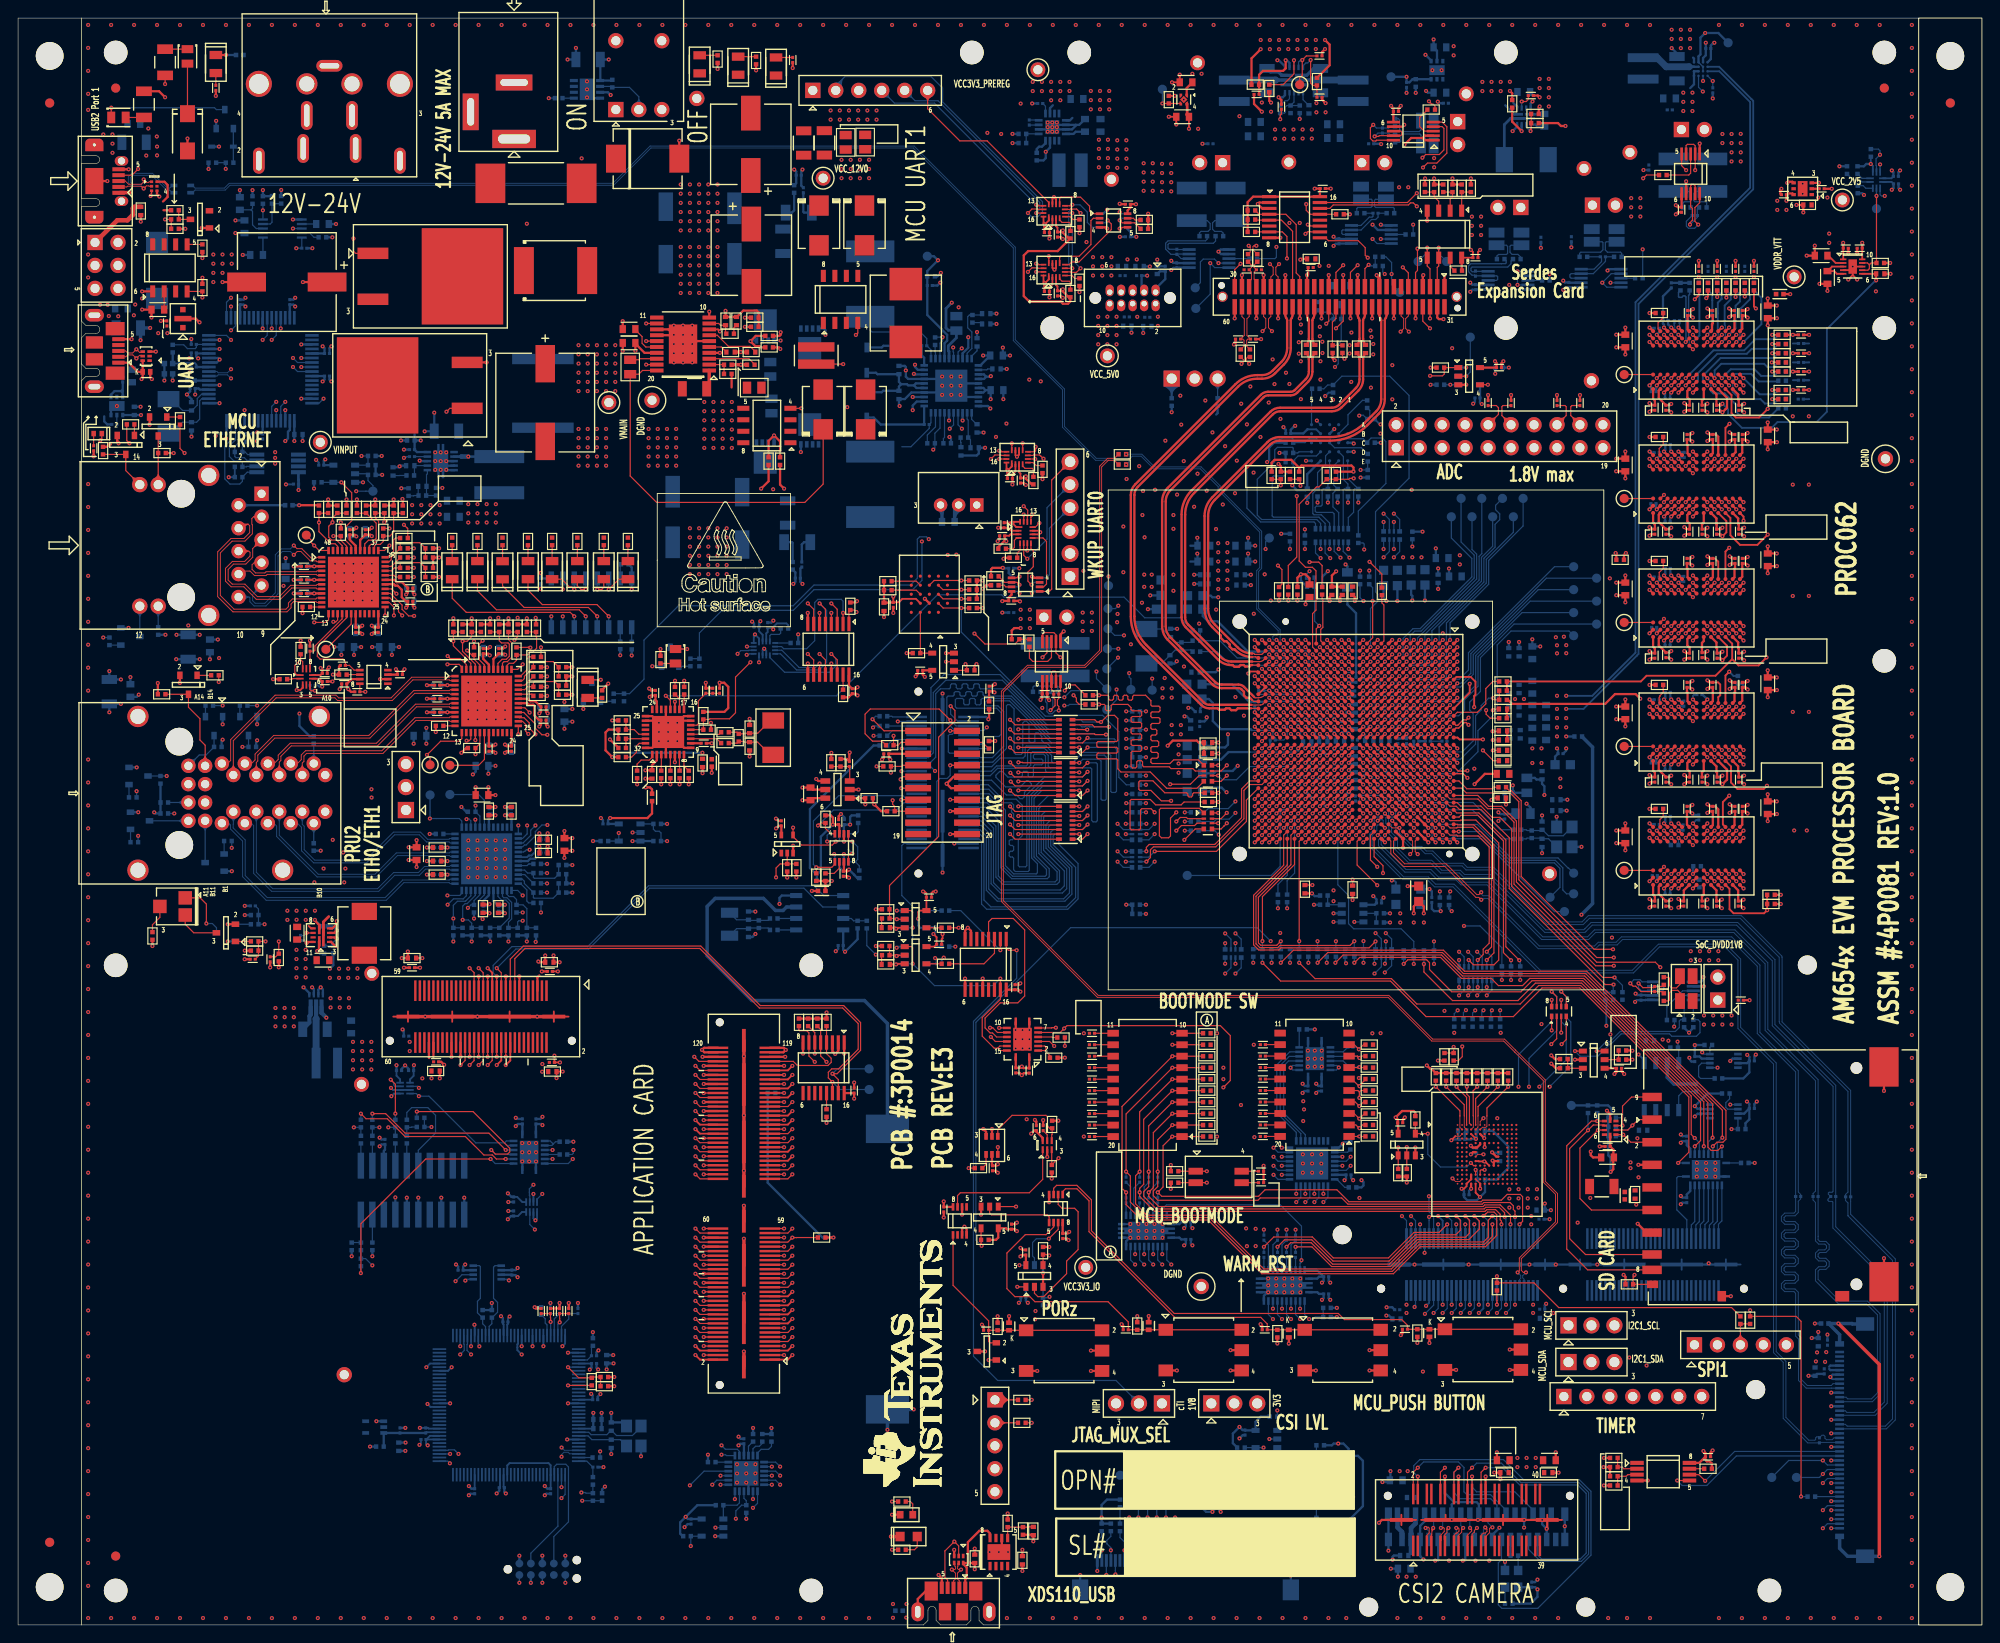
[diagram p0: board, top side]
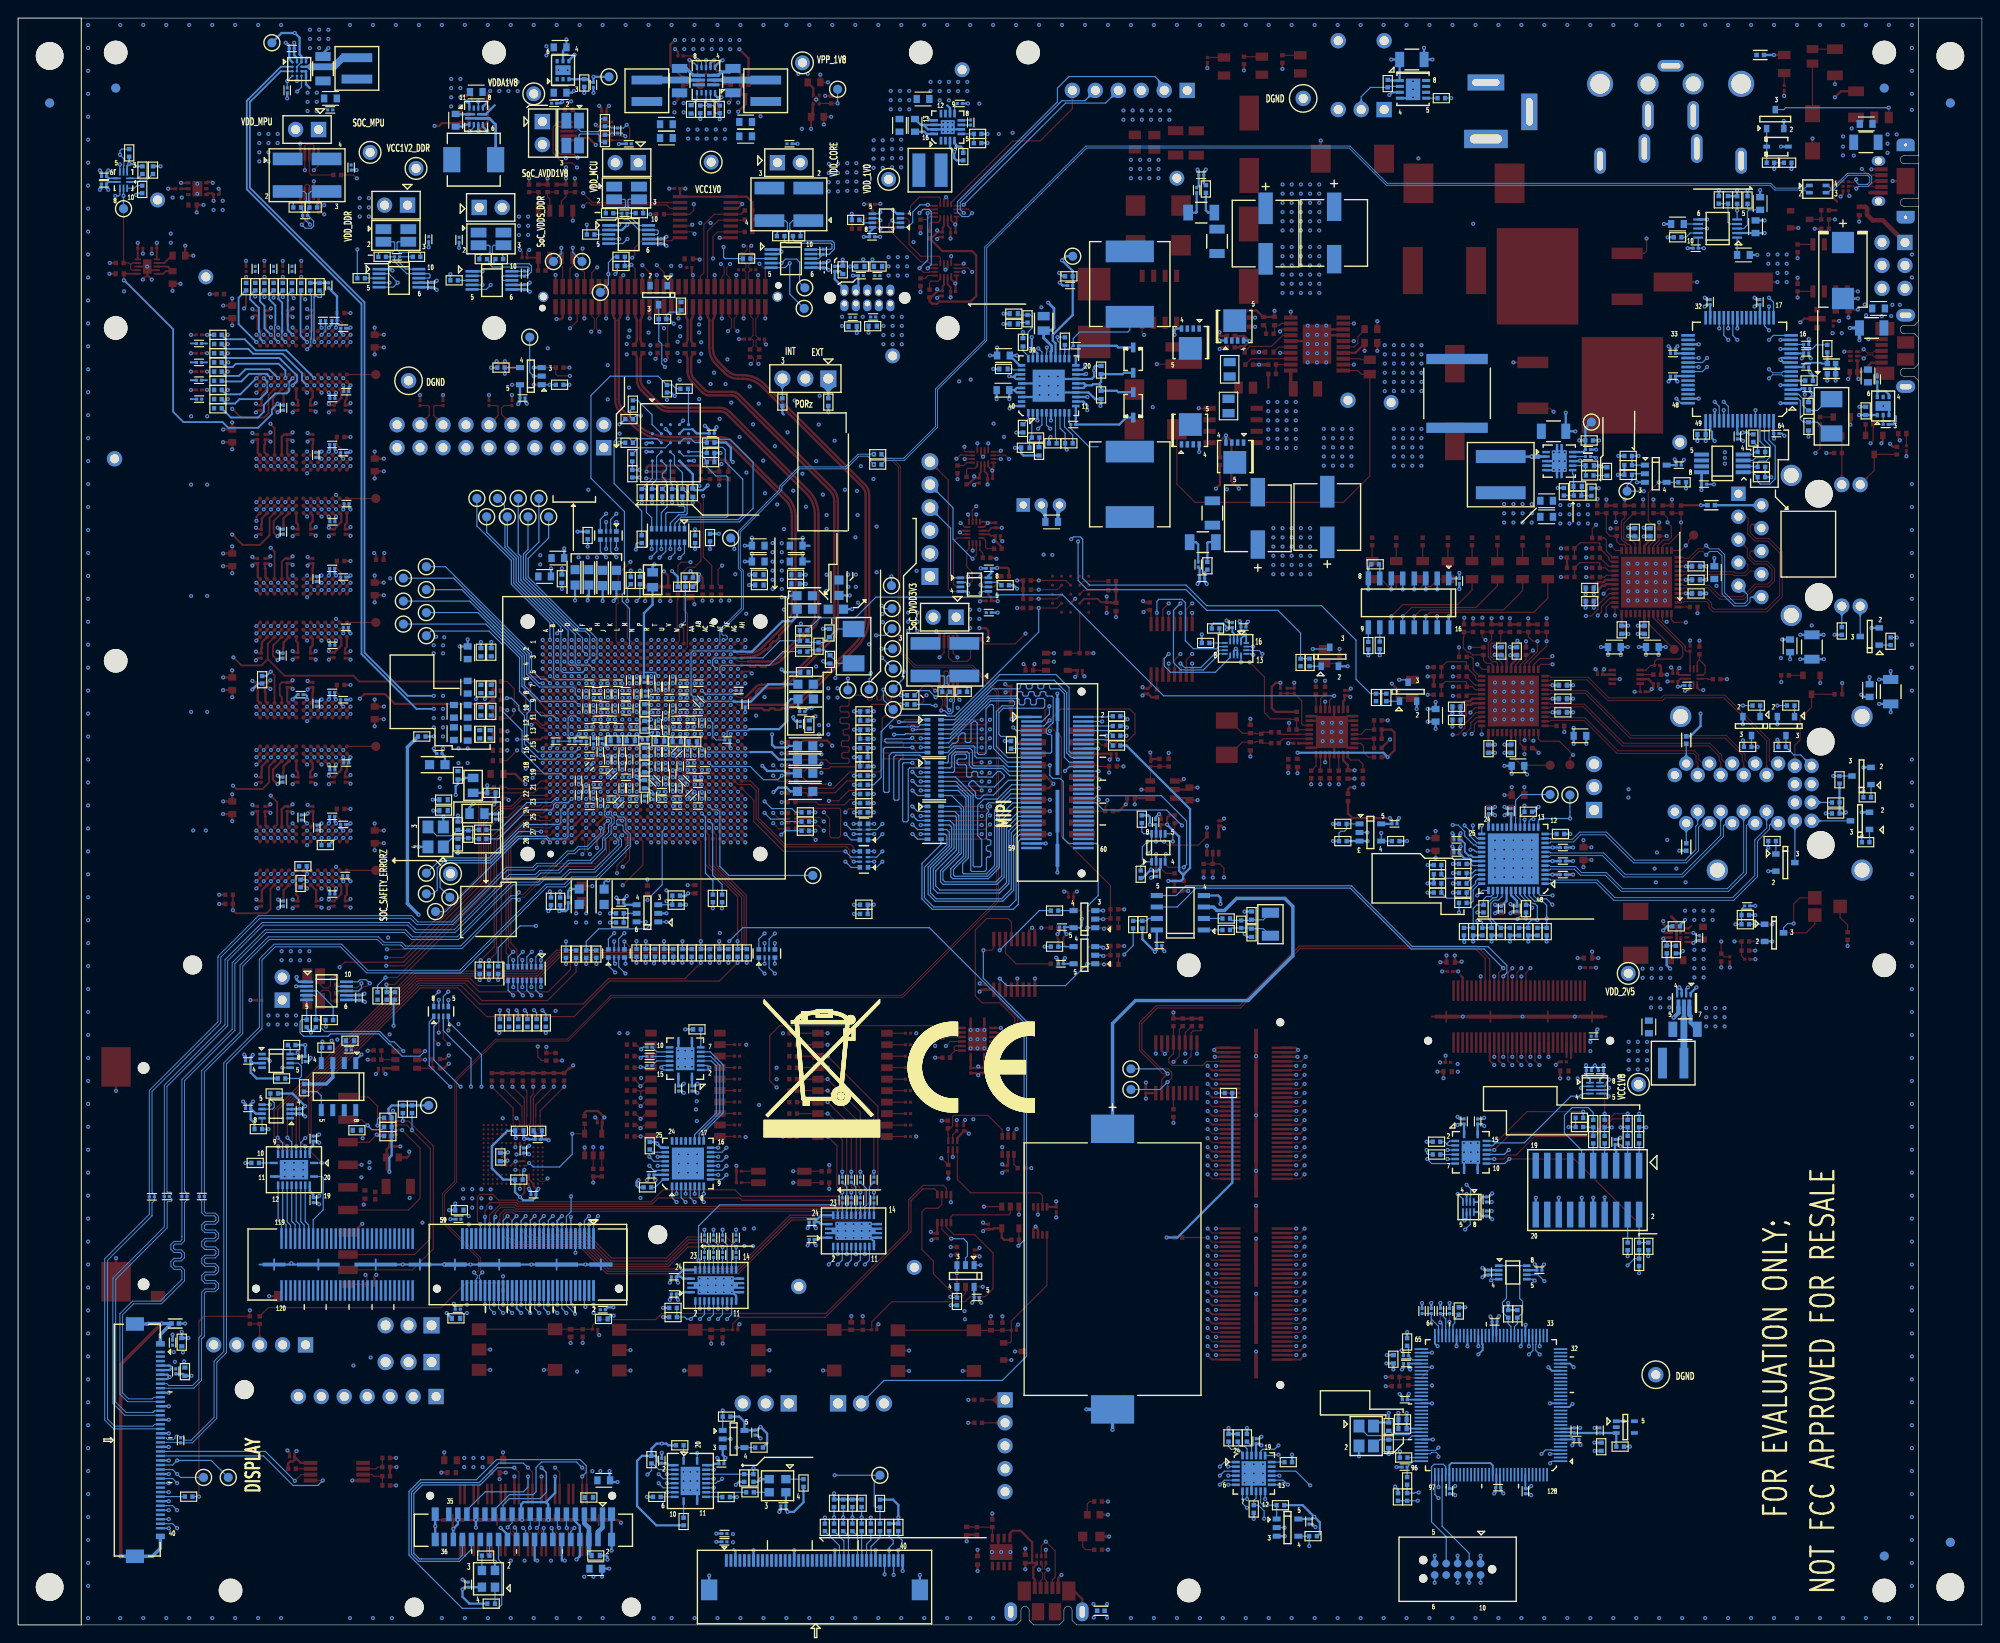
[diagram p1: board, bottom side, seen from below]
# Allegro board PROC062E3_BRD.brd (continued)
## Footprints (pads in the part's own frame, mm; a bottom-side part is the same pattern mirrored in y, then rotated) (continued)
XTAL4_NX3225GA_130X100_SMD_0-9
  rect 1.422x1.219 smd: 1(-1.1,-0.8) 2(1.1,-0.8) 3(1.1,0.8) 4(-1.1,0.8)
XTAL4_TXC_130X100_SMD_0-8
  rect 1.422x1.219 smd: 1(-1.1,-0.85) 2(1.1,-0.85) 3(1.1,0.85) 4(-1.1,0.85)
XTAL_ABM3_205X130_SMD
  rect 1.803x2.413 smd: 1(-1.9,0) 2(1.9,0)
XTAL_ABM3_210X130_SMD
  rect 1.803x2.413 smd: 1(-1.9,0) 2(1.9,0)
XTAL_ABS07_130X60_SMD_0-9
  rect 1.118x1.905 smd: 1(-1.27,0) 2(1.27,0)

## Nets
DGND: B1.2(-) C1.2 C2.2 C3.2 C5.2 C6.2 C7.2 C8.2 C9.2 C10.2 C11.1 C12.2 C13.2 C14.2 C15.2 C16.2 C17.2 C18.2 C19.2 C20.2 C21.2 C22.2 C23.2 C24.2 C25.2 C26.2 C29.2 C30.2 C31.2 C32.2 C33.2 C34.2 C35.2 C36.2 C37.2 C38.1 C39.2 C40.2 C41.2 C42.2 C43.2 C44.2 C45.2 C46.2 C47.2 C50.2 C51.2 C52.2 C53.2 C56.2 C57.2 C62.2 C63.2 C64.2 C65.2 C67.2 C68.2 C69.2 C70.2 C71.2 C72.2 C73.2 C74.2 C75.2 C76.2 C77.1 C78.2 C79.2 C80.2 C81.2 C82.2 C83.2 C85.2 C86.2 C87.2 C88.2 C89.2 C90.2 C91.2 C92.2 C94.2 C95.2 C96.2 C97.2 C98.2 C99.2 C100.2 C101.2 C102.2 C103.2 C104.2 C105.2 C106.2 C107.2 C108.2 C109.2 C110.2 C111.2 C112.2 C113.1 C114.2 C115.2 C116.2 C117.2 C119.2 C120.2 C121.2 C122.2 C123.2 C124.2 C125.2 C126.2 C127.2 C128.2 C129.2 C130.2 C131.2 C132.2 C133.2 C134.2 C135.2 C136.2 C137.2 C138.2 C139.2 C140.2 C141.2 C142.2 C143.2 C144.2 C145.2 C146.2 C147.2 C148.2 C149.2 C150.2 C151.2 C153.2 C154.2 C155.2 C156.1 C157.2 C158.2 C159.2 C160.2 C161.1 C162.2 C163.2 C164.2 C165.2 C166.2 C167.2 C168.2 C169.1 C170.1 C171.1 C172.2 C173.2 C174.2 C175.2 C176.2 C177.2 C178.2 C179.2 C180.2 C181.2 C182.2 C183.2 C184.2 C185.2 C186.2 C187.2 C188.2 C189.2 C190.2 C192.2 C193.2 C194.2 C195.2 C196.2 C197.2 C198.2 C199.2 C200.2 C201.2 C202.2 C203.2 C204.2 C205.2 C206.2 C207.2 C208.2 C209.2 C210.2 C211.2 C212.2 C213.2 C214.2 C215.2 C216.2 C217.2 C219.2 C220.2 C221.2 C222.2 C223.2 C224.1 C225.2 C226.2 C227.2 C228.2 C229.2 C230.2 C231.2 C232.2 C233.2 C234.2 C235.2 C236.2 C237.2 C238.2 C239.2 C240.2 C241.2 C242.2 C243.2 C244.2 C245.1 C246.1 C247.1 C248.1 C250.2 C251.2 C252.2 C253.2 C254.2 C255.2 C256.2 C257.2 C258.2 C259.2 C260.2 C261.2 C262.2 C263.2 C264.2 C265.2 C266.2 C267.2 C268.2 C270.2 C271.2 C272.2 C274.2 C275.2 C276.2 C277.2 C278.2 C281.2 C282.2 C283.2 C284.2 C285.2 C287.2 C288.2 C289.2 C290.2 C291.2 C294.2 C295.2 C296.2 C297.2 C298.2 C299.2 C300.2 C301.2 C302.2 C304.2 C305.1 C306.1 C307.2 C308.2 C309.2 C310.2 C311.2 C312.2 C313.2 C314.2 C315.2 C316.2 C317.2 C318.2 C319.1 C321.1 C322.1 C323.2 C324.1 C325.1 C326.1 C327.1 C328.2 C329.1 C330.2 C331.1 C332.2 C333.2 C334.2 C335.2 C336.2 C337.2 C338.2 C339.2 C340.2 C341.2 C342.2 C344.2 C345.2 C346.2 C347.1 C348.1 C349.1 C350.2 C351.2 C352.2 C353.2 C354.2 C355.2 C357.2 C358.2 C359.1 C360.1 C362.2 C363.2 C364.2 C365.2 C366.2 C367.2 C368.2 C369.2 C370.2 C371.2 C372.2 C373.2 C374.2 C375.2 C376.2 C377.2 C378.2 C379.2 C380.2 C381.2 C382.2 C383.2 C384.2 C385.2 C386.2 C387.2 C388.2 C389.2 C390.2 C391.2 C392.2 C393.2 C394.2 C395.2 C396.2 C397.2 C398.2 C399.2 C400.2 C401.2 C402.2 C403.2 C404.2 C405.2 C406.2 C407.2 C408.2 C409.2 C410.2 C411.2 C412.2 C413.1 C414.2 C415.2 C416.2 C417.2 C418.2 C419.2 C420.2 C421.2 C422.2 C423.2 C424.2 C425.2 C426.2 C427.2 C428.2 C429.2 C430.2 C431.2 C432.2 C433.2 C434.2 C435.2 C436.2 C437.2 C438.2 C439.2 C441.2 C442.2 C443.2 C444.2 C445.2 C446.2 C447.2 C448.2 C449.2 C450.2 C451.2 C452.2 C453.2 C454.2 C455.2 C456.2 C457.2 C458.2 C459.2 C460.2 C461.2 C462.2 C463.2 C464.2 C465.2 C466.2 C467.2 C468.2 C469.2 C470.2 C471.2 C472.2 C473.2 C474.2 C475.2 C476.2 C477.2 C478.2 C479.2 C480.2 C481.1 C482.2 C483.2 C484.2 C485.2 C486.2 C487.2 C488.2 C489.2 C490.2 C491.2 C492.2 C493.2 C494.2 C495.2 C496.2 C497.2 C498.2 C499.2 C500.2 C501.2 C502.2 C503.2 C504.2 C505.2 C506.2 C507.2 C508.2 C509.2 C510.2 C511.2 C512.2 C513.2 C514.2 C515.2 C516.2 C517.2 C518.2 C519.2 C520.2 C521.2 C522.2 C523.2 C524.2 C525.2 C526.2 C527.2 C528.2 C529.2 C530.2 C531.2 C532.2 C533.2 C534.2 C535.2 C536.2 C537.2 C538.2 C539.2 C540.2 C541.2 C542.2 C543.2 C544.2 C545.2 C546.2 C547.2 C548.2 C549.2 C550.2 C551.2 C552.2 C553.2 C554.2 C555.2 C556.2 C557.2 C558.2 C559.2 C560.2 C561.2 C562.2 C563.2 C564.1 C565.2 C566.2 C567.2 C568.2 C569.2 C570.1 C571.2 C572.2 C573.2 C574.2 C575.2 C576.1 C577.2 C578.2 C579.2 C580.2 C581.2 C582.2 C583.2 C584.2 C585.2 C586.2 C587.2 C588.2 C589.2 C590.2 C591.2 C592.2 C593.2 C594.2 C595.2 C596.1 C597.2 C598.2 C599.2 C600.2 C601.2 C602.2 C603.2 C604.2 C605.2 C606.2 C607.2 C608.2 C609.2 C610.2 C611.2 C612.2 C613.2 C614.2 C615.2 C616.2 C617.2 C618.2 C619.2 C620.2 C621.2 C622.2 C623.2 C624.1 C625.2 C626.2 C627.2 C628.2 C629.2 C630.2 C631.2 C632.2 C633.2 C634.2 C635.2 C636.2 C637.1 C638.2 C639.2 C640.2 C641.2 C642.2 C643.2 C644.2 C645.2 C646.2 C647.2 C648.2 C649.2 C650.2 C651.2 C652.1 C653.2 C654.2 C655.2 C656.2 C657.2 C658.2 C659.1 C660.2 C661.2 C662.2 C663.2 C664.2 C665.2 C666.1 C667.2 C668.2 C669.2 C670.1 C671.2 C672.2 C673.2 C674.2 C675.1 C676.1 C677.2 C679.2 C680.2 C681.2 C682.2 C685.2 C686.2 C687.1 C688.1 C689.1 C690.1 C691.2 C692.2 C693.2 C695.2 C696.2 D1.2(A) D2.2(ANODE) D4.1(A) D7.2(A) D10.2(A) D11.2(A) D12.2(A) D13.2(A) D14.2(ANODE) D16.1(A) FL2.2(GND) FL6.2 FL7.2 FL15.1 J1.2 J1.3 J2.3 J2.4 J2.5 J2.6 J2.7 J3.5(GND) J4.6 J5.1 J5.4 J5.7 J5.8 J5.9 J5.10 J5.13 J5.17 J5.20 J5.23 J5.26 J5.29 J5.32 J5.35 J5.38 J5.41 J5.44 J5.48 J5.51 J5.54 J5.57 J5.60 J5.SH1 J5.SH2 J6.4 J6.5 J6.6 J9.3 J10.1 J10.7 J10.8 J10.13 J10.14 J10.19 J10.20 J11.1 J12.1(CH-GND) J13.10 J13.12 J13.16 J13.20 J14.A10(GND) J14.B10(GND) J16.13 J16.18 J16.19 J16.22 J16.25 J16.40 J16.44 J16.61 J16.62 J16.63 J16.64 J17.3(VSS1) J17.6(VSS2) J17.G2 J17.G4 J17.G5 J18.1 J18.2 J18.5 J18.6 J18.17 J18.21 J18.25 J18.29 J18.36 J18.40 J18.52 J18.56 J18.69 J18.73 J18.82 J18.85 J18.86 J18.89 J18.92 J18.96 J18.97 J18.101 J18.104 J18.105 J18.107 J18.108 J18.109 J18.111 J18.112 J18.115 J18.116 J18.117 J18.118 J18.119 J18.120 J18.121 J18.122 J18.123 J18.124 J18.125 J18.126 J18.127 J18.128 J19.7 J20.5 J21.3 J22.12 J22.16 J22.24 J22.41(GND1) J22.42(GND2) J22.43(GND3) J22.44(GND4) J23.5(GND) J30.1 J32.16 J32.57 J32.61 J32.62 J32.63 J32.64 J33.1 J34.8 J34.10 J34.12 J34.16 J34.20 J35.12 J35.17 J35.22 J35.30 J35.35 J35.36 J35.121 J35.122 J35.123 J35.124 J35.125 J35.126 J35.127 J35.128 J36.12 J36.17 J36.22 J36.30 J36.35 J36.36 J36.61 J36.62 J36.63 J36.64 J38.6 J38.7 J38.10 J38.13 J38.16 J38.19 J38.22 J38.25 J38.28 J38.34 J39.6 J39.7 J39.10 J39.13 J39.16 J39.19 J39.22 J39.29 J39.33 J39.34 J39.SH1 J39.SH2 J39.SH3 J39.SH4 J40.3 J40.5 J40.9 J41.7 J41.16 J41.25 J41.34 J41.40 J41.41 J41.42 J42.5(GND) J43.3 LD2.1 LD3.1 LD4.1 LD5.1 LD19.1(CATHODE) LD20.1(CATHODE) Q3.2(S) Q4.2(S) Q5.2(S) Q6.2(S) Q7.3(D) Q8.2(S) Q9.2(S) Q10.2(S) Q11.2(S) Q12.2(S) Q13.2(S) Q14.2(S) Q15.2(S) Q16.2(S) Q17.2(S) R6.1 R10.2 R11.2 R15.2 R17.1 R19.2 R22.1 R23.1 R30.2 R31.1 R32.2 R34.2 R39.2 R40.2 R41.2 R42.1 R50.2 R52.2 R53.2 R59.2 R60.2 R62.2 R64.2 R65.2 R71.1 R75.2 R80.1 R82.1 R83.2 R87.1 R91.2 R92.2 R95.2 R96.2 R99.2 R112.2 R116.1 R117.2 R122.2 R125.2 R130.2 R135.2 R136.2 R138.2 R139.2 R142.2 R143.2 R146.2 R150.1 R158.2 R164.1 R166.2 R172.2 R176.2 R179.2 R186.2 R187.1 R188.2 R190.2 R195.1 R197.1 R201.2 R212.2 R216.2 R219.1 R228.2 R230.2 R240.2 R243.2 R245.2 R247.2 R249.2 R251.2 R252.1 R254.1 R255.1 R258.2 R260.2 R272.2 R274.2 R276.2 R278.2 R280.2 R282.2 R285.2 R287.2 R291.2 R293.2 R295.2 R297.2 R300.2 R301.2 R305.2 R312.1 R315.1 R324.2 R327.1 R331.1 R333.2 R340.2 R343.2 R350.2 R353.2 R356.2 R388.1 R394.1 R398.2 R409.1 R417.2 R418.2 R428.2 R431.1 R440.2 R442.1 R452.1 R453.1 R454.1 R456.2 R462.1 R471.2 R473.2 R478.1 R483.2 R484.2 R497.2 R509.2 R513.1 R514.2 R518.2 R524.2 R526.1 R535.2 R536.2 R544.1 R546.2 R553.2 R556.2 R557.2 R560.2 R561.2 R567.2 R596.1 R621.1 R622.1 R639.1 R641.2 R648.1 R650.1 R652.1 R653.2 R659.1 R660.1 R669.1 R673.2 R676.1 R677.2 R679.1 R680.2 R707.2 R730.2 R731.2 R737.1 R738.1 R739.2 R740.2 SW1.1 SW1.SH1 SW1.SH2 SW5.3 SW5.4 SW5.5(GND) SW6.3 SW6.4 SW6.5(GND) SW7.3 SW7.4 SW7.5(GND) SW8.3 SW8.4 SW8.5(GND) TP2.1(TP) TP4.1(TP) TP6.1(TP) TP21.1(TP) TP87.1(TP) TP88.1(TP) U1.2(GND) U1.5(EP) U2.7(GND) U3.1(A1) U3.7(GND) U4.4(GND) U5.3(GND) U5.7(EP) U6.1(1\O\E\) U6.10(GND1) U6.11(GND2) U6.16(2\O\E\) U7.2(A1) U7.3(A2) U7.8(GND) U8.4(GND) U9.4(VSS) U10.4(PGND) U10.8(GND) U10.11(EP) U11.1(GND) U12.1(1\O\E\) U12.10(GND1) U12.11(GND2) U12.16(2\O\E\) U13.1(S1) U13.2(S2) U13.3(S3) U14.6(AGND) U14.13(CSG) U14.14(PGND) U14.21(EP) U15.3(GND) U16.A2(VSSQ#A2) U16.A8(VSSQ#A8) U16.A9(VSS#A9) U16.C8(VSS#C8) U16.D1(VSSQ#D1) U16.D9(VSSQ#D9) U16.E1(VSS#E1) U16.E9(VSS#E9) U16.G1(VSS#G1) U16.H9(VSS#H9) U16.K1(VSS#K1) U16.K9(VSS#K9) U16.N1(VSS#N1) U17.3(GND) U19.1(1\O\E\) U19.10(GND1) U19.11(GND2) U19.16(2\O\E\) U20.A2(VSSQ#A2) U20.A8(VSSQ#A8) U20.A9(VSS#A9) U20.C8(VSS#C8) U20.D1(VSSQ#D1) U20.D9(VSSQ#D9) U20.E1(VSS#E1) U20.E9(VSS#E9) U20.G1(VSS#G1) U20.H9(VSS#H9) U20.K1(VSS#K1) U20.K9(VSS#K9) U20.N1(VSS#N1) U21.1(1\O\E\) U21.10(GND1) U21.11(GND2) U21.16(2\O\E\) U22.49(GND) U23.4(GND) U24.B3(VSS) U25.A2(VSSQ#A2) U25.A8(VSSQ#A8) U25.A9(VSS#A9) U25.C8(VSS#C8) U25.D1(VSSQ#D1) U25.D9(VSSQ#D9) U25.E1(VSS#E1) U25.E9(VSS#E9) U25.G1(VSS#G1) U25.H9(VSS#H9) U25.K1(VSS#K1) U25.K9(VSS#K9) U25.N1(VSS#N1) U26.8(GND) U27.1(A1) U27.7(GND) U28.3(GND) U29.3(GND) U30.2(GND) U31.49(GND) U32.4(GND#4) U32.9(GND#9) U32.15(GND#15) U32.16(GND#16) U32.21(GND#21) U32.25(GND#25) U32.26(GND#26) U32.32(GND#32) U32.33(EP) U33.A2(VSSQ#A2) U33.A8(VSSQ#A8) U33.A9(VSS#A9) U33.C8(VSS#C8) U33.D1(VSSQ#D1) U33.D9(VSSQ#D9) U33.E1(VSS#E1) U33.E9(VSS#E9) U33.G1(VSS#G1) U33.H9(VSS#H9) U33.K1(VSS#K1) U33.K9(VSS#K9) U33.N1(VSS#N1) U34.A1(VSS#A1) U34.A2(VSS#A2) U34.A28(VSS#A28) U34.AA7(VSS#AA7) U34.AA11(VSS#AA11) U34.AA13(VSS#AA13) U34.AA15(VSS#AA15) U34.AA17(VSS#AA17) U34.AA19(VSS#AA19) U34.AA23(VSS#AA23) U34.AA26(VSS#AA26) U34.AB10(VSS#AB10) U34.AB12(VSS#AB12) U34.AB14(VSS#AB14) U34.AB16(VSS#AB16) U34.AB18(VSS#AB18) U34.AB20(VSS#AB20) U34.AB22(VSS#AB22) U34.AD4(VSS#AD4) U34.AE5(VSS#AE5) U34.AE10(VSS#AE10) U34.AE25(VSS#AE25) U34.AF2(VSS#AF2) U34.AF8(VSS#AF8) U34.AF15(VSS#AF15) U34.AF20(VSS#AF20) U34.AG1(VSS#AG1) U34.AG4(VSS#AG4) U34.AG7(VSS#AG7) U34.AG10(VSS#AG10) U34.AG28(VSS#AG28) U34.AH1(VSS#AH1) U34.AH2(VSS#AH2) U34.AH5(VSS#AH5) U34.AH8(VSS#AH8) U34.AH11(VSS#AH11) U34.AH27(VSS#AH27) U34.AH28(VSS#AH28) U34.B6(VSS#B6) U34.B9(VSS#B9) U34.B12(VSS#B12) U34.B15(VSS#B15) U34.B20(VSS#B20) U34.D22(VSS#D22) U34.E4(VSS#E4) U34.E26(VSS#E26) U34.E28(VSS#E28) U34.F3(VSS#F3) U34.F14(VSS#F14) U34.F19(VSS#F19) U34.F22(VSS#F22) U34.F25(VSS#F25) U34.F27(VSS#F27) U34.G2(VSS#G2) U34.G7(VSS#G7) U34.G9(VSS#G9) U34.G11(VSS#G11) U34.G13(VSS#G13) U34.G16(VSS#G16) U34.G21(VSS#G21) U34.G23(VSS#G23) U34.H1(VSS#H1) U34.H6(VSS#H6) U34.H8(VSS#H8) U34.H10(VSS#H10) U34.H12(VSS#H12) U34.H14(VSS#H14) U34.H20(VSS#H20) U34.H22(VSS#H22) U34.H24(VSS#H24) U34.H26(VSS#H26) U34.H28(VSS#H28) U34.J7(VSS#J7) U34.J9(VSS#J9) U34.J11(VSS#J11) U34.J13(VSS#J13) U34.J15(VSS#J15) U34.J18(VSS#J18) U34.J21(VSS#J21) U34.J23(VSS#J23) U34.J25(VSS#J25) U34.J27(VSS#J27) U34.K1(VSS#K1) U34.K6(VSS#K6) U34.K8(VSS#K8) U34.K10(VSS#K10) U34.K12(VSS#K12) U34.K14(VSS#K14) U34.K17(VSS#K17) U34.K19(VSS#K19) U34.K22(VSS#K22) U34.K23(VSS#K23) U34.L3(VSS#L3) U34.L7(VSS#L7) U34.L9(VSS#L9) U34.L11(VSS#L11) U34.L13(VSS#L13) U34.L16(VSS#L16) U34.L23(VSS#L23) U34.L24(VSS#L24) U34.L26(VSS#L26) U34.L28(VSS#L28) U34.M8(VSS#M8) U34.M10(VSS#M10) U34.M15(VSS#M15) U34.M17(VSS#M17) U34.M20(VSS#M20) U34.N7(VSS#N7) U34.N9(VSS#N9) U34.N11(VSS#N11) U34.N13(VSS#N13) U34.N16(VSS#N16) U34.N19(VSS#N19) U34.N21(VSS#N21) U34.P6(VSS#P6) U34.P8(VSS#P8) U34.P10(VSS#P10) U34.P12(VSS#P12) U34.P14(VSS#P14) U34.P16(VSS#P16) U34.P18(VSS#P18) U34.P22(VSS#P22) U34.R7(VSS#R7) U34.R9(VSS#R9) U34.R11(VSS#R11) U34.R13(VSS#R13) U34.R15(VSS#R15) U34.R17(VSS#R17) U34.R19(VSS#R19) U34.R21(VSS#R21) U34.T8(VSS#T8) U34.T10(VSS#T10) U34.T12(VSS#T12) U34.T14(VSS#T14) U34.T16(VSS#T16) U34.T18(VSS#T18) U34.T22(VSS#T22) U34.T26(VSS#T26) U34.U3(VSS#U3) U34.U7(VSS#U7) U34.U9(VSS#U9) U34.U11(VSS#U11) U34.U13(VSS#U13) U34.U15(VSS#U15) U34.U17(VSS#U17) U34.U19(VSS#U19) U34.U21(VSS#U21) U34.V6(VSS#V6) U34.V10(VSS#V10) U34.V12(VSS#V12) U34.V14(VSS#V14) U34.V18(VSS#V18) U34.V20(VSS#V20) U34.V22(VSS#V22) U34.W7(VSS#W7) U34.W9(VSS#W9) U34.W11(VSS#W11) U34.W13(VSS#W13) U34.W15(VSS#W15) U34.W17(VSS#W17) U34.W19(VSS#W19) U34.W21(VSS#W21) U34.W23(VSS#W23) U34.Y6(VSS#Y6) U34.Y8(VSS#Y8) U34.Y12(VSS#Y12) U34.Y14(VSS#Y14) U34.Y16(VSS#Y16) U34.Y18(VSS#Y18) U34.Y22(VSS#Y22) U35.2(GND#2) U35.4(GND#4) U35.6(GND#6) U36.3(GND) U37.2(GND) U38.A2(VSSQ#A2) U38.A8(VSSQ#A8) U38.A9(VSS#A9) U38.C8(VSS#C8) U38.D1(VSSQ#D1) U38.D9(VSSQ#D9) U38.E1(VSS#E1) U38.E9(VSS#E9) U38.G1(VSS#G1) U38.H9(VSS#H9) U38.K1(VSS#K1) U38.K9(VSS#K9) U38.N1(VSS#N1) U39.3(GND) U40.1(PGND) U40.11(AGND) U41.3(GND) U42.7(2A) U42.8(GND) U42.9(3A) U42.12(4A) U43.8(GND1) U43.9(GND2) U43.17(PAD) U44.2(GND) U45.2(GND) U46.1(A0) U46.2(A1) U46.3(A2) U46.8(GND) U47.5(GND) U48.3(GND) U49.2(GND) U50.2(GND) U51.A6(VSS#A6) U51.C4(VSSQ#C4) U51.E7(VSS#E7) U51.G5(VSS#G5) U51.H10(VSS#H10) U51.J5(VSS#J5) U51.K8(VSS#K8) U51.N2(VSSQ#N2) U51.N5(VSSQ#N5) U51.P4(VSSQ#P4) U51.P6(VSSQ#P6) U52.4(GND) U53.3(GND) U54.3(2A) U54.4(GND) U54.6(3A) U55.3(GND) U56.4(GND) U57.6(GND) U57.9(PAD) U58.3(GND) U59.A2(AGND) U59.C1(SENSE-) U59.C3(PGND1) U59.C4(PGND2) U59.D4(PGND3) U60.5(GND) U60.7(EP) U61.1(PGND1) U61.11(PGND2) U61.13(AGND) U62.4(GND) U62.9(EP) U63.1(PGND) U63.11(AGND) U64.6(AGND) U64.14(PGND#14) U64.15(PGND#15) U64.17(EP) U65.4(GND) U66.6(GND) U67.1(A1) U67.7(GND) U68.1(A1) U68.2(A0) U68.7(GND) U69.7(GND) U70.7(GND) U71.1(S1) U71.2(S2) U71.3(S3) U73.1(GND1) U73.5(GND2) U73.10(AGND) U73.11(GND3) U73.13(TEST) U73.15(GND4) U73.25(GND5) U73.35(GND6) U73.47(GND7) U73.51(GND8) U74.3(GND) U75.14(PGND2) U75.17(PGND1) U75.35(AGND) U75.38(SYNIN) U75.41(EP) U76.3(GND) U76.7(EP) U77.B3(VSS#B3) U77.C1(VSS#C1) U77.E5(VSS#E5) U79.5(VSS) U80.3(GND#3) U80.4(GND#4) U80.5(GND#5) U80.11(EP) U81.1(S1) U81.2(S2) U81.3(S3) U82.3(GND) U83.4(GND) U84.8(G\) U84.16(GND) U85.1(1\O\E\) U85.10(GND1) U85.11(GND2) U85.16(2\O\E\) U86.3(GND) U87.2(GND) U88.49(GND) U89.2(GND) U90.3(GND) U91.4(VSS) U92.3(GND) U93.2(A0) U93.7(GND) U94.5(GND) U95.8(GND1) U95.9(GND2) U95.17(PAD) U96.2(GND) U97.3(A2) U97.5(GND) U97.6(B2) U98.8(GND1) U98.9(GND2) U98.17(PAD) U99.25(GND) U99.33(EP) U100.11(GND) U100.21(PAD) U101.3(A2) U101.5(GND) U101.6(B2) U102.11(GND1) U102.12(GND2) U102.13(GND3) U102.25(EP) U103.2(GND) U104.3(GND) U105.11(GND1) U105.12(GND2) U105.13(GND3) U105.25(EP) U106.10(GNDA) U106.17(GND#17) U106.48(GND#48) U106.55(GND#55) U106.58(GND#58) U106.64(W\A\K\E\) U106.66(XOSC0) U106.80(GND#80) U106.114(GND#114) U107.1(ANODE) U108.3(GND) U109.3(GND) U110.9(GND) U110.25(PAD) U111.11(GND) U111.21(PAD) U112.2(GND) U113.3(GND) U114.2(GND) U115.1(GND) Y4.2 Y4.4 Y6.2 Y6.4
GNDUSB: C77.2 J42.SH1 J42.SH2 J42.SH3 J42.SH4 J42.SH5 J42.SH6 R71.2
VCC1V0: C4.1 C268.1 C270.1 C274.1 C275.1 C276.1 C277.1 J26.1 J27.1 L4.2 L5.2 R349.4 R355.3 TP25.1(TP) U61.16(VO)
VCC1V2_DDR: C267.1 C287.1 C288.1 J28.1 J29.1 L6.2 R16.1 R360.4 R361.1 TP26.1(TP) U63.3(VOS)
VCC1V2_PG: R12.1 U63.5(PG)
VCC1V8: C16.1 C21.1 C41.1 C102.1 C120.1 C123.1 C126.1 C134.1 C135.1 C155.1 C162.1 C178.1 C186.1 C192.1 C209.1 C213.1 C216.1 C219.1 C220.1 C230.1 C237.1 C246.2 C248.2 C285.1 C295.1 C300.1 C334.1 C346.1 C358.1 C362.1 C371.1 C394.1 C396.1 C400.1 C404.1 C406.1 C477.1 C513.1 C529.1 C578.1 C582.1 C586.1 C598.1 C605.1 C608.1 C617.1 C619.1 C625.1 C637.2 C639.1 C641.1 C662.1 C675.2 C676.2 C677.1 FL4.1 FL5.1 FL11.1 FL12.1 FL14.1 J6.3 J15.1 J16.55 J16.57 J16.59 J22.38 J22.40 J35.2 J35.4 J36.2 J36.4 J37.1 J39.4 J39.5 L11.2 R27.2 R33.2 R35.2 R51.2 R90.1 R93.1 R94.1 R97.1 R98.2 R100.2 R115.1 R119.1 R137.1 R140.1 R141.1 R144.1 R145.2 R149.1 R151.2 R156.1 R160.1 R163.1 R167.1 R198.2 R234.2 R246.2 R262.1 R263.1 R264.1 R265.1 R266.1 R267.1 R268.1 R269.1 R288.2 R307.2 R308.2 R385.2 R402.2 R403.2 R406.2 R411.2 R420.2 R421.2 R422.2 R423.2 R424.2 R447.2 R498.2 R520.1 R522.1 R542.2 R554.2 R555.1 R558.1 R559.1 R562.1 R604.2 R605.2 R624.2 R625.1 R647.2 R700.1 R732.2 R741.1 TP19.1(TP) U6.3(VCCA) U8.8(VCC) U12.3(VCCA) U22.19(VDDIO#19) U22.30(VDDIO#30) U22.41(VDDIO#41) U29.7(VCCA) U30.3(VCCA) U31.19(VDDIO#19) U31.30(VDDIO#30) U31.41(VDDIO#41) U45.3(VCCA) U48.5(VCC) U51.C6(VCCQ#C6) U51.M4(VCCQ#M4) U51.N4(VCCQ#N4) U51.P3(VCCQ#P3) U51.P5(VCCQ#P5) U53.5(VCC) U65.8(VCC) U74.5(VCC) U77.B4(VCC#B4) U77.D1(VCC#D1) U77.E4(VCC#E4) U82.5(VCC) U85.3(VCCA) U86.5(VCC) U88.19(VDDIO#19) U88.30(VDDIO#30) U88.41(VDDIO#41) U94.3(FB) U94.4(VOS) U96.3(VCCA) U100.2(VCCA) U104.5(VCC) U109.6(VCCB) U114.4(VCC)
VCC1V8_CLKBUFF: C147.1 C171.2 FL4.2 U32.2(VDDO#2) U32.6(VDDO#6) U32.19(VDDO#19) U32.23(VDDO#23)
VCC1V8_MIPI: C188.1 FL5.2 R214.1 R217.1 R218.2 R479.1 U37.3(VCCA)
VCC2V5_PG: R549.1 U40.5(PG)
VCC3V3_IO: C6.1 C13.1 C18.1 C20.1 C26.1 C29.1 C92.1 C103.1 C119.1 C121.1 C122.1 C133.1 C136.1 C138.1 C144.1 C146.1 C148.1 C166.1 C189.1 C198.1 C217.1 C221.1 C222.1 C224.2 C225.1 C226.1 C227.1 C229.1 C234.1 C236.1 C238.1 C239.1 C244.1 C245.2 C247.2 C289.1 C294.1 C302.1 C304.1 C363.1 C366.1 C379.1 C389.1 C395.1 C581.1 C591.1 C596.2 C603.1 C604.1 C610.1 C613.1 C614.1 C615.1 C622.1 C623.1 C624.2 C626.1 C627.1 C629.1 C631.1 C632.1 C634.1 C635.1 C636.1 C638.1 C640.1 C648.1 C649.1 C656.1 C658.1 C661.1 C664.1 C666.2 C670.2 C671.1 C672.1 C673.1 C674.1 C685.1 C686.1 C687.2 C688.2 C689.2 C690.2 C693.1 C696.1 FL3.1 J5.18 J5.19 J13.5 J16.1 J16.3 J16.5 J22.30 J22.32 J22.34 J22.36 J31.1 J35.56 J35.58 J35.60 J36.56 J36.58 J36.60 J37.3 J38.4 J38.5 J39.1 J39.2 J39.3 J41.1 J41.2 J41.3 J43.1 L9.2 R20.2 R21.1 R24.1 R26.2 R29.2 R36.2 R37.1 R38.1 R58.2 R66.2 R78.2 R79.2 R81.2 R84.1 R88.2 R89.2 R103.1 R104.1 R105.1 R106.1 R107.1 R108.1 R109.1 R110.1 R113.2 R120.1 R123.2 R124.2 R126.2 R127.2 R133.2 R134.1 R147.2 R153.2 R155.2 R159.2 R174.1 R175.1 R177.2 R178.2 R184.2 R210.1 R213.1 R215.2 R221.2 R224.2 R227.2 R231.1 R232.1 R235.2 R236.2 R237.2 R238.2 R239.1 R242.1 R244.1 R248.1 R250.1 R256.1 R257.1 R259.1 R261.1 R270.2 R271.1 R273.1 R275.1 R277.1 R279.1 R281.1 R283.2 R284.1 R286.1 R289.1 R290.1 R292.1 R294.1 R296.1 R302.1 R303.2 R304.2 R306.1 R309.2 R318.2 R319.2 R320.2 R321.2 R328.1 R329.1 R330.1 R336.2 R390.2 R401.1 R412.2 R415.2 R419.1 R427.2 R441.2 R449.1 R459.2 R481.2 R482.2 R490.2 R496.1 R501.1 R504.1 R506.2 R521.1 R538.1 R539.1 R540.1 R545.1 R547.1 R552.2 R581.1 R582.1 R583.1 R584.1 R585.1 R586.1 R592.1 R593.1 R630.2 R656.2 R658.2 R661.2 R664.2 R667.2 R668.2 R671.1 R672.2 R681.2 R682.2 R683.2 R684.2 R685.2 R686.2 R687.1 R696.1 R697.1 R698.2 R735.1 R736.1 TP20.1(TP) U2.1(A1) U2.2(A0) U2.6(VS+) U3.6(VS+) U6.2(VCCB) U7.1(A0) U7.16(VCC) U9.8(VCC) U17.5(VCC) U19.3(VCCA) U21.3(VCCA) U23.8(VCC) U24.B4(VCC) U26.16(VCC) U27.6(VS+) U28.5(VCC) U29.6(VCCB) U30.7(VCCB) U36.5(VCC) U37.7(VCCB) U39.5(VCC) U41.5(VCC) U42.16(VCC) U43.1(VCCA) U43.16(VCCB) U44.4(V+) U45.7(VCCB) U46.16(VCC) U50.5(VCC) U51.E6(VCC#E6) U51.F5(VCC#F5) U51.J10(VCC#J10) U51.K9(VCC#K9) U52.8(VCC) U54.8(VCC) U55.5(VCC) U56.8(VCC) U67.2(A0) U67.6(VS+) U68.6(VS+) U69.1(A1) U69.6(VS+) U70.1(A1) U70.6(VS+) U83.8(VCC) U84.1(VCC) U87.3(VCCA) U87.7(VCCB) U89.4(V+) U90.5(VCC) U91.8(VCC) U92.5(VCC) U93.1(A1) U93.6(VS+) U95.1(VCCA) U95.16(VCCB) U97.1(VCCA) U98.1(VCCA) U99.27(VCCP) U99.31(VCC) U100.19(VCCB) U101.1(VCCA) U101.8(VCCB) U102.1(VCCA) U102.23(VCCB1) U102.24(VCCB2) U103.3(VCCA) U105.1(VCCA) U105.23(VCCB1) U105.24(VCCB2) U108.5(VCC) U109.7(VCCA) U110.21(VCC) U111.19(VCCB) U112.4(VCC) U113.5(VCC) U115.2(IN1) U115.3(IN2)
VCC3V3_PREREG: C1.1 C15.1 C23.1 C25.1 C211.1 C231.1 C252.1 C253.1 C255.1 C256.1 C257.1 C260.1 C262.1 C283.1 C284.1 C290.1 C606.1 R3.1 R4.2 R7.1 R8.1 R12.2 R345.1 R357.1 R376.2 R486.1 R549.2 R702.1 TP1.1(TP) U1.4(IN) U5.6(IN) U10.2(VLDOIN) U10.10(VDD) U40.7(PVIN) U40.8(AVIN) U49.6(VCC) U59.A1(AVIN) U59.A4(VIN) U60.6(IN) U61.3(VIN1) U61.9(VIN2) U63.7(PVIN) U63.8(AVIN) U64.3(DEF) U64.10(AVIN) U64.11(PVIN#11) U64.12(PVIN#12) U64.13(EN) U94.7(VIN)
VCC3V3_PREREG_PG: C316.1 R376.1 TP83.1(TP) U5.4(EN) U40.6(EN) U75.24(PG1) U80.8(EN)
VCC3V3_R: J32.1 R184.1
VCC3V3_XDS: C249.1 C251.1 C611.1 C616.1 C621.1 C633.1 C642.1 C646.1 C647.1 C650.1 C657.1 C660.1 C668.1 C669.1 J34.5 J40.1 R313.2 R314.2 R322.2 R334.1 R649.2 R651.2 R654.1 R655.1 R657.2 R663.1 U57.3(OUT1) U57.4(OUT2) U97.8(VCCB) U98.16(VCCB) U103.7(VCCB) U106.7(VDD#7) U106.8(VDDA) U106.16(VDD#16) U106.26(VDD#26) U106.28(VDD#28) U106.39(VDD#39) U106.47(VDD#47) U106.51(VDD#51) U106.52(VDD#52) U106.69(VDD#69) U106.79(VDD#79) U106.90(VDD#90) U106.101(VDD#101) U106.113(VDD#113) U106.122(VDD#122)
VCC5V0_PG: R404.1 U75.7(PG2)
VCC_1V8_FT4232: C321.2 C322.2 C347.2 C349.2 U73.12(VCORE#12) U73.37(VCORE#37) U73.49(VREGOUT) U73.64(VCORE#64)
VCC_2V5: C17.1 C297.1 C298.1 FL1.1 J6.1 TP82.1(TP) U5.1(OUT)
VCC_3V3_FT4232: C40.1 C91.1 C94.1 C305.2 C306.2 C326.2 C339.1 C348.2 C360.2 C397.1 FL9.2 FL10.2 R77.1 R408.2 R413.2 R416.2 U12.2(VCCB) U19.2(VCCB) U21.2(VCCB) U73.20(VCCIO#20) U73.31(VCCIO#31) U73.42(VCCIO#42) U73.50(VREGIN) U73.56(VCCIO#56) U76.1(OUT) U79.8(VCC) U85.2(VCCB)
VCC_5V0: C50.1 C223.1 C228.1 C309.1 C313.1 C365.1 C367.1 C368.1 C628.1 C630.1 C643.1 C644.1 FL2.1(I) J6.8 J6.10 J16.2 J16.4 J16.6 J35.55 J35.57 J35.59 J36.55 J36.57 J36.59 J38.1 J38.2 J38.3 R1.1 R426.2 R704.1 TP7.1(TP) U75.6(VCCX)
VCC_12V0: C7.1 C8.1 C9.1 C10.1 C12.1 C24.1 C56.1 C296.1 C301.1 C336.1 D3.1(CATHODE) D5.1(CATHODE) J6.7 J6.9 J9.2 R2.1 R54.1 TP66.1(TP) U14.10(VOUT) U14.17(VCCX)
VCC_HDR: C663.1 J37.2 R662.1 R666.1 R688.2 U111.2(VCCA)
VCC_LM5140: C330.1 C679.1 D15.2(ANODE) D17.2(ANODE) U75.15(VCC#15) U75.16(VCC#16)
VDD1V8_PG: C258.1 R336.1 TP81.1(TP) U60.3(PG) U61.4(EN) U94.2(PG)
VDD3V3_CLKBUF: C160.1 C169.2 FL3.2 R173.1 R185.1 R189.2 R193.2 R199.2 U32.10(VDD)
VDD_1V0: C101.1 C110.1 C111.1 C124.1 C125.1 C149.1 C150.1 C163.1 C187.1 C193.1 C195.1 C197.1 C208.1 C215.1 C271.1 C272.1 C310.1 C314.1 C372.1 C388.1 C392.1 C399.1 C403.1 C407.1 C446.1 C453.1 C471.1 C512.1 C577.1 C589.1 C590.1 C599.1 J6.2 J16.56 J16.58 J16.60 L7.2 R344.1 TP27.1(TP) U22.6(VDD1P0#6) U22.24(VDD1P0#24) U22.31(VDD1P0#31) U22.42(VDD1P0#42) U31.6(VDD1P0#6) U31.24(VDD1P0#24) U31.31(VDD1P0#31) U31.42(VDD1P0#42) U64.16(VOS) U88.6(VDD1P0#6) U88.24(VDD1P0#24) U88.31(VDD1P0#31) U88.42(VDD1P0#42)
VDD_1V0_PG: R345.2 U64.4(PG)
VDD_2V5: C109.1 C117.1 C143.1 C153.1 C194.1 C196.1 C199.1 C212.1 C378.1 C381.1 C393.1 C424.1 C466.1 C499.1 C588.1 C592.1 C609.1 C612.1 J16.52 J16.54 L2.2 R566.1 TP64.1(TP) U22.3(VDDA2P5#3) U22.9(VDDA2P5#9) U31.3(VDDA2P5#3) U31.9(VDDA2P5#9) U40.3(VOS) U88.3(VDDA2P5#3) U88.9(VDDA2P5#9)
VDD_CORE: C373.1 C374.1 C376.1 C377.1 C382.1 C383.1 C390.1 C391.1 C431.1 C451.1 C469.1 C473.1 C476.1 C479.1 C484.1 C485.1 C486.1 C487.1 C488.1 C490.1 C491.1 C494.1 C500.1 C502.1 C503.1 C509.1 C510.1 C511.1 C516.1 C517.1 C518.1 C520.1 C531.1 C532.1 C533.1 C534.1 C539.1 C543.1 C550.1 FL19.1 J27.2 R339.1 R355.2 U34.AA12(VDD#AA12) U34.J8(VDD#J8) U34.J10(VDD#J10) U34.J12(VDD#J12) U34.J14(VDD#J14) U34.J19(VDD#J19) U34.K13(VDD#K13) U34.L14(VDD#L14) U34.L19(VDD#L19) U34.M13(VDD#M13) U34.N14(VDD#N14) U34.P13(VDD#P13) U34.P15(VDD#P15) U34.P19(VDD#P19) U34.R14(VDD#R14) U34.R16(VDD#R16) U34.R18(VDD#R18) U34.T13(VDD#T13) U34.T15(VDD#T15) U34.T17(VDD#T17) U34.T19(VDD#T19) U34.U14(VDD#U14) U34.U16(VDD#U16) U34.U18(VDD#U18) U34.V13(VDD#V13) U34.V15(VDD#V15) U34.V19(VDD#V19) U34.W14(VDD#W14) U34.W18(VDD#W18) U34.Y11(VDD#Y11) U34.Y13(VDD#Y13) U34.Y15(VDD#Y15)
VDD_CORE_PG: C2.1 R8.2 TP79.1(TP) U59.A3(VSEL1) U59.B2(EN) U59.C2(VSEL0) U61.5(PG)
VDD_DDR4: C22.1 C44.1 C45.1 C47.1 C53.1 C78.1 C80.1 C81.1 C83.1 C86.1 C87.1 C89.1 C90.1 C95.1 C97.1 C98.1 C100.1 C105.1 C106.1 C108.1 C112.1 C128.1 C129.1 C130.1 C132.1 C139.1 C140.1 C142.1 C154.1 C172.1 C174.1 C175.1 C177.1 C182.1 C183.1 C185.1 C190.1 C202.1 C204.1 C205.1 C207.1 C303.1 C311.1 C312.1 C315.1 C332.1 C335.1 C351.1 C354.1 C355.1 C364.1 C369.1 C380.1 C385.1 C387.1 C398.1 C402.1 C434.1 C447.1 C449.1 C528.1 C538.1 C579.1 C583.1 C585.1 C593.1 C594.1 J28.2 R182.2 R220.2 R360.1 R460.2 R503.2 R516.1 U10.1(VDDQSNS) U16.A1(VDD#A1) U16.B2(VDDQ#B2) U16.B8(VDDQ#B8) U16.C1(VDDQ#C1) U16.C7(VDD#C7) U16.C9(VDDQ#C9) U16.E2(VDDQ#E2) U16.E8(VDDQ#E8) U16.F1(VDD#F1) U16.F9(VDD#F9) U16.H1(VDD#H1) U16.J9(VDD#J9) U16.M1(VDD#M1) U16.N9(VDD#N9) U20.A1(VDD#A1) U20.B2(VDDQ#B2) U20.B8(VDDQ#B8) U20.C1(VDDQ#C1) U20.C7(VDD#C7) U20.C9(VDDQ#C9) U20.E2(VDDQ#E2) U20.E8(VDDQ#E8) U20.F1(VDD#F1) U20.F9(VDD#F9) U20.H1(VDD#H1) U20.J9(VDD#J9) U20.M1(VDD#M1) U20.N9(VDD#N9) U25.A1(VDD#A1) U25.B2(VDDQ#B2) U25.B8(VDDQ#B8) U25.C1(VDDQ#C1) U25.C7(VDD#C7) U25.C9(VDDQ#C9) U25.E2(VDDQ#E2) U25.E8(VDDQ#E8) U25.F1(VDD#F1) U25.F9(VDD#F9) U25.H1(VDD#H1) U25.J9(VDD#J9) U25.M1(VDD#M1) U25.N9(VDD#N9) U33.A1(VDD#A1) U33.B2(VDDQ#B2) U33.B8(VDDQ#B8) U33.C1(VDDQ#C1) U33.C7(VDD#C7) U33.C9(VDDQ#C9) U33.E2(VDDQ#E2) U33.E8(VDDQ#E8) U33.F1(VDD#F1) U33.F9(VDD#F9) U33.H1(VDD#H1) U33.J9(VDD#J9) U33.M1(VDD#M1) U33.N9(VDD#N9) U38.A1(VDD#A1) U38.B2(VDDQ#B2) U38.B8(VDDQ#B8) U38.C1(VDDQ#C1) U38.C7(VDD#C7) U38.C9(VDDQ#C9) U38.E2(VDDQ#E2) U38.E8(VDDQ#E8) U38.F1(VDD#F1) U38.F9(VDD#F9) U38.H1(VDD#H1) U38.J9(VDD#J9) U38.M1(VDD#M1) U38.N9(VDD#N9)
VDD_DLL_CORE: C575.1 C580.1 FL19.2 U34.G22(VDD_DLL0) U34.H23(VDD_DLL1)
VDD_MCU: C375.1 C384.1 C452.1 C457.1 C458.1 C468.1 C482.1 J26.2 R349.1 U34.N10(VDD_MCU#N10) U34.P11(VDD_MCU#P11) U34.R10(VDD_MCU#R10) U34.R12(VDD_MCU#R12) U34.T11(VDD_MCU#T11)
VDD_MMC1: C692.1 C695.1 FL38.1 U115.6(OUT1) U115.7(OUT2) U115.8(OUT3)
VDD_MMC1_SD: C235.1 FL38.2 J17.4(VDD)
VDD_MPU: C437.1 C438.1 C456.1 C460.1 C461.1 C462.1 C463.1 C465.1 C467.1 C492.1 C496.1 C497.1 C498.1 C515.1 C524.1 C525.1 C526.1 C530.1 C535.1 J24.2 R348.1 R476.1 U34.K9(VDD_MPU0#K9) U34.K11(VDD_MPU0#K11) U34.K16(VDD_MPU1#K16) U34.K18(VDD_MPU1#K18) U34.L8(VDD_MPU0#L8) U34.L10(VDD_MPU0#L10) U34.L17(VDD_MPU1#L17) U34.M11(VDD_MPU0#M11) U34.M16(VDD_MPU1#M16) U34.M18(VDD_MPU1#M18) U34.N17(VDD_MPU1#N17) U59.B1(SENSE+)
VDDA1V8: C259.1 C263.1 J25.1 R342.2 TP22.1(TP) U60.1(OUT)
VDDA_1P8_OLDI: C566.1 FL21.2 U34.L22(VDDS_OLDI)
VDDA_1V8: FL21.1 FL22.1 FL23.1 FL24.1 FL25.1 FL26.1 FL27.1 FL28.1 FL29.1 FL30.1 FL31.1 FL32.1 FL33.1 FL34.1 FL35.1 J25.2 R342.3 U34.AB6(VDDA_1P8_WKUP_MON) U34.AC6(VDDA_1P8_SOC_MON)
VDDA_3P3_IOLDO_WKUP: C450.1 FL16.2 U34.AB9(VDDA_3P3_IOLDO_WKUP)
VDDA_3P3_USB: C464.1 C501.1 FL18.2 U34.AC12(VDDA_3P3_USB)
VDDA_3V3_SDIO: FL13.2 U34.H17(VDDA_3P3_SDIO)
VDDA_GP1: C478.1 C495.1 C521.1 FL27.2 U34.AA14(VDDA_GP1#AA14) U34.AB13(VDDA_GP1#AB13) U34.AB15(VDDA_GP1#AB15)
VDDA_GP3: C472.1 FL30.2 U34.U12(VDDA_GP3)
VDDA_GP4: C556.1 C595.1 FL28.2 U34.L20(VDDS_GP4#L20) U34.M21(VDDS_GP4#M21)
VDDA_GP9: C448.1 FL29.2 U34.AA9(VDDA_GP9)
VDDA_LM5140: C318.1 R404.2 U75.3(FB2) U75.28(FB1) U75.33(DEMB) U75.34(ILSET) U75.36(VDDA) U75.37(OSC)
VDDA_MCU_ADC: C423.1 C444.1 FL26.2 U34.M7(VDDA_MCU_ADC#M7) U34.M9(VDDA_MCU_ADC#M9)
VDDA_PLL_DDR: C455.1 C507.1 FL32.2 U34.H11(VDDA_PLL1_DDR) U34.H15(VDDA_PLL0_DDR)
VDDA_PLL_DSS: C565.1 FL33.2 U34.L21(VDDA_PLL_DSS)
VDDA_PLL_MAIN: C527.1 FL34.2 U34.Y17(VDDA_PLL_MAIN)
VDDA_PLL_MPU: C474.1 C508.1 FL31.2 U34.K15(VDDA_PLL_ARM1) U34.L12(VDDA_PLL_ARM0)
VDDA_PLL_PER0: C422.1 FL35.2 U34.AB7(VDDA_PLL_PER0)
VDDA_POR: C445.1 FL24.2 U34.Y9(VDDA_WKUP_POR)
VDDA_SRAM_CORE: C519.1 C546.1 FL22.2 U34.M19(VDDA_CORE0_SRAM) U34.V16(VDDA_CORE2_SRAM)
VDDA_SRAM_MPU: C419.1 C540.1 FL23.2 U34.K7(VDDA_MPU0_SRAM) U34.L18(VDDA_MPU1_SRAM)
VDDA_SYS_MON: R484.1 R486.2 U34.AC11(VDDA_PMIC_INPUT_MON)
VDDA_WKUP_LDO: C430.1 FL25.2 U34.AB8(VDDA_WKUP_LDO)
VDDC_1V2: C651.1 C653.1 C667.1 U106.87(VDDC#87) U106.115(VDDC#115)
VDDIM: C618.1 C620.1 U51.C2(VDDIM)
VDDR_VTT: C30.1 C31.1 C32.1 C33.1 C34.1 C35.1 C36.1 C38.2 C52.1 C57.1 C64.1 C65.1 C67.1 C70.1 C71.1 C328.1 R43.2 R44.2 R45.2 R46.2 R47.2 R48.2 R49.2 R56.2 R57.2 R61.2 R63.2 R67.2 R69.2 R70.2 R366.2 R367.2 R368.2 R369.2 R370.2 R371.2 R372.2 R377.2 R379.2 R382.2 R383.2 R386.2 R389.2 R391.2 R393.2 R742.2 TP5.1(TP) U10.3(VTT) U10.5(VTTSNS)
VDDS_OSC1: C514.1 C522.1 FL36.2 U34.J16(VDDS_SOC_OSC1)
VDDSHV_MMC1: C552.1 C564.2 C572.1 FL20.2 FL37.1 U34.J20(VDDSHV_MMC1#J20) U34.J22(VDDSHV_MMC1#J22) U34.K21(VDDSHV_MMC1#K21)
VDDSHV_SD_IO: C233.1 C607.1 FL37.2 R310.1 R600.2 R606.1 R607.1 R608.1 R614.1 R616.1 TP75.1(TP) U47.10(VCC) U96.7(VCCB)
VIN: C254.1 D6.1(CATHODE) Q1.4(D) R337.1 U62.1(V+)
VIN_MON_PORZ_3V3_PG: C353.1 R210.2 R401.2 TP76.1(TP) U35.1(OUT) U50.3(B) U60.4(EN) U63.6(EN) U80.10(PGOOD) U94.1(EN)
VINPUT: C39.1 C282.1 Q1.3(S) Q2.4(D) R13.1 R347.2 R351.1 R352.1 R354.1 R362.1 TP10.1(TP) U62.3(SOURCE) U66.2(VIN)
ADDR: R622.2 U99.26(ADDR)
APP_CARD_PSTN: J18.113 R238.1 U46.4(P0)
APP_PRG0_PRU0GPO16: J18.19 R570.2
APP_PRG0_PRU0GPO17: J18.10 R589.2
APP_PRG0_PRU1GPO0: J18.30 R576.2
APP_PRG0_PRU1GPO1: J18.34 R580.2
APP_PRG0_PRU1GPO2: J18.32 R578.2
APP_PRG0_PRU1GPO3: J18.28 R574.2
APP_PRG0_PRU1GPO4: J18.26 R572.2
APP_PRG0_PRU1GPO5: J18.8 R587.2
APP_UART1_CTS: J16.27 U26.13(ID1)
APP_UART1_RTS: J16.29 U26.10(IC1)
APP_UART1_RX: J16.31 U26.6(IB1)
APP_UART1_TX: J16.33 U26.3(IA1)
ATEST0_POK: TP29.1(TP) U34.B1(ATEST0_POK)
ATEST0_POR: TP50.1(TP) U34.AA6(ATEST0_POR)
ATEST-MAIN: TP58.1(TP) U34.AC23(ATEST_MAIN)
BOARD ID_APP_A1: J16.42
BOARD ID_LCD_A0: J38.31
BOARD ID_LCD_A2: J38.37
BOARDID_HDMI_A0: J35.8 J36.8
BOARDID_HDMI_A1: J35.10 J36.10
BOARDID_SERDES_A2: J5.11
BOOST_DRIVE: U13.4(G) U14.15(LO)
BOOT_EEPROM_A0: R23.2 R24.2 U9.1(A0)
BOOT_EEPROM_A1: R21.2 R22.2 U9.2(A1)
BOOT_EEPROM_A2: R19.1 R20.1 U9.3(A2)
BOOT_EEPROM_WP: R38.2 U9.7(WP)
BOOTMODE_I2C_SCL: J41.37 R696.2 U99.29(SCL)
BOOTMODE_I2C_SDA: J41.39 R697.2 U99.30(SDA)
BOOTMODEON: U17.4(Y) U95.14(2\O\E\) U95.15(1\O\E\) U102.22(O\E\) U105.22(O\E\)
BUCK_DRIVE: U14.19(HO) U18.4(G)
CAP_VDD_WKUP: C115.1 C443.1 C459.1 C475.1 C571.1 U34.M22(VDD_WKUP1) U34.V9(CAP_VDD_WKUP) U34.V11(VDD_WKUP#V11) U34.W10(VDD_WKUP#W10) U34.W12(VDD_WKUP#W12)
CAP_VDDA_1P8_IOLDO0: C170.2 U34.AA10(VDDS18V6) U34.AA16(VDDS_GENERAL_BIAS1) U34.G12(VDDS_GENERAL_BIAS0) U34.G19(CAP_VDDA_1P8_IOLDO0) U34.P20(VDDS_GPMC_BIAS)
CAP_VDDA_1P8_IOLDO1: C200.1 U34.Y19(CAP_VDDA_1P8_IOLDO1)
CAP_VDDA_1P8_IOLDO_WKUP: C113.2 U34.AA8(CAP_VDDA_1P8_IOLDO_WKUP) U34.V8(VDDS_WKUP_GENERAL_BIAS0)
CAP_VDDA_1P8_SDIO: C180.1 U34.G17(VDDQIN_SDIO) U34.J17(CAP_VDDA_1P8_SDIO) U34.K20(VDDS_MMC_BIAS1)
CAP_VDDAR_CORE0: C167.1 U34.P17(CAP_VDDAR_CORE0)
CAP_VDDAR_CORE1: C165.1 U34.V17(CAP_VDDAR_CORE1)
CAP_VDDAR_CORE2: C159.1 U34.W16(CAP_VDDAR_CORE2)
CAP_VDDAR_CORE3: C157.1 U34.M14(CAP_VDDAR_CORE3)
CAP_VDDAR_CORE4: C158.1 U34.L15(CAP_VDDAR_CORE4)
CAP_VDDAR_MCU: C116.1 U34.U10(CAP_VDDAR_MCU)
CAP_VDDAR_MPU0_0: C151.1 U34.M12(CAP_VDDAR_MPU0_0)
CAP_VDDAR_MPU0_1: C386.1 U34.N12(CAP_VDDAR_MPU0_1)
CAP_VDDAR_MPU2: C201.1 U34.N18(CAP_VDDAR_MPU2)
CAP_VDDAR_MPU3: C164.1 U34.N15(CAP_VDDAR_MPU3)
CAP_VDDAR_WKUP: C114.1 U34.Y10(CAP_VDDAR_WKUP)
CAP_VDDSHV_SDLDO: C541.1 FL20.1 U34.H18(CAP_VDDSHV_SDLDO)
CDCEL_XIN: R194.2 U32.11(XIN)
CDCEL_XOUT: R191.2 U32.12(XOUT)
COMP: C48.1 R55.1 U14.9(COMP)
CON_LCD_PWR_DN: J35.40 J36.40 U110.7(P06)
CS: D8.2(ANODE) D9.2(ANODE) R62.1 U14.12(CS)
CSI0_RXN0: J22.7 J39.9 U34.G28(CSI0_RXN0)
CSI0_RXN1: J22.11 J39.12 U34.H27(CSI0_RXN1)
CSI0_RXN2: J22.15 J39.15 U34.F26(CSI0_RXN2)
CSI0_RXN3: J22.19 J39.18 U34.H25(CSI0_RXN3)
CSI0_RXN4: J22.23 J39.21 U34.G24(CSI0_RXN4)
CSI0_RXP0: J22.5 J39.8 U34.F28(CSI0_RXP0)
CSI0_RXP1: J22.9 J39.11 U34.G27(CSI0_RXP1)
CSI0_RXP2: J22.13 J39.14 U34.G26(CSI0_RXP2)
CSI0_RXP3: J22.17 J39.17 U34.G25(CSI0_RXP3)
CSI0_RXP4: J22.21 J39.20 U34.F24(CSI0_RXP4)
CSI_`MCU_SPI0_D0: J22.18 J39.30 U111.4(A3)
CSI_MCU_SCL: J22.2 J39.25 R662.2 U111.1(A1)
CSI_MCU_SDA: J22.4 J39.24 R666.2 U111.3(A2)
CSI_MCU_SPI0_CLK: J22.20 J39.31 U111.5(A4)
CSI_MCU_SPI0_CS0: J22.22 J39.32 U111.6(A5)
CSI_REF_CLK: J22.10 U111.8(A7)
CSI_REF_CLK_1V8: J39.26 R699.2
CSI_REF_CLK_3V3: R674.2 U111.13(B7)
CSI_RESETN: J22.14 J39.23 U111.7(A6)
CSI_RSTN: R664.1 U108.4(Y) U111.14(B6)
CTI_TCK: R233.1 U42.3(1B2)
DDR_A0: R389.1 U16.L3(A0) U20.L3(A0) U25.L3(A0) U33.L3(A0) U34.A10(DDR_AC0) U38.L3(A0)
DDR_A1: R43.1 U16.L7(A1) U20.L7(A1) U25.L7(A1) U33.L7(A1) U34.D9(DDR_AC1) U38.L7(A1)
DDR_A2: R393.1 U16.M3(A2) U20.M3(A2) U25.M3(A2) U33.M3(A2) U34.C9(DDR_AC2) U38.M3(A2)
DDR_A3: R369.1 U16.K7(A3) U20.K7(A3) U25.K7(A3) U33.K7(A3) U34.E9(DDR_AC3) U38.K7(A3)
DDR_A4: R386.1 U16.K3(A4) U20.K3(A4) U25.K3(A4) U33.K3(A4) U34.A9(DDR_AC4) U38.K3(A4)
DDR_A5: R368.1 U16.L8(A5) U20.L8(A5) U25.L8(A5) U33.L8(A5) U34.E8(DDR_AC5) U38.L8(A5)
DDR_A6: R67.1 U16.L2(A6) U20.L2(A6) U25.L2(A6) U33.L2(A6) U34.F8(DDR_AC6) U38.L2(A6)
DDR_A7: R49.1 U16.M8(A7) U20.M8(A7) U25.M8(A7) U33.M8(A7) U34.C7(DDR_AC7) U38.M8(A7)
DDR_A8: R69.1 U16.M2(A8) U20.M2(A8) U25.M2(A8) U33.M2(A8) U34.C8(DDR_AC8) U38.M2(A8)
DDR_A9: R367.1 U16.M7(A9) U20.M7(A9) U25.M7(A9) U33.M7(A9) U34.D7(DDR_AC9) U38.M7(A9)
DDR_A10: R383.1 U16.J3(A10/AP) U20.J3(A10/AP) U25.J3(A10/AP) U33.J3(A10/AP) U34.E7(DDR_AC10) U38.J3(A10/AP)
DDR_A11: R70.1 U16.N2(A11) U20.N2(A11) U25.N2(A11) U33.N2(A11) U34.A6(DDR_AC11) U38.N2(A11)
DDR_A12: R370.1 U16.J7(A12/BC_N) U20.J7(A12/BC_N) U25.J7(A12/BC_N) U33.J7(A12/BC_N) U34.F7(DDR_AC12) U38.J7(A12/BC_N)
DDR_A13: R44.1 U16.N8(A13) U20.N8(A13) U25.N8(A13) U33.N8(A13) U34.D6(DDR_AC13) U38.N8(A13)
DDR_A14_WEN: R382.1 U16.H2(WE_N/A14) U20.H2(WE_N/A14) U25.H2(WE_N/A14) U33.H2(WE_N/A14) U34.C6(DDR_AC14) U38.H2(WE_N/A14)
DDR_A15_CAS: R46.1 U16.H7(CAS_N/A15) U20.H7(CAS_N/A15) U25.H7(CAS_N/A15) U33.H7(CAS_N/A15) U34.F6(DDR_AC15) U38.H7(CAS_N/A15)
DDR_A16_RAS: R371.1 U16.H8(RAS_N/A16) U20.H8(RAS_N/A16) U25.H8(RAS_N/A16) U33.H8(RAS_N/A16) U34.E6(DDR_AC16) U38.H8(RAS_N/A16)
DDR_A17: R366.1 U16.N7(A17/NF) U20.N7(A17/NF) U25.N7(A17/NF) U33.N7(A17/NF) U34.E5(DDR_AC17) U38.N7(A17/NF)
DDR_ACTN: R742.1 U16.H3(ACT_N) U20.H3(ACT_N) U25.H3(ACT_N) U33.H3(ACT_N) U34.D8(DDR_AC18) U38.H3(ACT_N)
DDR_ALERTN: R460.1 U16.L9(ALERT_N) U20.L9(ALERT_N) U25.L9(ALERT_N) U33.L9(ALERT_N) U34.D5(DDR_ALERT_N) U38.L9(ALERT_N)
DDR_BA0: R63.1 U16.K2(BA0) U20.K2(BA0) U25.K2(BA0) U33.K2(BA0) U34.D10(DDR_AC19) U38.K2(BA0)
DDR_BA1: R48.1 U16.K8(BA1) U20.K8(BA1) U25.K8(BA1) U33.K8(BA1) U34.E10(DDR_AC20) U38.K8(BA1)
DDR_BG0: R61.1 U16.J2(BG0) U20.J2(BG0) U25.J2(BG0) U33.J2(BG0) U34.C10(DDR_AC21) U38.J2(BG0)
DDR_BG1: R47.1 U16.J8(BG1) U20.J8(BG1) U25.J8(BG1) U33.J8(BG1) U34.F11(DDR_AC22) U38.J8(BG1)
DDR_CKE: R57.1 R731.1 U16.G3(CKE) U20.G3(CKE) U25.G3(CKE) U33.G3(CKE) U34.C11(DDR_AC26) U38.G3(CKE)
DDR_CKE1: R379.1 R730.1 U16.G2(C0/CKE1) U20.G2(C0/CKE1) U25.G2(C0/CKE1) U33.G2(C0/CKE1) U34.D12(DDR_AC29) U38.G2(C0/CKE1)
DDR_CLKN: R374.1 U16.F8(CK_C) U20.F8(CK_C) U25.F8(CK_C) U33.F8(CK_C) U34.B8(DDR_CK0_N) U38.F8(CK_C)
DDR_CLKP: R373.1 U16.F7(CK_T) U20.F7(CK_T) U25.F7(CK_T) U33.F7(CK_T) U34.A8(DDR_CK0) U38.F7(CK_T)
DDR_CS1N: R45.1 U16.G8(C1/CS1_N) U20.G8(C1/CS1_N) U25.G8(C1/CS1_N) U33.G8(C1/CS1_N) U34.E11(DDR_AC27) U38.G8(C1/CS1_N)
DDR_CSN: R372.1 U16.G7(CS_N) U20.G7(CS_N) U25.G7(CS_N) U33.G7(CS_N) U34.D11(DDR_AC24) U38.G7(CS_N)
DDR_DM0: U16.A7(NF/NF/DM_N/DBI_N/TDQS_T) U34.E1(DDR_DQDM8)
DDR_DM1: U20.A7(NF/NF/DM_N/DBI_N/TDQS_T) U34.C5(DDR_DQDM17)
DDR_DM2: U25.A7(NF/NF/DM_N/DBI_N/TDQS_T) U34.D14(DDR_DQDM26)
DDR_DM3: U33.A7(NF/NF/DM_N/DBI_N/TDQS_T) U34.B17(DDR_DQDM35)
DDR_DM4: U34.C17(DDR_DQDM43) U38.A7(NF/NF/DM_N/DBI_N/TDQS_T)
DDR_DQ0: U16.C2(DQ0) U34.A3(DDR_DQDM0)
DDR_DQ1: U16.B7(DQ1) U34.B2(DDR_DQDM1)
DDR_DQ2: U16.D3(DQ2) U34.C2(DDR_DQDM2)
DDR_DQ3: U16.D7(DQ3) U34.D2(DDR_DQDM3)
DDR_DQ4: U16.D2(DQ4/NC) U34.E2(DDR_DQDM4)
DDR_DQ5: U16.D8(DQ5/NC) U34.G1(DDR_DQDM5)
DDR_DQ6: U16.E3(DQ6/NC) U34.F2(DDR_DQDM6)
DDR_DQ7: U16.E7(DQ7/NC) U34.F1(DDR_DQDM7)
DDR_DQ8: U20.C2(DQ0) U34.E3(DDR_DQDM9)
DDR_DQ9: U20.B7(DQ1) U34.C3(DDR_DQDM10)
DDR_DQ10: U20.D3(DQ2) U34.D3(DDR_DQDM11)
DDR_DQ11: U20.D7(DQ3) U34.B3(DDR_DQDM12)
DDR_DQ12: U20.D2(DQ4/NC) U34.D4(DDR_DQDM13)
DDR_DQ13: U20.D8(DQ5/NC) U34.C4(DDR_DQDM14)
DDR_DQ14: U20.E3(DQ6/NC) U34.B4(DDR_DQDM15)
DDR_DQ15: U20.E7(DQ7/NC) U34.B5(DDR_DQDM16)
DDR_DQ16: U25.C2(DQ0) U34.E13(DDR_DQDM18)
DDR_DQ17: U25.B7(DQ1) U34.C14(DDR_DQDM19)
DDR_DQ18: U25.D3(DQ2) U34.B14(DDR_DQDM20)
DDR_DQ19: U25.D7(DQ3) U34.A14(DDR_DQDM21)
DDR_DQ20: U25.D2(DQ4/NC) U34.E14(DDR_DQDM22)
DDR_DQ21: U25.D8(DQ5/NC) U34.B13(DDR_DQDM23)
DDR_DQ22: U25.E3(DQ6/NC) U34.C13(DDR_DQDM24)
DDR_DQ23: U25.E7(DQ7/NC) U34.D13(DDR_DQDM25)
DDR_DQ24: U33.C2(DQ0) U34.D15(DDR_DQDM27)
DDR_DQ25: U33.B7(DQ1) U34.C15(DDR_DQDM28)
DDR_DQ26: U33.D3(DQ2) U34.E16(DDR_DQDM29)
DDR_DQ27: U33.D7(DQ3) U34.E15(DDR_DQDM30)
DDR_DQ28: U33.D2(DQ4/NC) U34.D16(DDR_DQDM31)
DDR_DQ29: U33.D8(DQ5/NC) U34.B16(DDR_DQDM32)
DDR_DQ30: U33.E3(DQ6/NC) U34.C16(DDR_DQDM33)
DDR_DQ31: U33.E7(DQ7/NC) U34.A17(DDR_DQDM34)
DDR_DQ36: U34.B19(DDR_DQDM36) U38.C2(DQ0)
DDR_DQ37: U34.B18(DDR_DQDM37) U38.B7(DQ1)
DDR_DQ38: U34.C18(DDR_DQDM38) U38.D3(DQ2)
DDR_DQ39: U34.D18(DDR_DQDM39) U38.D7(DQ3)
DDR_DQ40: U34.E18(DDR_DQDM40) U38.D2(DQ4/NC)
DDR_DQ41: U34.E17(DDR_DQDM41) U38.D8(DQ5/NC)
DDR_DQ42: U34.D17(DDR_DQDM42) U38.E3(DQ6/NC)
DDR_DQS0_N: U16.B3(DQS_C) U34.C1(DDR_DQS0_N)
DDR_DQS0_P: U16.C3(DQS_T) U34.D1(DDR_DQS0)
DDR_DQS1_N: U20.B3(DQS_C) U34.A4(DDR_DQS1_N)
DDR_DQS1_P: U20.C3(DQS_T) U34.A5(DDR_DQS1)
DDR_DQS2_N: U25.B3(DQS_C) U34.A12(DDR_DQS2_N)
DDR_DQS2_P: U25.C3(DQS_T) U34.A13(DDR_DQS2)
DDR_DQS3_N: U33.B3(DQS_C) U34.A16(DDR_DQS3_N)
DDR_DQS3_P: U33.C3(DQS_T) U34.A15(DDR_DQS3)
DDR_DQS_N: U34.A18(DDR_DQS4_N) U38.B3(DQS_C)
DDR_DQS_P: U34.A19(DDR_DQS4) U38.C3(DQS_T)
DDR_ODT: R377.1 U16.F3(ODT) U20.F3(ODT) U25.F3(ODT) U33.F3(ODT) U34.B11(DDR_AC25) U38.F3(ODT)
DDR_ODT1: R56.1 U16.F2(C2/ODT1) U20.F2(C2/ODT1) U25.F2(C2/ODT1) U33.F2(C2/ODT1) U34.E12(DDR_AC28) U38.F2(C2/ODT1)
DDR_PARITY: R391.1 U16.N3(PAR) U20.N3(PAR) U25.N3(PAR) U33.N3(PAR) U34.B10(DDR_AC23) U38.N3(PAR)
DDR_RESET#: R165.1 R171.1 R219.2 R220.1 U16.L1(RESET_N) U20.L1(RESET_N) U25.L1(RESET_N) U33.L1(RESET_N) U38.L1(RESET_N)
DDR_RESET_FS: R171.2 R182.1 U34.F16(DDR_FS_RESET_N)
DDR_TEN: R462.2 R503.1 U16.G9(TEN) U20.G9(TEN) U25.G9(TEN) U33.G9(TEN) U38.G9(TEN)
DDR_VPP: C43.1 C46.1 C79.1 C85.1 C88.1 C96.1 C104.1 C107.1 C127.1 C137.1 C141.1 C173.1 C181.1 C184.1 C203.1 FL1.2 U16.B1(VPP#B1) U16.M9(VPP#M9) U20.B1(VPP#B1) U20.M9(VPP#M9) U25.B1(VPP#B1) U25.M9(VPP#M9) U33.B1(VPP#B1) U33.M9(VPP#M9) U38.B1(VPP#B1) U38.M9(VPP#M9)
DDR_VREFCA: C37.1 C82.1 C99.1 C131.1 C176.1 C206.1 C338.1 C370.1 C411.1 C544.1 C597.1 R728.1 U10.6(VTTREF) U16.J1(VREFCA) U20.J1(VREFCA) U25.J1(VREFCA) U33.J1(VREFCA) U38.J1(VREFCA)
DDR_VTT_EN: R707.1 U34.P3(MCU_OSPI1_D0) U109.4(B2)
DDR_VTT_EN_3V3: R41.1 TP84.1(TP) U10.7(S3) U10.9(S5) U109.9(A2)
DEBOUNCE_WARM_RST: C242.1 D13.1(K) R321.1 SW7.1 SW7.2 U52.6(3A)
DEBOUNCE_WKUP_GPIO0_13: C240.1 D12.1(K) R320.1 SW5.1 SW5.2 U52.3(2A)
DEBOUNCE_WKUP_GPIO0_27: C241.1 D10.1(K) R318.1 SW6.1 SW6.2 U52.1(1A)
DIR: R648.2 R656.1 U95.2(1DIR) U95.3(2DIR) U102.2(DIR) U105.2(DIR)
ECAP0_IN_APWM0_OUT: J38.38 U34.D21(ECAP0_IN_APWM0_OUT)
EEPROM_A1: R327.2 R328.2 U56.2(A1)
EEPROM_A2: R330.2 R331.2 U56.3(A2)
EEPROM_WP: R329.2 U56.7(WP)
EMMC_RSTN: R288.1 U48.4(Y) U51.K5(RST_N)
EXP_BRD_DET_INTN: R283.1 U46.13(I\N\T\)
EXP_PCIE_DET_INTN: R27.1 U7.13(I\N\T\) U34.T1(MCU_OSPI1_CLK)
FB: C48.2 C49.2 R53.1 R54.2 U14.8(FB)
FT4232_DO: R407.2 R408.1 U79.4(DO)
FT4232_EECLK: R413.1 U73.62(EECLK) U79.2(CLK)
FT4232_EECS: R416.1 U73.63(EECS) U79.1(CS)
FT4232_EEDATA: R407.1 U73.61(EEDATA) U79.3(DI)
FT4232_MCU_UART1_CTS_3V3: U12.12(2B2) U73.28(BDBUS2)
FT4232_MCU_UART1_RTS_3V3: U12.14(1B2) U73.29(BDBUS3)
FT4232_MCU_UART1_RX_3V3: U12.13(2B1) U73.26(BDBUS0)
FT4232_MCU_UART1_TX_3V3: U12.15(1B1) U73.27(BDBUS1)
FT4232_REF: R388.2 U73.6(REF)
FT4232_RESET: C319.2 R381.1 U73.14(R\E\S\E\T\)
FT4232_UART0_CTS_3V3: U19.12(2B2) U73.18(ADBUS2)
FT4232_UART0_RTS_3V3: U19.14(1B2) U73.19(ADBUS3)
FT4232_UART0_RX_3V3: U19.13(2B1) U73.16(ADBUS0)
FT4232_UART0_TX_3V3: U19.15(1B1) U73.17(ADBUS1)
FT4232_UART1_CTS_1V8: U26.14(ID0) U85.9(2A2)
FT4232_UART1_CTS_3V3: U73.53(DDBUS2) U85.12(2B2)
FT4232_UART1_RTS_1V8: U26.11(IC0) U85.7(1A2)
FT4232_UART1_RTS_3V3: U73.54(DDBUS3) U85.14(1B2)
FT4232_UART1_RX_1V8: U26.5(IB0) U85.8(2A1)
FT4232_UART1_RX_3V3: U73.48(DDBUS0) U85.13(2B1)
FT4232_UART1_TX_1V8: U26.2(IA0) U85.6(1A1)
FT4232_UART1_TX_3V3: U73.52(DDBUS1) U85.15(1B1)
FT4232_USB_DM: J42.2(D-) U15.5(IO4) U73.7(DM)
FT4232_USB_DP: J42.3(D+) U15.4(IO3) U73.8(DP)
FT4232_USB_VBUS: C327.2 C329.2 D7.1(K) J42.1(VBUS) U15.6(VCC) U76.4(EN) U76.6(IN)
FT4232_WKUP_UART0_CTS_3V3: U21.12(2B2) U73.40(CDBUS2)
FT4232_WKUP_UART0_RTS_3V3: U21.14(1B2) U73.41(CDBUS3)
FT4232_WKUP_UART0_RX_3V3: U21.13(2B1) U73.38(CDBUS0)
FT4232_WKUP_UART0_TX_3V3: U21.15(1B1) U73.39(CDBUS1)
GATE: C291.1 Q2.1(G) U66.10(GATE)
GP1_TOUCH_EVT: J35.38 J36.38 U110.13(P13)
GPIO_CSI_RESETN: R658.1 U108.1(A) U110.8(P07)
GPIO_EMMC_RSTN: R303.1 U48.1(A) U110.1(P00)
GPIO_MCU_RGMII_RSTN: R409.2 R412.1 U82.1(A) U110.5(P04)
GPIO_OSPI_RSTN: R390.1 U74.1(A) U110.2(P01)
GPIO_PRG2_RGMII_RESETN: R506.1 R513.2 U86.1(A) U110.4(P03)
GPIO_SGMII_PHY_INT: J5.46 R58.1 R729.2
GPIO_SGMII_PHY_RST: J5.6 U110.6(P05)
GPIO_SPI0_RSTN: R159.1 U28.1(A) U110.3(P02)
HB: C66.1 U14.18(HB)
HDMI_GPMC_BRD_DET: J35.18 J36.18 R235.1 U46.7(P3)
HDR_MCU_UART1_CTS_1V8: U6.9(2A2) U8.1(A)
HDR_MCU_UART1_CTS_3V3: J30.6 U6.12(2B2)
HDR_MCU_UART1_RTS_3V3: J30.2 U6.14(1B2)
HDR_MCU_UART1_RX_1V8: U6.8(2A1) U65.1(A)
HDR_MCU_UART1_RX_3V3: J30.4 U6.13(2B1)
HDR_MCU_UART1_TX_3V3: J30.5 U6.15(1B1)
HDR_WKUP_UART0_CTS_3V3: J11.6 U23.1(A)
HDR_WKUP_UART0_RX_3V3: J11.4 U83.1(A)
HS: C66.2 D8.1(CATHODE) D9.1(CATHODE) L1.1 U14.20(HS) U18.1(S1) U18.2(S2) U18.3(S3)
HS_L: D3.2(ANODE) D5.2(ANODE) L1.2 U13.5(D1) U13.6(D2) U13.7(D3) U13.8(D4)
IFORCE: TP62.1(TP) U34.B28(IFORCE)
IN_SEL0: R193.1 R197.2 U32.30(IN_SEL0)
IN_SEL1: R187.2 R189.1 U32.29(IN_SEL1)
INA_ALERT: J21.4 R14.2 R18.2 R147.1 R148.2 R358.2 R363.2 R364.2 R365.2 R591.2
JTAG_CTI_RTCK: J13.9 R565.1
JTAG_CTI_TCK: J13.11 R227.1 R229.1 U41.2(B) U92.2(B)
JTAG_DIR: R254.2 U43.2(1DIR) U43.3(2DIR)
JTAG_EMU0: J13.13 R504.2 U37.8(B1) U87.8(B1)
JTAG_EMU1: J13.14 R521.2 U37.1(B2) U87.1(B2)
JTAG_EMU_RSTN: J13.15 R213.2 R472.1 U50.6(C)
JTAG_MIPI_EMU0_1V8: J32.38 R217.2 U37.5(A1)
JTAG_MIPI_EMU1_1V8: J32.40 R214.2 U37.4(A2)
JTAG_MIPI_RTCK: J32.7 R223.1
JTAG_MIPI_TCK: J32.3 R221.1 R222.1 U39.2(B) U90.2(B)
JTAG_MUX_SEL: J43.2 U42.1(S)
JTAG_TCK: U42.4(1A) U43.12(1B2)
JTAG_TDI: J13.3 R196.2 U43.13(1B1)
JTAG_TDIS: J13.4 R195.2
JTAG_TDO: J13.7 R202.1 U101.7(B1)
JTAG_TMS: J13.1 R470.1 U43.11(2B1)
JTAG_TRST#: J13.2 R475.1 U43.10(2B2)
LCD_BRD_DET: J38.40 R237.1 U46.5(P1)
LCD_BRD_TOUCH_INT: J38.29 R36.1 U7.7(P3)
LCD_BRD_TOUCH_RESETN: R686.1 U110.11(P11) U113.1(A)
LCD_DISPLAY_EN: J38.30 R687.2 U110.10(P10)
LCD_SHIELD: FL15.2 J38.SH1 J38.SH2 J38.SH3 J38.SH4
LCD_TOUCH_RESETN: J38.39 R698.1 U113.4(Y)
LED1: LD11.1 U84.3(DRAIN0)
LED2: LD12.1 U84.4(DRAIN1)
LED3: LD13.1 U84.5(DRAIN2)
LED4: LD14.1 U84.6(DRAIN3)
LED5: LD10.1 U84.11(DRAIN4)
LED6: LD15.1 U84.12(DRAIN5)
LED7: LD9.1 U84.13(DRAIN6)
LED8: LD8.1 U84.14(DRAIN7)
LM5140_COMP1: C308.1 R375.2 U75.29(COMP1)
LM5140_COMP2: C350.1 R399.2 U75.2(COMP2)
MAIN: F1.1 J1.1 J2.1 J2.2
MAIN_UART1_SEL: R134.2 U26.1(S) U110.15(P15)
MCASP1_ACLKR: R577.2 U100.7(A6)
MCASP1_ACLKR_3V3: J35.115 U100.14(B6)
MCASP1_ACLKX: R575.2 U100.4(A3)
MCASP1_ACLKX_3V3: J35.109 U100.17(B3)
MCASP1_AFSR: R573.2 U100.8(A7)
MCASP1_AFSR_3V3: J35.117 U100.13(B7)
MCASP1_AFSX: R579.2 U100.1(A1)
MCASP1_AFSX_3V3: J35.105 U100.20(B1)
MCASP1_AHCLKR: R569.2 U100.9(A8)
MCASP1_AHCLKR_3V3: J35.119 U100.12(B8)
MCASP1_AHCLKX: R590.2 U100.5(A4)
MCASP1_AHCLKX_3V3: J35.111 U100.16(B4)
MCASP1_AXR0: R571.2 U100.6(A5)
MCASP1_AXR0_3V3: J35.113 U100.15(B5)
MCASP1_AXR1: R588.2 U100.3(A2)
MCASP1_AXR1_3V3: J35.107 U100.18(B2)
MCU_ADC0_CH0: J10.4 U34.K5(MCU_ADC0_CH0)
MCU_ADC0_CH1: J10.5 U34.J3(MCU_ADC0_CH1)
MCU_ADC0_CH2: J10.11 U34.J1(MCU_ADC0_CH2)
MCU_ADC0_CH3: J10.2 U34.J5(MCU_ADC0_CH3)
MCU_ADC0_CH4: J10.9 U34.K4(MCU_ADC0_CH4)
MCU_ADC0_CH5: J10.15 U34.J4(MCU_ADC0_CH5)
MCU_ADC0_CH6: J10.6 U34.J2(MCU_ADC0_CH6)
MCU_ADC0_CH7: J10.3 U34.J6(MCU_ADC0_CH7)
MCU_ADC0_REFN: C74.1 J10.12 U34.K2(MCU_ADC0_REFN)
MCU_ADC0_REFP: C73.1 J10.10 U34.K3(MCU_ADC0_REFP)
MCU_ADC1_AIN1: TP34.1(TP) U34.G6(MCU_ADC1_CH1)
MCU_ADC1_AIN2: TP32.1(TP) U34.G4(MCU_ADC1_CH2)
MCU_ADC1_AIN3: TP31.1(TP) U34.H5(MCU_ADC1_CH3)
MCU_ADC1_AIN4: TP35.1(TP) U34.F5(MCU_ADC1_CH4)
MCU_ADC1_AIN5: TP30.1(TP) U34.G5(MCU_ADC1_CH5)
MCU_ADC1_AIN6: TP36.1(TP) U34.G3(MCU_ADC1_CH6)
MCU_ADC1_AIN7: TP37.1(TP) U34.H4(MCU_ADC1_CH7)
MCU_ADC1_CH8: J10.17 U34.F4(MCU_ADC1_CH0)
MCU_ADC1_REFN: C76.1 J10.18 U34.H3(MCU_ADC1_REFN)
MCU_ADC1_REFP: C75.1 J10.16 U34.H2(MCU_ADC1_REFP)
MCU_BOOTMODE0: R225.2 R228.1 R231.2 U34.AF4(WKUP_GPIO0_0)
MCU_BOOTMODE1: R540.2 R546.1 R548.2 U34.AF3(WKUP_GPIO0_1)
MCU_BOOTMODE2: R230.1 R232.2 U34.AE3(WKUP_GPIO0_2)
MCU_BOOTMODE3: R301.1 SW4.1(A1) U34.AD1(WKUP_GPIO0_3)
MCU_BOOTMODE9: R83.1 R84.2 U34.AB4(WKUP_GPIO0_9)
MCU_BYP_POR: J8.2 U34.V5(MCU_BYP_POR)
MCU_CLKOUT: R129.2 R185.2 R190.1 U32.13(PRI_INP)
MCU_EARTH: C405.1 J12.15(SH1) J12.16(SH2) R456.1
MCU_ETH1_CLK_OUT: TP14.1(TP) U22.18(CLK_OUT)
MCU_ETH1_INTN: R100.1 U22.44(INT/PWDN) U96.5(A1)
MCU_ETH1_INTN_SDIO: R600.1 U34.C24(MMC1_SDWP) U96.8(B1)
MCU_ETH1_RBIAS: R135.1 U22.12(RBIAS)
MCU_ETH1_RESETN: R417.1 U22.43(RESET_N) U82.4(Y)
MCU_ETH_D0M: J12.10(MX0-) U22.2(TD_M_A)
MCU_ETH_D0P: J12.9(MX0+) U22.1(TD_P_A)
MCU_ETH_D1M: J12.8(MX1-) U22.5(TD_M_B)
MCU_ETH_D1P: J12.7(MX1+) U22.4(TD_P_B)
MCU_ETH_D2M: J12.6(MX2-) U22.8(TD_M_C)
MCU_ETH_D2P: J12.5(MX2+) U22.7(TD_P_C)
MCU_ETH_D3M: J12.4(MX3-) U22.11(TD_M_D)
MCU_ETH_D3P: J12.3(MX3+) U22.10(TD_P_D)
MCU_ETH_GPIO_0: R72.2 R96.1 R97.2 U22.39(GPIO_0)
MCU_ETH_GPIO_1: R94.2 R95.1 U22.40(GPIO_1)
MCU_ETH_LED1: J12.12 Q9.3(D)
MCU_ETH_LED2: J12.13 Q3.3(D) R79.1
MCU_ETH_LED3: J12.14 Q4.3(D) R78.1
MCU_ETH_LED_1000: R73.2 R90.2 R91.1 U22.46(LED_1)
MCU_ETH_LED_ACTN: R92.1 R93.2 R451.2 U22.45(LED_2)
MCU_MCAN0_RX: J16.32 U34.W2(MCU_MCAN0_RX)
MCU_MCAN0_TX: J16.30 R131.1
MCU_MCAN0_TX_R: R131.2 U34.W1(MCU_MCAN0_TX)
MCU_MCAN1_RX: J16.36 U34.AD3(WKUP_GPIO0_5)
MCU_MCAN1_TX: J16.34 R128.2
MCU_MCAN1_TX/BOOTMODE4: R128.1 R305.1 SW4.2(A2) U34.AC3(WKUP_GPIO0_4)
MCU_MDC_RGMII: R132.2 U34.L1(MCU_MDIO_CLK)
MCU_MDC_RGMII_1V8: R149.2 U22.16(MDC) U29.8(A1)
MCU_MDC_RGMII_3V3: R132.1 R175.2 U29.5(B1)
MCU_MDIO_1V8: R156.2 U22.17(MDIO) U30.5(A1)
MCU_MDIO_3V3: R174.2 U30.8(B1) U34.L4(MCU_MDIO_DATA)
MCU_PORZ_OUT: R415.1 TP85.1(TP) U34.V2(MCU_PORZ_OUT) U82.2(B)
MCU_RESETSTATZ: TP38.1(TP) U34.V3(MCU_RESETSTATZ)
MCU_RESETZ: TP47.1(TP) U34.W4(MCU_RESETZ)
MCU_RGMII1_CLKIN: R203.2 U22.15(XI)
MCU_RGMII1_RD0: R118.1 U34.L6(MCU_RGMII1_RD0)
MCU_RGMII1_RD0_R: R118.2 R119.2 R122.1 U22.33(RX_D0)
MCU_RGMII1_RD1: R114.1 U34.M6(MCU_RGMII1_RD1)
MCU_RGMII1_RD1_R: R114.2 U22.34(RX_D1)
MCU_RGMII1_RD2: R111.1 U34.L5(MCU_RGMII1_RD2)
MCU_RGMII1_RD2_R: R111.2 R112.1 R115.2 U22.35(RX_D2)
MCU_RGMII1_RD3: R102.1 U34.L2(MCU_RGMII1_RD3)
MCU_RGMII1_RD3_R: R102.2 U22.36(RX_D3)
MCU_RGMII1_RX_CTL: R101.1 U34.N5(MCU_RGMII1_RX_CTL)
MCU_RGMII1_RX_CTL_R: R98.1 R99.1 R101.2 U22.38(RX_DV/RX_CTRL)
MCU_RGMII1_RXC: R121.1 U34.M1(MCU_RGMII1_RXC)
MCU_RGMII1_RXC_R: R121.2 U22.32(RX_CLK)
MCU_RGMII1_TD0: RA7.4 U22.28(TX_D0)
MCU_RGMII1_TD0_R: RA7.5 U34.M5(MCU_RGMII1_TD0)
MCU_RGMII1_TD1: RA7.3 U22.27(TX_D1)
MCU_RGMII1_TD1_R: RA7.6 U34.M4(MCU_RGMII1_TD1)
MCU_RGMII1_TD2: RA7.2 U22.26(TX_D2)
MCU_RGMII1_TD2_R: RA7.7 U34.M3(MCU_RGMII1_TD2)
MCU_RGMII1_TD3: RA7.1 U22.25(TX_D3)
MCU_RGMII1_TD3_R: RA7.8 U34.M2(MCU_RGMII1_TD3)
MCU_RGMII1_TX_CTL: R439.2 U22.37(TX_EN/TX_CTRL)
MCU_RGMII1_TX_CTL_R: R439.1 U34.N4(MCU_RGMII1_TX_CTL)
MCU_RGMII1_TXC: R438.2 U22.29(GTX_CLK)
MCU_RGMII1_TXC_R: R438.1 U34.N1(MCU_RGMII1_TXC)
MCU_RTCK: J34.9 R617.2
MCU_SAFETY_ERRORZ: TP40.1(TP) U34.W3(MCU_SAFETY_ERRORN)
MCU_SPI0_CLK: R432.1 U111.16(B4)
MCU_SPI0_CLK/BOOTMODE6: R432.2 R441.1 R442.2 U34.Y1(MCU_SPI0_CLK)
MCU_SPI0_CS0: U34.Y4(MCU_SPI0_CS0) U111.15(B5)
MCU_SPI0_D0/BOOTMODE7: R668.1 R669.2 U34.Y3(MCU_SPI0_D0) U111.17(B3)
MCU_SYSCLKOUT: TP43.1(TP) U34.AB3(WKUP_GPIO0_10)
MCU_TCK: J34.11 R610.2
MCU_TCLK: R610.1 R615.2 R617.1
MCU_TDI: J34.3 R619.2
MCU_TDIS: J34.4 R639.2
MCU_TDO: J34.7 R618.2
MCU_TEST_POR: R428.1 U34.V4(MCU_TEST_POR)
MCU_TMS: J34.1 R620.2
MCU_TRST#: J34.2 R640.2 R641.1
MCU_UART_SEL: R32.1 U8.6(A\/B) U65.6(A\/B) U109.5(B1)
MCU_UART_SEL_IO_EXP: U109.8(A1) U110.16(P16)
MCU_XDS110_TCK: R609.1 R615.1 U106.35(PA2/SSI0CLK)
MCU_XDS110_TDI: R612.1 R619.1 U106.38(PA5/SSI0XDAT1)
MCU_XDS110_TDO: R611.1 R618.1 U106.37(PA4/SSI0XDAT0)
MCU_XDS110_TMS: R613.1 R620.1 U106.36(PA3/SSI0FSS)
MCU_XDS110_TRST#: R640.1 R646.1 U106.40(PA6)
MIC-GATE: Q1.1(G) R338.1
MIPI_TCK: R543.1 U42.2(1B1)
MIPI_TDI_R: J32.5 R196.1
MIPI_TDO_R: J32.4 R202.2
MIPI_TMS_R: J32.2 R470.2
MIPI_TRC_CLK: J32.13 RA9.12
MIPI_TRC_CTL: J32.17 RA9.13
MIPI_TRC_DAT00: J32.19 RA9.11
MIPI_TRC_DAT01: J32.21 RA9.10
MIPI_TRC_DAT02: J32.23 RA9.9
MIPI_TRC_DAT03: J32.25 RA10.16
MIPI_TRC_DAT04: J32.27 RA10.15
MIPI_TRC_DAT05: J32.29 RA10.14
MIPI_TRC_DAT06: J32.31 RA10.13
MIPI_TRC_DAT07: J32.33 RA10.12
MIPI_TRC_DAT08: J32.35 RA10.11
MIPI_TRC_DAT09: J32.37 RA10.10
MIPI_TRC_DAT10: J32.39 RA10.9
MIPI_TRC_DAT11: J32.41 RA11.16
MIPI_TRC_DAT12: J32.43 RA11.15
MIPI_TRC_DAT13: J32.45 RA11.14
MIPI_TRC_DAT14: J32.47 RA11.13
MIPI_TRC_DAT15: J32.49 RA11.12
MIPI_TRC_DAT16: J32.51 RA11.11
MIPI_TRC_DAT17: J32.53 RA11.10
MIPI_TRC_DAT18: J32.55 RA11.9
MIPI_TRC_DAT19: J32.18 RA9.16
MIPI_TRC_DAT20: J32.20 RA9.15
MIPI_TRC_DAT21: J32.22 RA9.14
MIPI_TRC_DAT22: J32.24 R463.2
MIPI_TRC_DAT23: J32.26 R466.2
MIPI_TRST#_R: J32.8 R475.2
MMC0_CALPAD: R535.1 U34.D24(MMC0_CALPAD)
MMC0_CLK: RA14.14 U51.M6(CLK)
MMC0_CMD: R625.2 RA14.12 U51.M5(CMD)
MMC0_DAT0: R264.2 RA14.10 U51.A3(DAT0)
MMC0_DAT1: R265.2 RA14.16 U51.A4(DAT1)
MMC0_DAT2: R267.2 RA14.15 U51.A5(DAT2)
MMC0_DAT3: R262.2 R533.2 U51.B2(DAT3)
MMC0_DAT4: R263.2 RA14.11 U51.B3(DAT4)
MMC0_DAT5: R266.2 R532.2 U51.B4(DAT5)
MMC0_DAT6: R268.2 RA14.9 U51.B5(DAT6)
MMC0_DAT7: R269.2 RA14.13 U51.B6(DAT7)
MMC0_DS: R253.2 U51.H5(DS)
MMC0_VCTRL_TP: TP59.1(TP) U34.D23(MMC0_VCTRL_TP)
MMC1_CALPAD: R536.1 U34.F23(MMC1_CALPAD)
MMC1_CLK: J17.5(CLK) R534.1 U47.8(IO6)
MMC1_CLK_R: R534.2 U34.C27(MMC1_CLK)
MMC1_CMD: J17.2(CMD) R616.2 U34.C28(MMC1_CMD) U47.1(IO1)
MMC1_D0: J17.7(DAT0) R607.2 U34.D28(MMC1_DAT0) U47.7(IO5)
MMC1_D1: J17.8(DAT1) R606.2 U34.E27(MMC1_DAT1) U47.6(IO4)
MMC1_D2: J17.9(DAT2) R608.2 U34.D26(MMC1_DAT2) U47.3(IO3)
MMC1_D3: J17.1(CD/DAT3) R614.2 U34.D27(MMC1_DAT3) U47.2(IO2)
MMC1_SD_EN: R735.2 U7.9(P4) U115.4(EN)
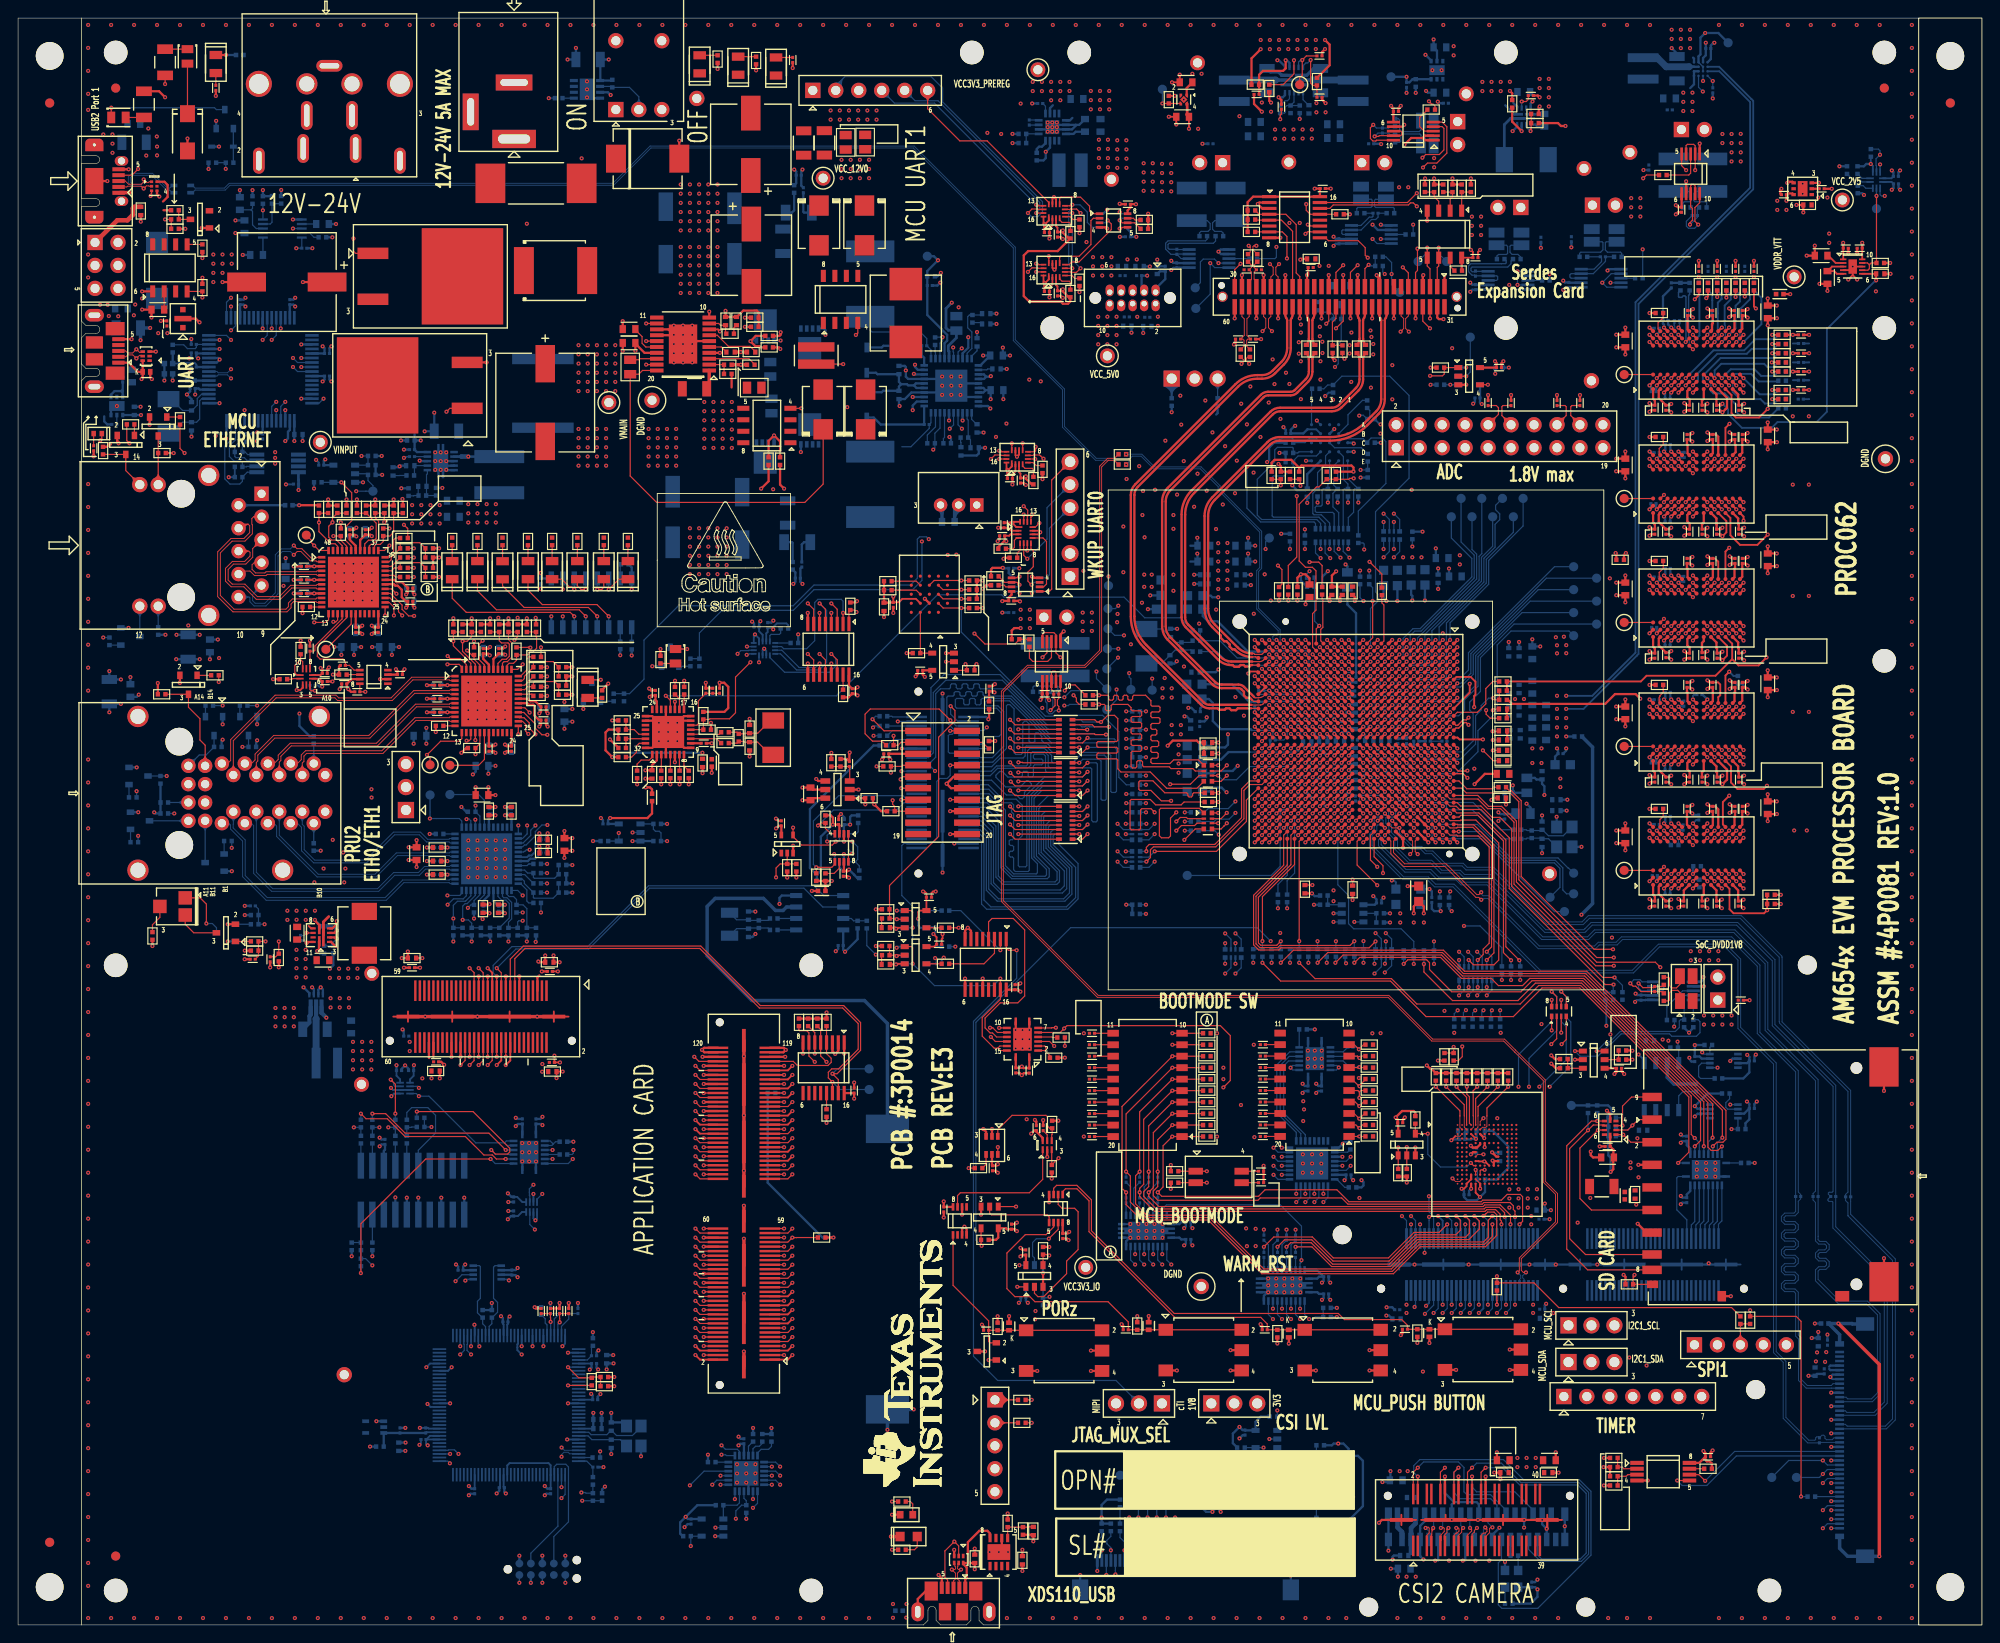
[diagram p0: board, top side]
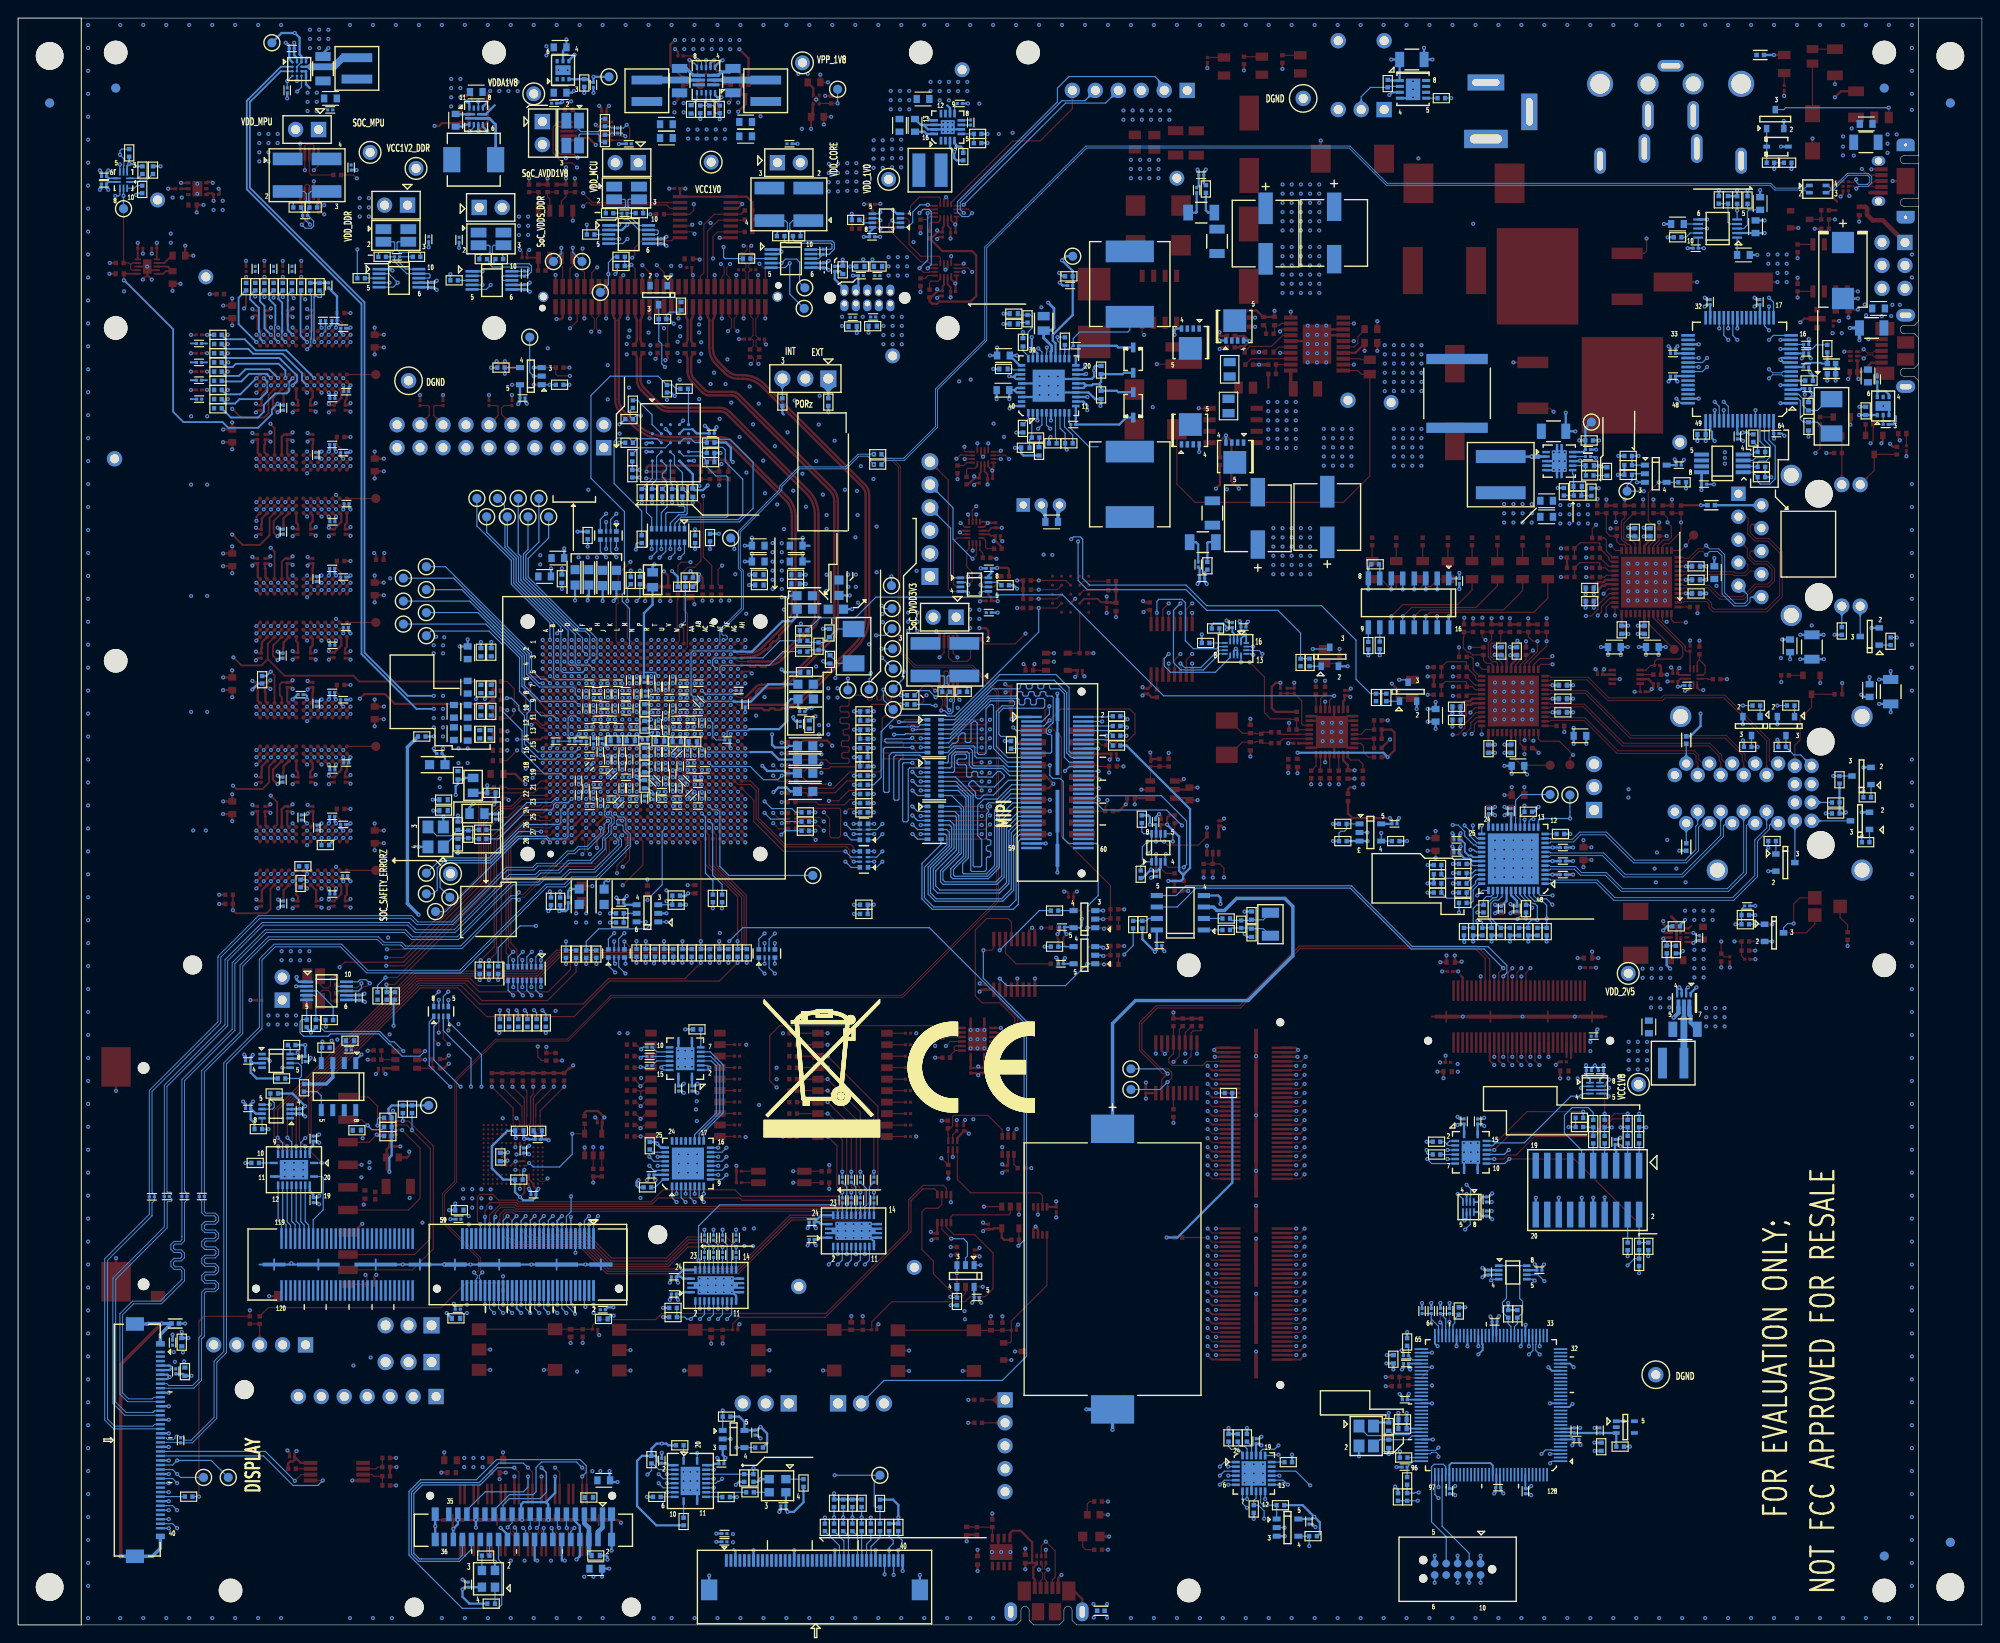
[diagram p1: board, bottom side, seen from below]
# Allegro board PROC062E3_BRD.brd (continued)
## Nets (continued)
MMC1_SDCD: J17.G1 R310.2 U34.B24(MMC1_SDCD)
MMC1_VCTRL_TP: TP61.1(TP) U34.E23(MMC1_VCTRL_TP)
OLDI0_A0N: J38.8 R599.2 U34.J28(OLDI0_A0N)
OLDI0_A0P: J38.9 R599.1 U34.K28(OLDI0_A0P)
OLDI0_A1N: J38.11 R597.2 U34.L27(OLDI0_A1N)
OLDI0_A1P: J38.12 R597.1 U34.K27(OLDI0_A1P)
OLDI0_A2N: J38.14 R595.2 U34.K24(OLDI0_A2N)
OLDI0_A2P: J38.15 R595.1 U34.J24(OLDI0_A2P)
OLDI0_A3N: J38.17 R594.2 U34.J26(OLDI0_A3N)
OLDI0_A3P: J38.18 R594.1 U34.K26(OLDI0_A3P)
OLDI0_CLKN: J38.20 R598.2 U34.L25(OLDI0_CLKN)
OLDI0_CLKP: J38.21 R598.1 U34.K25(OLDI0_CLKP)
OSC0: C652.2 U106.88(OSC0) Y6.1
OSC1: C659.2 U106.89(OSC1) Y6.3
OSC1_XI: R507.1 U34.C22(OSC1_XI)
OSC1_XOUT: R511.1 U34.E22(OSC1_XO)
OSPI_CLK: R398.1 R430.2 R706.1
OSPI_CS: R403.1 R429.2 U77.C2(S#)
OSPI_DQ0: R424.1 RA8.4 U77.D3(DQ0)
OSPI_DQ1: R421.1 RA8.7 U77.D2(DQ1)
OSPI_DQ2: R402.1 RA8.1 U77.C4(DQ2/W#)
OSPI_DQ3: R411.1 RA8.3 U77.D4(DQ3)
OSPI_DQ4: R406.1 RA8.2 U77.D5(DQ4)
OSPI_DQ5: R423.1 RA8.5 U77.E3(DQ5)
OSPI_DQ6: R422.1 RA8.6 U77.E2(DQ6)
OSPI_DQ7: R420.1 RA8.8 U77.E1(DQ7)
OSPI_DQS: R410.2 R732.1 U34.U2(MCU_OSPI0_DQS)
OSPI_INT: R33.1 R745.1 U34.N2(MCU_OSPI1_CSN0)
OSPI_LBCLKO_GPIO: R705.2 U34.U1(MCU_OSPI0_LBCLKO)
OSPI_RSTN: R385.1 U74.4(Y) U77.A4(RESET#)
PCIE0_PRSNTN: J5.21 R26.1 U7.4(P0)
PCIE1_ATEST: TP51.1(TP) U34.AC13(PCIE1ATEST)
PCIE1_PRSNTN: J5.22 R29.1 U7.5(P1)
PCIE1_RESREF: R497.1 U34.AC14(PCIE1REFRES)
PCIE1_SGMII1_RXN1: J5.52 U34.AG9(PCIE1_RXN0)
PCIE1_SGMII1_RXP1: J5.53 U34.AH10(PCIE1_RXP0)
PCIE1_SGMII1_TXN1: C58.2 J5.50
PCIE1_SGMII1_TXN1_C: C58.1 U34.AH9(PCIE1_TXN0)
PCIE1_SGMII1_TXP1: C59.2 J5.49
PCIE1_SGMII1_TXP1_C: C59.1 U34.AG8(PCIE1_TXP0)
PCIE_GPIO_RESET_IN: J5.12 R705.1 R743.1
PGD: R346.1 R347.1 U66.8(NPGD)
PMIC_POWER-EN0: TP52.1(TP) U34.Y5(PMIC_POWER_EN0)
PMIC_POWER-EN1: TP49.1(TP) U34.AA5(PMIC_POWER_EN1)
PORZ_OUT: J5.30 J16.38 J35.16 J36.16 R304.1 TP86.1(TP) U17.2(B) U28.2(B) U34.C19(PORZ_OUT) U48.2(B) U74.2(B) U86.2(B) U108.2(B) U113.2(B)
PRG0_MDIODATA: J18.53 R307.1 U34.AE26(PRG0_MDIO0_MDIO)
PRG0_MDIOMDCLK: J18.59 U34.AE28(PRG0_MDIO0_MDC)
PRG0_PRU0_GPO11_R: R568.1 U34.AB25(PRG0_PRU0GPO11)
PRG0_PRU0_GPO12_R: RA15.5 U34.AD27(PRG0_PRU0GPO12)
PRG0_PRU0_GPO13_R: RA15.6 U34.AC26(PRG0_PRU0GPO13)
PRG0_PRU0_GPO14_R: RA15.7 U34.AD26(PRG0_PRU0GPO14)
PRG0_PRU0_GPO15_R: RA15.8 U34.AA24(PRG0_PRU0GPO15)
PRG0_PRU0GPO0: J18.35 U34.V24(PRG0_PRU0GPO0)
PRG0_PRU0GPO1: J18.39 U34.W25(PRG0_PRU0GPO1)
PRG0_PRU0GPO2: J18.33 U34.W24(PRG0_PRU0GPO2)
PRG0_PRU0GPO3: J18.23 U34.AA27(PRG0_PRU0GPO3)
PRG0_PRU0GPO4: J18.31 U34.Y24(PRG0_PRU0GPO4)
PRG0_PRU0GPO5: J18.37 U34.V28(PRG0_PRU0GPO5)
PRG0_PRU0GPO6: J18.27 U34.Y25(PRG0_PRU0GPO6)
PRG0_PRU0GPO7: J18.16 U34.U27(PRG0_PRU0GPO7)
PRG0_PRU0GPO8: J18.20 U34.V27(PRG0_PRU0GPO8)
PRG0_PRU0GPO9: J18.43 U34.V26(PRG0_PRU0GPO9)
PRG0_PRU0GPO10: J18.18 U34.U25(PRG0_PRU0GPO10)
PRG0_PRU0GPO11: J18.13 R568.2
PRG0_PRU0GPO12: J18.15 RA15.4
PRG0_PRU0GPO13: J18.9 RA15.3
PRG0_PRU0GPO14: J18.11 RA15.2
PRG0_PRU0GPO15: J18.7 RA15.1
PRG0_PRU0GPO16: R569.1 R570.1 U34.AD28(PRG0_PRU0GPO16)
PRG0_PRU0GPO17: R589.1 R590.1 U34.U26(PRG0_PRU0GPO17)
PRG0_PRU0GPO18: J18.14 U34.V25(PRG0_PRU0GPO18)
PRG0_PRU0GPO19: J18.12 U34.U24(PRG0_PRU0GPO19)
PRG0_PRU1GPO0: R575.1 R576.1 U34.AB28(PRG0_PRU1GPO0)
PRG0_PRU1GPO1: R579.1 R580.1 U34.AC28(PRG0_PRU1GPO1)
PRG0_PRU1GPO2: R577.1 R578.1 U34.AC27(PRG0_PRU1GPO2)
PRG0_PRU1GPO3: R573.1 R574.1 U34.AB26(PRG0_PRU1GPO3)
PRG0_PRU1GPO4: R571.1 R572.1 U34.AA25(PRG0_PRU1GPO4)
PRG0_PRU1GPO5: R587.1 R588.1 U34.U23(PRG0_PRU1GPO5)
PRG0_PRU1GPO6: J18.54 U34.AB27(PRG0_PRU1GPO6)
PRG0_PRU1GPO7: J18.41 U34.W28(PRG0_PRU1GPO7)
PRG0_PRU1GPO8: J18.22 U34.W27(PRG0_PRU1GPO8)
PRG0_PRU1GPO9: J18.45 U34.Y28(PRG0_PRU1GPO9)
PRG0_PRU1GPO10: J18.49 U34.AA28(PRG0_PRU1GPO10)
PRG0_PRU1GPO11: J18.48 R527.2
PRG0_PRU1GPO11_R: R527.1 U34.AB24(PRG0_PRU1GPO11)
PRG0_PRU1GPO12: J18.50 R528.2
PRG0_PRU1GPO12_R: R528.1 U34.AC25(PRG0_PRU1_GPO12)
PRG0_PRU1GPO13: J18.46 RA16.4
PRG0_PRU1GPO13_R: RA16.5 U34.AD25(PRG0_PRU1GPO13)
PRG0_PRU1GPO14: J18.44 RA16.3
PRG0_PRU1GPO14_R: RA16.6 U34.AD24(PRG0_PRU1GPO14)
PRG0_PRU1GPO15: J18.42 RA16.2
PRG0_PRU1GPO15_R: RA16.7 U34.AE27(PRG0_PRU1GPO15)
PRG0_PRU1GPO16: J18.38 RA16.1
PRG0_PRU1GPO16_R: RA16.8 U34.AC24(PRG0_PRU1GPO16)
PRG0_PRU1GPO17: J18.24 U34.Y27(PRG0_PRU1GPO17)
PRG0_PRU1GPO18: J18.51 U34.Y26(PRG0_PRU1GPO18)
PRG0_PRU1GPO19: J18.47 U34.W26(PRG0_PRU1GPO19)
PRG0_RGMII1_ETH1_CLK: J18.4 R204.2
PRG0_RGMII2_ETH2_CLK: J18.106 R205.2
PRG1_MDIODATA: J18.99 R605.1 U34.AD18(PRG1_MDIO0_MDIO)
PRG1_MDIOMDCLK: J18.95 U34.AH18(PRG1_MDIO0_MDC)
PRG1_PRU0_GPO11_R: R508.1 U34.AF21(PRG1_PRU0GPO11)
PRG1_PRU0_GPO12_R: RA13.5 U34.AH20(PRG1_PRU0GPO12)
PRG1_PRU0_GPO13_R: RA13.6 U34.AH21(PRG1_PRU0GPO13)
PRG1_PRU0_GPO14_R: RA13.7 U34.AG20(PRG1_PRU0GPO14)
PRG1_PRU0_GPO15_R: RA13.8 U34.AD19(PRG1_PRU0GPO15)
PRG1_PRU0GPO0: J18.88 U34.AE22(PRG1_PRU0GPO0)
PRG1_PRU0GPO1: J18.76 U34.AG24(PRG1_PRU0GPO1)
PRG1_PRU0GPO2: J18.80 U34.AF23(PRG1_PRU0GPO2)
PRG1_PRU0GPO3: J18.90 U34.AD21(PRG1_PRU0GPO3)
PRG1_PRU0GPO4: J18.78 U34.AG23(PRG1_PRU0GPO4)
PRG1_PRU0GPO5: J18.60 U34.AF27(PRG1_PRU0GPO5)
PRG1_PRU0GPO6: J18.84 U34.AF22(PRG1_PRU0GPO6)
PRG1_PRU0GPO7: J18.66 U34.AG27(PRG1_PRU0GPO7)
PRG1_PRU0GPO8: J18.58 U34.AF28(PRG1_PRU0GPO8)
PRG1_PRU0GPO9: J18.62 U34.AF26(PRG1_PRU0GPO9)
PRG1_PRU0GPO10: J18.74 U34.AH25(PRG1_PRU0GPO10)
PRG1_PRU0GPO11: J18.98 R508.2
PRG1_PRU0GPO12: J18.110 RA13.4
PRG1_PRU0GPO13: J18.114 RA13.3
PRG1_PRU0GPO14: J18.100 RA13.2
PRG1_PRU0GPO15: J18.102 RA13.1
PRG1_PRU0GPO16: J18.94 U34.AD20(PRG1_PRU0GPO16)
PRG1_PRU0GPO17: J18.70 U34.AH26(PRG1_PRU0GPO17)
PRG1_PRU0GPO18: J18.72 U34.AG25(PRG1_PRU0GPO18)
PRG1_PRU0GPO19: J18.68 U34.AG26(PRG1_PRU0GPO19)
PRG1_PRU1GPO0: J18.63 U34.AH24(PRG1_PRU1GPO0)
PRG1_PRU1GPO1: J18.67 U34.AH23(PRG1_PRU1GPO1)
PRG1_PRU1GPO2: J18.77 U34.AG21(PRG1_PRU1GPO2)
PRG1_PRU1GPO3: J18.75 U34.AH22(PRG1_PRU1GPO3)
PRG1_PRU1GPO4: J18.65 U34.AE21(PRG1_PRU1GPO4)
PRG1_PRU1GPO5: J18.55 U34.AC22(PRG1_PRU1GPO5)
PRG1_PRU1GPO6: J18.71 U34.AG22(PRG1_PRU1GPO6)
PRG1_PRU1GPO8: J18.57 U34.AE24(PRG1_PRU1GPO8)
PRG1_PRU1GPO9: J18.64 U34.AF25(PRG1_PRU1GPO9)
PRG1_PRU1GPO10: J18.61 U34.AF24(PRG1_PRU1GPO10)
PRG1_PRU1GPO11: J18.81 R499.2
PRG1_PRU1GPO11_R: R499.1 U34.AC20(PRG1_PRU1GPO11)
PRG1_PRU1GPO12: J18.79 R505.2
PRG1_PRU1GPO12_R: R505.1 U34.AE20(PRG1_PRU1GPO12)
PRG1_PRU1GPO13: J18.91 RA12.4
PRG1_PRU1GPO13_R: RA12.5 U34.AF19(PRG1_PRU1GPO13)
PRG1_PRU1GPO14: J18.93 RA12.3
PRG1_PRU1GPO14_R: RA12.6 U34.AH19(PRG1_PRU1GPO14)
PRG1_PRU1GPO15: J18.83 RA12.2
PRG1_PRU1GPO15_R: RA12.7 U34.AG19(PRG1_PRU1GPO15)
PRG1_PRU1GPO16: J18.87 RA12.1
PRG1_PRU1GPO16_R: RA12.8 U34.AE19(PRG1_PRU1GPO16)
PRG1_RGMII1_ETH1_CLK: J18.3 R206.2
PRG1_RGMII2_ETH2_CLK: J18.103 R207.2
PRG2_ETH1_D0M: J14.A2(TD1-_1) U31.2(TD_M_A)
PRG2_ETH1_D0P: J14.A1(TD1+_1) U31.1(TD_P_A)
PRG2_ETH1_D1M: J14.A4(TD2-_1) U31.5(TD_M_B)
PRG2_ETH1_D1P: J14.A3(TD2+_1) U31.4(TD_P_B)
PRG2_ETH1_D2M: J14.A6(TD3-_1) U31.8(TD_M_C)
PRG2_ETH1_D2P: J14.A5(TD3+_1) U31.7(TD_P_C)
PRG2_ETH1_D3M: J14.A8(TD4-_1) U31.11(TD_M_D)
PRG2_ETH1_D3P: J14.A7(TD4+_1) U31.10(TD_P_D)
PRG2_ETH1_GPIO_0: R143.1 R144.2 R467.2 U31.39(GPIO_0)
PRG2_ETH1_GPIO_1: R141.2 R142.1 U31.40(GPIO_1)
PRG2_ETH1_LED1: J14.A11 Q16.3(D)
PRG2_ETH1_LED2: J14.A13 Q12.3(D) R481.1
PRG2_ETH1_LED3: J14.A14 Q13.3(D) R482.1
PRG2_ETH1_LED_1000: R137.2 R138.1 R468.2 U31.46(LED_1)
PRG2_ETH1_LED_ACT: R139.1 R140.2 R512.1 U31.45(LED_2)
PRG2_ETH1_LED_LINK/MCUBOOTMODE5: R87.2 R88.1 U31.47(LED_0) U34.Y2(MCU_SPI0_D1)
PRG2_ETH2_D0M: J14.B2(TD1-_2) U88.2(TD_M_A)
PRG2_ETH2_D0P: J14.B1(TD1+_2) U88.1(TD_P_A)
PRG2_ETH2_D1M: J14.B4(TD2-_2) U88.5(TD_M_B)
PRG2_ETH2_D1P: J14.B3(TD2+_2) U88.4(TD_P_B)
PRG2_ETH2_D2M: J14.B6(TD3-_2) U88.8(TD_M_C)
PRG2_ETH2_D2P: J14.B5(TD3+_2) U88.7(TD_P_C)
PRG2_ETH2_D3M: J14.B8(TD4-_2) U88.11(TD_M_D)
PRG2_ETH2_D3P: J14.B7(TD4+_2) U88.10(TD_P_D)
PRG2_ETH2_GPIO_0: R495.2 R555.2 R556.1 U88.39(GPIO_0)
PRG2_ETH2_GPIO_1: R557.1 R558.2 U88.40(GPIO_1)
PRG2_ETH2_LED1: J14.B11 Q15.3(D)
PRG2_ETH2_LED2: J14.B13 Q14.3(D) R490.1
PRG2_ETH2_LED3: J14.B14 Q5.3(D) R178.1
PRG2_ETH2_LED_1000: R161.2 R561.1 R562.2 U88.46(LED_1)
PRG2_ETH2_LED_ACT: R515.1 R559.2 R560.1 U88.45(LED_2)
PRG2_ETH2_LED_LINK/MCUBOOTMODE8: R81.1 R82.2 U34.AC5(WKUP_GPIO0_8) U88.47(LED_0)
PRG2_ETH_LED0: R464.2 R737.2 U7.10(P5)
PRG2_ETH_LED1: R458.2 R738.2 U7.11(P6)
PRG2_MDC: J5.16 RA5.16 U31.16(MDC) U88.16(MDC)
PRG2_MDIO: J5.15 R198.1 R498.1 RA3.11 U31.17(MDIO) U88.17(MDIO)
PRG2_PRU0_GP0: RA1.4 RA9.5 U34.AF18(PRG2_PRU0_GPO0)
PRG2_PRU0_GP1: RA1.5 RA9.4 U34.AE18(PRG2_PRU0_GPO1)
PRG2_PRU0_GP2: RA1.3 RA9.6 U34.AH17(PRG2_PRU0_GPO2)
PRG2_PRU0_GP3: RA1.2 RA9.7 U34.AG18(PRG2_PRU0_GPO3)
PRG2_PRU0_GP4: RA1.1 RA9.8 U34.AG17(PRG2_PRU0_GPO4)
PRG2_PRU0_GP5: RA3.8 RA10.1 U34.AF17(PRG2_PRU0_GPO5)
PRG2_PRU0_GP6: R209.2 RA3.7 RA10.2
PRG2_PRU0_GP7: RA3.6 RA10.3 U34.AC19(PRG2_PRU0_GPO7)
PRG2_PRU0_GP8: R211.2 RA3.5 RA10.4
PRG2_PRU0_GP9: RA3.4 RA4.4 RA10.5
PRG2_PRU0_GP10: RA3.3 RA4.3 RA10.6
PRG2_PRU0_GP11: RA3.2 RA4.2 RA10.7
PRG2_PRU0_GP16: RA3.1 RA4.1 RA10.8
PRG2_PRU1_GP0: RA5.8 RA11.1 U34.AH15(PRG2_PRU1_GPO0)
PRG2_PRU1_GP1: RA5.7 RA11.2 U34.AC16(PRG2_PRU1_GPO1)
PRG2_PRU1_GP2: RA5.6 RA11.3 U34.AD17(PRG2_PRU1_GPO2)
PRG2_PRU1_GP3: RA5.5 RA11.4 U34.AH14(PRG2_PRU1_GPO3)
PRG2_PRU1_GP4: RA5.4 RA11.5 U34.AG14(PRG2_PRU1_GPO4)
PRG2_PRU1_GP5: RA5.3 RA11.6 U34.AG15(PRG2_PRU1_GPO5)
PRG2_PRU1_GP6: RA2.3 RA5.2 RA11.7
PRG2_PRU1_GP7: RA5.1 RA11.8 U34.AE15(PRG2_PRU1_GPO7)
PRG2_PRU1_GP8: RA1.8 RA2.4 RA9.1
PRG2_PRU1_GP9: R494.2 RA1.7 RA9.2
PRG2_PRU1_GP10: R500.2 RA1.6 RA9.3
PRG2_PRU1_GP11: R180.1 R463.1 RA2.1
PRG2_PRU1_GP16: R183.1 R466.1 RA2.2
PRG2_RGMII1_ETH1_CLK: R170.2 U31.15(XI)
PRG2_RGMII1_ETH1_CLK_OUT: TP17.1(TP) U31.18(CLK_OUT)
PRG2_RGMII1_ETH1_RBIAS: R188.1 U31.12(RBIAS)
PRG2_RGMII1_RD0: R168.1 RA1.13
PRG2_RGMII1_RD0_R: R167.2 R168.2 R179.1 U31.33(RX_D0)
PRG2_RGMII1_RD1: R162.1 RA1.12
PRG2_RGMII1_RD1_R: R162.2 U31.34(RX_D1)
PRG2_RGMII1_RD2: R157.1 RA1.14
PRG2_RGMII1_RD2_R: R157.2 R158.1 R163.2 U31.35(RX_D2)
PRG2_RGMII1_RD3: R154.1 RA1.15
PRG2_RGMII1_RD3_R: R154.2 U31.36(RX_D3)
PRG2_RGMII1_RX_CTL: R152.1 RA1.16
PRG2_RGMII1_RX_CTL_R: R145.1 R146.1 R152.2 U31.38(RX_DV/RX_CTRL)
PRG2_RGMII1_RXC: R181.1 RA3.9
PRG2_RGMII1_RXC_R: R181.2 U31.32(RX_CLK)
PRG2_RGMII1_TD0: RA3.12 U31.28(TX_D0)
PRG2_RGMII1_TD1: RA3.13 U31.27(TX_D1)
PRG2_RGMII1_TD2: RA3.14 U31.26(TX_D2)
PRG2_RGMII1_TD3: RA3.15 U31.25(TX_D3)
PRG2_RGMII1_TX_CTL: RA3.10 U31.37(TX_EN/TX_CTRL)
PRG2_RGMII1_TXC: RA3.16 U31.29(GTX_CLK)
PRG2_RGMII2_ETH2_CLK: R169.2 U88.15(XI)
PRG2_RGMII2_ETH2_CLK_OUT: TP55.1(TP) U88.18(CLK_OUT)
PRG2_RGMII2_ETH2_RBIAS: R509.1 U88.12(RBIAS)
PRG2_RGMII2_RD0: R519.1 RA5.9
PRG2_RGMII2_RD0_R: R518.1 R519.2 R520.2 U88.33(RX_D0)
PRG2_RGMII2_RD1: R523.1 RA5.10
PRG2_RGMII2_RD1_R: R523.2 U88.34(RX_D1)
PRG2_RGMII2_RD2: R525.1 RA5.11
PRG2_RGMII2_RD2_R: R522.2 R524.1 R525.2 U88.35(RX_D2)
PRG2_RGMII2_RD3: R537.1 RA5.12
PRG2_RGMII2_RD3_R: R537.2 U88.36(RX_D3)
PRG2_RGMII2_RX_CTL: R541.1 RA5.13
PRG2_RGMII2_RX_CTL_R: R541.2 R553.1 R554.1 U88.38(RX_DV/RX_CTRL)
PRG2_RGMII2_RXC: R517.1 RA5.14
PRG2_RGMII2_RXC_R: R517.2 U88.32(RX_CLK)
PRG2_RGMII2_TD0: RA1.9 U88.28(TX_D0)
PRG2_RGMII2_TD1: RA1.10 U88.27(TX_D1)
PRG2_RGMII2_TD2: RA1.11 U88.26(TX_D2)
PRG2_RGMII2_TD3: R180.2 U88.25(TX_D3)
PRG2_RGMII2_TX_CTL: RA5.15 U88.37(TX_EN/TX_CTRL)
PRG2_RGMII2_TXC: R183.2 U88.29(GTX_CLK)
PRG2_RGMII_INTN: R151.1 R542.1 U31.44(INT/PWDN) U45.5(A1) U88.44(INT/PWDN)
PRG2_RGMII_INTN_3V3: R270.1 U34.A22(EXT_REFCLK1) U45.8(B1)
PRG2_RGMII_RESETN: R514.1 U31.43(RESET_N) U86.4(Y) U88.43(RESET_N)
PRG_EARTH: C489.1 J14.SH1 J14.SH2 J14.SH3 J14.SH4 R473.1
PRI_INN: C145.1 R172.1 R173.2 U32.14(PRI_INN)
R_PRG2_PRU1_GP6: RA2.6 U34.AC17(PRG2_PRU1_GPO6)
R_PRG2_PRU1_GP8: RA2.5 U34.AD15(PRG2_PRU1_GPO8)
R_PRG2_PRU1_GP11: RA2.8 U34.AD14(PRG2_PRU1_GPO11)
R_PRG2_PRU1_GP16: RA2.7 U34.AE14(PRG2_PRU1_GPO16)
R_SOC_SPI1_CS1: J35.42 J36.42 R311.2
RAMP: C62.1 U14.5(RAMP)
REFCLK0N: J5.58 R60.1 R725.1
REFCLK0N_R: R725.2 U34.AF9(REFCLK0N)
REFCLK0P: J5.59 R59.1 R724.1
REFCLK0P_R: R724.2 U34.AF10(REFCLK0P)
REFCLK1N: J5.27 R40.1 R727.1
REFCLK1N_R: R727.2 U34.AE8(REFCLK1N)
REFCLK1P: J5.28 R39.1 R726.1
REFCLK1P_R: R726.2 U34.AE9(REFCLK1P)
RESET_SOC_MPU: C682.1 U59.D1(VDD) U110.12(P12)
RESETSTATZ: TP48.1(TP) U34.D19(RESETSTATZ)
RT: R65.1 U14.3(RT)
SEL_XDS: U36.4(Y) U87.6(OE) U97.4(O\E\) U98.14(2\O\E\) U98.15(1\O\E\)
SEL_XDS110_INV: J13.8 J32.58 R215.1 R216.1 U36.2(A) U39.1(A) U41.1(A) U42.15(O\E\) U43.14(2\O\E\) U43.15(1\O\E\) U90.1(A) U92.1(A) U101.4(O\E\) U103.6(OE)
SERDES_BRD_DET: J5.45 R236.1 U46.6(P2)
SHIELD: FL7.1 J2.SH1 J2.SH2 J2.SH3 J2.SH4
SOC_DDR_VREFCA: C504.1 C505.1 R728.2 U34.F12(DDR_VREF0)
SOC_DVDD1V8: C415.1 C417.1 C418.1 C425.1 C432.1 C435.1 C439.1 C442.1 C537.1 C542.1 C545.1 C547.1 C548.1 C549.1 C551.1 C553.1 C555.1 C557.1 C558.1 C561.1 C562.1 C568.1 C569.1 C570.2 C573.1 C574.1 C576.2 FL36.1 J15.2 R234.3 U34.AA20(VDDSHV_PRG2#AA20) U34.AA22(VDDSHV_PRG1#AA22) U34.AB19(VDDSHV_PRG2#AB19) U34.AB21(VDDSHV_PRG2#AB21) U34.AB23(VDDSHV_PRG2#AB23) U34.AC18(VDDS_PRG_BIAS2) U34.F20(VDDS_MMC_BIAS0) U34.G20(VDDSHV_MMC0#G20) U34.H19(VDDSHV_MMC0#H19) U34.H21(VDDSHV_MMC0#H21) U34.N6(VDDSHV_WKUP_CPSW2G0#N6) U34.N8(VDDS_WKUP_CPSW2G_BIAS0) U34.P7(VDDSHV_WKUP_CPSW2G0#P7) U34.P9(VDDSHV_WKUP_CPSW2G0#P9) U34.R6(VDDSHV_WKUP_FLASH0#R6) U34.R8(VDDSHV_WKUP_FLASH0#R8) U34.T7(VDDSHV_WKUP_FLASH0#T7) U34.T9(VDDS_WKUP_FLASH_BIAS0) U34.T20(VDDS_PRG_BIAS0) U34.T21(VDDSHV_PRG0#T21) U34.U20(VDDSHV_PRG0#U20) U34.U22(VDDSHV_PRG0#U22) U34.V21(VDDSHV_PRG0#V21) U34.V23(VDDSHV_PRG0#V23) U34.W20(VDDSHV_PRG1#W20) U34.W22(VDDSHV_PRG1#W22) U34.Y20(VDDS_PRG_BIAS1) U34.Y21(VDDSHV_PRG1#Y21) U34.Y23(VDDSHV_PRG1#Y23)
SOC_DVDD3V3: C413.2 C416.1 C421.1 C426.1 C433.1 C470.1 C480.1 C481.2 C506.1 C523.1 C536.1 C554.1 C560.1 C563.1 C567.1 FL13.1 FL16.1 FL18.1 J31.2 R395.2 R459.3 U34.AA18(VDDSHV_GENERAL1#AA18) U34.AA21(VDDA_3P3_IOLDO1) U34.AB11(VDDSHV6) U34.AB17(VDDSHV_GENERAL1#AB17) U34.AC10(VDDA_3P3_SOC_MON) U34.G15(VDDSHV_GENERAL0#G15) U34.G18(VDDA_3P3_IOLDO0) U34.H16(VDDSHV_GENERAL0#H16) U34.N20(VDDSHV_GPMC#N20) U34.N22(VDDSHV_GPMC#N22) U34.P21(VDDSHV_GPMC#P21) U34.R20(VDDSHV_GPMC#R20) U34.R22(VDDSHV_GPMC#R22) U34.U6(VDDA_3P3_WKUP_IO_MON) U34.U8(VDDSHV_WKUP_GENERAL0#U8) U34.V7(VDDSHV_WKUP_GENERAL0#V7) U34.W8(VDDSHV_WKUP_GENERAL0#W8) U34.Y7(VDDSHV_WKUP_GENERAL0#Y7)
SOC_EMU0: U34.AA2(EMU0) U87.5(A1) U103.5(A1)
SOC_EMU1: U34.AA1(EMU1) U87.4(A2) U103.4(A2)
SOC_FT4232_MCU_UART1_CTS_1V8: U8.2(B) U12.9(2A2)
SOC_FT4232_MCU_UART1_RX_1V8: U12.8(2A1) U65.2(B)
SOC_FT4232_WKUP_UART0_CTS_3V3: U21.9(2A2) U23.2(B)
SOC_FT4232_WKUP_UART0_RX_3V3: U21.8(2A1) U83.2(B)
SOC_I2C0_SCL: J16.21 J33.3 R586.2 U34.D20(I2C0_SCL) U84.15(SCL) U91.6(SCL) U110.19(SCL)
SOC_I2C0_SDA: J16.23 J33.2 R585.2 U34.C21(I2C0_SDA) U84.2(SDA) U91.5(SDA) U110.20(SDA)
SOC_I2C1_SCL: J38.26 J44.3 R581.2 TP67.1(TP) U34.B21(I2C1_SCL)
SOC_I2C1_SDA: J38.27 J45.3 R582.2 TP68.1(TP) U34.E21(I2C1_SDA)
SOC_I2C2_SCL: J41.36 R325.1 R592.2 TP73.1(TP) U2.5(SCL) U3.5(SCL) U27.2(A0) U27.5(SCL) U34.T27(GPMC0_CSN3) U44.1(SCL) U67.5(SCL) U68.5(SCL) U69.2(A0) U69.5(SCL) U70.5(SCL) U89.1(SCL) U93.5(SCL)
SOC_I2C2_SDA: J41.38 R326.1 R593.2 TP74.1(TP) U2.4(SDA) U3.2(A0) U3.4(SDA) U27.4(SDA) U34.R25(GPMC0_CSN2) U44.6(SDA) U67.4(SDA) U68.4(SDA) U69.4(SDA) U70.2(A0) U70.4(SDA) U89.6(SDA) U93.4(SDA)
SOC_MAIN_UART0_CTS_3V3: U19.9(2A2) U34.AG11(UART0_CTSN)
SOC_MAIN_UART0_RTS_3V3: U19.7(1A2) U34.AD11(UART0_RTSN)
SOC_MAIN_UART0_RX_3V3: U19.8(2A1) U34.AF11(UART0_RXD)
SOC_MAIN_UART0_TX_3V3: U19.6(1A1) U34.AE11(UART0_TXD)
SOC_MAIN_UART1_RX_1V8: U26.7(YB) U34.AE23(PRG1_PRU1GPO17)
SOC_MAIN_UART1_TX_1V8: U26.4(YA) U34.AD23(PRG1_PRU1GPO7)
SOC_MCU_SCL: J5.2 J35.32 J36.32 J44.2 R545.2 TP69.1(TP) U9.6(SCL) U111.20(B1)
SOC_MCU_SCL_R: J44.1 U34.AD8(MCU_I2C0_SCL)
SOC_MCU_SDA: J5.3 J35.34 J36.34 J45.2 R538.2 TP70.1(TP) U9.5(SDA) U111.18(B2)
SOC_MCU_SDA_R: J45.1 U34.AD7(MCU_I2C0_SDA)
SOC_MCU_UART1_CTS_1V8: U8.5(Y) U34.P1(MCU_OSPI1_D3)
SOC_MCU_UART1_RTS_1V8: U6.7(1A2) U12.7(1A2) U34.N3(MCU_OSPI1_CSN1)
SOC_MCU_UART1_RX_1V8: U34.P4(MCU_OSPI1_D1) U65.5(Y)
SOC_MCU_UART1_TX_1V8: U6.6(1A1) U12.6(1A1) U34.P5(MCU_OSPI1_D2)
SOC_MMC0_CD: R739.1 U34.A23(MMC0_SDCD)
SOC_MMC0_CLK: RA14.3 U34.B25(MMC0_CLK)
SOC_MMC0_CMD: RA14.5 U34.B27(MMC0_CMD)
SOC_MMC0_DAT0: RA14.7 U34.A26(MMC0_DAT0)
SOC_MMC0_DAT1: RA14.1 U34.E25(MMC0_DAT1)
SOC_MMC0_DAT2: RA14.2 U34.C26(MMC0_DAT2)
SOC_MMC0_DAT3: R533.1 U34.A25(MMC0_DAT3)
SOC_MMC0_DAT4: RA14.6 U34.E24(MMC0_DAT4)
SOC_MMC0_DAT5: R532.1 U34.A24(MMC0_DAT5)
SOC_MMC0_DAT6: RA14.8 U34.B26(MMC0_DAT6)
SOC_MMC0_DAT7: RA14.4 U34.D25(MMC0_DAT7)
SOC_MMC0_DS: R252.2 R253.1 U34.C25(MMC0_DS)
SOC_MMC0_WP: R740.1 R741.2 U34.B23(MMC0_SDWP)
SOC_MPU: C261.1 C266.1 C278.1 J24.1 L3.2 R348.4 TP24.1(TP)
SOC_OSPI_CLK: R430.1 U34.V1(MCU_OSPI0_CLK)
SOC_OSPI_DQ0: RA8.13 U34.U4(MCU_OSPI0_D0)
SOC_OSPI_DQ1: RA8.10 U34.U5(MCU_OSPI0_D1)
SOC_OSPI_DQ2: RA8.16 U34.T2(MCU_OSPI0_D2)
SOC_OSPI_DQ3: RA8.14 U34.T3(MCU_OSPI0_D3)
SOC_OSPI_DQ4: RA8.15 U34.T4(MCU_OSPI0_D4)
SOC_OSPI_DQ5: RA8.12 U34.T5(MCU_OSPI0_D5)
SOC_OSPI_DQ6: RA8.11 U34.R2(MCU_OSPI0_D6)
SOC_OSPI_DQ7: RA8.9 U34.R3(MCU_OSPI0_D7)
SOC_PORZ: R299.2 R427.1 R743.2 TP28.1(TP) U34.E19(PORZ) U34.W5(MCU_PORZ)
SOC_POWER_MON_PORZ: R289.2 U49.4(SENSE_OUT) U50.1(A)
SOC_SAFETY_ERRORZ: TP57.1(TP) U34.E20(SOC_SAFETY_ERRORN)
SOC_SERDES_REFCLK0_N: J5.24 U34.AG5(USB0_REFCLKN)
SOC_SERDES_REFCLK0_P: J5.25 U34.AG6(USB0_REFCLKP)
SOC_SERDES_REFCLK1_N: J5.55 U34.AH6(PCIE1_REFCLKN)
SOC_SERDES_REFCLK1_P: J5.56 U34.AH7(PCIE1_REFCLKP)
SOC_SPI0_CLK: J16.20 R136.1 R491.1 U24.B2(C)
SOC_SPI0_CLK_R: R491.2 U34.AH13(SPI0_CLK)
SOC_SPI0_CS0: R133.1 U24.C2(S#) U34.AG13(SPI0SCS0)
SOC_SPI0_CS1: J16.24 U34.AF13(SPI0SCS1)
SOC_SPI0_D0: J16.26 R123.1 U24.D3(DQ0) U34.AE13(SPI0_D0)
SOC_SPI0_D1: J16.28 R126.1 U24.D2(DQ1) U34.AD13(SPI0_D1)
SOC_SPI1_CLK: J20.4 J35.48 J36.48 J38.32 R489.1
SOC_SPI1_CLK_R: R489.2 U34.AH12(SPI1_CLK)
SOC_SPI1_CS: J20.3 R316.1 R317.1
SOC_SPI1_CS0: R317.2 R675.1 U34.AD12(SPI1_CS0)
SOC_SPI1_CS1: R311.1 R316.2 U34.AG12(SPI1_CS1)
SOC_SPI1_MISO: J20.2 J35.46 J36.46 J38.36 U34.AF12(SPI1_D1)
SOC_SPI1_MOSI: J20.1 J35.44 J36.44 J38.35 U34.AE12(SPI1_D0)
SOC_TCK: R241.2 R623.2 U34.AA4(TCK)
SOC_TDI: U34.C20(TDI) U43.4(1A1) U98.4(1A1)
SOC_TDO: R208.2 U97.2(A1) U101.2(A1)
SOC_TMS: U34.A21(TMS) U43.6(2A1) U98.6(2A1)
SOC_TRST#: R130.1 U34.AA3(TRSTN) U43.7(2A2) U98.7(2A2)
SOC_UART1_CTS_1V8: U26.12(YD) U34.AD22(PRG1_PRU1GPO18)
SOC_UART1_RTS_1V8: U26.9(YC) U34.AC21(PRG1_PRU1GPO19)
SOC_USB1_VBUS: R28.2 R34.1 U34.AF6(USB1_VBUS)
SOC_VDDS_DDR: C408.1 C409.1 C410.1 C420.1 C427.1 C428.1 C429.1 C436.1 C441.1 C454.1 C483.1 C493.1 J29.2 R361.4 U34.G8(VDDS_DDR#G8) U34.G10(VDDS_DDR#G10) U34.G14(VDDS_DDR#G14) U34.H7(VDDS_DDR#H7) U34.H9(VDDS_DDR#H9) U34.H13(VDDS_DDR#H13)
SOC_WARM_RESETZ: R309.1 U34.F17(RESETZ) U55.4(Y)
SOC_WKUP_SCL: J5.33 J16.15 J35.6 J36.6 J38.23 R584.2 TP71.1(TP) U7.14(SCL) U34.AC7(WKUP_I2C0_SCL) U46.14(SCL) U56.6(SCL) U59.D3(SCL)
SOC_WKUP_SDA: J5.34 J16.17 J35.14 J36.14 J38.24 R583.2 TP72.1(TP) U7.15(SDA) U34.AD6(WKUP_I2C0_SDA) U46.15(SDA) U56.5(SDA) U59.D2(SDA)
SOC_WKUP_UART0_CTS_3V3: U23.5(Y) U34.AC2(WKUP_GPIO0_6)
SOC_WKUP_UART0_RTS_3V3: J11.2 U21.7(1A2) U34.AC1(WKUP_GPIO0_7)
SOC_WKUP_UART0_RX_3V3: U34.AB1(WKUP_UART0_RXD) U83.5(Y)
SOC_WKUP_UART0_TX_3V3: J11.5 U21.6(1A1) U34.AB5(WKUP_UART0_TXD)
SPI0_RSTN: R153.1 U24.A4(RESET#/DNU) U28.4(Y)
SPI0_WP: R127.1 U24.C4(W#/DQ2)
SS: C63.1 U14.7(SS)
SUPERVISOR_DEBOUNCE_RSTN: C243.1 D11.1(K) Q7.2(S) R319.1 SW8.1 SW8.2 U54.1(1A)
SUPERVISOR_MR_RSTN: U49.1(ENABLE) U54.7(1Y)
SYS_BOOTMODE0: U99.1(P00) U102.3(A1)
SYS_BOOTMODE1: U99.2(P01) U102.4(A2)
SYS_BOOTMODE2: U99.3(P02) U102.5(A3)
SYS_BOOTMODE3: U99.4(P03) U102.6(A4)
SYS_BOOTMODE4: U99.5(P04) U102.7(A5)
SYS_BOOTMODE5: U99.6(P05) U102.8(A6)
SYS_BOOTMODE6: U99.7(P06) U102.9(A7)
SYS_BOOTMODE7: U99.8(P07) U102.10(A8)
SYS_BOOTMODE8: U99.9(P10) U105.3(A1)
SYS_BOOTMODE9: U99.10(P11) U105.4(A2)
SYS_BOOTMODE10: U99.11(P12) U105.5(A3)
SYS_BOOTMODE11: U99.12(P13) U105.6(A4)
SYS_BOOTMODE12: U99.13(P14) U105.7(A5)
SYS_BOOTMODE13: U99.14(P15) U105.8(A6)
SYS_BOOTMODE14: U99.15(P16) U105.9(A7)
SYS_BOOTMODE15: U99.16(P17) U105.10(A8)
SYS_BOOTMODE16: U95.4(1A1) U99.19(P22)
SYS_BOOTMODE17: U95.5(1A2) U99.18(P21)
SYS_BOOTMODE18: U95.6(2A1) U99.17(P20)
TCA6424_EXP_INT: R630.1 U99.32(I\N\T\)
TCA9555_EXP_INT: R661.1 U110.22(I\N\T\)
TEMP_DIODE_P: TP53.1(TP) U34.W6(TEMP_DIODE_P)
TEST_GPIO1: R683.1 R692.1 U53.1(A)
TEST_GPIO2: R684.1 R693.1 U104.1(A)
TEST_GPIO3: R66.1 R694.1 U17.1(A)
TEST_GPIO4: R685.1 R695.1 TP65.1(TP) U99.28(R\E\S\E\T\)
TEST_PORZN: Q7.1(G) R681.1 R690.1
TEST_POWERDOWN: R352.2 R689.1 U66.5(EN)
TEST_WARMRESETN: R682.1 R691.1 U55.1(A)
TG: R4.1 TP3.1(TP) U61.7(TG)
TIMER_IO0: J19.1 U34.B22(TIMER_IO0)
TIMER_IO1: J19.2 U34.C23(TIMER_IO1)
TIMER_IO2: J19.3 RA6.1
TIMER_IO3: J19.4 RA6.2
TIMER_IO6: J19.5 RA6.3
TIMER_IO7: J19.6 RA6.4
TM4C129_RSTN: J40.10 R323.2
TM4C129_TCK: J40.4 U106.100(PC0/TCK/SWCLK)
TM4C129_TDI: J40.8 U106.98(PC2/TDI)
TM4C129_TDO: J40.6 U106.97(PC3/TDO/SWO)
TM4C129_TMS: J40.2 U106.99(PC1/TMS/SWDIO)
TMP1_ADD0: R544.2 R547.2 U89.5(ADD0)
TMP1_ADD1: R526.2 R539.2 U89.3(ADD1)
TMP2_ADD0: R247.1 R256.2 U44.5(ADD0)
TMP2_ADD1: R255.2 R261.2 U44.3(ADD1)
USB0_ATEST: TP54.1(TP) U34.AD10(USB0_ATEST)
USB0_DM: J5.36 U34.AE2(USB0_DM)
USB0_DP: J5.37 U34.AF1(USB0_DP)
USB0_DRV_VBUS: J5.5 U34.AD9(USB0_DRVVBUS)
USB0_ID_SOC: J5.14 U34.AF7(USB0_ID)
USB0_PCIE0_SGMII0_RXN0: J5.40 U34.AH3(USB0_SSRXN)
USB0_PCIE0_SGMII0_RXP0: J5.39 U34.AG2(USB0_SSRXP)
USB0_PCIE0_SGMII0_TXN0: C60.2 J5.43
USB0_PCIE0_SGMII0_TXN0_C: C60.1 U34.AH4(USB0_SSTXN)
USB0_PCIE0_SGMII0_TXP0: C61.2 J5.42
USB0_PCIE0_SGMII0_TXP0_C: C61.1 U34.AG3(USB0_SSTXP)
USB0_RESREF: R483.1 U34.AC9(USB0_RESREF)
USB0_VBUS: C691.1 J5.47 R380.1
USB0_VBUS_SOC: R469.2 R471.1 U34.AE7(USB0_VBUS)
USB1_AB_DM: FL8.4 J3.2(D-) U4.2(D-)
USB1_AB_DP: FL8.3 J3.3(D+) U4.1(D+)
USB1_AB_ID: J3.4(ID) J4.5 U4.3(ID) U34.AF5(USB1_ID)
USB1_CM_DM: FL8.1 R397.2
USB1_CM_DP: FL8.2 R400.2
USB1_DM: R74.2 R397.1 U34.AD2(USB1_DM)
USB1_DP: R76.2 R400.1 U34.AE1(USB1_DP)
USB1_DRV_VBUS: R474.2 R477.1 U34.AC8(USB1_DRVVBUS)
USB1_DRVBUS: R50.1 R477.2 U11.4(EN)
USB1_HDMI_GPMC_DM: J35.52 J36.52 R74.1
USB1_HDMI_GPMC_DP: J35.54 J36.54 R76.1
USB1_HDMI_GPMC_DRVBUS: J35.50 J36.50 R474.1
USB1_SHIELD: C11.2 J3.6(SH1) J3.7(SH2) J3.8(SH3) J3.9(SH4) J3.10(SH5) R17.2
USB1_VBUS: C19.1 J3.1(VCC) J4.1 R25.1 U4.6(VBUS) U11.6(OUT1) U11.7(OUT2) U11.8(OUT3)
UVLO_REF: R64.1 R68.2 U14.2(UVLO)
VMAIN: C68.1 C69.1 C72.1 C179.1 C323.1 C333.1 C340.1 C341.1 C680.1 C681.1 Q2.3(S) R9.1 R68.1 R200.1 R359.1 TP9.1(TP) U14.1(VIN) U14.4(EN) U18.5(D1) U18.6(D2) U18.7(D3) U18.8(D4) U35.5(VDD) U72.5(D) U75.25(VIN) U75.31(EN1) U75.40(EN2) U78.5(D) U80.1(VIN)
VOUT1_DATA20: J35.7 J36.7 U34.T28(GPMC0_BE0N_CLE)
VOUT1_DATA21: RA6.8 RA17.5 U34.P23(GPMC0_BE1N)
VOUT1_DATA21_TEST_HDR: J35.5 J36.5 RA17.4
VOUT1_DATA22: J35.3 J36.3 U34.R26(GPMC0_WAIT0)
VOUT1_DATA23: RA6.7 RA17.6 U34.R23(GPMC0_WAIT1)
VOUT1_DATA23_TEST_HDR: J35.1 J36.1 RA17.3
VOUT1_DE: RA6.5 RA17.8 U34.T23(GPMC0_CSN1)
VOUT1_DE_TEST_HDR: J35.28 J36.28 RA17.1
VOUT1_HSYNC: RA6.6 RA17.7 U34.T24(GPMC0_DIR)
VOUT1_HSYNC_TEST_HDR: J35.26 J36.26 RA17.2
VOUT1_PCLK: J35.20 J36.20 U34.R24(GPMC0_CSN0)
VOUT1_VSYNC: J35.24 J36.24 U34.T25(GPMC0_WPN)
VOUT_D0_BOOTMODE0: J35.51 J36.51 R297.1 R631.1 SW3.1 U34.M27(GPMC0_AD0)
VOUT_D1_BOOTMODE1: J35.49 J36.49 R293.1 R626.1 SW3.2 U34.M23(GPMC0_AD1)
VOUT_D2_BOOTMODE2: J35.47 J36.47 R287.1 R632.1 SW3.3 U34.M28(GPMC0_AD2)
VOUT_D3_BOOTMODE3: J35.45 J36.45 R282.1 R627.1 SW3.4 U34.M24(GPMC0_AD3)
VOUT_D4_BOOTMODE4: J35.43 J36.43 R278.1 R633.1 SW3.5 U34.N24(GPMC0_AD4)
VOUT_D5_BOOTMODE5: J35.41 J36.41 R274.1 R628.1 SW3.6 U34.N27(GPMC0_AD5)
VOUT_D6_BOOTMODE6: J35.39 J36.39 R260.1 R629.1 SW3.7 U34.N28(GPMC0_AD6)
VOUT_D7_BOOTMODE7: J35.37 J36.37 R251.1 R634.1 SW3.8 U34.M25(GPMC0_AD7)
VOUT_D8_BOOTMODE8: J35.33 J36.33 R245.1 R642.1 SW3.9 U34.N23(GPMC0_AD8)
VOUT_D9_BOOTMODE9: J35.31 J36.31 R240.1 R635.1 SW3.10 U34.M26(GPMC0_AD9)
VOUT_D10_BOOTMODE10: J35.29 J36.29 R295.1 R643.1 SW2.1 U34.P28(GPMC0_AD10)
VOUT_D11_BOOTMODE11: J35.27 J36.27 R291.1 R636.1 SW2.2 U34.P27(GPMC0_AD11)
VOUT_D12_BOOTMODE12: J35.25 J36.25 R285.1 R644.1 SW2.3 U34.N26(GPMC0_AD12)
VOUT_D13_BOOTMODE13: J35.23 J36.23 R280.1 R637.1 SW2.4 U34.N25(GPMC0_AD13)
VOUT_D14_BOOTMODE14: J35.21 J36.21 R276.1 R638.1 SW2.5 U34.P24(GPMC0_AD14)
VOUT_D15_BOOTMODE15: J35.19 J36.19 R272.1 R645.1 SW2.6 U34.R27(GPMC0_AD15)
VOUT_D16: J35.15 J36.15 U34.R28(GPMC0_CLK)
VOUT_D17_BOOTMODE16: J35.13 J36.13 R258.1 R603.1 SW2.7 U34.P25(GPMC0_ADVN_ALE)
VOUT_D18_BOOTMODE17: J35.11 J36.11 R249.1 R602.1 SW2.8 U34.P26(GPMC0_OEN_REN)
VOUT_D19_BOOTMODE18: J35.9 J36.9 R243.1 R601.1 SW2.9 U34.U28(GPMC0_WEN)
VPHY_3V3_FT4232: C331.2 FL10.1 U73.4(VPHY)
VPLL_3V3_FT4232: C324.2 FL9.1 R381.2 U73.9(VPLL)
VPP: U77.C5(VPP)
VPP_1V8: C5.1 FL17.1 TP23.1(TP) U1.1(OUT)
VPP_CORE_MCU: C414.1 C559.1 FL17.2 U34.F21(VPP_CORE) U34.T6(VPP_MCU)
VPP_LDO_EN: R6.2 TP80.1(TP) U1.3(EN) U34.R1(MCU_OSPI1_LBCLKO)
VREF: C654.1 C655.1 R663.2 U106.9(VREFA+) U107.3(CATHODE)
VSENSE: C361.2 R418.1 R425.2 U80.6(VSENSE)
WARM_RST: U52.2(3Y) U55.2(B)
WKUP_GPIO0_13: U52.5(2Y) U53.2(B)
WKUP_GPIO0_13_INTN: R308.1 U34.R5(MCU_OSPI0_CSN1) U53.4(Y)
WKUP_GPIO0_27: U52.7(1Y) U104.2(B)
WKUP_GPIO0_27_INTN: R647.1 U34.P2(MCU_OSPI1_DQS) U104.4(Y)
WKUP_LFOSC_RTC_XIN: R551.2 U34.AE4(WKUP_LFOSC_XI)
WKUP_LFOSC_XIN: R564.1 U91.1(X1)
WKUP_LFOSC_XOUT: R550.1 U91.2(X2)
WKUP_OSC0_XIN: R448.2 R450.1 U34.AD5(WKUP_OSC0_XI)
WKUP_OSC0_XOUT: R457.1 U34.AE6(WKUP_OSC0_XO)
WKUP_UART_SEL: R120.2 U23.6(A\/B) U83.6(A\/B) U110.14(P14)
XDS110_DIR: R621.2 U98.2(1DIR) U98.3(2DIR)
XDS110_EMU0: R655.2 U103.8(B1) U106.42(PF0)
XDS110_EMU1: R654.2 U103.1(B2) U106.43(PF1)
XDS110_TCK: R609.2 U98.12(1B2)
XDS110_TDI: R612.2 U98.13(1B1)
XDS110_TDO: R611.2 U97.7(B1)
XDS110_TMS: R613.2 U98.11(2B1)
XDS110_TRST#: R646.2 U98.10(2B2)
XDS_SHIELD: FL6.1 J23.SH1 J23.SH2 J23.SH3 J23.SH4 J23.SH5 J23.SH6
XDS_USB_DM: J23.2(D-) U58.5(IO4) U106.93(PL7/USB0DM)
XDS_USB_DP: J23.3(D+) U58.4(IO3) U106.94(PL6/USB0DP)
XDS_USB_ID: J23.4(ID) R665.2 U58.2(IO2)
XDS_USB_VBUS: C250.1 J23.1(VBUS) R670.1 R678.1 U57.1(IN1) U57.2(IN2) U57.8(EN) U58.6(VCC)
N5126218: J14.A12 R501.2
N5126260: TP16.1(TP) U31.13(VDDA1P8#13) U31.48(VDDA1P8#48)
N15202140: R665.1 U106.95(PB0/USB0ID)
N15204440: C249.2 R333.1 R334.2 U57.5(NR/FB)
N15205319: C645.1 R657.1 U106.68(VBAT)
N15205492: R322.1 R323.1 R324.1 U106.70(R\S\T\)
N15212041: R653.1 U106.59(RBAIS)
N15239696: C665.1 R670.2 U106.96(PB1/USB0VBUS)
N15241750: R677.1 R678.2 U106.1(PD0/AIN15)
N15242949: R335.1 U106.3(PD2/AIN13)
N15242980: LD20.2(ANODE) R335.2
N15243226: R332.1 U106.4(PD3/AIN12)
N15352717: R410.1 U77.C3(DQS)
N15365714: J41.27 R690.2
N15365947: J41.30 R692.2
N15366015: J41.31 R693.2
N15366091: J41.32 R694.2
N15507744: C342.1 U76.2(NR/FB)
N15584817: R281.2 SW3.17
N15584821: R286.2 SW3.18
N15584825: R292.2 SW3.19
N15584829: R296.2 SW3.20
N15591045: R250.2 SW3.13
N15591049: R259.2 SW3.14
N15591053: R273.2 SW3.15
N15591057: R277.2 SW3.16
N15697942: J12.11 R449.2
N15698204: TP12.1(TP) U22.13(VDDA1P8#13) U22.48(VDDA1P8#48)
N15808488: R75.1 U20.B9(ZQ)
N15808528: TP8.1(TP) U16.A3(NF/NF/TDQS_C/NF)
N15808578: TP11.1(TP) U20.A3(NF/NF/TDQS_C/NF)
N15808694: TP13.1(TP) U25.A3(NF/NF/TDQS_C/NF)
N15808746: R52.1 U16.B9(ZQ)
N15808770: TP15.1(TP) U33.A3(NF/NF/TDQS_C/NF)
N15812130: R166.1 U33.B9(ZQ)
N15812170: R117.1 U25.B9(ZQ)
N15820521: R516.2 U38.E7(DQ7/NC)
N15820751: TP18.1(TP) U38.A3(NF/NF/TDQS_C/NF)
N15820885: R212.1 U38.B9(ZQ)
N15854221: C440.2 R715.1 U27.8(VBUS) U27.9(VIN-)
N15854243: C440.1 R714.1 U27.10(VIN+)
N15854325: R148.1 U27.3(ALERT)
N15854335: R18.1 U3.3(ALERT)
N15854337: C279.2 R713.1 U3.8(VBUS) U3.9(VIN-)
N15854349: C279.1 R712.1 U3.10(VIN+)
N15854407: R363.1 U68.3(ALERT)
N15854417: C286.2 R709.1 U68.8(VBUS) U68.9(VIN-)
N15854427: C286.1 R708.1 U68.10(VIN+)
N15854463: R358.1 U67.3(ALERT)
N15854467: C280.2 R711.1 U67.8(VBUS) U67.9(VIN-)
N15854483: C280.1 R710.1 U67.10(VIN+)
N15854545: R591.1 U93.3(ALERT)
N15854547: R14.1 U2.3(ALERT)
N15854553: C218.2 R717.1 U93.8(VBUS) U93.9(VIN-)
N15854557: C273.2 R719.1 U2.8(VBUS) U2.9(VIN-)
N15854581: C273.1 R718.1 U2.10(VIN+)
N15854603: C218.1 R716.1 U93.10(VIN+)
N15854669: R364.1 U69.3(ALERT)
N15854673: C292.2 R723.1 U69.8(VBUS) U69.9(VIN-)
N15854685: C292.1 R722.1 U69.10(VIN+)
N15854737: R365.1 U70.3(ALERT)
N15854741: C293.2 R721.1 U70.8(VBUS) U70.9(VIN-)
N15854757: C293.1 R720.1 U70.10(VIN+)
N15854857: J21.2 R326.2
N15854859: J21.1 R325.2
N16248811: R448.1 U32.20(Y7)
N16248833: R169.1 U32.18(Y6)
N16248855: R170.1 U32.17(Y5)
N16248877: R207.1 U32.8(Y4)
N16248899: R206.1 U32.7(Y3)
N16248921: R205.1 U32.5(Y2)
N16248943: R204.1 U32.3(Y1)
N16248965: R203.1 U32.1(Y0)
N16295803: R244.2 SW3.12
N16300126: R239.2 SW3.11
N16303893: R279.2 SW2.17
N16303897: R284.2 SW2.18
N16303901: R290.2 SW2.19
N16303905: R294.2 SW2.20
N16303913: R248.2 SW2.13
N16303917: R257.2 SW2.14
N16303921: R271.2 SW2.15
N16303925: R275.2 SW2.16
N16303929: R242.2 SW2.12
N16457366: C401.1 R450.2 R455.1 Y3.2
N16457370: C412.1 R455.2 R457.2 Y3.1
N16458713: C584.1 R507.2 R510.1 Y4.3
N16458717: C587.1 R510.2 R511.2 Y4.1
N16460347: C602.1 R563.1 R564.2 Y5.2
N16460351: C600.1 R550.2 R563.2 Y5.1
N16489740: R551.1 R552.1 U91.7(MFP)
N16493735: B1.1(+) U91.3(VBAT)
N16679303: R312.2 R313.1 U106.60(PK7)
N16679944: R649.1 R650.2 U106.63(PK4)
N16679981: R651.1 R652.2 U106.61(PK6)
N16680014: R314.1 R315.2 U106.62(PK5)
N16753626: J32.6 R472.2
N16753680: J32.15 R478.2
N16753934: J32.12 R479.2
N16818481: LD6.1 Q8.3(D)
N16818579: D14.1(CATHODE) Q8.1(G) R346.2
N16818604: R362.2 U66.1(SENSE)
N16818646: LD6.2 R13.2
N16818667: R359.2 U66.9(OUT)
N16818684: C281.1 U66.7(TIMER)
N16818713: LD5.2 R9.2
N16818872: R350.1 R351.2 U66.4(UVLO)
N16818874: R353.1 R354.2 U66.3(OVP)
N16865556: FL12.2 J14.A9(VCC)
N16865678: FL11.2 J12.2(VCC)
N16937764: R241.1 U43.5(1A2)
N16938293: R623.1 U98.5(1A2)
N17211229: J41.33 R695.2
N17247526: LD11.2 R107.2
N17247539: LD12.2 R108.2
N17247599: LD13.2 R109.2
N17247637: LD14.2 R110.2
N17247662: LD10.2 R106.2
N17247701: LD15.2 R105.2
N17247743: LD9.2 R104.2
N17247786: LD8.2 R103.2
N17248427: R431.2 U84.7(A2)
N17248432: R453.2 U84.10(A1)
N17248439: R454.2 U84.9(A0)
N17307815: R688.1 U111.10(OE)
N17309165: R676.2 U111.9(A8)
N17314921: R679.2 U111.12(B8)
N17368941: R356.1 U65.7(G\)
N17368953: R440.1 U83.7(G\)
N17372472: R452.2 U85.5(2DIR)
N17372478: R447.1 U85.4(1DIR)
N17372544: R80.2 U19.5(2DIR)
N17372552: R89.1 U19.4(1DIR)
N17372616: R116.2 U21.5(2DIR)
N17372624: R113.1 U21.4(1DIR)
N17372676: R42.2 U12.5(2DIR)
N17372684: R51.1 U12.4(1DIR)
N17402100: R624.1 U100.10(OE)
N17546132: J41.26 R689.2
N17546158: J41.28 R691.2
N17682848: R355.4 R708.2
N17682861: R355.1 R709.2
N17683733: R349.3 R710.2
N17683748: R349.2 R711.2
N17685192: R348.3 R712.2
N17685207: R348.2 R713.2
N17685595: R459.1 R714.2
N17685608: R459.4 R715.2
N17685678: R234.1 R716.2
N17685693: R234.4 R717.2
N17685736: R342.1 R718.2
N17685749: R342.4 R719.2
N17686321: R361.2 R720.2
N17686333: R361.3 R721.2
N17686697: R360.3 R722.2
N17686710: R360.2 R723.2
N17781485: L11.1 U94.6(SW)
N17781689: L6.1 U63.2(SW)
N17781701: R15.1 R16.2 U63.4(FB)
N17781734: L3.1 U59.B3(SW1) U59.B4(SW2)
N17782106: R7.2 R11.1 U61.8(MODE)
N17782154: L5.1 U61.2(SW1)
N17782156: L4.1 U61.10(SW2)
N17782314: C4.2 R339.2 R340.1 R341.2 U61.14(FB)
N17782316: C265.1 U61.12(SS/TR)
N17782320: R10.1 U61.6(VSEL)
N17782393: R341.1 U61.15(RS)
N17785459: C357.1 R414.1 U80.7(COMP)
N17785463: C359.2 R414.2
N17785477: C356.2 L9.1 U80.2(SW)
N17785481: C356.1 U80.9(BOOT)
N17785497: C361.1 R419.2 R425.1
N17785579: L7.1 U64.1(SW1) U64.2(SW2)
N17785692: C269.2 U64.7(CP)
N17785694: C269.1 U64.8(CN)
N17785722: R343.1 R344.2 U64.5(FB)
N17786037: L2.1 U40.2(SW)
N17786049: R566.2 R567.1 U40.4(FB)
N17817176: TP41.1(TP) U34.A7(DDR_CK1)
N17817178: TP39.1(TP) U34.B7(DDR_CK1_N)
N17817198: TP45.1(TP) U34.C12(DDR_ATESTOUTO)
N17817246: TP42.1(TP) U34.F9(DDR_DTESTOUT0)
N17817413: R186.1 U34.F13(DDR_VTP)
N17817732: TP44.1(TP) U34.F10(DDR_DTESTOUT1)
N17818942: TP46.1(TP) U34.F15(DDR_VREF_ZQ)
N17839730: C299.1 J4.2
N17903256: R302.2 SW4.4(B1)
N17903258: R306.2 SW4.3(B2)
N17976903: R596.2 U95.7(2A2)
N18001847: R700.2 U114.1(ENABLE/DISABLE)
N18001866: R699.1 U114.3(OUTPUT)
N18022426: R31.2 U6.5(2DIR)
N18022434: R35.1 U6.4(1DIR)
N18024163: R30.1 U8.7(G\)
N18024634: R125.1 U23.7(G\)
N18046866: C51.1 U14.16(VCC)
N18046972: C49.1 R55.2
N18070254: R603.2 U95.13(1B1)
N18070257: R602.2 U95.12(1B2)
N18070260: R601.2 U95.11(2B1)
N18104656: J8.1 R395.1
N18104659: J8.3 R394.2
N18114187: FL14.2 J14.B9(VCC)
N18115017: J14.B12 R496.2
N18115328: TP56.1(TP) U88.13(VDDA1P8#13) U88.48(VDDA1P8#48)
N18116794: Q16.1(G) R512.2
N18116818: Q12.1(G) R467.1
N18116875: Q13.1(G) R468.1
N18117332: Q15.1(G) R515.2
N18117348: Q14.1(G) R495.1
N18117389: Q5.1(G) R161.1
N18118509: R494.1 U34.AF14(PRG2_PRU1_GPO9)
N18118513: R500.1 U34.AC15(PRG2_PRU1_GPO10)
N18118517: R211.1 U34.AH16(PRG2_PRU0_GPO8)
N18118519: RA4.6 U34.AF16(PRG2_PRU0_GPO10)
N18118521: RA4.5 U34.AG16(PRG2_PRU0_GPO9)
N18118523: RA4.7 U34.AE16(PRG2_PRU0_GPO11)
N18118537: RA4.8 U34.AD16(PRG2_PRU0_GPO16)
N18118541: R209.1 U34.AE17(PRG2_PRU0_GPO6)
N18120742: R150.2 U29.1(DIR2) U29.10(DIR1)
N18120819: R160.2 U30.6(OE)
N18120892: R164.2 U29.2(O\E\)
N18122515: Q3.1(G) R73.1
N18122533: Q4.1(G) R72.1
N18122581: Q9.1(G) R451.1
N18125073: TP60.1(TP) U34.A27(VSENSE)
N18125082: R208.1 U34.A20(TDO)
N18125186: R129.1 U34.AB2(WKUP_GPIO0_11)
N18184841: R667.1 U110.18(A0)
N18184861: R660.2 U110.23(A1)
N18184865: R659.2 U110.24(A2)
N18275385: R218.1 U37.6(OE)
N18276744: C214.1 R229.2
N18280417: R233.2 U41.4(Y)
N18280437: R565.2 U92.4(Y)
N18280477: R543.2 U90.4(Y)
N18280857: R223.2 U39.4(Y)
N18289329: R300.1 R476.2 U49.3(SENSE)
N18289350: C232.1 U49.5(CT)
N18289892: R674.1 U112.3(OUTPUT)
N18289915: R671.2 U112.1(ENABLE/DISABLE)
N18292398: C168.1 R200.2 R201.1 U35.3(SENSE)
N18320293: C161.2 R192.1 R194.1 Y1.2
N18320301: C156.2 R191.1 R192.2 Y1.1
N18321769: R199.1 U32.31(OE)
N18436285: LD18.1(CATHODE1) Q17.3(D)
N18436298: LD18.3(ANODE) R224.1
N18436321: Q6.1(G) R225.1
N18436342: LD18.2(CATHODE2) Q6.3(D)
N18436344: Q17.1(G) R548.1
N18436628: Q11.1(G) R464.1
N18436656: LD17.2 R177.1
N18436666: LD17.1 Q11.3(D)
N18436681: Q10.1(G) R458.1
N18436707: LD16.2 R155.1
N18546005: D2.1(CATHODE) D6.2(ANODE) F1.2 R5.1
N18546027: LD1.1 R5.2
N18546044: D1.1(K) LD1.2
N18547174: R338.2 U62.5(GATE)
N18547348: R337.2 SW1.2 U62.2(I/P)
N18550089: C3.1 U63.9(SS/TR)
N18860929: R672.1 U109.10(DIR1)
N18860951: R673.1 U109.2(O\E\)
N18867275: R642.2 U105.21(B1)
N18867277: R635.2 U105.20(B2)
N18867279: R643.2 U105.19(B3)
N18867281: R636.2 U105.18(B4)
N18867283: R644.2 U105.17(B5)
N18867285: R637.2 U105.16(B6)
N18867287: R638.2 U105.15(B7)
N18867289: R645.2 U105.14(B8)
N18867885: R631.2 U102.21(B1)
N18867903: R626.2 U102.20(B2)
N18867905: R632.2 U102.19(B3)
N18867915: R627.2 U102.18(B4)
N18867925: R633.2 U102.17(B5)
N18867943: R628.2 U102.16(B6)
N18867953: R629.2 U102.15(B7)
N18867955: R634.2 U102.14(B8)
N18948512: R124.1 U24.D4(DQ3)
N18950218: R429.1 U34.R4(MCU_OSPI0_CSN0)
N18968753: C42.1 FL2.3(O) U11.2(IN1) U11.3(IN2)
N18968782: R37.2 U11.5(O\C\)
N18972035: R176.1 U26.15(E\)
N18977103: LD7.2(ANODE) R77.2
N18977129: C337.1 U73.3(OSCO) Y2.2
N18977189: C344.1 U73.2(OSCI) Y2.1
N18977240: LD7.1(CATHODE) U73.60(P\W\R\E\N\)
N19031494: C601.1 U40.9(SS/TR)
N19031660: C264.1 U64.9(SS)
N19158110: R299.1 U50.4(Y)
N19311007: R165.2 U34.A11(DDR_RESET_N)
N19311901: D16.3(C) R380.2 R469.1
N19312123: D4.3(C) R25.2 R28.1
N19753713: C343.2 D17.1(CATHODE) U75.11(HB2)
N19753729: C343.1 L10.1 U75.10(SW2) U78.1(S1) U78.2(S2) U78.3(S3) U81.5(D)
N19753760: L10.2 R426.1 R703.1
N19753772: R405.2 U75.8(HOL2) U78.4(G)
N19753820: R392.1 U75.13(LO2)
N19753822: R392.2 R396.2 U81.4(G)
N19753872: C684.1 R703.2 U75.4(CS2)
N19753878: C684.2 R704.2 U75.5(VOUT2)
N19753964: C352.1 R399.1
N19754006: C317.1 U75.30(SS1)
N19754185: C345.1 U75.1(SS2)
N19754201: C320.2 L8.2 U71.5(D) U72.1(S1) U72.2(S2) U72.3(S3) U75.21(SW1)
N19754203: C320.1 D15.1(CATHODE) U75.20(HB1)
N19754223: R378.2 U75.22(HO1)
N19754237: R378.1 U72.4(G) U75.23(HOL1)
N19754314: R384.1 R387.1 U71.4(G)
N19754320: R384.2 U75.19(LOL1)
N19754322: R387.2 U75.18(LO1)
N19754431: R405.1 U75.9(HO2)
N19754435: R396.1 U75.12(LOL2)
N19754522: L8.1 R357.2 R701.1
N19754526: C683.1 R702.2 U75.26(VOUT1)
N19754534: C683.2 R701.2 U75.27(CS1)
N19754630: C325.2 U75.32(RES)
N19754677: C307.1 R375.1
N20141585: R680.1 U109.1(DIR2)
N20142928: C14.1 U5.2(NR/FB)
N20155231: R246.1 U45.6(OE)
N20155262: R604.1 U96.6(OE)
N20584902: R706.2 U77.B2(C)
N20753582: C303.2 R373.2 R374.2
N21124530: J38.33 R675.2
N21549383: R729.1 U34.F18(NMIN)
N22464359: R736.2 U115.5(O\C\)
N22573349: R745.2 U77.A5(DNU1)
N152432201: LD19.2(ANODE) R332.2
N182775171: C210.1 R222.2
N184366740: LD16.1 Q10.3(D)
N194468551: LD4.2 R2.2
N197540311: LD2.2 R1.2
N197540831: LD3.2 R3.2

Pads without a net: D4 2; D16 2; J4 3 4; J5 31; J9 1; J11 3; J13 6 17 18 19; J16 7 8 9 10 11 12 14 16 35 37 39 41 43 45 46 47 48 49 50 51 53; J17 G3; J21 5; J22 1 3 6 8 25 26 27 28 29 31 33 35 37 39; J30 3; J32 9 10 11 14 28 30 32 34 36 42 44 46 48 50 52 54 56 59 60; J34 6 13 14 15 17 18 19; J35 53 61 62 63 64 65 66 67 68 69 70 71 72 73 74 75 76 77 78 79 80 81 82 83 84 85 86 87 88 89 90 91 92 93 94 95 96 97 98 99 100 101 102 103 104 106 108 110 112 114 116 118 120; J36 53; J39 27 28 35 36; J40 7; J41 4 5 6 8 9 10 11 12 13 14 15 17 18 19 20 21 22 23 24 29 35; J42 4; SW1 3; SW2 10 11; U4 5; U5 5; U7 6 12; U8 3; U14 11; U15 1 2; U22 14 20 21 22 23 47; U23 3; U24 A2 A3 A5 B1 B5 C1 C3 C5 D1 D5 E1 E2 E3 E4 E5; U29 4 9; U30 1 4; U31 14 20 21 22 23; U32 22 24 27 28; U34 AC4; U36 1; U40 10; U42 5 6 10 11 13 14; U45 1 4; U46 9 10 11 12; U47 4 9; U51 A1 A2 A7 A8 A9 A10 A11 A12 A13 A14 B1 B7 B8 B9 B10 B11 B12 B13 B14 C1 C3 C5 C7 C8 C9 C10 C11 C12 C13 C14 D1 D2 D3 D4 D12 D13 D14 E1 E2 E3 E5 E8 E9 E10 E12 E13 E14 F1 F2 F3 F10 F12 F13 F14 G1 G2 G3 G10 G12 G13 G14 H1 H2 H3 H12 H13 H14 J1 J2 J3 J12 J13 J14 K1 K2 K3 K6 K7 K10 K12 K13 K14 L1 L2 L3 L12 L13 L14 M1 M2 M3 M7 M8 M9 M10 M11 M12 M13 M14 N1 N3 N6 N7 N8 N9 N10 N11 N12 N13 N14 P1 P2 P7 P8 P9 P10 P11 P12 P13 P14; U54 2 5; U56 1; U57 7; U58 1; U60 2; U62 6 7 8; U63 10; U65 3; U73 21 22 23 24 30 32 33 34 36 43 44 45 46 55 57 58 59; U75 39; U76 5; U77 A2 A3 B1 B5; U79 6 7; U83 3; U88 14 20 21 22 23; U95 10; U96 1 4; U99 20 21 22 23 24; U106 2 5 6 11 12 13 14 15 18 19 20 21 22 23 24 25 27 29 30 31 32 33 34 41 44 45 46 49 50 53 54 56 57 65 67 71 72 73 74 75 76 77 78 81 82 83 84 85 86 91 92 102 103 104 105 106 107 108 109 110 111 112 116 117 118 119 120 121 123 124 125 126 127 128; U107 2 4 5; U110 17

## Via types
v1: diameter 0.457, hole 0.203, TOP to BOTTOM, 4718 vias

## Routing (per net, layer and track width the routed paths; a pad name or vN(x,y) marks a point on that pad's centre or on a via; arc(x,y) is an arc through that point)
DGND: length 1459.3
  TOP w0.094: U51.A6 161.68,55.7 v1(162.05,56.07) ; v1(158.62,49.4) 158.95,49.08 159.44,49.08 U51.N2
  TOP w0.122: U51.P6 U51.N5
  TOP w0.203: 170.73,11.62 J22.44 169.1,12.19 ; J18.101 85.12,59.36 v1(85.62,59.86) ; U6.1 113.98,155.41 v1(113.53,154.95) 113.39,155.08 U6.16 ; J18.5 85.12,30.36 v1(85.62,30.86) ; J18.25 85.12,35.36 v1(85.62,35.86) ; v1(52.93,61.95) 53.43,62.45 J16.22 ; C688.1 102.13,75.87 102.23,75.97 v1(102.23,76.45) ; v1(59.55,60.5) C228.2 v1(60.22,61.23) ; v1(101.47,81.15) 101.18,81.15 101.01,80.99 C690.1 ; v1(128.46,171.54) C5.2 v1(127.61,170.69) ; J16.19 v1(53.93,71.75) ; v1(85.62,58.86) 85.12,58.36 J18.97 ; U12.16 113.39,148.57 v1(113.53,148.44) 113.98,148.89 U12.1 ; v1(128.08,166.03) C1.2 v1(127.25,166.88) ; U6.11 114.38,157.82 v1(114.55,157.99) 114.78,157.76 U6.10 ; v1(59.31,62.99) C223.2 v1(59.92,62.24) ; v1(203.37,148.87) 202.88,149.36 ; 202.88,149.36 v1(202.88,150.3) ; 202.88,149.36 v1(202.39,148.87) ; 152.97,11.05 J22.41 ; J22.41 154.6,11.62 ; J22.41 152.97,12.19 ; U51.K8 162.22,51.29 v1(162.15,51.29) 161.55,51.29 161.51,51.32 U51.J5 ; J16.13 v1(55.43,71.75) ; C106.2 187.66,118.01 188.01,117.66 U25.K9 ; U10.8 v1(202.88,150.3) ; v1(202.88,150.3) 202.48,149.9 U10.4 ; J18.2 75.4,29.36 v1(74.9,29.86) ; C685.2 161.44,151.92 v1(161.67,152.15) ; U21.11 112.86,121.08 v1(113.03,120.9) 112.8,120.68 U21.10 ; C222.2 v1(59.69,72.31) ; v1(85.62,61.86) 85.12,61.36 J18.109 ; v1(85.62,60.86) 85.12,60.36 J18.105 ; v1(161.22,53.78) U51.C4 ; v1(74.9,30.86) 75.4,30.36 J18.6 ; U21.1 110.38,121.48 v1(109.93,121.93) 110.06,122.06 U21.16 ; J18.85 85.12,55.36 v1(85.62,55.86) ; U34.AH8 U34.AG7 ; 43.12,66.74 J16.61 ; J16.61 41.49,67.31 ; J16.61 43.12,67.88 ; v1(74.9,55.86) 75.4,55.36 J18.86 ; J18.29 85.12,36.36 v1(85.62,36.86) ; v1(136.04,105.28) 136.26,105.5 137.05,105.5 U34.AH5 ; J18.111 v1(84.71,61.86) ; 155.16,11.62 J22.43 157.86,12.19 ; v1(59.88,73.33) C227.2 v1(59.21,74.08) ; J16.62 59.25,67.88 ; J16.62 60.87,67.31 ; J16.62 59.25,66.74 ; J18.1 85.12,29.36 v1(85.62,29.86) ; 48.01,67.88 J16.63 48.01,66.74 ; v1(85.62,51.86) 85.12,51.36 J18.69 ; 188.23,102.87 188.23,104.06 188,104.29 C140.2 ; J18.21 85.12,34.36 v1(85.62,34.86) ; 54.36,67.88 54.36,66.74 ; v1(85.62,52.86) 85.12,52.36 J18.73 ; v1(51.93,72.67) 52.43,72.17 J16.25 ; U39.3 97.21,77.14 v1(97.09,77.03) ; R6.1 v1(127.91,169.19) ; J18.107 v1(84.71,60.86) ; U12.11 114.38,150.16 114.58,149.96 v1(114.61,149.96) 114.78,150.13 U12.10 ; U19.11 110.29,129.43 v1(110.46,129.26) 110.69,129.49 U19.10 ; v1(74.9,54.86) 75.4,54.36 J18.82 ; J16.18 54.43,62.45 v1(53.93,61.95) ; v1(188.47,106.74) 188.98,107.25 188.98,108.35 ; 164.21,11.05 J22.42 164.21,12.19 ; U19.16 109.3,127.87 v1(109.43,127.73) 109.89,128.19 U19.1 ; J18.89 85.12,56.36 v1(85.62,56.86) ; v1(85.62,33.86) 85.12,33.36 J18.17 ; U41.3 97.15,73.15 v1(97.08,73.09) ; U29.3 31.48,103.71 31.2,103.44 v1(30.81,103.44) ; v1(188.47,120.46) 188.91,120.9
  TOP w0.208: U38.H9 v1(186.81,88.69) ; U33.N1 v1(190.81,95.21) ; U25.K1 188.98,108.35 ; U25.D9 v1(182.81,116.12) ; U20.A9 v1(180.41,129.84) ; U38.K1 v1(188.41,81.49) ; U25.H9 v1(186.81,116.12) ; U38.E1 v1(183.61,81.49) ; U20.C8 v1(182.01,129.04) ; U20.G1 v1(185.21,122.64) ; U25.E9 v1(183.61,116.12) ; U25.C8 v1(182.01,115.32) ; U33.A9 v1(180.41,102.41) ; U33.E9 v1(183.61,102.41) ; U25.A9 v1(180.41,116.12) ; U33.K9 188.01,102.65 188.23,102.87 ; U25.N1 v1(190.81,108.92) ; U25.G1 v1(185.21,108.92) ; U38.A9 v1(180.41,88.69) ; U20.K1 188.91,122.14 188.91,120.9 ; U38.G1 v1(185.21,81.49) ; U38.N1 v1(190.81,81.49) ; U33.C8 v1(182.01,101.61) ; U33.E1 v1(183.61,95.21) ; U20.H9 v1(186.81,129.84) ; U20.E1 v1(183.61,122.64) ; U20.N1 190.81,122.64 v1(190.81,122.17) ; U25.E1 v1(183.61,108.92) ; U20.E9 v1(183.61,129.84) ; U33.H9 v1(186.81,102.41) ; U33.G1 v1(185.21,95.21) ; U25.A8 v1(180.41,115.32)
  TOP w0.254: C198.2 91.72,82.84 v1(91.88,82.67) ; C109.2 v1(30.48,117.14) ; v1(113.53,154.95) 113.5,154.92 C20.2 ; U8.4 120.3,154.65 v1(120.44,154.51) ; v1(52.79,96.5) 52.61,96.68 C162.2 ; v1(177.74,126.86) C90.2 v1(176.72,127.65) ; C127.2 182.58,107.04 v1(182.81,106.81) ; U16.N1 v1(190.81,136.35) ; U34.R7 v1(147.16,104.19) ; C206.2 188.18,79.54 v1(188.41,79.31) ; C82.2 188.24,134.4 188.47,134.18 v1(188.47,134.18) 188.83,134.53 188.83,134.54 188.98,134.69 188.98,135.78 U16.K1 ; v1(33.08,74.57) 33.27,74.76 33.27,75.61 U40.1 ; R230.2 v1(28.83,72.76) ; U34.N11 v1(149.56,100.99) ; v1(184.25,134.24) 184.42,134.4 C80.2 ; U34.Y22 v1(143.16,91.39) ; C138.2 35.79,103.77 v1(35.56,103.55) ; U51.E7 v1(162.18,52.86) ; J22.43 v1(158.54,11.62) v1(161.44,11.62) J22.42 v1(166.54,11.62) v1(168.54,11.62) J22.44 169.1,10.7 v1(169.04,10.64) ; U7.8 v1(139.59,153.49) ; C171.1 v1(69.38,93.65) ; v1(114.01,102.33) 113.81,102.54 C148.2 113.78,103.06 U27.7 ; C176.2 188.24,93.26 v1(188.47,93.03) 188.98,93.54 188.98,94.63 U33.K1 ; J17.G5 v1(206.34,59.09) ; v1(52.2,108.21) 52,108.02 51.45,108.02 C125.2 ; U34.G21 v1(154.36,92.19) ; U7.3 137.57,156.74 137.1,157.21 v1(137.1,157.23) 137.26,157.39 U7.2 ; J18.104 v1(75.82,59.86) ; v1(141.8,151.07) 141.88,151.15 C26.2 ; v1(180.41,117.73) R117.2 ; U34.L3 v1(151.16,107.39) ; U32.15 73.13,100.06 ; 73.13,100.06 v1(72.9,99.82) v1(71.88,98.81) ; 73.13,100.06 73.63,100.56 U32.16 ; U28.3 v1(102.62,107.53) ; v1(177.74,140.58) C53.2 v1(176.74,141.37) ; J5.32 156.94,144.67 157.12,144.49 v1(157.63,144.49) ; v1(186.81,79.31) 186.58,79.54 C205.2 ; C126.2 53.64,108.03 v1(53.87,108.26) ; U35.2 v1(92.94,92.43) ; v1(180.41,93.09) 180.57,93.26 C172.2 ; U34.AE10 v1(139.16,101.79) ; v1(72.52,142.75) v1(73.53,141.73) 74.04,142.24 74.76,142.24 74.94,142.06 U14.6 ; v1(72.52,142.75) 71.91,143.36 U14.13 ; v1(72.52,142.75) 72.48,142.71 U14.14 ; R333.2 v1(109.43,12.33) ; C140.2 187.04,104.29 v1(186.81,104.52) ; v1(180.41,131.44) R75.2 ; C219.2 v1(191.48,69.13) ; LD19.1 v1(96.65,12.19) ; U34.AB14 v1(141.56,98.59) ; v1(47.12,61.98) 46.79,62.31 C609.2 ; U34.Y6 v1(143.16,104.99) ; v1(150.5,11.3) 150.81,11.62 J22.41 ; J5.51 v1(141.74,144.57) ; U34.AE5 v1(139.16,105.79) ; C50.2 v1(15.79,144.29) ; R130.2 141.48,115.87 v1(141.86,116.26) 142.37,116.26 142.81,115.81 C113.1 ; C40.2 113.5,148.41 v1(113.53,148.44) ; v1(186.81,145.67) 187.04,145.44 C45.2 ; v1(153.16,85.99) U34.H28 U34.J27 ; C102.2 38.89,121.18 v1(39.12,121.41) ; C75.2 v1(170.18,136.09) ; C214.2 v1(97.08,73.09) ; v1(61.29,87.06) C193.2 v1(60.41,87.85) ; v1(186.81,93.03) 186.58,93.26 C175.2 ; v1(110.85,41.72) 111.08,41.49 C239.2 ; C3.2 168.07,169.23 v1(168.26,169.04) ; v1(160.66,52.07) 160.91,52.32 U51.G5 ; C21.2 115.32,153.57 v1(115.54,153.35) ; v1(145.76,116.59) 145.29,116.11 C114.2 C115.2 ; C250.2 v1(105.79,8.45) ; U34.W19 v1(143.96,93.79) ; R92.2 R91.2 v1(34.29,124.54) ; U33.D1 v1(182.81,95.21) ; v1(153.35,56.16) 153.12,55.93 C230.2 ; U34.F27 U34.E28 v1(155.96,86.59) ; U34.V18 v1(144.76,94.59) ; C204.2 183.77,79.54 v1(183.61,79.38) ; U34.H22 v1(153.56,91.39) ; R99.2 42.55,124.59 v1(42.51,124.59) ; U34.N16 v1(149.56,96.19) ; v1(110.8,113.26) 110.74,113.26 110.7,113.31 C119.2 ; R150.1 v1(31.24,108.92) ; J5.48 v1(144.14,144.56) ; U34.H14 v1(153.56,98.59) ; U34.Y16 v1(143.16,96.19) ; U34.AB12 v1(141.56,100.19) ; C187.2 v1(53.84,90.51) ; C153.2 v1(45.21,100.99) ; v1(182.81,93.03) 182.58,93.26 C173.2 ; C166.2 95.73,95.95 v1(95.54,95.76) ; R31.1 v1(117.38,154) ; U34.AA17 v1(142.36,95.39) ; v1(189.27,90.81) 189.5,90.58 C184.2 ; U36.3 v1(85.7,86.22) ; C229.2 v1(92.46,60.02) ; C105.2 184.99,118.01 v1(185.15,118.17) ; J5.17 v1(144.94,149.36) ; U34.U9 v1(145.56,102.59) ; C237.2 110.29,44.35 v1(110.45,44.51) ; U34.F3 v1(155.16,107.39) ; v1(11.11,130.75) 10.96,130.9 Q4.2 ; U49.2 v1(113.81,51.77) ; Q5.2 v1(17.89,104.22) ; J13.16 v1(103.07,90.04) ; U34.AA23 v1(142.36,90.59) ; R80.1 v1(113.28,126.78) ; U34.F19 v1(155.16,93.79) ; J5.35 v1(154.54,144.57) ; U46.2 90.7,63.52 v1(90.36,63.18) 90.05,63.49 U46.3 ; D4.1 v1(20.31,154.58) ; R219.1 v1(194.93,80.79) ; R312.1 57.27,35.01 v1(57.13,35.15) ; v1(100.27,113.55) U24.B3 ; C110.2 v1(30.48,115.64) ; C95.2 180.57,120.69 v1(180.41,120.52) ; v1(109.43,127.73) 109.4,127.7 C91.2 ; U42.7 105.37,76.81 105.04,77.14 v1(105.03,77.14) 105.02,77.14 104.72,76.85 U42.8 ; C30.2 v1(185.86,150.94) ; U11.1 v1(13.72,147.55) ; J18.96 v1(75.82,57.86) ; v1(83.81,89.22) 84.05,88.98 C189.2 ; C195.2 v1(58.56,86.14) ; U34.M10 v1(150.36,101.79) ; U34.AA26 v1(142.36,88.19) ; U33.D9 v1(182.81,102.41) ; C216.2 v1(42.67,72.72) ; C15.2 194.88,158.37 194.88,158.8 v1(195,158.91) ; v1(189.28,118.24) 189.51,118.01 C107.2 ; U34.AA13 v1(142.36,99.39) ; U34.V6 v1(144.76,104.99) ; C86.2 184.99,131.72 v1(185.15,131.89) ; R135.2 v1(31.46,111.95) ; C78.2 180.57,134.4 v1(180.41,134.24) ; R142.2 R143.2 v1(54.23,111.39) ; v1(91,89.73) 90.74,89.47 C188.2 ; J13.12 103.17,92.58 v1(102.68,93.08) 103.45,93.85 104.94,93.85 ; U34.AH28 137.16,86.97 136.78,86.59 v1(136.76,86.59) ; J42.5 v1(12.55,142.27) ; C134.2 34.19,105.77 v1(34.37,105.95) ; U34.P12 v1(148.76,100.19) ; R247.2 178.51,63.56 v1(178.51,63.53) ; J5.38 v1(152.14,144.57) ; R11.2 144.2,168.78 v1(144.59,168.39) ; R19.2 155.58,160.06 v1(155.59,160.06) ; U38.E9 v1(183.61,88.69) ; v1(168.26,168.02) 168.16,167.92 R15.2 ; v1(185.15,90.74) 184.99,90.58 C182.2 ; D1.2 v1(18.73,164.48) ; v1(106.59,33.22) 106.77,33.04 C243.2 ; J5.1 v1(157.74,149.37) ; R228.2 v1(25.07,74.62) ; C83.2 190.64,134.4 v1(190.87,134.18) ; D12.2 v1(156.07,31.19) ; v1(84.83,62.86) J18.115 ; C111.2 43.65,114.2 v1(43.83,114.02) ; C18.2 183.56,156.31 v1(183.32,156.08) ; J17.6 180.08,43.41 v1(179.11,44.39) ; U34.N13 v1(149.56,99.39) ; U34.H26 U34.J25 v1(152.76,89.79) ; U16.D1 v1(182.81,136.35) ; U16.D9 v1(182.81,143.55) ; C612.2 v1(46.63,60.48) ; U34.P14 v1(148.76,98.59) ; v1(190.87,93.03) 190.87,93.03 190.64,93.26 C177.2 ; U38.A8 v1(180.41,87.89) ; v1(39.5,124.54) R96.2 R95.2 ; v1(137.54,167.44) 136.68,168.3 C2.2 ; v1(193.48,119.34) C104.2 v1(194.49,118.56) ; v1(194.49,104.84) C137.2 v1(193.48,105.63) ; U4.4 15.36,158.31 v1(15.62,158.05) ; v1(134.46,141.68) 134.63,141.85 R59.2 ; U34.B9 v1(158.36,102.59) ; v1(198.69,152.62) C25.2 v1(197.79,151.51) ; U48.3 v1(154.52,52.83) ; v1(71.88,99.82) 71.63,100.07 U32.21 ; v1(50.16,111.39) R139.2 R138.2 ; C155.2 58.38,99.59 v1(58.56,99.41) ; U34.AA19 v1(142.36,93.79) ; C161.1 v1(80.9,96.09) ; SW7.5 v1(134.08,30.4) ; C151.2 164.63,101.3 R186.2 ; C145.2 R172.2 v1(76.05,104.25) ; C142.2 191.1,104.29 v1(191.26,104.46) ; C141.2 189.51,104.29 v1(189.28,104.52) ; C139.2 184.99,104.29 v1(185.15,104.46) ; C156.1 v1(80.9,100.26) ; v1(109.93,121.93) 109.9,121.96 C94.2 ; v1(58.56,100.87) 58.38,101.05 C150.2 ; v1(86.74,91.26) C179.2 87.85,91.48 U35.6 ; C245.1 v1(163.54,19.1) ; v1(190.81,79.31) 190.58,79.54 C207.2 ; D2.2 v1(73.12,164.24) ; U44.2 v1(172.17,62.55) ; D7.2 14.62,138.04 v1(14.8,137.86) ; v1(194.49,91.12) C181.2 v1(193.48,91.91) ; U47.5 176.06,56.54 v1(175.7,56.9) ; R327.1 v1(175.37,18.48) ; v1(186.81,90.81) 187.04,90.58 C183.2 187.68,90.58 188.01,90.25 U38.K9 ; v1(200.09,147.61) C38.1 v1(199.21,148.4) ; v1(71.88,98.81) v1(70.87,99.82) 70.63,100.06 ; v1(71.88,98.81) v1(72.9,97.79) 73.63,97.06 U32.9 ; v1(71.88,98.81) v1(70.87,97.79) 70.13,97.06 U32.32 ; SW5.5 v1(164.96,30.47) ; C14.2 v1(200.57,158.91) ; v1(34.77,104.39) C136.2 ; U34.T18 v1(146.36,94.59) ; U34.Y14 v1(143.16,98.59) ; v1(108.97,117.96) 109.09,118.08 R116.1 ; v1(42.74,105.75) 42.51,105.52 C135.2 ; C180.2 v1(164.54,90.78) ; U34.U11 v1(145.56,100.99) ; U34.H8 v1(153.56,103.39) ; v1(193.48,143.8) C43.2 v1(194.5,144.59) ; U34.V22 v1(144.76,91.39) ; v1(188.47,106.74) 188.24,106.97 C131.2 ; C248.1 v1(170.36,16.85) ; v1(186.81,106.81) 186.58,107.04 C128.2 ; J16.40 v1(48.93,62.87) ; D11.2 v1(109.59,34.17) ; R190.2 v1(76.62,99.81) ; v1(176.74,86.5) C190.2 v1(177.74,85.72) ; v1(139.38,128.46) 139.64,128.21 R82.1 R83.2 ; v1(190.87,120.46) 190.87,120.46 190.64,120.69 C100.2 ; C117.2 v1(30.48,114.14) ; v1(108.33,119.92) 108.55,120.14 C103.2 ; C44.2 185.05,145.44 v1(185.21,145.61) ; R164.1 v1(28.19,104.65) ; C99.2 188.24,120.69 v1(188.47,120.46) ; v1(115.54,146.84) 115.32,147.06 C41.2 ; v1(88.27,93.6) 88.48,93.38 U35.4 ; v1(177.74,113.15) C112.2 v1(176.74,113.93) ; C217.2 110.69,70.85 v1(110.83,70.99) ; v1(176.74,100.22) C154.2 v1(177.74,99.43) ; C47.2 191.1,145.44 v1(191.26,145.61) ; U34.L9 v1(151.16,102.59) ; C208.2 52.09,78.8 v1(52.13,78.75) ; v1(92.83,102.85) 92.64,103.04 C146.2 91.84,102.64 R176.2 ; v1(71.88,97.79) 71.63,97.54 U32.4 ; SW8.5 v1(118.64,30.35) ; C130.2 184.42,106.97 v1(184.25,106.81) ; U34.T22 v1(146.36,91.39) ; v1(186.81,118.24) 187.04,118.01 C106.2 ; C144.2 107.79,103.87 v1(108.01,104.1) ; v1(111.44,126.14) 111.23,126.35 C92.2 ; J18.56 v1(75.82,42.86) ; U46.8 v1(86.8,63.21) ; U34.L24 v1(151.16,90.59) U34.L23 ; R34.2 v1(18.49,154.48) ; SW6.5 v1(149.45,30.4) ; U34.AF8 v1(138.36,103.39) ; U42.9 v1(104.72,71.52) ; v1(44.07,83.86) C196.2 v1(43.19,84.64) ; R42.1 v1(117.38,147.48) ; C251.2 v1(111.06,8.32) ; U34.AF2 v1(138.36,108.19) ; U38.A2 v1(180.41,82.29) ; R305.2 v1(127.47,48.25) ; U34.W21 v1(143.96,92.19) ; U34.B12 v1(158.36,100.19) ; U34.W11 v1(143.96,100.99) ; v1(42.43,73.79) C213.2 v1(43.1,74.51) ; J16.44 v1(47.93,62.87) ; U34.L11 v1(151.16,100.99) ; C98.2 186.58,120.69 v1(186.81,120.46) ; R41.2 v1(207.02,150.7) ; U34.K17 v1(151.96,95.39) ; C200.2 v1(143.08,80.95) ; v1(65.45,97.98) 66.38,97.05 R197.1 ; U34.P18 v1(148.76,94.59) ; U34.G2 v1(154.36,108.19) ; C169.1 v1(75.69,94.24) ; U34.V10 v1(144.76,101.79) ; R195.1 v1(108.05,97.81) ; R315.1 v1(60.9,35.62) ; U34.J23 v1(152.76,90.59) U34.H24 ; U34.P6 v1(148.76,104.99) ; U26.8 v1(87.33,111.99) ; J18.117 84.63,63.36 v1(84.9,63.63) 84.67,63.86 J18.119 ; U32.26 70.63,100.06 ; 70.63,100.06 70.13,100.56 U32.25 ; U34.H20 v1(153.56,92.99) ; C225.2 110.75,61.08 v1(111,60.83) 111.22,61.06 C226.2 ; U34.A2 v1(159.16,108.19) ; C246.1 v1(170.04,19.1) ; J22.16 v1(159.29,16.42) ; v1(127.13,97.28) 127.7,97.85 130.35,97.85 130.56,97.64 C159.2 C165.2 ; C19.2 v1(13.57,155.27) ; U34.W15 v1(143.96,96.99) ; U34.P8 v1(148.76,103.39) ; C122.2 v1(95.76,111.52) ; J18.116 v1(75.69,62.86) ; U34.AH1 v1(136.76,108.99) ; R216.2 v1(86.07,82.69) ; U53.3 v1(106.49,45.4) ; C210.2 96.96,77.15 v1(97.09,77.03) ; v1(159.16,108.99) 159.16,108.94 158.81,108.59 U34.A1 ; J13.20 v1(103.07,87.5) ; C234.2 108.11,50.26 v1(108.34,50.03) ; U34.F22 v1(155.16,91.39) ; C231.2 112.6,55.73 v1(112.45,55.88) ; U34.E4 v1(155.96,106.59) ; U34.R21 v1(147.16,92.19) ; U34.R13 v1(147.16,99.39) ; v1(153.29,165.99) 153.09,165.79 U2.7 ; C203.2 182.58,79.54 v1(182.81,79.31) ; J3.5 v1(12.23,161.07) ; U34.W13 v1(143.96,99.39) ; U34.K8 v1(151.96,103.39) ; U9.4 v1(155.83,155.38) ; U46.1 v1(91.35,63.21) ; SW6.3 v1(143.51,28.15) ; U34.H6 v1(153.56,104.99) ; C224.1 177.32,61.25 v1(177.61,60.96) ; R255.1 169.95,62.61 v1(169.55,63.02) ; C174.2 184.49,93.26 184.26,93.03 v1(184.25,93.03) ; U55.3 v1(113.34,38.93) ; R252.1 v1(157.01,62.45) ; C197.2 v1(45.21,84.52) ; U34.J15 v1(152.76,96.99) ; v1(180.41,79.38) 180.57,79.54 C202.2 ; C133.2 99.48,105.2 v1(99.25,104.97) ; U34.AG1 v1(137.56,108.99) ; R201.2 91.64,95.82 C168.2 91.92,96.49 v1(91.96,96.53) ; U34.G16 v1(154.36,96.19) ; C242.2 122.21,33.1 v1(122.03,33.27) ; R112.2 v1(46.56,119.13) ; U38.C8 v1(182.01,87.89) ; U34.T12 v1(146.36,100.19) ; SW7.4 v1(134.08,28.15) ; C46.2 189.44,145.44 v1(189.21,145.67) ; U25.D1 v1(182.81,108.92) ; U20.A8 v1(180.41,129.04) ; SW6.4 v1(149.45,28.15) ; U34.P10 v1(148.76,101.79) ; U34.L26 v1(151.16,88.19) ; v1(39.11,109.65) 39.29,109.83 C124.2 ; v1(43.83,112.56) 43.65,112.74 C120.2 ; U34.B20 v1(158.36,92.99) ; U37.2 91.32,86.69 v1(91.34,86.68) ; v1(152.91,168.08) 152.65,167.83 C6.2 ; J22.12 v1(157.79,16.42) ; LD5.1 v1(23,173.72) ; J22.24 v1(162.29,16.42) ; C101.2 37.17,121.18 v1(37.4,121.41) ; U34.Y8 v1(143.16,103.39) ; U43.8 111.82,65.56 v1(111.07,64.81) 110.32,65.56 U43.9 ; v1(163,52.29) 163.47,51.82 U51.H10 ; v1(14.75,144.67) C42.2 v1(13.72,145.54) ; U54.6 v1(104.39,45.4) ; R10.2 138.37,168.64 v1(138.56,168.45) ; U34.Y18 v1(143.16,94.59) ; R188.2 v1(46.19,98.8) ; U34.D22 v1(156.76,91.39) ; v1(161.68,48.26) U51.P6 ; SW5.4 v1(164.96,28.22) ; J17.G2 v1(189.41,36.37) ; U5.3 v1(199.15,159.56) ; U34.R15 v1(147.16,96.99) ; v1(53.84,96.5) 54.02,96.68 C163.2 ; U16.A9 v1(180.41,143.55) ; Q7.3 v1(106.93,30.26) ; J5.41 v1(149.74,144.57) ; U34.W17 v1(143.96,95.39) ; J18.108 v1(75.82,60.86) ; U34.T8 v1(146.36,103.39) ; U38.D1 v1(182.81,81.49) ; J5.23 v1(140.14,149.36) ; v1(112.12,116) 112.26,115.86 U23.4 ; v1(155.39,149.36) 155.34,149.31 J5.4 ; C199.2 v1(45.21,83.02) ; v1(115.63,109.94) 115.28,109.59 U27.1 ; FL2.2 19.66,144.54 v1(20.07,144.13) ; SW7.3 v1(128.15,28.15) ; R32.2 124.97,155.46 R30.2 v1(124.97,156.15) ; C37.2 v1(207.06,149.5) ; v1(158.62,160.06) R22.1 R23.1 ; U34.AE25 v1(139.16,88.99) ; U34.R17 v1(147.16,95.39) ; R300.2 v1(114.31,49.39) ; U51.P4 v1(160.68,48.26) ; U3.7 v1(184.46,159.74) ; C67.2 v1(198.06,138.68) ; U16.E1 v1(183.61,136.35) ; U16.E9 v1(183.61,143.55) ; J5.29 v1(135.34,149.36) ; v1(145.16,158.93) 145.1,158.93 145.1,158.94 C13.2 ; U16.H9 v1(186.81,143.55) ; U34.AD4 v1(140.76,106.59) ; v1(186.81,131.95) 187.04,131.72 C87.2 187.76,131.72 188.01,131.47 U20.K9 ; J18.36 v1(75.82,37.86) ; C240.2 153.09,32.25 v1(152.91,32.07) ; C39.2 v1(22.61,148.59) ; U34.N7 v1(149.56,104.19) ; U34.U13 v1(145.56,99.39) ; v1(182.81,120.46) 182.58,120.69 C96.2 ; U16.G1 v1(185.21,136.35) ; U34.K14 v1(151.96,98.59) ; J18.118 75.9,63.36 v1(75.63,63.63) 75.86,63.86 J18.120 ; v1(180.41,104.01) R166.2 ; J5.44 v1(147.34,144.57) ; v1(182.81,134.18) 182.58,134.4 C79.2 ; C186.2 v1(52.79,90.51) ; R179.2 v1(61.29,102.93) ; C51.2 v1(66.86,144.26) ; C108.2 191.1,118.01 v1(191.26,118.17) ; U34.AB20 v1(141.56,92.99) ; U34.M15 v1(150.36,96.99) ; v1(189.26,131.95) 189.49,131.72 C88.2 ; U34.P22 v1(148.76,91.39) ; C16.2 121.86,157.2 v1(121.82,157.25) ; U34.U7 v1(145.56,104.19) ; R136.2 v1(106.69,112.52) ; J18.52 v1(75.82,41.86) ; U34.T10 v1(146.36,101.79) ; U33.A2 v1(180.41,96.01) ; U34.K10 v1(151.96,101.79) ; C121.2 v1(96.79,111.98) ; C160.2 v1(76.71,97.56) ; v1(125.03,34.18) D13.2 ; v1(137.4,33.27) 137.58,33.1 C241.2 ; U54.4 104.89,43.83 v1(104.65,44.07) 104.39,43.81 U54.3 ; R146.2 57.28,111.44 v1(57.24,111.44) ; v1(163.92,16.13) C247.1 v1(163.25,16.85) ; U34.N19 v1(149.56,93.79) ; R50.2 v1(20.38,149.07) ; C52.2 v1(198.06,142.75) ; J23.5 102.14,5.17 v1(101.79,5.52) ; U34.AA7 v1(142.36,104.19) ; v1(186.81,134.18) 186.58,134.4 C81.2 ; U34.AG10 v1(137.56,100.99) ; v1(69.79,103.61) 69.99,103.4 C147.2 ; C64.2 v1(198.06,140.71) ; C73.2 v1(162.56,136.09) ; U34.J13 v1(152.76,99.39) ; Q6.2 v1(23.19,77.53) ; C236.2 v1(102.36,45.08) ; R331.1 v1(175.37,15.43) ; U34.H10 v1(153.56,101.79) ; U34.T26 v1(146.36,88.19) ; U34.L13 v1(151.16,99.39) ; v1(40.04,104.65) U30.2 ; U34.U21 v1(145.56,92.19) ; U34.A28 v1(159.16,86.59) ; U34.G7 v1(154.36,104.19) ; U34.U19 v1(145.56,93.79) ; U34.M17 v1(150.36,95.39) ; U34.H12 v1(153.56,100.19) ; C34.2 v1(189.93,150.94) ; J18.40 v1(75.82,38.86) ; J18.112 v1(75.82,61.86) ; U34.W9 v1(143.96,102.59) ; v1(108.46,8.06) 108.78,8.39 108.78,9.56 ; U34.V14 v1(144.76,98.59) ; U34.L7 v1(151.16,104.19) ; R212.2 v1(180.41,90.3) ; U34.AB10 v1(141.56,101.79) ; v1(53.84,78.75) 53.79,78.8 C209.2 ; U3.1 v1(185.96,163.92) ; R122.2 v1(46.56,115.95) ; SW8.3 v1(112.7,28.1) ; U38.D9 v1(182.81,88.69) ; U34.U3 v1(145.56,107.39) ; R60.2 v1(137.46,142.28) ; U34.P16 v1(148.76,96.19) ; U34.G23 v1(154.36,90.59) ; C178.2 v1(50.6,92.7) ; C233.2 v1(174.9,52.95) ; U34.AB22 v1(141.56,91.39) ; J5.60 v1(134.54,144.57) ; U16.K9 v1(188.41,143.55) ; U34.J9 v1(152.76,102.59) ; U34.R19 v1(147.16,93.79) ; U34.AF15 v1(138.36,96.99) ; U34.AG4 v1(138.36,106.59) ; C244.2 187.16,19.08 v1(187.39,19.3) ; U34.B15 v1(158.36,96.99) ; C123.2 37.88,109.83 v1(38.06,109.65) ; R324.2 v1(65.93,26.42) ; U34.V20 v1(144.76,92.99) ; J18.92 v1(75.82,56.86) ; U17.3 v1(160.14,137.23) ; U20.D9 v1(182.81,129.84) ; C22.2 v1(202.39,151.74) ; U34.V12 v1(144.76,100.19) ; J17.G4 v1(206.34,40.58) ; v1(197.42,156.3) C17.2 v1(196.66,157.12) ; v1(191.26,131.89) 191.1,131.72 C89.2 ; U16.A8 v1(180.41,142.75) ; U56.4 v1(180.21,15.98) ; Q3.2 v1(14.54,132.81) ; U34.W23 v1(143.96,90.59) ; SW5.3 v1(159.02,28.22) ; U34.J18 v1(152.76,94.59) ; R52.2 v1(180.41,145.16) ; v1(184.25,120.52) 184.42,120.69 C97.2 ; v1(164.25,139.83) 164.05,139.62 C686.2 ; C232.2 v1(113.36,55.87) ; v1(193.48,133.06) C85.2 v1(194.49,132.27) ; U34.AH11 v1(136.76,100.99) ; R158.2 v1(61.29,105.97) ; U34.M8 v1(150.36,103.39) ; U34.Y12 v1(143.16,100.19) ; U34.R9 v1(147.16,102.59) ; U34.G9 v1(154.36,102.59) ; C36.2 v1(191.96,150.94) ; C149.2 v1(45.21,102.48) ; U34.AA11 v1(142.36,100.99) ; J17.3 v1(179.18,50.91) ; U20.A2 v1(180.41,123.44) ; v1(116.17,42.58) 115.99,42.76 C238.2 ; D10.2 v1(140.53,31.13) ; U20.D1 v1(182.81,122.64) ; U34.K22 v1(151.96,91.39) U34.K23 ; U33.A8 v1(180.41,101.61) ; U34.AH27 v1(136.76,87.39) ; R187.1 v1(65.71,100.09) ; U34.F14 v1(155.16,98.59) ; U34.N9 v1(149.56,102.59) ; J5.20 v1(142.54,149.36) 142.66,149.48 C29.2 ; J5.26 v1(137.74,149.36) ; U34.F25 U34.E26 v1(155.96,88.19) ; U34.J21 v1(152.76,92.19) ; C132.2 190.64,106.97 190.87,106.74 v1(190.87,106.74) ; U34.G13 v1(154.36,99.39) ; U34.U17 v1(145.56,95.39) ; R254.1 v1(115.76,62.76) ; C56.2 v1(66.86,140.98) ; U58.3 v1(103.52,8.31) ; U34.J11 v1(152.76,100.99) ; U40.11 32.02,75.57 v1(31.9,75.46) ; C201.2 v1(147.57,80.21) ; U34.AG28 v1(137.56,86.59) ; R301.2 v1(127.47,50.89) ; U34.T14 v1(146.36,98.59) ; U34.AF20 v1(138.36,92.99) ; SW8.4 v1(118.64,28.1) ; U34.R11 v1(147.16,100.99) ; C157.2 C158.2 ; v1(114.02,46.77) U52.4 ; U34.N21 v1(149.56,92.19) ; R125.2 107.09,115.05 v1(106.69,114.66) ; U34.K6 v1(151.96,104.99) ; U34.G11 v1(154.36,100.99) ; U34.K19 v1(151.96,93.79) ; U34.AG7 v1(137.56,104.19) ; U16.C8 v1(182.01,142.75) ; C23.2 v1(203.37,151.74) ; C70.2 v1(198.06,136.65) ; U34.AH2 v1(136.76,108.19) ; J5.57 v1(136.94,144.57) ; U34.AB18 v1(141.56,94.59) ; C76.2 v1(172.72,136.09) ; U34.L16 v1(151.16,96.19) ; U34.B6 v1(158.36,104.99) ; U34.AB16 v1(141.56,96.19) ; U50.2 v1(107.69,54.87) ; v1(191.26,90.74) 191.1,90.58 C185.2 ; C194.2 v1(45.21,86.02) ; U34.M20 v1(150.36,92.99) ; U42.12 v1(106.67,71.52) ; R53.2 v1(80.38,144.65) ; C32.2 v1(187.9,150.94) ; v1(15.23,140.9) U15.3 ; U25.A2 v1(180.41,109.72) ; U34.T16 v1(146.36,96.19) ; U34.W7 v1(143.96,104.19) ; C192.2 v1(58.56,87.6) ; U34.AA15 v1(142.36,96.99) ; J5.13 v1(148.14,149.37) ; C74.2 v1(165.1,136.09) ; U34.K12 v1(151.96,100.19) ; J5.54 v1(139.34,144.57) ; C129.2 180.57,106.97 v1(180.41,106.81) ; U34.J7 v1(152.76,104.19) ; C143.2 v1(45.21,103.98) ; U16.A2 v1(180.41,137.15) ; U34.U15 v1(145.56,96.99)
  TOP w0.305: U34.K1 v1(151.96,108.99) ; v1(151.16,86.6) 150.77,86.99 U34.L28 ; U34.H1 v1(153.56,108.99)
  TOP w0.381: J18.123 v1(80.26,42.74) ; v1(150.24,149.35) 150.54,149.05 J5.10 ; J18.124 v1(80.26,46.38) ; J18.128 v1(80.26,62.93) J18.127 v1(80.26,56.39) J18.126 v1(80.26,50.25) J18.125 ; C63.2 v1(79.93,140.84) C62.2 ; J16.61 v1(45.02,67.31) J16.63 v1(50.8,67.31) v1(57.4,67.31) J16.62 ; J18.122 v1(80.26,36.64) ; J18.121 v1(80.26,30.25) ; R65.2 v1(79.93,139.45) R64.2 ; LD20.1 v1(96.52,9.78)
  L02_GND1 w0.127: 136.32,100.58 138,100.58
  L12_SIG4 w0.254: v1(98.17,138.81) 97.03,138.81 95.24,140.6 89.5,140.6 87.97,142.12 v1(84.32,142.12) ; v1(97.48,134.87) 90.65,128.04 84.21,128.04 83.5,127.33 v1(83.5,125.66)
  BOTTOM w0.122: v1(183.61,143.55) 183.73,143.67 183.73,144.02 ; C430.2 v1(138.36,103.39)
  BOTTOM w0.203: 172.73,40.45 J35.125 172.73,39.31 ; U97.3 U97.6 41.46,59.2 v1(41.24,59.42) ; C65.2 198.06,139.7 198.06,139.7 ; C689.1 102.13,73.61 v1(102.36,73.84) ; U92.3 97.28,75.05 v1(97.16,74.93) ; v1(171.2,102.81) 174.09,102.81 178.86,107.58 178.86,146.35 191.54,159.03 191.54,168.5 188.13,171.91 U59.C1 ; C358.2 33.25,128.62 v1(32.96,128.91) ; U106.58 v1(58.09,30.84) ; 188.86,39.31 J35.128 ; J35.128 188.86,40.45 ; J35.128 190.48,39.88 ; C667.2 53.69,15.27 U106.114 ; v1(54.36,34.12) 54.17,33.94 C642.2 54.17,33.31 54.09,33.23 U106.48 ; 152.73,40.45 J35.121 152.73,39.31 ; C571.2 150.96,90.78 v1(151.16,90.59) ; v1(200.41,27.43) 200.64,27.2 J38.7 ; 157.62,39.31 J35.122 157.62,40.45 ; v1(150.67,132.84) 150.6,132.84 150.03,133.41 R398.2 ; J35.17 157.54,44.74 v1(157.04,45.24) ; 163.97,40.45 J35.123 163.97,39.31 ; U101.3 v1(56.99,47.69) ; C687.1 102.01,76.68 102.23,76.45 v1(102.23,76.45) ; C657.2 44.55,20.09 v1(44.39,19.92) ; C349.1 22.1,131.83 v1(21.84,131.57) ; U102.13 124.03,44.35 v1(124.78,43.6) ; U85.1 81.93,109.16 v1(81.49,109.6) 81.36,109.47 81.36,108.67 U85.16 ; v1(29.62,126.2) 30.42,126.2 C360.1 ; 183.97,39.31 J35.127 183.97,40.45 ; 177.62,39.31 J35.126 177.62,40.45 ; U90.3 v1(97.17,79.04) ; U97.5 41.56,58.8 v1(41.28,58.51) ; v1(60.19,30.84) 60.49,31.14 U106.64 ; v1(60.81,24.52) U106.80 ; R707.2 v1(204.88,161.66) 205.11,161.43 U109.3 ; U101.5 57.39,44.94 v1(57.21,44.77) 56.99,44.99 U101.6 ; J35.12 156.04,35.64 v1(155.7,35.31) ; J35.36 162.04,35.02 v1(161.54,34.52) ; U106.10 45.41,21.72 45.33,21.8 C654.2 v1(44.43,21.8) ; U85.11 82.33,107.85 v1(82.51,108.02) 82.73,107.79 U85.10 ; v1(47.77,24.52) U106.17 ; 168.86,40.45 J35.124 168.86,39.31 ; v1(179.2,63.12) 179.83,62.48 U115.1 ; U106.66 v1(60.81,30.12) ; C57.2 198.06,141.8 ; 198.06,135.64 C71.2 ; U82.3 v1(38.14,126.43) ; U106.55 v1(56.89,30.84)
  BOTTOM w0.254: v1(52.2,108.21) C407.2 ; v1(91.88,82.67) 91.88,82.68 91.72,82.84 C198.2 ; C408.2 v1(165.99,108.77) ; v1(53.84,78.75) 53.61,78.98 C598.2 ; v1(182.81,136.35) 182.69,136.23 C335.2 ; v1(91,89.73) 91.38,89.34 C581.2 ; C664.2 139.11,18.32 v1(138.94,18.49) 139.25,18.8 U108.3 ; C607.2 185.06,62.34 184.91,62.48 ; C450.2 136.76,101.59 v1(136.76,100.99) ; v1(182.81,81.49) 182.69,81.37 C594.2 ; 122.92,42.85 124.03,42.85 v1(124.78,43.6) ; 122.92,42.85 U102.12 ; 122.92,42.85 122.53,42.45 U102.11 ; U68.1 132.98,152.19 v1(132.75,151.96) 133.02,151.69 U68.2 ; C398.2 180.65,109.96 v1(180.41,109.72) ; v1(139.93,132.54) 139.93,132.5 140.18,132.25 C346.2 ; R652.1 v1(58.86,35.62) ; v1(185.42,56.26) 185.72,56.56 C220.2 186.07,56.57 U45.2 ; v1(60.41,99.16) C471.2 v1(61.29,99.95) ; C635.2 144.93,38.04 v1(145.1,37.87) ; v1(50.16,75.62) R560.2 R561.2 ; v1(147.16,99.39) 147.31,99.24 147.76,99.24 C482.2 ; v1(79.67,20.83) 79.9,20.6 C658.2 ; C372.2 37.35,121.36 v1(37.4,121.41) ; 138.16,36.82 137.77,36.42 U105.11 ; 138.16,36.82 U105.12 ; 138.16,36.82 139.27,36.82 v1(140.02,37.57) 139.27,38.32 U105.13 ; C447.2 180.44,102.37 v1(180.41,102.41) ; v1(54.23,75.62) R556.2 R557.2 ; v1(102.23,103.06) J32.62 J32.64 ; v1(10.09,105.54) C489.2 v1(11.37,104.61) ; v1(208.12,158.8) 207.95,158.97 C661.2 ; C388.2 v1(30.48,115.64) ; v1(46.74,128.78) 47.24,128.27 48.2,128.27 U80.4 ; J34.12 v1(44.26,47.27) ; v1(200.51,18.2) J38.25 ; v1(147.16,93.79) 146.97,93.61 C547.2 ; U73.25 v1(27.05,143.46) ; v1(151.77,17.02) 151.77,16.19 151.83,16.13 C666.1 151.51,15.81 v1(150.88,15.81) ; J38.10 v1(200.51,25.7) ; v1(153.56,98.59) 153.54,98.58 C507.2 C508.2 ; v1(180.41,88.69) 180.52,88.58 C583.2 ; C600.2 81.52,78.95 v1(81.53,78.93) ; U64.6 114.11,165.48 v1(114.36,165.73) ; C277.2 v1(130.97,163.89) ; Q14.2 v1(13.12,94.88) ; J39.33 v1(168.54,11.62) 168.54,11.14 v1(169.04,10.64) J39.34 ; C663.2 v1(145.99,19.05) ; R518.2 v1(61.29,84.08) ; C516.2 147.21,97.04 v1(147.16,96.99) ; C311.2 183.73,144.02 ; C640.2 169.21,33.95 v1(169.77,34.51) ; v1(183.87,54.27) 184.06,54.08 C619.2 ; v1(112.12,114.18) 112.3,114.36 U83.4 ; U77.E5 v1(142.42,128.81) ; v1(163,52.29) 163.05,52.24 C623.2 ; v1(147.16,102.59) 147.35,102.78 C435.2 ; v1(182.81,129.84) 182.72,129.93 C351.2 ; v1(47.35,127.81) 47.38,127.78 U80.5 ; C276.2 150.7,163.89 v1(150.73,163.86) ; v1(141.86,116.26) 141.86,115.55 R442.1 ; C364.2 180.57,123.6 v1(180.41,123.44) ; C669.2 50.01,14.52 v1(49.85,14.35) ; C281.2 v1(35.16,155.01) ; U87.2 v1(91.32,85.29) ; U96.2 189.59,62.66 v1(189.34,62.41) ; v1(188.47,106.74) 188.24,106.97 C131.2 ; C613.2 143.76,59.08 v1(143.55,58.86) ; v1(67.95,86.73) U86.3 R513.1 ; v1(52.79,96.5) C513.2 ; C176.2 188.24,93.26 v1(188.47,93.03) ; C362.2 v1(142.56,124.15) ; v1(39.98,53.91) 40.17,53.72 C621.2 ; v1(22.28,135.19) U73.1 ; C348.1 26.64,131.23 v1(26.42,131) ; C593.2 180.72,82.6 v1(180.41,82.29) ; C399.2 v1(39.11,109.65) ; R553.2 57.28,75.57 v1(57.24,75.57) ; U59.C3 U59.C4 U59.D4 185.33,170.47 184.91,170.05 ; v1(97.73,96.97) 97.79,96.97 97.79,96.97 J32.16 ; C614.2 142.26,59.08 v1(142.05,58.86) ; C586.2 58.38,87.42 v1(58.56,87.6) ; v1(103.2,137.12) 102.45,136.37 U75.14 98.79,136.37 98.06,135.64 C679.2 97.41,134.95 v1(97.48,134.87) ; v1(103.2,137.12) v1(104.22,136.11) 104.45,135.87 U75.38 ; v1(103.2,137.12) 102.45,137.87 U75.17 98.43,137.87 98.17,138.13 v1(98.17,138.81) 98.17,139.19 98.05,139.31 C330.2 ; v1(103.2,137.12) 103.45,137.37 U75.35 ; v1(127.52,150.94) 127.74,150.72 C294.2 128.15,150.69 U68.7 ; U73.35 v1(31.32,141.69) ; C448.2 141.72,101.96 v1(141.56,101.79) ; C402.2 182.69,108.8 v1(182.81,108.92) ; v1(151.54,8.22) J39.SH2 J39.SH1 ; C401.2 v1(128.17,110.22) ; Q15.2 v1(23.64,83.4) ; R673.2 204.12,161.4 204.38,161.66 v1(204.88,161.66) ; C522.2 171.2,96.75 v1(171.2,96.99) ; U60.5 156.91,174.19 C253.2 v1(156.53,175.44) ; v1(132.74,105.73) 132.44,105.42 C413.1 ; R514.2 v1(63.58,86.73) ; v1(58.25,14.35) 58.41,14.52 C668.2 ; C622.2 160.79,52.21 v1(160.66,52.07) ; U89.2 v1(145.47,78.74) ; C329.1 11.57,138.44 ; v1(129.41,101.47) 129.75,101.47 C464.2 ; C285.2 v1(121.84,153.59) ; U59.A2 186.33,173.38 186.63,173.68 C252.2 v1(186.63,175.07) ; C665.2 v1(64.73,17.46) ; U103.2 54.59,39.25 C634.2 55.01,39.27 v1(55.24,39.5) ; v1(114.36,165.73) 114.61,165.48 U64.15 116.55,165.48 116.97,165.9 116.97,165.98 ; v1(114.36,165.73) 114.61,165.98 U64.14 116.97,165.98 ; Y6.2 v1(68.88,18.66) ; v1(200.41,27.43) 200.41,27.44 200.66,27.7 J38.6 ; R418.2 v1(46.91,125.81) ; C601.2 31.64,75.73 v1(31.9,75.46) ; J32.63 J32.61 v1(102.23,83.25) ; C682.2 v1(187.41,168.91) ; Q11.2 v1(62.51,101.35) ; v1(166.54,10.77) v1(166.54,11.62) J39.29 ; 130.43,118.54 C377.2 129.64,117.67 ; C585.2 183.8,88.51 v1(183.61,88.69) ; v1(122.54,97.03) R483.2 R484.2 ; C313.2 v1(123.13,142.99) ; C319.1 v1(19.15,142.28) ; U67.7 146.1,153.35 C289.2 145.7,153.38 v1(145.47,153.61) ; C453.2 v1(58.56,100.87) ; R526.1 143.92,80.64 143.38,80.64 v1(143.08,80.95) ; C322.1 34.44,141.27 v1(34.65,141.48) ; R676.1 v1(147.63,14.17) ; U93.7 180.01,69.66 179.98,69.69 C604.2 179.04,69.69 178.88,69.85 v1(178.87,69.85) ; J41.16 v1(131.35,8.26) ; v1(180.41,116.12) 180.58,115.95 C385.2 ; C82.2 188.18,134.4 188.41,134.18 v1(188.47,134.18) ; U80.3 v1(47.35,128.78) ; v1(144.16,63.55) 144.15,63.56 U95.9 ; v1(143.96,96.99) 144.14,96.81 C519.2 ; C389.2 v1(57.79,114.62) ; C534.2 147.28,95.27 v1(147.16,95.39) ; v1(132.99,12.51) 132.82,12.68 C671.2 ; v1(143.96,92.19) 143.97,92.19 C555.2 ; C332.2 180.6,136.97 v1(180.41,137.15) ; J39.16 160.04,7.13 ; C344.2 v1(19.18,131.49) ; C660.2 v1(42.82,19.26) ; R680.2 v1(201.41,161.4) ; J39.SH4 v1(171.04,10.92) J39.SH3 ; J41.40 v1(119.35,5.97) ; v1(22.28,141.19) U73.13 ; C272.2 117.34,165.98 116.97,165.98 ; J41.41 v1(140.75,5.47) ; 131.44,100.53 v1(131.44,100.43) 131.44,100.23 131.19,99.97 C480.2 ; v1(129.86,43.91) 129.69,44.08 C631.2 ; v1(156.78,119.13) 156.78,119.12 C375.2 ; v1(109.69,140.46) C323.2 v1(108.9,141.34) ; C615.2 57.76,55.99 v1(57.99,56.22) ; J40.3 v1(57.98,7.66) ; v1(208.12,160.94) 207.94,160.76 C662.2 ; v1(151.96,93.79) 151.78,93.96 C540.2 ; R417.2 v1(32.73,125.75) ; v1(168.83,46.62) C628.2 v1(169.5,45.9) ; 9.53,133.73 9.53,133.17 9.85,132.84 C342.2 ; R567.2 33.35,74.3 v1(33.08,74.57) ; Q13.2 v1(22.62,99.65) ; v1(158.36,96.99) 158.01,97.33 C504.2 ; v1(81.17,111.01) 81.38,110.8 C397.2 ; C626.2 v1(54.21,46.8) ; v1(182.81,88.69) 182.72,88.79 C579.2 ; C629.2 v1(54.21,45.8) ; C383.2 v1(130.06,116.2) ; v1(64.4,25.55) 64.1,25.25 C650.2 ; v1(147.16,92.19) 147.53,92.57 C550.2 ; v1(147.16,92.19) 146.94,91.97 C563.2 ; v1(147.16,92.19) 147.63,91.72 C565.2 ; R544.1 v1(151.72,78.74) ; v1(62.91,169.02) 63,168.94 U62.4 ; C502.2 151.65,98.29 v1(151.96,98.59) ; v1(34.96,108.2) C404.2 v1(35.75,107.33) ; C337.2 19.18,135.64 v1(18.67,136.14) 18.8,136.27 18.8,136.27 19.02,136.5 C331.1 ; C577.2 54.02,90.33 v1(53.84,90.51) ; v1(30.64,146.85) 30.64,146.85 30.44,146.65 C305.1 ; R536.2 157.23,79.08 v1(157.32,78.98) 156.59,78.98 156.34,79.23 C595.2 ; v1(125.98,151.07) C298.2 126.04,150.34 C297.2 ; v1(55.04,56.11) 55.16,55.99 C616.2 ; J39.13 158.54,13.34 158.79,13.59 ; C587.2 v1(168.53,85.4) ; C400.2 v1(38.06,109.65) ; C391.2 v1(130.06,115.19) ; v1(182.81,102.41) 182.72,102.5 C434.2 ; v1(172.88,86.1) Y4.4 ; C357.2 42.24,128.27 42.24,128.27 42.19,128.22 v1(42.19,128.2) 42.08,128.09 C359.1 ; R535.2 158.24,79.27 v1(158.53,78.98) ; C394.2 v1(43.83,112.56) ; U114.2 v1(164.43,6.98) ; v1(152.59,5.33) C676.1 v1(151.8,6.22) ; v1(142.36,96.99) 142.1,97.25 C511.2 ; C386.2 v1(157.04,116.9) ; v1(180.41,143.55) 180.48,143.49 C315.2 ; v1(39.12,121.41) 39.07,121.36 C371.2 ; C646.2 v1(65.81,29.86) ; v1(10.92,134.87) 10.53,134.87 10.27,134.62 U76.3 ; v1(199.07,32.42) C643.2 v1(198.35,31.75) ; R431.1 67.86,117.02 U84.8 v1(67.86,114.59) ; R639.1 v1(39.18,40.8) ; C647.2 63.97,28.44 v1(64.14,28.27) ; C672.2 74.04,11.16 v1(73.7,10.82) ; C267.2 168.74,167.15 U63.1 ; v1(120.44,156.6) 120.44,156.59 120,156.15 U65.4 ; C578.2 52.61,90.33 v1(52.79,90.51) ; J38.22 v1(200.51,19.7) ; C307.2 v1(108.19,143.95) ; v1(160.68,48.26) 160.46,48.03 C625.2 ; C653.2 C651.2 v1(64.53,23.46) ; C409.2 v1(164.85,108.77) ; C677.2 167.74,4.74 v1(168.02,5.02) ; J35.126 v1(174.63,39.88) J35.125 v1(170.05,39.88) J35.124 J36.61 v1(167.14,39.88) J35.123 J36.63 v1(160.41,39.88) J35.122 J36.64 v1(154.43,39.88) J35.121 J36.62 ; R509.2 v1(45.52,87.52) ; v1(170.87,148.74) 171.06,148.55 C302.2 171.53,148.52 U69.7 ; R641.2 v1(36.89,40.8) ; C395.2 v1(108.84,112.02) ; J39.22 163.04,9.98 v1(163.81,10.75) ; C221.2 192.01,57.65 v1(192.28,57.91) ; 129.64,119.42 C374.2 130.43,120.29 ; J39.19 161.54,13.34 161.29,13.59 158.79,13.59 ; C590.2 v1(45.21,84.52) ; v1(182.81,143.55) 182.46,143.9 C312.2 ; v1(182.81,95.21) 182.69,95.09 C538.2 ; v1(157,168.54) 157.17,168.38 C263.2 ; v1(168.33,108.27) C410.2 v1(167.45,109.06) ; C345.2 v1(106.77,131.94) ; C306.1 24.94,146.65 25.14,146.85 v1(25.14,146.85) ; C618.2 159.98,54.49 C620.2 160.66,53.72 160.71,53.78 v1(161.22,53.78) 161.27,53.83 C617.2 ; C378.2 v1(30.48,117.14) ; U77.C1 147.57,130.81 147.66,130.72 v1(147.7,130.72) ; v1(198,27.57) C649.2 198.93,27.77 C648.2 ; v1(147.64,49.21) 147.64,49.21 147.41,49.44 C624.1 ; v1(157.79,16.42) 157.79,14.6 158.79,13.59 ; C352.2 106.01,129.4 106.24,129.63 C350.2 v1(106.93,130.25) ; v1(136.81,119.42) C373.2 v1(136.02,120.29) ; C512.2 v1(53.84,96.5) ; C308.2 v1(108.19,145.1) ; v1(183.61,116.12) 183.72,116.01 C387.2 ; J39.10 157.04,7.12 ; R343.2 v1(109.97,164.98) ; R653.2 v1(57.13,35.15) ; U73.10 21.97,139.69 22.29,140.01 v1(22.29,140.02) 22.12,140.19 U73.11 ; v1(108.95,135.64) C318.2 ; C588.2 v1(45.21,86.02) ; C466.2 v1(45.21,100.99) ; C392.2 v1(43.83,114.02) ; U112.2 v1(135.06,16.13) 135.35,15.84 R669.1 ; C424.2 v1(45.21,103.98) ; U63.11 167.27,168.37 v1(167.48,168.57) ; FL7.2 v1(23,173.72) ; U111.11 142.07,14.9 v1(142.06,14.91) ; C675.1 152.14,7.68 152,7.54 v1(152,7.22) ; v1(31.32,135.69) U73.47 ; J41.34 v1(122.35,8.26) ; R454.1 v1(67.86,107.27) ; R471.2 v1(122.54,100.08) ; C288.2 v1(168.4,152.37) ; v1(147.16,100.99) 147.2,100.95 C458.2 ; v1(186.81,102.41) 186.28,102.93 R462.1 ; v1(155.16,98.59) 155.61,98.13 C505.2 C506.2 ; v1(128.13,106.63) 128.13,106.63 127.88,106.38 C412.2 ; v1(57.28,51.29) 57.26,51.28 U98.8 ; C510.2 144.8,98.55 v1(144.76,98.59) ; R677.2 64.58,14.99 v1(64.9,15.3) ; C477.2 v1(58.56,99.41) ; v1(155.42,7.24) 155.06,7.6 155.06,7.6 155.04,7.62 J39.6 155.04,10.68 155.05,10.69 155.05,10.97 155.54,11.46 J39.7 ; R621.1 v1(61.4,53.47) ; FL15.1 v1(198.7,33.35) ; v1(135.06,20.64) 135.43,21.01 C656.2 ; R497.2 v1(122.54,90.93) ; v1(41.34,107.33) C403.2 v1(42.13,108.2) ; v1(151.16,96.19) 151.13,96.17 C525.2 ; J34.20 v1(49.34,47.27) ; v1(58.56,86.14) 58.38,85.96 C589.2 ; C328.2 198.06,137.73 ; R452.1 v1(86.27,109.6) ; R394.1 132.65,134.09 132.5,133.93 ; R473.2 v1(12.42,104.88) ; v1(145.55,132.33) U77.B3 ; C324.1 19.15,138.76 v1(18.99,138.59) 18.69,138.3 R388.1 ; v1(81.53,76.45) 81.2,76.12 C602.2 ; C637.1 110.89,35.86 v1(110.67,35.64) ; Q8.2 v1(21.91,166.42) ; v1(188.41,79.31) 188.18,79.54 C206.2 ; v1(151.33,35.14) 151.96,35.14 C639.2 ; v1(151.31,34.23) 151.6,34.23 C641.2 ; C636.2 144.93,36.14 v1(145.1,35.97) ; D14.2 v1(22.22,163.58) ; v1(136.81,117.67) C376.2 v1(136.02,118.54) ; C499.2 v1(43.75,97.51) ; C645.2 63.97,30.17 v1(64.18,30.38) ; C655.2 v1(42.82,21.8) ; R428.2 v1(139.68,120.74) ; v1(163.7,88.96) 163.91,89.17 C580.2 ; C291.2 v1(32.54,152.34) ; J35.22 v1(158.54,35.43) ; U84.16 v1(58.97,111.6) ; Y4.2 v1(170.14,89.43) ; C355.2 183.7,129.75 v1(183.61,129.84) ; v1(83.52,111.13) 83.31,110.91 C396.2 ; C599.2 51.91,78.98 v1(52.13,78.75) ; U110.9 80.77,16.51 v1(80.52,16.76) ; J34.8 v1(41.72,47.31) ; R622.1 146.69,53.44 v1(146.49,53.24) 146.06,52.8 U99.25 ; U98.9 55.76,51.28 v1(55.75,51.29) ; C414.2 147.27,104.3 v1(147.16,104.19) ; C382.2 v1(136.33,116.2) ; J35.127 186.81,39.88 v1(186.95,40.02) 187.09,39.88 J35.128 ; C611.2 42.41,61.52 v1(42.8,61.91) 43.18,61.53 C610.2 ; J40.9 v1(56.71,4.66) ; C406.2 53.8,108.21 53.85,108.26 v1(53.87,108.26) ; C608.2 192.01,62.95 v1(192.17,63.1) ; v1(22.28,142.19) U73.15 ; C633.2 48.66,39.66 v1(48.43,39.88) ; R546.2 v1(25.07,78.55) ; v1(168.98,35.54) 168.83,35.39 C638.2 ; R596.1 v1(143.4,65.9) ; U95.8 142.65,63.56 v1(142.64,63.55) ; R679.1 v1(137.68,14.15) ; U100.11 187.69,49.62 v1(187.68,49.61) ; C446.2 v1(45.21,102.48) ; Q10.2 v1(70.13,106.08) ; v1(183.87,46.55) 184.05,46.72 C627.2 ; C659.1 v1(65.6,18.91) ; C596.1 150.78,80.23 151,80.45 v1(151,80.48) ; C584.2 v1(168.53,89.57) ; R315.1 v1(60.9,35.62) ; U67.1 150.78,154.85 v1(150.7,154.94) ; v1(46.02,134.14) C341.2 44.97,132.08 v1(44.96,132.07) ; U107.1 v1(39.62,22.54) ; C564.1 164.37,90.95 v1(164.54,90.78) ; U71.1 v1(84.32,142.12) ; C259.2 155.89,169.55 v1(155.7,169.74) ; C339.2 v1(13.55,134.79) ; C380.2 182.72,116.22 v1(182.81,116.12) ; J34.10 v1(42.99,47.27) ; C393.2 v1(30.48,114.14) ; C582.2 64.68,89.05 v1(64.45,89.28) ; v1(18.92,140.15) 19.15,140.38 C321.1 ; v1(20.08,106.86) C405.2 v1(17.48,106.86) ; v1(129.86,42) 129.69,42.17 C632.2 ; Q12.2 v1(26.43,99.66) ; C299.2 v1(13.72,146.77) ; v1(61.69,174.5) C254.2 v1(60.76,173.22) ; C644.2 v1(200.09,32.12) ; C560.2 142.95,91.6 v1(143.16,91.39) ; J41.25 v1(126.85,8.26) ; J34.16 v1(46.8,47.27) ; v1(65.6,23.46) C652.1 66.88,22.41 Y6.4 ; C592.2 v1(45.21,83.02) ; J38.13 v1(200.51,24.2) ; C316.2 101.66,148.21 v1(101.98,148.53) ; C264.2 v1(112.14,168.35) ; C354.2 180.54,129.71 v1(180.41,129.84) ; C603.2 90.69,74.81 v1(90.42,74.55) ; C99.2 188.24,120.69 v1(188.47,120.46) ; C528.2 180.6,95.82 v1(180.41,96.01) ; R125.2 107.09,115.05 v1(106.69,114.66) ; v1(50.29,94.11) 50.6,94.42 C529.2 ; R456.2 v1(21.21,106.85) ; U74.3 v1(160.14,139.13) ; v1(22.28,137.19) U73.5 ; U66.6 v1(30.39,155.51) ; C317.2 v1(106.05,143.06) ; C384.2 v1(158.24,116.89) ; C509.2 146.64,98.31 v1(146.36,98.59) ; C287.2 v1(171.77,152.44) ; R409.1 v1(40.21,129.35) ; J41.42 v1(117.45,5.52) ; C325.1 v1(109.33,138.97) ; U73.51 v1(29.55,134.42) ; v1(34.65,137.59) 34.65,137.59 34.44,137.8 C326.1 ; C390.2 v1(136.33,115.06) ; C576.1 v1(171.25,90.11) ; C347.1 v1(31.47,131) ; J35.35 v1(162.04,44.32) ; U70.7 161.21,148.27 C304.2 160.81,148.3 v1(160.59,148.53) ; R648.1 v1(145.83,35.08) ; R453.1 v1(66.59,107.3) ; v1(53.94,14.55) 53.77,14.71 C667.2 ; v1(124.97,156.15) R30.2 ; Q17.2 v1(23.19,75.63) ; U104.3 v1(113.34,38.93) ; C501.2 138.47,97.1 v1(138.36,96.99) ; R353.2 v1(25.92,158.76) ; J35.30 v1(160.54,35.43) ; C282.2 v1(24.04,155.41) ; C379.2 v1(110.72,116.92) ; J41.7 v1(135.85,8.26) ; R350.2 v1(29.1,158.78) ; Q9.2 v1(12.21,110.32) ; v1(143.96,93.79) 143.77,93.61 C548.2 ; U91.4 84.45,80.71 84.2,80.45 v1(84.2,79.78) ; U93.2 v1(186.41,70.66) ; v1(83.31,21.79) R659.1 R660.1 ; v1(200.51,13.7) J38.34 ; C369.2 182.69,122.52 v1(182.81,122.64) ; C570.1 v1(171.32,91.31) ; C674.2 v1(139.95,9.2) ; v1(128.99,100.53) 129.23,100.53 C481.1 ; C449.2 183.8,102.22 v1(183.61,102.41) ; C630.2 v1(169.36,44.89) ; Q16.2 v1(13.29,89.92) ; C500.2 148.11,98.01 148.69,98.59 v1(148.76,98.59) 148.96,98.39 C503.2 ; v1(42.52,65.89) 42.65,65.76 C215.2 ; R195.1 v1(108.05,97.81) ; R524.2 v1(61.29,81.03) ; v1(200.51,16.7) J38.28 ; v1(160.91,135.13) 161.1,135.32 C334.2 ; J38.19 v1(200.51,21.2) ; U113.3 v1(77.09,9.82) ; C314.2 v1(124.42,142.95) ; C353.2 v1(42.67,130.05) ; v1(139.95,10.11) C673.2 ; J38.16 v1(200.51,22.7) ; C278.2 v1(179.74,160.98) ; J32.57 v1(103.53,86.47) ; C258.2 v1(153.54,169.52) ; J40.5 v1(60.52,7.66)
  BOTTOM w0.381: v1(96.14,21.59) B1.2 v1(99.03,23.85) ; J9.3 102.17,123.77 C336.2 ; v1(14.61,143.51) C77.1 v1(13.54,142.16)
  BOTTOM w0.457: U94.5 33.56,67.73 v1(34.09,67.2)
  vias: v1(7.75,177.04) v1(7.75,174.5) v1(7.75,171.96) v1(7.75,169.42) v1(7.75,167.64) v1(7.75,151.64) v1(7.75,149.1) v1(7.75,126.24) v1(7.75,123.7) v1(7.75,121.16) v1(7.75,118.62) v1(7.75,116.08) v1(7.75,113.54) v1(7.75,111) v1(7.75,108.46) v1(7.75,105.92) v1(7.75,103.38) v1(7.75,95.76) v1(7.75,93.22) v1(7.75,90.68) v1(7.75,88.14) v1(7.75,85.6) v1(7.75,83.06) v1(7.75,80.52) v1(7.75,77.98) v1(7.75,75.44) v1(7.75,72.9) v1(7.75,70.36) v1(7.75,67.82) v1(7.75,65.28) v1(7.75,62.74) v1(7.75,60.2) v1(7.75,57.66) v1(7.75,55.12) v1(7.75,52.58) v1(7.75,50.04) v1(7.75,47.5) v1(7.75,44.96) v1(7.75,42.42) v1(7.75,39.88) v1(7.75,37.34) v1(7.75,34.8) v1(7.75,32.26) v1(7.75,29.72) v1(7.75,27.18) v1(7.75,24.64) v1(7.75,22.1) v1(7.75,19.56) v1(7.75,17.02) v1(7.75,14.48) v1(7.75,11.94) v1(7.75,9.4) v1(7.75,6.86) v1(7.75,4.32) v1(7.75,0.76) v1(10.29,177.04) v1(10.29,0.76) v1(12.83,177.04) v1(12.81,144.92) v1(12.83,0.76) v1(12.96,146.11) v1(14.17,162.59) v1(14.4,165.58) v1(15.37,177.04) v1(15.34,164.69) v1(15.37,163.58) v1(15.37,162.61) v1(15.37,0.76) v1(17.91,177.04) v1(17.91,0.76) v1(20.45,177.04) v1(20.45,0.76) v1(21.59,151.64) v1(21.59,150.62) v1(21.59,149.61) v1(21.59,148.59) v1(22.23,106.98) v1(22.61,151.64) v1(22.61,150.62) v1(22.61,149.61) v1(22.99,177.04) v1(22.99,0.76) v1(23.62,151.64) v1(23.62,150.62) v1(25.53,177.04) v1(25.53,0.76) v1(28.07,177.04) v1(28.07,0.76) v1(28.43,129.77) v1(28.43,129.13) v1(28.43,128.5) v1(29.35,114.97) v1(30.61,177.04) v1(30.61,0.76) v1(30.78,74.7) v1(30.78,73.68) v1(30.78,72.67) v1(30.78,71.65) v1(31.8,74.7) v1(31.8,73.68) v1(31.8,72.67) v1(31.8,71.65) v1(32.77,82.17) v1(33.15,177.04) v1(33.15,0.76) v1(33.78,83.69) v1(34.56,69.34) v1(34.56,68.33) v1(34.8,86.87) v1(35.05,117.42) v1(35.05,116.4) v1(35.05,115.39) v1(35.05,114.37) v1(35.05,113.35) v1(35.57,69.34) v1(35.57,68.33) v1(35.69,177.04) v1(35.69,0.76) v1(35.94,85.47) v1(36.07,117.42) v1(36.07,116.4) v1(36.07,115.39) v1(36.07,114.37) v1(36.07,113.35) v1(36.07,82.17) v1(36.2,83.69) v1(36.59,69.34) v1(36.59,68.33) v1(37.08,117.42) v1(37.08,116.4) v1(37.08,115.39) v1(37.08,114.37) v1(37.08,113.35) v1(38.1,117.42) v1(38.1,116.4) v1(38.1,115.39) v1(38.1,114.37) v1(38.1,113.35) v1(38.23,177.04) v1(38.23,0.76) v1(39.12,117.42) v1(39.12,116.4) v1(39.12,115.39) v1(39.12,114.37) v1(39.12,113.35) v1(40.77,177.04) v1(40.77,0.76) v1(43.31,177.04) v1(43.31,0.76) v1(43.57,123.91) v1(43.57,122.89) v1(43.57,121.88) v1(44.59,123.91) v1(44.59,122.89) v1(44.59,121.88) v1(45.61,123.91) v1(45.61,122.89) v1(45.61,121.88) v1(45.85,177.04) v1(45.85,0.76) v1(46.13,129.74) v1(46.13,128.78) v1(46.13,127.81) v1(46.62,123.91) v1(46.62,122.89) v1(46.62,121.88) v1(46.74,129.74) v1(46.74,127.81) v1(47.35,129.74) v1(48.39,177.04) v1(48.39,0.76) v1(49.78,104.27) v1(49.78,103.25) v1(49.78,102.23) v1(49.78,101.22) v1(49.78,100.2) v1(49.78,86.8) v1(49.78,85.79) v1(49.78,84.77) v1(49.78,83.76) v1(49.78,82.74) v1(50.8,104.27) v1(50.8,103.25) v1(50.8,102.23) v1(50.8,101.22) v1(50.8,100.2) v1(50.8,86.8) v1(50.8,85.79) v1(50.8,84.77) v1(50.8,83.76) v1(50.8,82.74) v1(50.93,177.04) v1(50.93,0.76) v1(51.82,104.27) v1(51.82,103.25) v1(51.82,102.23) v1(51.82,101.22) v1(51.82,100.2) v1(51.82,86.8) v1(51.82,85.79) v1(51.82,84.77) v1(51.82,83.76) v1(51.82,82.74) v1(52.83,104.27) v1(52.83,103.25) v1(52.83,102.23) v1(52.83,101.22) v1(52.83,100.2) v1(52.83,86.8) v1(52.83,85.79) v1(52.83,84.77) v1(52.83,83.76) v1(52.83,82.74) v1(53.47,177.04) v1(53.47,0.76) v1(53.85,104.27) v1(53.85,103.25) v1(53.85,102.23) v1(53.85,101.22) v1(53.85,100.2) v1(53.85,86.8) v1(53.85,85.79) v1(53.85,84.77) v1(53.85,83.76) v1(53.85,82.74) v1(55.75,53.32) v1(55.75,52.3) v1(56.01,177.04) v1(56.01,0.76) v1(56.51,53.32) v1(56.51,52.3) v1(56.51,51.29) v1(57.28,53.32) v1(57.28,52.3) v1(58.55,177.04) v1(58.55,0.76) v1(61.09,177.04) v1(61.09,0.76) v1(61.98,132.33) v1(61.98,131.32) v1(61.98,130.3) v1(61.98,129.29) v1(61.98,128.27) v1(62.91,170.8) v1(62.91,169.91) v1(62.99,132.33) v1(62.99,131.32) v1(62.99,130.3) v1(62.99,129.29) v1(62.99,128.27) v1(63.63,177.04) v1(63.63,0.76) v1(64.01,132.33) v1(64.01,131.32) v1(64.01,130.3) v1(64.01,129.29) v1(64.01,128.27) v1(65.02,132.33) v1(65.02,131.32) v1(65.02,130.3) v1(65.02,129.29) v1(65.02,128.27) v1(66.17,177.04) v1(66.17,0.76) v1(68.71,177.04) v1(68.71,0.76) v1(69.72,132.33) v1(69.72,131.32) v1(69.72,130.3) v1(69.72,129.29) v1(69.72,128.27) v1(70.74,132.33) v1(70.74,131.32) v1(70.74,130.3) v1(70.74,129.29) v1(70.74,128.27) v1(70.87,98.81) v1(71.25,177.04) v1(71.25,0.76) v1(71.75,132.33) v1(71.75,131.32) v1(71.75,130.3) v1(71.75,129.29) v1(71.75,128.27) v1(72.52,143.76) v1(72.52,141.73) v1(72.52,140.72) v1(72.52,139.7) v1(72.77,132.33) v1(72.77,131.32) v1(72.77,130.3) v1(72.77,129.29) v1(72.77,128.27) v1(72.9,98.81) v1(73.28,152.46) v1(73.28,151.45) v1(73.28,150.43) v1(73.28,149.42) v1(73.28,148.4) v1(73.28,147.38) v1(73.53,143.76) v1(73.53,142.75) v1(73.53,140.72) v1(73.53,139.7) v1(73.79,177.04) v1(73.79,0.76) v1(74.3,152.46) v1(74.3,151.45) v1(74.3,150.43) v1(74.3,149.42) v1(74.3,148.4) v1(74.3,147.38) v1(74.55,143.76) v1(74.55,142.75) v1(74.55,141.73) v1(74.55,140.72) v1(74.55,139.7) v1(75.31,152.46) v1(75.31,151.45) v1(75.31,150.43) v1(75.31,149.42) v1(75.31,148.4) v1(75.31,147.38) v1(76.33,177.04) v1(76.33,152.46) v1(76.33,151.45) v1(76.33,150.43) v1(76.33,149.42) v1(76.33,148.4) v1(76.33,147.38) v1(76.33,0.76) v1(77.34,152.46) v1(77.34,151.45) v1(77.34,150.43) v1(77.34,149.42) v1(77.34,148.4) v1(77.34,147.38) v1(78.87,177.04) v1(78.87,0.76) v1(79.5,17.78) v1(79.5,16.76) v1(79.5,15.75) v1(80.52,17.78) v1(80.52,15.75) v1(81.41,177.04) v1(81.41,0.76) v1(81.53,17.78) v1(81.53,16.76) v1(81.53,15.75) v1(83.95,177.04) v1(83.95,0.76) v1(86.49,177.04) v1(86.49,0.76) v1(89.03,177.04) v1(89.03,0.76) v1(89.85,167.58) v1(89.85,166.56) v1(90.87,167.58) v1(90.87,166.56) v1(91.57,177.04) v1(91.57,0.76) v1(91.88,167.58) v1(91.88,166.56) v1(92.9,167.58) v1(92.9,166.56) v1(93.92,167.58) v1(93.92,166.56) v1(94.11,177.04) v1(94.11,0.76) v1(94.93,167.58) v1(94.93,166.56) v1(96.65,177.04) v1(96.75,2.31) v1(96.75,0.79) v1(99.19,177.04) v1(101.73,177.04) v1(102.18,138.14) v1(102.18,137.12) v1(102.18,136.11) v1(103.2,138.14) v1(103.2,136.11) v1(104.01,145.8) v1(104.22,138.14) v1(104.22,137.12) v1(104.27,177.04) v1(106.81,177.04) v1(107.44,8.06) v1(108.14,131.45) v1(109.3,132.93) v1(109.35,177.04) v1(109.35,0.76) v1(109.47,8.06) v1(110.31,65.82) v1(110.31,64.81) v1(110.31,63.79) v1(111.07,65.82) v1(111.07,63.79) v1(111.89,177.04) v1(111.84,65.82) v1(111.84,64.81) v1(111.84,63.79) v1(111.89,0.76) v1(113.86,166.24) v1(113.86,165.73) v1(113.86,165.23) v1(114.43,177.04) v1(114.36,166.24) v1(114.36,165.23) v1(114.43,0.76) v1(114.87,166.24) v1(114.87,165.73) v1(114.87,165.23) v1(116.97,177.04) v1(116.97,0.76) v1(118.63,169.74) v1(118.63,168.72) v1(118.63,167.7) v1(119.51,177.04) v1(119.51,0.76) v1(119.65,169.74) v1(119.65,168.72) v1(119.65,167.7) v1(120.66,169.74) v1(120.66,168.72) v1(120.66,167.7) v1(122.05,177.04) v1(122.05,0.76) v1(122.22,121.54) v1(122.22,116.48) v1(122.58,126.8) v1(122.68,151.09) v1(123,44.36) v1(123,43.6) v1(123,42.84) v1(123.06,108.51) v1(123.71,151.09) v1(123.76,144.74) v1(123.89,44.36) v1(123.89,43.6) v1(123.89,42.84) v1(123.98,128.22) v1(124.33,122.81) v1(124.28,113.11) v1(124.4,125.48) v1(124.59,177.04) v1(124.57,120.35) v1(124.59,0.76) v1(124.78,44.36) v1(124.78,42.84) v1(125.73,125.6) v1(125.67,44.36) v1(125.67,43.6) v1(125.67,42.84) v1(126.56,44.36) v1(126.56,43.6) v1(126.56,42.84) v1(126.8,104.78) v1(126.87,131.04) v1(127.13,177.04) v1(127.13,0.76) v1(127.76,122.81) v1(127.76,121.28) v1(127.76,116.2) v1(127.76,114.43) v1(128.17,125.07) v1(128.63,132.82) v1(128.91,168.78) v1(128.91,128.78) v1(128.93,106.05) v1(129.67,177.04) v1(129.67,0.76) v1(130.05,123.72) v1(130.43,127.38) v1(130.4,120.29) v1(130.4,118.54) v1(130.61,110.79) v1(131.29,135.48) v1(131.44,125.5) v1(132.08,131.95) v1(132.21,177.04) v1(132.21,0.76) v1(132.48,121.26) v1(132.49,112.34) v1(132.59,65.47) v1(132.59,54.04) v1(133.22,123.98) v1(133.29,61.66) v1(133.29,60.39) v1(133.48,130.43) v1(134.57,125.22) v1(134.62,102.67) v1(134.75,177.04) v1(134.77,128.83) v1(134.75,0.76) v1(135.26,135.13) v1(135.56,100.61) v1(135.89,132.84) v1(136.27,137.03) v1(136.63,127.51) v1(136.65,111.89) v1(137.29,177.04) v1(137.29,0.76) v1(137.39,131.44) v1(137.54,168.45) v1(137.86,116.26) v1(138.3,135.25) v1(138.24,38.33) v1(138.24,37.57) v1(138.24,36.8) v1(138.56,167.44) v1(138.73,140.03) v1(139,165.47) v1(139,164.45) v1(138.94,137.3) v1(139.13,38.33) v1(139.13,37.57) v1(139.13,36.8) v1(139.6,133.45) v1(139.83,177.04) v1(139.83,0.76) v1(140.02,165.47) v1(140.02,164.45) v1(140.02,38.33) v1(140.02,36.8) v1(140.21,138.56) v1(140.59,137.31) v1(140.91,38.33) v1(140.91,37.57) v1(140.91,36.8) v1(141.03,165.47) v1(141.03,164.45) v1(141.63,141.94) v1(141.63,140.67) v1(141.8,38.33) v1(141.8,37.57) v1(141.8,36.8) v1(141.86,143.89) v1(141.86,143) v1(141.86,139.83) v1(141.86,135.64) v1(142.05,165.47) v1(142.05,164.47) v1(142.08,52.07) v1(142.08,51.05) v1(142.08,50.04) v1(142.06,16.94) v1(142.06,15.93) v1(142.37,177.04) v1(142.37,0.76) v1(142.64,62.66) v1(142.64,61.77) v1(142.82,16.94) v1(142.82,15.93) v1(142.82,14.91) v1(143.07,165.47) v1(143.07,164.47) v1(143.1,52.07) v1(143.1,51.05) v1(143.1,50.04) v1(143.4,63.55) v1(143.4,62.66) v1(143.4,61.77) v1(143.57,168.39) v1(143.57,167.37) v1(143.59,16.94) v1(143.59,15.93) v1(143.59,14.91) v1(143.95,143.64) v1(143.95,142.6) v1(144.02,139.83) v1(144.02,137.79) v1(144.11,52.07) v1(144.11,51.05) v1(144.11,50.04) v1(144.23,141.99) v1(144.16,62.66) v1(144.16,61.77) v1(144.25,140.74) v1(144.59,167.37) v1(144.91,177.04) v1(144.91,0.76) v1(145.42,135.56) v1(146.88,0.76) v1(147.24,141.6) v1(147.24,140.69) v1(147.42,137.54) v1(147.45,177.04) v1(147.45,143) v1(149.56,143.23) v1(149.61,136.91) v1(149.66,142.52) v1(149.76,65.46) v1(149.86,141.73) v1(149.86,140.59) v1(149.99,177.04) v1(150.67,65.48) v1(151.97,139.4) v1(151.97,135.61) v1(152.53,177.04) v1(152.53,0.76) v1(155.07,177.04) v1(155.07,0.76) v1(156.4,172.03) v1(156.72,7.11) v1(157.42,172.03) v1(157.61,177.04) v1(157.56,109.73) v1(157.61,0.76) v1(158.24,7.11) v1(158.59,141.27) v1(159.77,7.11) v1(160.15,177.04) v1(160.15,0.76) v1(161.04,94.74) v1(161.16,7.11) v1(162.69,177.04) v1(162.69,7.11) v1(162.69,0.76) v1(165.23,177.04) v1(165.23,0.76) v1(165.54,102.45) v1(166.53,102.45) v1(167.45,96.99) v1(167.45,95.37) v1(167.77,177.04) v1(167.77,0.76) v1(168.26,171.07) v1(168.26,170.05) v1(168.47,96.99) v1(168.47,95.37) v1(169.28,171.07) v1(169.28,170.05) v1(169.28,169.04) v1(169.28,168.02) v1(170.18,102.81) v1(170.31,177.04) v1(170.31,0.76) v1(172.85,177.04) v1(173.86,47.24) v1(175.39,177.04) v1(175.84,0.76) v1(177.93,177.04) v1(177.93,0.76) v1(178.18,29.59) v1(178.94,46.51) v1(179.07,53.85) v1(179.2,49.53) v1(180.09,28.7) v1(180.47,177.04) v1(180.47,0.76) v1(184.14,169.54) v1(184.14,168.53) v1(184.14,167.51) v1(184.82,62.76) v1(185.16,169.54) v1(185.16,168.53) v1(185.16,167.51) v1(185.65,51.13) v1(185.65,50.37) v1(185.65,49.61) v1(186.66,51.13) v1(186.66,50.37) v1(186.66,49.61) v1(187.68,51.13) v1(187.68,50.37) v1(188.09,177.04) v1(188.09,0.76) v1(190.63,177.04) v1(190.63,0.76) v1(193.17,177.04) v1(193.17,0.76) v1(195.71,177.04) v1(195.71,0.76) v1(196.26,133.74) v1(196.26,126.17) v1(196.26,113.86) v1(196.26,101.03) v1(196.41,87.91) v1(197.35,159.47) v1(197.35,158.36) v1(197.81,87.91) v1(198.03,133.74) v1(198.03,126.17) v1(198.03,113.86) v1(198.03,101.03) v1(198.25,177.04) v1(198.25,0.76) v1(200.79,177.04) v1(200.79,0.76) v1(203.33,177.04) v1(203.33,0.76) v1(205.87,177.04) v1(205.87,0.76) v1(209.42,177.04) v1(209.42,174.5) v1(209.42,171.96) v1(209.42,169.42) v1(209.42,166.88) v1(209.42,164.34) v1(209.42,161.8) v1(209.42,159.26) v1(209.42,156.72) v1(209.42,154.18) v1(209.42,151.64) v1(209.42,149.1) v1(209.42,146.56) v1(209.42,144.02) v1(209.42,141.48) v1(209.42,138.94) v1(209.42,136.4) v1(209.42,133.86) v1(209.42,131.32) v1(209.42,128.78) v1(209.42,126.24) v1(209.42,123.7) v1(209.42,121.16) v1(209.42,118.62) v1(209.42,116.08) v1(209.42,113.54) v1(209.42,111) v1(209.42,108.46) v1(209.42,105.92) v1(209.42,103.38) v1(209.42,100.84) v1(209.42,98.3) v1(209.42,95.76) v1(209.42,93.22) v1(209.42,90.68) v1(209.42,88.14) v1(209.42,85.6) v1(209.42,83.06) v1(209.42,80.52) v1(209.42,77.98) v1(209.42,75.44) v1(209.42,72.9) v1(209.42,70.36) v1(209.42,67.82) v1(209.42,65.28) v1(209.42,62.74) v1(209.42,60.2) v1(209.42,57.66) v1(209.42,55.12) v1(209.42,52.58) v1(209.42,50.04) v1(209.42,47.5) v1(209.42,44.96) v1(209.42,42.42) v1(209.42,39.88) v1(209.42,37.34) v1(209.42,34.8) v1(209.42,32.26) v1(209.42,29.72) v1(209.42,27.18) v1(209.42,24.64) v1(209.42,22.1) v1(209.42,19.56) v1(209.42,17.02) v1(209.42,14.48) v1(209.42,11.94) v1(209.42,9.4) v1(209.42,6.86) v1(209.42,4.32) v1(209.42,0.76)
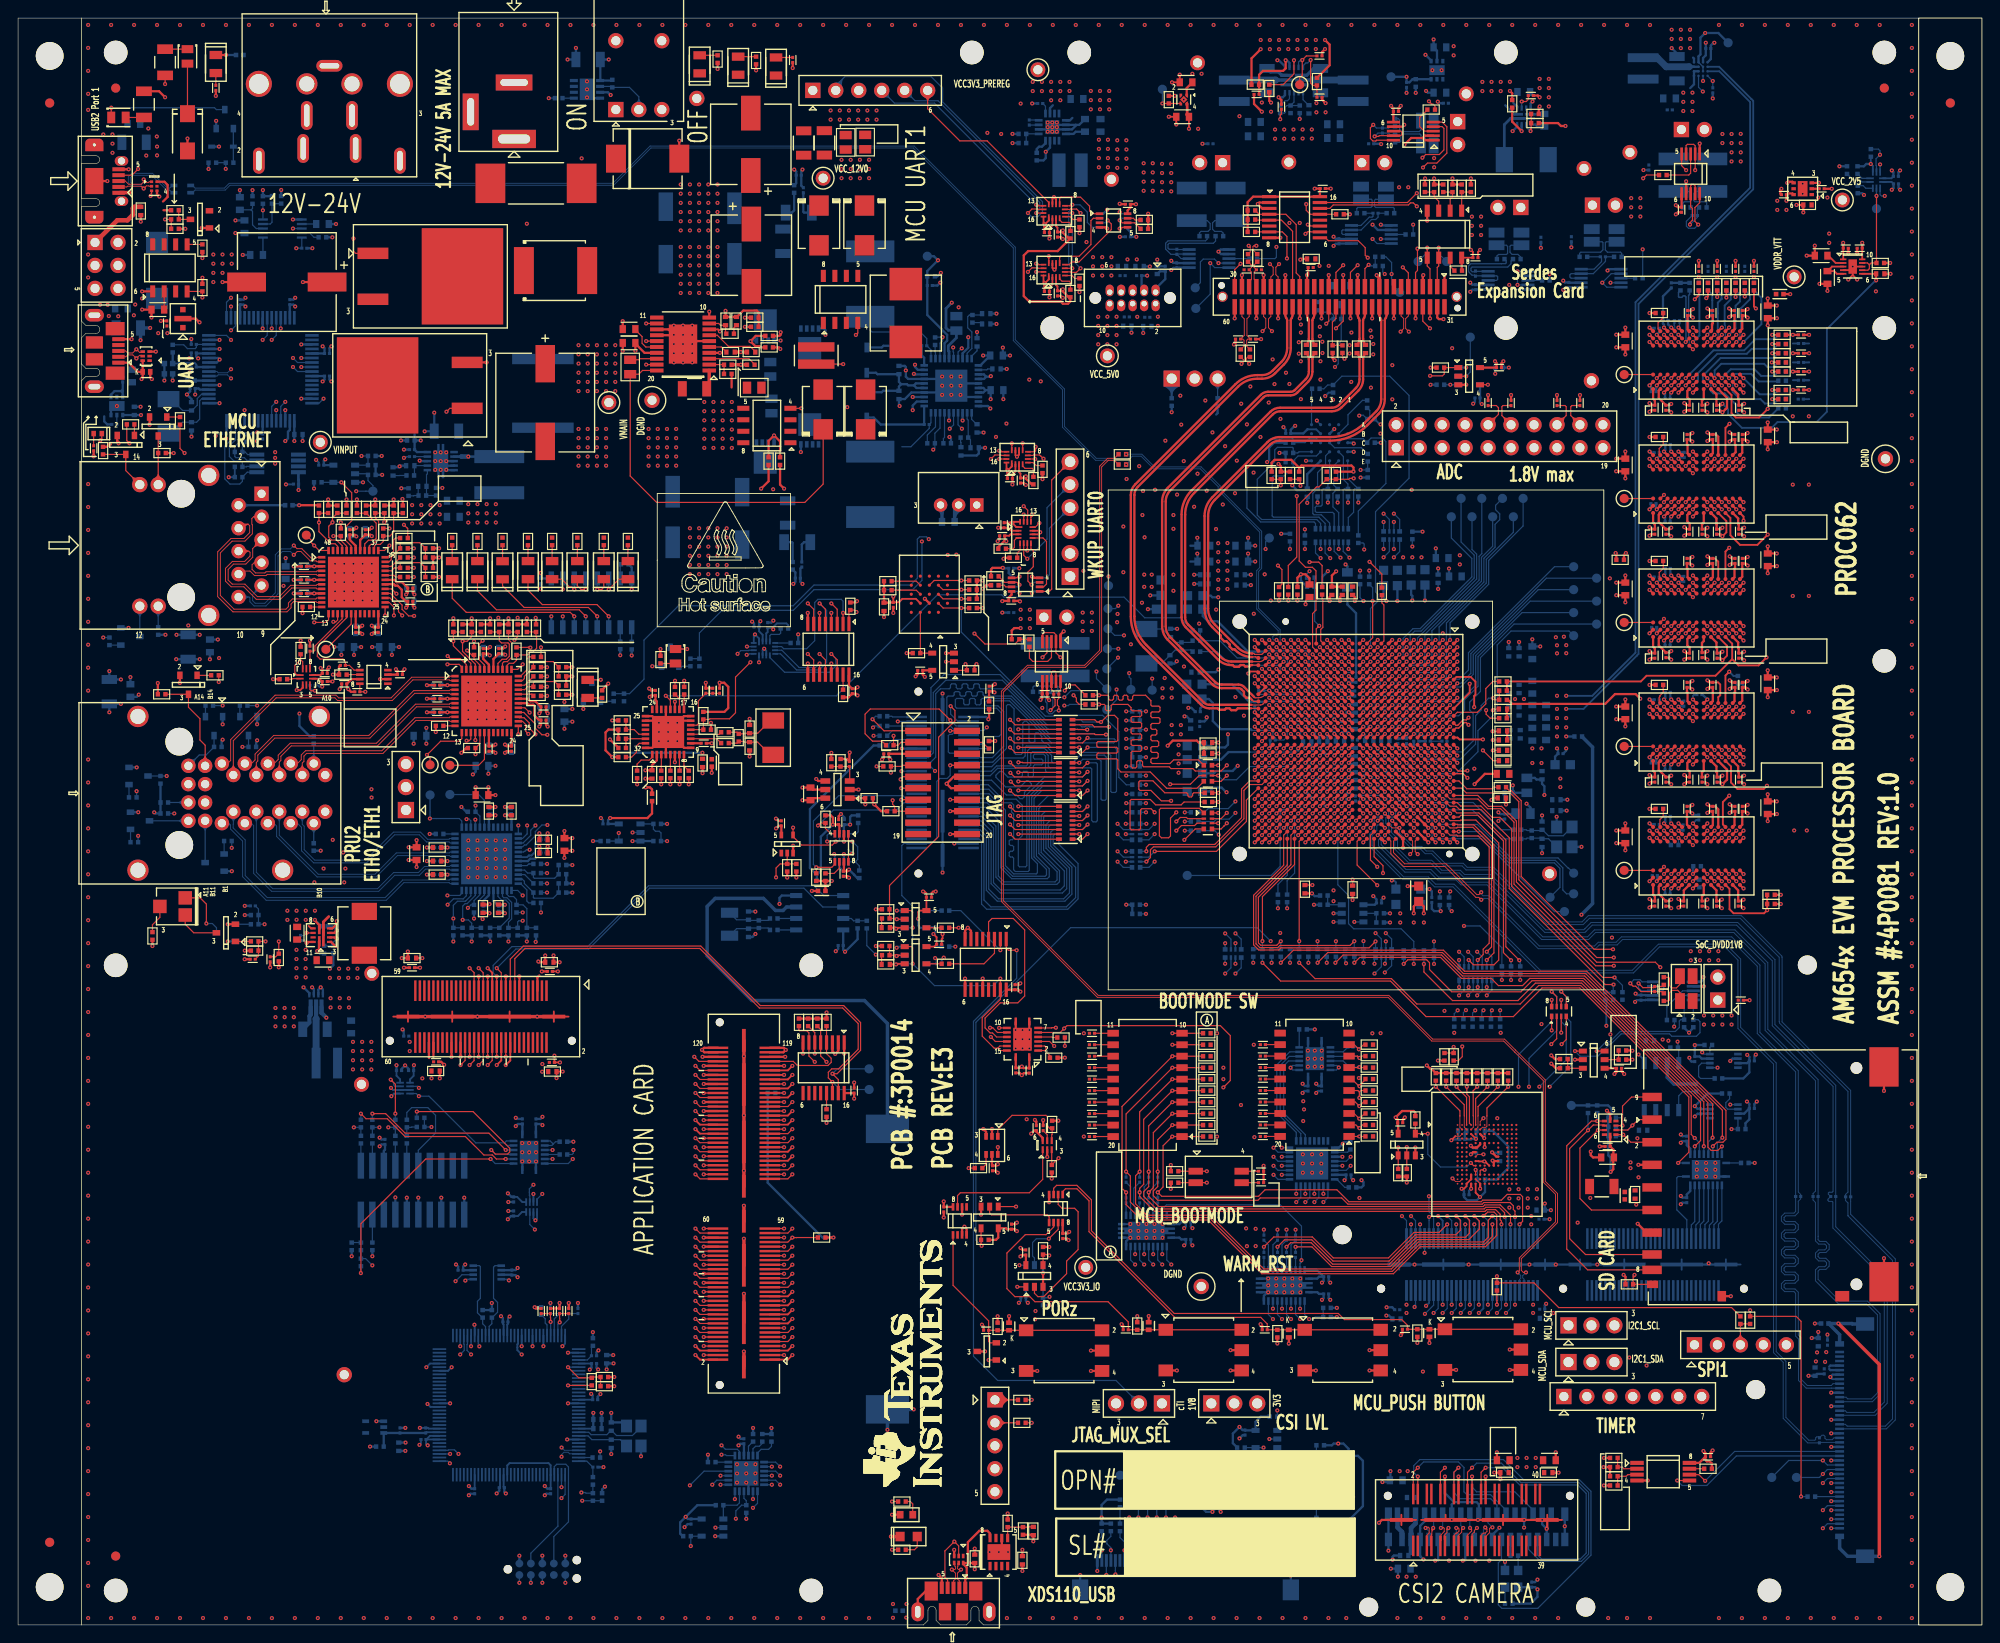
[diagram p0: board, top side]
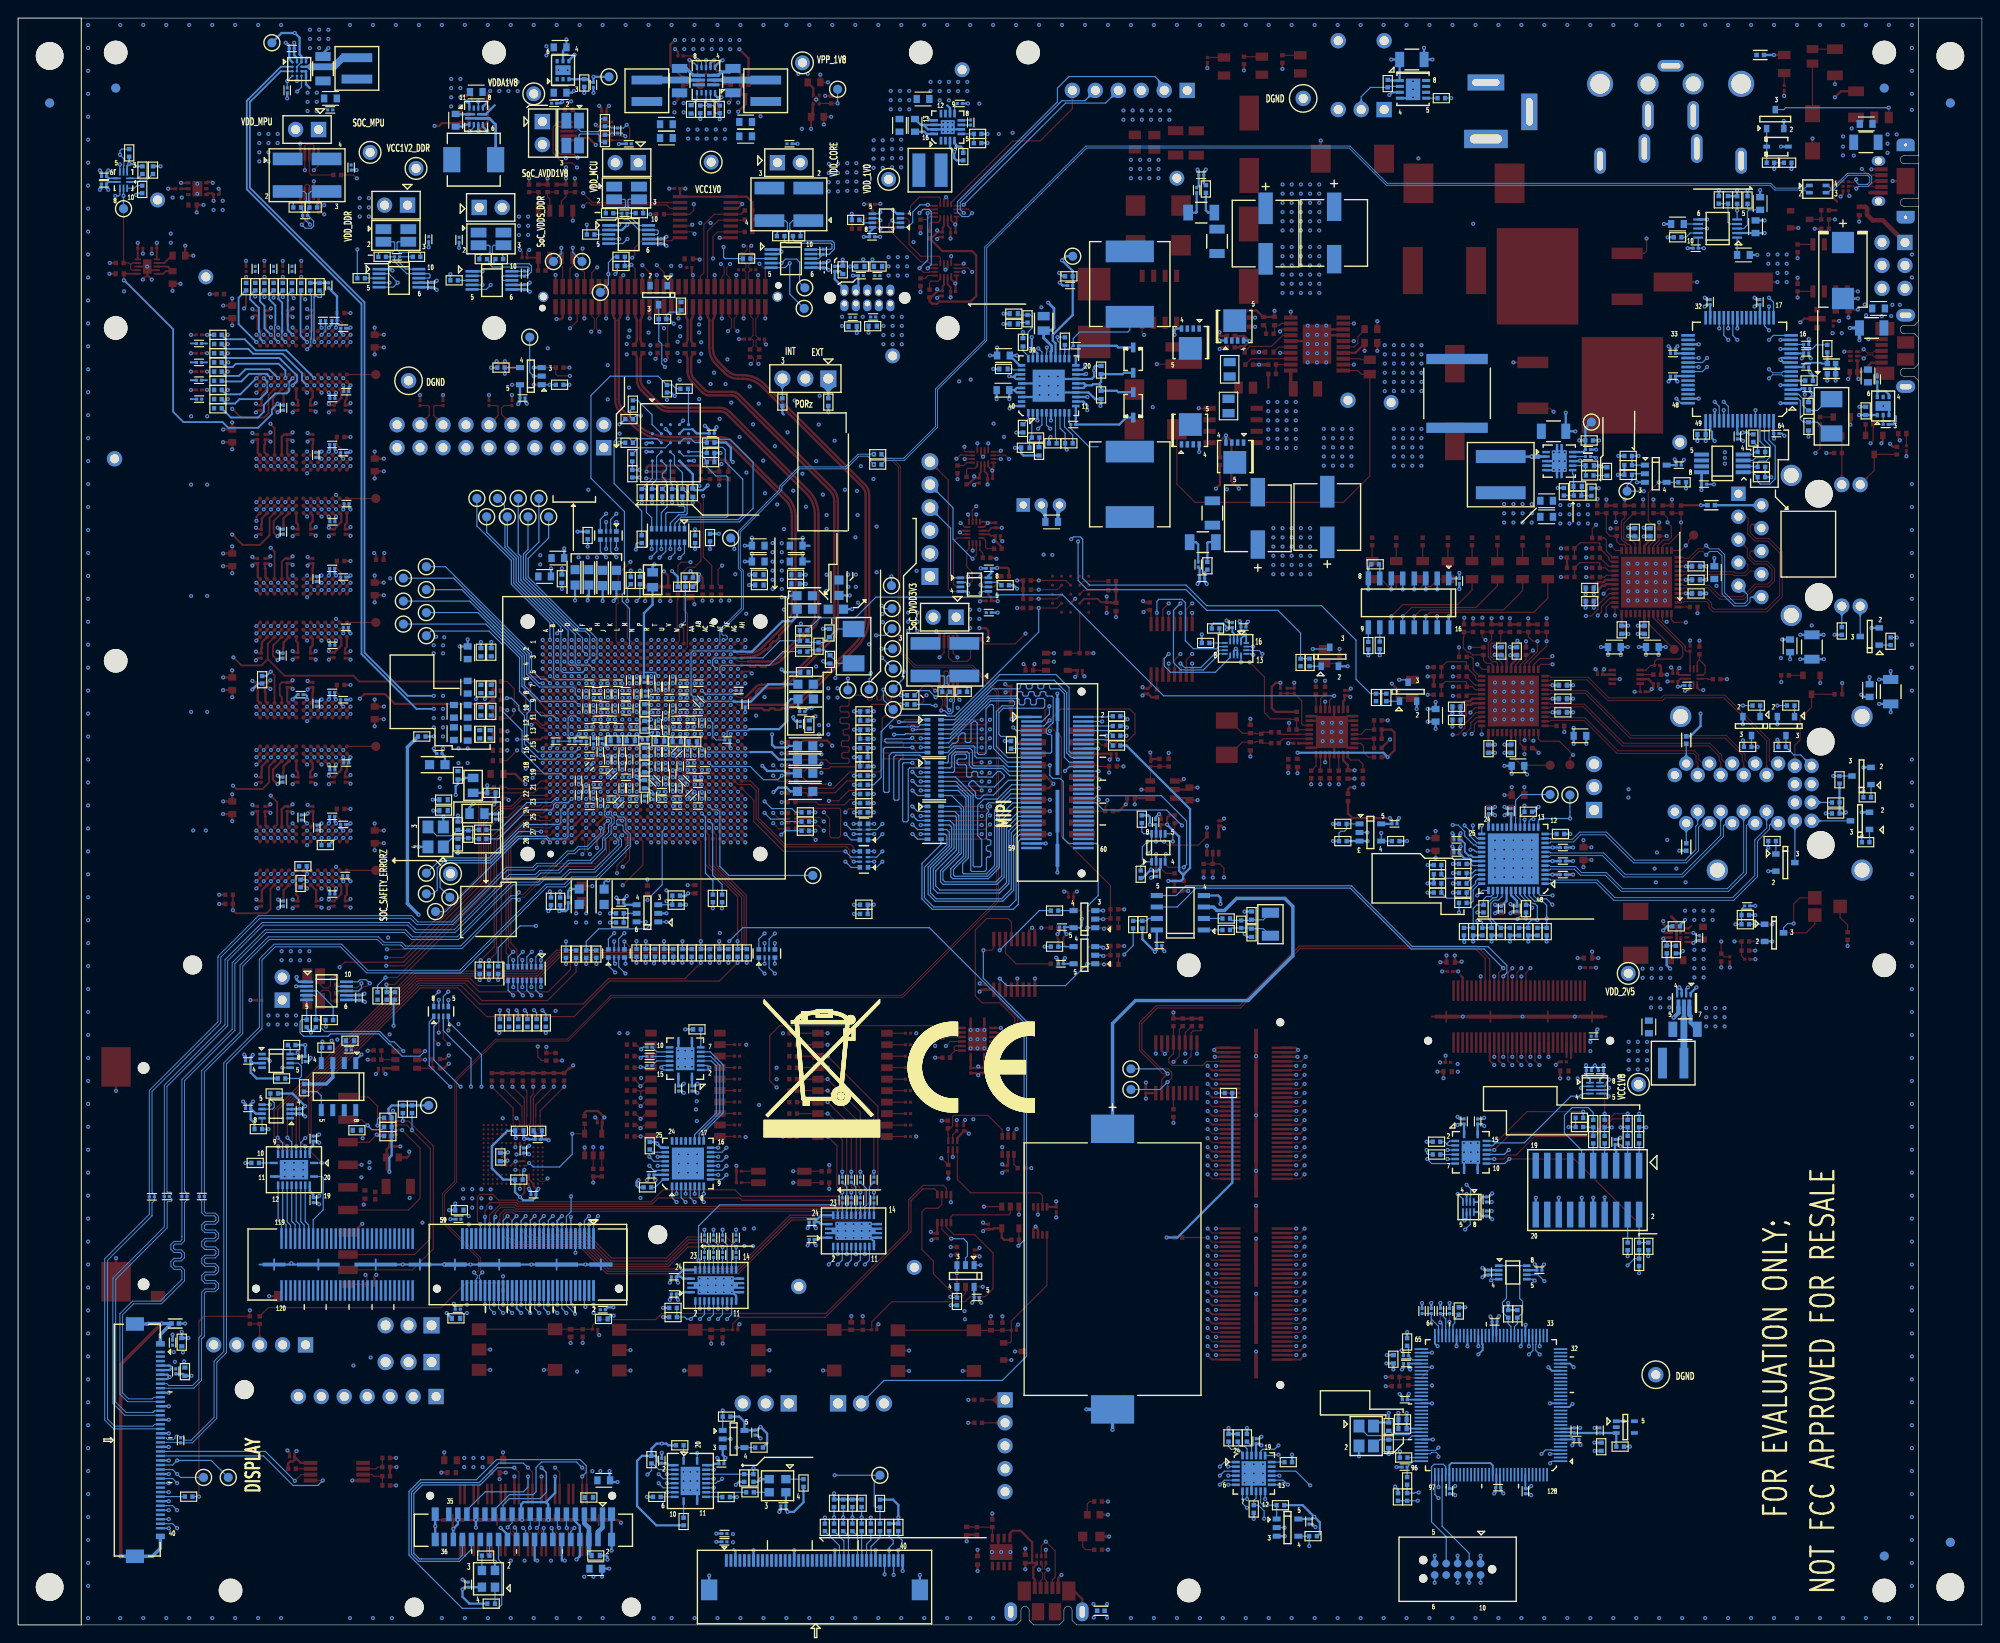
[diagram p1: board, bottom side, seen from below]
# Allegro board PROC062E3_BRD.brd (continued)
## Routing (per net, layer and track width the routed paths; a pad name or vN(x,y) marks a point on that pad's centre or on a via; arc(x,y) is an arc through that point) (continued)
GNDUSB:
  vias: v1(9.07,146.08) v1(9.91,146.08) v1(10.03,144.83) v1(11.07,144.81)
VCC1V0: length 7.2
  TOP w0.254: v1(139.4,169.04) 139.7,168.73 C4.1
  L08_PWR3 w0.254: v1(139.4,169.04) 137.16,169.04 v1(135.06,166.94)
  BOTTOM w0.254: v1(139.4,169.04) 139.87,169.04 140.1,169.27 U61.16
VCC1V2_DDR: length 4.7
  TOP w0.254: R16.1 170.29,166.18 170.61,165.86 v1(171.12,165.86)
  BOTTOM w0.254: U63.3 167.79,166.02 168.01,165.8 C267.1
VCC1V2_PG: length 3.8
  TOP w0.254: v1(166.27,165.29) 165.23,166.34 R12.1
  BOTTOM w0.254: U63.5 v1(166.27,165.29)
VCC1V8: length 255.8
  TOP w0.203: C41.1 114.94,148.11 114.78,148.26 U12.3 ; v1(159.63,48.26) 159.9,48.26 160.18,48.55 U51.P3 U51.N4 ; U29.7 33.45,105.1 C134.1 ; C21.1 114.94,154.62 114.78,154.78 U6.3 ; v1(161.67,47.35) 161.18,47.83 U51.P5
  TOP w0.254: R307.2 v1(90.17,42.87) ; v1(53.84,79.68) 53.8,79.72 C209.1 ; FL5.1 v1(87.78,81.22) ; R93.1 v1(36.32,124.54) ; R149.1 v1(32.28,108.92) ; C186.1 v1(52.79,89.59) ; R198.2 49.55,97.03 v1(49.02,96.5) ; U30.3 41.88,105.15 41.88,105.16 C135.1 41.95,105.59 v1(41.78,105.75) ; v1(52.79,97.42) 52.61,97.24 C162.1 U31.19 ; R167.1 R163.1 v1(61.29,104.96) ; v1(33.46,105.88) 33.46,105.88 33.66,105.69 33.66,105.31 C134.1 ; v1(52,92.7) C178.1 v1(52.79,91.82) ; 116.36,146.91 116.19,146.91 115.54,147.56 v1(115.54,147.79) 115.36,147.62 C41.1 ; 116.36,146.91 116.36,146.45 116.11,146.19 115.54,146.19 115.3,146.43 111.82,146.43 111.21,147.04 111.21,151.54 111.7,152.02 114.96,152.02 116.36,153.42 ; 116.36,146.91 R51.2 ; R156.1 35.49,106.03 R160.1 v1(34.82,105.15) ; U22.41 37.83,120.05 38.39,120.61 C102.1 38.39,120.63 38.97,120.63 v1(39.12,120.48) ; v1(65.47,89.28) 69.6,89.28 70.1,89.79 FL4.1 ; v1(56.26,111.39) R145.2 R144.1 ; U22.19 C123.1 37.88,110.39 v1(38.06,110.57) ; U51.C6 162.14,53.87 v1(162.14,53.87) ; v1(123.62,157.2) C16.1 123.01,156.84 122.69,156.52 U8.8 ; R94.1 v1(37.47,124.54) ; R288.2 154.52,56.68 154.34,56.86 153.04,56.86 v1(152.34,56.16) 152.56,55.93 C230.1 152.56,55.31 152.62,55.26 U48.5 ; R27.2 v1(147.27,156.09) ; R119.1 R115.1 v1(46.56,118.11) ; v1(155.79,61.91) 156.16,61.54 156.29,61.54 156.77,61.06 R262.1 R263.1 R264.1 R265.1 R266.1 R267.1 R268.1 R269.1 ; v1(53.87,107.35) 53.75,107.47 C126.1 53.15,107.46 52.57,106.88 U31.41 ; C216.1 v1(44.45,72.72) ; R140.1 R141.1 v1(52.2,111.39) ; 116.36,153.42 R35.2 ; 116.36,153.42 116.19,153.42 115.54,154.07 v1(115.54,154.31) 115.36,154.13 C21.1 ; C192.1 v1(57.64,87.6) ; R151.2 v1(50.42,108.85) ; v1(57.64,99.41) 57.82,99.59 C155.1 57.59,100.13 57.09,100.64 57.09,101.69 56.95,101.82 56.47,101.82 56.31,101.99 55.32,101.99 ; R100.2 v1(35.69,122) ; v1(110.45,43.57) 110.24,43.79 C237.1 109.36,43.79 109.26,43.89 U53.5 108.39,42.86 108.14,42.61 R308.2 ; C213.1 v1(44.7,73.79) ; v1(41.53,124.54) R98.2 R97.1 ; R137.1 v1(48.13,111.39) ; U22.30 40.61,115.16 41.55,115.16 41.72,114.99 41.98,114.99 42.43,114.54 42.43,113.72 42.86,113.28 C120.1 43.09,112.74 v1(42.91,112.56) ; U51.M4 U51.N4 ; v1(31.08,123.9) 33.24,123.9 R90.1
  L03_SIG1 w0.203: v1(207.21,160.94) 207.69,160.46 207.69,149.15 206.11,147.57 v1(205.45,147.57)
  BOTTOM w0.203: v1(175.64,66.29) 175.64,69.05 R741.1 ; 142.58,132.29 143.55,132.29 U77.B4 ; U85.3 82.73,109.71 82.89,109.87 C396.1 ; R447.2 85.17,110.62 84.96,110.82 83.91,110.82 83.51,110.42 v1(83.51,110.16) ; C662.1 207.16,160.07 U109.6 ; v1(144.55,135.97) 144.93,136.36 R33.2 ; C586.1 57.59,86.88 57.18,86.46 57.18,85.55 56.78,85.14 56.52,85.14 56.5,85.13 56.47,85.13 56.29,84.95 55.38,84.95 U88.30
  BOTTOM w0.254: R246.2 186.82,58.8 v1(185.42,57.4) 185.71,57.12 C220.1 186.1,57.07 U45.3 ; FL14.1 v1(33.46,85.67) ; v1(162.14,53.87) 162.19,53.92 C617.1 163.07,54.67 164.78,52.96 164.78,50.55 163.51,49.28 R625.1 162.22,47.9 v1(161.67,47.35) 161.31,46.99 160.26,46.99 159.9,47.35 C625.1 159.9,48 v1(159.63,48.26) ; U74.5 C334.1 161.66,135.29 v1(161.86,135.09) ; v1(83.51,110.16) 83.32,110.35 C396.1 ; U86.5 C582.1 65.24,89.05 v1(65.47,89.28) ; v1(33.97,128.97) 33.81,128.8 C358.1 U82.5 ; J6.3 124.25,147.75 C300.1 v1(124.86,149.3) ; U100.2 184.91,52.7 184.53,53.08 C619.1 184.05,53.52 v1(183.87,53.35) ; C400.1 v1(38.06,110.57) ; R562.1 v1(48.13,75.62) ; R403.2 v1(150.7,130.81) ; v1(39.12,120.48) 39.08,120.44 C371.1 ; v1(191.21,63.08) 191.45,62.84 C608.1 ; R423.2 v1(144.84,124.19) ; R624.2 v1(192.04,51.12) ; v1(52.2,75.62) R558.1 R559.1 ; v1(52.79,89.59) 52.61,89.77 C578.1 U88.19 ; v1(111.67,35.64) 111.45,35.87 C637.2 U104.5 ; U77.E4 142.56,127.33 C362.1 142.38,125.56 141.43,125.56 v1(140.9,126.1) ; U114.4 C677.1 167.78,4.18 v1(168.02,3.94) 168.02,3.11 167.27,2.36 R700.1 ; v1(207.21,160.94) 207.38,160.77 C662.1 ; U94.3 33.21,70.29 v1(33.46,70.55) 33.71,70.31 U94.4 ; R421.2 v1(147.07,124.19) ; v1(61.29,82.05) R522.1 R520.1 ; v1(90.17,42.87) 88.96,42.87 82.9,48.93 R605.2 ; FL11.1 v1(31.08,123.9) ; R411.2 R406.2 v1(139.5,129.68) ; v1(141.22,132.68) 141.13,132.59 141.08,132.59 140.74,132.25 C346.1 142.13,131.84 142.58,132.29 ; R647.2 v1(114.03,35.37) ; R422.2 v1(145.92,124.19) ; R555.1 R554.2 v1(56.26,75.62) ; R604.2 190.79,60.47 191.45,61.13 C608.1 ; C394.1 v1(42.91,112.56) ; v1(37.15,107.33) C404.1 v1(37.94,108.2) ; v1(52,94.18) C529.1 v1(52.79,95.06) ; FL12.1 32.25,98.33 31.11,99.47 v1(31.11,100.84) ; C295.1 v1(125.16,150.31) ; R498.2 49.55,89.98 v1(49.02,90.51) ; C586.1 57.82,87.42 v1(57.64,87.6) ; C608.1 191.2,62.16 U96.3 ; v1(53.87,107.35) 53.66,107.35 53.6,107.29 C406.1 ; R542.2 v1(50.42,78.16) ; U88.41 52.57,80.11 53.12,79.55 C598.1 53.69,79.54 v1(53.84,79.68) ; R420.2 v1(148.21,124.19) ; U65.8 122.69,154.45 123.01,154.13 C285.1 v1(123.66,153.59) ; v1(148.46,126.96) R732.2 ; R385.2 v1(164.86,139.13) ; R424.2 v1(143.7,124.19) ; 154.04,7.97 C675.2 ; v1(147.7,129.81) 147.7,129.81 U77.D1 ; v1(138.13,128.68) 138.35,128.9 138.35,130.27 138.9,130.83 R402.2 ; C513.1 v1(52.79,97.42) ; C477.1 v1(57.64,99.41)
  BOTTOM w0.508: 154.04,7.97 J39.4 154.04,10.73 154.54,11.23 J39.5
  vias: v1(37.03,64.52) v1(37.03,63.5) v1(37.03,62.48) v1(37.03,61.47) v1(38.05,64.52) v1(38.05,63.5) v1(38.05,62.48) v1(38.05,61.47) v1(39.07,64.52) v1(39.07,63.5) v1(39.07,62.48) v1(39.07,61.47) v1(153.54,35.43) v1(153.54,34.52) v1(153.54,5.33) v1(154.56,5.33) v1(167.83,18.48) v1(167.83,17.46) v1(186.44,67.44) v1(186.44,66.43) v1(187.45,67.44) v1(187.45,66.43) v1(188.47,67.44) v1(188.47,66.43) v1(189.48,67.44) v1(189.48,66.43)
VCC1V8_CLKBUFF: length 8
  TOP w0.203: U32.19 v1(72.63,102.16)
  TOP w0.254: v1(69.41,92.68) 69.88,92.68 70.1,92.46 FL4.2 ; v1(69.85,102.68) 70.01,102.84 C147.1 70.48,102.34 70.63,102.19 U32.23 ; U32.6 v1(72.63,95.46) ; U32.2 70.63,95.67 70.1,95.14 C171.2 v1(69.38,94.57)
VCC1V8_MIPI: length 32.9
  TOP w0.254: R218.2 FL5.2 ; R218.2 R217.1 ; R218.2 v1(89.98,82.32) ; R214.1 89.88,89.57 90.11,89.34 v1(90.11,88.56) C188.1 90.82,88.48 U37.3
  BOTTOM w0.254: 88.33,82.99 87.57,83.76 87.57,90.27 94.6,97.31 R479.1 ; 88.33,82.99 88.33,82.57 88.58,82.32 v1(89.98,82.32) ; 88.33,82.99 88.77,83.44 88.77,87.22 v1(90.11,88.56)
VCC2V5_PG: length 2.1
  TOP w0.254: U40.5 34.98,76.57 v1(35.25,76.85)
  BOTTOM w0.254: R549.1 34.8,77.3 v1(35.25,76.85)
VCC3V3_IO: length 346.3
  TOP w0.203: v1(100.08,81.15) 100.25,81.15 100.45,80.95 C690.2 U39.5 99.7,79.04 99.54,78.88 v1(99.54,78.13) ; U21.3 109.75,120.68 109.6,120.52 C103.1 ; U41.5 101.32,75.05 C688.2 101.57,76.09 v1(101.22,76.45) ; U9.8 C685.1 160.88,151.92 v1(160.66,152.15) ; U29.6 33.32,104.7 C136.1 ; U24.B4 99.28,113.54 97.79,113.54 97.41,113.16 96.79,113.16 ; U19.3 110.69,127.56 110.85,127.4 C92.1 ; U6.2 114.38,154.86 114.06,154.53 C20.1 ; 96.79,113.16 v1(96.79,113.79) ; 96.79,113.16 C121.1
  TOP w0.254: C103.1 109.11,120.1 v1(109.28,119.92) 109.05,119.92 108.4,119.27 R113.2 ; v1(143.38,158.93) 143.45,158.93 143.45,158.94 C13.1 143.96,158.91 U7.16 U7.1 136.58,158.04 135.97,157.43 R26.2 R29.2 R36.2 ; R89.2 112.09,126.2 111.44,126.85 v1(111.44,127.09) 111.27,126.91 C92.1 ; R147.2 109.88,110.02 110.16,110.3 v1(110.87,110.3) ; U43.16 C225.1 110.85,61.64 v1(111,61.79) 111.16,61.62 C226.1 U43.1 ; v1(83.82,88.14) 83.82,88.14 84.1,88.42 C189.1 U36.5 ; v1(186.37,19.24) 186.6,19.01 C244.1 ; 57.64,71.87 57.43,71.65 J16.5 ; R330.1 R328.1 v1(175.32,17.46) ; 155.32,164.53 155.56,164.29 U2.1 ; 155.32,164.53 154.05,164.53 v1(153.29,163.77) ; 155.32,164.53 155.58,164.79 U2.2 ; 163.12,51.32 163.18,51.25 U51.K9 ; 163.12,51.32 v1(163.06,51.38) ; 163.12,51.32 U51.J10 ; v1(102.36,46.86) C236.1 U54.8 ; 141.67,128.04 141.91,128.28 147.46,128.28 147.68,128.07 v1(147.68,127.61) R88.2 ; 141.67,128.04 R84.1 ; 141.67,128.04 140.79,128.92 138.95,128.92 138.62,128.59 R81.2 ; R289.1 v1(115.04,55.79) ; v1(58.29,74.08) C227.1 57.61,73.33 v1(57.53,73.41) ; R318.2 v1(139.26,31.14) ; R213.1 95.43,90.04 v1(94.68,90.8) 94.68,90.81 94.53,90.96 R210.1 ; R283.2 v1(89.4,55.55) ; R38.1 159.64,149.9 U9.8 ; R232.1 v1(27.88,72.76) ; U55.5 C239.1 111.01,40.93 v1(110.85,40.77) ; U56.8 185.91,17.93 186.59,18.61 C244.1 ; R37.1 v1(20.38,151.24) ; R159.2 105.76,106.09 v1(105.98,106.31) ; v1(108.9,116.97) 107.76,116.97 107.59,116.8 R120.1 ; v1(163.32,139.83) 163.49,139.66 C686.1 U17.5 ; R174.1 36.8,103.25 v1(36.51,103.54) 36.35,103.71 C138.1 36.36,104.14 36.87,104.65 U30.7 ; U3.6 C18.1 183.55,156.87 v1(183.32,157.1) ; C121.1 96.34,113.15 96.3,113.11 C122.1 R127.2 R124.2 ; U27.6 113.28,103.06 C148.1 113.25,102.54 v1(113.07,102.36) ; U44.4 C224.2 176.76,61.19 v1(176.53,60.96) ; v1(123.76,34.17) R321.2 ; v1(137.73,50.8) R302.1 R306.1 ; R329.1 187.3,17.86 187.07,18.1 186.75,18.1 186.6,18.25 C244.1 ; v1(160.66,53.02) 160.86,52.82 U51.F5 161.33,52.82 161.68,53.17 U51.E6 ; R235.2 R236.2 R237.2 R238.2 v1(89.4,67.77) ; C136.1 v1(33.63,103.82) ; v1(145.59,139.94) 145.37,140.17 R58.2 ; R184.2 C144.1 107.85,103.31 v1(107.98,103.19) ; v1(108.84,113.28) 108.86,113.31 C119.1 109.55,113.68 109.87,113.99 U23.8 ; R221.2 v1(94.86,79.18) ; v1(10.16,130.68) 9.84,130.36 R78.2 ; R224.2 v1(14.86,75.12) ; C222.1 v1(57.92,72.31) ; R177.2 64.58,103.48 v1(65.26,104.16) ; U37.7 91.32,83.47 C198.1 91.7,83.4 v1(91.88,83.59) ; U46.16 C229.1 v1(92.46,58.24) ; v1(96.46,95.76) 96.29,95.92 C166.1 J13.5 ; R303.2 R304.2 v1(153.57,48.94) ; R134.1 92.63,113.14 v1(92.77,113.28) ; v1(110.84,70.08) 110.84,70.08 110.83,70.08 110.63,70.29 C217.1 U42.16 ; v1(116.23,43.49) 116.06,43.32 C238.1 U52.8 ; v1(108.34,50.98) 108.18,50.82 C234.1 107.69,50.87 U50.5 ; v1(169.55,62.1) 170.05,61.6 R261.1 ; R309.2 v1(114.03,41.82) ; FL3.1 v1(76.71,94.28) ; R153.2 v1(98.26,107.53) ; R215.2 v1(85.05,82.69) ; R66.2 v1(156.2,139.13) ; R319.2 v1(108.32,34.16) ; v1(92.83,103.76) 92.67,103.6 C146.1 91.88,103.95 U26.16 ; v1(100.27,104.9) 100.04,105.13 C133.1 U28.5 ; v1(106.69,115.57) R123.2 R126.2 R133.2 ; R155.2 v1(71.04,107.99) ; v1(156.59,160.06) R20.2 R21.1 ; R24.1 v1(160.66,160.06) ; R256.1 v1(178.51,62.55) ; v1(114.06,153.41) C20.1 ; R79.2 v1(17.21,129.67) ; R178.2 v1(15.46,104.22) ; v1(151.83,168.08) 152.09,167.82 C6.1 U2.6 ; R227.2 v1(94.86,75.12) ; R231.1 v1(25.06,73.66) ; R320.2 v1(154.74,31.2)
  L10_SIG3 w0.254: v1(114.06,153.41) 115.17,152.29 125.84,152.29 126.95,151.18 126.95,150.49 v1(127.52,149.92)
  L12_SIG4 w0.254: v1(114.06,153.41) 114.06,159.38 110.87,162.56 v1(110.87,168.34)
  BOTTOM w0.203: C626.1 55.19,47.36 55.76,46.79 U101.1 ; U109.7 207.18,159.67 C661.1 ; v1(101.22,76.45) 101.45,76.68 C687.2 100.53,77.22 U90.5 99.77,77.14 99.54,77.37 v1(99.54,78.13) ; U97.1 43.34,60.36 43.74,60.76 C610.1 ; C629.1 55.28,45.24 55.73,45.69 U101.8 ; v1(101.41,73.79) 101.57,73.62 C689.2 U92.5 ; v1(33.63,103.82) 33.3,103.82 33.16,103.96 R175.1
  BOTTOM w0.254: R667.2 v1(76.29,18.83) ; R685.2 120.42,13.86 119.82,13.27 v1(119.82,11.89) R697.1 R696.1 ; v1(122.54,79.69) R538.1 R545.1 ; v1(146.69,49.21) 146.85,49.37 C624.2 U99.31 ; U87.7 91.32,88.5 C581.1 v1(92.01,88.56) 92.01,89.41 92.18,89.57 R504.1 ; R656.2 v1(145.83,34.06) ; U84.1 C389.1 v1(57.79,116.4) ; v1(15.05,89.92) 15.18,89.79 R496.1 R501.1 R490.2 ; R270.2 191.03,55.52 191.45,55.94 C221.1 ; v1(207.21,158.8) 207.39,158.98 C661.1 ; U95.16 C613.1 143.79,59.64 v1(143.55,59.88) ; U99.27 v1(146.45,51.8) ; R698.2 73.49,9.82 73.22,10.1 73.22,11.35 v1(73.83,11.96) ; v1(144.84,116.6) 144.22,115.97 R441.2 ; v1(55.24,38.48) 55.01,38.71 C634.1 54.56,38.75 U103.3 ; C610.1 43.74,61.9 v1(43.78,61.94) ; U102.1 128.44,42.85 128.63,42.66 C632.1 129.13,42.18 v1(128.95,42) ; R412.2 R415.2 v1(40.26,127.25) ; U83.8 109.87,116.07 109.55,116.39 C379.1 108.95,116.92 v1(108.9,116.97) ; J38.4 200.4,28.7 200.28,28.57 ; R552.2 92.84,75.87 v1(91.45,74.49) 91.25,74.69 C603.1 U91.8 ; v1(139.85,18.49) 139.67,18.3 C664.1 140.18,17.83 140.32,17.68 140.33,17.68 140.34,17.68 U111.19 ; R336.2 v1(154.56,169.52) ; v1(54.16,44.89) 54.17,44.89 54.52,45.24 C629.1 ; C221.1 190.87,56.57 U45.7 ; C221.1 191.45,57.65 v1(191.18,57.91) ; R672.2 203.94,158.42 v1(204.13,158.23) ; U67.2 150.37,154.35 v1(149.78,154.94) ; v1(165.81,149.77) U70.1 ; v1(160.66,53.02) 160.91,52.77 C622.1 ; R540.1 v1(25.07,79.56) ; R664.2 134.81,19.64 134.33,20.11 134.33,21.18 v1(135.06,21.91) 135.41,21.57 C656.1 135.72,21.52 U108.5 136.85,22.49 137.41,23.05 R658.2 ; v1(175.77,149.87) 175.77,149.87 175.93,150.02 U69.1 ; v1(144.19,35.97) 144.37,36.15 C636.1 143.87,36.63 143.68,36.82 U105.1 ; R661.2 v1(81.28,21.79) ; R482.2 22.51,97.84 v1(22.62,97.95) ; J41.3 137.85,8.18 138.05,8.38 ; v1(149.86,80.64) 150.22,80.29 C596.2 150.02,79.69 U89.4 ; v1(148.56,49.21) 148.78,48.99 148.78,48.63 148.56,48.41 R630.2 ; R521.1 92.81,82.64 92.46,82.99 92.46,83.02 v1(91.88,83.59) 91.7,83.4 C198.1 90.82,83.83 U87.3 ; R419.1 v1(42.38,125.77) ; 129.12,44.56 C631.1 129.13,44.09 v1(128.95,43.91) ; 129.12,44.56 128.63,44.56 128.41,44.35 U102.24 ; 129.12,44.56 128.36,45.32 U102.23 ; R686.2 75.12,13.25 v1(73.83,11.96) ; R427.2 v1(155.31,120.97) ; J38.5 200.4,28.2 200.28,28.32 ; R449.1 v1(16.29,109.56) ; v1(73.83,11.96) 74.07,11.72 C672.1 U113.5 ; R671.1 130.31,13.58 131.38,12.51 v1(132.08,12.51) 132.26,12.69 C671.1 U112.4 ; R401.1 v1(42.34,131.06) ; v1(54.17,47.75) 54.56,47.36 C626.1 ; v1(127.52,149.92) 127.76,150.16 C294.1 128.15,150.19 U68.6 ; v1(160.59,147.51) 160.82,147.74 C304.1 161.21,147.77 U70.6 ; v1(79.67,19.87) 79.84,20.04 C658.1 U110.21 ; v1(144.19,37.87) 144.37,38.06 C635.1 ; v1(126.94,14.56) R681.2 R682.2 R683.2 R684.2 ; v1(26.43,97.88) 26.32,97.77 R481.2 ; U93.1 186.12,71.16 186.37,71.42 v1(186.37,71.69) ; U67.6 146.1,152.85 C289.1 145.71,152.82 v1(145.47,152.59) ; R687.1 v1(80.53,11.73) ; U95.1 C614.1 142.29,59.64 v1(142.05,59.88) ; R547.1 v1(151.72,77.72) ; v1(163.06,51.38) 163.12,51.32 C623.1 ; R506.2 v1(71.77,88.63) ; v1(178.81,68.94) 179.01,69.13 C604.1 179.94,69.13 179.97,69.16 U93.6 ; v1(137.8,15.49) 137.45,15.84 R668.2 ; v1(170.87,147.72) 171.14,147.99 C302.1 171.53,148.02 U69.6 ; R539.1 v1(143.31,79.69) ; U105.23 143.61,39.29 C635.1 ; U105.24 143.65,38.32 143.87,38.53 C635.1 ; R592.1 v1(184.79,65.53) 184.24,66.08 R593.1 ; R390.2 v1(156.2,137.23) ; U100.19 184.91,48.01 184.53,47.63 C627.1 184.06,47.28 v1(183.87,47.47) ; U98.1 C615.1 57.87,55.43 v1(57.99,55.31)
  BOTTOM w0.381: U115.3 182.37,60.58 183.1,59.86 R736.1
  BOTTOM w0.508: J39.1 152.54,10.79 153.04,10.29 J39.2
  vias: v1(49.78,124.02) v1(49.78,123) v1(49.78,121.98) v1(50.8,124.02) v1(50.8,123) v1(50.8,121.98) v1(51.82,124.02) v1(51.82,123) v1(51.82,121.98) v1(52.83,124.02) v1(52.83,123) v1(52.83,121.98) v1(110.87,112.33) v1(110.87,111.32) v1(111.89,112.33) v1(111.89,111.32) v1(111.89,110.3) v1(117.86,65.47) v1(117.86,54.04) v1(136.65,64.2) v1(136.72,53.98) v1(138.11,10.06) v1(138.11,9.14) v1(143.92,150.38) v1(144.94,150.38) v1(152.78,17.02) v1(153.67,17.02) v1(158.81,65.52) v1(163.96,65.52) v1(165.8,18.48) v1(165.8,17.46) v1(166.81,18.48) v1(166.81,17.46) v1(167.54,35.43) v1(167.54,34.52) v1(181.86,64.77) v1(182.5,64.64) v1(198.81,29.16) v1(199.83,29.11)
VCC3V3_PREREG: length 210.4
  TOP w0.203: 32.13,77.34 32.4,77.07 U40.8 ; C1.1 v1(129.48,165.55) ; U10.10 C23.1 ; 200.19,151.51 201,150.7 U10.2
  TOP w0.254: R4.2 144.2,174.04 v1(144.53,174.37) ; v1(164.97,169.74) 165.23,169.48 R12.2 ; C23.1 v1(203.93,152.93) ; v1(144.53,175.37) 145.03,174.87 145.03,172.58 143.65,171.2 R7.1 ; U1.4 129.29,168.3 ; v1(32.83,78.01) 32.83,77.92 33.31,77.43 U40.7 ; v1(112.03,54.36) 112.37,54.7 C231.1 112.6,54.6 113.31,53.89 U49.6 ; v1(195.56,157.59) C15.1 195.69,158.39 196.22,158.39 U5.6 ; R8.1 136.4,173.34 v1(137.41,174.36) ; R3.1 v1(81.61,172.02)
  TOP w0.305: 129.29,168.3 129.29,167.18 129.23,167.13 C1.1
  L03_SIG1 w0.254: v1(112.03,54.36) 111.08,55.31 111.08,55.76 111.08,57.8 113.84,60.56 113.84,91.57 117.21,94.94 118.46,94.94 118.51,95 v1(122.54,95)
  L05_SIG2 w0.254: v1(28.46,66.23) 28.46,55.87 37.99,46.34 58.92,46.34 69.97,57.4 76.71,57.4 83.39,64.08 89.46,64.08 89.9,63.64 89.9,62.99 90.14,62.76 90.14,61.72 89.41,60.99 89.41,60.08 95.13,54.36 v1(112.03,54.36)
  BOTTOM w0.254: R345.1 113.39,162.05 113.65,162.31 v1(113.65,163) 114.11,163.47 U64.3 ; R549.2 33.38,77.46 v1(32.83,78.01) ; 116.59,166.75 116.32,166.48 U64.13 ; R376.2 101.66,149.22 v1(102.04,149.61) ; R357.1 85.57,156.27 85.82,156.53 R702.1 ; v1(182.86,174.48) 183.45,173.89 C255.1 ; 165.35,168.4 165.77,167.98 U63.8 ; U59.A4 185.33,173.32 185.23,173.42 ; U64.10 114.11,167.83 114.43,168.15 ; R486.1 v1(122.54,95) ; 164.47,168.15 165.46,167.15 U63.7 ; v1(187.58,175.07) 187.5,175.07 187.19,174.76 C252.1 187.19,173.27 U59.A1
  BOTTOM w0.356: C257.1 138.51,171.83 139.38,171.83 139.75,171.47 U61.3 ; C256.1 143.27,172.23 142.51,171.47 U61.9
  BOTTOM w0.457: C606.1 32.21,66.65 32.21,67.36 32.36,67.51 U94.7
  vias: v1(28.46,68.26) v1(28.46,67.25) v1(29.48,68.26) v1(29.48,67.25) v1(29.48,66.23) v1(29.78,79.03) v1(29.78,78.01) v1(30.49,68.26) v1(30.49,67.25) v1(30.49,66.23) v1(30.79,79.03) v1(30.79,78.03) v1(31.81,79.03) v1(31.81,78.01) v1(32.83,79.03) v1(73.28,159.38) v1(73.28,158.37) v1(73.28,157.35) v1(73.28,156.34) v1(73.28,155.32) v1(73.28,154.31) v1(74.3,159.38) v1(74.3,158.37) v1(74.3,157.35) v1(74.3,156.34) v1(74.3,155.32) v1(74.3,154.31) v1(75.31,159.38) v1(75.31,158.37) v1(75.31,157.35) v1(75.31,156.34) v1(75.31,155.32) v1(75.31,154.31) v1(76.33,159.38) v1(76.33,158.37) v1(76.33,157.35) v1(76.33,156.34) v1(76.33,155.32) v1(76.33,154.31) v1(77.34,159.38) v1(77.34,158.37) v1(77.34,157.35) v1(77.34,156.34) v1(77.34,155.32) v1(77.34,154.31) v1(112.2,170.74) v1(112.2,169.72) v1(113.22,170.74) v1(113.22,169.72) v1(114.24,170.74) v1(114.24,169.72) v1(114.24,168.71) v1(115.25,170.74) v1(115.25,169.72) v1(115.25,168.71) v1(116.27,170.74) v1(116.27,169.74) v1(130.49,165.55) v1(137.41,175.37) v1(138.43,175.37) v1(138.43,174.36) v1(139.45,175.37) v1(139.45,174.36) v1(140.46,175.37) v1(140.46,174.37) v1(141.48,175.37) v1(141.48,174.37) v1(142.49,175.37) v1(142.49,174.37) v1(143.51,175.37) v1(143.51,174.37) v1(158.75,174.69) v1(158.75,173.67) v1(161.93,170.74) v1(161.93,169.72) v1(162.94,170.74) v1(162.94,169.72) v1(163.96,170.74) v1(163.96,169.72) v1(164.97,170.75) v1(182.86,176.51) v1(182.86,175.49) v1(183.88,176.51) v1(183.88,175.49) v1(183.88,174.48) v1(184.89,176.51) v1(184.89,175.49) v1(184.89,174.48) v1(194.54,157.59) v1(194.54,156.57) v1(195.56,156.57) v1(200.28,153.95) v1(200.28,152.93)
VCC3V3_PREREG_PG: length 313.2
  TOP w0.254: v1(195.64,159.56) 195.77,159.69 196.22,159.69 U5.4 ; v1(35.24,77.87) 35.24,77.56 34.76,77.07 U40.6
  L05_SIG2 w0.254: v1(44.41,128.83) 44.41,130.09 41.38,133.12 27.98,133.12 26.92,134.18 26.92,136.4 22.59,140.73 22.09,140.73 21.82,141 21.82,147.3 22.36,147.84 98.56,147.84 v1(101.73,151)
  L10_SIG3 w0.254: v1(195.64,159.56) 195.64,161.35 190.02,166.98 160.16,166.98 159.66,167.48 158.73,167.48 158.23,166.98 155.16,166.98 152.59,169.54 134.68,169.54 133.29,168.15 127.51,168.15 126.37,167 104.58,167 100.55,162.97 100.55,152.18 v1(101.73,151)
  L12_SIG4 w0.254: v1(35.24,77.87) 37.38,80.01 37.38,106.45 33.81,110.02 33.81,120.06 32.64,121.22 32.64,124.71 35.65,127.73 43.31,127.73 v1(44.41,128.83)
  BOTTOM w0.254: v1(44.41,128.83) 44.46,128.83 44.51,128.78 U80.8 ; U75.24 102.45,141.82 102.74,142.11 102.74,142.75 100.55,144.95 C316.1 R376.1 100.55,149.82 v1(101.73,151) 101.28,151.45 TP83.1
VCC3V3_R: length 3.5
  TOP w0.254: v1(107.3,100.21) 107.38,100.29 R184.1
  BOTTOM w0.254: v1(107.3,100.21) 107.04,100.47 J32.1
VCC3V3_XDS: length 54.1
  TOP w0.254: v1(112.27,9.26) C249.1 112.22,9.98 R334.1 ; R322.2 v1(65.93,27.43) ; R313.2 R314.2 v1(59.88,35.62) ; C251.1 v1(111.06,5.97)
  BOTTOM w0.203: 45.14,20.52 U106.7 ; 45.14,20.52 C657.1 45.11,20.06 v1(45.3,19.87) ; 45.14,20.52 45.54,20.92 U106.8 ; v1(45.28,24.45) 45.6,24.12 U106.16 ; U106.69 C647.1 ; U106.52 v1(55.69,30.84) ; v1(50.47,33.22) 50.49,33.22 U106.39 ; U106.47 53.69,33.23 53.61,33.31 C642.1 ; U97.8 42.24,60.37 41.85,60.77 C611.1 ; U106.79 C650.1 ; C668.1 U106.101 58.89,17.67 58.66,17.91 54.36,17.91 54.09,17.64 U106.113 ; U106.28 45.56,28.92 v1(45.15,28.51) ; v1(55.69,29.92) 55.21,30.41 55.21,30.7 55.21,30.7 55.21,31.04 55.29,31.12 U106.51 ; U106.90 v1(60.72,20.52) ; v1(47.94,28.51) 47.55,28.12 U106.26 ; U106.122 C669.1
  BOTTOM w0.254: R314.2 v1(59.88,35.62) ; v1(63.37,25.57) 63.54,25.4 C650.1 ; C668.1 58.54,15.08 v1(58.25,15.37) ; C669.1 50.14,15.08 v1(49.85,15.37) ; v1(65.85,28.94) C646.1 v1(65.09,28.27) ; v1(63.22,28.26) 63.41,28.45 C647.1 ; v1(53.4,34.16) 53.61,33.95 C642.1 ; v1(39.98,52.96) 40.18,53.16 C621.1 40.58,52.58 40.45,52.45 J34.5 ; v1(49.44,39.88) 49.22,39.66 C633.1 U103.7 ; v1(55.04,55.2) 55.27,55.43 C616.1 U98.16 ; R663.1 v1(38.92,19.73) ; C660.1 v1(42.85,20.18) ; R657.2 v1(63.56,32.4) ; R655.1 R654.1 v1(52.39,35.62) ; R649.2 v1(61.91,35.62) ; J40.1 v1(55.44,7.66) ; C611.1 v1(41.85,61.94)
VCC5V0_PG: length 3.4
  BOTTOM w0.132: R404.1 102.32,131.27 102.45,131.4 U75.7
VCC_1V8_FT4232: length 38.7
  L03_SIG1 w0.381: v1(19.92,140.14) 19.92,138.33 20.83,137.41 20.83,133.41 v1(22.99,131.25) 23.81,130.43 29.98,130.43 v1(30.55,131) 30.55,132.78 32.51,134.75 32.51,140.31 v1(33.68,141.48)
  BOTTOM w0.203: C349.2 22.99,131.8 v1(22.99,131.25)
  BOTTOM w0.254: C349.2 23.05,131.86 U73.64 ; v1(33.68,141.48) 33.88,141.27 C322.2 U73.37 ; U73.49 C347.2 v1(30.55,131) ; U73.12 19.77,140.69 C321.2 19.71,140.35 v1(19.92,140.14)
VCC_2V5: length 99.7
  TOP w0.254: FL1.1 v1(195.97,147.26)
  L05_SIG2 w0.381: v1(199.07,157.94) 199.07,157.37 199.07,157.37 199.07,155.25 197.31,153.49 177.75,153.49 175.68,151.43 152.11,151.43 151.38,152.15 147.45,152.15 147.09,151.79 139.04,151.79 137.59,153.24 128.99,153.24 125.79,150.04 J6.1
  L08_PWR3 w0.254: v1(199.07,157.94) 198.56,157.43 198.56,155.25 195.07,151.76 195.07,148.16 v1(195.97,147.26)
  BOTTOM w0.254: C298.1 126.27,149.78 C297.1 126.86,148.92 125.79,147.85 J6.1
  vias: v1(200.08,157.94)
VCC_3V3_FT4232: length 173.6
  TOP w0.203: C94.1 109.51,121.4 109.84,121.08 U21.2 ; U19.2 110.29,127.64 109.96,127.31 C91.1 ; C40.1 114.06,148.02 114.38,148.35 U12.2
  TOP w0.254: C40.1 v1(114.06,146.89) ; C91.1 v1(109.96,126.19) ; C94.1 v1(108.39,121.4) ; R77.1 v1(8.36,129.31)
  L03_SIG1 w0.254: v1(114.06,146.89) 111.82,146.89 111.18,146.25 111.18,133.02 109.43,131.28 109.43,130.56 109.96,130.03 v1(109.96,126.19)
  L05_SIG2 w0.254: v1(108.39,121.4) 88.38,121.4 82.09,115.11 v1(82.09,111.07)
  L10_SIG3 w0.254: v1(82.09,111.07) 80.75,109.73 48.13,109.73 40.51,102.11 35.31,102.11 34.79,102.63 30.98,102.63 28.7,104.9 28.7,125.2 29.08,125.58 v1(31.01,125.58)
  L12_SIG4 w0.254: v1(108.39,121.4) 108.39,124.61 v1(109.96,126.19)
  BOTTOM w0.203: C397.1 81.94,109.95 82.33,109.56 U85.2 ; v1(23.29,127) 23.3,127 R416.2 R413.2 ; v1(26.45,131.95) 25.91,131.95 25.69,131.74 R408.2
  BOTTOM w0.254: v1(30.64,145.88) 30.64,145.88 30.44,146.09 C305.2 U73.31 ; v1(25.14,145.88) 25.14,145.88 24.94,146.09 C306.2 U73.20 ; v1(82.09,111.07) 81.94,110.92 C397.1 ; v1(16.18,137.69) FL10.2 FL9.2 ; v1(29.55,131) 29.84,131.3 29.84,132.02 30.05,132.22 U73.50 ; U73.56 C348.2 26.61,131.79 v1(26.45,131.95) ; U73.42 C326.2 33.88,137.8 33.68,137.59 v1(33.68,137.59) ; U76.1 C339.1 v1(13.59,133.87)
  BOTTOM w0.305: v1(31.01,125.58) C360.2 31.01,126.68 31,126.69 U79.8
VCC_5V0: length 201.8
  TOP w0.254: R1.1 v1(77.36,172.17)
  L06_PWR1 w0.508: v1(198.94,30.15) 195.94,33.15 178.51,33.15 v1(167.33,44.32)
  L08_PWR3 w0.254: v1(77.36,172.17) 80.66,168.87 80.66,152.64 82.42,150.88 82.42,146.3
  L08_PWR3 w0.508: v1(16.51,142.94) 18.29,144.72 60.77,144.72 62.36,146.3 82.42,146.3 96.14,132.59
  L08_PWR3 w0.762: 95.19,77.28 70.61,77.28 57.98,64.64 v1(57.98,62.06)
  BOTTOM w0.254: R704.1 85.65,119.73 85.57,119.81 R426.2 ; U75.6 v1(102.95,133.27)
  vias: v1(15.49,142.94) v1(57.95,61.21) v1(74.3,121.35) v1(74.3,120.33) v1(74.3,119.32) v1(74.3,118.3) v1(74.3,117.28) v1(74.3,116.27) v1(75.31,121.35) v1(75.31,120.33) v1(75.31,119.32) v1(75.31,118.3) v1(75.31,117.28) v1(75.31,116.27) v1(76.33,121.35) v1(76.33,120.33) v1(76.33,119.32) v1(76.33,118.3) v1(76.33,117.28) v1(76.33,116.27) v1(77.34,121.35) v1(77.34,120.33) v1(77.34,119.32) v1(77.34,118.3) v1(77.34,117.28) v1(77.34,116.27) v1(78.36,121.35) v1(78.36,120.33) v1(78.36,119.32) v1(78.36,118.3) v1(78.36,117.28) v1(78.36,116.27) v1(119.44,144.74) v1(119.44,143.74) v1(119.44,142.72) v1(119.44,141.71) v1(120.46,144.75) v1(120.46,143.74) v1(120.46,142.72) v1(120.46,141.71) v1(121.48,144.75) v1(121.48,143.74) v1(121.48,142.72) v1(121.48,141.71) v1(164.91,48.2) v1(164.91,47.19) v1(164.91,46.18) v1(165.93,48.21) v1(165.93,47.19) v1(165.93,46.18) v1(166.95,48.21) v1(166.95,47.19) v1(166.95,46.18) v1(167.33,45.24) v1(167.96,48.21) v1(167.94,47.2) v1(199.95,30.19)
VCC_12V0: length 96.5
  TOP w0.254: U14.10 v1(76.43,145.32) ; R2.1 v1(85.66,172.27) ; R54.1 v1(80.38,143.64) ; v1(68.27,140.98) 68.27,141.64 68.26,141.64 68.26,141.77 ; 68.26,141.77 69.28,140.76 U14.17 ; 68.26,141.77 C56.1
  L03_SIG1 w0.254: 80.52,146.37 80.96,146.81 80.96,157.42 83.63,160.08 TP66.1 v1(91.06,160.08) ; 80.52,146.37 80.84,146.05 80.84,144.1 v1(80.38,143.64) ; 80.52,146.37 77.48,146.37 v1(76.43,145.32) 69.43,145.32 68.27,144.15 v1(68.27,140.98)
  L05_SIG2 w0.254: v1(91.06,162.12) 85.66,167.51 v1(85.66,172.27)
  L12_SIG4 w0.381: J9.2 105.11,125.02 107.74,125.02 111.89,129.16 111.89,132.33 117.98,138.43 117.98,145.8 116.86,146.92 116.86,148.35 117.82,149.31 v1(118.87,149.31)
  BOTTOM w0.381: C336.1 103.57,123.48 J9.2
  vias: v1(91.06,161.1) v1(92.08,162.12) v1(92.08,161.1) v1(92.08,160.08) v1(93.09,162.12) v1(93.09,161.1) v1(93.09,160.08) v1(94.11,162.12) v1(94.11,161.1) v1(94.11,160.08) v1(118.87,151.34) v1(118.87,150.33) v1(119.89,151.34) v1(119.89,150.33) v1(119.89,149.31) v1(120.9,151.34) v1(120.9,150.33) v1(120.9,149.31)
VCC_HDR: length 34.3
  L05_SIG2 w0.254: J37.2 135.75,25.77 140.28,25.77 v1(145.99,20.07)
  BOTTOM w0.254: R666.1 147.13,19.49 146.56,20.07 v1(145.99,20.07) 145.48,20.07 145.29,19.88 R662.1 ; R666.1 148.17,18.71 148.72,18.16 148.72,13.14 146.59,11.02 R688.2 ; R666.1 146.67,18.71 146.48,18.52 146.48,18.13 146.24,17.88 C663.1 145.44,17.88 145.23,17.68 U111.2
VCC_LM5140: length 13.2
  BOTTOM w0.254: 99.06,137.16 99.27,137.37 U75.16 ; 99.06,137.16 99.35,136.87 U75.15 ; 99.06,137.16 98.42,137.16 98.3,137.29 97.66,137.29 ; 97.66,137.29 97.41,137.54 C330.1 95.03,138.39 94.87,138.55 D15.2 ; 97.66,137.29 97.41,137.03 C679.1 95.67,136.56 95.51,136.4 D17.2
VDD1V8_PG: length 216.3
  L05_SIG2 w0.254: v1(153.54,171.3) 141.1,171.3 v1(139.26,173.14) 137.32,173.14 132.33,168.15 127,168.15 126.05,167.2 109.28,167.2 v1(107.19,165.1)
  L12_SIG4 w0.254: v1(107.19,165.1) 67.06,165.1 65.15,163.19 65.15,149.1 50.29,134.24 50.29,128.78 48.13,126.62 39.37,126.62 38.99,127 37.85,127 34.21,123.37 34.21,111 37.78,107.43 37.78,77.53 33.54,73.29 33.54,71.57 v1(32.51,70.55)
  BOTTOM w0.254: U61.4 140.1,172.45 139.41,173.14 v1(139.26,173.14) ; U60.3 R336.1 154.21,171.03 153.86,170.69 C258.1 v1(153.54,171.3) TP81.1 ; v1(32.51,70.55) 32.71,70.35 U94.2
VDD3V3_CLKBUF: length 33.2
  TOP w0.254: U32.10 C160.1 ; R193.2 R189.2 65.28,99.07 64.96,98.75 64.96,96.77 v1(65.71,96.02) R199.2 ; R185.1 78.12,101.04 78.53,101.45 78.53,103.81 78.09,104.25 v1(77.58,104.25) R173.1
  L03_SIG1 w0.254: v1(77.58,104.25) 75.68,102.36 v1(75.68,96.51)
  BOTTOM w0.254: v1(65.71,96.02) 66.19,96.51 v1(75.68,96.51)
VDD_1V0: length 47.8
  TOP w0.254: C149.1 v1(47.48,102.48) U31.6 ; U22.42 37.33,119.41 36.7,120.04 36.7,120.09 36.68,120.12 C101.1 37.22,120.62 v1(37.4,120.44) ; C195.1 v1(57.64,86.14) ; C208.1 52.09,79.72 v1(52.13,79.76) ; U31.42 52.07,106.26 51.44,106.89 C125.1 51.98,107.47 v1(52.16,107.29) ; v1(39.11,110.57) 39.29,110.39 C124.1 U22.24 ; C187.1 v1(53.84,89.59) ; U31.24 C163.1 54.02,97.24 v1(53.84,97.42) ; v1(57.64,100.87) 57.82,101.05 C150.1 57.81,101.59 57.19,102.21 56.63,102.21 56.35,102.48 U31.31 ; U22.31 41.62,115.64 41.88,115.38 42.46,115.38 C111.1 43.09,114.2 v1(42.91,114.02) ; C197.1 v1(47.48,84.52) ; C110.1 v1(32.74,115.64) U22.6 ; v1(61.29,85.66) C193.1 v1(60.41,84.87)
  BOTTOM w0.254: U88.31 56.37,84.52 56.63,84.78 57.17,84.78 57.81,85.41 C589.1 57.82,85.96 v1(57.64,86.14) ; R344.1 v1(109.97,163.97) ; C392.1 v1(42.91,114.02) ; U88.6 v1(47.48,84.52) C590.1 ; C388.1 v1(32.74,115.64) ; v1(61.29,101.35) C471.1 v1(60.41,102.13) ; v1(53.84,89.59) 54.02,89.77 C577.1 U88.24 ; C407.1 v1(52.16,107.29) ; C453.1 v1(57.64,100.87) ; U64.16 116.71,164.98 116.95,165.23 C272.1 ; v1(39.94,107.31) C403.1 v1(39.15,108.2) ; C446.1 v1(47.48,102.48) ; U88.42 52.07,80.75 51.41,80.09 C599.1 51.91,79.54 v1(52.13,79.76) ; C512.1 v1(53.84,97.42) ; C399.1 v1(39.11,110.57) ; C372.1 v1(37.4,120.44)
  vias: v1(43.31,64.52) v1(43.31,63.5) v1(119.52,164.34) v1(119.52,163.32) v1(119.52,162.31) v1(119.52,161.29) v1(120.52,164.34) v1(120.52,163.32) v1(120.52,162.31) v1(120.52,161.29) v1(121.55,164.27) v1(121.55,163.26) v1(121.55,162.24) v1(121.55,161.23) v1(122.55,164.27) v1(122.57,163.26) v1(122.57,162.24) v1(122.57,161.23) v1(126.05,144.75) v1(126.05,143.74)
VDD_1V0_PG: length 1.9
  BOTTOM w0.254: U64.4 113.61,163.96 113.23,163.57 112.9,163.57 112.65,163.32 R345.2
VDD_2V5: length 24.6
  TOP w0.254: J16.54 45.43,62.77 45.47,62.74 ; U40.3 34.62,75.57 35.17,75.02 ; C117.1 v1(32.74,114.14) U22.9 ; C153.1 v1(47.48,100.99) U31.9 ; v1(44.07,86.83) C196.1 v1(43.19,86.04) ; U22.3 v1(32.74,117.14) C109.1 ; C199.1 v1(47.48,83.02) ; U31.3 v1(47.48,103.98) C143.1 ; C194.1 v1(47.48,86.02) ; J16.52 45.93,62.85
  BOTTOM w0.254: v1(45.15,97.51) C499.1 v1(45.15,99.26) ; U88.9 v1(47.48,86.02) C588.1 ; C393.1 v1(32.74,114.14) ; R566.1 34.86,73 v1(34.48,72.62) ; C424.1 v1(47.48,103.98) ; C381.1 v1(29.59,118.05) ; U88.3 v1(47.48,83.02) C592.1 ; C466.1 v1(47.48,100.99) ; C378.1 v1(32.74,117.14)
  vias: v1(34.48,71.6) v1(35.49,72.62) v1(35.49,71.6) v1(36.51,72.62) v1(36.51,71.6) v1(37.53,72.62) v1(37.53,71.6) v1(44.7,60.48) v1(45.72,60.48)
VDD_CORE: length 88.8
  TOP w0.254: U34.W14 v1(143.96,98.59) ; U34.T15 v1(146.36,96.99) ; U34.V13 v1(144.76,99.39) ; U34.N14 v1(149.56,98.59) ; U34.R18 v1(147.16,94.59) ; U34.J14 v1(152.76,98.59) ; U34.V19 v1(144.76,93.79) ; U34.Y15 v1(143.16,96.99) ; U34.P19 v1(148.76,93.79) ; U34.U18 v1(145.56,94.59) ; U34.R16 v1(147.16,96.19) ; U34.R14 v1(147.16,98.59) ; U34.T13 v1(146.36,99.39) ; U34.P15 v1(148.76,96.99) ; U34.W18 v1(143.96,94.59) ; U34.L19 v1(151.16,93.79) ; U34.T17 v1(146.36,95.39) ; U34.V15 v1(144.76,96.99) ; U34.Y13 v1(143.16,99.39) ; U34.Y11 v1(143.16,100.99) ; U34.U14 v1(145.56,98.59) ; U34.J12 v1(152.76,100.19) ; U34.K13 v1(151.96,99.39) ; U34.P13 v1(148.76,99.39) ; U34.T19 v1(146.36,93.79) ; U34.L14 v1(151.16,98.59) ; U34.J10 v1(152.76,101.79) ; U34.AA12 v1(142.36,100.19) ; U34.M13 v1(150.36,99.39) ; U34.J8 v1(152.76,103.39) ; U34.U16 v1(145.56,96.19) ; U34.J19 v1(152.76,93.79)
  L05_SIG2 w0.122: 159.77,93.25 158.83,94.18 153.15,94.18 v1(152.76,93.79)
  L05_SIG2 w0.254: v1(166.82,90.87) 166.82,92.77 165.93,93.66 160.93,93.66 160.48,93.22 159.79,93.22 159.77,93.25
  L07_PWR2 w0.254: v1(144.76,93.79) 144.37,94.17 ; v1(146.36,93.79) 145.97,94.17 ; v1(151.16,93.79) 151.54,94.17 ; v1(148.76,93.79) 148.25,94.3 ; v1(152.76,93.79) 152.34,94.21
  L12_SIG4 w0.203: v1(128.52,136.02) 127.25,136.02 125.22,138.05 125.22,141.48 129.67,145.92 129.67,152.91 138.05,161.29 138.05,165.48 138.68,166.12 141.21,166.12 v1(141.73,166.64)
  BOTTOM w0.203: R339.1 v1(141.73,166.64)
  BOTTOM w0.254: C500.1 147.55,98.2 v1(147.16,98.59) ; v1(151.16,98.59) 150.73,98.17 C502.1 ; v1(145.56,98.59) 145.72,98.43 C509.1 ; v1(147.16,96.19) 147.22,96.12 C516.1 ; C550.1 148.45,93.49 v1(148.76,93.79) ; v1(149.56,98.59) 149.88,98.27 C503.1 ; v1(166.82,90.87) 167.25,90.44 FL19.1 ; v1(143.16,96.99) 143.02,97.13 C511.1 ; v1(147.16,94.59) 147.4,94.35 C534.1 ; v1(143.96,98.59) 143.88,98.51 C510.1
  vias: v1(124.47,161.73) v1(124.47,160.72) v1(124.47,159.7) v1(124.47,158.69) v1(125.48,161.73) v1(125.48,160.72) v1(125.48,159.7) v1(125.48,158.69) v1(126.5,161.67) v1(126.5,160.66) v1(126.5,159.64) v1(126.5,158.62) v1(127.51,161.67) v1(127.52,160.66) v1(127.52,159.64) v1(127.52,158.62) v1(132.72,119.7) v1(132.72,118.69) v1(132.72,117.66) v1(132.72,116.66) v1(132.72,115.65) v1(132.72,114.63) v1(133.73,119.71) v1(133.73,118.69) v1(133.73,117.66) v1(133.73,116.66) v1(133.73,115.65) v1(133.73,114.63)
VDD_CORE_PG: length 68.9
  TOP w0.254: v1(140.18,173.14) 140.18,172.24 139.89,171.96 137.67,171.96 137.24,171.53 R8.2 C2.1
  L10_SIG3 w0.254: v1(186.56,176.15) 187.09,175.62 187.09,173.69 182.89,169.49 166.44,169.49 165.26,168.31 158.88,168.31 156.37,170.81 142.5,170.81 v1(140.18,173.14)
  BOTTOM w0.147: U59.A3 U59.B2
  BOTTOM w0.152: U59.C2 U59.B2
  BOTTOM w0.254: U61.5 140.6,172.84 140.3,173.14 v1(140.18,173.14) ; TP79.1 188.02,176.15 v1(186.56,176.15) 186.04,175.63 186.04,173.78 185.83,173.57 U59.A3
VDD_DDR4: length 163.3
  TOP w0.203: U10.1 C22.1
  TOP w0.208: U16.E2 v1(183.61,137.15) ; U25.C7 v1(182.01,114.52) ; U16.C7 v1(182.01,141.95) ; U25.E2 v1(183.61,109.72) ; U16.B2 v1(181.21,137.15) ; U25.B8 v1(181.21,115.32) ; U20.E8 v1(183.61,129.04) ; U33.E2 v1(183.61,96.01) ; U16.E8 v1(183.61,142.75) ; U33.C7 v1(182.01,100.81) ; U33.E8 v1(183.61,101.61) ; U25.E8 v1(183.61,115.32)
  TOP w0.254: U20.E2 v1(183.61,123.44) ; v1(191.26,89.79) 191.26,89.79 191.03,90.02 C185.1 190.66,88.54 U38.N9 ; v1(179.39,102.49) 178.88,103 176.59,103 175.51,101.92 165.21,101.92 164.76,102.36 R182.2 ; v1(176.74,142.77) C53.1 v1(177.74,143.55) ; v1(176.74,115.33) C112.1 v1(177.74,116.12) ; U16.J9 187.32,143.26 187.32,143.93 187.41,144.02 C45.1 186.98,144.88 v1(186.81,144.72) ; v1(185.15,89.79) 184.92,90.02 C182.1 184.55,88.55 U38.F9 ; U33.N9 190.66,102.26 C142.1 191.03,103.73 191.26,103.5 v1(191.26,103.5) ; U33.A1 180.81,94.52 181,94.32 C172.1 180.64,93.82 v1(180.41,94.04) ; U16.C1 v1(182.01,136.35) ; v1(190.81,80.26) 190.65,80.1 C207.1 190.21,81.29 U38.M1 ; U25.C9 v1(182.01,116.12) ; U25.F9 184.62,115.92 184.62,116.88 184.55,116.94 C105.1 184.92,117.45 v1(185.15,117.22) ; U33.M1 190.21,95 190.21,94.38 190.27,94.32 C177.1 190.71,93.82 v1(190.87,93.98) ; v1(186.81,131) 186.98,131.17 C87.1 187.41,129.63 U20.J9 ; U20.B8 v1(181.21,129.04) ; U20.C7 v1(182.01,128.24) ; U20.F9 184.62,129.63 184.62,130.59 184.55,130.66 C86.1 184.92,131.17 v1(185.15,130.94) ; U25.B2 v1(181.21,109.72) ; U25.N9 190.66,115.98 C108.1 191.03,117.45 191.26,117.22 v1(191.26,117.22) ; U33.B8 v1(181.21,101.61) ; U33.B2 v1(181.21,96.01) ; U33.H1 186.41,94.53 186.21,94.32 C175.1 186.64,93.82 v1(186.81,93.98) ; v1(177.74,88.69) C190.1 v1(176.74,87.9) ; U38.B2 v1(181.21,82.29) ; U25.H1 186.41,108.86 186.21,108.67 186.21,108.11 186.21,108.1 C128.1 186.64,107.59 v1(186.81,107.76) ; U16.F1 184.59,136.54 184.59,135.83 184.85,135.57 C80.1 184.48,134.96 v1(184.25,135.19) ; v1(186.81,117.28) 186.98,117.45 C106.1 187.41,115.92 U25.J9 ; U20.M1 190.21,122.43 190.21,121.82 190.27,121.76 C100.1 190.71,121.25 v1(190.87,121.41) ; U16.C9 v1(182.01,143.55) ; C22.1 201.83,152.93 v1(201.83,152.93) ; U20.C1 v1(182.01,122.64) ; v1(191.26,144.65) 191.03,144.88 C47.1 190.66,143.41 U16.N9 ; U33.C9 v1(182.01,102.41) ; U20.B2 v1(181.21,123.44) ; v1(183.61,80.33) 183.84,80.1 C204.1 184.2,81.28 U38.F1 ; U20.A1 180.81,121.95 181,121.76 C95.1 180.64,121.25 v1(180.41,121.48) ; U25.F1 184.59,109.11 184.59,108.39 184.85,108.14 C130.1 184.48,107.53 v1(184.25,107.76) ; U33.J9 187.41,102.2 C140.1 186.98,103.73 v1(186.81,103.57) ; v1(177.74,102.41) C154.1 176.72,101.62 v1(176.72,101.62) ; U38.E2 v1(183.61,82.29) ; U16.M1 190.21,136.15 190.21,135.6 190.28,135.53 C83.1 190.71,134.96 v1(190.87,135.13) ; U38.H1 186.41,80.81 186.21,80.61 C205.1 186.64,80.1 v1(186.81,80.26) ; U20.N9 190.66,129.69 C89.1 191.03,131.17 191.26,130.94 v1(191.26,130.94) ; U20.C9 v1(182.01,129.84) ; U33.C1 v1(182.01,95.21) ; U33.F1 184.59,95.39 184.59,94.68 184.85,94.42 C174.1 184.48,93.82 v1(184.25,94.04) ; U20.H1 186.41,121.95 186.21,121.76 C98.1 186.64,121.25 186.81,121.41 v1(186.81,121.41) ; U38.E8 v1(183.61,87.89) ; U38.B8 v1(181.21,87.89) ; U16.B8 v1(181.21,142.75) ; U16.A1 180.81,135.67 181,135.47 C78.1 180.64,134.96 v1(180.41,135.19) ; U25.C1 v1(182.01,108.92) ; U38.C7 v1(182.01,87.09) ; R220.2 v1(194.93,79.77) ; v1(180.41,107.76) 180.64,107.53 C129.1 181,108.04 180.81,108.23 U25.A1 ; U38.A1 180.81,80.8 181,80.61 C202.1 180.64,80.1 v1(180.41,80.33) ; U16.F9 184.62,143.35 C44.1 184.98,144.88 v1(185.21,144.65) ; U38.C1 v1(182.01,81.49) ; v1(186.81,89.85) 186.98,90.02 C183.1 187.41,88.49 U38.J9 ; v1(176.74,129.05) C90.1 v1(177.74,129.84) ; v1(184.25,121.48) 184.48,121.25 C97.1 184.85,121.86 184.59,122.11 184.59,122.82 U20.F1 ; v1(190.87,107.7) 190.71,107.53 C132.1 190.27,108.04 190.21,108.1 190.21,108.72 U25.M1 ; U33.F9 184.62,102.2 184.62,103.16 184.55,103.23 C139.1 184.92,103.73 v1(185.15,103.5) ; U38.C9 v1(182.01,88.69) ; v1(186.81,135.13) 186.64,134.96 C81.1 186.21,135.47 186.41,135.67 U16.H1
  BOTTOM w0.122: 183.17,144.02 183.13,143.98 183.13,143.78 183.2,143.72 183.2,143.16 v1(183.61,142.75)
  BOTTOM w0.254: C303.1 182.82,147.93 181.9,147.01 C312.1 181.9,143.98 182.01,143.87 v1(182.01,143.55) ; C447.1 181.5,101.89 v1(181.21,101.61) ; v1(181.21,123.44) 181.13,123.52 C364.1 ; v1(183.61,87.89) 183.67,87.95 C585.1 ; v1(182.01,129.84) 182.16,129.98 C351.1 ; v1(181.21,115.32) 181.49,115.6 C385.1 ; C594.1 182.13,81.37 v1(182.01,81.49) ; v1(181.21,109.72) 181.21,109.73 C398.1 ; v1(183.61,129.04) 183.76,129.19 C355.1 ; v1(185.15,89.79) 185.31,89.62 R503.2 ; C369.1 182.13,122.52 v1(182.01,122.64) ; C332.1 181.16,137.1 v1(181.21,137.15) ; v1(181.21,142.75) 181.5,143.04 C315.1 ; C335.1 182.13,136.23 v1(182.01,136.35) ; v1(182.01,87.09) 182.78,86.32 R516.1 ; C449.1 183.66,101.66 v1(183.61,101.61) ; C387.1 183.74,115.45 v1(183.61,115.32) ; v1(181.21,96.01) 181.16,95.96 C528.1 ; C579.1 182.16,88.83 v1(182.01,88.69) ; C593.1 181.28,82.36 v1(181.21,82.29) ; C380.1 182.16,116.27 v1(182.01,116.12) ; v1(181.21,129.04) 181.5,129.32 C354.1 ; v1(182.01,95.21) 182.13,95.09 C538.1 ; C402.1 182.13,108.8 v1(182.01,108.92) ; 183.17,144.02 C311.1 ; v1(181.21,87.89) 181.5,88.18 C583.1 ; C434.1 182.16,102.55 v1(182.01,102.41) ; v1(191.26,103.5) 190.6,104.16 R460.2
  vias: v1(178.38,157.87) v1(178.38,156.86) v1(178.38,155.84) v1(179.4,157.87) v1(179.4,156.86) v1(179.4,155.84)
VDD_DLL_CORE: length 25
  TOP w0.254: U34.G22 v1(154.36,91.39) ; U34.H23 v1(153.56,90.59)
  L03_SIG1 w0.254: v1(153.56,90.59) v1(154.36,91.39)
  L05_SIG2 w0.122: v1(153.56,90.59) 153.95,90.98 159.77,90.98 159.77,90.98
  L05_SIG2 w0.254: v1(163.7,89.92) 161.23,89.92 160.16,90.98 159.77,90.98
  L07_PWR2 w0.122: v1(154.36,91.39) 154.76,90.98 157.81,90.98 157.86,90.93
  L07_PWR2 w0.254: v1(163.7,89.92) 159.7,89.92 158.69,90.93 157.86,90.93
  BOTTOM w0.254: v1(163.7,89.92) 163.89,89.73 C580.1 165.55,89.73 FL19.2
VDD_MCU: length 6.7
  TOP w0.254: U34.T11 v1(146.36,100.99) ; U34.P11 v1(148.76,100.99) ; U34.N10 v1(149.56,101.79) ; U34.R10 v1(147.16,101.79) ; U34.R12 v1(147.16,100.19)
  L06_PWR1 w0.254: v1(147.16,100.19) v1(146.36,100.99) v1(147.16,101.79)
  BOTTOM w0.254: C482.1 147.32,100.03 v1(147.16,100.19) ; C458.1 147.23,101.87 v1(147.16,101.79)
  vias: v1(152.72,159.08) v1(153.73,159.08) v1(159.44,118.36) v1(159.44,117.35)
VDD_MMC1:
  vias: v1(178.31,51.18) v1(178.31,50.55)
VDD_MPU: length 90.9
  TOP w0.254: U34.K18 v1(151.96,94.59) ; U34.L10 v1(151.16,101.79) ; U34.K16 v1(151.96,96.19) ; U34.K11 v1(151.96,100.99) ; U34.M18 v1(150.36,94.59) ; U34.M11 v1(150.36,100.99) ; U34.N17 v1(149.56,95.39) ; U34.L17 v1(151.16,95.39) ; U34.K9 v1(151.96,102.59) ; U34.L8 v1(151.16,103.39) ; U34.M16 v1(150.36,96.19)
  BOTTOM w0.203: v1(171.2,101.36) 173.11,101.36 179,107.25 179.2,107.44 179.2,146.18 191.88,158.86 191.88,168.64 191.68,168.84 188.11,172.41 U59.B1
  BOTTOM w0.254: R476.1 171.2,98.3 v1(171.2,98.31) ; v1(150.36,100.99) 150.32,101.03 C465.1
  vias: v1(170.18,101.36) v1(170.18,100.34) v1(170.18,99.31) v1(170.18,98.31) v1(171.2,100.34) v1(171.2,99.31) v1(188.47,164.97) v1(188.47,163.97) v1(189.48,164.97) v1(189.48,163.97) v1(189.48,162.94) v1(189.48,161.94) v1(190.5,164.99) v1(190.5,163.97) v1(190.5,162.94) v1(190.5,161.94)
VDDA_1P8_OLDI: length 12.5
  TOP w0.254: FL21.2 v1(153.67,81.75) ; U34.L22 v1(151.16,91.39)
  L06_PWR1 w0.122: v1(151.16,91.39) 151.55,91 151.55,86.3
  L06_PWR1 w0.254: v1(153.67,81.75) 153.67,83.06 151.55,85.18 151.55,86.3
VDDA_1V8: length 4.2
  TOP w0.254: U34.AB6 v1(141.56,104.99) ; U34.AC6 v1(140.76,104.99) ; v1(154.34,78.74) 154.34,79.51 FL21.1 155.45,79.49 v1(155.45,78.74)
  vias: v1(124.53,116.22) v1(124.53,114.86) v1(125.36,116.22) v1(125.36,114.86) v1(128.33,97.35) v1(128.33,96.33) v1(128.33,95.31) v1(128.33,94.3) v1(152.84,78.74) v1(152.84,77.72) v1(153.16,118.13) v1(154.18,118.13) v1(154.34,77.72) v1(155.19,118.13) v1(155.46,77.72) v1(156.59,162.31) v1(156.59,161.29)
VDDA_3P3_IOLDO_WKUP: length 12.2
  TOP w0.254: U34.AB9 v1(141.56,102.59)
  BOTTOM w0.122: 138.07,102.2 141.16,102.2 v1(141.56,102.59)
  BOTTOM w0.254: FL16.2 134.22,104.09 136.15,102.15 C450.1 138.03,102.15 138.07,102.2
VDDA_3P3_USB: length 17.1
  TOP w0.254: U34.AC12 v1(140.76,100.19)
  BOTTOM w0.122: 136.41,99.01 136.44,98.98 138.6,98.98 138.76,98.82 138.76,98.43 139.03,98.16 C501.1 139.97,97.92 140.35,98.29 140.35,99.78 v1(140.76,100.19)
  BOTTOM w0.254: 136.41,99.01 136.3,99.12 133.02,99.12 132.12,100.01 132.12,102.02 131.69,102.45 FL18.2 130.92,101.61 130.74,101.42 C464.1
VDDA_3V3_SDIO: length 0.9
  TOP w0.254: U34.H17 v1(153.56,95.39)
  BOTTOM w0.254: v1(153.56,95.39) 153.76,95.19 FL13.2
VDDA_GP1: length 15.8
  TOP w0.254: U34.AA14 v1(142.36,98.59) ; U34.AB13 v1(141.56,99.39) ; U34.AB15 v1(141.56,96.99)
  L10_SIG3 w0.254: v1(141.56,96.99) 141.56,97.79 v1(142.36,98.59) v1(141.56,99.39)
  BOTTOM w0.122: 136.14,96.58 141.15,96.58 v1(141.56,96.99)
  BOTTOM w0.254: FL27.2 133.03,95.75 133.86,96.58 136.14,96.58
VDDA_GP3: length 17.2
  TOP w0.254: U34.U12 v1(145.56,100.19)
  L08_PWR3 w0.122: 136.14,99.5 136.42,99.78 145.15,99.78 v1(145.56,100.19)
  L08_PWR3 w0.152: v1(133.79,98.55) 135.19,98.55 136.14,99.5
  BOTTOM w0.254: FL30.2 131.93,97.27 132.11,97.09 133.48,97.09 133.79,97.41 v1(133.79,98.55)
VDDA_GP4: length 18.1
  TOP w0.203: U34.L20 v1(151.16,92.99)
  TOP w0.254: U34.M21 v1(150.36,92.19)
  L06_PWR1 w0.122: v1(150.36,92.19) v1(151.16,92.99) 151.55,92.6 151.55,92.05 151.79,91.8 152.12,91.8 152.36,91.55 152.36,87.93
  L06_PWR1 w0.254: 152.36,87.93 152.36,85.13 v1(156.08,81.42)
  BOTTOM w0.254: FL28.2 v1(156.08,81.42) 156.08,81.42 156.34,81.17 C595.1
VDDA_GP9: length 20.3
  TOP w0.254: U34.AA9 v1(142.36,102.59)
  BOTTOM w0.122: 138.02,107.7 138.1,107.78 142.52,107.78 142.75,107.55 142.75,102.98 v1(142.36,102.59)
  BOTTOM w0.254: 138.02,107.7 136,107.7 132.64,111.06 131.58,111.06 131.01,111.63 FL29.2 ; v1(142.36,102.59) 142.13,102.37 C448.1
VDDA_LM5140: length 28.6
  L12_SIG4 w0.254: v1(105.07,142.49) 105.07,139.02 105.92,138.18 v1(107.57,138.18) 107.57,137.92 107.55,137.91 v1(107.55,135.64) 105.19,133.27 v1(104.45,133.27) 104.45,133.29 103.63,134.11 102.36,134.11 102.11,133.86 102.11,132.33 v1(103,131.44)
  BOTTOM w0.254: v1(107.55,135.64) C318.1 106.98,136.63 ; v1(103,131.44) 103.16,131.28 R404.2 ; 106.98,136.63 106.98,136.61 106.74,136.37 U75.37 ; 106.98,136.63 106.74,136.87 U75.36 ; U75.3 v1(104.45,133.27) ; 107.06,138.11 107.51,138.11 v1(107.57,138.18) ; 107.06,138.11 106.82,137.87 U75.34 ; 107.06,138.11 106.8,138.37 U75.33 ; U75.28 104.45,140.7 105.07,141.32 v1(105.07,142.49)
VDDA_MCU_ADC: length 15.3
  TOP w0.254: U34.M9 v1(150.36,102.59) ; U34.M7 v1(150.36,104.19)
  L03_SIG1 w0.122: 150.75,109.6 150.75,107.23 150.52,107 150.2,107 149.97,106.76 149.96,106.75 149.96,104.83 149.97,104.83 149.97,104.58 v1(150.36,104.19) 149.96,103.8 149.96,102.98 v1(150.36,102.59)
  L03_SIG1 w0.254: 150.75,109.6 150.75,110.55 152.53,112.33 v1(152.53,113.29)
  BOTTOM w0.254: FL26.2 v1(152.53,113.29)
VDDA_PLL_DDR: length 21.4
  TOP w0.254: U34.H15 v1(153.56,96.99) ; U34.H11 v1(153.56,100.99)
  L05_SIG2 w0.122: v1(153.56,100.99) 153.16,101.38 153.16,107.55 153.17,107.55 153.17,107.57 153.39,107.8 153.72,107.8 153.95,108.03 153.95,109.58 153.97,109.6
  L05_SIG2 w0.254: v1(155.58,113.36) 155.58,112.71 153.97,111.1 153.97,109.6
  L12_SIG4 w0.122: v1(153.56,100.99) 153.16,100.6 153.16,97.38 v1(153.56,96.99)
  BOTTOM w0.122: v1(153.56,96.99) 153.54,97 C507.1
  BOTTOM w0.254: FL32.2 v1(155.58,113.36)
VDDA_PLL_DSS: length 16.4
  TOP w0.254: U34.L21 v1(151.16,92.19)
  L06_PWR1 w0.122: 150.76,86.34 150.76,91.79 v1(151.16,92.19)
  L06_PWR1 w0.254: 150.76,86.34 150.76,85.08 152.15,83.69 152.15,82.6 v1(151.92,82.37)
  BOTTOM w0.122: v1(151.16,92.19) 150.76,91.79 148.56,91.79 148.34,91.57 148.34,91.28 148.22,91.16 C565.1
  BOTTOM w0.203: v1(151.92,82.37) 152.16,82.37 152.36,82.17 FL33.2
VDDA_PLL_MAIN: length 15.1
  TOP w0.254: U34.Y17 v1(143.16,95.39)
  L06_PWR1 w0.122: v1(143.16,95.39) 143.55,95 143.55,94.43 143.3,94.18 136.14,94.18
  L06_PWR1 w0.152: v1(134.87,95.06) 135.75,94.18 136.14,94.18
  BOTTOM w0.254: FL34.2 132.24,94.23 132.5,94.49 134.31,94.49 v1(134.87,95.06)
VDDA_PLL_MPU: length 25.5
  TOP w0.254: U34.K15 v1(151.96,96.99) ; U34.L12 v1(151.16,100.19)
  L12_SIG4 w0.122: 148.11,109.6 148.11,109.57 148.11,109.57 148.11,104.01 148.35,103.78 151.32,103.78 151.54,103.55 151.54,100.58 v1(151.16,100.19) 151.56,99.78 151.56,97.38 v1(151.96,96.99)
  L12_SIG4 w0.254: 148.11,109.6 148.11,110.77 150.63,113.29 v1(151.32,113.29)
  BOTTOM w0.254: FL31.2 151,113.66 151.32,113.35 v1(151.32,113.29) ; v1(151.96,96.99) 152.48,97.51 C508.1
VDDA_PLL_PER0: length 23.4
  TOP w0.254: U34.AB7 v1(141.56,104.19)
  L08_PWR3 w0.122: v1(141.56,104.19) 141.16,104.59 136.51,104.59
  L08_PWR3 w0.254: 136.51,104.59 129.52,104.59 124.94,109.17 v1(124.94,112.39)
  BOTTOM w0.254: FL35.2 v1(124.94,112.39)
VDDA_POR: length 29
  TOP w0.254: U34.Y9 v1(143.16,102.59)
  L05_SIG2 w0.122: v1(143.16,102.59) 143.56,103 143.56,103.6 143.75,103.78 144.21,103.78 144.35,103.92 144.35,106.75 144.1,107 143.79,107 143.55,107.25 143.55,108.61 143.32,108.84 143.32,109.6
  L05_SIG2 w0.254: v1(132.72,113.71) 132.06,114.37 132.06,115.88 132.32,116.13 135.27,116.13 135.89,115.52 136.77,115.52 137.1,115.19 140.8,115.19 143.32,112.67 143.32,109.6
  BOTTOM w0.254: v1(132.72,113.71) 132.07,113.71 131.9,113.88 FL24.2
VDDA_SRAM_CORE: length 26
  TOP w0.254: U34.V16 v1(144.76,96.19) ; U34.M19 v1(150.36,93.79)
  L06_PWR1 w0.122: v1(144.76,96.19) 144.36,95.8 144.36,93.65 144.1,93.38 136.82,93.38 136.14,92.71
  L06_PWR1 w0.152: 136.14,92.71 135.58,92.14 v1(133.64,92.14)
  L12_SIG4 w0.122: v1(144.76,96.19) 145.16,95.78 145.16,94.36 145.34,94.18 149.96,94.18 150.12,94.02 150.12,94.02 v1(150.36,93.79)
  BOTTOM w0.254: C519.1 144.56,96.39 v1(144.76,96.19) ; FL22.2 131.75,92.23 132.17,92.65 133.1,92.65 133.6,92.14 133.6,92.14 v1(133.64,92.14)
VDDA_SRAM_MPU: length 24.1
  TOP w0.254: U34.K7 v1(151.96,104.19) ; U34.L18 v1(151.16,94.59)
  L03_SIG1 w0.122: 153.16,109.6 153.16,105.65 153.15,105.63 153.15,105.63 152.92,105.4 152.61,105.4 152.35,105.13 152.35,104.83 151.96,104.44 v1(151.96,104.19)
  L03_SIG1 w0.254: v1(154.18,113.36) 154.18,111.44 153.16,110.43 153.16,109.6
  L12_SIG4 w0.122: v1(151.96,104.19) 152.36,103.78 152.36,95.25 152.35,95.23 152.35,95.23 152.12,95 151.56,95 v1(151.16,94.59)
  BOTTOM w0.254: v1(154.18,113.36) 154.18,113.87 154.05,113.99 FL23.2 ; C540.1 151.34,94.4 v1(151.16,94.59)
VDDA_SYS_MON: length 20.3
  TOP w0.254: U34.AC11 v1(140.76,100.99)
  L08_PWR3 w0.122: 136.38,100.57 136.4,100.58 140.35,100.58 v1(140.76,100.99)
  L08_PWR3 w0.254: 136.38,100.57 135.62,99.81 134.1,99.81 132.16,97.87 126.59,97.87 v1(124.73,96.01)
  BOTTOM w0.254: R486.2 R484.1 v1(124.73,96.01)
VDDA_WKUP_LDO: length 31.6
  TOP w0.254: U34.AB8 v1(141.56,103.39)
  L08_PWR3 w0.122: v1(141.56,103.39) 141.16,103.78 138.07,103.78
  L08_PWR3 w0.254: 138.07,103.78 137.99,103.7 129.6,103.7 124.27,109.03 124.27,112.43 125.2,113.36 v1(125.2,113.92)
  BOTTOM w0.122: v1(141.56,103.39) 141.15,102.98 138.07,102.98 138.04,102.96 137.3,102.96 137.2,103.06 C430.1
  BOTTOM w0.254: FL25.2 v1(125.2,113.92)
VDDC_1V2: length 23.8
  L12_SIG4 w0.254: v1(63.61,23.46) 55.34,23.46 52.92,21.04 v1(52.92,14.55)
  BOTTOM w0.203: C667.1 53.29,15.27 U106.115 ; U106.87 C653.1
  BOTTOM w0.254: v1(63.61,23.46) C651.1 C653.1 ; v1(52.92,14.55) 53.21,14.84 C667.1
VDDIM: length 3.5
  TOP w0.094: 158.94,54.08 159.44,54.08 U51.C2
  TOP w0.203: 158.94,54.08 v1(158.5,53.63)
  BOTTOM w0.254: C618.1 159.24,53.9 C620.1 158.58,53.72 v1(158.5,53.63)
VDDR_VTT: length 9.7
  TOP w0.203: U10.3 200.59,150.3 C38.2 200.84,149.8 201.13,149.5 U10.5
  TOP w0.254: R56.2 v1(196.27,142.75) 196.27,142.75 C52.1 ; v1(196.27,140.72) 196.27,140.71 C64.1 ; v1(196.27,136.65) 196.27,136.65 C70.1 ; C67.1 196.27,138.68 v1(196.27,138.68)
  BOTTOM w0.203: C328.1 196.27,137.73 ; C65.1 196.27,139.7 ; C57.1 196.27,141.8
  BOTTOM w0.254: v1(196.27,142.75) R377.2
  vias: v1(185.86,149.16) v1(187.9,149.16) v1(189.93,149.16) v1(191.96,149.16)
VDDS_OSC1: length 20.6
  TOP w0.254: U34.J16 v1(152.76,96.19)
  L08_PWR3 w0.122: v1(152.76,96.19) 153.15,95.8 159.43,95.8 159.77,96.14 159.77,96.14
  L08_PWR3 w0.254: 159.77,96.14 169.33,96.14 v1(170.18,96.99)
  BOTTOM w0.254: v1(170.18,96.99) 170.29,96.88 C522.1 169.97,96.08 FL36.2
VDDSHV_MMC1: length 71.5
  TOP w0.254: U34.K21 v1(151.96,92.19) ; U34.J22 v1(152.76,91.39) ; U34.J20 v1(152.76,92.99) ; v1(173.91,52.37) 173.91,51.98 174.17,51.73 FL37.1
  L03_SIG1 w0.254: v1(152.76,92.99) v1(151.96,92.19) v1(152.76,91.39)
  L05_SIG2 w0.122: 159.77,91.8 153.16,91.8 v1(152.76,91.39)
  L05_SIG2 w0.254: v1(173.91,52.37) 174.39,51.9 175.9,51.9 179.26,55.26 179.26,57.34 175.02,61.58 175.02,74.08 165.29,83.81 v1(165.29,92.9) 164.19,91.8 159.77,91.8
  BOTTOM w0.254: FL20.2 C564.2 v1(165.29,92.9)
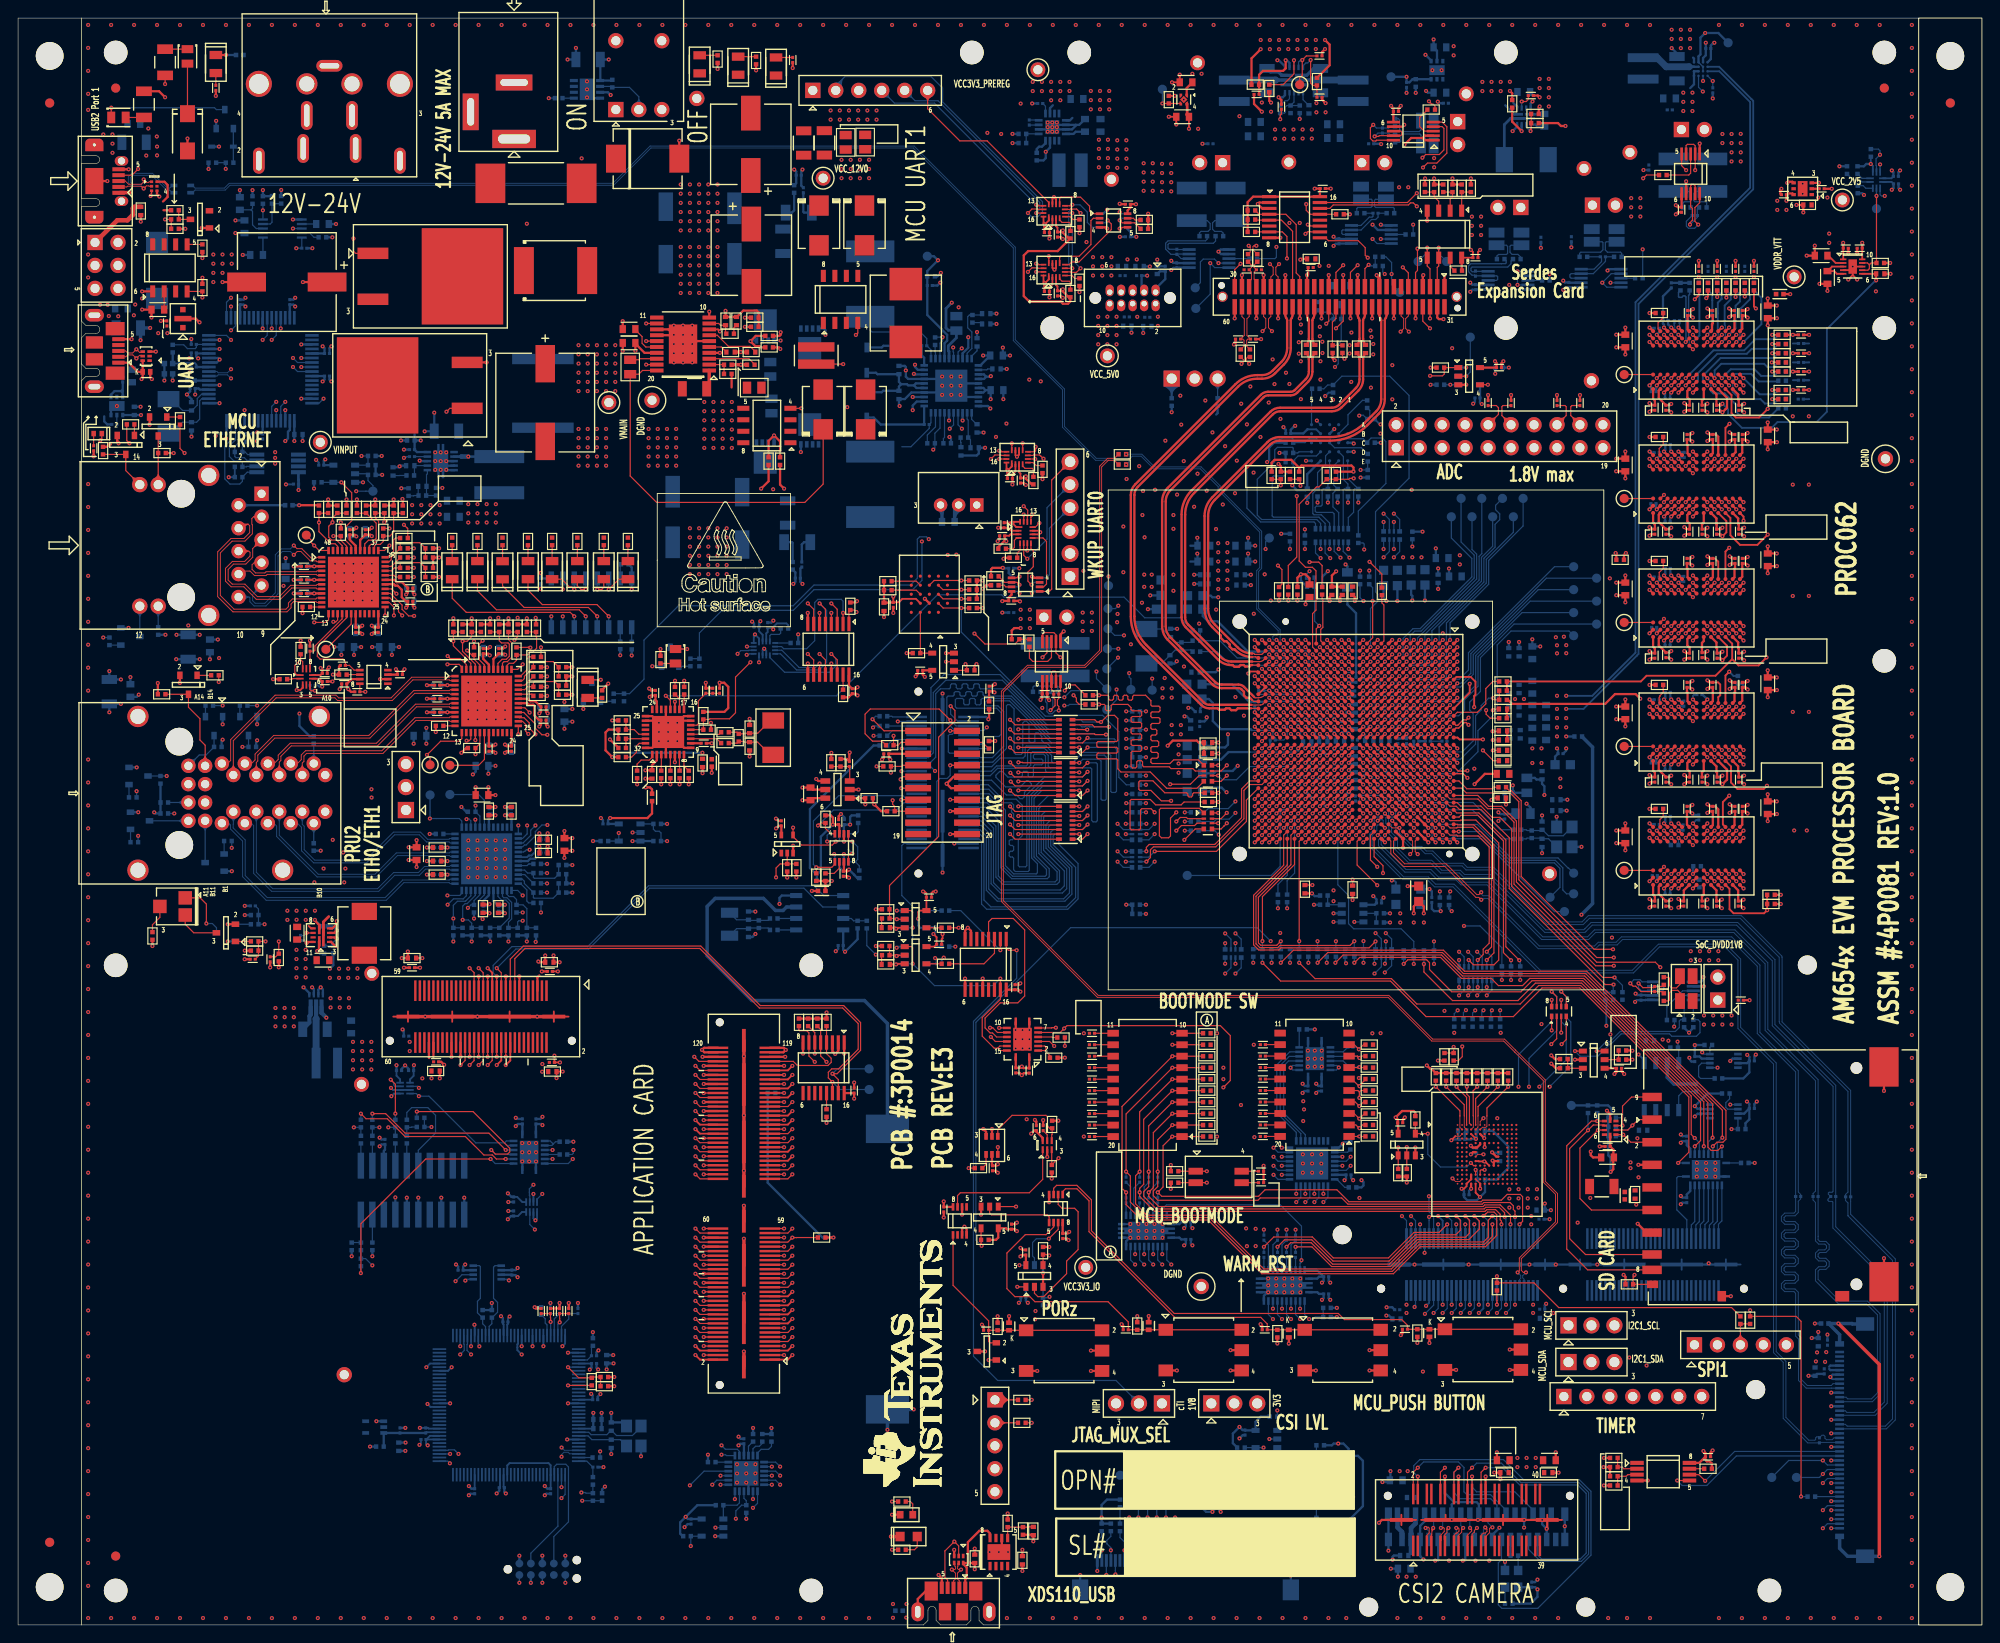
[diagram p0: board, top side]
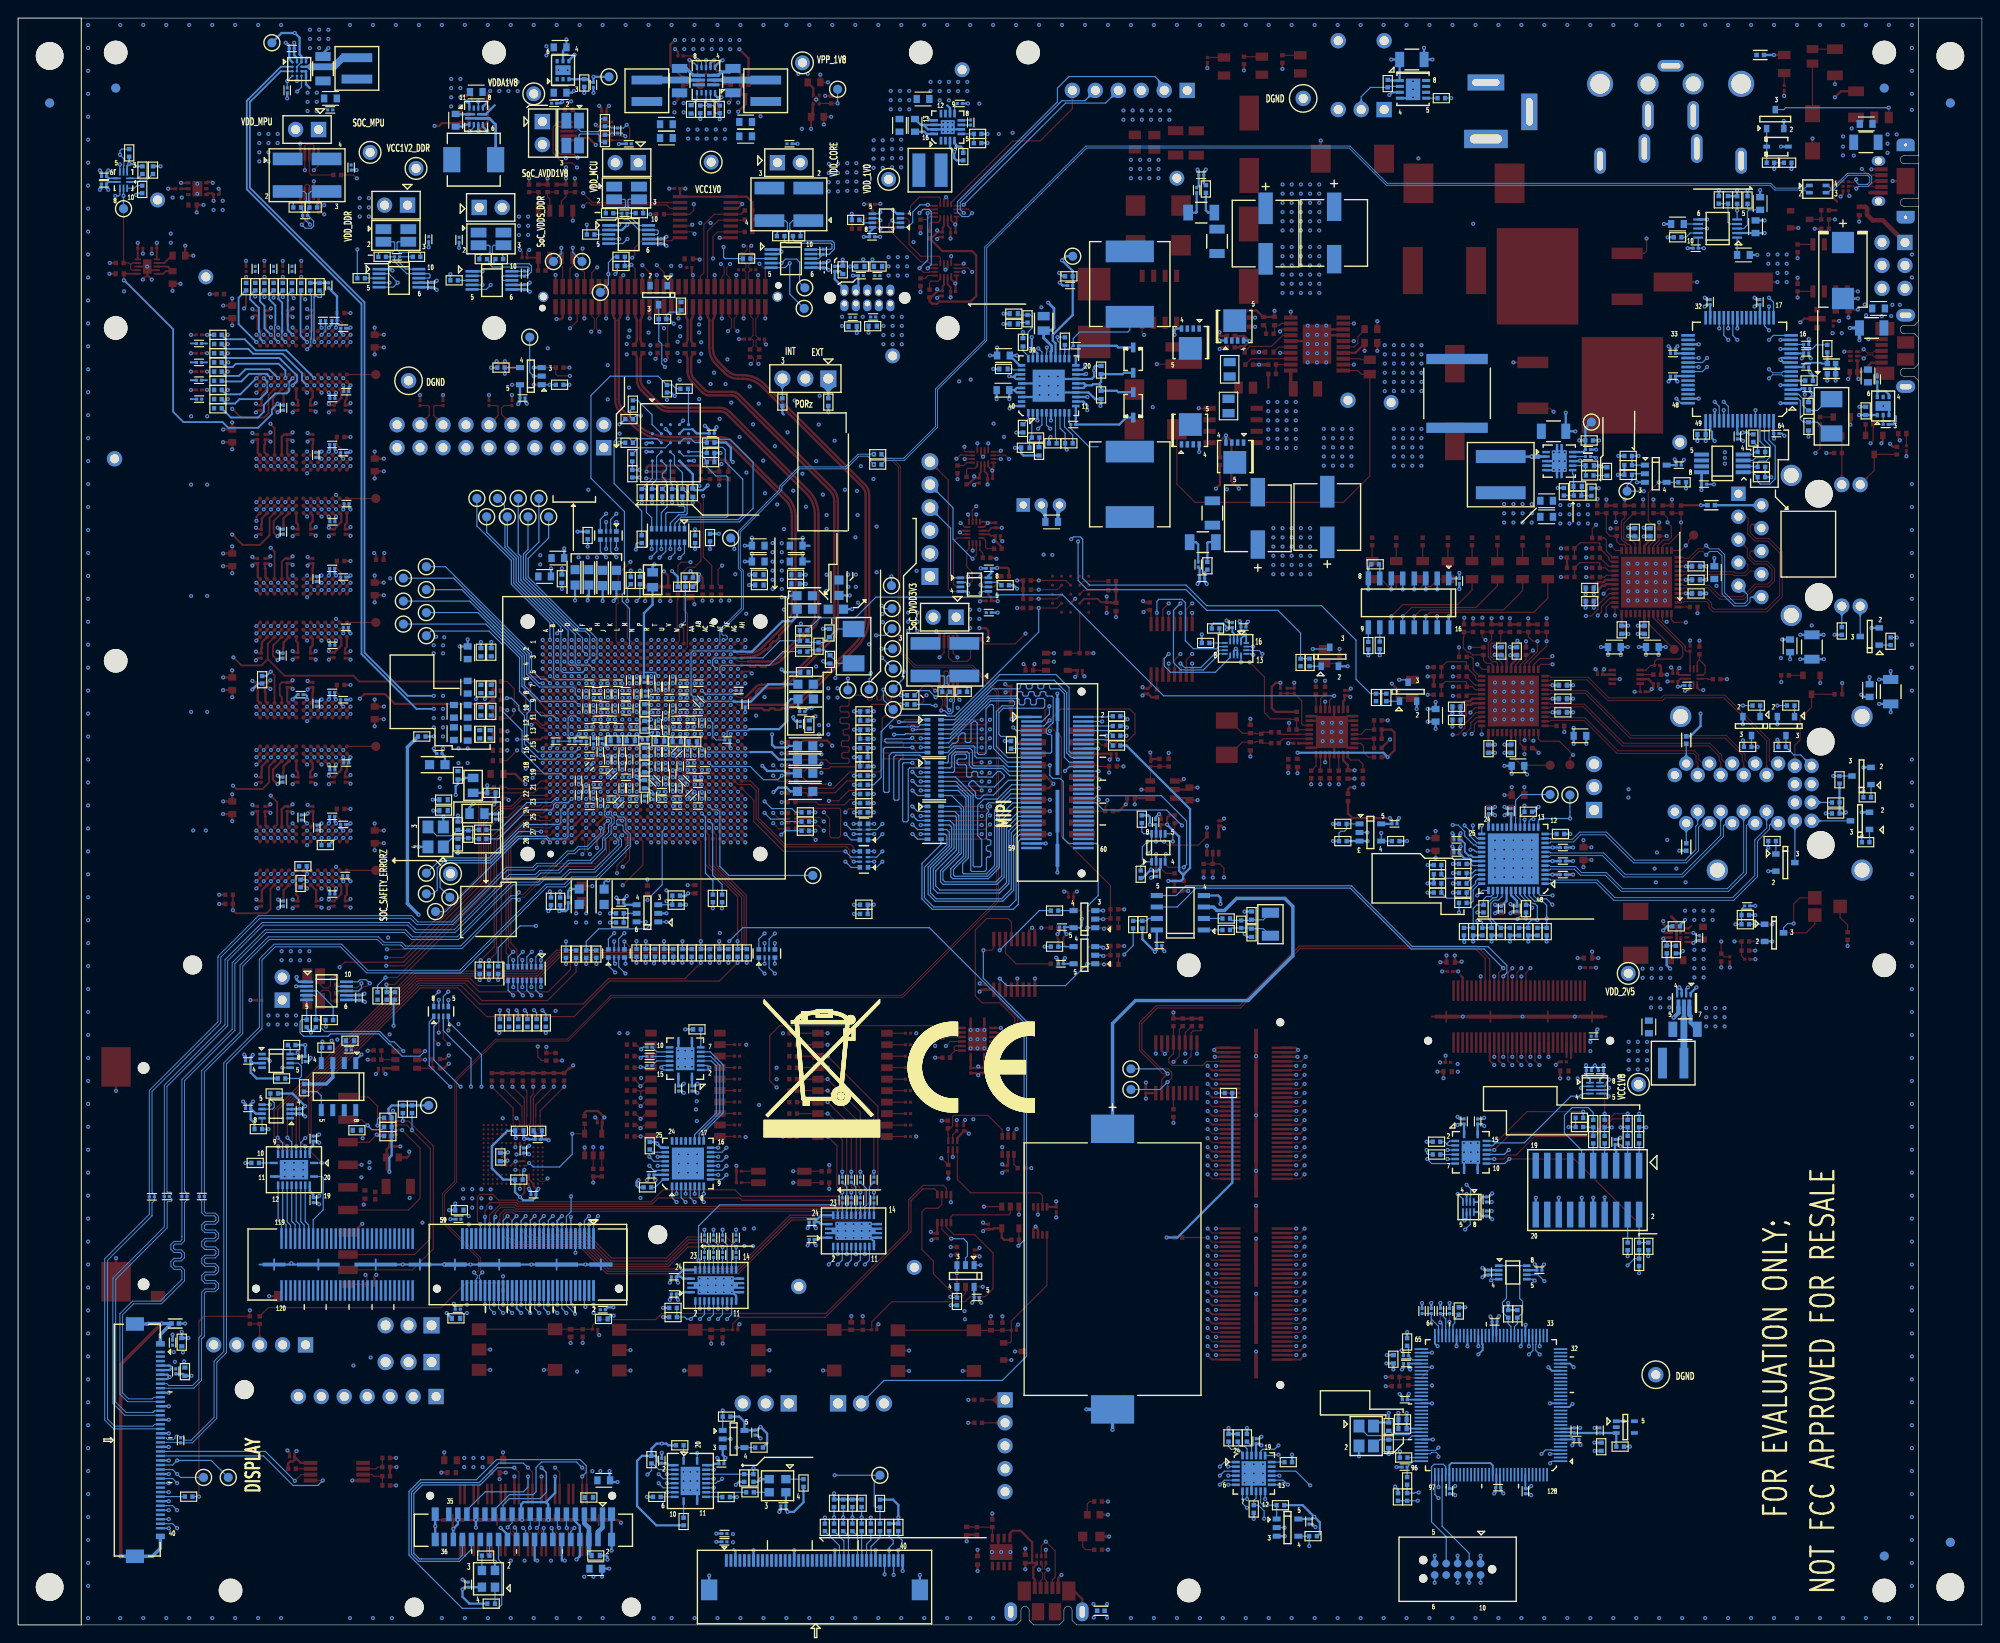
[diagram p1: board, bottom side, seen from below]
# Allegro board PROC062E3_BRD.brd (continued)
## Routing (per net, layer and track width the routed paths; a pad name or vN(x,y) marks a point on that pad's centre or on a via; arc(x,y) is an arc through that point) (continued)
VDDSHV_SD_IO: length 51.3
  TOP w0.254: v1(176.11,50.13) 176.4,50.42 176.4,51.66 FL37.2 176.42,51.78 176.42,52.59 C233.1 U47.10 ; R310.1 177.76,38.52 v1(177.55,38.73)
  L08_PWR3 w0.254: v1(176.11,50.13) 176.11,54.85 v1(185.42,64.16)
  L12_SIG4 w0.254: v1(177.55,38.73) 176.11,40.17 v1(176.11,50.13)
  BOTTOM w0.254: TP75.1 R607.1 R606.1 175.84,57.48 176.21,57.11 176.21,56.64 175.86,56.29 R608.1 R614.1 R616.1 175.86,51.95 176.11,51.7 v1(176.11,50.13) ; U96.7 186.18,62.66 185.95,62.9 C607.1 v1(185.42,64.16) 185.42,64.16 185.43,64.17 R600.2
VIN: length 30.6
  L12_SIG4 w0.254: v1(56.26,155.04) 56.26,155.07 56.71,155.51 63.56,155.51 64.07,156.02 64.07,171.97 v1(65.32,173.22)
  BOTTOM w0.254: v1(65.32,173.22) C254.1 64.39,170.92 U62.1 65.63,170.89 R337.1
VIN_MON_PORZ_3V3_PG: length 356
  TOP w0.254: U35.1 R210.2 v1(93.69,90.8) ; U50.3 107.04,54.56 v1(106.74,54.86)
  L03_SIG1 w0.254: v1(106.74,54.86) 93.69,67.92 v1(93.69,90.8)
  L05_SIG2 w0.254: v1(155.63,173.74) 155.19,173.3 155.19,171.58 153.81,170.19 135.32,170.19 132.87,167.74 127.17,167.74 126.13,166.7 110.44,166.7 v1(108.71,164.97)
  L10_SIG3 w0.254: v1(44.53,131.06) 58.48,131.06 60.21,132.79 89.74,132.79 v1(91.69,134.75)
  L12_SIG4 w0.254: 83.06,133.86 81.66,132.46 81.66,116.71 90.55,107.82 90.55,93.93 v1(93.69,90.8) ; 83.06,133.86 90.8,133.86 v1(91.69,134.75) ; 83.06,133.86 82.04,134.87 82.04,160.02 86.11,164.08 107.82,164.08 v1(108.71,164.97) ; v1(31.56,70.55) 32.51,71.5 32.51,76.83 36.97,81.29 36.97,105.39 33.4,108.96 33.4,119.89 32,121.28 32,125.86 34.82,128.68 43.21,128.68 44.53,130 v1(44.53,131.06) ; v1(165.28,165.29) 162.43,168.14 162.43,170.88 160.34,172.97 156.4,172.97 v1(155.63,173.74)
  BOTTOM w0.254: U60.4 156.26,173.11 v1(155.63,173.74) ; U63.6 165.77,165.79 v1(165.28,165.29) ; R401.2 v1(44.53,131.06) ; R401.2 43.85,132.42 TP76.1 ; R401.2 43.85,130.06 C353.1 44.11,129.78 U80.10 ; U94.1 32.21,69.91 31.57,70.55 v1(31.56,70.55)
VINPUT: length 98.3
  TOP w0.254: R13.1 15.59,169.7 v1(16.26,169.04) ; C39.1 v1(31.5,148.59)
  L03_SIG1 w0.254: v1(16.26,169.04) 21.06,164.23 v1(21.06,161.1) 23.4,158.76 v1(24.53,158.76) 25.28,159.51 26.33,159.51 v1(27.07,158.77) 24.77,156.46 24.77,154.75 v1(24.03,154.01) 24.85,153.19 v1(24.85,151.59) 28.49,151.59 v1(31.5,148.59) 31.88,148.97 31.88,155.19 34.54,157.86 59.95,157.86 63.12,161.03 63.12,168.21 64.2,169.29 v1(65.53,169.29)
  BOTTOM w0.254: U62.3 65.23,169.59 v1(65.53,169.29) ; U66.2 C282.1 v1(24.03,154.01) ; v1(27.07,158.77) R352.1 28.07,158.09 R351.1 ; R347.2 v1(21.06,161.1) ; R362.1 v1(24.85,151.59) ; R354.1 v1(24.53,158.76)
ADDR: length 1.8
  BOTTOM w0.132: R622.2 147.02,52.3 U99.26
APP_CARD_PSTN: length 11.3
  TOP w0.132: J18.113 85.72,62.36 86.18,61.9 89.57,61.9 89.92,62.25 89.92,62.7 89.4,63.21 U46.4 R238.1
APP_PRG0_PRU0GPO16: length 84.7
  TOP w0.132: J18.19 v1(84.71,33.86)
  L12_SIG4 w0.084: v1(84.71,33.86) 85.17,33.4 87.39,33.4 103.14,49.15 113.42,49.15 114.12,49.85 114.74,49.85 124.46,59.56 124.46,65.08 127.97,68.59 142.69,68.59 146.85,72.76 v1(146.85,73.21)
  BOTTOM w0.132: R570.2 146.75,73.34 146.85,73.24 v1(146.85,73.21)
APP_PRG0_PRU0GPO17: length 100.9
  TOP w0.132: J18.10 75.4,31.36 v1(74.9,31.86)
  L10_SIG3 w0.084: v1(74.9,31.86) 75.36,31.4 82.01,31.4 82.93,32.32 85.73,32.32 105.19,51.78 111.06,51.78 111.91,52.63 114.67,52.63 124.54,62.49 124.54,63.47 128.4,67.34 145.79,67.34 149.07,70.61 151.82,70.61 v1(154.34,73.14)
  BOTTOM w0.132: R589.2 v1(154.34,73.14)
APP_PRG0_PRU1GPO0: length 85.4
  TOP w0.132: v1(74.9,36.86) 75.4,36.36 J18.30
  L10_SIG3 w0.084: v1(140.65,73.27) 137.8,70.41 127.2,70.41 127.17,70.38 127.13,70.38 121.49,64.74 121.49,63.97 115.41,57.89 103.82,57.89 90.87,44.93 84.27,44.93 82.63,43.29 82.63,42.73 76.3,36.4 75.36,36.4 v1(74.9,36.86)
  BOTTOM w0.132: R576.2 v1(140.65,73.27)
APP_PRG0_PRU1GPO1: length 80.9
  TOP w0.132: v1(74.9,37.86) 75.4,37.36 J18.34
  L10_SIG3 w0.084: v1(74.9,37.86) 75.36,37.4 76.44,37.4 82.02,42.98 82.02,43.54 84.02,45.54 90.62,45.54 103.57,58.5 115.15,58.5 120.64,63.98 120.64,64.77 126.89,71.02 134.34,71.02 v1(136.59,73.27)
  BOTTOM w0.132: R580.2 v1(136.59,73.27)
APP_PRG0_PRU1GPO2: length 80.9
  TOP w0.132: J18.32 v1(75.82,36.86)
  L10_SIG3 w0.084: v1(75.82,36.86) 76.33,36.86 82.32,42.85 82.32,43.41 84.15,45.24 90.74,45.24 103.7,58.19 115.28,58.19 120.94,63.85 120.94,64.69 126.96,70.71 136.07,70.71 v1(138.62,73.27)
  BOTTOM w0.132: R578.2 v1(138.62,73.27)
APP_PRG0_PRU1GPO3: length 85.5
  TOP w0.132: J18.28 v1(75.82,35.86)
  L10_SIG3 w0.084: v1(75.82,35.86) 76.28,35.86 82.93,42.51 82.93,43.16 84.4,44.63 91,44.63 103.95,57.58 115.53,57.58 121.79,63.84 121.79,64.64 127.23,70.08 127.3,70.08 127.33,70.1 139.52,70.1 v1(142.68,73.27)
  BOTTOM w0.132: R574.2 v1(142.68,73.27)
APP_PRG0_PRU1GPO4: length 89.9
  TOP w0.132: v1(74.9,35.86) 75.4,35.36 J18.26
  L10_SIG3 w0.084: v1(144.72,73.27) 141.25,69.8 127.37,69.8 122.1,64.53 122.1,63.71 115.66,57.28 104.08,57.28 91.12,44.32 84.53,44.32 83.31,43.11 83.31,42.46 76.25,35.4 75.36,35.4 v1(74.9,35.86)
  BOTTOM w0.132: R572.2 v1(144.72,73.27)
APP_PRG0_PRU1GPO5: length 101.4
  TOP w0.132: J18.8 v1(75.82,30.86)
  L10_SIG3 w0.084: v1(75.82,30.86) 82.61,30.86 83.07,31.32 85.73,31.32 96.65,42.24 96.65,42.72 105.4,51.47 111.19,51.47 112.04,52.32 114.8,52.32 124.84,62.37 124.84,63.31 128.56,67.03 145.92,67.03 149.12,70.23 153.67,70.23 v1(156.58,73.14)
  BOTTOM w0.132: R587.2 v1(156.58,73.14)
APP_UART1_CTS: length 68
  TOP w0.132: U26.13 v1(89.93,106.39) ; J16.27 v1(51.93,71.75)
  L10_SIG3 w0.084: v1(89.93,106.39) 79.43,95.89 70.04,95.89 69.66,95.5 57.14,95.5 52.91,91.27 52.08,91.27 50.11,89.3 50.11,88.92 50.34,88.69 50.34,79.83 50.91,79.26 50.91,75.51 51.44,74.99 51.44,72.25 v1(51.93,71.75)
APP_UART1_RTS: length 68.6
  TOP w0.132: v1(87.33,107.43) 87.98,106.78 U26.10 ; J16.29 51.43,72.17 v1(50.93,72.67)
  L10_SIG3 w0.084: v1(87.33,107.43) 85.39,107.43 74.55,96.6 56.55,96.6 51.65,91.69 50.99,91.69 49.14,89.84 49.14,78.63 49.57,78.19 49.57,74.03 v1(50.93,72.67)
APP_UART1_RX: length 73.4
  TOP w0.132: J16.31 v1(50.93,71.75) ; U26.6 v1(88.63,111.99)
  L10_SIG3 w0.084: v1(50.93,71.75) 50.2,71.75 47.68,74.28 47.68,78.66 47.95,78.94 47.95,91.12 52.33,95.5 53.78,95.5 55.5,97.22 73.28,97.22 88.05,111.99 v1(88.63,111.99)
APP_UART1_TX: length 75.4
  TOP w0.132: U26.3 90.58,112.38 v1(89.93,113.03) ; J16.33 50.43,72.17 v1(49.93,72.67)
  L10_SIG3 w0.084: v1(89.93,113.03) 89.09,112.19 89.09,111.57 74.42,96.9 55.75,96.9 52.31,93.46 50.72,93.46 48.26,91 48.26,78.61 48.64,78.23 48.64,73.96 v1(49.93,72.67)
ATEST0_POK: length 19.6
  TOP w0.132: U34.B1 v1(158.36,108.99)
  BOTTOM w0.122: 158.36,109.6 v1(158.36,108.99)
  BOTTOM w0.132: 158.36,109.6 158.36,110.89 162.62,115.16 162.62,117.79 166.43,121.6 TP29.1
ATEST0_POR: length 24.2
  TOP w0.132: U34.AA6 v1(142.36,104.99)
  L05_SIG2 w0.084: v1(142.36,104.99) 142.12,104.99 141.72,104.58 136.14,104.58 133.69,107.04 122.1,107.04 122.09,107.03 v1(121.63,107.03)
  BOTTOM w0.132: TP50.1 v1(121.63,107.03)
ATEST-MAIN: length 18.7
  TOP w0.132: U34.AC23 v1(140.76,90.59)
  BOTTOM w0.122: 139.56,86.06 139.56,89.95 139.81,90.2 140.36,90.2 v1(140.76,90.59)
  BOTTOM w0.132: 139.56,86.06 139.56,83.94 138.56,82.93 TP58.1
BOOST_DRIVE: length 28.8
  TOP w0.132: U14.15 v1(69.45,142.06) ; v1(92.65,142.74) 92.86,142.95 U13.4
  L05_SIG2 w0.084: v1(92.65,142.74) 90.44,142.74 86.44,138.74 72.77,138.74 v1(69.45,142.06)
BOOT_EEPROM_A0: length 3.1
  TOP w0.132: U9.1 R23.2 R24.2
BOOT_EEPROM_A1: length 3.2
  TOP w0.132: U9.2 158.37,157.78 158.62,158.03 R22.2 R21.2
BOOT_EEPROM_A2: length 3.3
  TOP w0.132: U9.3 157.1,157.53 156.59,158.03 R20.1 R19.1
BOOT_EEPROM_WP: length 1.6
  TOP w0.132: R38.2 158.37,150.33 U9.7
BOOTMODE_I2C_SCL: length 77.7
  L12_SIG4 w0.084: v1(120.85,8.26) 119.94,7.35 119.94,5.2 120.36,4.78 137.59,4.78 141.34,8.52 141.34,28.74 146.48,33.88 146.48,38.01 143.7,40.78 143.7,44.53 145.42,46.24 145.42,49.77 v1(146.45,50.8)
  BOTTOM w0.132: R696.2 120.84,9.8 120.4,9.36 120.4,9 120.4,9 120.4,8.99 120.85,8.54 v1(120.85,8.26) J41.37 ; U99.29 v1(146.45,50.8)
BOOTMODE_I2C_SDA: length 80.4
  L12_SIG4 w0.084: v1(147.36,50.8) 145.72,49.16 145.72,46.12 144.03,44.43 144.03,40.92 146.81,38.14 146.81,33.74 141.64,28.58 141.64,8.4 137.72,4.47 120.23,4.47 118.94,5.77 118.94,7.35 v1(119.85,8.26)
  BOTTOM w0.132: U99.30 146.87,50.3 147.36,50.8 v1(147.36,50.8) ; J41.39 v1(119.85,8.26) 119.4,8.71 119.4,9.36 119.82,9.79 R697.2
BOOTMODEON: length 247.5
  TOP w0.132: U17.4 v1(162.54,137.23)
  L10_SIG3 w0.084: v1(146.05,61.68) 146.05,62.94 147.83,64.72 148.99,64.72 152.84,60.87 162.85,60.87 v1(168.47,66.48)
  L12_SIG4 w0.084: v1(168.47,66.48) 173.61,66.48 178.84,61.26 192.04,61.26 200.72,69.94 200.72,140.71 193.42,148.01 178.42,148.01 167.64,137.23 v1(162.54,137.23) ; v1(146.05,61.68) 145.33,60.96 142.87,60.96 141.72,62.11 140.31,62.11 140.15,61.96 140.15,49.64 139.73,49.21 135.38,49.21 134.72,48.55 134.72,41.52 135.88,40.36 v1(141.92,40.36)
  BOTTOM w0.132: U102.22 126.53,46.01 127,46.48 139.57,46.48 141.92,44.13 v1(141.92,40.36) 141.92,40.13 141.77,39.98 U105.22 ; U95.15 145.77,61.41 v1(146.05,61.68) 145.83,61.91 U95.14
BUCK_DRIVE: length 21.6
  TOP w0.132: U18.4 v1(86.61,134.62) ; U14.19 v1(69.45,139.46)
  L05_SIG2 w0.084: v1(69.45,139.46) 74.03,134.87 78.93,134.87 79.19,134.62 v1(86.61,134.62)
CAP_VDD_WKUP: length 36.3
  TOP w0.132: U34.V11 v1(144.76,100.99) ; U34.W10 v1(143.96,101.79) ; U34.V9 v1(144.76,102.59) ; U34.W12 v1(143.96,100.19) ; U34.M22 v1(150.36,91.39)
  TOP w0.254: v1(146.18,113.29) 146.18,113.71 C115.1
  L05_SIG2 w0.122: 147.57,109.22 147.57,102.46 147.3,102.18 145.16,102.18 v1(144.76,102.59) 144.76,102.52 144.02,101.79 v1(143.96,101.79) v1(144.76,100.99) v1(143.96,100.19)
  L05_SIG2 w0.203: v1(146.18,113.29) 147.41,112.06 147.41,109.39 147.57,109.22
  L12_SIG4 w0.122: v1(150.36,91.39) 149.97,91.78 149.97,93.13 149.71,93.38 144.61,93.38 144.36,93.63 144.36,99.78 v1(143.96,100.19)
  BOTTOM w0.203: v1(150.36,91.39) 150.38,91.39 C571.1
CAP_VDDA_1P8_IOLDO0: length 41.3
  TOP w0.132: U34.G12 v1(154.36,100.19)
  TOP w0.203: U34.AA16 v1(142.36,96.19) ; U34.AA10 v1(142.36,101.79) ; U34.G19 v1(154.36,93.79) ; U34.P20 v1(148.76,92.99)
  TOP w0.254: C170.2 162.2,94.17 v1(161.06,93.03)
  L05_SIG2 w0.122: v1(154.36,93.79) 154.76,93.39 158.84,93.39 159.41,92.81 159.77,92.81
  L05_SIG2 w0.254: v1(161.06,93.03) 160.84,92.81 159.77,92.81
  L07_PWR2 w0.122: v1(142.36,96.19) 141.96,95.8 141.96,93.63 142.19,93.4 148.35,93.4 v1(148.76,92.99) 149.15,93.38 153.95,93.38 v1(154.36,93.79)
  L10_SIG3 w0.122: v1(154.36,100.19) 153.96,99.8 153.96,94.19 154.36,93.8 v1(154.36,93.79)
  L12_SIG4 w0.122: v1(142.36,101.79) 141.96,101.4 141.96,96.58 v1(142.36,96.19)
CAP_VDDA_1P8_IOLDO1: length 13.6
  TOP w0.132: U34.Y19 v1(143.16,93.79) ; v1(143.13,81.87) C200.1
  L05_SIG2 w0.084: v1(143.13,81.87) 143.55,82.28 143.55,86.43 143.55,86.43 143.55,93.4 v1(143.16,93.79)
CAP_VDDA_1P8_IOLDO_WKUP: length 15.1
  TOP w0.132: U34.V8 v1(144.76,103.39) ; C113.2 142.75,113.73 142.38,113.36 v1(142.38,112.94) ; U34.AA8 v1(142.36,103.39)
  L03_SIG1 w0.084: v1(142.38,112.94) 143.15,112.17 143.15,107.94 142.76,107.55 142.76,103.8 v1(142.36,103.39) 142.75,103 144.36,103 v1(144.76,103.39)
CAP_VDDA_1P8_SDIO: length 21.5
  TOP w0.203: U34.K20 v1(151.96,92.99) ; U34.G17 v1(154.36,95.39) ; U34.J17 v1(152.76,95.39)
  TOP w0.254: C180.1 163.15,91.5 v1(162.93,91.29)
  L06_PWR1 w0.122: v1(151.96,92.99) 152.36,92.58 152.92,92.58 153.16,92.34 153.16,90.42 153.4,90.18 158.08,90.18
  L06_PWR1 w0.254: v1(162.93,91.29) 161.94,90.3 158.19,90.3 158.08,90.18
  L12_SIG4 w0.122: v1(154.36,95.39) 153.95,95.8 153.16,95.8 v1(152.76,95.39) 153.16,94.98 153.16,93.65 153.15,93.63 153.15,93.63 152.92,93.4 152.36,93.4 v1(151.96,92.99)
CAP_VDDAR_CORE0: length 16.6
  TOP w0.132: C167.1 163.13,95.63 v1(161.99,96.77) ; U34.P17 v1(148.76,95.39)
  L05_SIG2 w0.122: 159.54,95.78 149.15,95.78 v1(148.76,95.39)
  L05_SIG2 w0.203: 159.54,95.78 160.53,96.77 v1(161.99,96.77)
CAP_VDDAR_CORE1: length 15.1
  TOP w0.132: U34.V17 v1(144.76,95.39) ; C165.1 v1(132.73,96.43)
  L03_SIG1 w0.084: v1(132.73,96.43) 133.26,96.96 136.14,96.96 136.56,97.38 142.52,97.38 142.76,97.13 142.76,96.03 143.01,95.78 144.36,95.78 v1(144.76,95.39)
CAP_VDDAR_CORE2: length 14.1
  TOP w0.132: U34.W16 v1(143.96,96.19) ; C159.1 v1(132.73,97.64)
  L03_SIG1 w0.084: v1(132.73,97.64) 135.36,97.64 135.68,97.96 137.02,97.96 137.24,98.18 139.63,98.18 139.86,97.95 143.16,97.95 143.55,97.56 143.55,96.6 v1(143.96,96.19)
CAP_VDDAR_CORE3: length 14.9
  TOP w0.132: U34.M14 v1(150.36,98.59)
  TOP w0.203: C157.1 163.7,98.88 v1(163.06,98.88)
  L05_SIG2 w0.203: v1(163.06,98.88) 161.38,98.88 160.41,97.92 150.66,97.92 150.36,98.22 v1(150.36,98.59)
CAP_VDDAR_CORE4: length 14
  TOP w0.132: U34.L15 v1(151.16,96.99) ; C158.1 v1(163.08,97.92)
  L05_SIG2 w0.203: v1(151.16,96.99) 151.66,97.5 160.5,97.5 161.48,98.48 162.52,98.48 v1(163.08,97.92)
CAP_VDDAR_MCU: length 14.9
  TOP w0.132: U34.U10 v1(145.56,101.79)
  TOP w0.254: v1(147.83,113.29) 147.83,113.71 C116.1
  L12_SIG4 w0.122: 147.7,109.47 147.82,109.36 147.82,102.54 147.46,102.18 145.95,102.18 v1(145.56,101.79)
  L12_SIG4 w0.254: 147.7,109.47 147.54,109.64 147.54,112.56 147.83,112.85 v1(147.83,113.29)
CAP_VDDAR_MPU0_0: length 16.9
  TOP w0.132: v1(163.08,101.22) 163.21,101.35 C151.1 ; U34.M12 v1(150.36,100.19)
  L05_SIG2 w0.084: v1(163.08,101.22) 160.28,98.42 159.91,98.42 159.68,98.2 151,98.2 150.75,98.45 150.75,99.8 v1(150.36,100.19)
CAP_VDDAR_MPU0_1: length 21.6
  TOP w0.132: U34.N12 v1(149.56,100.19)
  L03_SIG1 w0.084: v1(149.56,100.19) 149.96,100.6 151.32,100.6 151.54,100.82 151.54,106.72 151.81,107 152.12,107 152.35,107.23 152.35,109.15 152.35,109.15 152.35,110.69 153.35,111.7 153.35,113.61 154.69,114.95 156.71,114.95 v1(157.04,114.63)
  BOTTOM w0.132: C386.1 v1(157.04,114.63)
CAP_VDDAR_MPU2: length 16.3
  TOP w0.132: C201.1 v1(147.57,82.48) ; U34.N18 v1(149.56,94.59)
  L10_SIG3 w0.084: v1(147.57,82.48) 150.75,85.65 150.75,94.75 150.52,94.98 149.95,94.98 v1(149.56,94.59)
CAP_VDDAR_MPU3: length 15.3
  TOP w0.132: U34.N15 v1(149.56,96.99) ; C164.1 v1(163.08,96.77)
  L05_SIG2 w0.084: v1(163.08,96.77) 162.67,97.18 160.27,97.18 159.7,96.61 149.94,96.61 v1(149.56,96.99)
CAP_VDDAR_WKUP: length 16.3
  TOP w0.132: U34.Y10 v1(143.16,101.79)
  TOP w0.254: C114.1 145.03,113.71 v1(145.03,113.29)
  L05_SIG2 w0.122: 146.76,109.31 146.76,105.65 146.5,105.38 145.39,105.38 145.15,105.13 145.15,103.23 144.9,102.98 144.47,102.98 144.35,102.86 144.35,102.43 144.12,102.2 144.11,102.2 144.1,102.18 143.55,102.18 v1(143.16,101.79)
  L05_SIG2 w0.203: v1(145.03,113.29) 145.07,113.29 146.76,111.6 146.76,109.31
CAP_VDDSHV_SDLDO: length 23.5
  TOP w0.203: U34.H18 v1(153.56,94.59)
  L06_PWR1 w0.122: 159.55,90.98 154.13,90.98 153.96,91.15 153.96,92.33 153.72,92.58 153.41,92.58 153.15,92.85 153.15,94.18 v1(153.56,94.59)
  L06_PWR1 w0.254: 159.55,90.98 161.98,90.98 162.83,91.83 v1(168.78,91.83)
  BOTTOM w0.254: v1(168.78,91.83) 168.78,92.81 168.53,93.06 C541.1 168.52,93.55 167.91,93.55 167.73,93.72 FL20.1
CDCEL_XIN: length 3.6
  TOP w0.132: R194.2 77.26,98.06 U32.11
CDCEL_XOUT: length 3.5
  TOP w0.132: U32.12 75.41,98.56 75.43,98.54 77.51,98.54 R191.2
COMP: length 2.9
  TOP w0.132: R55.1 78.23,142.96 C48.1 77.67,143.81 77.48,144.01 U14.9
CON_LCD_PWR_DN: length 102.6
  L05_SIG2 w0.084: v1(81.27,12.95) 82.73,11.49 118.17,11.49 124.71,18.03 137.6,18.03 139.08,19.51 158.55,19.51 162.54,23.5 v1(162.54,34.52)
  BOTTOM w0.132: J35.40 163.04,35.02 v1(162.54,34.52) ; U110.7 81.77,13.45 v1(81.27,12.95)
CS: length 30.8
  TOP w0.132: U14.12 v1(69.45,144.01) ; R62.1 v1(91.25,139.51) 91.25,139.51
  L05_SIG2 w0.084: v1(91.25,139.51) 90.17,138.44 72.26,138.44 68.9,141.8 68.9,143.45 v1(69.45,144.01)
CSI0_RXN0: length 100.3
  TOP w0.107: v1(156.49,10.73) 156.34,10.58 156.34,10.03 156.29,9.98 J22.7 ; v1(153.94,85.29) 154.21,85.56 154.21,86.74 U34.G28
  L12_SIG4 w0.076: v1(153.94,85.29) 154.22,85.01 154.22,80.93 155.9,79.24 155.9,71.14 153.09,68.33 153.09,64.2 150.46,61.57 150.46,40.75 149.33,39.62 149.33,32.29 152.92,28.69 152.92,28.42 152.27,27.78 152.27,27.32 152.62,26.97 153.08,26.97 153.77,27.65 153.96,27.65 155.37,26.24 155.82,26.24 156.72,27.14 156.95,27.14 157.14,26.95 157.14,26.72 156.25,25.84 156.25,25.36 156.6,25.01 157.04,25.01 157.94,25.92 158.17,25.92 158.36,25.73 158.36,25.5 157.47,24.61 157.47,24.14 158.39,23.22 158.39,14.88 154.74,11.23 154.74,11 154.74,10.06 155.04,9.75 155.96,9.75 156.32,10.12 156.32,10.56 v1(156.49,10.73)
  BOTTOM w0.107: J39.9 156.54,10.78 v1(156.49,10.73)
CSI0_RXN1: length 100.1
  TOP w0.107: v1(158.18,10.73) 158,10.55 158,10.21 157.71,9.92 157.71,9.49 157.79,9.41 J22.11 ; U34.H27 v1(153.56,87.39)
  L12_SIG4 w0.076: v1(153.56,87.39) 153.81,87.13 153.81,86.09 152.73,85.01 152.73,80.96 154.74,78.95 154.74,71.06 152,68.32 152,64.2 149.71,61.91 149.71,41.55 148.55,40.4 148.55,31.94 150.05,30.44 150.05,27.79 152.35,25.49 152.35,25.26 151.68,24.59 151.68,24.13 152.03,23.78 152.48,23.78 153.16,24.45 153.39,24.45 153.57,24.27 153.57,24.04 152.9,23.36 152.9,22.91 153.25,22.56 153.71,22.56 154.38,23.23 154.61,23.23 156.15,21.69 156.15,14.9 153.95,12.7 153.95,9.66 154.66,8.96 157.1,8.96 158.08,9.94 158.08,10.63 v1(158.18,10.73)
  BOTTOM w0.107: J39.12 158.04,10.59 v1(158.18,10.73)
CSI0_RXN2: length 100.1
  TOP w0.107: J22.15 159.29,9.91 159.64,10.26 159.64,10.57 v1(159.8,10.73) ; U34.F26 v1(154.36,88.99)
  L12_SIG4 w0.076: v1(154.36,88.99) 154.36,88.72 155,88.07 155,86.04 155.51,85.54 155.51,84.99 156.82,83.68 156.82,80.81 156.93,80.7 156.93,78.6 157.37,78.17 157.37,71.15 154.95,68.73 154.95,64.54 151.48,61.07 151.48,41.55 152.06,40.97 152.06,36.55 150.6,35.08 150.6,32.87 153.84,29.62 159.26,29.62 160.19,28.7 160.19,27.66 160.35,27.5 161.07,27.5 161.39,27.18 161.39,26.68 161.07,26.36 160.35,26.36 160.19,26.2 160.19,25.93 160.35,25.77 161.07,25.77 161.39,25.44 161.39,24.95 161.07,24.63 160.35,24.63 160.19,24.46 160.19,24.2 160.35,24.04 161.07,24.04 161.39,23.71 161.39,23.22 161.07,22.89 160.35,22.89 160.19,22.73 160.19,13.79 159.71,13.32 159.71,10.82 v1(159.8,10.73)
  BOTTOM w0.107: v1(159.8,10.73) 159.54,10.99 J39.15
CSI0_RXN3: length 100.4
  TOP w0.107: v1(161.33,10.73) 161.04,10.44 161.04,10.28 160.79,10.03 J22.19 ; U34.H25 v1(153.56,88.99)
  L12_SIG4 w0.076: v1(153.56,88.99) 153.56,88.35 152.82,87.61 152.82,86.62 151.56,85.36 151.56,83.12 151.23,82.79 151.23,80.96 153.66,78.54 153.66,71.11 151.17,68.62 151.17,64.52 148.95,62.3 148.95,42.17 147.8,41.02 147.8,26.82 149.24,25.39 149.24,13.28 154.32,8.21 159.21,8.21 161.05,10.04 161.05,10.61 161.16,10.73 v1(161.33,10.73)
  BOTTOM w0.107: J39.18 161.04,10.44 v1(161.33,10.73)
CSI0_RXN4: length 100.5
  TOP w0.107: U34.G24 v1(154.36,89.79) ; J22.23 162.29,9.77 162.73,10.21 162.73,10.67 162.84,10.79 v1(163.04,10.79)
  L12_SIG4 w0.076: v1(154.36,89.79) 154.57,89.57 154.75,89.57 154.88,89.44 154.88,89.09 155.3,88.67 155.3,86.3 157.66,83.93 157.66,80.58 157.87,80.37 157.87,70.85 155.84,68.81 155.84,64.45 153.76,62.37 153.76,55.78 151.96,53.98 151.96,41.87 152.55,41.28 152.55,34.2 153.85,32.91 158.41,32.91 164.57,26.75 164.57,9.84 164.21,9.48 162.93,9.48 162.65,9.76 162.65,10.94 162.73,11.02 162.9,11.02 163.04,10.88 v1(163.04,10.79)
  BOTTOM w0.107: v1(163.04,10.79) 162.54,11.29 J39.21
CSI0_RXP0: length 100.2
  TOP w0.107: v1(155.65,10.73) 155.74,10.82 155.94,10.82 156.04,10.71 156.04,10.17 155.79,9.91 J22.5 ; U34.F28 154.5,86.74 154.5,85.57 v1(154.78,85.29)
  L12_SIG4 w0.076: v1(154.78,85.29) 154.68,85.29 154.5,85.1 154.5,84.92 154.49,84.92 154.49,81.04 156.18,79.35 156.18,71.03 153.37,68.21 153.37,64.08 150.73,61.45 150.73,40.64 149.6,39.51 149.6,32.4 153.2,28.81 153.2,28.31 152.55,27.66 152.55,27.43 152.74,27.25 152.97,27.25 153.65,27.93 154.07,27.93 155.49,26.52 155.7,26.52 156.6,27.42 157.06,27.42 157.41,27.07 157.41,26.61 156.53,25.72 156.53,25.48 156.71,25.29 156.93,25.29 157.83,26.19 158.29,26.19 158.64,25.84 158.64,25.38 157.75,24.5 157.75,24.25 158.67,23.33 158.67,14.77 155.02,11.11 155.02,10.17 155.16,10.03 155.84,10.03 156.04,10.23 156.04,10.75 155.96,10.83 155.73,10.83 155.65,10.75 v1(155.65,10.73)
  BOTTOM w0.107: J39.8 156.04,10.34 v1(155.65,10.73)
CSI0_RXP1: length 100.4
  TOP w0.107: U34.G27 v1(154.36,87.39) ; v1(157.34,10.73) 157.4,10.79 157.61,10.79 157.71,10.69 157.71,10.33 157.37,9.99 157.37,9.38 157.29,9.3 J22.9
  L12_SIG4 w0.076: v1(157.34,10.73) 157.46,10.85 157.72,10.85 157.81,10.76 157.81,10.05 156.99,9.24 154.77,9.24 154.23,9.78 154.23,12.59 156.43,14.78 156.43,21.8 154.73,23.5 154.27,23.5 153.59,22.83 153.36,22.83 153.18,23.02 153.18,23.25 153.85,23.92 153.85,24.38 153.5,24.73 153.04,24.73 152.37,24.06 152.14,24.06 151.95,24.24 151.95,24.47 152.62,25.15 152.62,25.61 150.33,27.9 150.33,30.56 148.83,32.06 148.83,40.29 149.98,41.44 149.98,61.8 152.27,64.09 152.27,68.2 155.02,70.95 155.02,79.07 153.01,81.08 153.01,84.9 154.09,85.98 154.09,87.12 v1(154.36,87.39)
  BOTTOM w0.107: v1(157.34,10.73) 157.54,10.93 J39.11
CSI0_RXP2: length 99.7
  TOP w0.107: U34.G26 v1(154.36,88.19) ; J22.13 158.79,9.91 159.04,10.16 159.12,10.16 159.34,10.39 159.34,10.63 159.24,10.73 v1(159.04,10.73)
  L12_SIG4 w0.076: v1(159.04,10.73) 159.04,10.66 159.12,10.58 159.35,10.58 159.43,10.66 159.43,13.43 159.91,13.91 159.91,22.85 160.23,23.17 160.95,23.17 161.11,23.33 161.11,23.6 160.95,23.76 160.23,23.76 159.91,24.08 159.91,24.58 160.23,24.9 160.95,24.9 161.11,25.06 161.11,25.33 160.95,25.49 160.23,25.49 159.91,25.82 159.91,26.31 160.23,26.63 160.95,26.63 161.11,26.8 161.11,27.06 160.95,27.22 160.23,27.22 159.91,27.55 159.91,28.59 159.15,29.35 153.73,29.35 150.32,32.75 150.32,35.19 151.79,36.66 151.79,40.85 151.21,41.43 151.21,61.19 154.67,64.65 154.67,68.84 157.09,71.26 157.09,78.05 156.65,78.49 156.65,80.58 156.54,80.7 156.54,83.56 155.23,84.87 155.23,85.42 154.73,85.93 154.73,87.82 v1(154.36,88.19)
  BOTTOM w0.107: v1(159.04,10.73) J39.14
CSI0_RXP3: length 100.6
  TOP w0.107: U34.G25 v1(153.56,89.79) ; v1(160.57,10.73) 160.74,10.55 160.74,10.4 160.29,9.94 J22.17
  L12_SIG4 w0.076: v1(160.57,10.73) 160.77,10.53 160.77,10.16 159.1,8.48 154.43,8.48 149.52,13.4 149.52,25.5 148.08,26.94 148.08,40.91 149.23,42.05 149.23,62.18 151.45,64.4 151.45,68.51 153.93,70.99 153.93,78.66 151.51,81.08 151.51,82.68 151.84,83.01 151.84,85.24 153.1,86.51 153.1,87.5 153.93,88.33 153.93,89.15 153.56,89.52 v1(153.56,89.79)
  BOTTOM w0.107: J39.17 160.54,10.76 v1(160.57,10.73)
CSI0_RXP4: length 100.2
  TOP w0.107: v1(162.24,10.79) 162.43,10.6 162.43,10.34 162.26,10.16 162.04,10.16 161.79,9.91 J22.21 ; U34.F24 v1(155.16,89.79)
  L12_SIG4 w0.076: v1(162.24,10.79) 162.37,10.66 162.37,9.65 162.81,9.21 164.33,9.21 164.84,9.73 164.84,26.86 158.52,33.19 153.96,33.19 152.83,34.32 152.83,41.39 152.23,41.99 152.23,53.86 154.04,55.67 154.04,62.26 156.11,64.33 156.11,68.7 158.15,70.74 158.15,80.48 157.94,80.7 157.94,84.05 155.57,86.41 155.57,88.79 155.16,89.2 v1(155.16,89.79)
  BOTTOM w0.107: J39.20 162.04,10.59 v1(162.24,10.79)
CSI_`MCU_SPI0_D0: length 50.5
  TOP w0.132: J22.18 160.29,16.9 v1(160.79,17.4)
  L05_SIG2 w0.084: v1(160.79,17.4) 160.33,17.85 157.11,17.85 156.15,16.89 154.65,16.89 153.95,17.59 146.33,17.59 v1(145.41,16.68)
  BOTTOM w0.132: v1(145.41,16.68) U111.4 ; J39.30 167.04,8.36 167.78,7.62 167.78,7.62 168.36,7.04 172.67,7.04 172.88,7.04 173.67,7.83 173.67,14.67 172.58,15.76 166.17,15.76 164.03,17.9 161.29,17.9 v1(160.79,17.4)
CSI_MCU_SCL: length 31
  TOP w0.132: v1(154.79,17.4) 154.29,16.9 J22.2
  L05_SIG2 w0.084: v1(154.79,17.4) 153.71,18.48 144.11,18.48 v1(143.57,19.01)
  BOTTOM w0.132: v1(154.79,17.4) 155.42,18.03 159.28,18.03 159.89,17.42 159.89,14.73 160.21,14.41 162.83,14.41 164.54,12.7 J39.25 ; R662.2 v1(143.57,19.01) U111.1
CSI_MCU_SDA: length 63.8
  TOP w0.132: J22.4 v1(154.79,16.42)
  L05_SIG2 w0.084: v1(154.79,16.42) 154.46,16.1 151.77,16.1 151.23,16.64 v1(147.57,16.64)
  BOTTOM w0.132: v1(147.57,16.64) 147.13,17.08 R666.2 146.99,17.87 146.3,17.18 U111.3 ; J39.24 164.04,7.22 163.69,6.87 163.69,2.22 164.08,1.84 168.05,1.84 173.94,7.72 173.94,14.79 172.66,16.06 166.5,16.06 164.26,18.3 155.01,18.3 154.34,17.62 154.34,16.87 v1(154.79,16.42)
CSI_MCU_SPI0_CLK: length 36.5
  TOP w0.132: J22.20 v1(160.79,16.42)
  L05_SIG2 w0.084: v1(160.79,16.42) 156.68,12.32 145.51,12.32 144.24,13.58 144.24,15.34 145.12,16.22 145.87,16.22 v1(146.33,16.68)
  BOTTOM w0.132: J39.31 167.54,12.7 165.51,14.73 161.3,14.73 160.79,15.24 v1(160.79,16.42) ; U111.5 145.83,16.18 v1(146.33,16.68)
CSI_MCU_SPI0_CS0: length 52.9
  TOP w0.132: J22.22 161.79,16.9 v1(162.29,17.4)
  L05_SIG2 w0.084: v1(145.41,15.68) 145.34,15.68 144.58,14.92 144.58,13.68 145.63,12.62 156.34,12.62 160.6,16.88 161.77,16.88 v1(162.29,17.4)
  BOTTOM w0.132: J39.32 168.04,7.73 168.47,7.3 172.56,7.3 172.77,7.3 173.41,7.94 173.41,14.55 172.47,15.49 166.06,15.49 164.15,17.4 v1(162.29,17.4) ; v1(145.41,15.68) U111.6
CSI_REF_CLK: length 18
  TOP w0.132: J22.10 157.29,16.9 v1(157.79,17.4)
  L05_SIG2 w0.084: v1(157.79,17.4) 156.07,15.68 151.75,15.68 151.17,16.27 150.32,16.27 148.72,14.68 v1(145.41,14.68)
  BOTTOM w0.132: U111.8 v1(145.41,14.68)
CSI_REF_CLK_1V8: length 1.8
  BOTTOM w0.132: J39.26 R699.2
CSI_REF_CLK_3V3: length 4.4
  BOTTOM w0.132: R674.2 U111.13
CSI_RESETN: length 34.6
  TOP w0.132: J22.14 158.79,16.9 v1(159.29,17.4)
  L05_SIG2 w0.084: v1(159.29,17.4) 158.83,16.94 158.83,15.54 156.22,12.93 145.76,12.93 144.96,13.73 144.96,14.87 145.22,15.13 145.79,15.13 v1(146.33,15.68)
  BOTTOM w0.132: v1(159.29,17.4) 158.75,16.86 158.75,14.67 159.45,13.97 162.85,13.97 163.54,13.28 J39.23 ; v1(146.33,15.68) 145.83,15.18 U111.7
CSI_RSTN: length 9
  L12_SIG4 w0.084: v1(137.73,19.62) 137.73,16.77 139.32,15.18 v1(140.24,15.18)
  BOTTOM w0.132: U111.14 140.4,15.18 v1(140.24,15.18) ; R664.1 U108.4 v1(137.73,19.62)
CTI_TCK: length 7.1
  TOP w0.132: R233.1 106.81,73.15 107.97,74.32 U42.3
DDR_A0: length 143.6
  TOP w0.208: U34.A10 160.53,103.16 v1(160.53,104.14) ; U38.L3 v1(189.21,83.09) ; U20.L3 v1(189.21,124.24) ; U16.L3 v1(189.21,137.95) ; U25.L3 v1(189.21,110.52) ; U33.L3 v1(189.21,96.81)
  L05_SIG2 w0.127: v1(160.53,104.14) 167.96,104.14 169.85,102.25 172.5,102.25 174.04,100.7 174.04,95.1 175.49,93.64 175.49,93.4 175.37,93.28 174.36,93.28 174.23,93.15 174.23,90.09 174.36,89.97 174.74,89.97 174.86,90.09 174.86,92.52 174.99,92.65 175.37,92.65 175.49,92.52 175.49,79.51 178.48,76.52 187.43,76.52 189.62,78.71 189.62,82.43 189.21,82.84 v1(189.21,83.09) 189.21,84.75 189.38,84.92 190.76,84.92 190.93,85.09 190.93,86.42 190.4,86.95 190.4,91.14 191.01,91.75 191.01,92.46 190.88,92.59 190.69,92.59 190.43,92.84 190.43,94.49 189.62,95.3 189.62,96.15 189.39,96.38 189.39,96.63 v1(189.21,96.81) 189.21,98.47 189.38,98.64 190.75,98.64 190.93,98.82 190.93,100.13 190.4,100.66 190.4,104.86 191.01,105.46 191.01,106.18 190.88,106.3 190.69,106.3 190.43,106.56 190.43,108.2 189.62,109.01 189.62,109.87 189.36,110.13 189.36,110.38 v1(189.21,110.52) 189.21,112.19 189.38,112.35 190.75,112.35 190.93,112.53 190.93,113.85 190.4,114.38 190.4,118.57 191.01,119.18 191.01,119.9 190.88,120.02 190.69,120.02 190.43,120.28 190.43,121.92 189.62,122.73 189.62,123.58 189.4,123.81 189.4,124.05 v1(189.21,124.24) 189.21,125.9 189.38,126.07 190.75,126.07 190.93,126.24 190.93,127.57 190.4,128.09 190.4,132.29 191.01,132.89 191.01,133.61 190.88,133.73 190.69,133.73 190.43,133.99 190.43,135.63 189.62,136.44 189.62,137.3 189.36,137.56 189.36,137.81 v1(189.21,137.95)
  BOTTOM w0.208: v1(189.21,137.95) 189.69,138.43 191.64,138.43 192.48,137.59 194.58,137.59 R389.1
DDR_A1: length 143.5
  TOP w0.208: U33.L7 v1(189.21,100.81) ; U16.L7 v1(189.21,141.95) ; U20.L7 v1(189.21,128.24) ; U34.D9 v1(156.76,102.59) ; U38.L7 v1(189.21,87.09) ; R43.1 v1(189.93,146.94) ; U25.L7 v1(189.21,114.52)
  L03_SIG1 w0.127: v1(189.21,87.09) 189.21,85.67 188.39,84.86 188.39,83.66 188.8,83.25 188.8,80.63 188.91,80.52 188.91,79.18 188.53,78.81 179.48,78.81 174.38,83.9 174.38,99.96 173.07,101.27 171.95,101.27 171.59,100.9 165.79,100.9 163.33,98.44 158.86,98.44 158.59,98.17 155.82,98.17 155.56,98.43 155.56,102.75 155.79,102.98 156.23,102.98 156.62,102.59 v1(156.76,102.59)
  L05_SIG2 w0.127: v1(189.21,141.95) 189.61,142.35 189.61,143.64 189.93,143.95 v1(189.93,146.94)
  L12_SIG4 w0.127: v1(189.21,141.95) 190.19,140.97 190.74,140.97 191.84,139.87 191.84,130.83 190.93,129.92 190.34,129.92 189.62,129.2 189.62,128.65 v1(189.21,128.24) 190.19,127.25 190.74,127.25 191.84,126.16 191.84,117.11 190.93,116.2 190.34,116.2 189.62,115.48 189.62,114.93 v1(189.21,114.52) 190.19,113.54 190.74,113.54 191.84,112.44 191.84,103.39 190.94,102.49 190.34,102.49 189.62,101.77 189.62,101.21 v1(189.21,100.81) 190.19,99.82 190.74,99.82 191.84,98.72 191.84,89.66 190.95,88.77 190.34,88.77 189.62,88.05 189.62,87.5 v1(189.21,87.09)
DDR_A2: length 145
  TOP w0.208: U33.M3 v1(190.01,96.81) ; U38.M3 v1(190.01,83.09) ; U25.M3 v1(190.01,110.52) ; U16.M3 v1(190.01,137.95) ; U20.M3 v1(190.01,124.24) ; U34.C9 v1(157.56,102.59)
  L05_SIG2 w0.127: v1(190.01,137.95) 190.01,137.71 190.42,137.3 190.42,136.95 190.6,136.76 191.62,136.76 191.74,136.64 191.74,125.3 191.53,125.09 190.13,125.09 190.01,124.97 v1(190.01,124.24) 190.01,124 190.42,123.59 190.42,123.23 190.6,123.05 191.62,123.05 191.74,122.92 191.74,111.58 191.53,111.38 190.13,111.38 190.01,111.26 v1(190.01,110.52) 190.01,110.28 190.42,109.87 190.42,109.51 190.6,109.33 191.62,109.33 191.74,109.21 191.74,97.87 191.53,97.66 190.13,97.66 190.01,97.54 v1(190.01,96.81) 190.01,96.56 190.42,96.16 190.42,95.8 190.6,95.61 191.62,95.61 191.74,95.49 191.74,84.13 191.55,83.95 190.13,83.95 190.01,83.83 v1(190.01,83.09) 190.01,82.84 190.42,82.43 190.42,80.5 190.37,80.44 190.37,78.42 187.73,75.79 178.18,75.79 172.4,81.57 172.4,94.72 172.28,94.85 171.89,94.85 171.77,94.72 171.77,92.98 171.65,92.86 171.26,92.86 171.14,92.98 171.14,95.35 171.26,95.48 172.28,95.48 172.4,95.6 172.4,99.83 171.36,100.86 169.8,100.86 167.27,103.39 161.11,103.39 159.6,101.89 158.85,101.89 158.53,102.2 157.95,102.2 v1(157.56,102.59)
  BOTTOM w0.127: 189.62,136.45 189.62,137.56
  BOTTOM w0.208: R393.1 194.65,135.63 194.46,135.44 194.46,135.44 194.18,135.15 193.17,135.15 192.68,135.64 190.44,135.64 189.62,136.45 ; 189.62,137.56 v1(190.01,137.95)
DDR_A3: length 143.9
  TOP w0.208: U34.E9 v1(155.96,102.59) ; U25.K7 v1(188.41,114.52) ; U33.K7 v1(188.41,100.81) ; U38.K7 v1(188.41,87.09) ; U20.K7 v1(188.41,128.24) ; U16.K7 v1(188.41,141.95)
  L03_SIG1 w0.127: v1(155.96,102.59) 156.35,102.2 156.35,99.25 156.61,98.98 160.83,98.98 161.23,99.38 163.46,99.38 166.07,102 171.64,102 171.76,102.12 171.76,103.12 171.88,103.24 173.96,103.24 174.08,103.12 174.08,102.73 173.96,102.61 172.51,102.61 172.39,102.49 172.39,102.12 172.51,102 174.24,102 174.75,101.49 174.75,85.32 180.19,79.88 180.47,79.88 180.53,79.82 187.34,79.82 188.02,80.5 188.02,85.02 188.69,85.69 188.69,86.81 v1(188.41,87.09)
  L12_SIG4 w0.127: v1(188.41,141.95) 190.22,140.14 190.77,140.14 191.45,139.46 191.45,132.73 190.82,132.09 190.82,131.26 188.82,129.26 188.82,128.65 v1(188.41,128.24) 190.22,126.43 190.77,126.43 191.45,125.75 191.45,119.01 190.82,118.38 190.82,117.54 188.82,115.54 188.82,114.93 v1(188.41,114.52) 190.22,112.71 190.77,112.71 191.45,112.03 191.45,105.31 190.82,104.68 190.82,103.82 188.82,101.82 188.82,101.21 v1(188.41,100.81) 190.22,99 190.79,99 191.45,98.33 191.45,91.56 190.82,90.92 190.82,90.11 188.82,88.11 188.82,87.5 v1(188.41,87.09)
  BOTTOM w0.127: 188.8,142.35 188.8,143.78 188.72,143.86
  BOTTOM w0.208: v1(188.41,141.95) 188.8,142.35 ; R369.1 188.93,147.66 189.38,147.21 189.38,147.09 189.4,147.08 189.4,146.67 188.72,146 188.72,143.86
DDR_A4: length 144.7
  TOP w0.208: U38.K3 v1(188.41,83.09) ; U20.K3 v1(188.41,124.24) ; U33.K3 v1(188.41,96.81) ; U34.A9 v1(159.16,102.59) ; U25.K3 v1(188.41,110.52) ; U16.K3 v1(188.41,137.95)
  L05_SIG2 w0.127: v1(188.41,137.95) 188.41,137.72 188.82,137.31 188.82,136.05 189.7,135.17 189.7,133.69 189.78,133.61 189.78,132.7 189.47,132.39 189.08,132.39 188.82,132.14 188.82,130.69 189.01,130.5 189.29,130.5 189.49,130.3 189.49,129.63 189.37,129.51 189.04,129.51 188.82,129.29 188.82,128.08 189.17,127.73 189.17,127.26 189.03,127.13 188.54,127.13 188.41,126.99 v1(188.41,124.24) 188.41,124.01 188.45,123.96 188.45,123.95 188.6,123.81 188.6,123.81 188.82,123.58 188.82,122.33 189.7,121.45 189.7,118.88 189.49,118.68 189.01,118.68 188.82,118.49 188.82,116.97 189.01,116.78 189.32,116.78 189.49,116.61 189.49,115.92 189.37,115.8 189.04,115.8 188.82,115.58 188.82,114.36 189.17,114.01 189.17,113.55 189.03,113.41 188.54,113.41 188.41,113.28 v1(188.41,110.52) 188.41,110.28 188.6,110.09 188.6,110.09 188.82,109.87 188.82,108.61 189.7,107.74 189.7,105.17 189.49,104.96 189.01,104.96 188.82,104.77 188.82,103.25 189.01,103.06 189.32,103.06 189.49,102.89 189.49,102.2 189.37,102.08 189.04,102.08 188.82,101.86 188.82,100.64 189.17,100.3 189.17,99.84 189.02,99.69 188.54,99.69 188.41,99.56 v1(188.41,96.81) 188.41,96.58 188.46,96.53 188.46,96.51 188.82,96.15 188.82,94.9 189.7,94.02 189.7,91.45 189.49,91.25 189.01,91.25 188.82,91.06 188.82,89.54 189.01,89.35 189.32,89.35 189.49,89.18 189.49,88.48 189.37,88.36 189.04,88.36 188.82,88.15 188.82,86.93 189.17,86.58 189.17,86.1 189.04,85.98 188.54,85.98 188.41,85.85 v1(188.41,83.09) 188.45,83.05 188.45,82.81 188.8,82.45 188.8,80.63 188.91,80.52 188.91,78.52 187.28,76.89 178.64,76.89 175.86,79.66 175.86,93.82 174.6,95.08 174.6,98.45 174.72,98.57 175.11,98.57 175.23,98.45 175.23,95.75 175.35,95.63 175.74,95.63 175.86,95.75 175.86,99.08 175.74,99.2 174.72,99.2 174.6,99.33 174.6,100.66 172.01,103.25 169.43,103.25 167.65,105.03 160.79,105.03 160.09,104.32 160.09,103.52 v1(159.16,102.59)
  BOTTOM w0.208: v1(188.41,137.95) 189.39,138.94 192.02,138.94 192.76,138.2 194.18,138.2 194.19,138.21 194.2,138.21 194.65,138.67 R386.1
DDR_A5: length 143.2
  TOP w0.208: U16.L8 v1(189.21,142.75) ; U34.E8 v1(155.96,103.39) ; U33.L8 v1(189.21,101.61) ; U38.L8 v1(189.21,87.89) ; U25.L8 v1(189.21,115.32) ; U20.L8 v1(189.21,129.04)
  L03_SIG1 w0.127: v1(189.21,142.75) 188.82,142.36 188.82,141.55 191.77,138.6 191.77,133.16 190.3,131.69 190.3,131.42 190.67,131.04 190.67,130.34 190.35,130.02 190.2,130.02 v1(189.21,129.04) 188.82,128.65 188.82,127.84 191.77,124.89 191.77,119.44 190.3,117.97 190.3,117.7 190.67,117.33 190.67,116.63 190.35,116.31 190.2,116.31 v1(189.21,115.32) 188.82,114.93 188.82,114.12 191.77,111.17 191.77,105.73 190.3,104.26 190.3,103.98 190.67,103.61 190.67,102.91 190.35,102.59 190.2,102.59 v1(189.21,101.61) 188.82,101.21 188.82,100.4 191.77,97.45 191.77,92.01 190.3,90.54 190.3,90.27 190.63,89.94 190.63,89.08 190.42,88.87 190.2,88.87 v1(189.21,87.89) 188.82,87.5 188.27,87.5 188.02,87.25 188.02,86.14 187.22,85.34 187.22,82.02 187.1,81.9 186.33,81.9 186.12,82.11 186.12,83.32 185.16,84.28 178.33,84.28 175.86,86.75 175.86,101.9 177.45,103.49 177.45,106.24 176.77,106.92 165.81,106.92 163.56,104.67 163.56,102.37 163.18,101.99 160.5,101.99 159.9,101.4 158.19,101.4 157.96,101.63 157.96,102 157.79,102.18 157.41,102.18 157.16,102.43 157.16,102.73 156.92,102.98 156.61,102.98 156.2,103.39 v1(155.96,103.39)
  BOTTOM w0.208: R368.1 190.41,147.18 190.41,147.14 190.41,147.14 190.41,146.74 190.41,146.74 190.41,146.45 189.92,145.96 189.92,143.47 v1(189.21,142.75)
DDR_A6: length 146.5
  TOP w0.208: R67.1 v1(193.98,138.68) ; U38.L2 v1(189.21,82.29) ; U25.L2 v1(189.21,109.72) ; U34.F8 v1(155.16,103.39) ; U20.L2 v1(189.21,123.44) ; U33.L2 v1(189.21,96.01) ; U16.L2 v1(189.21,137.15)
  L05_SIG2 w0.127: v1(193.98,138.68) 193.67,139 193.67,139.2 192.88,139.98 189.51,139.98 188.82,139.29 188.82,137.76 189.21,137.37 v1(189.21,137.15) 189.21,136.34 190.06,135.48 190.06,133.84 190.34,133.56 190.34,132.75 190.04,132.44 190.04,129.7 189.62,129.29 189.62,127.98 189.75,127.85 190.13,127.85 190.37,127.6 190.37,126.78 190.24,126.64 188.98,126.64 188.82,126.49 188.82,123.98 189.21,123.59 v1(189.21,123.44) 189.21,122.62 190.06,121.77 190.06,120.12 190.34,119.84 190.34,119.03 190.04,118.73 190.04,115.99 189.62,115.57 189.62,114.27 189.75,114.13 190.13,114.13 190.37,113.89 190.37,113.06 190.24,112.93 188.98,112.93 188.82,112.77 188.82,110.27 189.21,109.87 v1(189.21,109.72) 189.21,108.9 190.06,108.05 190.06,106.41 190.34,106.13 190.34,105.32 190.04,105.01 190.04,102.27 189.62,101.85 189.62,100.55 189.75,100.41 190.13,100.41 190.37,100.17 190.37,99.35 190.24,99.21 188.98,99.21 188.82,99.06 188.82,96.55 189.05,96.32 189.05,96.19 189.21,96.03 v1(189.21,96.01) 189.21,95.19 190.06,94.33 190.06,92.69 190.34,92.41 190.34,91.6 190.04,91.29 190.04,88.55 189.62,88.14 189.62,86.83 189.75,86.7 190.13,86.7 190.37,86.46 190.37,85.62 190.25,85.5 188.98,85.5 188.82,85.34 188.82,82.76 189.03,82.55 189.03,82.5 189.21,82.32 v1(189.21,82.29)
  L10_SIG3 w0.127: v1(155.16,103.39) 154.76,103.78 154.76,105.15 154.99,105.38 156.12,105.38 156.35,105.15 156.35,105.15 156.36,105.13 156.36,104.83 156.59,104.6 158.52,104.6 158.52,104.6 160.86,104.6 163.17,106.91 179.47,106.91 180.03,106.36 187.39,106.36 188.79,104.97 191.94,104.97 192.8,104.11 192.8,86.25 191.59,85.04 189.06,85.04 188.8,84.79 188.8,82.7 v1(189.21,82.29)
DDR_A7: length 142.8
  TOP w0.208: U16.M8 v1(190.01,142.75) ; U25.M8 v1(190.01,115.32) ; R49.1 v1(190.94,146.99) ; U38.M8 v1(190.01,87.89) ; U20.M8 v1(190.01,129.04) ; U33.M8 v1(190.01,101.61) ; U34.C7 v1(157.56,104.19)
  L03_SIG1 w0.127: v1(157.56,104.19) 157.15,103.78 154.99,103.78 154.75,103.54 154.75,98.3 155,98.04 155.62,98.04 155.74,97.92 160.27,97.92 160.72,97.48 163.36,97.48 163.76,97.87 171.95,97.87 173.83,96 173.83,83.94 179.32,78.44 188.69,78.44 189.28,79.03 189.28,81.71 189.61,82.04 U38.M8 v1(190.01,87.89) 190.62,88.5 191.93,88.5 192.14,88.7 192.14,98.13 189.62,100.64 189.62,101.21 v1(190.01,101.61) 190.62,102.21 191.92,102.21 192.14,102.43 192.14,111.84 189.62,114.36 189.62,114.93 v1(190.01,115.32) 190.62,115.93 191.92,115.93 192.14,116.15 192.14,125.56 189.62,128.08 189.62,128.65 v1(190.01,129.04) 190.62,129.65 191.92,129.65 192.14,129.86 192.14,139.28 189.62,141.79 189.62,142.36 v1(190.01,142.75)
  L05_SIG2 w0.127: v1(190.01,142.75) 190.37,143.12 190.37,145.92 190.94,146.49 v1(190.94,146.99)
DDR_A8: length 146.7
  TOP w0.208: U16.M2 v1(190.01,137.15) ; U25.M2 v1(190.01,109.72) ; U38.M2 v1(190.01,82.29) ; R69.1 v1(193.98,136.65) ; U20.M2 v1(190.01,123.44) ; U33.M2 v1(190.01,96.01) ; U34.C8 v1(157.56,103.39)
  L05_SIG2 w0.127: v1(157.56,103.39) 157.95,103 158.49,103 158.51,102.98 158.52,102.98 158.75,102.75 158.75,102.75 158.76,102.73 158.76,102.32 158.89,102.2 159.35,102.2 160.91,103.76 167.82,103.76 169.7,101.88 172.35,101.88 173.67,100.55 173.67,89.44 173.79,89.32 174.81,89.32 174.93,89.2 174.93,86.68 174.81,86.56 174.42,86.56 174.3,86.68 174.3,88.57 174.18,88.69 173.79,88.69 173.67,88.57 173.67,80.81 178.33,76.15 187.58,76.15 190,78.57 190,80.6 190.01,80.61 v1(190.01,82.29) 190.01,82.4 189.62,82.8 189.62,84.15 189.8,84.33 191.06,84.33 191.38,84.65 191.38,88.34 190.77,88.95 190.77,90.88 191.37,91.49 191.37,94.36 190.91,94.81 190.65,94.81 190.01,95.45 v1(190.01,96.01) 190.01,96.12 189.62,96.51 189.62,97.86 189.8,98.04 191.06,98.04 191.38,98.37 191.38,102.05 190.77,102.67 190.77,104.6 191.37,105.2 191.37,108.07 190.91,108.53 190.65,108.53 190.01,109.17 v1(190.01,109.72) 190.01,109.84 189.62,110.23 189.62,111.58 189.8,111.76 190.84,111.76 191.38,112.3 191.38,115.77 190.77,116.38 190.77,118.31 191.37,118.92 191.37,122.17 190.97,122.57 190.49,122.57 190.01,123.05 v1(190.01,123.44) 190.01,123.55 189.62,123.94 189.62,124.15 189.62,124.15 189.62,125.29 189.8,125.48 190.84,125.48 191.38,126.02 191.38,129.49 190.77,130.1 190.77,132.03 191.37,132.63 191.37,135.72 191.13,135.96 190.65,135.96 190.01,136.6 v1(190.01,137.15) 190.01,137.37 189.62,137.76 189.62,137.86 189.62,138.83 190.36,139.57 192.41,139.57 193.29,138.68 193.29,137.34 v1(193.98,136.65)
DDR_A9: length 144.1
  TOP w0.208: U16.M7 v1(190.01,141.95) ; U34.D7 v1(156.76,104.19) ; U38.M7 v1(190.01,87.09) ; U20.M7 v1(190.01,128.24) ; U33.M7 v1(190.01,100.81) ; U25.M7 v1(190.01,114.52)
  L03_SIG1 w0.127: v1(190.01,87.09) 190.01,83.8 190.42,83.39 190.42,82.16 190.4,82.15 190.4,82.13 189.64,81.37 189.64,78.88 188.84,78.07 188.53,78.07 179.17,78.07 173.17,84.08 173.17,85.28 173.46,85.58 173.46,93.15 171.74,94.87 162.57,94.87 160.33,97.11 160.2,97.11 159.61,97.7 154.7,97.7 153.95,98.45 153.95,104.33 154.19,104.58 156.15,104.58 156.54,104.19 v1(156.76,104.19)
  L12_SIG4 w0.127: v1(190.01,141.95) 190.4,141.56 191.7,141.56 192.21,141.05 192.21,130.56 191.09,129.43 190.65,129.43 190.42,129.2 190.42,128.65 v1(190.01,128.24) 190.4,127.85 191.7,127.85 192.21,127.34 192.21,116.84 191.09,115.71 190.65,115.71 190.42,115.48 190.42,114.93 v1(190.01,114.52) 190.4,114.13 191.7,114.13 192.21,113.62 192.21,103.13 191.08,102 190.65,102 190.42,101.77 190.42,101.21 v1(190.01,100.81) 190.4,100.41 191.7,100.41 192.21,99.9 192.21,89.4 191.1,88.28 190.65,88.28 190.42,88.05 190.42,87.5 v1(190.01,87.09)
  BOTTOM w0.127: 190.41,142.35 190.41,142.97 190.54,143.1
  BOTTOM w0.208: R367.1 190.95,147.66 191.14,147.47 191.15,147.47 191.52,147.1 191.52,146.69 190.54,145.71 190.54,143.1 ; v1(190.01,141.95) 190.41,142.35
DDR_A10: length 146.1
  TOP w0.208: U34.E7 v1(155.96,104.19) ; U38.J3 v1(187.61,83.09) ; U25.J3 v1(187.61,110.52) ; U33.J3 v1(187.61,96.81) ; U16.J3 v1(187.61,137.95) ; U20.J3 v1(187.61,124.24)
  L05_SIG2 w0.127: v1(187.61,137.95) 187.61,137.76 188,137.37 188,133.06 187.67,132.73 187.44,132.73 187.3,132.59 187.3,130.87 187.2,130.77 187.2,127.5 187.33,127.37 187.53,127.37 187.66,127.24 187.66,126.85 187.54,126.73 187.14,126.73 187.02,126.6 187.02,126.36 187.14,126.24 187.49,126.24 187.65,126.08 187.65,125.81 187.52,125.68 187.14,125.68 187.02,125.55 187.02,125.27 187.14,125.15 187.49,125.15 187.61,125.03 v1(187.61,124.24) 187.61,124.05 188,123.66 188,119.34 187.67,119.01 187.44,119.01 187.3,118.88 187.3,117.15 187.2,117.05 187.2,113.79 187.33,113.66 187.53,113.66 187.66,113.53 187.66,113.13 187.54,113.01 187.14,113.01 187.02,112.89 187.02,112.64 187.14,112.52 187.49,112.52 187.65,112.36 187.65,112.09 187.52,111.96 187.14,111.96 187.02,111.83 187.02,111.55 187.14,111.43 187.49,111.43 187.61,111.31 v1(187.61,110.52) 187.61,110.33 188,109.94 188,105.63 187.67,105.29 187.44,105.29 187.3,105.16 187.3,103.43 187.2,103.33 187.2,100.07 187.33,99.94 187.53,99.94 187.66,99.81 187.66,99.41 187.54,99.29 187.14,99.29 187.02,99.17 187.02,98.93 187.14,98.81 187.49,98.81 187.65,98.64 187.65,98.38 187.52,98.24 187.14,98.24 187.02,98.12 187.02,97.84 187.14,97.72 187.49,97.72 187.61,97.59 v1(187.61,96.81) 187.61,96.62 188,96.22 188,91.91 187.67,91.58 187.44,91.58 187.3,91.44 187.3,89.72 187.2,89.62 187.2,86.35 187.33,86.23 187.53,86.23 187.67,86.09 187.67,85.7 187.55,85.58 187.14,85.58 187.02,85.46 187.02,85.21 187.14,85.09 187.49,85.09 187.65,84.93 187.65,84.66 187.52,84.53 187.14,84.53 187.02,84.4 187.02,84.12 187.14,84 187.49,84 187.61,83.88 v1(187.61,83.09) 187.61,83.02 187.79,82.84 187.79,82.83 188,82.62 188,82.03 187.45,81.48 187.45,78.48 186.59,77.62 178.94,77.62 178.38,78.18 178.38,86.91 177.07,88.22 177.07,92.4 177.22,92.55 177.6,92.55 177.72,92.42 177.72,90.42 177.84,90.3 178.23,90.3 178.35,90.42 178.35,93.05 178.23,93.18 177.21,93.18 177.09,93.3 177.09,99.2 172.31,103.98 169.73,103.98 167.26,106.45 161.12,106.45 159.25,104.58 156.35,104.58 v1(155.96,104.19)
  BOTTOM w0.208: v1(187.61,137.95) 187.61,138.81 188.35,139.55 193.09,139.55 193.45,139.18 194.15,139.18 194.65,139.69 R383.1
DDR_A11: length 146.3
  TOP w0.208: U20.N2 v1(190.81,123.44) ; U25.N2 v1(190.81,109.72) ; v1(161.02,101.55) 161.02,102.8 161.16,102.94 161.16,104.37 160.63,104.9 159.06,104.9 U34.A6 ; U16.N2 v1(190.81,137.15) ; U38.N2 v1(190.81,82.29) ; U33.N2 v1(190.81,96.01) ; R70.1 v1(193.98,135.64)
  L05_SIG2 w0.127: v1(193.98,135.64) 192.91,136.7 192.91,138.43 192.14,139.2 190.54,139.2 190.4,139.07 190.4,137.81 190.81,137.4 v1(190.81,137.15) 191.98,137.15 192.1,137.03 192.1,124.98 191.84,124.71 190.56,124.71 190.4,124.56 190.4,124.05 190.81,123.64 v1(190.81,123.44) 191.98,123.44 192.1,123.32 192.1,111.26 191.84,111 190.56,111 190.4,110.84 190.4,110.33 190.81,109.93 v1(190.81,109.72) 191.98,109.72 192.1,109.6 192.1,97.55 191.84,97.28 190.56,97.28 190.4,97.12 190.4,96.62 190.81,96.21 v1(190.81,96.01) 191.98,96.01 192.1,95.88 192.1,83.82 191.85,83.57 190.56,83.57 190.4,83.41 190.4,82.9 190.81,82.49 v1(190.81,82.29) 191.39,81.71 191.39,78.55 188.26,75.42 178.03,75.42 172.03,81.42 172.03,87.37 171.91,87.49 171.52,87.49 171.4,87.37 171.4,86.62 171.28,86.5 170.89,86.5 170.77,86.62 170.77,88 170.89,88.12 171.91,88.12 172.03,88.24 172.03,89.97 170.07,91.93 170.07,93.97 170.69,94.59 170.69,97.18 169.66,98.2 169.66,100.49 167.12,103.03 161.3,103.03 161.02,102.75 v1(161.02,101.55)
DDR_A12: length 143.8
  TOP w0.208: U38.J7 v1(187.61,87.09) ; U20.J7 v1(187.61,128.24) ; U25.J7 v1(187.61,114.52) ; U34.F7 v1(155.16,104.19) ; U33.J7 v1(187.61,100.81) ; U16.J7 v1(187.61,141.95)
  L03_SIG1 w0.127: v1(187.61,87.09) 187.61,87.15 187.79,87.33 187.79,87.35 188.02,87.58 188.02,88.6 188.45,89.03 188.6,89.03 188.79,89.22 188.79,92.11 189.29,92.62 189.29,94.29 189.48,94.48 190.22,94.48 190.4,94.66 190.4,97.38 187.61,100.17 v1(187.61,100.81) 187.61,100.94 188.02,101.35 188.02,102.34 188.42,102.74 188.6,102.74 188.79,102.93 188.79,105.83 189.29,106.33 189.29,108 189.48,108.19 190.22,108.19 190.4,108.38 190.4,111.1 187.61,113.89 v1(187.61,114.52) 187.61,114.71 188.02,115.12 188.02,116.06 188.42,116.46 188.6,116.46 188.79,116.65 188.79,119.54 189.29,120.05 189.29,121.72 189.48,121.91 190.22,121.91 190.4,122.09 190.4,124.81 187.61,127.6 v1(187.61,128.24) 187.61,128.37 188.02,128.78 188.02,129.77 188.42,130.18 188.6,130.18 188.79,130.37 188.79,133.22 189.29,133.72 189.29,135.43 189.48,135.62 190.22,135.62 190.4,135.81 190.4,138.53 187.61,141.32 v1(187.61,141.95)
  L10_SIG3 w0.127: v1(187.61,87.09) 188.83,85.87 191.39,85.87 192.07,86.55 192.07,101.06 191.07,102.07 190.11,102.07 188.83,103.34 188.83,103.7 186.9,105.63 179.78,105.63 178.86,104.71 175.76,104.71 175.64,104.84 175.64,105.13 175.52,105.25 175.13,105.25 175.01,105.13 175.01,104.85 174.87,104.71 174.5,104.71 174.38,104.84 174.38,105.13 174.26,105.25 173.87,105.25 173.75,105.13 173.75,104.85 173.61,104.71 173.24,104.71 173.12,104.84 173.12,105.13 173,105.25 172.61,105.25 172.49,105.13 172.49,104.85 172.35,104.71 168.94,104.71 168.82,104.84 168.82,105.22 168.7,105.34 168.31,105.34 168.19,105.22 168.19,104.84 168.07,104.71 167.68,104.71 167.56,104.84 167.56,105.22 167.44,105.34 167.05,105.34 166.93,105.22 166.93,104.84 166.81,104.71 166.42,104.71 166.3,104.84 166.3,105.22 166.18,105.34 165.79,105.34 165.67,105.22 165.67,104.84 165.55,104.71 165.16,104.71 165.04,104.84 165.04,105.22 164.92,105.34 164.53,105.34 164.41,105.22 164.41,104.84 164.29,104.71 163.9,104.71 163.78,104.84 163.78,105.22 163.66,105.34 163.27,105.34 163.15,105.22 163.15,104.84 163.03,104.71 162.4,104.71 160.68,103 159.32,103 159.32,103 155.79,103 155.56,103.23 155.56,103.23 155.55,103.25 155.55,103.8 v1(155.16,104.19)
  BOTTOM w0.127: 188,142.35 188,142.98 187.96,143.02
  BOTTOM w0.208: 188,142.35 v1(187.61,141.95) ; R370.1 188.38,147.18 188.38,147.14 188.38,147.14 188.38,146.74 188.38,146.74 188.38,146.72 187.97,146.31 187.97,145.16 187.96,145.08 187.96,143.02
DDR_A13: length 143
  TOP w0.208: v1(192.18,145.67) 191.96,145.88 R44.1 ; U25.N8 v1(190.81,115.32) ; U34.D6 v1(156.76,104.99) ; U38.N8 v1(190.81,87.89) ; U16.N8 v1(190.81,142.75) ; U20.N8 v1(190.81,129.04) ; U33.N8 v1(190.81,101.61)
  L03_SIG1 w0.127: v1(190.81,142.75) 190.42,142.36 190.42,141.79 192.5,139.71 192.5,129.11 192.22,128.83 191.02,128.83 v1(190.81,129.04) 190.42,128.65 190.42,128.08 192.5,125.99 192.5,115.4 192.22,115.11 191.02,115.11 v1(190.81,115.32) 190.42,114.93 190.42,114.36 192.5,112.28 192.5,101.68 192.21,101.4 191.02,101.4 v1(190.81,101.61) 190.42,101.21 190.42,100.64 192.5,98.56 192.5,87.95 192.23,87.68 191.02,87.68 v1(190.81,87.89) 190.42,87.5 190.42,84.9 191.2,84.12 191.2,81.28 190.01,80.09 190.01,78.73 188.99,77.71 188.38,77.71 178.99,77.71 169.42,87.28 169.42,89.76 165.83,93.35 163.83,93.35 162.67,94.5 162.42,94.5 160.18,96.74 160.05,96.74 159.32,97.47 154.6,97.47 154.6,97.47 154.01,97.47 153.16,98.32 153.16,104.35 153.41,104.6 153.75,104.6 153.96,104.82 153.96,105.19 154.18,105.4 156.35,105.4 v1(156.76,104.99)
  L05_SIG2 w0.127: v1(192.18,145.67) 192.15,144.09 v1(190.81,142.75)
DDR_A14_WEN: length 148.2
  TOP w0.208: U20.H2 v1(186.81,123.44) ; U25.H2 v1(186.81,109.72) ; U34.C6 v1(157.56,104.99) ; U38.H2 v1(186.81,82.29) ; U33.H2 v1(186.81,96.01) ; U16.H2 v1(186.81,137.15)
  L05_SIG2 w0.127: v1(186.81,137.15) 186.81,136.07 185.65,134.92 185.65,134.55 185.77,134.43 186.24,134.43 186.37,134.31 186.37,133.98 186.24,133.86 185.75,133.86 185.63,133.74 185.63,127.27 185.04,126.68 185.04,126.29 185.63,125.7 185.63,124.25 186.44,123.44 v1(186.81,123.44) 186.81,122.36 185.65,121.2 185.65,120.84 185.77,120.71 186.24,120.71 186.37,120.59 186.37,120.26 186.24,120.14 185.75,120.14 185.63,120.02 185.63,113.49 185.04,112.9 185.04,112.57 185.63,111.99 185.63,110.54 186.44,109.72 v1(186.81,109.72) 186.81,108.64 185.65,107.48 185.65,107.12 185.77,107 186.24,107 186.37,106.88 186.37,106.55 186.24,106.43 185.75,106.43 185.63,106.3 185.63,99.84 185.1,99.31 185.1,98.79 185.63,98.27 185.63,96.73 185.86,96.49 185.87,96.49 186.35,96.01 v1(186.81,96.01) 186.81,94.93 185.65,93.77 185.65,93.4 185.77,93.28 186.24,93.28 186.37,93.16 186.37,92.83 186.24,92.71 185.75,92.71 185.63,92.59 185.63,86.06 185.09,85.53 185.09,85.08 185.63,84.55 185.63,83.01 186.35,82.29 v1(186.81,82.29) 186.06,81.53 186.06,78.49 185.55,77.98 179.25,77.98 178.74,78.49 178.74,97.82 178.62,97.95 178.24,97.95 178.07,97.78 178.07,94.09 177.95,93.97 177.62,93.97 177.54,94.05 177.54,98.45 177.67,98.58 178.62,98.58 178.74,98.7 178.74,99.7 177.27,101.18 176.54,101.18 173.37,104.35 169.88,104.35 167.41,106.82 160.86,106.82 159.44,105.4 157.96,105.4 v1(157.56,104.99)
  BOTTOM w0.208: v1(186.81,137.15) 186.31,137.66 186.31,138.22 188.27,140.18 194.13,140.18 194.65,140.7 R382.1
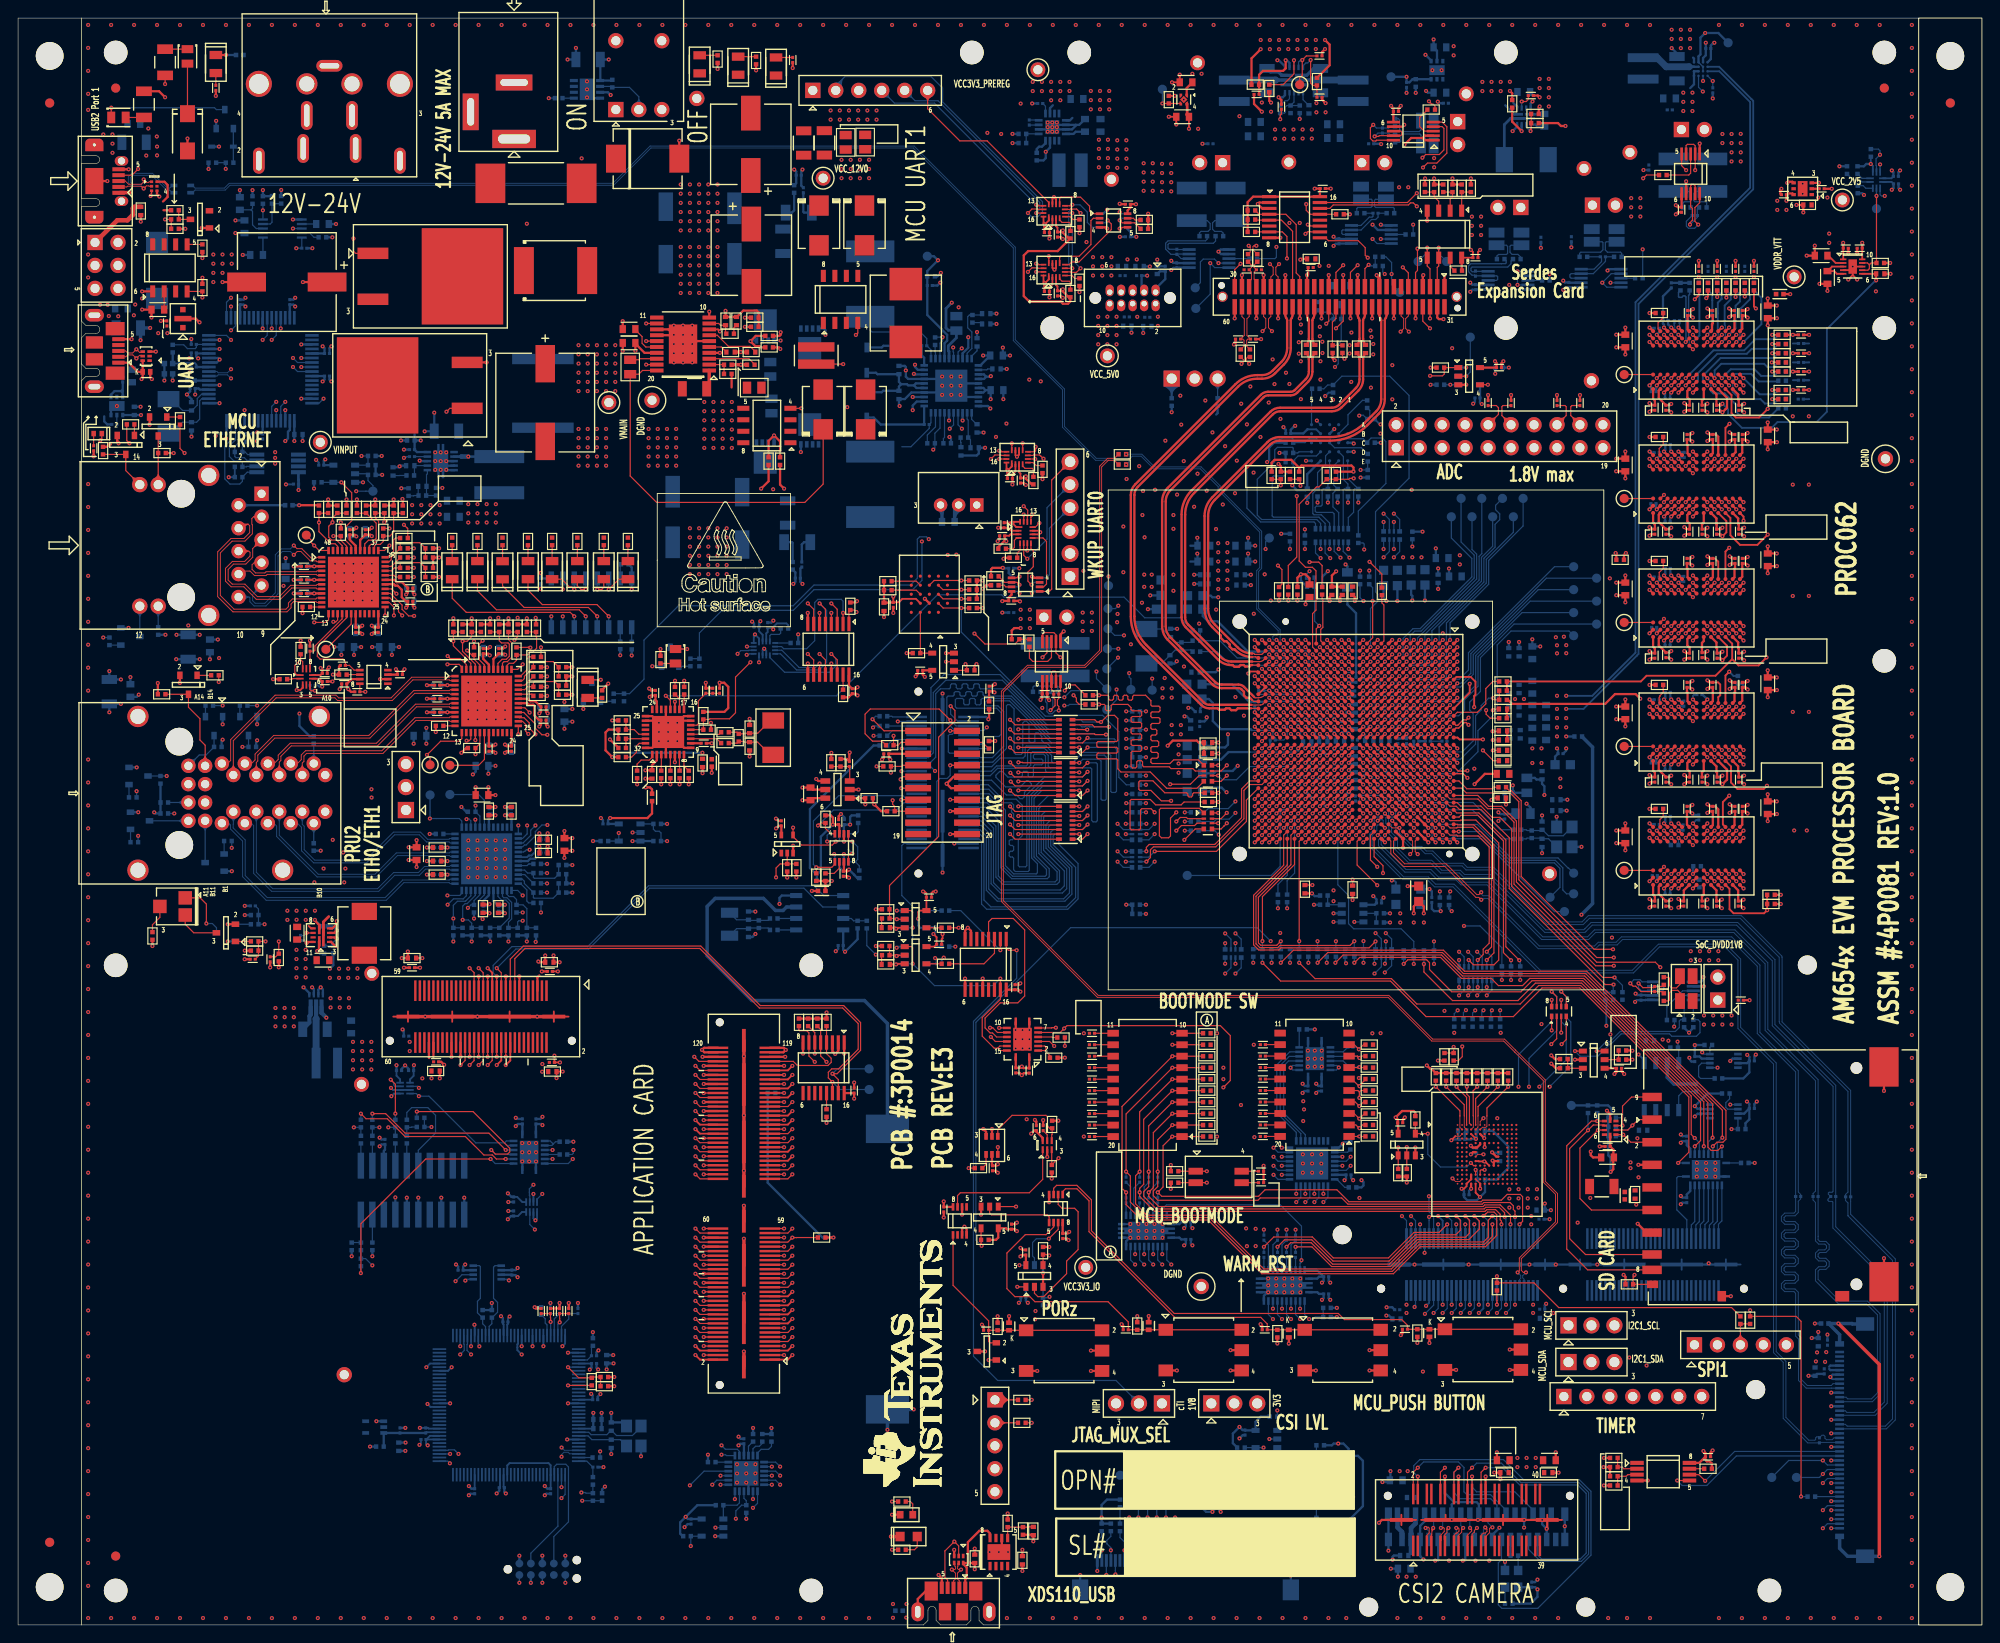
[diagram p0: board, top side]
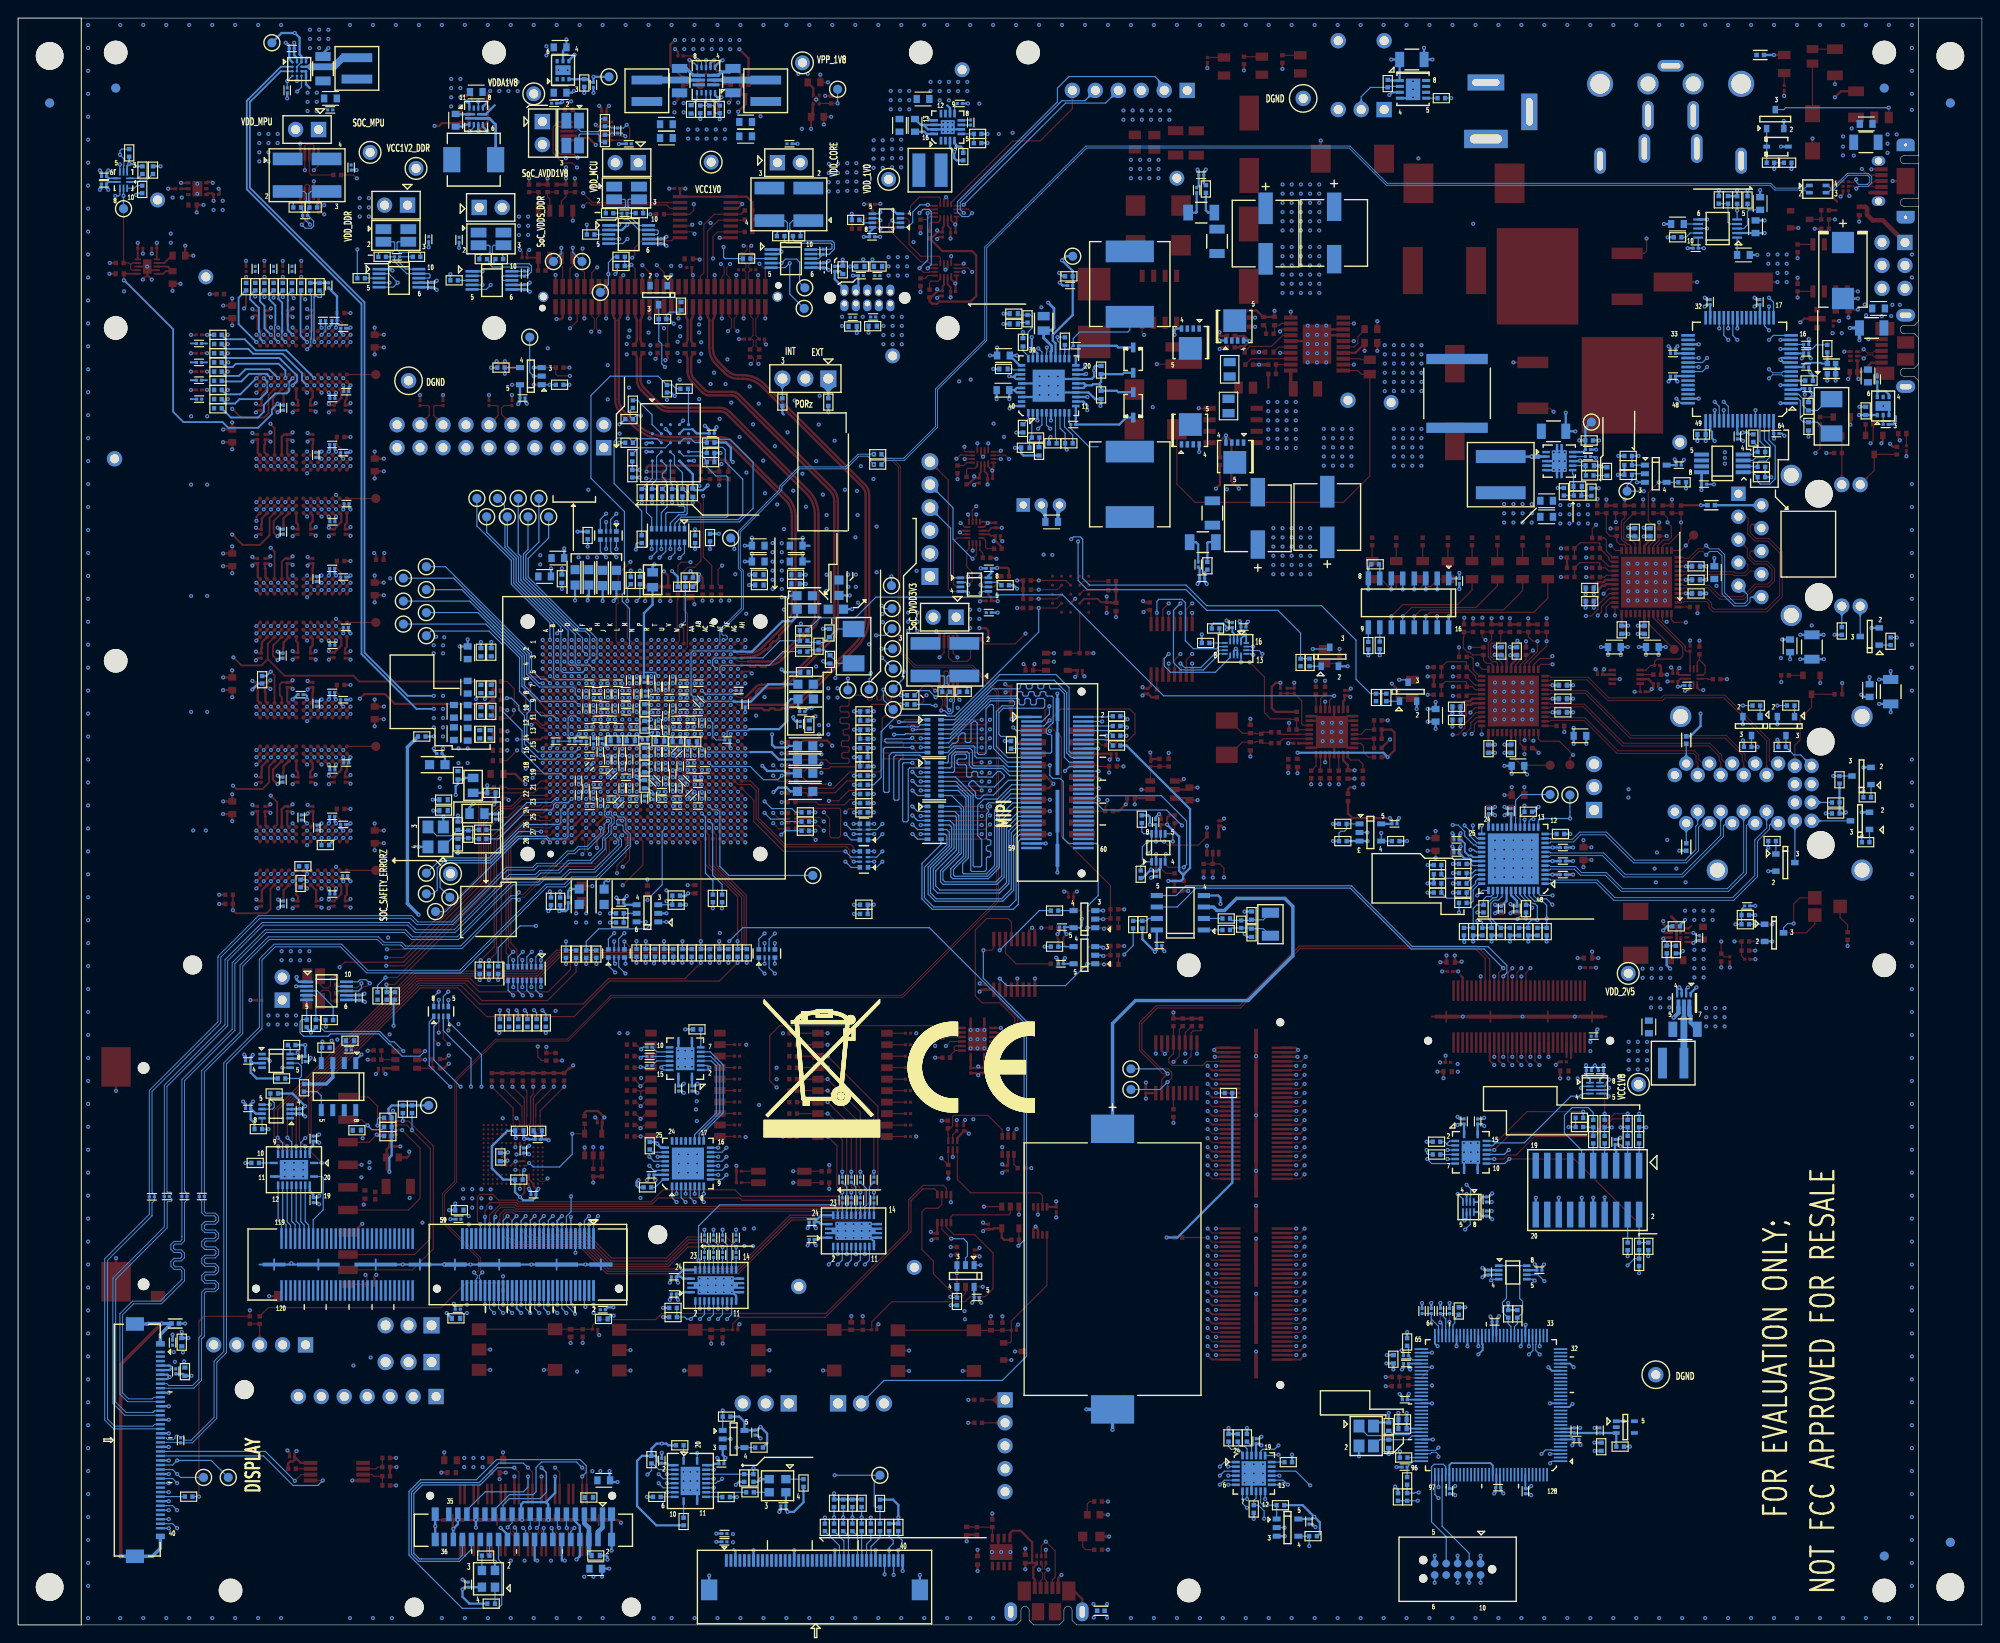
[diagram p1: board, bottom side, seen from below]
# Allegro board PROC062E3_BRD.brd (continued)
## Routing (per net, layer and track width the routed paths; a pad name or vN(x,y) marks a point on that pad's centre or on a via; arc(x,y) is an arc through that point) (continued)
DDR_A15_CAS: length 143.6
  TOP w0.208: v1(186.69,146.81) 186.88,147 R46.1 ; U20.H7 v1(186.81,128.24) ; U34.F6 v1(155.16,104.99) ; U38.H7 v1(186.81,87.09) ; U16.H7 v1(186.81,141.95) ; U25.H7 v1(186.81,114.52) ; U33.H7 v1(186.81,100.81)
  L03_SIG1 w0.127: v1(186.81,141.95) 186.81,140.6 188.82,138.59 188.82,136.39 188.57,136.14 188.21,136.14 188.03,135.96 188.03,133.35 187.33,132.64 187.33,131.59 187.2,131.47 186.49,131.47 186.37,131.35 186.37,128.36 186.49,128.24 v1(186.81,128.24) 186.81,126.88 188.82,124.87 188.82,122.68 188.57,122.43 188.21,122.43 188.03,122.24 188.03,119.63 187.33,118.93 187.33,117.88 187.2,117.75 186.49,117.75 186.37,117.63 186.37,114.64 186.49,114.52 v1(186.81,114.52) 186.81,113.16 188.82,111.15 188.82,108.96 188.57,108.71 188.27,108.71 188.03,108.47 188.03,105.91 187.33,105.21 187.33,104.16 187.2,104.04 186.49,104.04 186.37,103.92 186.37,100.93 186.49,100.81 v1(186.81,100.81) 186.81,99.45 188.82,97.44 188.82,95.25 188.57,95 188.25,95 188.03,94.77 188.03,92.2 187.33,91.49 187.33,90.44 187.2,90.32 186.49,90.32 186.37,90.2 186.37,87.21 186.49,87.09 v1(186.81,87.09)
  L05_SIG2 w0.127: v1(186.81,141.95) 186.37,142.4 186.37,146.49 v1(186.69,146.81)
  L10_SIG3 w0.127: v1(186.81,87.09) 188.42,85.48 191.51,85.48 192.44,86.4 192.44,102.17 192.31,102.29 191.4,102.29 191.28,102.41 191.28,102.8 191.4,102.92 192.31,102.92 192.44,103.04 192.44,103.89 192.31,104.01 190.61,104.01 190.49,103.89 190.49,103.08 190.36,102.96 189.98,102.96 189.86,103.08 189.86,103.89 189.73,104.01 189.04,104.01 187.06,106 179.63,106 179.49,105.85 163.02,105.85 160.77,103.6 159.73,103.6 159.55,103.78 156.61,103.78 156.36,104.03 156.36,104.03 156.35,104.05 156.35,104.35 156.12,104.58 156.12,104.58 156.11,104.59 155.56,104.59 v1(155.16,104.99)
DDR_A16_RAS: length 142.8
  TOP w0.208: U25.H8 v1(186.81,115.32) ; U33.H8 v1(186.81,101.61) ; U34.E6 v1(155.96,104.99) ; U16.H8 v1(186.81,142.75) ; U20.H8 v1(186.81,129.04) ; U38.H8 v1(186.81,87.89)
  L03_SIG1 w0.127: v1(186.81,142.75) 187.2,142.36 187.2,140.97 189.6,138.57 189.6,136.55 188.93,135.88 188.93,133.96 188.42,133.46 188.42,130.8 188.24,130.62 187.32,130.62 187.2,130.5 187.2,129.43 v1(186.81,129.04) 187.2,128.65 187.2,127.25 189.6,124.85 189.6,122.84 188.93,122.16 188.93,120.29 188.42,119.78 188.42,117.08 188.24,116.9 187.32,116.9 187.2,116.78 187.2,115.71 v1(186.81,115.32) 187.2,114.93 187.2,113.53 189.6,111.13 189.6,109.12 188.93,108.44 188.93,106.57 188.42,106.07 188.42,103.32 188.22,103.12 187.32,103.12 187.2,103 187.2,102 v1(186.81,101.61) 187.2,101.21 187.2,99.82 189.6,97.42 189.6,95.41 188.93,94.73 188.93,92.86 188.42,92.35 188.42,89.63 188.2,89.41 187.32,89.41 187.2,89.29 187.2,88.28 v1(186.81,87.89) 187.2,87.5 187.2,86.19 186.52,85.5 179.18,85.5 178.18,86.5 178.18,111.03 177.01,112.2 166.16,112.2 162.53,108.58 162.53,103.6 161.93,103 160.19,103 159.36,102.17 159.02,102.17 158.76,102.43 158.76,102.73 158.52,102.98 158.21,102.98 157.95,103.25 157.95,104.35 157.71,104.58 156.61,104.58 156.2,104.99 v1(155.96,104.99)
  BOTTOM w0.208: R371.1 186.89,147.66 187.35,147.21 187.35,145.18 187.35,145.12 187.35,145.11 187.35,143.76 187.35,143.76 187.35,143.29 v1(186.81,142.75)
DDR_A17: length 144.4
  TOP w0.208: U38.N7 v1(190.81,87.09) ; U25.N7 v1(190.81,114.52) ; U16.N7 v1(190.81,141.95) ; U33.N7 v1(190.81,100.81) ; U20.N7 v1(190.81,128.24) ; U34.E5 v1(155.96,105.79)
  L03_SIG1 w0.127: v1(155.96,105.79) 155.56,106.18 154.19,106.18 153.96,105.95 153.96,105.65 153.72,105.4 153.41,105.4 153.16,105.15 153.16,104.85 152.92,104.6 152.61,104.6 152.36,104.35 152.36,98.43 153.41,97.38 153.72,97.38 153.96,97.13 153.96,96.83 154.19,96.6 159.66,96.6 159.88,96.38 160.03,96.38 162.27,94.14 162.39,94.14 163.55,92.98 163.56,92.98 169.05,87.49 169.05,87.13 178.62,77.56 178.84,77.34 188.23,77.34 188.23,77.34 189.14,77.34 189.14,77.34 189.48,77.34 191.52,79.38 191.52,85.85 190.81,86.56 v1(190.81,87.09) 192.74,87.09 192.87,87.21 192.87,98.75 v1(190.81,100.81) 192.75,100.81 192.87,100.93 192.87,112.47 v1(190.81,114.52) 192.75,114.52 192.87,114.64 192.87,126.18 v1(190.81,128.24) 192.75,128.24 192.87,128.36 192.87,139.9 v1(190.81,141.95)
  BOTTOM w0.208: R366.1 191.97,147.66 192.79,146.85 192.79,143.93 v1(190.81,141.95)
DDR_ACTN: length 148.6
  TOP w0.208: U33.H3 v1(186.81,96.81) ; U25.H3 v1(186.81,110.52) ; U16.H3 v1(186.81,137.95) ; U34.D8 v1(156.76,103.39) ; U38.H3 v1(186.81,83.09) ; U20.H3 v1(186.81,124.24)
  L03_SIG1 w0.127: v1(186.81,83.09) 186.81,84.86 186.54,85.14 178.45,85.14 178.18,85.4 178.18,85.9 177.81,86.26 177.81,87.24 177.59,87.46 176.54,87.46 176.23,87.77 176.23,101.75 177.81,103.34 177.81,110.86 176.84,111.84 166.31,111.84 162.9,108.43 162.9,102.96 162.57,102.63 160.35,102.63 159.65,101.93 158.77,101.93 158.52,102.18 158.11,102.18 157.95,102.35 157.95,102.75 157.72,102.98 157.41,102.98 157,103.39 v1(156.76,103.39)
  L05_SIG2 w0.127: v1(186.81,83.09) 186.53,82.81 186.31,82.81 185.99,83.13 185.99,84.88 185.88,84.99 185.7,84.99 185.58,85.11 185.58,85.56 185.7,85.68 185.85,85.68 185.99,85.82 185.99,92.21 186.11,92.33 187.13,92.33 187.25,92.45 187.25,95.81 187.2,95.86 187.2,96.17 186.81,96.56 v1(186.81,96.81) 186.53,96.53 186.31,96.53 185.99,96.85 185.99,98.6 185.88,98.71 185.71,98.71 185.59,98.83 185.59,99.27 185.71,99.39 185.85,99.39 185.99,99.53 185.99,105.92 186.11,106.05 187.13,106.05 187.25,106.17 187.25,109.53 187.2,109.58 187.2,109.88 186.81,110.28 v1(186.81,110.52) 186.53,110.25 186.31,110.25 185.99,110.57 185.99,112.31 185.88,112.42 185.71,112.42 185.59,112.54 185.59,113.05 185.71,113.17 185.85,113.17 185.99,113.31 185.99,119.64 186.11,119.76 187.13,119.76 187.25,119.88 187.25,123.24 187.2,123.29 187.2,123.6 186.81,123.99 v1(186.81,124.24) 186.53,123.96 186.31,123.96 185.99,124.28 185.99,126.03 185.88,126.14 185.71,126.14 185.59,126.26 185.59,126.77 185.71,126.89 185.85,126.89 185.99,127.03 185.99,133.36 186.11,133.48 187.13,133.48 187.25,133.6 187.25,136.96 187.2,137.01 187.2,137.32 186.81,137.71 v1(186.81,137.95)
  BOTTOM w0.127: 187.2,137.54 187.2,137.54 187.2,136.78 187.2,136.78
  BOTTOM w0.208: v1(186.81,137.95) 186.81,137.93 187.2,137.54 ; R742.1 193.64,133.6 190.63,133.6 189.99,134.24 189.99,135 188.72,136.27 187.45,136.27 187.2,136.53 187.2,136.78
DDR_ALERTN: length 145.7
  TOP w0.208: U25.L9 188.81,118.77 v1(189.23,119.19) ; U16.L9 v1(189.21,143.55) ; v1(189.23,91.76) 188.52,91.05 188.52,88.58 U38.L9 ; U20.L9 188.81,132.45 v1(189.26,132.91) ; U34.D5 v1(156.76,105.79) ; v1(189.23,105.47) 188.81,105.05 U33.L9
  L03_SIG1 w0.127: v1(156.76,105.79) 157.15,106.18 157.15,109.15 157.15,109.15 157.15,110.03 163.36,116.24 176.58,116.24 177.11,116.78 177.11,127.2 179.74,129.83 179.74,146.82 180.6,147.68 190.02,147.68 190.37,147.32 190.37,144.71 v1(189.21,143.55)
  L10_SIG3 w0.127: v1(189.21,143.55) 188.82,143.16 188.82,136.43 189.29,135.96 189.29,133.22 189.26,133.19 v1(189.26,132.91) 189.87,132.3 189.87,129.86 189.62,129.61 189.62,119.58 v1(189.23,119.19) 188.82,118.78 188.82,108.46 189.23,108.05 v1(189.23,105.47)
  L12_SIG4 w0.127: v1(189.23,91.76) 189.23,94.21 188.7,94.74 188.32,94.74 187.45,95.61 187.45,95.61 187.22,95.84 187.22,95.85 187.2,95.86 187.2,102.57 187.2,102.57 187.2,103.44 v1(189.23,105.47)
  BOTTOM w0.208: R460.1 189.7,105 v1(189.23,105.47)
DDR_BA0: length 147.3
  TOP w0.208: U34.D10 v1(156.76,101.79) ; U25.K2 v1(188.41,109.72) ; U33.K2 v1(188.41,96.01) ; U38.K2 v1(188.41,82.29) ; R63.1 v1(193.93,139.7) ; U16.K2 v1(188.41,137.15) ; U20.K2 v1(188.41,123.44)
  L05_SIG2 w0.127: v1(193.93,139.7) 193.28,140.35 188.86,140.35 188.02,139.51 188.02,137.68 188.41,137.29 v1(188.41,137.15) 188.41,135.88 189.31,134.99 189.31,133.81 188.41,132.91 188.41,132.3 188.25,132.13 188,132.13 187.84,131.98 187.84,131.63 187.96,131.5 188.29,131.5 188.41,131.38 188.41,131 188.29,130.87 188.02,130.87 187.86,130.72 187.86,130.37 187.98,130.24 188.29,130.24 188.48,130.05 188.48,129.66 188.33,129.51 188.14,129.51 188.02,129.39 188.02,124.08 188.23,123.87 188.23,123.76 188.23,123.75 188.23,123.62 v1(188.41,123.44) 188.41,122.17 189.31,121.27 189.31,120.09 188.41,119.2 188.41,118.58 188.25,118.42 188,118.42 187.84,118.26 187.84,117.91 187.96,117.79 188.29,117.79 188.41,117.67 188.41,117.28 188.29,117.16 188.02,117.16 187.86,117 187.86,116.65 187.98,116.53 188.29,116.53 188.48,116.33 188.48,115.95 188.33,115.8 188.14,115.8 188.02,115.68 188.02,110.35 188.23,110.14 188.23,109.9 v1(188.41,109.72) 188.41,108.45 189.31,107.56 189.31,106.38 188.41,105.48 188.41,104.87 188.25,104.7 188,104.7 187.84,104.55 187.84,104.19 187.96,104.07 188.29,104.07 188.41,103.95 188.41,103.56 188.29,103.44 188.02,103.44 187.86,103.29 187.86,102.93 187.98,102.81 188.29,102.81 188.49,102.61 188.49,102.24 188.33,102.08 188.14,102.08 188.02,101.96 188.02,96.64 188.23,96.43 188.23,96.19 v1(188.41,96.01) 188.41,94.74 189.31,93.84 189.31,92.66 188.41,91.76 188.41,91.15 188.25,90.99 188,90.99 187.84,90.83 187.84,90.48 187.96,90.36 188.29,90.36 188.41,90.23 188.41,89.85 188.29,89.73 188.02,89.73 187.86,89.57 187.86,89.22 187.98,89.1 188.29,89.1 188.49,88.9 188.49,88.52 188.33,88.37 188.14,88.37 188.02,88.24 188.02,82.93 188.23,82.72 188.23,82.47 v1(188.41,82.29) 188.41,82.11 187.9,81.6 187.9,78.17 186.97,77.25 178.79,77.25 176.7,79.34 176.7,84.08 176.82,84.2 177.2,84.2 177.33,84.08 177.33,82.51 177.45,82.39 177.83,82.39 177.96,82.51 177.96,84.71 177.83,84.83 176.82,84.83 176.28,85.37 176.28,99.5 172.16,103.62 169.58,103.62 167.11,106.09 161.33,106.09 159.72,104.47 159.72,104.09 159.41,103.78 157.39,103.78 157.16,103.55 157.16,102.45 156.76,102.04 v1(156.76,101.79)
DDR_BA1: length 143
  TOP w0.208: U16.K8 v1(188.41,142.75) ; U34.E10 v1(155.96,101.79) ; R48.1 v1(188.91,146.88) ; U33.K8 v1(188.41,101.61) ; U25.K8 v1(188.41,115.32) ; U38.K8 v1(188.41,87.89) ; U20.K8 v1(188.41,129.04)
  L03_SIG1 w0.127: v1(188.41,87.89) 189.74,89.22 189.74,91.42 190.9,92.59 191.05,92.59 191.31,92.84 191.31,97.29 188.02,100.59 188.02,101.02 188.41,101.42 v1(188.41,101.61) 189.74,102.93 189.74,105.16 190.88,106.3 191.05,106.3 191.31,106.56 191.31,111.01 188.02,114.3 188.02,114.68 188.41,115.08 v1(188.41,115.32) 189.74,116.65 189.74,118.9 190.85,120.02 191.05,120.02 191.31,120.28 191.31,124.73 188.02,128.02 188.02,128.46 188.41,128.85 v1(188.41,129.04) 189.74,130.37 189.74,132.6 190.87,133.73 191.05,133.73 191.32,134 191.32,138.44 188.02,141.74 188.02,142.12 188.41,142.51 v1(188.41,142.75)
  L05_SIG2 w0.127: v1(188.91,146.88) 188.26,146.23 188.26,144.63 187.93,144.3 187.93,143.23 v1(188.41,142.75)
  L10_SIG3 w0.127: v1(188.41,87.89) 188.82,87.48 188.82,86.68 189.23,86.27 191.14,86.27 191.7,86.84 191.7,88.47 191.58,88.6 190.99,88.6 190.87,88.72 190.87,89.1 190.99,89.23 191.58,89.23 191.7,89.35 191.7,91.49 191.58,91.61 190.97,91.61 190.84,91.73 190.84,92.12 190.97,92.24 191.58,92.24 191.7,92.36 191.7,93.06 191.58,93.18 191.44,93.18 191.31,93.3 191.31,93.69 191.44,93.81 191.58,93.81 191.7,93.93 191.7,94.37 191.58,94.49 191.32,94.49 191.2,94.61 191.2,94.9 191.32,95.02 191.58,95.02 191.7,95.14 191.7,95.7 191.58,95.82 191.32,95.82 191.2,95.94 191.2,96.23 191.32,96.35 191.58,96.35 191.7,96.47 191.7,97.24 191.58,97.37 190.92,97.37 190.8,97.49 190.8,97.77 190.92,97.9 191.58,97.9 191.7,98.02 191.7,98.24 191.58,98.36 190.87,98.36 190.75,98.48 190.75,98.77 190.87,98.89 191.58,98.89 191.7,99.01 191.7,99.3 191.58,99.42 190.87,99.42 190.75,99.54 190.75,99.83 190.87,99.95 191.58,99.95 191.7,100.07 191.7,100.29 191.58,100.41 189.85,100.41 189.6,100.66 189.6,101.97 188.47,103.1 188.47,103.55 186.75,105.27 179.93,105.27 179.02,104.35 162.55,104.35 160.8,102.6 159.94,102.6 159.52,102.18 156.35,102.18 v1(155.96,101.79)
DDR_BG0: length 148
  TOP w0.208: R61.1 v1(193.98,140.72) ; U25.J2 v1(187.61,109.72) ; U33.J2 v1(187.61,96.01) ; U38.J2 v1(187.61,82.29) ; U16.J2 v1(187.61,137.15) ; U20.J2 v1(187.61,123.44) ; U34.C10 v1(157.56,101.79)
  L03_SIG1 w0.127: v1(157.56,101.79) 157.15,101.38 157.15,100.05 157.39,99.8 158.7,99.8 158.89,99.99 162.68,99.99 162.93,99.74 163.3,99.74 164.29,100.73 164.29,103.97 164.56,104.24 165.11,104.24 165.23,104.12 165.23,103.1 165.36,102.98 168.76,102.98 168.88,103.1 168.88,103.49 168.76,103.61 165.99,103.61 165.86,103.73 165.86,104.12 165.99,104.24 176.26,104.24 176.38,104.12 176.38,103.65 176.26,103.53 175.23,103.53 175.11,103.4 175.11,86.44 180.48,81.08 187.25,81.08 187.61,81.44 v1(187.61,82.29)
  L05_SIG2 w0.127: v1(193.98,140.72) 188.34,140.72 187.22,139.59 187.22,137.79 187.45,137.56 187.45,137.32 v1(187.61,137.15) 187.62,137.15 187.62,133.26 187.45,133.09 186.49,133.09 186.37,132.97 186.37,127.29 186.49,127.17 186.59,127.17 186.71,127.04 186.71,126.78 186.57,126.64 186.34,126.64 186.22,126.52 186.22,126.24 186.35,126.11 186.57,126.11 186.7,125.98 186.7,125.77 186.44,125.51 186.44,124.84 186.56,124.71 187.08,124.71 187.22,124.57 187.22,124.08 187.44,123.85 187.44,123.61 v1(187.61,123.44) 187.62,123.43 187.62,119.55 187.45,119.38 186.49,119.38 186.37,119.25 186.37,113.57 186.49,113.45 186.59,113.45 186.71,113.33 186.71,113.07 186.57,112.92 186.34,112.92 186.22,112.8 186.22,112.53 186.35,112.39 186.57,112.39 186.7,112.27 186.7,112.06 186.44,111.8 186.44,111.12 186.56,111 187.08,111 187.22,110.86 187.22,110.36 187.44,110.14 187.44,109.89 v1(187.61,109.72) 187.62,109.71 187.62,105.83 187.45,105.66 186.49,105.66 186.37,105.54 186.37,99.86 186.49,99.73 186.59,99.73 186.71,99.61 186.71,99.35 186.57,99.21 186.34,99.21 186.22,99.08 186.22,98.81 186.35,98.68 186.57,98.68 186.7,98.55 186.7,98.34 186.44,98.08 186.44,97.4 186.56,97.28 187.08,97.28 187.22,97.14 187.22,96.64 187.44,96.42 187.44,96.17 v1(187.61,96.01) 187.62,96 187.62,92.11 187.45,91.94 186.49,91.94 186.37,91.82 186.37,86.14 186.49,86.02 186.59,86.02 186.72,85.9 186.72,85.64 186.57,85.49 186.34,85.49 186.22,85.37 186.22,85.09 186.35,84.96 186.57,84.96 186.7,84.83 186.7,84.63 186.44,84.37 186.44,83.69 186.56,83.57 187.08,83.57 187.22,83.43 187.22,82.93 187.44,82.7 187.44,82.46 v1(187.61,82.29)
DDR_BG1: length 142.9
  TOP w0.208: U38.J8 v1(187.61,87.89) ; R47.1 v1(187.9,146.94) ; U25.J8 v1(187.61,115.32) ; U33.J8 v1(187.61,101.61) ; U16.J8 v1(187.61,142.75) ; U20.J8 v1(187.61,129.04) ; U34.F11 v1(155.16,100.99)
  L05_SIG2 w0.127: v1(187.9,146.94) 187.9,144.78 187.26,144.15 187.26,143.1 v1(187.61,142.75)
  L10_SIG3 w0.127: v1(155.16,100.99) 155.56,101.4 159.31,101.4 160.15,102.23 160.95,102.23 162.7,103.98 179.17,103.98 180.08,104.9 185.81,104.9 186.7,104.01 186.99,104.01 188.8,102.2 188.8,100.63 189.28,100.15 190.11,100.15 190.42,99.84 190.42,99.61 190.3,99.49 188.59,99.49 188.47,99.37 188.47,99.08 188.59,98.96 190.3,98.96 190.42,98.84 190.42,98.55 190.3,98.43 188.59,98.43 188.47,98.31 188.47,98.03 188.59,97.9 190.3,97.9 190.42,97.78 190.42,95.61 190.3,95.49 189.32,95.49 189.19,95.37 189.19,95.09 189.32,94.96 190.3,94.96 190.42,94.84 190.42,94.56 190.3,94.44 189.32,94.44 189.19,94.31 189.19,94.03 189.32,93.91 190.3,93.91 190.42,93.79 190.42,93.5 190.3,93.38 189.32,93.38 189.19,93.26 189.19,92.97 189.32,92.85 190.3,92.85 190.42,92.73 190.42,91.34 190.42,91.34 190.42,88.73 190.04,88.34 188.06,88.34 v1(187.61,87.89)
  L12_SIG4 w0.127: v1(187.61,87.89) 188.56,88.84 188.98,88.84 190.18,90.04 190.18,95.62 190.4,95.84 190.4,97.88 188.67,99.61 188.17,99.61 188.02,99.76 188.02,101.2 v1(187.61,101.61) 188.56,102.55 188.98,102.55 190.18,103.76 190.18,109.34 190.4,109.56 190.4,111.6 188.67,113.33 188.19,113.33 188.02,113.49 188.02,114.91 v1(187.61,115.32) 188.56,116.27 188.98,116.27 190.18,117.48 190.18,123.06 190.4,123.28 190.4,125.29 188.65,127.04 188.17,127.04 188.02,127.19 188.02,128.63 v1(187.61,129.04) 188.56,129.98 188.98,129.98 190.18,131.19 190.18,136.77 190.4,136.99 190.4,139.01 188.65,140.76 188.17,140.76 188.02,140.91 188.02,142.35 v1(187.61,142.75)
DDR_CKE: length 150
  TOP w0.208: U25.G3 v1(185.21,110.52) ; U20.G3 v1(185.21,124.24) ; U16.G3 v1(185.21,137.95) ; U38.G3 v1(185.21,83.09) ; R57.1 v1(193.98,141.73) ; U33.G3 v1(185.21,96.81) ; U34.C11 v1(157.56,100.99)
  L03_SIG1 w0.127: v1(185.21,83.09) 184.81,83.49 178.6,83.49 175.49,86.6 175.49,102.05 177.08,103.64 177.08,105.5 176.68,105.9 173.03,105.9 172.91,105.77 172.91,105.39 173.03,105.27 176.32,105.27 176.53,105.06 176.53,104.84 176.32,104.64 172.4,104.64 172.28,104.76 172.28,105.77 172.13,105.92 166.63,105.92 166.48,105.77 166.48,105.39 166.61,105.27 167.23,105.27 167.39,105.11 167.39,104.79 167.23,104.64 165.98,104.64 165.85,104.76 165.85,105.77 165.73,105.9 165.3,105.9 163.93,104.52 163.93,101.44 163.16,100.68 162.09,100.68 161.9,100.88 159.69,100.88 159.4,100.58 157.96,100.58 v1(157.56,100.99)
  L05_SIG2 w0.127: v1(193.98,141.73) 193.36,141.11 187.34,141.11 185.21,138.98 v1(185.21,137.95) 185.21,137.85 185.64,137.41 185.77,137.41 186.24,136.95 186.24,136.14 185.26,135.16 185.26,132.47 185.12,132.33 184.21,132.33 184.07,132.19 184.07,131.15 184.8,130.41 184.8,127.18 184.68,127.06 184.53,127.06 184.39,126.92 184.39,126.38 185.21,125.56 v1(185.21,124.24) 185.21,124.13 185.64,123.7 185.77,123.7 186.24,123.23 186.24,122.42 185.26,121.44 185.26,118.75 185.12,118.62 184.19,118.62 184.07,118.49 184.07,117.43 184.8,116.7 184.8,113.46 184.68,113.34 184.53,113.34 184.39,113.21 184.39,112.66 185.21,111.84 v1(185.21,110.52) 185.21,110.41 185.68,109.95 185.84,109.95 186.24,109.55 186.24,108.7 185.26,107.73 185.26,105.04 185.12,104.9 184.21,104.9 184.07,104.76 184.07,103.72 184.8,102.98 184.8,99.75 184.68,99.63 184.59,99.63 184.38,99.42 184.38,98.95 185.21,98.13 v1(185.21,96.81) 185.21,96.7 185.64,96.27 185.77,96.27 186.24,95.8 186.24,94.99 185.26,94.01 185.26,91.32 185.12,91.18 184.21,91.18 184.07,91.04 184.07,90 184.8,89.26 184.8,86.03 184.68,85.91 184.53,85.91 184.41,85.79 184.41,85.22 185.21,84.41 v1(185.21,83.09)
  BOTTOM w0.208: R731.1 185.21,83.9 v1(185.21,83.09)
DDR_CKE1: length 150.1
  TOP w0.208: U33.G2 v1(185.21,96.01) ; U16.G2 v1(185.21,137.15) ; U38.G2 v1(185.21,82.29) ; U20.G2 v1(185.21,123.44) ; U34.D12 v1(156.76,100.19) ; U25.G2 v1(185.21,109.72)
  L05_SIG2 w0.127: v1(156.76,100.19) 156.76,100.29 156.36,100.68 156.36,103.53 156.1,103.8 155.79,103.8 155.56,104.03 155.56,105.98 155.78,106.2 159.67,106.2 160.65,107.18 162.17,107.18 162.29,107.3 162.29,107.63 162.41,107.75 162.8,107.75 162.92,107.63 162.92,107.3 163.04,107.18 163.43,107.18 163.55,107.3 163.55,107.63 163.67,107.75 164.06,107.75 164.18,107.63 164.18,107.3 164.3,107.18 164.69,107.18 164.81,107.3 164.81,107.63 164.93,107.75 165.32,107.75 165.44,107.63 165.44,107.3 165.56,107.18 167.56,107.18 170.03,104.71 174.25,104.71 179.11,99.85 179.11,78.69 179.45,78.35 185.4,78.35 185.6,78.55 185.6,81.9 v1(185.21,82.29) 185.21,82.45 184.82,82.84 184.82,84.04 184,84.86 184,87.57 184.45,88.02 184.45,88.91 183.67,89.7 183.67,91.48 183.81,91.63 184.51,91.63 184.89,92.02 184.89,94.22 185.86,95.19 185.86,95.78 185.64,96.01 v1(185.21,96.01) 185.21,96.16 184.82,96.55 184.82,97.76 184,98.57 184,101.28 184.44,101.72 184.44,102.64 183.67,103.42 183.67,105.2 183.81,105.35 184.51,105.35 184.89,105.73 184.89,107.93 185.86,108.9 185.86,109.5 185.65,109.72 185.58,109.72 185.58,109.72 v1(185.21,109.72) 185.21,109.87 184.82,110.26 184.82,111.47 184,112.29 184,115 184.44,115.44 184.44,116.36 183.67,117.13 183.67,118.92 183.81,119.06 184.51,119.06 184.89,119.45 184.89,121.65 185.86,122.62 185.86,123.22 185.64,123.44 v1(185.21,123.44) 185.21,123.59 184.82,123.98 184.82,125.19 184,126 184,128.71 184.44,129.15 184.44,130.07 183.67,130.85 183.67,132.63 183.81,132.78 184.51,132.78 184.89,133.17 184.89,135.36 185.86,136.33 185.86,136.93 185.64,137.15 v1(185.21,137.15)
  BOTTOM w0.208: R730.1 185.38,82.46 v1(185.21,82.29) ; v1(185.21,137.15) 185.78,137.72 185.78,138.52 187.91,140.65 191.17,140.65 191.72,141.2 193.78,141.2 193.78,141.2 194.13,141.2 194.65,141.72 R379.1
DDR_CLKN: length 144.1
  TOP w0.157: v1(184.41,141.95) U16.F8 ; v1(184.41,114.52) U25.F8 ; v1(184.41,100.81) U33.F8 ; v1(184.41,128.24) U20.F8 ; U34.B8 v1(158.36,103.39) ; v1(184.41,87.09) U38.F8
  L03_SIG1 w0.109: v1(158.36,103.39) 158.76,103.8 159.33,103.8 159.45,103.68 161.51,103.68 161.77,103.94 161.77,108.8 167.69,114.72 168.73,114.72 169.09,114.36 169.09,113.25 169.31,113.02 171.59,113.02 171.75,113.19 171.75,113.51 171.6,113.66 170.11,113.66 169.85,113.92 169.85,114.41 170.16,114.72 177.99,114.72 178.93,113.78 178.93,86.86 179.37,86.42 183.76,86.42 184.41,87.08 v1(184.41,87.09) 184.5,87.18 184.5,87.39 184.15,87.74 184.15,91.24 185.67,92.77 185.67,97.82 185.53,97.96 184.35,97.96 183.94,98.37 183.94,99.05 184.81,99.92 184.81,100.22 184.68,100.35 184.52,100.35 184.41,100.47 v1(184.41,100.81) 184.5,100.89 184.5,101.07 184.12,101.44 184.12,105.03 185.67,106.58 185.67,111.57 185.52,111.72 184.3,111.72 183.99,112.02 183.99,112.82 184.81,113.64 184.81,113.91 184.65,114.07 184.52,114.07 184.41,114.18 v1(184.41,114.52) 184.5,114.61 184.5,114.82 184.15,115.17 184.15,118.74 185.64,120.23 185.64,125.27 185.48,125.43 184.28,125.43 183.92,125.79 183.92,126.46 184.81,127.35 184.81,127.63 184.65,127.79 184.52,127.79 184.41,127.9 v1(184.41,128.24) 184.5,128.32 184.5,128.52 184.13,128.89 184.13,132.46 185.64,133.97 185.64,138.99 185.5,139.14 184.31,139.14 183.94,139.51 183.94,140.19 184.81,141.07 184.81,141.34 184.65,141.5 184.52,141.5 184.41,141.61 v1(184.41,141.95)
  BOTTOM w0.157: v1(184.41,141.95) 184.44,141.99 184.44,146.94 184.32,147.07 184.15,147.07 183.98,146.9 183.69,146.9 183.62,146.97 183.62,147.45 R374.1
DDR_CLKP: length 144.1
  TOP w0.157: U34.A8 v1(159.16,103.39) ; U33.F7 v1(185.21,100.01) ; U38.F7 v1(185.21,86.29) ; U20.F7 v1(185.21,127.44) ; U25.F7 v1(185.21,113.72) ; U16.F7 v1(185.21,141.15)
  L03_SIG1 w0.109: v1(185.21,141.15) 184.16,140.1 184.16,139.6 184.4,139.36 185.59,139.36 185.86,139.09 185.86,133.88 184.35,132.37 184.35,128.98 184.81,128.53 184.81,127.97 185.21,127.56 v1(185.21,127.44) 184.14,126.36 184.14,125.88 184.37,125.65 185.58,125.65 185.86,125.36 185.86,120.14 184.37,118.65 184.37,115.26 184.81,114.82 184.81,114.26 185.21,113.86 v1(185.21,113.72) 185.04,113.55 185.03,113.55 184.21,112.73 184.21,112.12 184.39,111.94 185.61,111.94 185.89,111.66 185.89,106.49 184.34,104.94 184.34,101.54 184.81,101.07 184.81,100.53 185.21,100.13 v1(185.21,100.01) 184.16,98.96 184.16,98.46 184.44,98.18 185.62,98.18 185.89,97.91 185.89,92.68 184.37,91.15 184.37,87.83 184.81,87.39 U38.F7 v1(185.21,86.29) 185.07,86.15 184.78,86.15 184.61,86.32 184.61,86.46 184.46,86.61 184.26,86.61 183.85,86.2 179.28,86.2 178.71,86.77 178.71,113.68 177.9,114.5 170.25,114.5 170.07,114.32 170.07,114.01 170.2,113.88 171.69,113.88 171.97,113.6 171.97,113.09 171.68,112.8 169.22,112.8 168.87,113.15 168.87,114.27 168.64,114.5 167.78,114.5 161.99,108.7 161.99,103.85 161.6,103.46 159.23,103.46 v1(159.16,103.39)
  BOTTOM w0.122: v1(185.21,141.15) U16.F7 184.81,142.29 184.73,142.37
  BOTTOM w0.157: 184.73,142.37 184.73,147.12 184.85,147.23 R373.1
DDR_CS1N: length 143.1
  TOP w0.208: v1(185.42,146.69) 185.86,147.13 R45.1 ; U33.G8 v1(185.21,101.61) ; U38.G8 v1(185.21,87.89) ; U16.G8 v1(185.21,142.75) ; U34.E11 v1(155.96,100.99) ; U20.G8 v1(185.21,129.04) ; U25.G8 v1(185.21,115.32)
  L03_SIG1 w0.127: v1(185.21,87.89) 185.96,88.64 185.96,90.64 187.66,92.35 187.66,94.3 187.3,94.66 187.3,95.13 188.02,95.84 188.02,97.48 186.31,99.19 186.31,100.61 186.12,100.8 186.12,101.08 185.6,101.61 v1(185.21,101.61) 185.96,102.35 185.96,104.36 187.66,106.07 187.66,108.05 187.32,108.4 187.32,108.86 188.02,109.56 188.02,111.19 186.31,112.9 186.31,114.33 186.12,114.51 186.12,114.8 185.6,115.32 v1(185.21,115.32) 185.96,116.07 185.96,118.08 187.66,119.78 187.66,121.77 187.31,122.12 187.31,122.57 188.02,123.27 188.02,124.91 186.31,126.62 186.31,128.04 186.12,128.23 186.12,128.52 185.6,129.04 v1(185.21,129.04) 185.96,129.79 185.96,131.79 187.66,133.5 187.66,135.48 187.31,135.83 187.31,136.29 188.02,136.99 188.02,138.62 186.31,140.34 186.31,141.76 186.12,141.94 186.12,142.23 185.6,142.75 v1(185.21,142.75)
  L05_SIG2 w0.127: v1(185.21,142.75) 185.86,143.41 185.86,146.24 v1(185.42,146.69)
  L10_SIG3 w0.127: v1(155.96,100.99) 155.56,100.6 155.56,100.35 155.56,100.03 155.79,99.8 159.12,99.8 159.33,100 160.62,100 161.83,101.22 161.83,102.08 162.89,103.14 163.56,103.14 163.68,103.02 163.68,102.67 163.8,102.55 164.19,102.55 164.31,102.67 164.31,103.02 164.43,103.14 167.6,103.14 167.72,103.02 167.72,102.11 167.84,101.99 168.23,101.99 168.35,102.11 168.35,103.02 168.47,103.14 168.86,103.14 168.98,103.02 168.98,102.11 169.1,101.99 171.64,101.99 171.76,102.11 171.76,103.13 171.88,103.25 172.27,103.25 172.39,103.13 172.39,101.92 172.51,101.8 172.9,101.8 173.02,101.92 173.02,103.13 173.14,103.25 173.53,103.25 173.65,103.13 173.65,101.92 173.77,101.8 174.16,101.8 174.28,101.92 174.28,103.13 174.4,103.25 174.79,103.25 174.91,103.13 174.91,101.92 175.03,101.8 176.16,101.8 176.48,102.13 176.48,102.94 176.6,103.05 180.98,103.05 181.1,103.18 181.1,103.9 181.23,104.03 181.61,104.03 181.73,103.9 181.73,103.18 181.86,103.05 182.24,103.05 182.36,103.18 182.36,103.9 182.49,104.03 182.87,104.03 182.99,103.9 182.99,103.18 183.12,103.05 183.5,103.05 183.62,103.18 183.62,103.9 183.75,104.03 184.13,104.03 184.25,103.9 184.25,103.18 184.38,103.05 185.17,103.05 185.63,102.59 185.63,94.77 185.79,94.62 186.05,94.62 186.17,94.5 186.17,94.21 186.05,94.09 185.76,94.09 185.63,93.97 185.63,93.71 185.79,93.56 186.05,93.56 186.17,93.44 186.17,93.16 186.05,93.03 185.76,93.03 185.63,92.91 185.63,92.66 185.76,92.53 186.02,92.53 186.14,92.41 186.14,88.82 v1(185.21,87.89)
DDR_CSN: length 143.5
  TOP w0.208: U38.G7 v1(185.21,87.09) ; U25.G7 v1(185.21,114.52) ; U34.D11 v1(156.76,100.99) ; U16.G7 v1(185.21,141.95) ; U33.G7 v1(185.21,100.81) ; U20.G7 v1(185.21,128.24)
  L03_SIG1 w0.127: v1(185.21,87.09) 185.21,87.34 184.82,87.73 184.82,88.94 185.23,89.35 185.46,89.35 185.59,89.48 185.59,90.8 187.25,92.45 187.25,94.17 186.77,94.64 186.77,95.41 187.2,95.84 187.2,97.6 185.93,98.87 185.93,100.65 185.77,100.81 v1(185.21,100.81) 185.21,101.05 184.82,101.44 184.82,102.65 185.23,103.06 185.46,103.06 185.59,103.19 185.59,104.51 187.25,106.17 187.25,107.94 186.8,108.39 186.8,109.16 187.2,109.56 187.2,111.31 185.93,112.59 185.93,114.36 185.77,114.52 v1(185.21,114.52) 185.21,114.77 184.82,115.16 184.82,116.43 185.17,116.78 185.46,116.78 185.59,116.91 185.59,118.23 187.25,119.89 187.25,121.65 186.8,122.11 186.8,122.88 187.2,123.28 187.2,125.03 185.93,126.3 185.93,128.08 185.77,128.24 v1(185.21,128.24) 185.21,128.48 184.82,128.88 184.82,130.14 185.17,130.5 185.46,130.5 185.59,130.62 185.59,131.94 187.25,133.61 187.25,135.37 186.8,135.82 186.8,136.59 187.2,136.99 187.2,138.74 185.93,140.02 185.93,141.8 185.77,141.95 v1(185.21,141.95)
  L10_SIG3 w0.127: v1(185.21,87.09) 186.3,87.09 186.42,87.21 186.42,88.05 186.67,88.3 187.31,88.3 188,88.99 188,89.56 187.88,89.68 187.45,89.68 187.33,89.8 187.33,90.09 187.45,90.21 187.88,90.21 188,90.33 188,90.62 187.88,90.74 187.45,90.74 187.33,90.86 187.33,91.14 187.45,91.27 187.88,91.27 188,91.39 188,91.67 187.88,91.79 187.45,91.79 187.33,91.92 187.33,92.2 187.45,92.32 187.88,92.32 188,92.44 188,92.73 187.88,92.85 187.45,92.85 187.33,92.97 187.33,93.26 187.45,93.38 187.88,93.38 188,93.5 188,93.79 187.88,93.91 187.45,93.91 187.33,94.03 187.33,94.31 187.45,94.44 187.88,94.44 188,94.56 188,94.84 187.88,94.96 187.45,94.96 187.33,95.09 187.33,95.37 187.45,95.49 187.88,95.49 188,95.61 188,97.47 187.88,97.59 186.35,97.59 186.22,97.71 186.22,98 186.35,98.12 187.88,98.12 188,98.24 188,98.53 187.88,98.65 186.35,98.65 186.22,98.77 186.22,99.05 186.35,99.18 187.88,99.18 188,99.3 188,99.58 187.88,99.7 186.35,99.7 186.22,99.83 186.22,100.11 186.35,100.23 187.88,100.23 188,100.35 188,102.26 187.3,102.96 186.77,102.96 185.71,104.02 184.92,104.02 184.48,104.46 180.16,104.46 179.32,103.62 162.85,103.62 161.46,102.23 161.46,101.37 161.01,100.91 159.46,100.91 159.15,100.6 158.52,100.6 158.52,100.6 157.39,100.6 157.39,100.6 157.15,100.6 v1(156.76,100.99)
  BOTTOM w0.208: v1(185.21,141.95) 185.93,142.67 185.93,147.6 R372.1
DDR_DM0: length 52.3
  TOP w0.208: U16.A7 v1(180.41,141.95) ; U34.E1 v1(155.96,108.99)
  L12_SIG4 w0.127: v1(180.41,141.95) 180.41,140.62 178.18,138.39 178.18,137.86 178.06,137.74 177.78,137.74 177.66,137.62 177.66,137.23 177.78,137.11 178.06,137.11 178.18,136.99 178.18,136.6 178.06,136.48 177.78,136.48 177.66,136.36 177.66,135.97 177.78,135.85 178.06,135.85 178.18,135.73 178.18,135.34 178.06,135.22 177.78,135.22 177.66,135.1 177.66,134.71 177.78,134.59 178.06,134.59 178.18,134.47 178.18,134.08 178.06,133.96 177.78,133.96 177.66,133.84 177.66,133.45 177.78,133.33 178.06,133.33 178.18,133.21 178.18,132.82 178.06,132.7 177.78,132.7 177.66,132.58 177.66,132.19 177.78,132.07 178.06,132.07 178.18,131.95 178.18,131.56 178.06,131.44 177.78,131.44 177.66,131.32 177.66,130.93 177.78,130.81 178.06,130.81 178.18,130.69 178.18,126.68 175.45,123.95 169.45,123.95 155.96,110.45 v1(155.96,108.99)
DDR_DM1: length 50.2
  TOP w0.208: v1(180.41,128.24) U20.A7 ; U34.C5 v1(157.56,105.79)
  L10_SIG3 w0.127: v1(157.56,105.79) 157.56,105.86 157.38,106.04 157.38,106.05 157.15,106.28 157.15,109.15 157.1,109.2 157.1,109.47 157.1,112.19 170.08,125.17 170.26,125.17 170.53,124.9 170.53,124.73 167.03,121.22 167.03,121.05 167.3,120.78 167.47,120.78 171.42,124.73 171.42,124.9 170.7,125.62 170.7,125.79 171.57,126.66 176.91,126.66 177.55,127.31 179.09,127.31 180.02,128.24 v1(180.41,128.24)
DDR_DM2: length 37.6
  TOP w0.208: U34.D14 v1(156.76,98.59) ; U25.A7 v1(180.41,114.52)
  L12_SIG4 w0.127: v1(180.41,114.52) 179.3,114.52 179.18,114.64 179.18,115.24 179.06,115.36 178.67,115.36 178.55,115.24 178.55,114.65 178.42,114.52 178.04,114.52 177.92,114.64 177.92,115.07 177.8,115.19 177.41,115.19 177.29,115.07 177.29,114.65 177.16,114.52 175.74,114.52 171.07,109.86 169.93,109.86 169.51,109.44 169.51,108.3 168.53,107.31 164.33,107.31 160.71,103.7 160.36,103.7 159.66,103 156.59,103 156.59,103 156.48,103 156.36,102.88 156.36,99.23 156.76,98.84 v1(156.76,98.59)
DDR_DM3: length 35
  TOP w0.208: U33.A7 v1(180.41,100.81) ; U34.B17 v1(158.36,95.39)
  L10_SIG3 w0.127: v1(180.41,100.81) 180.13,101.08 180.13,101.33 179.83,101.63 178.1,101.63 177.18,100.7 177.18,99.88 177.06,99.76 175.1,99.76 174.98,99.88 174.98,100.36 174.85,100.48 174.47,100.48 174.35,100.36 174.35,99.88 174.22,99.76 173.84,99.76 173.72,99.88 173.72,100.36 173.59,100.48 173.21,100.48 173.09,100.36 173.09,99.88 172.96,99.76 172.58,99.76 172.46,99.88 172.46,100.36 172.33,100.48 171.95,100.48 171.83,100.36 171.83,99.95 171.7,99.82 169.98,99.82 169.49,100.32 163.76,100.32 163.61,100.17 163.61,99.89 163.48,99.76 161.99,99.76 160.81,98.58 158.9,98.58 158.5,98.18 156.75,98.18 156.59,98.03 156.59,97.71 157.15,97.15 157.15,96.85 157.41,96.58 157.72,96.58 157.95,96.35 157.95,95.87 158.36,95.46 v1(158.36,95.39)
DDR_DM4: length 34.7
  TOP w0.208: U34.C17 v1(157.56,95.39) ; U38.A7 v1(180.41,87.09)
  L12_SIG4 w0.127: v1(180.41,87.09) 178.61,87.09 178.38,87.31 178.38,89.72 176.98,91.13 176.81,91.13 176.41,90.73 176.24,90.73 175.97,91.01 175.97,91.18 176.36,91.57 176.36,91.74 176.09,92.02 175.91,92.02 175.52,91.62 175.35,91.62 175.08,91.9 175.08,92.07 175.47,92.46 175.47,92.63 175.2,92.91 175.02,92.91 174.63,92.51 174.46,92.51 174.18,92.79 174.18,92.96 174.58,93.35 174.58,93.53 174.31,93.8 174.13,93.8 173.74,93.4 173.57,93.4 173.29,93.68 173.29,93.85 173.69,94.24 173.69,94.42 173.17,94.93 162.63,94.93 161.39,96.16 159.71,96.16 159.35,95.8 157.96,95.8 v1(157.56,95.39)
DDR_DQ0: length 52.3
  TOP w0.208: U16.C2 v1(182.01,137.15) ; U34.A3 v1(159.16,107.39)
  L12_SIG4 w0.127: v1(182.01,137.15) 181.55,136.69 181.55,129.26 181.6,129.2 181.6,126.88 176.67,121.95 171.95,121.95 166.91,116.92 166.91,116.75 167.6,116.06 167.6,115.89 167.33,115.61 167.16,115.61 166.47,116.3 166.3,116.3 166.02,116.03 166.02,115.86 166.71,115.17 166.71,115 166.44,114.72 166.27,114.72 165.58,115.41 165.41,115.41 165.13,115.14 165.13,114.97 165.82,114.28 165.82,114.11 165.55,113.83 165.38,113.83 164.69,114.52 164.52,114.52 164.24,114.25 164.24,114.08 164.93,113.39 164.93,113.22 164.66,112.94 164.48,112.94 163.8,113.63 163.62,113.63 163.04,113.04 163.04,110.39 160.04,107.39 v1(159.16,107.39)
DDR_DQ1: length 52.3
  TOP w0.208: U34.B2 v1(158.36,108.19) ; U16.B7 v1(181.21,141.95)
  L12_SIG4 w0.127: v1(181.21,141.95) 182.19,140.98 182.19,139.93 182.06,139.81 180.11,139.81 178.54,138.24 178.54,126.53 175.6,123.59 169.61,123.59 156.36,110.34 156.36,108.83 156.59,108.6 157.95,108.6 v1(158.36,108.19)
DDR_DQ2: length 52.3
  TOP w0.208: U34.C2 v1(157.56,108.19) ; U16.D3 v1(182.81,137.95)
  L12_SIG4 w0.127: v1(157.56,108.19) 157.95,107.8 158.56,107.8 158.78,108.01 158.76,108.03 158.76,109.2 159.05,109.48 161.61,109.48 162.67,110.54 162.67,113.39 168.57,119.29 168.57,119.46 168.12,119.9 168.12,120.08 168.39,120.35 168.56,120.35 169.01,119.9 169.18,119.9 169.46,120.18 169.46,120.35 169.01,120.8 169.01,120.97 169.28,121.24 169.46,121.24 169.9,120.8 170.07,120.8 170.35,121.07 170.35,121.24 169.9,121.69 169.9,121.86 170.17,122.13 170.35,122.13 170.79,121.69 170.96,121.69 171.6,122.32 176.52,122.32 180.82,126.62 180.82,129.2 181.04,129.42 181.04,136.21 180.82,136.43 180.82,137.32 181.05,137.55 182.16,137.55 182.41,137.79 182.65,137.79 v1(182.81,137.95)
DDR_DQ3: length 52.3
  TOP w0.208: U34.D2 v1(156.76,108.19) ; v1(182.81,141.95) U16.D7
  L12_SIG4 w0.127: v1(182.81,141.95) 183.2,141.56 183.2,137.79 182.96,137.55 182.65,137.55 182.42,137.32 182.42,136.17 181.95,135.71 181.95,134.35 182.4,133.9 182.4,127.16 176.82,121.59 173.86,121.59 163.4,111.13 163.4,110.24 160.17,107 157.39,107 157.15,107.25 157.15,107.8 v1(156.76,108.19)
DDR_DQ4: length 52.3
  TOP w0.208: U34.E2 v1(155.96,108.19) ; U16.D2 v1(182.81,137.15)
  L12_SIG4 w0.127: v1(155.96,108.19) 156.35,107.8 156.35,106.45 156.59,106.2 159.9,106.2 169.18,115.48 169.35,115.48 169.59,115.24 169.76,115.24 170.03,115.51 170.03,115.68 169.8,115.92 169.8,116.09 170.07,116.37 170.24,116.37 170.48,116.13 170.65,116.13 170.92,116.4 170.92,116.57 170.69,116.81 170.69,116.98 170.96,117.26 171.13,117.26 171.37,117.02 171.54,117.02 171.82,117.29 171.82,117.47 171.58,117.7 171.58,117.88 171.85,118.15 172.02,118.15 172.26,117.91 172.43,117.91 172.71,118.18 172.71,118.36 172.47,118.59 172.47,118.84 174.85,121.22 176.98,121.22 183.2,127.45 183.2,129.98 183.35,130.13 183.35,135.59 183.2,135.73 183.2,136.76 v1(182.81,137.15)
DDR_DQ5: length 52.3
  TOP w0.208: U16.D8 v1(182.81,142.75) ; U34.G1 v1(154.36,108.99)
  L12_SIG4 w0.127: v1(154.36,108.99) 154.36,109.89 169.58,125.11 175.44,125.11 176.21,125.88 176.21,129.29 176.93,130 176.93,138.17 179.13,140.38 179.13,142.18 180.1,143.15 182.42,143.15 v1(182.81,142.75)
DDR_DQ6: length 52.2
  TOP w0.208: U34.F2 v1(155.16,108.19) ; U16.E3 v1(183.61,137.95)
  L12_SIG4 w0.127: v1(183.61,137.95) 184,137.56 184,135.85 183.81,135.66 183.81,134.06 184,133.86 184,127.73 165.62,109.35 163.57,109.35 159.62,105.4 155.79,105.4 155.56,105.63 155.56,107.78 v1(155.16,108.19)
DDR_DQ7: length 52.3
  TOP w0.208: U34.F1 v1(155.16,108.99) ; U16.E7 v1(183.61,141.95)
  L12_SIG4 w0.127: v1(155.16,108.99) 154.88,109.27 154.88,109.89 169.3,124.32 175.16,124.32 177.29,126.45 177.29,138.02 179.51,140.24 179.51,142.01 179.85,142.35 183.22,142.35 v1(183.61,141.95)
DDR_DQ8: length 50.1
  TOP w0.208: U20.C2 v1(182.01,123.44) ; U34.E3 v1(155.96,107.39)
  L10_SIG3 w0.127: v1(182.01,123.44) 182.42,123.85 182.42,125.32 184,126.91 184,128.07 184,128.08 184,129.2 183.77,129.43 178.76,129.43 177.16,127.83 177.16,127.47 176.72,127.02 175.99,127.02 175.87,127.14 175.87,127.45 175.75,127.58 175.36,127.58 175.24,127.45 175.24,127.14 175.12,127.02 174.73,127.02 174.61,127.14 174.61,127.45 174.49,127.58 174.1,127.58 173.98,127.45 173.98,127.14 173.86,127.02 173.47,127.02 173.35,127.14 173.35,127.45 173.23,127.58 172.84,127.58 172.72,127.45 172.72,127.14 172.6,127.02 171.42,127.02 156.35,111.96 156.35,107.79 v1(155.96,107.39)
DDR_DQ9: length 50.1
  TOP w0.208: U34.C3 v1(157.56,107.39) ; U20.B7 v1(181.21,128.24)
  L10_SIG3 w0.127: v1(157.56,107.39) 157.56,107.52 157.96,107.93 157.96,109.45 158,109.48 158,112.17 160.23,114.4 161.78,114.4 162.23,114.86 162.23,115.03 161.51,115.75 161.51,115.92 166.05,120.46 166.22,120.46 166.49,120.18 166.49,120.01 162.41,115.92 162.41,115.75 162.68,115.48 162.85,115.48 173.66,126.29 179.26,126.29 v1(181.21,128.24)
DDR_DQ10: length 50.2
  TOP w0.208: U34.D3 v1(156.76,107.39) ; U20.D3 v1(182.81,124.24)
  L10_SIG3 w0.127: v1(156.76,107.39) 156.36,107 155.79,107 155.56,107.23 155.56,111.69 172.05,128.17 176.99,128.17 179.07,130.26 183.75,130.26 184.81,129.19 184.81,126.99 182.81,124.99 v1(182.81,124.24)
DDR_DQ11: length 50.1
  TOP w0.208: U20.D7 v1(182.81,128.24) ; U34.B3 v1(158.36,107.39)
  L10_SIG3 w0.127: v1(158.36,107.39) 158.51,107.39 158.92,107.8 159.32,107.8 159.55,108.03 159.55,109.15 158.73,109.97 158.73,111.87 160.54,113.67 163.92,113.67 164.34,114.1 164.34,114.27 163.62,114.99 163.62,115.16 167.48,119.01 167.65,119.01 167.92,118.74 167.92,118.57 164.51,115.16 164.51,114.99 164.79,114.71 164.96,114.71 175.81,125.56 180.52,125.56 182.81,127.85 v1(182.81,128.24)
DDR_DQ12: length 50.2
  TOP w0.208: U34.D4 v1(156.76,106.59) ; U20.D2 v1(182.81,123.44)
  L10_SIG3 w0.127: v1(182.81,123.44) 182.81,123.63 183.2,124.02 183.2,124.38 183.45,124.63 183.77,124.63 184,124.4 184,122.41 183.51,121.92 179.35,121.92 167.94,110.51 167.77,110.51 167.49,110.78 167.49,110.95 169.97,113.43 169.97,113.6 169.75,113.82 169.57,113.82 166.65,110.9 166.65,110.73 167.32,110.06 167.32,109.89 166.64,109.21 164.65,109.21 160.78,105.34 160.76,105.34 160.4,104.98 158.93,104.98 158.51,105.4 157.36,105.4 157.15,105.62 157.15,105.95 156.92,106.18 156.88,106.18 156.76,106.31 v1(156.76,106.59)
DDR_DQ13: length 50.1
  TOP w0.208: U34.C4 v1(157.56,106.59) ; U20.D8 v1(182.81,129.04)
  L10_SIG3 w0.127: v1(157.56,106.59) 157.56,106.84 157.96,107.25 157.96,107.55 158.21,107.8 158.52,107.8 158.76,108.05 158.76,109.21 158.36,109.61 158.36,112.02 160.38,114.04 161.93,114.04 171.88,123.99 172.05,123.99 172.32,123.72 172.32,123.54 169.4,120.62 169.4,120.45 169.67,120.18 169.85,120.18 173.22,123.54 173.22,123.72 172.5,124.44 172.5,124.61 173.82,125.93 180.25,125.93 182.42,128.09 182.42,128.65 v1(182.81,129.04)
DDR_DQ14: length 50.1
  TOP w0.208: U34.B4 v1(158.36,106.59) ; U20.E3 v1(183.61,124.24)
  L10_SIG3 w0.127: v1(158.36,106.59) 158.76,106.18 158.76,105.63 159.05,105.34 159.66,105.34 159.66,105.35 160.25,105.35 160.61,105.71 160.63,105.71 167.24,112.32 167.24,112.33 169.87,114.96 170.05,114.96 170.76,114.25 170.93,114.25 175.65,118.96 175.65,119.13 175.37,119.4 175.2,119.4 170.93,115.14 170.76,115.14 170.49,115.41 170.49,115.58 177.95,123.05 183.08,123.05 183.22,123.18 183.22,123.71 183.61,124.11 v1(183.61,124.24)
DDR_DQ15: length 50.1
  TOP w0.208: U34.B5 v1(158.36,105.79) ; U20.E7 v1(183.61,128.24)
  L10_SIG3 w0.127: v1(158.36,105.79) 157.95,106.2 157.95,106.77 158.18,107 159.32,107 159.96,107.64 159.96,109.26 159.09,110.12 159.09,111.71 160.69,113.31 164.08,113.31 171.73,120.95 171.9,120.95 172.62,120.23 172.85,120.23 175.67,123.05 175.67,123.22 175.39,123.5 175.22,123.5 172.85,121.12 172.62,121.12 172.34,121.4 172.34,121.57 175.97,125.19 180.96,125.19 183.61,127.85 v1(183.61,128.24)
DDR_DQ16: length 37.4
  TOP w0.208: U25.C2 v1(182.01,109.72) ; U34.E13 v1(155.96,99.39)
  L12_SIG4 w0.127: v1(182.01,109.72) 181.62,109.33 181.47,109.33 181.11,108.98 179.84,108.98 179.5,108.63 179.5,107.46 178.51,106.47 178.51,106.29 178.85,105.95 178.85,105.77 178.58,105.5 178.41,105.5 178.06,105.85 177.89,105.85 177.61,105.58 177.61,105.4 177.96,105.06 177.96,104.88 177.69,104.61 177.52,104.61 177.17,104.96 177,104.96 176.72,104.69 176.72,104.51 177.07,104.16 177.07,103.99 176.8,103.72 176.63,103.72 176.28,104.07 176.11,104.07 172.92,100.88 169.08,100.88 167.96,99.76 162.45,99.76 161.39,98.69 159.78,98.69 159,97.92 158.63,97.92 158.63,97.91 156.59,97.91 156.35,98.16 156.35,98.82 155.96,99.21 v1(155.96,99.39)
DDR_DQ17: length 37.5
  TOP w0.208: U34.C14 v1(157.56,98.59) ; U25.B7 v1(181.21,114.52)
  L12_SIG4 w0.127: v1(181.21,114.52) 181.56,114.17 181.56,113.18 181.09,112.71 176.45,112.71 172.07,108.33 172.07,106.29 171.7,105.91 168.41,105.91 168.29,106.03 168.29,106.38 168.16,106.5 167.78,106.5 167.66,106.38 167.66,106.03 167.53,105.91 167.15,105.91 167.03,106.03 167.03,106.38 166.9,106.5 166.52,106.5 166.4,106.38 166.4,106.03 166.27,105.91 165.89,105.91 165.77,106.03 165.77,106.38 165.64,106.5 165.26,106.5 165.14,106.38 165.14,106.03 165.01,105.91 163.96,105.91 161.01,102.97 160.73,102.97 158.75,100.98 158.75,100.83 158.5,100.58 158.19,100.58 157.95,100.33 157.95,98.98 v1(157.56,98.59)
DDR_DQ18: length 37.5
  TOP w0.208: U34.B14 v1(158.36,98.59) ; U25.D3 v1(182.81,110.52)
  L12_SIG4 w0.127: v1(158.36,98.59) 159.13,99.37 159.13,100.33 161.04,102.23 161.32,102.23 163.59,104.51 163.84,104.51 163.96,104.39 166.03,104.39 166.48,103.94 166.76,103.94 167.33,104.51 172.45,104.51 173.1,105.16 173.1,106.65 172.82,106.93 172.82,107.4 177.31,111.9 179.67,111.9 179.67,111.9 183.88,111.9 184.02,111.76 184.02,111.13 183.9,111 182.88,111 182.81,110.93 v1(182.81,110.52)
DDR_DQ19: length 37.4
  TOP w0.208: v1(161.99,97.98) 159.4,97.98 159.19,98.19 U34.A14 ; U25.D7 v1(182.81,114.52)
  L12_SIG4 w0.127: v1(161.99,97.98) 162.37,98.36 169.1,98.36 169.49,98.75 173.43,98.75 176.28,101.6 176.28,101.8 176.54,102.06 176.74,102.06 181.92,107.25 183.02,107.25 184.02,108.24 184.02,110.68 184.4,111.06 184.4,112.93 v1(182.81,114.52)
DDR_DQ20: length 37.4
  TOP w0.208: U34.E14 v1(155.96,98.59) ; U25.D2 v1(182.81,109.72)
  L12_SIG4 w0.127: v1(182.81,109.72) 182.62,109.72 182.4,109.5 182.4,108.63 182.28,108.51 180.01,108.51 179.86,108.36 179.86,105.9 176.57,102.6 176.39,102.6 176.25,102.75 176.07,102.75 175.8,102.48 175.8,102.31 175.95,102.16 175.95,101.99 175.68,101.71 175.5,101.71 175.35,101.86 175.18,101.86 174.91,101.59 174.91,101.42 175.06,101.27 175.06,101.1 174.78,100.82 174.61,100.82 174.46,100.97 174.25,100.97 174.02,100.74 174.02,100.53 174.17,100.38 174.17,100.21 173.72,99.76 169.74,99.76 169.31,99.34 162.55,99.34 161.54,98.33 160.17,98.33 159.5,97.66 156.49,97.66 155.96,98.2 v1(155.96,98.59)
DDR_DQ21: length 37.5
  TOP w0.208: U34.B13 v1(158.36,99.39) ; U25.D8 v1(182.81,115.32)
  L12_SIG4 w0.127: v1(182.81,115.32) 182.42,114.93 182.42,114.31 183.64,113.09 183.64,112.65 183.26,112.27 177,112.27 172.45,107.71 172.45,105.9 171.43,104.88 167.17,104.88 167.17,104.87 165.4,104.87 165.28,105 165.28,105.29 165.16,105.42 164.77,105.42 164.65,105.29 164.65,105 164.53,104.87 163.44,104.87 161.17,102.6 160.88,102.6 158.78,100.5 158.78,99.82 v1(158.36,99.39)
DDR_DQ22: length 37.4
  TOP w0.208: U34.C13 v1(157.56,99.39) ; U25.E3 v1(183.61,110.52)
  L12_SIG4 w0.127: v1(157.56,99.39) 157.16,99 157.16,98.27 157.29,98.14 158.53,98.14 159.45,99.06 161.24,99.06 162.82,100.64 167.32,100.64 168.71,102.03 172.41,102.03 172.76,102.38 172.93,102.38 173.2,102.1 173.38,102.1 173.65,102.37 173.65,102.55 173.38,102.82 173.38,102.99 173.65,103.27 173.82,103.27 174.1,102.99 174.27,102.99 174.54,103.27 174.54,103.44 174.27,103.71 174.27,103.88 174.54,104.16 174.71,104.16 174.99,103.88 175.16,103.88 175.43,104.16 175.43,104.33 175.09,104.67 175.09,104.96 180.47,110.34 181.47,110.34 181.69,110.11 183.27,110.11 183.61,110.46 v1(183.61,110.52)
DDR_DQ23: length 37.5
  TOP w0.208: U34.D13 v1(156.76,99.39) ; U25.E7 v1(183.61,114.52)
  L12_SIG4 w0.127: v1(183.61,114.52) 183.2,114.93 183.2,115.48 182.97,115.71 181.85,115.71 181.62,115.48 181.62,115.18 181.37,114.93 181.07,114.93 180.8,114.67 180.8,114.36 180.09,113.65 177.08,113.65 176.92,113.49 176.48,113.49 171.7,108.71 171.7,107.31 171.26,106.87 164.4,106.87 160.86,103.33 160.51,103.33 158.58,101.4 157.39,101.4 157.16,101.17 157.16,99.8 v1(156.76,99.39)
DDR_DQ24: length 34.9
  TOP w0.208: U33.C2 v1(182.01,96.01) ; U34.D15 v1(156.76,96.99)
  L10_SIG3 w0.127: v1(182.01,96.01) 181.62,95.61 178.7,95.61 177.9,94.82 176.92,94.82 176.8,94.95 176.8,95.13 176.68,95.25 176.29,95.25 176.17,95.13 176.17,94.95 176.05,94.82 175.66,94.82 175.54,94.95 175.54,95.28 175.42,95.41 175.03,95.41 174.91,95.28 174.91,94.95 174.79,94.82 174.4,94.82 174.28,94.95 174.28,95.28 174.16,95.41 173.77,95.41 173.65,95.28 173.65,94.95 173.53,94.82 173.14,94.82 173.02,94.95 173.02,95.28 172.9,95.41 172.51,95.41 172.39,95.28 172.39,94.95 172.27,94.82 171.88,94.82 171.76,94.95 171.76,95.28 171.64,95.41 171.25,95.41 171.13,95.28 171.13,94.95 171.01,94.82 170.62,94.82 170.5,94.95 170.5,95.28 170.38,95.41 169.99,95.41 169.87,95.28 169.87,94.95 169.75,94.82 162.74,94.82 162.32,95.25 160.35,95.25 159.3,94.2 157.39,94.2 157.16,94.43 157.16,96.33 157.15,96.35 157.15,96.35 156.76,96.74 v1(156.76,96.99)
DDR_DQ25: length 35
  TOP w0.208: U34.C15 v1(157.56,96.99) ; U33.B7 v1(181.21,100.81)
  L10_SIG3 w0.127: v1(157.56,96.99) 157.56,97.42 158.1,97.96 159.47,97.96 159.61,98.1 160.97,98.1 162.25,99.39 163.97,99.39 164.1,99.51 164.1,99.83 164.22,99.96 164.6,99.96 164.73,99.83 164.73,99.51 164.85,99.39 165.23,99.39 165.36,99.51 165.36,99.83 165.48,99.96 165.86,99.96 165.99,99.83 165.99,99.51 166.11,99.39 166.49,99.39 166.62,99.51 166.62,99.83 166.74,99.96 167.12,99.96 167.25,99.83 167.25,99.51 167.37,99.39 167.75,99.39 167.88,99.51 167.88,99.83 168,99.96 168.38,99.96 168.51,99.83 168.51,99.51 168.63,99.39 169.48,99.39 170.07,98.79 171.98,98.79 172.1,98.92 172.1,99.27 172.23,99.39 172.61,99.39 172.73,99.27 172.73,98.92 172.86,98.79 173.24,98.79 173.36,98.92 173.36,99.27 173.49,99.39 173.87,99.39 173.99,99.27 173.99,98.92 174.12,98.79 177.72,98.79 178.18,99.25 178.18,100.96 178.3,101.08 179.69,101.08 179.92,100.85 179.92,100.17 180.09,100 181.08,100 181.21,100.13 v1(181.21,100.81)
DDR_DQ26: length 35
  TOP w0.208: U34.E16 v1(155.96,96.19) ; U33.D3 v1(182.81,96.81)
  L10_SIG3 w0.127: v1(155.96,96.19) 155.56,95.8 155.56,94.43 155.79,94.2 156.1,94.2 156.35,93.95 156.35,92.85 156.61,92.58 164.21,92.58 165.72,94.09 179.83,94.09 180.23,94.49 182.64,94.49 183.2,95.04 183.2,96.41 v1(182.81,96.81)
DDR_DQ27: length 35.1
  TOP w0.208: U34.E15 v1(155.96,96.99) ; U33.D7 v1(182.81,100.81)
  L10_SIG3 w0.127: v1(182.81,100.81) 182.4,101.21 182.4,101.77 182.17,102 177.95,102 176.82,100.86 170.08,100.86 169.9,100.69 168.27,100.69 168.14,100.82 168.14,101.14 168.02,101.26 167.63,101.26 167.51,101.14 167.51,100.81 167.39,100.69 167.01,100.69 166.88,100.82 166.88,101.14 166.76,101.26 166.37,101.26 166.25,101.14 166.25,100.81 166.13,100.69 165.75,100.69 165.62,100.82 165.62,101.14 165.5,101.26 165.11,101.26 164.99,101.14 164.99,100.81 164.87,100.69 164.49,100.69 164.36,100.82 164.36,101.14 164.24,101.26 163.85,101.26 163.73,101.14 163.73,100.81 163.61,100.69 162.36,100.69 160.66,98.98 156.59,98.98 156.36,98.75 156.36,98.4 155.96,97.99 v1(155.96,96.99)
DDR_DQ28: length 35
  TOP w0.208: U34.D16 v1(156.76,96.19) ; U33.D2 v1(182.81,96.01)
  L10_SIG3 w0.127: v1(156.76,96.19) 156.35,95.78 156.35,94.45 156.59,94.2 156.9,94.2 157.15,93.95 157.15,93.65 157.39,93.4 158.65,93.4 158.77,93.28 160.69,93.28 160.89,93.48 161.13,93.48 161.25,93.6 161.25,94.3 161.37,94.43 161.76,94.43 161.88,94.3 161.88,93.61 162.01,93.48 162.39,93.48 162.51,93.6 162.51,94.3 162.63,94.43 163.02,94.43 163.14,94.3 163.14,93.61 163.27,93.48 164.37,93.48 164.72,93.83 164.72,94.09 165.09,94.46 178.36,94.46 178.71,94.81 182.2,94.81 182.42,95.02 182.42,95.61 v1(182.81,96.01)
DDR_DQ29: length 35.1
  TOP w0.208: U33.D8 v1(182.81,101.61) ; U34.B16 v1(158.36,96.19)
  L10_SIG3 w0.127: v1(182.81,101.61) 183.22,101.2 183.22,100.64 183.45,100.41 183.45,99.63 183.33,99.51 182.64,99.51 182.52,99.63 182.52,100.24 182.4,100.36 181.72,100.36 181.6,100.24 181.6,99.63 181.48,99.51 179.75,99.51 179.58,99.68 179.58,100.1 179.41,100.27 178.69,100.27 178.57,100.15 178.57,98.89 178.11,98.43 171.94,98.43 171.38,97.87 170,97.87 168.89,98.97 163.83,98.97 163.28,98.43 161.81,98.43 161.12,97.74 159.61,97.74 158.3,97.74 157.96,97.4 157.96,96.83 158.36,96.44 v1(158.36,96.19)
DDR_DQ30: length 35.1
  TOP w0.208: U33.E3 v1(183.61,96.81) ; U34.C16 v1(157.56,96.19)
  L10_SIG3 w0.127: v1(183.61,96.81) 184.01,96.41 184.63,96.41 184.81,96.6 184.81,97.82 184.69,97.94 182.63,97.94 182.4,97.72 182.4,96.64 182.16,96.4 181.07,96.4 180.82,96.64 180.82,97.02 180.53,97.31 179.75,97.31 178.26,95.82 167.17,95.82 166.53,95.19 162.89,95.19 162.45,95.63 160.22,95.63 159.59,95 158.19,95 157.95,95.25 157.95,95.55 157.56,95.94 v1(157.56,96.19)
DDR_DQ31: length 35
  TOP w0.208: U33.E7 v1(183.61,100.81) ; U34.A17 v1(159.16,95.39)
  L10_SIG3 w0.127: v1(183.61,100.81) 184,100.41 184.6,100.41 184.76,100.25 184.76,99.03 184.64,98.91 184.05,98.91 183.93,98.79 183.93,98.5 183.81,98.37 183.52,98.37 183.4,98.5 183.4,98.79 183.28,98.91 182.99,98.91 182.87,98.79 182.87,98.5 182.75,98.37 182.47,98.37 182.34,98.5 182.34,98.79 182.22,98.91 179.11,98.91 178.26,98.06 172.09,98.06 171.53,97.5 169.85,97.5 168.81,98.54 164.41,98.54 163.24,97.37 159.61,97.37 159.47,97.51 159.12,97.51 158.76,97.15 158.76,95.78 v1(159.16,95.39)
DDR_DQ36: length 34.7
  TOP w0.208: U34.B19 v1(158.36,93.79) ; U38.C2 v1(182.01,82.29)
  L12_SIG4 w0.127: v1(158.36,93.79) 159.16,93.79 160.49,92.46 165.85,92.46 167.62,90.69 167.62,89.68 172.35,84.95 172.52,84.95 173.25,85.68 173.43,85.68 173.7,85.41 173.7,85.23 172.97,84.5 172.97,84.33 173.24,84.06 173.42,84.06 174.14,84.79 174.32,84.79 174.59,84.52 174.59,84.34 173.86,83.61 173.86,83.44 174.39,82.91 181.39,82.91 v1(182.01,82.29)
DDR_DQ37: length 34.8
  TOP w0.208: U34.B18 v1(158.36,94.59) ; U38.B7 v1(181.21,87.09)
  L12_SIG4 w0.127: v1(158.36,94.59) 158.76,95 159.41,95 160.13,95.72 161.32,95.72 162.48,94.56 171.86,94.56 172.76,93.66 172.76,93.49 172.32,93.05 172.32,92.88 172.59,92.6 172.77,92.6 173.21,93.04 173.38,93.04 173.65,92.77 173.65,92.6 173.21,92.16 173.21,91.98 173.48,91.71 173.66,91.71 174.1,92.15 174.27,92.15 174.54,91.88 174.54,91.71 174.1,91.27 174.1,91.09 174.38,90.82 174.55,90.82 174.99,91.26 175.16,91.26 176.28,90.15 176.28,87.63 177.68,86.23 180.74,86.23 181.21,86.7 v1(181.21,87.09)
DDR_DQ38: length 34.8
  TOP w0.208: U38.D3 v1(182.81,83.09) ; U34.C18 v1(157.56,94.59)
  L12_SIG4 w0.127: v1(157.56,94.59) 157.8,94.59 158.19,94.2 159.23,94.2 160.28,95.25 161.27,95.25 162.32,94.2 170.73,94.2 171.78,93.14 171.78,89.56 176.5,84.84 182.17,84.84 182.81,84.2 v1(182.81,83.09)
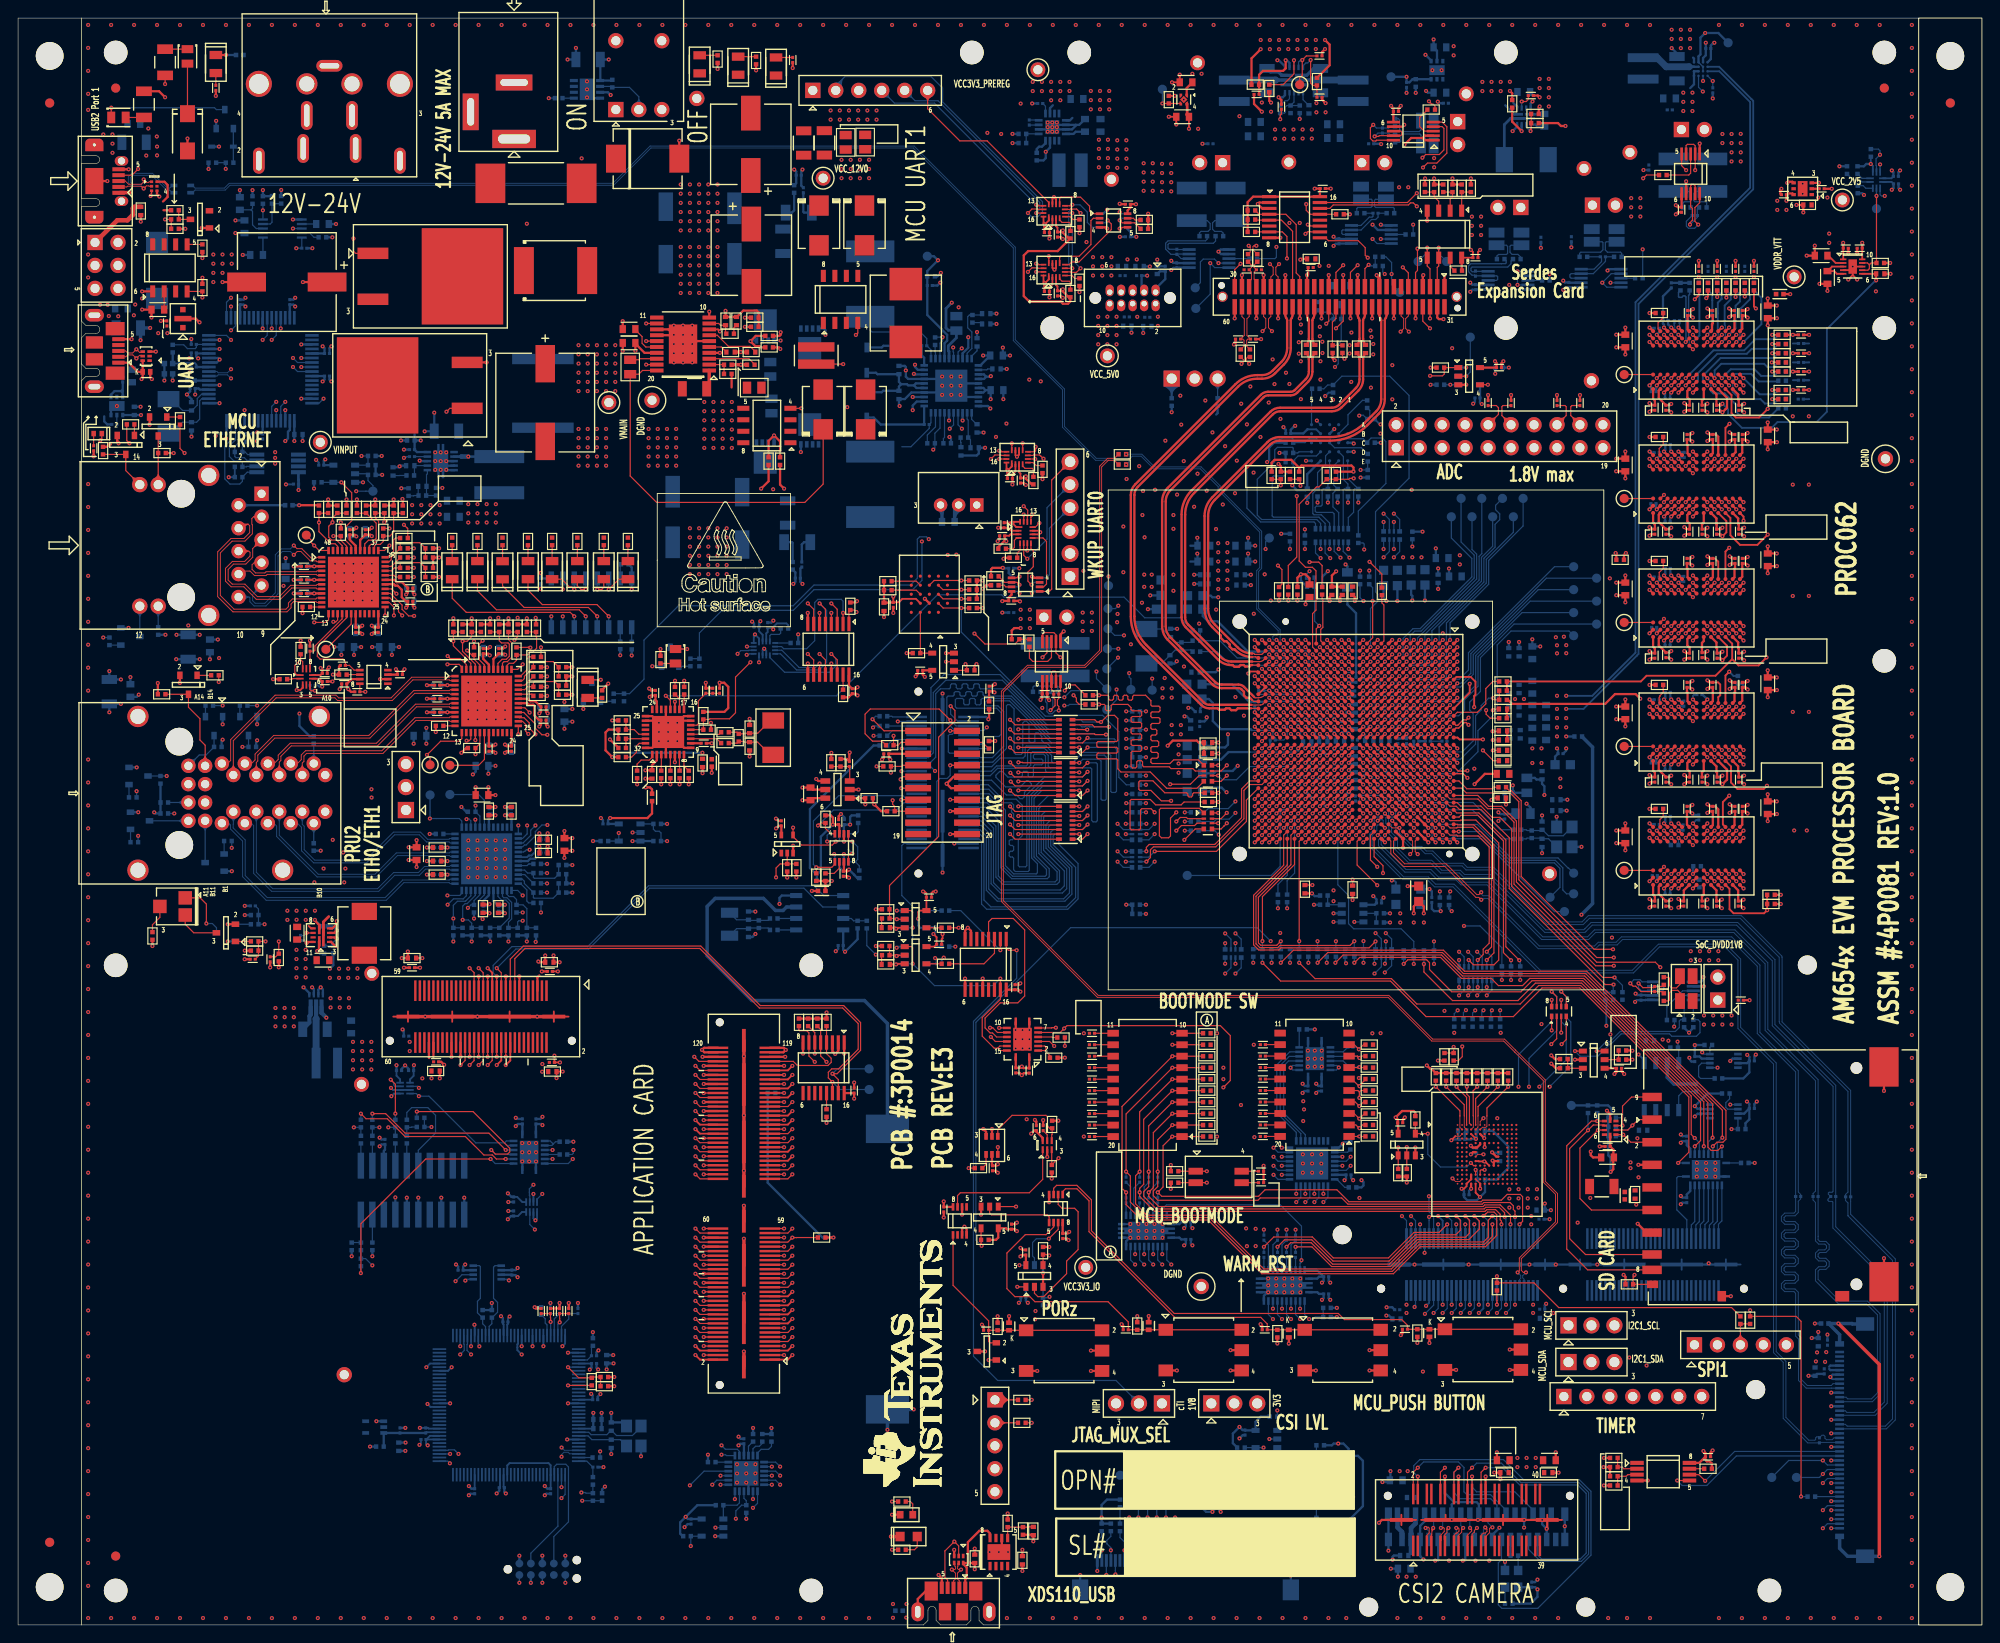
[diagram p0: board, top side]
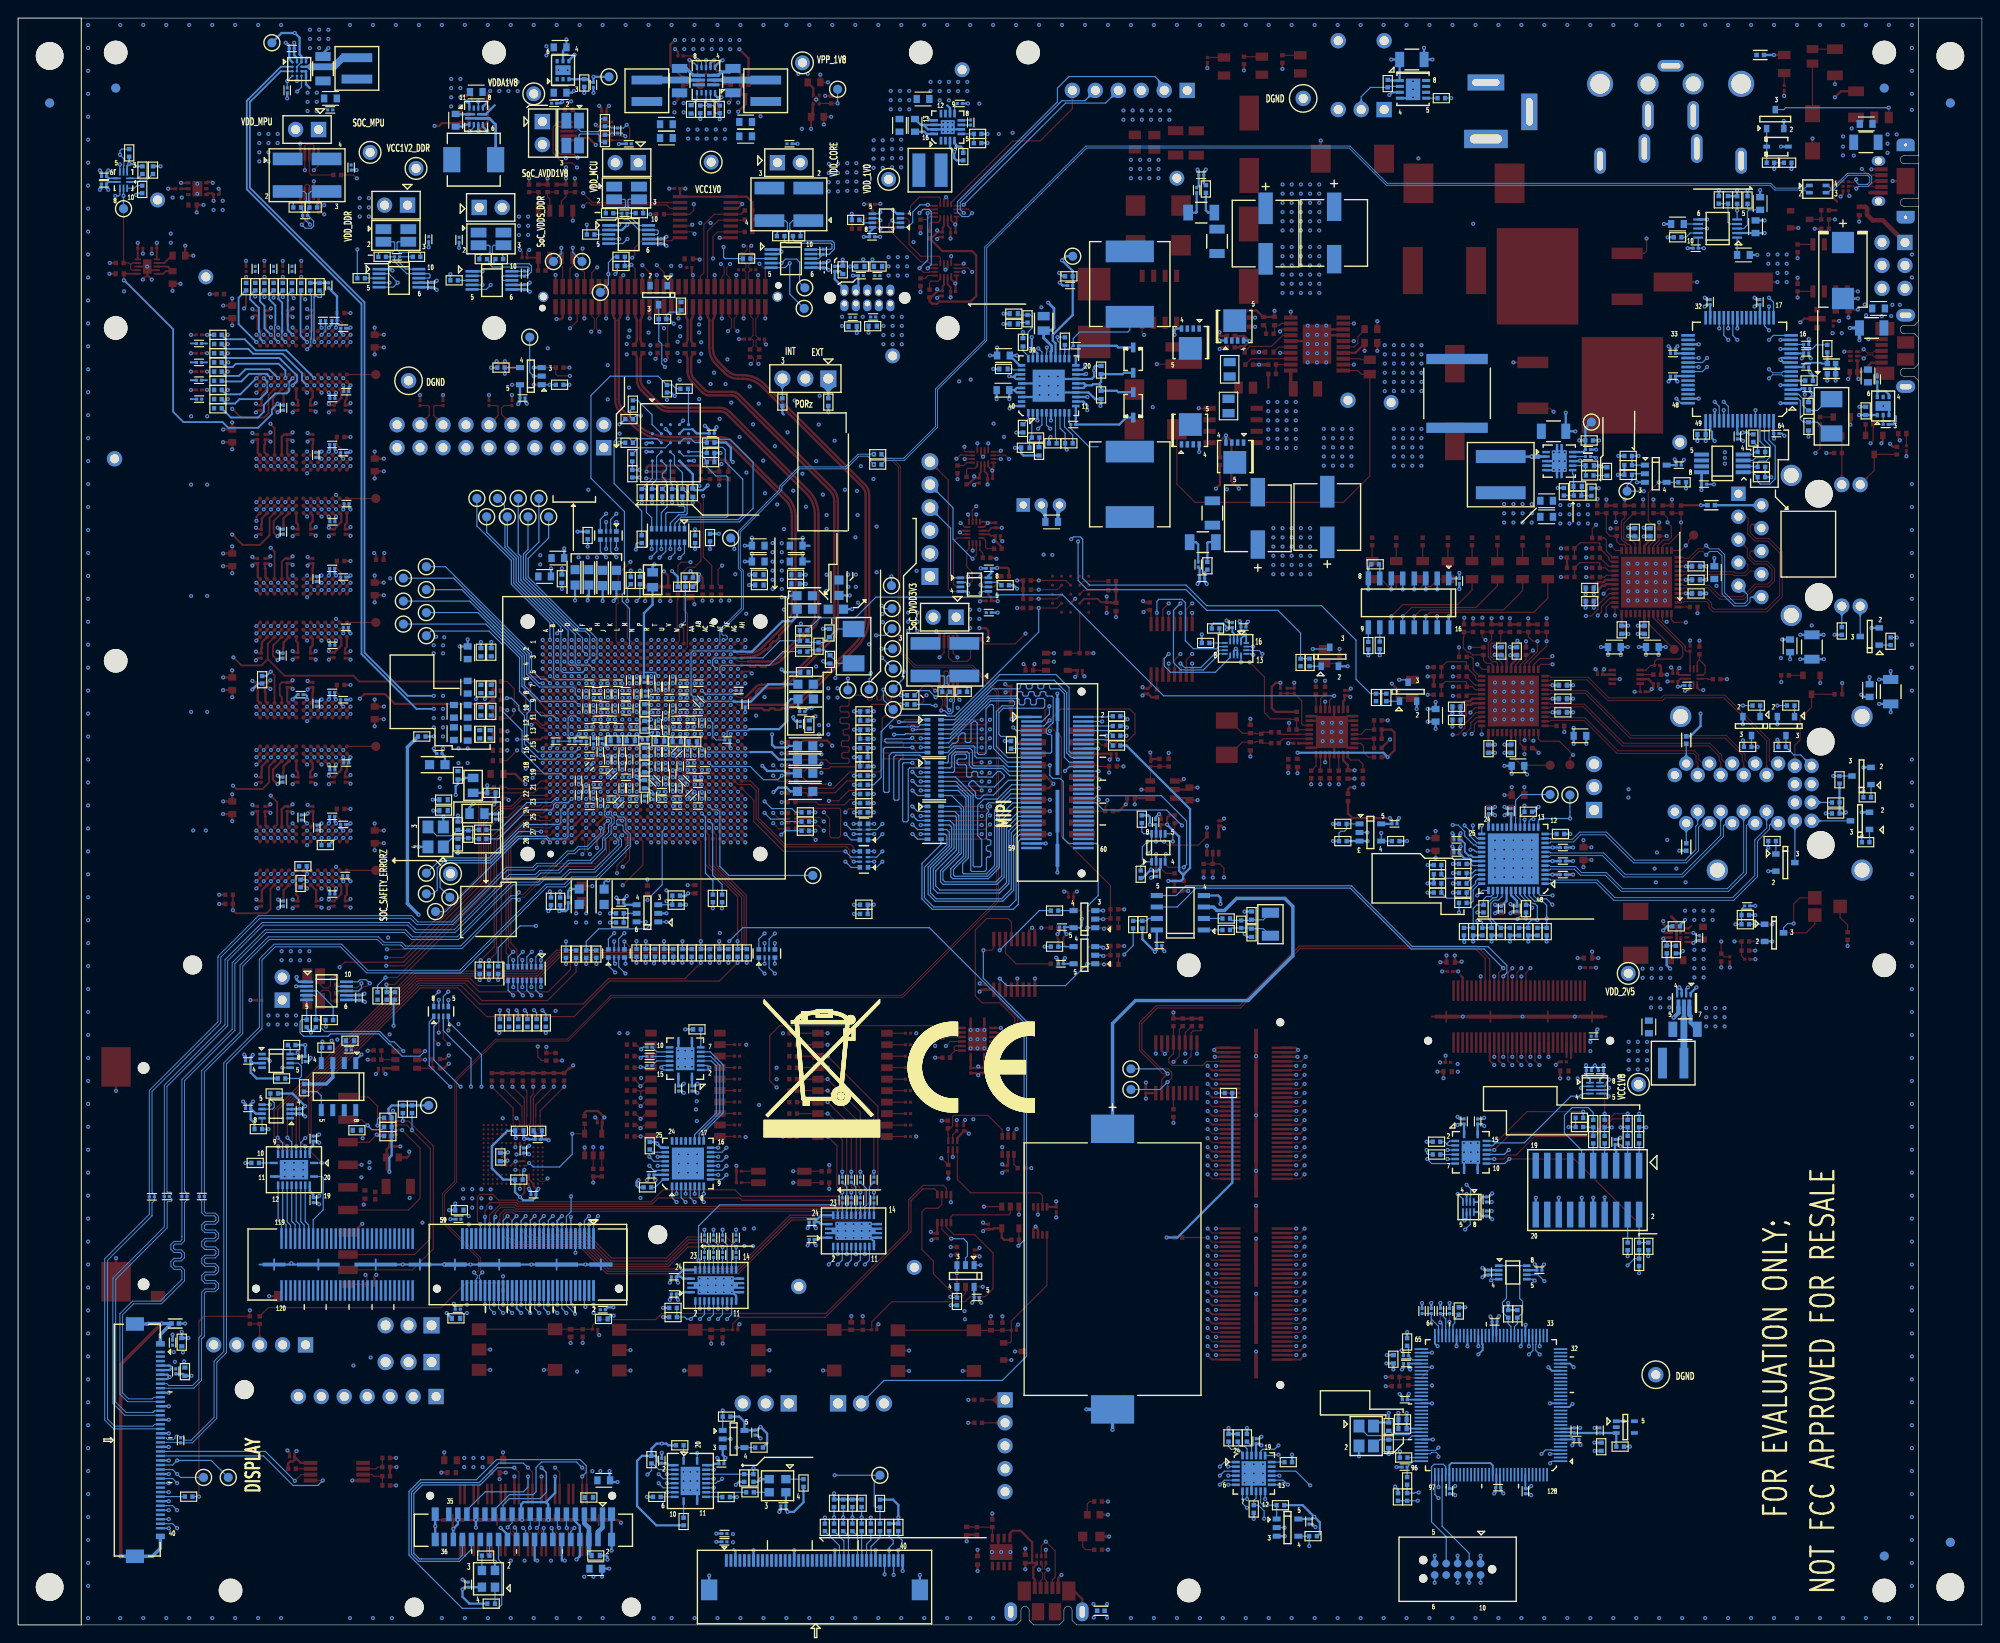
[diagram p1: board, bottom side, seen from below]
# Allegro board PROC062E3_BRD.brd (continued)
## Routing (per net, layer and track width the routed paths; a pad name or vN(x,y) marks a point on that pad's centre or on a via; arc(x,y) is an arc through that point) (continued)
DDR_DQ39: length 34.9
  TOP w0.208: U34.D18 v1(156.76,94.59) ; U38.D7 v1(182.81,87.09)
  L12_SIG4 w0.127: v1(182.81,87.09) 182.42,86.7 181.85,86.7 181.62,86.93 181.62,88.6 181.04,89.17 179.45,89.17 172.68,95.94 164.44,95.94 164.1,96.29 161.79,96.29 161.47,96.6 156.59,96.6 156.36,96.37 156.36,94.98 v1(156.76,94.59)
DDR_DQ40: length 34.8
  TOP w0.208: U34.E18 v1(155.96,94.59) ; U38.D2 v1(182.81,82.29)
  L12_SIG4 w0.127: v1(182.81,82.29) 182.74,82.22 182.74,81.98 182.42,81.65 182.42,81.29 182.22,81.09 174.91,81.09 164.27,91.73 159.63,91.73 158.75,92.6 158.19,92.6 157.96,92.83 157.96,93.13 157.72,93.38 157.41,93.38 157.16,93.63 157.16,93.93 156.9,94.2 156.35,94.2 v1(155.96,94.59)
DDR_DQ41: length 34.7
  TOP w0.208: U38.D8 v1(182.81,87.89) ; U34.E17 v1(155.96,95.39)
  L12_SIG4 w0.127: v1(182.81,87.89) 182.42,88.28 182.42,89 181.72,89.69 179.44,89.69 172.83,96.3 164.6,96.3 163.52,97.38 155.79,97.38 155.56,97.15 155.56,95.78 v1(155.96,95.39)
DDR_DQ42: length 34.8
  TOP w0.208: U34.D17 v1(156.76,95.39) ; U38.E3 v1(183.61,83.09)
  L12_SIG4 w0.127: v1(183.61,83.09) 183.21,82.68 182.65,82.68 182.42,82.45 182.42,82.15 182.17,81.9 174.79,81.9 164.6,92.09 160.12,92.09 158.84,93.38 158.21,93.38 157.96,93.63 157.96,93.95 157.72,94.2 157.39,94.2 157.15,94.45 157.15,95 v1(156.76,95.39)
DDR_DQS0_N: length 52.2
  TOP w0.157: U16.B3 v1(181.21,137.95) ; U34.C1 v1(157.56,108.99)
  L12_SIG4 w0.109: v1(181.21,137.95) 181.47,137.95 181.74,138.22 181.74,138.83 181.62,138.95 180.45,138.95 179.35,137.85 179.35,126.19 176.02,122.86 170.04,122.86 166.67,119.49 166.67,119.32 167.01,118.99 167.01,118.65 166.69,118.34 166.34,118.34 166.01,118.67 165.85,118.67 165.67,118.49 165.67,118.32 166,117.98 166,117.63 165.7,117.34 165.33,117.34 165,117.67 164.85,117.67 164.66,117.48 164.66,117.31 165.02,116.96 165.02,116.62 164.7,116.3 164.36,116.3 163.99,116.66 163.84,116.66 163.65,116.47 163.65,116.31 163.94,116.02 163.94,115.67 163.63,115.35 163.29,115.35 162.99,115.65 162.83,115.65 157.08,109.9 157.08,109.21 157.34,108.95 157.52,108.95 v1(157.56,108.99)
DDR_DQS0_P: length 52.2
  TOP w0.157: U16.C3 v1(182.01,137.95) ; U34.D1 v1(156.76,108.99)
  L12_SIG4 w0.109: v1(156.76,108.99) 156.86,109.09 156.86,109.99 162.74,115.88 163.08,115.88 163.38,115.58 163.54,115.58 163.72,115.76 163.72,115.93 163.43,116.22 163.43,116.57 163.75,116.88 164.09,116.88 164.45,116.52 164.6,116.52 164.8,116.71 164.8,116.86 164.44,117.22 164.44,117.57 164.75,117.89 165.09,117.89 165.42,117.56 165.61,117.56 165.78,117.72 165.78,117.89 165.45,118.23 165.45,118.58 165.76,118.89 166.1,118.89 166.43,118.56 166.6,118.56 166.78,118.74 166.78,118.9 166.45,119.23 166.45,119.58 169.95,123.08 175.93,123.08 179.13,126.28 179.13,137.94 180.36,139.17 181.71,139.17 181.96,138.92 181.96,138.01 v1(182.01,137.95)
DDR_DQS1_N: length 50.2
  TOP w0.157: U20.B3 v1(182.01,125.04) ; U34.A4 v1(159.16,106.59)
  L10_SIG3 w0.109: v1(182.01,125.04) 181.7,124.73 178.73,124.73 167.7,113.7 167.4,113.7 167.12,113.97 167.12,114.16 172.31,119.34 172.31,119.7 171.93,120.08 171.55,120.08 165.73,114.26 165.73,113.84 166.66,112.91 166.66,112.56 160.38,106.29 159.45,106.29 v1(159.16,106.59)
DDR_DQS1_P: length 50.1
  TOP w0.157: U34.A5 v1(159.16,105.79) ; U20.C3 v1(182.01,124.24)
  L10_SIG3 w0.109: v1(159.16,105.79) 159.44,106.07 160.48,106.07 166.88,112.47 166.88,113 165.95,113.93 165.95,114.17 171.64,119.86 171.83,119.86 172.09,119.61 172.09,119.43 166.9,114.25 166.9,113.88 167.31,113.47 167.79,113.47 178.82,124.51 181.74,124.51 v1(182.01,124.24)
DDR_DQS2_N: length 37.5
  TOP w0.157: U25.B3 v1(182.01,111.32) ; v1(160.4,100.39) 160.15,100.14 159.8,100.14 159.19,99.54 159.01,99.54 U34.A12
  L12_SIG4 w0.109: v1(182.01,111.32) 181.73,111.04 179.55,111.04 179.04,110.53 178.79,110.53 178.24,111.08 177.8,111.08 177.49,110.76 177.49,110.33 178.04,109.78 178.04,109.52 177.86,109.34 177.6,109.34 177.05,109.89 176.62,109.89 176.31,109.58 176.31,109.14 176.85,108.59 176.85,108.34 176.67,108.16 176.42,108.16 175.87,108.7 175.43,108.7 175.12,108.39 175.12,107.96 175.67,107.41 175.67,107.15 175.49,106.97 175.23,106.97 174.68,107.52 174.24,107.52 173.93,107.21 173.93,106.77 174.48,106.22 174.48,105.97 172.42,103.9 169.39,103.9 167.5,102.01 162.02,102.01 161.54,101.53 161.54,100.57 161.05,100.08 160.72,100.08 v1(160.4,100.39)
DDR_DQS2_P: length 37.4
  TOP w0.157: v1(160.4,99.59) 160.15,99.85 159.92,99.85 159.31,99.24 159.01,99.24 U34.A13 ; U25.C3 v1(182.01,110.52)
  L12_SIG4 w0.109: v1(160.4,99.59) 160.66,99.86 161.15,99.86 161.76,100.47 161.76,101.44 162.12,101.79 167.59,101.79 169.48,103.68 172.51,103.68 174.7,105.87 174.7,106.31 174.16,106.86 174.16,107.12 174.34,107.3 174.59,107.3 175.14,106.75 175.58,106.75 175.89,107.06 175.89,107.5 175.34,108.05 175.34,108.3 175.52,108.48 175.78,108.48 176.33,107.94 176.76,107.94 177.07,108.25 177.07,108.68 176.53,109.23 176.53,109.49 176.71,109.67 176.96,109.67 177.51,109.12 177.95,109.12 178.26,109.43 178.26,109.87 177.71,110.42 177.71,110.67 177.89,110.85 178.15,110.85 178.7,110.31 179.14,110.31 179.64,110.82 181.72,110.82 v1(182.01,110.52)
DDR_DQS3_N: length 35
  TOP w0.157: U33.B3 v1(181.21,96.81) ; U34.A16 v1(159.16,96.19)
  L10_SIG3 w0.109: v1(181.21,96.81) 181.58,97.17 181.58,98.09 181.38,98.29 179.99,98.29 177.99,96.29 176.7,96.29 176.41,96.58 176.41,97.04 176.3,97.15 175.91,97.15 175.79,97.03 175.79,96.55 175.53,96.29 174.98,96.29 174.72,96.55 174.72,97.03 174.6,97.14 174.21,97.14 174.09,97.02 174.09,96.55 173.83,96.29 173.28,96.29 173.02,96.55 173.02,97.02 172.9,97.14 172.52,97.14 172.41,97.03 172.41,96.54 172.16,96.3 172.15,96.3 172.15,96.29 167.02,96.29 166.77,96.54 166.77,97.58 166.65,97.71 166.35,97.71 166.24,97.6 166.24,96.57 165.96,96.29 165.24,96.29 164.92,96.61 164.92,97.49 164.77,97.64 164.46,97.64 164.27,97.45 164.27,96.42 163.96,96.11 160.34,96.11 159.78,96.67 159.37,96.67 159.16,96.46 v1(159.16,96.19)
DDR_DQS3_P: length 35
  TOP w0.157: U33.C3 v1(182.01,96.81) ; U34.A15 v1(159.16,96.99)
  L10_SIG3 w0.109: v1(159.16,96.99) 159.26,96.89 159.87,96.89 160.43,96.33 163.87,96.33 164.05,96.51 164.05,97.54 164.37,97.86 164.86,97.86 165.14,97.58 165.14,96.7 165.33,96.51 165.87,96.51 166.02,96.66 166.02,97.69 166.26,97.93 166.74,97.93 166.99,97.67 166.99,96.63 167.11,96.52 172.06,96.52 172.06,96.52 172.07,96.52 172.19,96.64 172.19,97.12 172.42,97.36 173,97.36 173.24,97.11 173.24,96.64 173.37,96.51 173.74,96.51 173.87,96.64 173.87,97.11 174.12,97.36 174.7,97.36 174.94,97.12 174.94,96.64 175.07,96.51 175.44,96.51 175.57,96.64 175.57,97.12 175.82,97.37 176.39,97.37 176.63,97.13 176.63,96.67 176.79,96.51 177.9,96.51 179.9,98.51 181.47,98.51 181.8,98.18 181.8,97.02 v1(182.01,96.81)
DDR_DQS_N: length 34.8
  TOP w0.157: v1(182.01,83.89) 182.01,83.89 U38.B3 ; v1(160.27,94.53) 160.23,94.48 159.26,94.48 U34.A18
  L12_SIG4 w0.109: v1(182.01,83.89) 181.72,83.6 177.05,83.6 173.22,87.43 172.78,87.43 172.11,86.76 171.85,86.76 171.67,86.94 171.67,87.2 172.35,87.87 172.35,88.31 172.04,88.62 171.6,88.62 170.93,87.95 170.67,87.95 170.49,88.13 170.49,88.38 171.16,89.05 171.16,89.49 169.96,90.69 169.96,93.15 169.38,93.74 162.05,93.74 161.57,94.22 160.58,94.22 v1(160.27,94.53)
DDR_DQS_P: length 34.7
  TOP w0.157: v1(160.27,93.73) 159.81,94.19 U34.A19 ; U38.C3 v1(182.01,83.09)
  L12_SIG4 w0.109: v1(160.27,93.73) 160.55,94 161.48,94 161.96,93.52 169.29,93.52 169.74,93.06 169.74,90.6 170.94,89.4 170.94,89.15 170.27,88.48 170.27,88.04 170.58,87.73 171.02,87.73 171.69,88.4 171.94,88.4 172.12,88.21 172.12,87.96 171.45,87.29 171.45,86.85 171.76,86.54 172.2,86.54 172.87,87.21 173.13,87.21 176.96,83.38 181.73,83.38 v1(182.01,83.09)
DDR_ODT: length 149.7
  TOP w0.208: U34.B11 v1(158.36,100.99) ; U25.F3 v1(184.41,110.52) ; U38.F3 v1(184.41,83.09) ; U16.F3 v1(184.41,137.95) ; U20.F3 v1(184.41,124.24) ; U33.F3 v1(184.41,96.81)
  L05_SIG2 w0.127: v1(184.41,137.95) 184.41,137.72 184.8,137.33 184.8,136.24 184.2,135.63 183.51,135.63 183.26,135.38 183.26,134.18 183.38,134.05 183.75,134.05 184.01,133.8 184.01,133.41 183.81,133.21 183.32,133.21 183.2,133.09 183.2,126.03 184.41,124.82 v1(184.41,124.24) 184.41,124.01 184.8,123.62 184.8,122.52 184.2,121.92 183.51,121.92 183.26,121.67 183.26,120.46 183.38,120.34 183.75,120.34 184.01,120.08 184.01,119.69 183.81,119.49 183.32,119.49 183.2,119.37 183.2,112.31 184.41,111.1 v1(184.41,110.52) 184.41,110.29 184.8,109.9 184.8,108.81 184.2,108.2 183.51,108.2 183.26,107.95 183.26,106.74 183.38,106.62 183.75,106.62 184,106.37 184,105.97 183.81,105.78 183.32,105.78 183.2,105.65 183.2,98.61 184.41,97.4 v1(184.41,96.81) 184.41,96.58 184.8,96.19 184.8,95.09 184.2,94.49 183.5,94.49 183.26,94.25 183.26,93.03 183.38,92.91 183.75,92.91 184.02,92.64 184.02,92.27 183.81,92.06 183.32,92.06 183.2,91.94 183.2,84.89 184.41,83.69 v1(184.41,83.09) 184.41,82.92 184.8,82.53 184.8,80.24 184.38,79.82 180.27,79.82 179.52,80.56 179.52,99.99 173.66,105.85 169.74,105.85 167.47,108.12 163.46,108.12 163.13,108.46 162.44,108.46 162.11,108.12 160.96,108.12 159.81,106.98 154.99,106.98 154.76,106.76 154.76,104.36 154.76,104.35 154.76,104.03 154.99,103.8 155.31,103.8 155.55,103.55 155.55,100.83 155.78,100.6 156.1,100.6 156.35,100.35 156.35,100.05 156.59,99.8 157.72,99.8 157.95,100.03 157.95,100.58 v1(158.36,100.99)
  BOTTOM w0.208: R377.1 194.65,142.73 194.2,142.28 194.19,142.28 194.18,142.27 192.11,142.27 190.88,141.03 187.49,141.03 v1(184.41,137.95)
DDR_ODT1: length 151.5
  TOP w0.208: R56.1 v1(193.98,142.75) ; U33.F2 v1(184.41,96.01) ; U25.F2 v1(184.41,109.72) ; U16.F2 v1(184.41,137.15) ; U20.F2 v1(184.41,123.44) ; U38.F2 v1(184.41,82.29) ; U34.E12 v1(155.96,100.19)
  L05_SIG2 w0.127: v1(193.98,142.75) 192.71,141.48 186.82,141.48 184.02,138.68 184.02,137.55 v1(184.41,137.15) 184.41,136.48 183.9,135.96 182.46,135.96 182,135.51 182,134.36 182.42,133.94 182.42,126.06 184.01,124.47 184.01,123.84 v1(184.41,123.44) 184.41,122.76 183.9,122.25 182.46,122.25 182,121.79 182,120.64 182.42,120.22 182.42,112.35 184.01,110.76 184.01,110.12 v1(184.41,109.72) 184.41,109.05 183.9,108.53 182.43,108.53 182.02,108.11 182.02,106.88 182.42,106.48 182.42,98.63 184.01,97.04 184.01,96.41 v1(184.41,96.01) 184.41,95.33 183.9,94.81 182.36,94.81 182.05,94.51 182.05,93.16 182.42,92.79 182.42,84.92 184.01,83.33 184.01,82.69 v1(184.41,82.29) 184.41,81.24 184.01,80.84 180.89,80.84 179.9,81.83 179.9,101.28 178.82,102.36 178.82,103.76 178.56,104.01 178.56,104.9 178.82,105.16 178.82,105.92 178.31,106.43 169.93,106.43 169.16,107.19 169.16,109.22 168.78,109.6 161.8,109.6 160,107.8 155.01,107.8 154.76,107.55 154.76,107.25 154.52,107 154.21,107 153.96,106.75 153.96,104.36 153.96,104.35 153.96,103.98 154.14,103.8 154.62,103.8 154.75,103.67 154.75,100.77 154.94,100.58 155.32,100.58 155.7,100.2 155.94,100.2 v1(155.96,100.19)
DDR_PARITY: length 142.2
  TOP w0.208: U25.N3 v1(190.81,110.52) ; U16.N3 v1(190.81,137.95) ; U34.B10 v1(158.36,101.79) ; U33.N3 v1(190.81,96.81) ; U38.N3 v1(190.81,83.09) ; U20.N3 v1(190.81,124.24)
  L05_SIG2 w0.127: v1(158.36,101.79) 159.12,101.03 161.29,101.03 162.06,101.8 164.78,101.8 164.91,101.68 164.91,100.66 165.03,100.54 167.59,100.54 167.71,100.66 167.71,101.05 167.59,101.17 165.66,101.17 165.54,101.29 165.54,101.68 165.66,101.8 167.84,101.8 169.3,100.34 169.3,86.23 171.67,83.86 171.67,81.27 177.66,75.27 177.88,75.06 188.41,75.06 191.75,78.4 191.75,82.15 v1(190.81,83.09) 192.3,83.09 192.47,83.26 192.47,96.19 192.26,96.39 191.23,96.39 v1(190.81,96.81) 192.29,96.81 192.47,96.98 192.47,109.9 192.26,110.11 191.23,110.11 v1(190.81,110.52) 192.28,110.52 192.47,110.71 192.47,123.62 192.26,123.82 191.23,123.82 v1(190.81,124.24) 192.28,124.24 192.47,124.42 192.47,137.33 192.26,137.54 191.23,137.54 v1(190.81,137.95)
  BOTTOM w0.208: R391.1 194.65,136.64 194.2,136.18 194.19,136.18 194.18,136.17 192.6,136.17 v1(190.81,137.95)
DDR_RESET#: length 127.7
  TOP w0.208: R219.2 R220.1 v1(193.42,79.09) 193.08,78.75 189.71,78.75 189.25,79.2 189.25,81.45 U38.L1 ; U33.L1 189.42,94.99 189.42,93.21 190.15,92.49 193.03,92.49 v1(193.4,92.86) ; R171.1 R165.1 179.45,104.39 180.09,105.03 187.71,105.03 189.55,106.87 ; 189.55,106.87 189.55,108.58 U25.L1 ; 189.55,106.87 190.25,106.17 192.47,106.17 v1(193.36,107.06) ; U16.L1 189.48,136.09 189.48,134.08 189.96,133.6 192.53,133.6 v1(193.48,134.56) ; v1(193.48,120.65) 192.34,119.51 190.42,119.51 189.36,120.57 189.36,122.49 U20.L1
  L03_SIG1 w0.127: v1(193.42,79.09) 193.42,81.55 195.14,83.26 195.14,91.12 v1(193.4,92.86) 195.71,95.17 195.71,104.71 v1(193.36,107.06) 195.45,109.16 195.45,118.68 v1(193.48,120.65) 195.39,122.56 195.39,132.65 v1(193.48,134.56)
DDR_RESET_FS: length 15.4
  TOP w0.132: R171.2 R182.1 163.31,102.36 v1(163.12,102.55) ; U34.F16 v1(155.16,96.19)
  BOTTOM w0.122: v1(155.16,96.19) 155.55,95.8 159.52,95.8 159.77,96.05
  BOTTOM w0.132: 159.77,96.05 161.17,97.46 161.17,100.61 161.8,101.24 161.8,101.73 162.62,102.55 v1(163.12,102.55)
DDR_TEN: length 65.2
  TOP w0.208: U38.G9 v1(185.21,88.69) ; U20.G9 v1(185.21,129.84) ; U16.G9 v1(185.21,143.55) ; U33.G9 v1(185.21,102.41) ; U25.G9 v1(185.21,116.12)
  L12_SIG4 w0.127: v1(185.21,143.55) 185.99,142.77 185.99,130.62 v1(185.21,129.84) 185.91,129.14 185.91,127.42 188.81,124.52 188.81,122.89 189.02,122.68 189.02,119.86 188.41,119.25 188.41,117.83 187.4,116.82 185.91,116.82 v1(185.21,116.12) 186.06,115.28 186.06,108.46 185.67,108.08 185.67,102.87 v1(185.21,102.41) 185.74,101.88 185.74,89.22 v1(185.21,88.69)
  BOTTOM w0.203: v1(185.21,88.69) 185.59,89.06 R503.1
  BOTTOM w0.208: v1(185.21,102.41) 185.21,102.79 185.36,102.93 R462.2
DDR_VPP: length 35.7
  TOP w0.254: U38.M9 189.81,88.49 189.81,89.45 189.87,89.51 C184.1 189.44,90.02 v1(189.27,89.85) ; v1(193.48,130.09) C85.1 v1(194.5,130.87) ; v1(189.21,144.72) 189.38,144.88 C46.1 189.81,143.35 U16.M9 ; v1(194.5,89.72) C181.1 v1(193.48,88.94) ; U33.M9 189.81,102.2 189.81,103.16 189.87,103.23 C141.1 189.44,103.73 v1(189.27,103.57) ; v1(189.27,117.28) 189.44,117.45 C107.1 189.87,116.94 189.81,116.88 189.81,115.92 U25.M9 ; v1(189.26,130.94) 189.49,131.17 C88.1 189.86,130.66 189.93,130.58 189.93,129.76 U20.M9 ; U38.B1 181.43,81.71 181.43,80.89 182.21,80.11 C203.1 182.65,80.1 v1(182.81,80.26) ; v1(182.81,93.98) 182.65,93.82 C173.1 182.21,93.83 181.43,94.61 181.43,95.43 U33.B1 ; U25.B1 181.43,109.14 181.43,108.39 182.21,107.61 C127.1 182.65,107.59 v1(182.81,107.76) ; U16.B1 181.43,136.57 181.43,135.75 182.21,134.98 C79.1 182.64,134.96 182.78,135.1 v1(182.81,135.1) ; v1(193.48,146.78) C43.1 v1(194.49,145.99) ; v1(193.48,102.65) C137.1 v1(194.5,103.44) ; v1(194.5,117.16) C104.1 v1(193.48,116.37) ; U20.B1 181.43,122.86 181.43,122.04 182.21,121.26 C96.1 182.65,121.25 v1(182.81,121.41)
DDR_VREFCA: length 121.8
  TOP w0.203: v1(205.47,148.78) C37.1 U10.6
  TOP w0.254: v1(177.8,118.61) 177.58,118.39 R728.1 ; U25.J1 187.81,108.72 187.81,108.1 187.88,108.04 C131.1 188.31,107.53 v1(188.47,107.7) ; U20.J1 187.81,122.43 187.81,121.77 187.83,121.76 C99.1 188.31,121.25 v1(188.47,121.41) ; v1(188.47,93.98) 188.31,93.82 C176.1 187.88,94.32 187.81,94.39 187.81,95 U33.J1 ; v1(188.41,80.26) 188.41,80.26 188.24,80.1 C206.1 187.81,81.29 U38.J1 ; v1(188.47,135.13) 188.31,134.96 C82.1 187.81,136.15 U16.J1
  L10_SIG3 w0.122: 188.02,115.76 188.02,113.92 ; 188.82,129.37 188.82,123.01 ; 188.02,110.97 188.02,109.44
  L10_SIG3 w0.203: 188.02,115.76 188.02,118.84 188.94,119.76 188.94,120.95 v1(188.47,121.41) 188.82,121.76 188.82,123.01 ; 188.02,113.92 188.02,110.97 ; 188.02,109.44 188.02,108.15 v1(188.47,107.7) ; v1(188.47,135.13) 188.94,134.66 188.94,133.57 188.82,133.45 188.82,129.37
  L12_SIG4 w0.122: 187.22,81.57 187.22,88.25
  L12_SIG4 w0.203: 187.22,81.57 187.22,81.46 v1(188.41,80.26) ; v1(188.47,107.7) 186.23,105.45 186.23,95.67 187.6,94.3 188.15,94.3 v1(188.47,93.98) 187.5,93.01 187.5,88.53 187.22,88.25
  L12_SIG4 w0.254: v1(188.47,121.41) 186.47,119.41 178.6,119.41 v1(177.8,118.61)
  BOTTOM w0.203: v1(205.47,148.78) 205.42,148.78 200.03,143.38 200.03,134.24 198.88,133.1 194.56,133.1 193.93,132.46 190.63,132.46 189.1,133.99 189.1,134.5 v1(188.47,135.13)
  BOTTOM w0.254: C206.1 188.24,80.1 188.41,80.26 v1(188.41,80.26) ; v1(188.47,121.41) 188.31,121.25 C99.1 ; v1(188.47,107.7) 188.31,107.53 C131.1 ; v1(188.47,135.13) 188.41,135.13 188.25,134.96 C82.1 ; C176.1 188.31,93.82 v1(188.47,93.98)
DDR_VTT_EN: length 102
  TOP w0.132: U34.P3 v1(148.76,107.39)
  L10_SIG3 w0.084: v1(154.11,125.6) 167.48,125.6 171.58,129.7 171.58,142.39 180.85,151.66 184.23,151.66 187.18,154.62 201.1,154.62 205.29,158.81 205.29,162.06 v1(205.9,162.67)
  L12_SIG4 w0.084: v1(148.76,107.39) 148.37,107.78 148.37,109.25 152.08,112.97 152.08,115.89 151.41,116.56 151.41,119.79 153.57,121.95 153.57,125.06 v1(154.11,125.6)
  BOTTOM w0.132: U109.4 205.51,161.45 205.46,161.5 205.46,162.24 v1(205.9,162.67) 205.9,163.12 205.72,163.3 R707.1
DDR_VTT_EN_3V3: length 12.7
  TOP w0.132: 204.72,150.5 204.72,150.07 204.56,149.9 U10.7 ; 204.72,150.5 204.93,150.7 R41.1 v1(205.51,158.13) ; 204.72,150.5 204.51,150.7 U10.9
  BOTTOM w0.132: U109.9 v1(205.51,158.13) TP84.1
DEBOUNCE_WARM_RST: length 39.2
  TOP w0.132: U52.6 114.52,44.03 113.67,43.18 111.38,43.18 109.35,41.15 109.35,37.21 110.24,36.32 111.89,36.32 112.44,35.76 114.51,35.76 114.54,35.76 114.56,35.76 120.53,35.76 122.77,33.53 C242.1 R321.1 D13.1 SW7.1 SW7.2
DEBOUNCE_WKUP_GPIO0_13: length 61.3
  TOP w0.132: SW5.2 SW5.1 D12.1 R320.1 C240.1 153.65,33.15 153.02,33.78 146.68,33.78 146,34.46 127.85,34.46 118.69,43.62 118.69,47.04 117.09,48.64 114.85,48.64 114.52,48.31 U52.3
DEBOUNCE_WKUP_GPIO0_27: length 44.5
  TOP w0.132: SW6.2 SW6.1 D10.1 R318.1 C241.1 138.14,33.31 137.41,34.04 127.9,34.04 118.43,43.51 118.43,46.93 117.09,48.26 115.82,48.26 115.52,47.95 U52.1
DIR: length 68.9
  L05_SIG2 w0.084: v1(142.77,33.85) 142.77,39.1 141.99,39.88 v1(127.53,39.88)
  L12_SIG4 w0.084: v1(140.72,61.66) 140.72,61.2 140.46,60.94 140.46,49.51 139.4,48.45 137.1,48.45 135.03,46.38 135.03,41.64 135.85,40.82 142.06,40.82 143.37,39.51 143.37,34.45 v1(142.77,33.85)
  BOTTOM w0.132: U102.2 127.03,40.38 v1(127.53,39.88) ; U95.2 140.97,61.41 v1(140.72,61.66) 140.97,61.91 U95.3 ; U105.2 142.27,34.35 v1(142.77,33.85) 143.21,33.85 143.43,34.06 R656.1 R648.2
ECAP0_IN_APWM0_OUT: length 117.2
  TOP w0.132: U34.D21 v1(156.76,92.19)
  L10_SIG3 w0.084: v1(156.76,92.19) 157.15,91.8 158.14,91.8 163.33,86.6 163.33,84.82 167.36,80.8 173.43,80.8 180.71,73.51 180.71,42.87 184.09,39.5 193.29,39.5 203.84,28.95 203.84,11.49 202.44,10.1 200.34,10.1 200.09,10.35 200.09,11.28 v1(200.51,11.7)
  BOTTOM w0.132: J38.38 v1(200.51,11.7)
EEPROM_A1: length 3.2
  TOP w0.132: U56.2 177.58,17.28 177.4,17.46 R328.2 R327.2
EEPROM_A2: length 3.2
  TOP w0.132: U56.3 178.01,16.63 177.83,16.45 R330.2 R331.2
EEPROM_WP: length 1.6
  TOP w0.132: U56.7 R329.2
EMMC_RSTN: length 10.9
  TOP w0.132: v1(155.89,54.36) U48.4 R288.1 ; v1(160.66,51.12) 160.95,50.82 U51.K5
  BOTTOM w0.132: v1(155.89,54.36) 155.89,52.07 157.29,50.67 160.21,50.67 v1(160.66,51.12)
EXP_BRD_DET_INTN: length 1.8
  TOP w0.132: U46.13 R283.1
EXP_PCIE_DET_INTN: length 80.7
  TOP w0.132: v1(142.45,157.22) 142.45,156.54 142.89,156.09 U7.13 R27.1 ; U34.T1 v1(146.36,108.99)
  L12_SIG4 w0.084: v1(142.45,157.22) 142.88,156.78 144.64,156.78 144.67,156.76 144.75,156.76 147.28,154.23 154.57,154.23 154.82,154.48 156.67,154.48 161.58,149.57 161.58,149.3 161.89,148.99 161.89,146.38 160.78,145.27 160.78,137.15 158.99,135.36 152.53,135.36 149.78,132.61 149.78,123.94 145.63,119.79 145.63,117.57 145.25,117.18 145.25,116.29 144.63,115.67 144.63,113.13 145.16,112.59 145.16,108.83 145.39,108.6 145.96,108.6 v1(146.36,108.99)
FB: length 10.1
  TOP w0.203: v1(77.61,143.13) 77.39,143.36 U14.8
  TOP w0.254: v1(78.23,145.41) C48.2 C49.2 79.49,144.73 80.2,145.44 81.69,145.44 81.89,145.24 R53.1 R54.2
  L03_SIG1 w0.203: v1(77.61,143.13) 78.23,143.75 v1(78.23,145.41)
FT4232_DO: length 3
  BOTTOM w0.132: U79.4 25.38,129.5 25.09,129.79 R407.2 24.8,130.44 25.26,130.9 R408.1
FT4232_EECLK: length 8
  BOTTOM w0.132: U73.62 24.05,131.13 23.37,130.45 23.37,129.29 23.88,128.78 24.62,128.78 24.8,128.59 R413.1 25.24,128.14 25.29,128.2 U79.2
FT4232_EECS: length 11.3
  BOTTOM w0.132: U79.1 25.34,127.55 24.8,127.01 R416.1 24.8,126.53 24.51,126.24 23.43,126.24 22.86,126.81 22.86,130.43 23.55,131.12 U73.63
FT4232_EEDATA: length 6.8
  BOTTOM w0.132: U79.3 25.33,128.85 25.02,129.16 24.09,129.16 23.96,129.29 R407.1 23.96,130.39 24.55,130.97 U73.61
FT4232_MCU_UART1_CTS_3V3: length 114.2
  TOP w0.132: U12.12 v1(113.98,151.45)
  L05_SIG2 w0.084: v1(28.05,142.19) 30.31,142.19 30.97,142.85 45.37,142.85 61.34,126.87 101.27,126.87 105.84,131.44 107.19,131.44 111.01,135.27 111.01,145.1 113.98,148.07 v1(113.98,151.45)
  BOTTOM w0.132: v1(28.05,142.19) 28.55,142.69 U73.28
FT4232_MCU_UART1_RTS_3V3: length 109.1
  TOP w0.132: U12.14 112.81,150.11 112.76,150.16 112.12,150.16 v1(111.67,149.71)
  L05_SIG2 w0.084: v1(29.05,143.46) 45.65,143.46 61.6,127.5 101.04,127.5 106.18,132.65 107.45,132.65 110.4,135.6 110.4,145.73 111.67,147 v1(111.67,149.71)
  BOTTOM w0.132: U73.29 v1(29.05,143.46)
FT4232_MCU_UART1_RX_3V3: length 114
  TOP w0.132: U12.13 112.7,150.51 v1(112.59,150.63)
  L05_SIG2 w0.084: v1(27.05,142.19) 27.5,142.65 30.33,142.65 30.84,143.15 45.49,143.15 61.47,127.18 101.14,127.18 106.31,132.34 107.58,132.34 110.71,135.47 110.71,145.61 113.12,148.02 113.12,150.09 v1(112.59,150.63)
  BOTTOM w0.132: U73.26 27.55,142.69 v1(27.05,142.19)
FT4232_MCU_UART1_TX_3V3: length 110.5
  TOP w0.132: U12.15 v1(112.59,149.71)
  L05_SIG2 w0.084: v1(112.59,149.71) 112.13,150.17 111.48,150.17 111.25,149.94 111.25,147.01 110.1,145.86 110.1,135.72 107.33,132.95 106.06,132.95 100.91,127.81 61.73,127.81 45.62,143.91 28.5,143.91 v1(28.05,143.46)
  BOTTOM w0.132: U73.27 v1(28.05,143.46)
FT4232_REF: length 1.6
  BOTTOM w0.254: R388.2 U73.6
FT4232_RESET: length 4.6
  BOTTOM w0.132: U73.14 C319.2 19.71,141.36 19.58,141.22 18.73,141.22 18.31,141.64 R381.1
FT4232_UART0_CTS_3V3: length 101
  TOP w0.132: U19.12 v1(109.89,130.75)
  L05_SIG2 w0.084: v1(109.89,130.75) 108.27,130.75 104.09,126.57 87.07,126.57 85.33,124.83 62.94,124.83 45.23,142.54 31.09,142.54 30.27,141.72 26.35,141.72 23.55,144.52 v1(23.55,145.88)
  BOTTOM w0.132: U73.18 v1(23.55,145.88)
FT4232_UART0_RTS_3V3: length 97.9
  TOP w0.132: U19.14 108.72,129.41 108.67,129.46 108.03,129.46 v1(107.58,129.01)
  L05_SIG2 w0.084: v1(107.58,129.01) 104.81,126.24 87.17,126.24 85.46,124.52 62.8,124.52 45.09,142.24 31.22,142.24 30.4,141.41 25.39,141.41 v1(23.55,143.26)
  BOTTOM w0.132: U73.19 24.05,143.76 v1(23.55,143.26)
FT4232_UART0_RX_3V3: length 98.6
  TOP w0.132: U19.13 108.61,129.81 v1(108.49,129.92)
  L05_SIG2 w0.084: v1(108.49,129.92) 108.04,129.47 108.04,128.82 105.15,125.93 87.3,125.93 85.58,124.22 62.59,124.22 45.86,140.95 24.79,140.95 v1(23.55,142.19)
  BOTTOM w0.132: v1(23.55,142.19) 23.05,142.69 U73.16
FT4232_UART0_TX_3V3: length 104.2
  TOP w0.132: U19.15 v1(108.49,129.01)
  L05_SIG2 w0.084: v1(23.55,146.85) 22.8,146.1 22.8,141.6 23.76,140.65 45.74,140.65 62.47,123.91 85.71,123.91 87.42,125.63 105.57,125.63 108.49,128.55 v1(108.49,129.01)
  BOTTOM w0.132: U73.17 23.05,146.35 v1(23.55,146.85)
FT4232_UART1_CTS_1V8: length 12.6
  TOP w0.132: U26.14 90.58,106.78 v1(89.93,107.43)
  BOTTOM w0.132: U85.9 83.13,107.05 84.77,105.41 89.73,105.41 90.42,106.11 90.42,106.94 v1(89.93,107.43)
FT4232_UART1_CTS_3V3: length 67.2
  L05_SIG2 w0.084: v1(28.55,134.42) 29.24,133.73 49.15,133.73 61.66,121.22 65.15,121.22 80.26,106.11 81.53,106.11 v1(81.93,106.52)
  BOTTOM w0.132: U85.12 v1(81.93,106.52) ; U73.53 v1(28.55,134.42)
FT4232_UART1_RTS_1V8: length 7.1
  TOP w0.132: U26.11 v1(88.63,106.39)
  BOTTOM w0.132: v1(88.63,106.39) 88.18,105.94 86.37,105.94 84.45,107.85 U85.7
FT4232_UART1_RTS_3V3: length 66.8
  L05_SIG2 w0.084: v1(79.57,107.45) 65.49,121.53 61.79,121.53 48.39,134.93 28.95,134.93 v1(28.55,135.33)
  BOTTOM w0.132: U73.54 28.05,134.83 v1(28.55,135.33) ; U85.14 80.83,107.85 80.78,107.81 79.92,107.81 v1(79.57,107.45)
FT4232_UART1_RX_1V8: length 16.2
  TOP w0.132: v1(88.63,113.03) 89.28,112.38 U26.5
  BOTTOM w0.132: v1(88.63,113.03) 89.41,112.26 89.41,106.49 88.59,105.67 86.09,105.67 84.31,107.45 U85.8
FT4232_UART1_RX_3V3: length 60.8
  L05_SIG2 w0.084: v1(80.57,107.34) 66.08,121.83 61.91,121.83 48.06,135.69 v1(33.78,135.69)
  BOTTOM w0.132: U73.48 33.28,135.19 v1(33.78,135.69) ; v1(80.57,107.34) 80.69,107.45 U85.13
FT4232_UART1_TX_1V8: length 15
  TOP w0.132: U26.2 v1(91.23,111.99)
  BOTTOM w0.132: U85.6 84.43,108.25 84.66,108.02 87.2,108.02 88.09,108.91 88.09,113.13 88.44,113.48 91.03,113.48 91.23,113.28 v1(91.23,111.99)
FT4232_UART1_TX_3V3: length 66
  L05_SIG2 w0.084: v1(29.55,135.33) 30.36,136.15 48.03,136.15 62.04,122.14 66.72,122.14 v1(80.6,108.25)
  BOTTOM w0.132: U73.52 29.05,134.83 v1(29.55,135.33) ; v1(80.6,108.25) U85.15
FT4232_USB_DM: length 18.6
  TOP w0.104: U15.5 13.69,140.48 13.43,140.48 v1(13.08,140.14) 12.69,140.53 12.12,140.53 11.91,140.32 J42.2
  L03_SIG1 w0.089: v1(23.55,137.93) 23.55,138.24 23.46,138.33 22.64,138.33 19.53,141.44 14.83,141.44 13.93,140.54 13.17,140.54 13.08,140.45 v1(13.08,140.14)
  BOTTOM w0.104: v1(23.55,137.93) 23.15,138.33 22.14,138.33 22,138.19 U73.7
FT4232_USB_DP: length 18.6
  TOP w0.104: J42.3 11.89,140.97 12.12,140.74 12.67,140.74 v1(13.08,141.15) 13.43,140.81 13.69,140.81 U15.4
  L03_SIG1 w0.089: v1(23.55,138.95) 23.55,138.63 23.46,138.54 22.73,138.54 19.62,141.66 14.74,141.66 13.84,140.75 13.17,140.75 13.08,140.84 v1(13.08,141.15)
  BOTTOM w0.104: U73.8 21.99,138.69 22.13,138.55 23.15,138.55 v1(23.55,138.95)
FT4232_USB_VBUS: length 8.6
  TOP w0.254: v1(13.65,137.86) 13.78,137.98 D7.1 ; D7.1 U15.6 ; D7.1 13.24,138.65 12.22,139.67 J42.1
  BOTTOM w0.254: 11.57,136.53 10.67,136.53 10.27,136.13 U76.4 ; 11.57,136.53 C329.2 ; 11.57,136.53 U76.6
FT4232_WKUP_UART0_CTS_3V3: length 93.4
  TOP w0.132: v1(112.94,121.92) 112.5,121.48 U21.12
  L05_SIG2 w0.084: v1(31.32,139.19) 46.76,139.19 62.34,123.61 85.84,123.61 87.55,125.32 111.34,125.32 112.94,123.72 v1(112.94,121.92)
  BOTTOM w0.132: U73.40 v1(31.32,139.19)
FT4232_WKUP_UART0_RTS_3V3: length 92.5
  TOP w0.132: U21.14 111.61,122.65 111.65,122.7 111.65,123.34 v1(111.21,123.79)
  L05_SIG2 w0.084: v1(30.4,139.19) 30.4,138.73 30.75,138.38 46.71,138.38 62.24,122.85 110.27,122.85 v1(111.21,123.79)
  BOTTOM w0.132: v1(30.4,139.19) 30.9,138.69 U73.41
FT4232_WKUP_UART0_RX_3V3: length 93.6
  TOP w0.132: v1(112.12,122.87) 112.01,122.76 U21.13
  L05_SIG2 w0.084: v1(112.12,122.87) 112.12,124.04 111.14,125.02 87.68,125.02 85.96,123.3 62.22,123.3 46.84,138.68 31.01,138.68 30.86,138.84 30.86,139.73 v1(31.32,140.19)
  BOTTOM w0.132: U73.38 v1(31.32,140.19)
FT4232_WKUP_UART0_TX_3V3: length 92.8
  TOP w0.132: U21.15 v1(111.21,122.87)
  L05_SIG2 w0.084: v1(30.4,140.19) 30,139.78 30,138.71 30.63,138.07 46.58,138.07 62.11,122.55 110.88,122.55 v1(111.21,122.87)
  BOTTOM w0.132: U73.39 30.9,139.69 v1(30.4,140.19)
GATE: length 29.2
  TOP w0.132: v1(47.37,134.24) 47.75,134.62 Q2.1
  L12_SIG4 w0.084: v1(47.37,134.24) 47.37,135.73 v1(30.76,152.34)
  BOTTOM w0.132: U66.10 C291.1 v1(30.76,152.34)
GP1_TOUCH_EVT: length 96.6
  L05_SIG2 w0.084: v1(162.54,35.43) 161.94,34.84 161.94,33.11 156.09,27.25 95.71,27.25 84.56,16.11 83.19,16.11 83.14,16.15 78.32,16.15 v1(77.68,15.51)
  BOTTOM w0.132: U110.13 v1(77.68,15.51) ; J35.38 v1(162.54,35.43)
GPIO_CSI_RESETN: length 65.7
  L05_SIG2 w0.084: v1(139.25,23.74) 134.17,18.66 124.4,18.66 118.99,13.25 91.45,13.25 90.77,13.93 v1(81.27,13.93)
  BOTTOM w0.132: U110.8 v1(81.27,13.93) ; U108.1 R658.1 v1(139.25,23.74)
GPIO_EMMC_RSTN: length 118
  TOP w0.132: R303.1 U48.1 v1(152.62,52.83)
  L05_SIG2 w0.084: v1(84.27,17.51) 94.32,27.56 155.96,27.56 159,30.61 159,36.47 163.44,40.91 163.44,45.52 162.05,46.91 153.61,46.91 152.62,47.9 v1(152.62,52.83)
  BOTTOM w0.132: U110.1 83.77,18.01 v1(84.27,17.51)
GPIO_MCU_RGMII_RSTN: length 147.6
  L03_SIG1 w0.084: v1(37.98,129.35) 37.98,128.01 39.93,126.06 39.93,111.65 40.84,110.73 40.84,69.27 48.73,61.38 56.74,61.38 72.6,45.52 72.6,23.15 77.17,18.59 77.17,15.45 77.71,14.91 83.67,14.91 v1(84.27,15.51)
  BOTTOM w0.132: U110.5 83.77,16.01 v1(84.27,15.51) ; v1(37.98,129.35) R409.2 R412.1 U82.1
GPIO_OSPI_RSTN: length 235.9
  L03_SIG1 w0.084: v1(83.36,17.51) 83.95,18.11 87.34,18.11 96.78,27.55 96.78,56.68 92.29,61.17 92.29,77.84 87.45,82.68 87.45,96.6 93.04,102.19 100.22,102.19 103.02,104.99 103.02,107.82 98.98,111.86 98.98,131.45 100,132.46 100,145.59 108.31,153.9 113.28,153.9 115.15,155.77 117.75,155.77 120.16,158.18 128.51,158.18 129.69,159.36 149.94,159.36 152.65,156.65 152.65,151.28 153.66,150.27 153.66,144.32 154.88,143.1 154.88,141.16 156.73,139.31 156.73,138.88 v1(158.38,137.23)
  BOTTOM w0.132: U110.2 v1(83.36,17.51) ; U74.1 v1(158.38,137.23) R390.1
GPIO_PRG2_RGMII_RESETN: length 84.7
  L03_SIG1 w0.084: v1(71.77,86.73) 71.77,73.28 73.82,71.22 73.82,25.4 78.8,20.42 78.8,15.62 79.21,15.21 82.06,15.21 v1(83.36,16.51)
  BOTTOM w0.132: U86.1 R506.1 70.26,88.05 70.48,87.82 70.9,87.82 71.1,87.63 R513.2 v1(71.77,86.73) ; U110.4 v1(83.36,16.51)
GPIO_SGMII_PHY_INT: length 5.5
  TOP w0.132: J5.46 145.74,144.56 145.34,144.16 145.34,141.64 R58.1 R729.2
GPIO_SGMII_PHY_RST: length 221.3
  TOP w0.132: J5.6 153.74,149.61 v1(153.13,150.22)
  L03_SIG1 w0.084: v1(153.13,150.22) 152.34,151.01 152.34,156.45 150.46,158.33 129.1,158.33 128.64,157.87 128.39,157.87 120.29,157.87 117.87,155.46 115.39,155.46 112.33,152.4 107.57,152.4 100.83,145.66 100.83,132.7 99.44,131.32 99.44,112.09 103.33,108.2 103.33,104.87 100.34,101.88 93.17,101.88 87.76,96.47 87.76,82.8 92.6,77.97 92.6,61.3 97.08,56.81 97.08,27.42 86.58,16.92 84.1,16.92 83.86,16.68 83.86,16.02 v1(83.36,15.51)
  BOTTOM w0.132: U110.6 v1(83.36,15.51)
GPIO_SPI0_RSTN: length 113.5
  TOP w0.132: v1(104.78,106.31) 104.92,106.17 R159.1 U28.1
  L03_SIG1 w0.084: v1(84.27,16.51) 86.62,16.51 97.39,27.28 97.39,56.94 92.9,61.42 92.9,91.06 91.25,92.71 91.25,98.23 93.99,100.97 101.85,100.97 104.78,103.89 v1(104.78,106.31)
  BOTTOM w0.132: v1(84.27,16.51) 83.77,17.01 U110.3
HB: length 3
  TOP w0.132: C66.1 68.63,139.99 68.75,140.11 U14.18
HDMI_GPMC_BRD_DET: length 105.7
  TOP w0.132: v1(88.1,62.3) 87.45,62.95 U46.7 87.45,65.52 87.22,65.74 86.42,65.74 86.35,65.81 R235.1
  L05_SIG2 w0.084: v1(157.54,35.43) 162.63,40.53 162.63,45.22 161.24,46.61 146.02,46.61 144.24,48.39 141.35,48.39 140.4,47.43 127.13,47.43 125.91,48.65 123,48.65 119.47,52.18 108.31,52.18 104.79,48.65 98.79,48.65 88.9,58.55 88.9,61.5 v1(88.1,62.3)
  BOTTOM w0.132: J35.18 v1(157.54,35.43)
HDR_MCU_UART1_CTS_1V8: length 6.2
  TOP w0.132: U6.9 115.18,157.85 115.31,157.98 117.49,157.98 118.49,156.98 118.49,156.46 118.81,156.15 U8.1
HDR_MCU_UART1_CTS_3V3: length 19.9
  TOP w0.132: U6.12 113.98,157.39 107.16,164.21 104.14,164.21 100.58,167.77 J30.6
HDR_MCU_UART1_RTS_3V3: length 35.5
  TOP w0.132: U6.14 112.81,156.63 112.76,156.67 112.12,156.67 v1(111.67,156.23)
  BOTTOM w0.132: v1(111.67,156.23) 112.07,155.83 112.78,155.83 113.28,156.34 113.28,157.48 102.23,168.53 102.23,170.05 100.97,171.32 91.44,171.32 90.42,170.31 J30.2
HDR_MCU_UART1_RX_1V8: length 5.6
  TOP w0.132: v1(116.58,157.14) 116.47,157.03 U6.8
  BOTTOM w0.132: U65.1 118.78,154.65 118.24,155.19 118.24,156.34 117.43,157.14 v1(116.58,157.14)
HDR_MCU_UART1_RX_3V3: length 23.2
  TOP w0.132: v1(112.59,157.14) 112.7,157.03 U6.13
  BOTTOM w0.132: J30.4 96.91,168.39 101.34,168.39 v1(112.59,157.14)
HDR_MCU_UART1_TX_3V3: length 22.2
  TOP w0.132: U6.15 v1(112.59,156.23)
  BOTTOM w0.132: v1(112.59,156.23) 112.98,156.62 112.98,157.4 101.73,168.66 99.19,168.66 J30.5
HDR_WKUP_UART0_CTS_3V3: length 16.4
  TOP w0.132: J11.6 114.3,126.68 114.3,114.62 114.05,114.36 U23.1
HDR_WKUP_UART0_RX_3V3: length 9.6
  BOTTOM w0.132: U83.1 113.7,115.86 114.05,116.2 114.05,121.35 J11.4
HS: length 43.8
  TOP w0.132: D8.1 89.03,126.24 87,124.21 70.61,124.21 67.69,127.13 C66.2 68.63,138.39 69.05,138.81 U14.20
IFORCE: length 16.7
  TOP w0.132: U34.B28 v1(158.36,86.59)
  BOTTOM w0.122: 159.77,87 158.76,87 v1(158.36,86.59)
  BOTTOM w0.132: TP62.1 169.89,78.93 161.83,87 159.77,87
IN_SEL0: length 3.2
  TOP w0.132: U32.30 R193.1 R197.2
IN_SEL1: length 3.4
  TOP w0.132: R187.2 R189.1 68.13,99.07 68.64,98.56 U32.29
INA_ALERT: length 446.1
  TOP w0.132: v1(105.76,109.7) 106.92,108.54 110.23,108.54 110.72,109.03 R147.1 R148.2 ; v1(179.71,160.07) 180.07,160.43 R18.2 ; R14.2 156.69,168.05 156.46,168.28 156.34,168.28 v1(156.02,168.59)
  L03_SIG1 w0.084: v1(169.37,149.46) 176.91,149.46 v1(179.66,152.21) 180.47,153.02 180.47,159.31 v1(179.71,160.07) ; v1(105.76,109.7) 107.19,111.12 107.19,112.21 108.75,113.77 111.12,113.77 111.12,113.79 111.51,114.17 111.51,116.84 112.14,117.47 112.14,119.14 108.01,123.27 108.01,129.15 107.7,129.47 107.7,132.38 110.21,134.9 110.21,146.66 114.68,151.13 117.68,151.13 118.75,152.19 130.11,152.19 131.08,153.16 138.46,153.16 v1(139.15,152.48)
  L05_SIG2 w0.084: v1(183.13,66.2) 185.51,66.2 186.94,64.77 197.11,64.77 201.57,69.23 201.57,146.79 196.15,152.21 v1(179.66,152.21) ; v1(139.15,152.48) 144.48,152.48 145.16,153.16 146.69,153.16 147.17,152.68 152.01,152.68 v1(154.27,154.94)
  L10_SIG3 w0.084: v1(169.37,149.46) 168.52,150.3 160.85,150.3 156.21,154.94 v1(154.27,154.94)
  L12_SIG4 w0.084: v1(105.76,109.7) 104.37,108.31 104.37,85.89 102.93,84.45 84.39,84.45 80.86,80.93 80.86,72.43 68.45,60.02 68.45,17.08 70.8,14.73 95.5,14.73 98.05,17.28 J21.4 ; v1(154.27,154.94) 154.27,166.85 v1(156.02,168.59)
  BOTTOM w0.132: v1(183.13,66.2) 183.17,66.24 R591.2 ; R365.2 v1(169.37,149.46) ; R364.2 v1(179.66,152.21) ; R363.2 139,151.19 139.15,151.34 v1(139.15,152.48) ; R358.2 v1(154.27,154.94)
JTAG_CTI_RTCK: length 23.8
  TOP w0.132: 99.53,93.85 97.83,93.85 97.6,93.63 97.6,93.56 v1(97.59,93.56)
  L03_SIG1 w0.084: v1(103.65,75.05) 103.65,75.96 100.66,78.95 100.66,90.49 v1(97.59,93.56)
  BOTTOM w0.132: R565.1 v1(103.65,75.05)
JTAG_CTI_TCK: length 24.7
  TOP w0.132: R227.1 R229.1 97.07,74.1 v1(97.16,74.02) 97.24,74.1 U41.2 ; J13.11 v1(97.66,92.58)
  L03_SIG1 w0.084: v1(97.16,74.02) 98.12,74.98 98.12,92.13 v1(97.66,92.58)
  BOTTOM w0.132: v1(97.16,74.02) 97.24,74.1 U41.2
JTAG_DIR: length 3.1
  TOP w0.132: 113.54,63.56 114.11,62.99 R254.2 ; 113.54,63.56 U43.2 ; 113.54,63.56 113.66,63.68 113.66,63.93 113.53,64.06 U43.3
JTAG_EMU0: length 17
  TOP w0.132: U37.8 91.82,85.22 91.95,85.35 v1(92.27,85.35) ; J13.13 v1(97.66,91.31)
  L12_SIG4 w0.084: v1(97.66,91.31) 97.66,88.87 94.14,85.35 v1(92.27,85.35)
  BOTTOM w0.132: v1(92.27,85.35) 91.82,85.79 U87.8 92.68,87.54 92.9,87.76 R504.2
JTAG_EMU1: length 21.2
  TOP w0.132: U37.1 91.82,86.82 91.95,86.69 v1(92.27,86.69) ; J13.14 v1(103.07,91.31)
  L12_SIG4 w0.084: v1(103.07,91.31) 102.57,91.82 96.58,91.82 95.39,90.63 95.39,89.81 v1(92.27,86.69)
  BOTTOM w0.132: R521.2 93.03,83.99 92.58,84.44 ; 92.58,84.44 92.85,84.71 92.85,86.11 v1(92.27,86.69) ; 92.58,84.44 U87.1
JTAG_EMU_RSTN: length 58.7
  TOP w0.132: J13.15 R213.2 96.94,90.57 96.71,90.8 v1(96.71,91.25) ; U50.6 v1(108.34,52.87)
  L03_SIG1 w0.084: v1(108.34,52.87) 108.34,55.17 95.95,67.56 95.95,90.49 v1(96.71,91.25) 94.04,93.92 94.04,98.8 v1(94.55,99.3)
  BOTTOM w0.132: v1(94.55,99.3) 94.55,99.3 94.72,99.47 R472.1
JTAG_MIPI_EMU0_1V8: length 21.1
  TOP w0.132: U37.5 90.32,84.17 89.98,83.83 88.27,83.83 v1(88.27,83.83) R217.2
  BOTTOM w0.132: v1(88.27,83.83) 87.95,84.15 87.95,88.96 90.74,91.76 97.85,91.76 98.14,91.47 J32.38
JTAG_MIPI_EMU1_1V8: length 14.8
  TOP w0.132: U37.4 89.88,87.54 89.28,88.14 R214.2 88.73,88.73 v1(88.46,88.46)
  BOTTOM w0.132: v1(88.46,88.46) 90.17,90.17 97.16,90.17 97.95,90.97 J32.40
JTAG_MIPI_RTCK: length 31.1
  TOP w0.132: R223.1 v1(104.01,77.14)
  L03_SIG1 w0.084: v1(107.12,99.31) 106.67,99.31 106.35,99.63 103.12,99.63 102.62,99.12 102.62,96.46 104.58,94.49 104.58,77.71 v1(104.01,77.14)
  BOTTOM w0.132: v1(107.12,99.31) 106.78,98.97 J32.7
JTAG_MIPI_TCK: length 32.5
  TOP w0.132: v1(103.12,101.66) 103.6,101.19 103.6,100.03 103.27,99.7 101.8,98.23 101.8,87.25 96.37,81.82 R221.1 R222.1 97.1,78.17 v1(97.17,78.09) U39.2
  BOTTOM w0.132: v1(103.12,101.66) 103.12,100.79 103.94,99.97 J32.3 ; U39.2 v1(97.17,78.09)
JTAG_MUX_SEL: length 69.6
  TOP w0.132: U42.1 109.27,74.9 109.51,74.66 v1(110.43,74.66)
  BOTTOM w0.132: v1(110.43,74.66) 110.43,71.56 105.65,66.78 105.65,29.73 108.33,27.05 121.41,27.05 J43.2
JTAG_TCK: length 23.2
  TOP w0.132: U43.12 108.2,65.06 107.76,65.51 107.49,65.51 106.93,66.06 106.93,67.16 108.61,68.83 110.55,68.83 111.32,69.6 111.32,76.9 110.05,78.17 107.7,78.17 107.32,77.8 U42.4
JTAG_TDI: length 43.7
  TOP w0.132: v1(107.57,65.06) 108.07,64.56 U43.13 ; v1(96.81,98.39) R196.2 97.32,97.35 97.64,97.66 J13.3
  L03_SIG1 w0.084: v1(107.57,65.06) 104.1,68.53 104.1,75.93 100.96,79.07 100.96,91.82 96.81,95.97 v1(96.81,98.39)
JTAG_TDIS: length 2.7
  TOP w0.132: R195.2 107.33,96.97 106.64,97.66 J13.4
JTAG_TDO: length 76.9
  TOP w0.132: v1(96.52,94.31) R202.1 97.7,95 97.83,95.12 J13.7
  L12_SIG4 w0.084: v1(96.52,94.31) 95.08,92.88 95.08,90 92.65,87.57 91.38,87.57 90.93,87.12 90.93,86.55 90.11,85.72 84.31,85.72 79.91,81.33 79.91,72.77 64.06,56.92 64.06,50.66 v1(57.15,43.75)
  BOTTOM w0.132: v1(57.15,43.75) 56.59,44.31 U101.7
JTAG_TMS: length 50
  TOP w0.132: J13.1 95.77,98.93 v1(94.49,100.21) ; v1(107.48,66.08) 107.79,66.08 108.3,65.56 U43.11
  L03_SIG1 w0.084: v1(107.48,66.08) 105.18,68.38 105.18,75.29 101.98,78.49 101.98,81.92 101.83,82.07 101.83,96.1 98.87,99.06 95.64,99.06 v1(94.49,100.21)
  BOTTOM w0.132: v1(94.49,100.21) 94.82,100.55 R470.1
JTAG_TRST#: length 47.2
  TOP w0.132: J13.2 v1(103.07,98.93) ; U43.10 v1(108.49,66.06)
  L03_SIG1 w0.084: v1(108.49,66.06) 107.44,67.1 107.44,94.56 v1(103.07,98.93)
  L10_SIG3 w0.084: v1(103.07,98.93) 95.15,98.93 v1(94.6,98.39)
  BOTTOM w0.132: R475.1 v1(94.6,98.39)
LCD_BRD_DET: length 167.3
  TOP w0.132: v1(89.4,62.3) 88.75,62.95 U46.5 88.75,65.89 R237.1
  L05_SIG2 w0.084: v1(89.4,62.3) 89,62.71 87.93,62.71 87.69,62.46 87.69,59.31 90.93,56.07 90.95,56.07 98.67,48.35 104.91,48.35 108.17,51.6 112.86,51.6 113.54,50.93 118.62,50.93 121.16,48.39 121.16,34.75 127,28.91 154.48,28.91 v1(155.35,28.04)
  L10_SIG3 w0.084: v1(200.51,10.7) 202.18,12.37 202.18,27.37 200.93,28.62 189.48,28.62 188.17,27.3 156.08,27.3 v1(155.35,28.04)
  BOTTOM w0.132: J38.40 v1(200.51,10.7)
LCD_BRD_TOUCH_INT: length 209.3
  TOP w0.132: v1(140.32,151.2) 140.32,153.63 139.81,154.14 U7.7 R36.1
  L05_SIG2 w0.084: v1(140.32,151.2) 141.15,150.36 142.83,150.36 143.61,151.15 147.47,151.15 148.08,151.76 149.48,151.76 150.39,150.86 175.71,150.86 177.76,152.91 197.25,152.91 202.08,148.08 202.08,67.34 200.53,65.79 200.53,35.55 201.93,34.15 201.93,17.02 201.05,16.14 200.02,16.14 v1(199.58,15.7)
  BOTTOM w0.132: J38.29 200.08,16.2 v1(199.58,15.7)
LCD_BRD_TOUCH_RESETN: length 4.7
  BOTTOM w0.132: U110.11 79.77,13.51 79.51,13.25 R686.1 U113.1
LCD_DISPLAY_EN: length 133.6
  L10_SIG3 w0.084: v1(200.51,15.7) 199.99,15.18 186.2,15.18 180.02,9 141.16,9 136.72,4.56 110.92,4.56 108.01,7.47 94.88,7.47 93.28,9.07 82.05,9.07 v1(79.38,11.75)
  BOTTOM w0.132: U110.10 80.27,14.02 80.53,13.76 R687.2 80,13.25 79.38,12.62 v1(79.38,11.75) ; J38.30 v1(200.51,15.7)
LCD_SHIELD: length 40.5
  TOP w0.381: v1(205.83,7.6) 205.83,28.82 v1(201.3,33.35)
  BOTTOM w0.381: v1(205.83,7.6) J38.SH4 202.31,7.6 201.43,8.48 J38.SH2 ; J38.SH1 201.43,32.12 FL15.2 v1(201.3,33.35) 202.8,33.35 202.86,33.3 J38.SH3
LCD_TOUCH_RESETN: length 134.1
  L10_SIG3 w0.084: v1(74.39,8.72) 93.19,8.72 94.81,7.11 107.77,7.11 110.62,4.25 136.84,4.25 141.29,8.7 180.15,8.7 182.15,10.7 v1(199.58,10.7)
  BOTTOM w0.132: U113.4 R698.1 v1(74.39,8.72) ; v1(199.58,10.7) 200.08,11.2 J38.39
LED1: length 4.1
  TOP w0.132: v1(61.51,114.59) 61.19,114.9 60.93,114.9 60.12,115.71 LD11.1
  BOTTOM w0.132: U84.3 v1(61.51,114.59)
LED2: length 3
  TOP w0.132: v1(62.78,114.59) 62.25,114.59 61.85,114.99 LD12.1
  BOTTOM w0.132: U84.4 v1(62.78,114.59)
LED3: length 2.9
  TOP w0.132: LD13.1 64.77,114.81 64.55,114.59 v1(64.05,114.59)
  BOTTOM w0.132: U84.5 v1(64.05,114.59)
LED4: length 3.8
  TOP w0.132: LD14.1 66.44,115.71 v1(65.32,114.59)
  BOTTOM w0.132: U84.6 v1(65.32,114.59)
LED5: length 12.6
  TOP w0.132: v1(65.32,111.6) 64.01,112.9 57.98,112.9 56.39,114.49 LD10.1
  BOTTOM w0.132: U84.11 v1(65.32,111.6)
LED6: length 13.8
  TOP w0.132: v1(64.05,111.6) 63.06,112.59 55.96,112.59 53.57,114.97 LD15.1
  BOTTOM w0.132: U84.12 v1(64.05,111.6)
LED7: length 15.6
  TOP w0.132: v1(62.78,111.6) 62.05,112.32 52.91,112.32 50.8,114.43 LD9.1
  BOTTOM w0.132: U84.13 v1(62.78,111.6)
LED8: length 17.6
  TOP w0.132: LD8.1 48.01,113.6 49.56,112.05 61.06,112.05 v1(61.51,111.6)
  BOTTOM w0.132: U84.14 v1(61.51,111.6)
LM5140_COMP1: length 6.8
  BOTTOM w0.132: C308.1 106.45,144.95 R375.2 105.19,144.95 105.01,144.76 105.01,143.53 105.47,143.07 105.47,141.23 104.95,140.71 U75.29
LM5140_COMP2: length 4
  BOTTOM w0.132: C350.1 105.32,131.13 R399.2 105.07,133.32 104.95,133.43 U75.2
MAIN_UART1_SEL: length 124.3
  TOP w0.132: U26.1 91.88,112.15 R134.2 92.5,112.3 v1(92.72,112.08)
  L03_SIG1 w0.084: v1(77.68,16.51) 78.19,17.03 78.19,20.17 73.52,24.84 73.52,70.67 70.36,73.83 70.36,94.36 68.7,96.02 68.7,106.75 74.54,112.59 92.21,112.59 v1(92.72,112.08)
  BOTTOM w0.132: U110.15 v1(77.68,16.51)
MCASP1_ACLKR: length 63.6
  TOP w0.132: v1(139.64,73.27) 141.03,74.66 157.63,74.66 159.95,72.33 173.46,72.33 174.95,70.85 188.86,56.93 188.86,53.75 188.53,53.42 187.87,53.42 v1(187.41,52.96)
  BOTTOM w0.132: R577.2 v1(139.64,73.27) ; v1(187.41,52.96) U100.7
MCASP1_ACLKR_3V3: length 6.1
  BOTTOM w0.132: J35.115 187.04,44.23 187.41,44.6 U100.14
MCASP1_ACLKX: length 58.6
  TOP w0.132: v1(141.67,73.27) 143.42,71.51 151.87,71.51 154.68,68.71 166.12,68.71 168.16,70.75 172.8,70.75 185.02,58.53 185.02,54.26 v1(185.41,53.87)
  BOTTOM w0.132: v1(185.41,53.87) 185.91,53.37 U100.4 ; R575.2 v1(141.67,73.27)
MCASP1_ACLKX_3V3: length 6.1
  BOTTOM w0.132: U100.17 185.91,44.63 185.54,44.25 J35.109
MCASP1_AFSR: length 58.2
  TOP w0.132: v1(188.47,53.91) 188.47,56.95 173.35,72.07 159.84,72.07 157.52,74.39 144.83,74.39 v1(143.7,73.27)
  BOTTOM w0.132: R573.2 v1(143.7,73.27) ; v1(188.47,53.91) 187.91,53.36 U100.8
MCASP1_AFSR_3V3: length 6.1
  BOTTOM w0.132: J35.117 187.54,44.28 187.91,44.66 U100.13
MCASP1_AFSX: length 65.3
  TOP w0.132: v1(137.6,73.27) 139.62,71.25 151.77,71.25 155.7,67.31 165.35,67.31 168.53,70.48 172.69,70.48 184.76,58.42 184.76,52.3 v1(183.58,51.12)
  BOTTOM w0.132: U100.1 v1(183.58,51.12) ; R579.2 v1(137.6,73.27)
MCASP1_AFSX_3V3: length 8.3
  BOTTOM w0.132: U100.20 183.58,49.62 183.43,49.47 183.43,45.93 184.54,44.82 J35.105
MCASP1_AHCLKR: length 55
  TOP w0.132: v1(188.41,52.96) 187.97,52.51 187.23,52.51 186.86,52.88 186.86,57.81 173.13,71.54 167.17,71.54 166.37,70.74 163.7,70.74 162.9,71.54 159.62,71.54 157.3,73.86 148.36,73.86 v1(147.76,73.27)
  BOTTOM w0.132: R569.2 v1(147.76,73.27) ; U100.9 v1(188.41,52.96)
MCASP1_AHCLKR_3V3: length 6.1
  BOTTOM w0.132: U100.12 188.41,44.71 188.04,44.34 J35.119
MCASP1_AHCLKX: length 47.8
  TOP w0.132: v1(186.41,52.96) 186.41,57.88 173.02,71.28 167.42,71.28 166.19,70.06 158.54,70.06 156.08,72.52 156.08,73.28 155.77,73.6 153.68,73.6 v1(153.23,73.14)
  BOTTOM w0.132: R590.2 v1(153.23,73.14) ; v1(186.41,52.96) U100.5
MCASP1_AHCLKX_3V3: length 6.1
  BOTTOM w0.132: U100.16 186.41,44.68 186.04,44.31 J35.111
MCASP1_AXR0: length 55.4
  TOP w0.132: v1(145.67,73.27) 146.53,74.12 157.41,74.12 159.73,71.81 173.24,71.81 187.39,57.66 v1(187.39,53.91)
  BOTTOM w0.132: U100.6 186.91,53.44 v1(187.39,53.91) ; R571.2 145.73,73.41 145.67,73.34 v1(145.67,73.27)
MCASP1_AXR0_3V3: length 6.1
  BOTTOM w0.132: U100.15 186.91,44.67 186.54,44.3 J35.113
MCASP1_AXR1: length 45.7
  TOP w0.132: v1(155.46,73.14) 155.46,72.25 158.62,69.09 165.86,69.09 167.79,71.01 172.91,71.01 186.06,57.87 186.06,53.6 v1(185.41,52.96)
  BOTTOM w0.132: R588.2 v1(155.46,73.14) ; v1(185.41,52.96) U100.3
MCASP1_AXR1_3V3: length 6.1
  BOTTOM w0.132: J35.107 185.04,44.26 185.41,44.64 U100.18
MCU_ADC0_CH0: length 31
  TOP w0.132: U34.K5 v1(151.96,105.79)
  L12_SIG4 w0.084: v1(151.96,105.79) 151.55,106.2 150.99,106.2 150.76,106.43 150.76,109.36 153.67,112.27 153.67,114.6 154.69,115.62 154.69,121.57 155.25,122.13 155.25,127.76 156.02,128.54 156.02,131.72 J10.4
MCU_ADC0_CH1: length 26.7
  TOP w0.132: U34.J3 v1(152.76,107.39)
  L12_SIG4 w0.084: v1(152.76,107.39) 152.36,107.78 151.81,107.78 151.56,108.03 151.56,109.4 154.75,112.59 154.75,115.25 154.99,115.49 154.99,116.69 157.48,119.18 J10.5
MCU_ADC0_CH2: length 30.6
  TOP w0.132: U34.J1 v1(152.76,108.99)
  L05_SIG2 w0.084: v1(152.76,108.99) 152.76,111.16 153.72,112.13 153.72,113.99 155.77,116.04 155.77,125.54 158.15,127.93 164.38,127.93 165.1,128.65 J10.11
MCU_ADC0_CH3: length 37.3
  TOP w0.132: U34.J5 v1(152.76,105.79)
  L12_SIG4 w0.084: v1(152.76,105.79) 153.16,105.38 153.16,104.83 152.93,104.6 149.36,104.6 149.16,104.8 149.16,109.22 153.04,113.09 153.04,116.21 152.76,116.48 152.76,120.5 154.64,122.38 154.64,127.51 153.61,128.54 153.61,131.59 J10.2
MCU_ADC0_CH4: length 42
  TOP w0.132: U34.K4 v1(151.96,106.59)
  L05_SIG2 w0.084: J10.9 161.14,128.84 154.18,128.84 153.02,127.69 153.02,121.24 152.14,120.36 148.58,120.36 147.83,119.6 147.83,113.97 148.28,113.52 148.28,109.73 148.14,109.6 148.14,109.6 148.14,107.14 148.14,107.13 148.14,106.65 148.61,106.18 149.72,106.18 149.95,105.95 149.95,105.65 150.19,105.4 151.32,105.4 151.55,105.63 151.55,106.18 v1(151.96,106.59)
MCU_ADC0_CH5: length 31.9
  TOP w0.132: U34.J4 v1(152.76,106.59)
  L12_SIG4 w0.084: v1(152.76,106.59) 153.16,107 153.16,109.67 156.22,112.72 156.22,117.06 168.35,129.18 169.1,129.18 J10.15
MCU_ADC0_CH6: length 28.5
  TOP w0.132: U34.J2 v1(152.76,108.19)
  L12_SIG4 w0.084: J10.6 158.69,131.59 158.69,119.95 155.3,116.56 155.3,115.37 155.13,115.2 155.13,112.08 152.36,109.31 152.36,108.58 v1(152.76,108.19)
MCU_ADC0_CH7: length 30.3
  TOP w0.132: U34.J6 v1(152.76,104.99)
  L12_SIG4 w0.084: v1(152.76,104.99) 152.35,105.4 150.19,105.4 149.96,105.63 149.96,109.32 153.37,112.73 153.37,114.73 153.67,115.04 153.67,120.98 154.94,122.25 J10.3
MCU_ADC0_REFN: length 39.2
  TOP w0.132: U34.K2 v1(151.96,108.19) ; J10.12 164.08,133.82 164.08,134.8 164.21,134.92 C74.1
  L05_SIG2 w0.084: v1(151.96,108.19) 152.36,108.6 152.36,111.2 153.42,112.25 153.42,114.12 154.62,115.33 154.62,128.08 154.77,128.23 163.47,128.23 164.02,128.78 164.02,131.72 J10.12
MCU_ADC0_REFP: length 40.3
  TOP w0.132: U34.K3 v1(151.96,107.39) ; C73.1 163.47,134.92 163.7,134.69 163.7,133.94 J10.10
  L05_SIG2 w0.084: J10.10 163.64,131.72 163.64,129.1 163.08,128.54 154.38,128.54 153.61,127.76 153.61,114.74 153.11,114.25 153.11,112.38 151.55,110.82 151.55,107.8 v1(151.96,107.39)
MCU_ADC1_AIN1: length 25.3
  TOP w0.132: U34.G6 v1(154.36,104.99)
  BOTTOM w0.122: v1(154.36,104.99) 154.75,104.6 157.72,104.6 157.95,104.83 157.95,109.56 157.95,109.56 157.95,109.63
  BOTTOM w0.132: TP34.1 165.35,120.9 162.36,117.91 162.36,115.28 157.95,110.87 157.95,109.63
MCU_ADC1_AIN2: length 22.7
  TOP w0.132: U34.G4 v1(154.36,106.59)
  BOTTOM w0.122: 154.08,109.6 153.95,109.47 153.95,107 v1(154.36,106.59)
  BOTTOM w0.132: 154.08,109.6 154.45,109.97 155.16,109.97 161.03,115.84 161.03,118.37 159.58,119.82 TP32.1
MCU_ADC1_AIN3: length 23.7
  TOP w0.132: U34.H5 v1(153.56,105.79)
  BOTTOM w0.122: v1(153.56,105.79) 153.96,106.2 155.32,106.2 155.56,106.45 155.56,109.6
  BOTTOM w0.132: 155.56,109.6 161.57,115.6 161.57,118.24 161.86,118.53 TP31.1
MCU_ADC1_AIN4: length 21
  TOP w0.132: U34.F5 v1(155.16,105.79)
  BOTTOM w0.122: v1(155.16,105.79) 155.22,105.79 155.63,106.2 156.12,106.2 156.35,106.43 156.35,109.6
  BOTTOM w0.132: TP35.1 163.07,119.37 161.83,118.13 161.83,115.49 156.35,110.01 156.35,109.6
MCU_ADC1_AIN5: length 25.9
  TOP w0.132: U34.G5 v1(154.36,105.79)
  BOTTOM w0.122: v1(154.36,105.79) 154.76,105.38 156.9,105.38 157.15,105.63 157.15,109.6
  BOTTOM w0.132: 157.15,109.6 157.15,110.44 162.1,115.38 162.1,118.02 163.33,119.26 163.33,121.78 163.85,122.3 163.85,122.94 163.39,123.4 163.39,123.89 TP30.1
MCU_ADC1_AIN6: length 18.9
  TOP w0.132: U34.G3 v1(154.36,107.39)
  BOTTOM w0.122: 155.16,109.6 154.75,109.19 154.75,107.78 v1(154.36,107.39)
  BOTTOM w0.132: 155.16,109.6 161.29,115.73 161.29,118.49 160.78,119 TP36.1
MCU_ADC1_AIN7: length 21.3
  TOP w0.132: U34.H4 v1(153.56,106.59)
  BOTTOM w0.122: 153.61,109.6 153.16,109.15 153.16,106.98 v1(153.56,106.59)
  BOTTOM w0.132: 153.61,109.6 154.25,110.24 155.05,110.24 160.76,115.95 160.76,118 158.5,120.27 TP37.1
MCU_ADC1_CH8: length 34.1
  TOP w0.132: U34.F4 v1(155.16,106.59)
  L12_SIG4 w0.084: J10.17 170.92,128.46 168.83,128.46 157.44,117.07 157.44,116.74 156.53,115.82 156.53,112.6 153.95,110.02 153.95,107.25 154.19,107 154.75,107 v1(155.16,106.59)
MCU_ADC1_REFN: length 43.5
  TOP w0.132: J10.18 171.7,133.82 171.7,134.8 171.83,134.92 C76.1 ; U34.H3 v1(153.56,107.39)
  L05_SIG2 w0.084: v1(153.56,107.39) 153.66,107.39 154.06,107.8 154.52,107.8 154.75,108.03 154.75,109.6 154.75,109.6 154.75,110.68 156.38,112.31 156.38,125.29 158.41,127.32 166.22,127.32 168.72,129.81 168.72,130.75 169.31,131.34 171.26,131.34 J10.18
MCU_ADC1_REFP: length 40.8
  TOP w0.132: J10.16 171.2,133.82 171.2,134.8 171.07,134.92 C75.1 ; U34.H2 v1(153.56,108.19)
  L05_SIG2 w0.084: v1(153.56,108.19) 153.16,108.58 153.16,110.97 154.76,112.57 154.76,114.6 156.07,115.91 156.07,125.41 158.28,127.62 165.09,127.62 166.18,128.71 166.18,130.43 167.39,131.64 169.02,131.64 J10.16
MCU_BOOTMODE0: length 166.1
  TOP w0.132: U34.AF4 v1(139.16,106.59) ; v1(27.37,75.63) R225.2 R228.1 26.58,74.02 R231.2
  L10_SIG3 w0.084: v1(139.16,106.59) 138.75,107 136.19,107 136.14,107.04 126.56,107.04 121.88,102.36 118.69,102.36 114.3,97.97 114.3,87.37 105.13,78.21 101.8,78.21 99.57,75.97 84.04,75.97 66.8,58.74 54.36,58.74 47.31,51.69 32.64,51.69 26.54,57.78 26.54,74.81 v1(27.37,75.63)
MCU_BOOTMODE1: length 166.7
  TOP w0.132: U34.AF3 v1(138.36,107.39)
  L10_SIG3 w0.084: v1(27.26,77.53) 27.77,77.01 27.77,75.27 26.92,74.42 26.92,57.84 32.77,51.99 47.18,51.99 54.23,59.04 66.68,59.04 83.91,76.28 99.44,76.28 101.68,78.51 105.01,78.51 114,87.5 114,98.1 120.42,104.52 123.61,104.52 126.53,107.44 137.91,107.44 137.96,107.39 v1(138.36,107.39)
  BOTTOM w0.132: R540.2 26.58,79.22 R546.1 R548.2 v1(27.26,77.53)
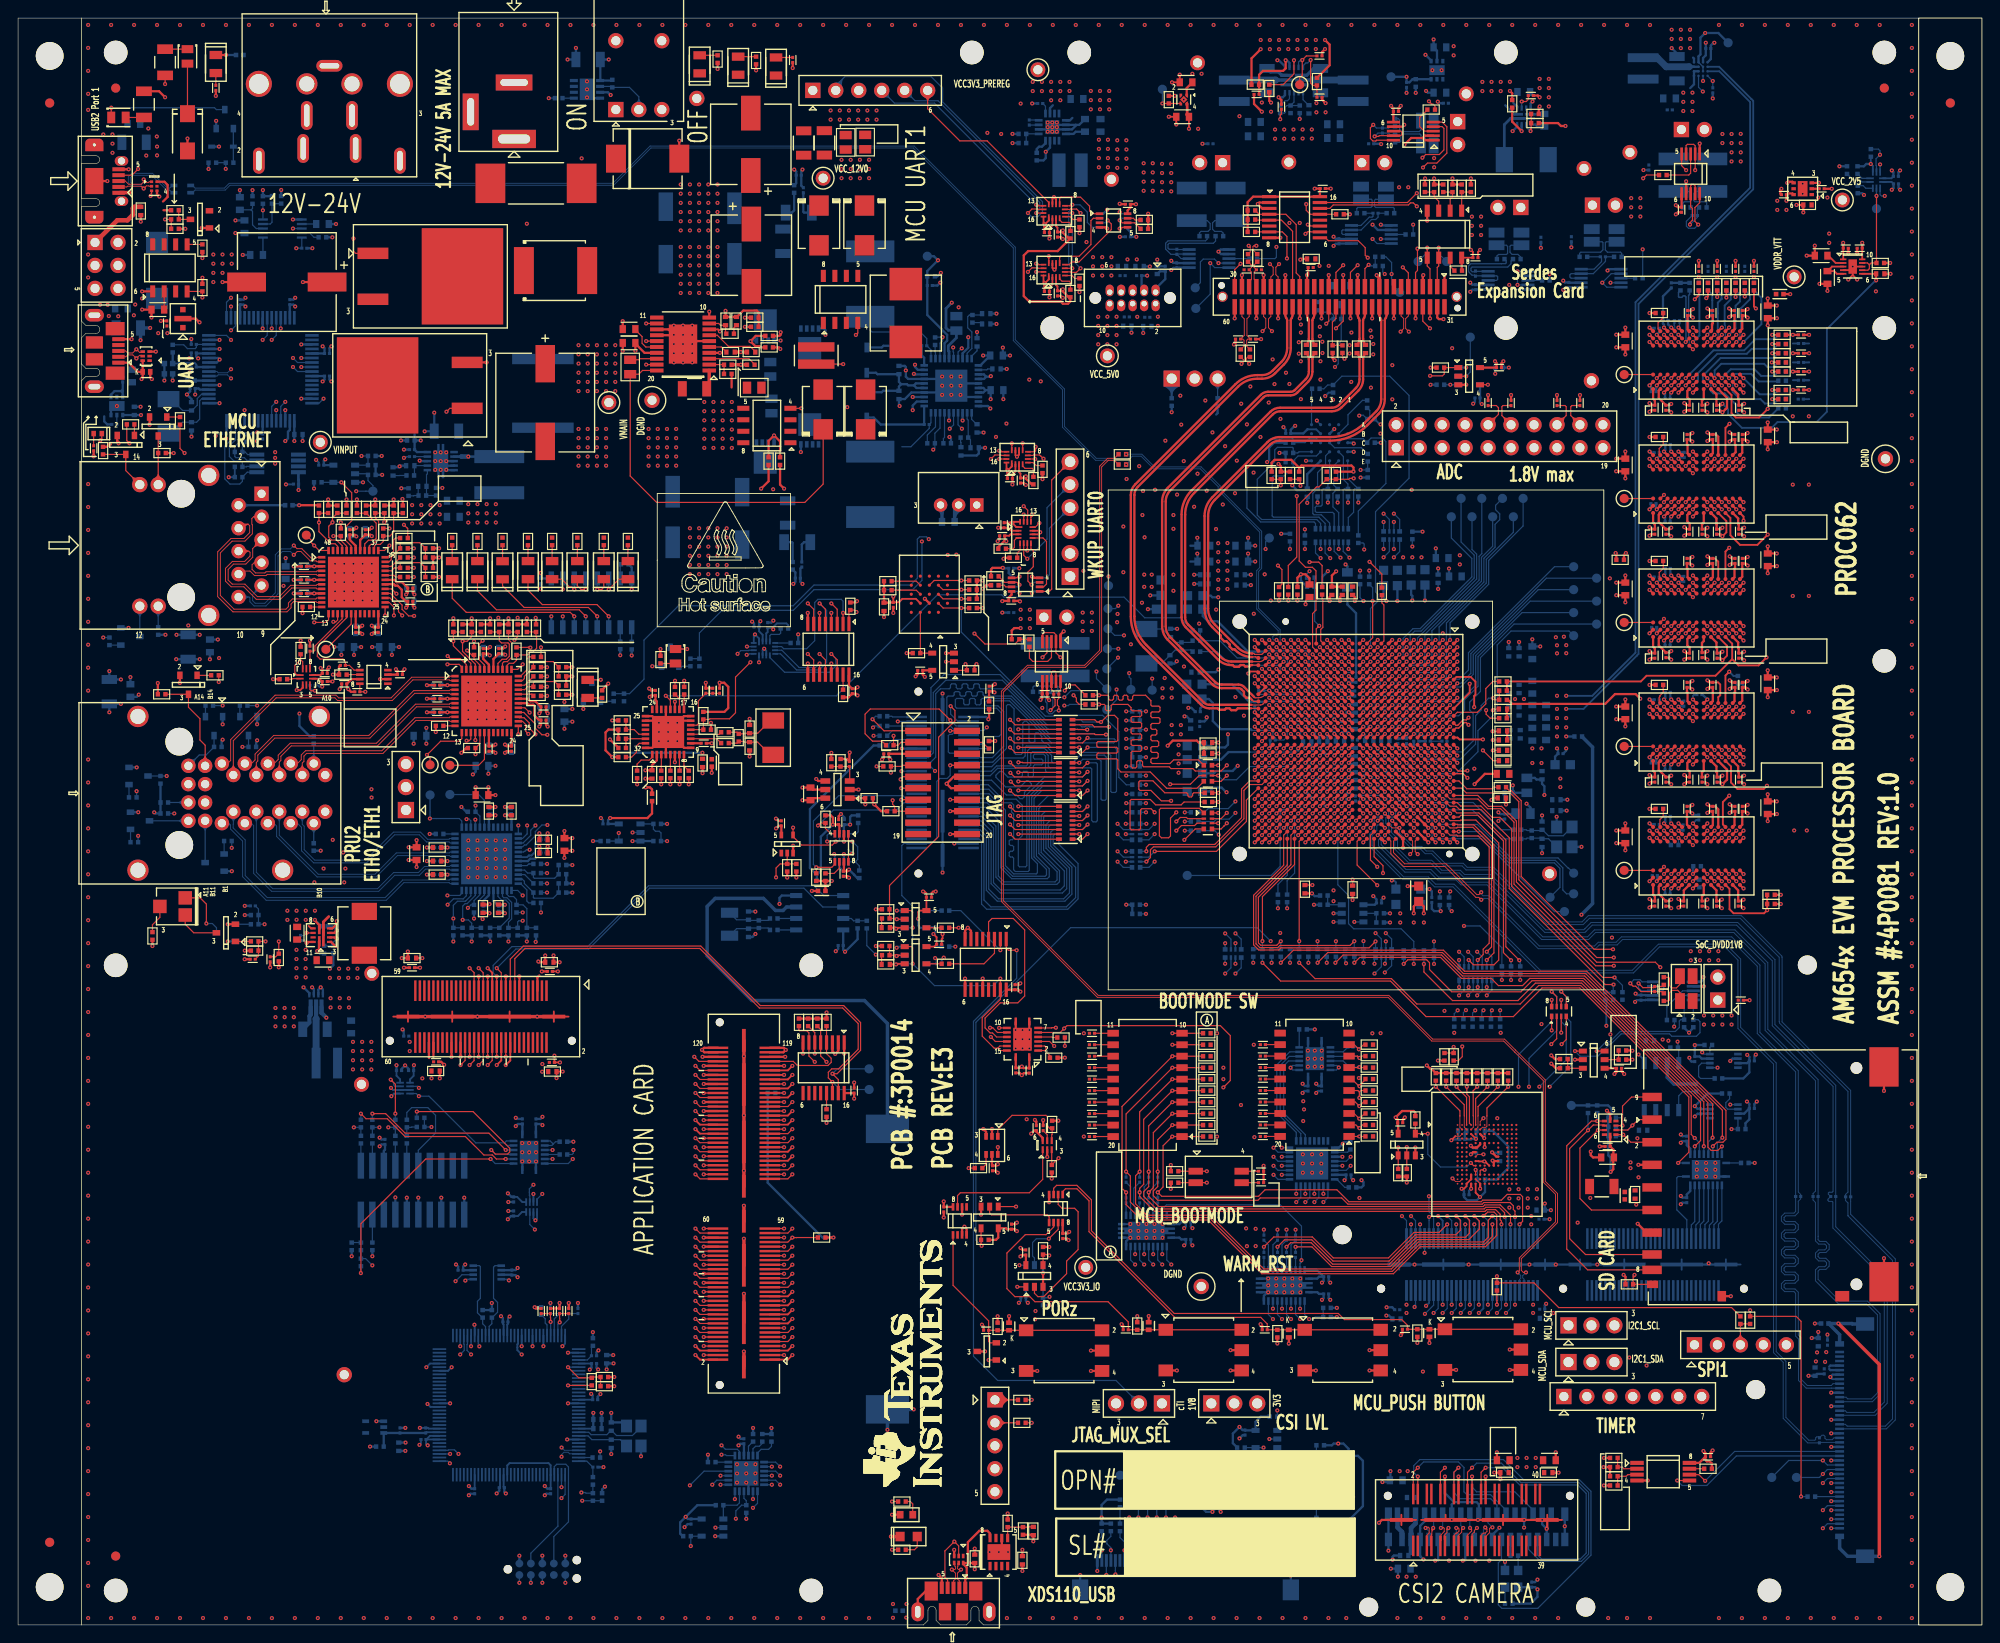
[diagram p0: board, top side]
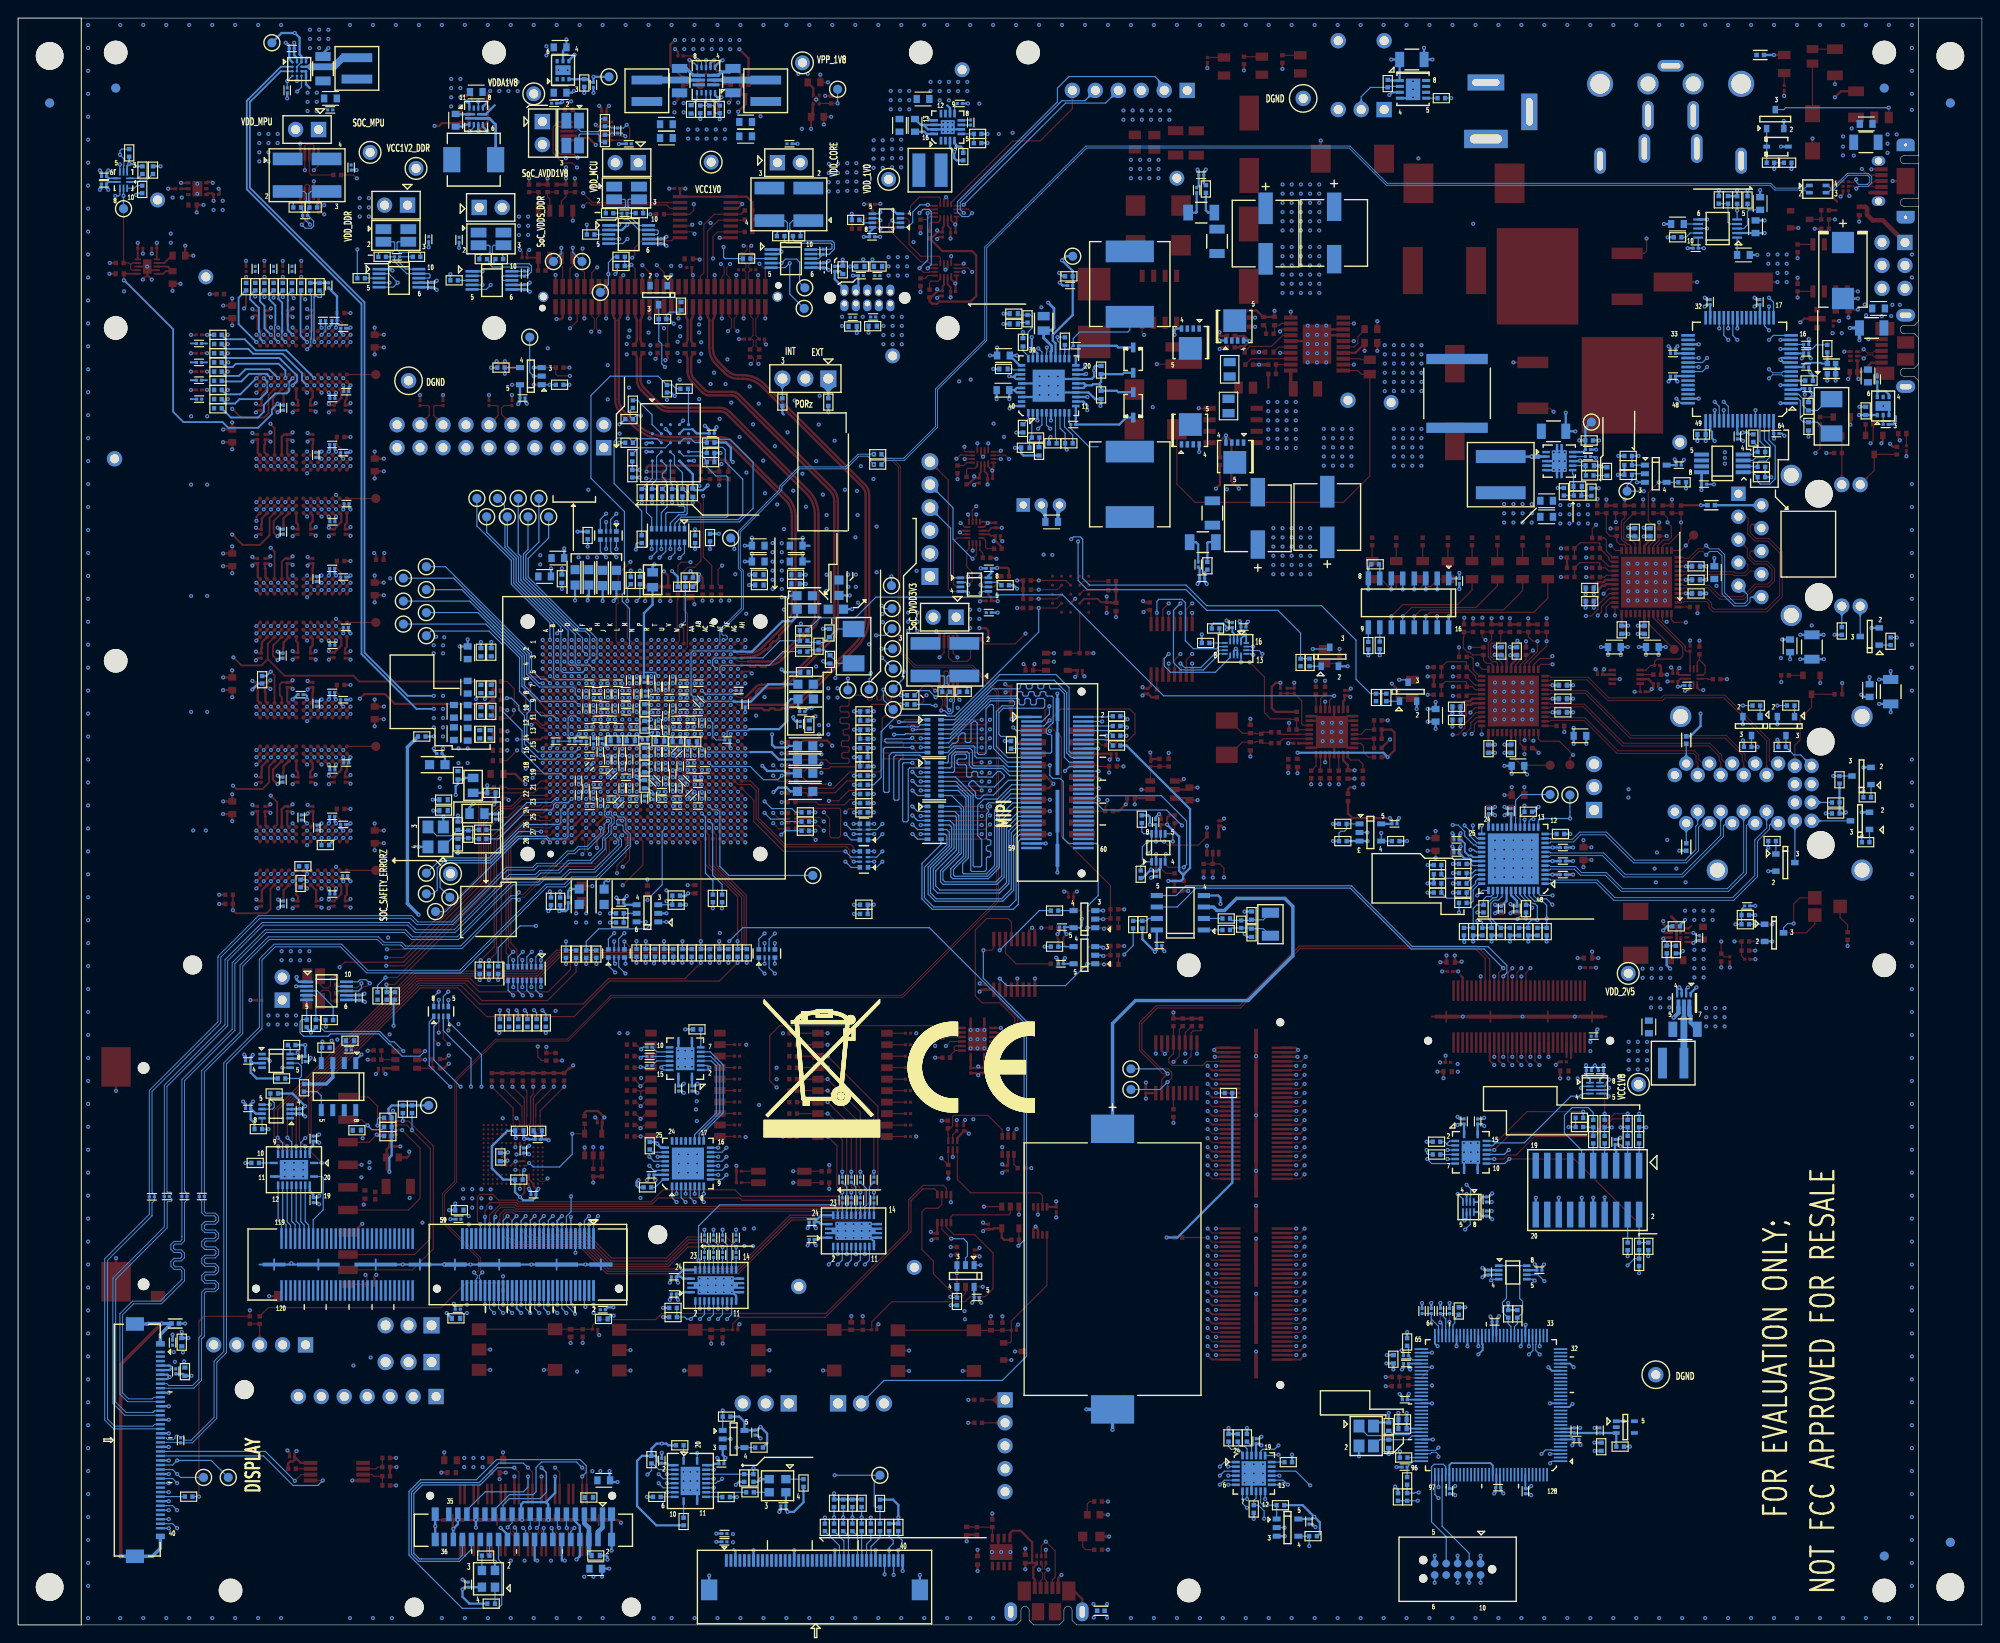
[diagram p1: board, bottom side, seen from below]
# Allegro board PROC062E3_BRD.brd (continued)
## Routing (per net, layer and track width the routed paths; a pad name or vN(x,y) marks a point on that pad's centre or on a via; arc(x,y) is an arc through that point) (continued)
MCU_BOOTMODE2: length 165
  TOP w0.132: U34.AE3 v1(139.16,107.39) ; v1(28.83,75.63) R230.1 28.49,73.93 27.88,73.93
  L10_SIG3 w0.084: v1(28.83,75.63) 27.23,74.03 27.23,57.96 32.89,52.3 47.05,52.3 54.1,59.35 66.55,59.35 83.78,76.58 99.31,76.58 101.55,78.82 104.88,78.82 113.69,87.62 113.69,98.22 120.37,104.9 123.06,104.9 125.94,107.78 136.14,107.78 136.15,107.78 138.52,107.78 138.91,107.39 v1(139.16,107.39)
MCU_BOOTMODE3: length 213.6
  TOP w0.132: R301.1 SW4.1 v1(131.46,50.2) ; U34.AD1 v1(139.96,108.99)
  L03_SIG1 w0.084: v1(139.96,108.99) 139.96,109.38 139.74,109.6 139.7,109.6 138.53,110.77 v1(138.53,113.35)
  L05_SIG2 w0.084: v1(121.58,111.87) 123.79,111.87 124.35,111.3 133.23,111.3 134.88,112.95 138.14,112.95 v1(138.53,113.35)
  L12_SIG4 w0.084: v1(121.58,111.87) 121.56,111.87 120.42,110.73 120.42,109.36 119.06,108 112.86,108 111.86,107 111.86,80.71 104.65,73.5 103.57,73.5 94.41,64.34 75.17,64.34 72.81,61.98 72.81,30.63 74.61,28.83 91.19,28.83 107.63,45.28 128.76,45.28 131.86,48.38 131.86,49.8 v1(131.46,50.2)
MCU_BOOTMODE9: length 26
  TOP w0.132: R83.1 R84.2 141.79,126.65 141.79,126.04 v1(141.81,126.04) ; U34.AB4 v1(141.56,106.59)
  L03_SIG1 w0.084: v1(141.81,126.04) 141.79,126.04 138.38,122.63 138.38,116.08 137.71,115.4 137.71,111.09 139.56,109.23 139.56,107.23 139.57,107.22 139.57,107.19 139.78,106.98 141.16,106.98 v1(141.56,106.59)
MCU_BYP_POR: length 63.2
  TOP w0.132: U34.V5 v1(144.76,105.79)
  L10_SIG3 w0.084: J8.2 130.11,132.59 138.95,123.75 152.61,123.75 153.6,122.75 153.6,109.94 153.95,109.6 153.95,106.43 153.7,106.18 153.39,106.18 153.15,105.93 153.15,103.98 152.96,103.8 148.59,103.8 148.36,104.03 148.36,104.94 147.9,105.4 146.99,105.4 146.75,105.64 146.75,105.95 146.75,105.95 146.52,106.18 145.15,106.18 v1(144.76,105.79)
MCU_CLKOUT: length 95.7
  TOP w0.132: R129.2 140.46,117.22 141.4,118.16 v1(141.4,124.91) ; U32.13 74.39,99.06 R190.1 R185.2 76.44,100.2 76.51,100.26 78.67,100.26 79.34,100.93 79.34,104.87 v1(80.98,106.52)
  L05_SIG2 w0.084: v1(141.4,124.91) 138.79,122.3 115.51,122.3 114.58,121.38 112.12,121.38 111.68,120.94 88.9,120.94 84.06,116.1 84.06,108.38 82.78,107.1 81.56,107.1 v1(80.98,106.52)
MCU_EARTH: length 3.4
  BOTTOM w0.254: v1(20.08,109.56) C405.1 v1(17.52,109.56) ; R456.1 v1(22.09,109.04)
  vias: v1(18.82,110.59)
MCU_ETH1_CLK_OUT: length 5.1
  TOP w0.132: TP14.1 36.83,110.75 36.83,111.89
MCU_ETH1_INTN: length 236.6
  TOP w0.132: U22.44 36.33,119.37 35.69,120.02 R100.1 v1(34.86,120.48)
  L03_SIG1 w0.084: v1(39.08,92.47) 36.11,95.44 36.11,105.75 34.45,107.41 34.45,120.07 v1(34.86,120.48)
  L05_SIG2 w0.084: v1(39.08,92.47) 39.62,91.92 39.62,85.09 42.6,82.12 56.46,82.12 56.93,81.64 86.27,81.64 91.92,76 110.77,76 122.38,64.39 122.38,64.14 122.38,57.65 126.4,53.63 128.05,53.63 131.74,57.32 131.74,66.29 134.94,69.49 155.93,69.49 157.73,71.3 162.69,71.3 167.64,66.35 167.64,63.42 171.09,59.96 171.09,54.57 174.36,51.3 176.9,51.3 177.93,52.32 178.6,52.32 v1(187.94,61.66)
  BOTTOM w0.132: U96.5 v1(187.94,61.66)
MCU_ETH1_INTN_SDIO: length 47.9
  TOP w0.132: U34.C24 v1(157.56,89.79)
  L03_SIG1 w0.084: v1(186.24,63.36) 186.24,65.85 184.43,67.66 184.43,71.59 179.97,76.05 v1(176.26,76.05)
  L10_SIG3 w0.084: v1(157.56,89.79) 158.06,89.28 159.79,89.28 162.73,86.35 162.73,84.16 166.75,80.14 173.23,80.14 176.26,77.11 v1(176.26,76.05)
  BOTTOM w0.132: R600.1 187.09,63.92 U96.8 186.43,63.16 v1(186.24,63.36)
MCU_ETH1_RBIAS: length 1.3
  TOP w0.132: U22.12 R135.1
MCU_ETH1_RESETN: length 10.7
  TOP w0.132: v1(35.74,126.43) 36.89,125.28 36.89,122.17 36.21,121.49 36.21,120 36.83,119.38 36.83,118.89
  BOTTOM w0.132: v1(35.74,126.43) U82.4 R417.1
MCU_ETH_D0M: length 15.6
  TOP w0.107: v1(30.49,118.4) 30.86,118.77 31.28,118.77 32.31,117.74 32.96,117.74 33.06,117.64 U22.2
  BOTTOM w0.107: v1(30.49,118.4) 30.12,118.77 29.22,118.77 28.74,118.29 28.74,114.09 27.4,112.75 26.1,112.75 25.64,113.21 25.64,113.64 25.55,113.74 J12.10
MCU_ETH_D0P: length 15.6
  TOP w0.107: U22.1 33.05,118.14 32.95,118.04 32.43,118.04 31.38,119.09 30.84,119.09 v1(30.49,119.44)
  BOTTOM w0.107: v1(30.49,119.44) 30.12,119.07 29.1,119.07 28.45,118.41 28.45,114.21 27.28,113.04 26.23,113.04 25.93,113.33 25.93,114.02 J12.9
MCU_ETH_D1M: length 9.6
  TOP w0.107: U22.5 33.08,116.14 32.97,116.24 27.55,116.24 27.42,116.11 26.14,116.11 25.64,116.61 24.72,116.61 J12.8
MCU_ETH_D1P: length 9.6
  TOP w0.107: J12.7 26.12,117.55 25.88,117.3 25.88,116.8 26.26,116.41 27.3,116.41 27.42,116.54 32.97,116.54 33.07,116.64 U22.4
MCU_ETH_D2M: length 18.5
  TOP w0.107: J12.6 25.52,118.82 25.65,118.68 25.65,118.27 25.06,117.68 23.7,117.68 22.93,116.91 22.93,115.5 23.56,114.87 24.96,114.87 26.34,113.49 29.01,113.49 30.26,114.74 32.96,114.74 33.06,114.64 U22.8
MCU_ETH_D2P: length 18.5
  TOP w0.107: J12.5 25.95,119.11 25.95,118.15 25.18,117.38 23.82,117.38 23.23,116.79 23.23,115.62 23.68,115.17 25.08,115.17 26.46,113.78 28.89,113.78 30.14,115.04 32.98,115.04 33.08,115.14 U22.7
MCU_ETH_D3M: length 24.6
  TOP w0.107: J12.4 24.83,121.81 25.43,121.81 25.61,121.63 25.61,120.86 24.97,120.22 23.55,120.22 22.07,118.74 22.07,113.78 23.75,112.1 29.74,112.1 30.19,112.55 30.19,112.96 30.46,113.23 32.94,113.23 33.04,113.14 U22.11
MCU_ETH_D3P: length 24.6
  TOP w0.107: J12.3 26.06,122.63 25.85,122.42 25.85,121.81 25.91,121.75 25.91,120.74 25.09,119.92 23.67,119.92 22.36,118.62 22.36,113.91 23.88,112.39 29.62,112.39 29.89,112.67 29.89,113.08 30.34,113.53 32.93,113.53 33.04,113.64 U22.10
MCU_ETH_GPIO_0: length 42.5
  TOP w0.132: v1(40.49,122.03) 40.49,122.47 40.51,122.5 R97.2 R96.1 39.5,122.51 39.86,122.15 39.86,120.13 39.56,119.83 39.46,119.83 39.2,119.57 39.02,119.57 38.83,119.38 U22.39 ; v1(12.32,130.75) 12.02,131.04 R72.2
  L05_SIG2 w0.084: v1(12.32,130.75) 18.22,130.75 18.41,130.56 21.21,130.56 24.43,127.34 37.82,127.34 40.49,124.67 v1(40.49,122.03)
MCU_ETH_GPIO_1: length 6.5
  TOP w0.132: U22.40 38.33,119.61 38.75,120.03 39.29,120.03 39.35,120.09 39.45,120.09 39.6,120.24 39.6,121.92 38.49,123.02 R95.1 R94.2
MCU_ETH_LED1: length 3.4
  BOTTOM w0.132: J12.12 Q9.3
MCU_ETH_LED2: length 5.4
  TOP w0.132: Q3.3 R79.1 J12.13
MCU_ETH_LED3: length 6.5
  TOP w0.132: J12.14 11.91,127.73 Q4.3 R78.1
MCU_ETH_LED_1000: length 29.6
  TOP w0.132: R91.1 R90.2 v1(33.27,122) 33.27,120.97 34.61,119.63 35.05,119.63 35.33,119.35 U22.46 ; R73.2 17.91,130.18 v1(18.41,129.67)
  L05_SIG2 w0.084: v1(18.41,129.67) 18.86,129.22 22.11,129.22 24.3,127.03 31.46,127.03 32.13,126.36 32.13,123.14 v1(33.27,122)
MCU_ETH_LED_ACTN: length 43.7
  TOP w0.132: R93.2 R92.1 35.29,123.02 34.77,122.5 v1(34.77,122) 34.35,121.58 34.35,120.36 34.68,120.04 35.23,120.04 35.83,119.43 U22.45
  L05_SIG2 w0.084: v1(34.77,122) 33.17,120.4 30.48,120.4 28.45,118.36 28.45,110.62 25.45,107.62 11.06,107.62 v1(9.42,109.26)
  BOTTOM w0.132: R451.2 v1(9.42,109.26)
MCU_MCAN0_RX: length 124
  TOP w0.132: U34.W2 v1(143.96,108.19) ; J16.32 v1(50.93,62.87)
  L10_SIG3 w0.084: v1(143.96,108.19) 142.76,109.38 136.47,109.38 135.93,108.84 125.07,108.84 122.17,105.94 120.55,105.94 113.08,98.48 113.08,87.88 104.63,79.43 101.3,79.43 100.42,78.55 84.89,78.55 66.3,59.96 53.07,59.96 51.44,61.59 51.44,62.36 v1(50.93,62.87)
MCU_MCAN0_TX: length 173.3
  TOP w0.132: R131.1 144.21,117.22 143.83,117.6 v1(142.81,117.6) ; J16.30 51.43,62.45 v1(50.93,61.95)
  L03_SIG1 w0.084: v1(55.24,111.44) 54.05,110.25 48.05,110.25 41.45,103.66 41.45,72.14 50.42,63.17 50.42,62.46 v1(50.93,61.95)
  L05_SIG2 w0.084: v1(55.24,111.44) 55.98,110.7 74.78,110.7 79.98,105.5 82.68,105.5 82.94,105.75 82.94,105.76 84.76,107.58 84.76,115.94 87.47,118.65 101.3,118.65 101.98,119.34 109.43,119.34 109.99,119.89 112.04,119.89 114.62,117.32 117.19,117.32 119.01,119.13 136.02,119.13 138.34,116.81 142.02,116.81 v1(142.81,117.6)
MCU_MCAN0_TX_R: length 5.7
  TOP w0.132: U34.W1 144.06,108.89 144.06,110.16 144.29,110.39 144.29,113.42 144.21,113.5 R131.2
MCU_MCAN1_RX: length 121
  TOP w0.132: J16.36 v1(49.93,62.87) ; U34.AD3 v1(139.96,107.39)
  L10_SIG3 w0.084: v1(139.96,107.39) 139.55,107.8 138.9,107.8 138.75,107.95 138.75,108.39 138.56,108.58 138.52,108.58 138.52,108.58 136.59,108.58 136.15,108.14 124.8,108.14 122.3,105.64 120.67,105.64 113.39,98.35 113.39,87.75 104.76,79.12 101.42,79.12 99.99,77.68 84.46,77.68 66.42,59.65 52.62,59.65 50.42,61.85 50.42,62.38 v1(49.93,62.87)
MCU_MCAN1_TX: length 168.2
  TOP w0.132: J16.34 50.43,62.45 v1(49.93,61.95) ; v1(139.32,117.22) 139.77,116.77 139.77,115.17 R128.2
  L03_SIG1 w0.084: v1(53.11,111.44) 52.22,110.55 46.96,110.55 42.33,105.92 42.33,104.96 41.15,103.78 41.15,71.89 49.4,63.63 49.4,62.48 v1(49.93,61.95)
  L05_SIG2 w0.084: v1(53.11,111.44) 53.72,112.06 73.86,112.06 80.11,105.81 82.56,105.81 84.45,107.71 84.45,115.81 84.45,116.06 89.02,120.63 111.74,120.63 112.48,119.89 132.11,119.89 132.34,120.12 135.47,120.12 138.37,117.22 v1(139.32,117.22)
MCU_MCAN1_TX/BOOTMODE4: length 216
  TOP w0.132: v1(131.46,48.93) SW4.2 R305.1 ; R128.1 v1(139.45,113.33) ; U34.AC3 v1(140.76,107.39)
  L03_SIG1 w0.084: v1(139.45,113.33) 139.07,112.95 139.07,110.7 140.35,109.42 140.35,107.8 v1(140.76,107.39)
  L05_SIG2 w0.084: v1(139.45,113.33) 138.86,113.92 137.62,113.92 136.96,113.26 134.76,113.26 133.13,111.63 124.35,111.63 123.66,112.33 121.25,112.33 120.99,112.07 120.99,111.21 121.25,110.95 v1(121.54,110.95)
  L12_SIG4 w0.084: v1(131.46,48.93) 131.46,48.4 128.64,45.58 107.24,45.58 90.92,29.26 74.87,29.26 73.11,31.01 73.11,61.85 75.3,64.03 94.53,64.03 103.7,73.2 104.78,73.2 112.17,80.58 112.17,106.87 112.99,107.7 119.19,107.7 120.73,109.23 120.73,110.41 121.26,110.95 v1(121.54,110.95)
MCU_MDC_RGMII: length 5.6
  TOP w0.132: U34.L1 151.04,108.87 151.04,112.87 150.81,113.09 R132.2
MCU_MDC_RGMII_1V8: length 7.8
  TOP w0.132: U29.8 R149.2 32.71,107.75 32.83,107.86 32.83,108.31 35.83,111.32 U22.16
MCU_MDC_RGMII_3V3: length 161.9
  TOP w0.132: v1(149.45,117.63) 150.81,116.27 R132.1 ; U29.5 32.28,103.5 32.41,103.37 v1(32.83,103.37)
  L10_SIG3 w0.084: v1(149.45,117.63) 150.37,118.55 152.46,118.55 153.06,119.15 153.06,122.85 152.53,123.38 131.64,123.38 124.84,130.18 112.91,130.18 112.69,129.96 112.35,129.96 112.14,130.18 109.32,130.18 108.66,129.52 102.78,129.52 100.64,127.38 41.15,127.38 40.51,128.02 36.7,128.02 31.87,123.18 31.87,103.7 32.27,103.3 32.71,103.3 32.77,103.37 v1(32.83,103.37)
  BOTTOM w0.132: R175.2 32.29,103.68 32.54,103.43 32.77,103.43 v1(32.83,103.37)
MCU_MDIO_1V8: length 11.6
  TOP w0.132: U22.17 36.33,111.45 33.09,108.2 33.09,107.18 33.4,106.87 35.93,106.87 36.19,106.61 R156.2 36.64,106.17 37.16,105.65 U30.5
MCU_MDIO_3V3: length 134.6
  TOP w0.132: v1(38.4,103.25) R174.2 U30.8 ; U34.L4 v1(151.16,106.59)
  L10_SIG3 w0.084: v1(38.4,103.25) 38.4,106.78 40.33,108.71 42.09,108.71 48.44,115.06 78.61,115.06 79.25,115.06 80.47,116.28 104.6,116.28 105.37,115.51 105.37,111.94 110.76,106.55 121.92,106.55 124.9,109.54 135.7,109.54 135.91,109.75 136.09,109.92 147.74,109.92 148.2,109.46 148.2,105.68 148.47,105.4 149.72,105.4 149.95,105.63 149.95,105.93 149.96,105.95 149.96,105.95 150.19,106.18 150.52,106.18 150.93,106.59 v1(151.16,106.59)
MCU_PORZ_OUT: length 155.9
  TOP w0.132: U34.V2 v1(144.76,108.19)
  L10_SIG3 w0.084: v1(37.39,125.45) 36.66,125.45 34.23,123.02 34.23,111.85 32.7,110.32 32.7,104.03 33.5,103.23 35.1,103.23 35.48,102.84 40.49,102.84 47.96,110.31 75.01,110.31 80.67,115.98 104.47,115.98 105.07,115.38 105.07,114.24 104.93,114.1 104.93,111.95 110.63,106.25 122.05,106.25 125.03,109.23 135.83,109.23 136.21,109.62 143.33,109.62 v1(144.76,108.19)
  BOTTOM w0.132: U82.2 38.57,127.38 R415.1 38.7,126.62 39.24,126.07 TP85.1 38.47,125.45 v1(37.39,125.45)
MCU_RESETSTATZ: length 19.1
  TOP w0.132: U34.V3 v1(144.76,107.39)
  L05_SIG2 w0.084: v1(144.76,107.39) 145.15,107.78 145.15,109.6 145.15,109.6 145.15,111.9 143.38,113.67 143.38,117.61 142.65,118.34 138.67,118.34 v1(137.96,119.05)
  BOTTOM w0.132: TP38.1 137.96,119.86 v1(137.96,119.05)
MCU_RESETZ: length 25.5
  TOP w0.132: U34.W4 v1(143.96,106.59)
  L05_SIG2 w0.084: v1(143.96,106.59) 143.71,106.59 143.3,107 136.15,107 134.69,108.46 127.51,108.46 126.47,109.5 v1(122.3,109.5)
  BOTTOM w0.132: TP47.1 121.26,109.5 v1(122.3,109.5)
MCU_RGMII1_CLKIN: length 48.1
  TOP w0.132: R203.2 v1(68.45,93.01) ; U22.15 35.33,111.19 35.14,111 v1(34.86,111)
  L05_SIG2 w0.084: v1(68.45,93.01) 57.61,93.01 54.42,96.2 54.42,104.9 52.64,106.68 49.29,106.68 46.37,109.6 40.81,109.6 39.41,111 v1(34.86,111)
MCU_RGMII1_RD0: length 153.5
  TOP w0.132: U34.L6 v1(151.16,104.99) ; R118.1 v1(43.77,116.97)
  L10_SIG3 w0.084: v1(151.16,104.99) 150.76,105.38 150.76,105.95 151.01,106.2 151.32,106.2 151.55,106.43 151.55,112.19 148.88,114.86 137.81,114.86 137.03,115.63 134.3,115.63 133.79,115.13 130.7,115.13 130.19,114.62 129.73,114.62 129.01,115.34 122.91,115.34 120.43,112.86 115.03,112.86 114.76,113.13 112.29,115.6 108.99,115.6 103.85,120.74 72.55,120.74 72.4,120.89 72.4,121.19 72.25,121.34 71.89,121.34 71.74,121.19 71.74,120.89 71.59,120.74 71.23,120.74 71.08,120.89 71.08,121.19 70.93,121.34 70.57,121.34 70.42,121.19 70.42,120.89 70.27,120.74 69.91,120.74 69.76,120.89 69.76,121.19 69.61,121.34 69.25,121.34 69.1,121.19 69.1,120.89 68.94,120.74 68.59,120.74 68.44,120.89 68.44,121.19 68.28,121.34 67.93,121.34 67.78,121.19 67.78,120.89 67.62,120.74 67.27,120.74 67.12,120.89 67.12,121.19 66.96,121.34 66.61,121.34 66.46,121.19 66.46,120.89 66.3,120.74 65.95,120.74 65.8,120.89 65.8,121.19 65.64,121.34 65.29,121.34 65.13,121.19 65.13,120.89 64.98,120.74 64.63,120.74 64.47,120.89 64.47,121.19 64.32,121.34 63.97,121.34 63.81,121.19 63.81,120.89 63.66,120.74 63.18,120.74 62.92,120.47 62.92,118.03 62.77,117.88 62.03,117.88 61.88,118.03 61.88,120.04 61.73,120.19 61.37,120.19 61.22,120.04 61.22,118.03 61.07,117.88 60.71,117.88 60.56,118.03 60.56,120.04 60.41,120.19 60.05,120.19 59.9,120.04 59.9,118.03 59.75,117.88 59.39,117.88 59.24,118.03 59.24,120.04 59.09,120.19 58.73,120.19 58.58,120.04 58.58,118.03 58.43,117.88 58.07,117.88 57.92,118.03 57.92,120.04 57.77,120.19 57.41,120.19 57.26,120.04 57.26,118.03 57.11,117.88 56.75,117.88 56.6,118.03 56.6,120.04 56.45,120.19 56.09,120.19 55.94,120.04 55.94,118.03 55.79,117.88 47.32,117.88 46.41,116.97 v1(43.77,116.97)
MCU_RGMII1_RD0_R: length 6.4
  TOP w0.132: U22.33 41.28,116.64 41.61,116.97 R118.2 42.25,117.44 42.35,117.54 44.49,117.54 45.05,116.98 R119.2 R122.1
MCU_RGMII1_RD1: length 153.5
  TOP w0.132: R114.1 v1(43.77,118.11) ; U34.M6 v1(150.36,104.99)
  L10_SIG3 w0.084: v1(43.77,118.11) 43.2,118.67 43.2,119.49 43.48,119.78 44.47,119.78 44.62,119.62 44.62,119.28 44.77,119.13 45.13,119.13 45.28,119.28 45.28,119.62 45.43,119.78 47.46,119.78 47.62,119.94 47.62,121.16 47.83,121.37 49.06,121.37 49.23,121.21 49.23,119.52 49.38,119.37 49.85,119.37 50,119.52 50,121.33 50.16,121.48 50.51,121.48 50.66,121.33 50.66,119.35 50.82,119.19 51.17,119.19 51.32,119.35 51.32,121.33 51.48,121.48 51.83,121.48 51.98,121.33 51.98,119.33 52.14,119.18 52.49,119.18 52.64,119.33 52.64,121.33 52.8,121.48 53.15,121.48 53.3,121.33 53.3,119.31 53.46,119.15 53.92,119.15 54.11,119.35 54.11,122.19 54.27,122.34 103.9,122.34 104.23,122 104.45,122 104.57,122.12 104.78,122.12 105.04,121.87 105.04,121.66 104.91,121.54 104.91,121.32 105.17,121.07 105.38,121.07 105.5,121.19 105.72,121.19 105.97,120.94 105.97,120.72 105.85,120.6 105.85,120.39 106.1,120.13 106.32,120.13 106.44,120.26 106.65,120.26 106.9,120 106.9,119.79 106.78,119.67 106.78,119.45 107.03,119.2 107.25,119.2 107.37,119.32 107.59,119.32 107.84,119.07 107.84,118.85 107.72,118.73 107.72,118.52 108.76,117.47 113.16,117.47 113.39,117.25 113.39,115.8 115.3,113.89 120.27,113.89 123.04,116.66 131.84,116.66 132.4,117.22 138.74,117.22 139.3,116.66 142.1,116.66 142.64,116.13 150.34,116.13 153.15,113.32 153.15,106.41 152.92,106.18 152.59,106.18 152.36,105.95 152.36,104.85 152.12,104.6 150.75,104.6 v1(150.36,104.99)
MCU_RGMII1_RD1_R: length 2.1
  TOP w0.132: U22.34 41.29,117.14 42.25,118.1 R114.2
MCU_RGMII1_RD2: length 153.4
  TOP w0.132: U34.L5 v1(151.16,105.79) ; R111.1 v1(43.77,119.13)
  L10_SIG3 w0.084: v1(43.77,119.13) 44.22,118.67 54.42,118.67 54.57,118.83 54.57,121.73 54.72,121.88 55.44,121.88 55.59,121.73 55.59,121.11 55.74,120.96 56.1,120.96 56.25,121.11 56.25,121.73 56.4,121.88 56.76,121.88 56.91,121.73 56.91,121.11 57.06,120.96 57.42,120.96 57.57,121.11 57.57,121.73 57.72,121.88 58.08,121.88 58.23,121.73 58.23,121.11 58.38,120.96 58.74,120.96 58.89,121.11 58.89,121.73 59.04,121.88 59.4,121.88 59.55,121.73 59.55,121.11 59.7,120.96 60.06,120.96 60.21,121.11 60.21,121.73 60.36,121.88 60.72,121.88 60.87,121.73 60.87,121.11 61.02,120.96 61.38,120.96 61.53,121.11 61.53,121.73 61.69,121.88 62.04,121.88 62.19,121.73 62.19,121.11 62.35,120.96 62.7,120.96 62.85,121.11 62.85,121.73 63.01,121.88 78.92,121.88 79.07,121.73 79.07,121.39 79.22,121.24 79.58,121.24 79.73,121.39 79.73,121.73 79.88,121.88 80.24,121.88 80.39,121.73 80.39,121.39 80.54,121.24 80.9,121.24 81.05,121.39 81.05,121.73 81.21,121.88 81.56,121.88 81.71,121.73 81.71,121.39 81.87,121.24 82.22,121.24 82.37,121.39 82.37,121.73 82.53,121.88 82.88,121.88 83.03,121.73 83.03,121.39 83.19,121.24 83.54,121.24 83.69,121.39 83.69,121.73 83.85,121.88 84.2,121.88 84.35,121.73 84.35,121.39 84.51,121.24 84.86,121.24 85.02,121.39 85.02,121.73 85.17,121.88 85.52,121.88 85.68,121.73 85.68,121.39 85.83,121.24 86.18,121.24 86.34,121.39 86.34,121.73 86.49,121.88 86.84,121.88 87,121.73 87,121.39 87.15,121.24 87.5,121.24 87.66,121.39 87.66,121.73 87.81,121.88 88.16,121.88 88.32,121.73 88.32,121.39 88.47,121.24 88.83,121.24 88.98,121.39 88.98,121.73 89.13,121.88 89.49,121.88 89.64,121.73 89.64,121.39 89.79,121.24 90.15,121.24 90.3,121.39 90.3,121.73 90.45,121.88 90.81,121.88 90.96,121.73 90.96,121.39 91.11,121.24 91.47,121.24 91.62,121.39 91.62,121.73 91.77,121.88 92.13,121.88 92.28,121.73 92.28,121.39 92.43,121.24 92.79,121.24 92.94,121.39 92.94,121.73 93.09,121.88 93.45,121.88 93.6,121.73 93.6,121.39 93.75,121.24 94.11,121.24 94.26,121.39 94.26,121.73 94.41,121.88 94.77,121.88 94.92,121.73 94.92,121.39 95.07,121.24 95.43,121.24 95.58,121.39 95.58,121.73 95.73,121.88 96.09,121.88 96.24,121.73 96.24,121.39 96.39,121.24 96.75,121.24 96.9,121.39 96.9,121.73 97.05,121.88 97.41,121.88 97.56,121.73 97.56,121.39 97.72,121.24 98.07,121.24 98.22,121.39 98.22,121.73 98.38,121.88 98.73,121.88 98.88,121.73 98.88,121.39 99.04,121.24 99.39,121.24 99.54,121.39 99.54,121.73 99.7,121.88 100.05,121.88 100.2,121.73 100.2,121.39 100.36,121.24 100.71,121.24 100.86,121.39 100.86,121.73 101.02,121.88 101.47,121.88 101.62,121.73 101.62,121.31 101.74,121.2 102.17,121.2 102.28,121.31 102.28,121.73 102.44,121.88 103.37,121.88 108.8,116.46 112.46,116.46 112.93,115.99 112.93,115.61 115.2,113.34 120.27,113.34 122.73,115.8 131.93,115.8 132.33,116.2 134.68,116.2 135.19,116.71 138.25,116.71 139.45,115.52 149.74,115.52 152.07,113.19 152.07,109.88 152.35,109.6 152.35,106.43 152.12,106.2 151.63,106.2 151.22,105.79 v1(151.16,105.79)
MCU_RGMII1_RD2_R: length 7.1
  TOP w0.132: U22.35 41.02,117.64 41.26,117.87 41.26,118.12 42.25,119.11 R111.2 42.25,119.66 42.34,119.75 44.43,119.75 R112.1 R115.2
MCU_RGMII1_RD3: length 152.1
  TOP w0.132: U34.L2 v1(151.16,108.19) ; R102.1 43.09,121.31 42.99,121.41 42.99,121.41 v1(42.67,121.73)
  L10_SIG3 w0.084: v1(42.67,121.73) 42.67,116.72 42.88,116.51 47.08,116.51 47.99,117.42 63.37,117.42 63.53,117.57 63.53,119.81 63.68,119.97 64.03,119.97 64.19,119.81 64.19,117.57 64.34,117.42 64.69,117.42 64.85,117.57 64.85,119.81 65,119.97 65.35,119.97 65.51,119.81 65.51,117.57 65.66,117.42 66.01,117.42 66.17,117.57 66.17,119.81 66.32,119.97 66.68,119.97 66.83,119.81 66.83,117.57 66.98,117.42 67.34,117.42 67.49,117.57 67.49,119.81 67.64,119.97 68,119.97 68.15,119.81 68.15,117.57 68.3,117.42 68.64,117.42 68.79,117.57 68.79,119.72 68.96,119.89 92.08,119.89 92.58,119.38 104.45,119.38 108.39,115.43 108.39,111.82 110.74,109.47 118.87,109.47 119.98,110.58 119.98,111.81 122.48,114.31 125.84,114.31 126.49,113.67 128.46,113.67 128.93,114.14 133.85,114.14 134.11,114.4 148.57,114.4 149.29,113.69 149.29,112.85 151.09,111.05 151.09,109.73 150.76,109.4 150.76,108.58 v1(151.16,108.19)
MCU_RGMII1_RD3_R: length 3.3
  TOP w0.132: R102.2 41.74,120.27 41.53,120.06 41.53,118.83 40.84,118.14 U22.36
MCU_RGMII1_RX_CTL: length 153.1
  TOP w0.132: U34.N5 v1(149.56,105.79) ; R101.1 v1(41.07,121.32)
  L10_SIG3 w0.084: v1(41.07,121.32) 41.53,120.87 41.53,115.28 41.97,114.83 47.13,114.83 48.12,115.82 78.84,115.82 80.05,117.03 80.14,117.03 80.15,117.04 89.09,117.04 89.24,117.2 89.24,118.04 89.39,118.19 89.75,118.19 89.9,118.04 89.9,117.2 90.05,117.04 90.41,117.04 90.56,117.2 90.56,118.04 90.71,118.19 91.07,118.19 91.22,118.04 91.22,117.2 91.37,117.04 91.73,117.04 91.88,117.2 91.88,118.04 92.03,118.19 92.39,118.19 92.54,118.04 92.54,117.2 92.7,117.04 93.05,117.04 93.2,117.2 93.2,118.04 93.36,118.19 93.71,118.19 93.86,118.04 93.86,117.2 94.02,117.04 94.37,117.04 94.52,117.2 94.52,118.04 94.68,118.19 95.03,118.19 95.18,118.04 95.18,117.2 95.34,117.04 95.69,117.04 95.84,117.2 95.84,118.04 96,118.19 96.35,118.19 96.51,118.04 96.51,117.2 96.66,117.04 97.01,117.04 97.17,117.2 97.17,118.04 97.32,118.19 97.67,118.19 97.83,118.04 97.83,117.2 97.98,117.04 98.33,117.04 98.49,117.2 98.49,118.04 98.64,118.19 98.99,118.19 99.15,118.04 99.15,117.2 99.3,117.04 99.65,117.04 99.81,117.2 99.81,118.04 99.96,118.19 100.32,118.19 100.47,118.04 100.47,117.2 100.62,117.04 100.98,117.04 101.13,117.2 101.13,118.04 101.28,118.19 101.64,118.19 101.79,118.04 101.79,117.2 101.94,117.04 102.51,117.04 102.66,117.2 102.66,117.6 102.81,117.76 103.17,117.76 103.32,117.6 103.32,117.2 103.47,117.04 105.06,117.04 106.17,115.93 106.17,112.27 110.19,108.25 112.89,108.25 113.04,108.1 113.04,107.89 113.19,107.74 113.55,107.74 113.7,107.89 113.7,108.1 113.85,108.25 114.21,108.25 114.36,108.1 114.36,107.89 114.51,107.74 114.87,107.74 115.02,107.89 115.02,108.1 115.17,108.25 115.53,108.25 115.68,108.1 115.68,107.89 115.83,107.74 116.19,107.74 116.34,107.89 116.34,108.1 116.49,108.25 116.85,108.25 117,108.1 117,107.89 117.15,107.74 117.51,107.74 117.66,107.89 117.66,108.1 117.81,108.25 119.38,108.25 119.71,108.58 122.32,108.58 126.03,112.29 129.64,112.29 130.07,112.73 134.16,112.73 134.59,113.16 138.15,113.16 138.79,112.52 146.58,112.52 149.95,109.15 149.95,106.25 149.74,106.04 149.74,106.04 149.56,105.86 v1(149.56,105.79)
MCU_RGMII1_RX_CTL_R: length 6.8
  TOP w0.132: U22.38 39.41,118.97 39.41,119.4 39.57,119.56 40.06,119.56 40.39,119.89 R101.2 41.11,120.48 41.53,120.9 R98.1 R99.1
MCU_RGMII1_RXC: length 153.7
  TOP w0.132: U34.M1 v1(150.36,108.99) ; R121.1 v1(43.77,115.95)
  L10_SIG3 w0.084: v1(43.77,115.95) 44.24,115.48 46.92,115.48 48.24,116.81 60.19,116.81 60.42,116.59 60.85,116.59 61.08,116.81 61.51,116.81 61.74,116.59 62.17,116.59 62.4,116.81 62.84,116.81 63.06,116.59 63.5,116.59 63.72,116.81 64.16,116.81 64.38,116.59 64.82,116.59 65.04,116.81 65.48,116.81 65.7,116.59 66.14,116.59 66.36,116.81 66.8,116.81 67.02,116.59 67.46,116.59 67.68,116.81 68.12,116.81 68.34,116.59 68.78,116.59 69,116.81 69.4,116.81 69.55,116.96 69.55,119.08 69.71,119.24 70.06,119.24 70.21,119.08 70.21,116.96 70.37,116.81 70.72,116.81 70.87,116.96 70.87,119.08 71.03,119.24 71.38,119.24 71.53,119.08 71.53,116.96 71.69,116.81 72.04,116.81 72.2,116.96 72.2,119.08 72.35,119.24 72.7,119.24 72.86,119.08 72.86,118.8 73.01,118.65 73.65,118.65 73.81,118.5 73.81,118.14 73.65,117.99 73.01,117.99 72.86,117.84 72.86,116.96 73.01,116.81 78.8,116.81 79.02,117.03 79.02,118.73 79.13,118.83 79.78,118.83 79.94,118.68 79.94,117.94 80.09,117.79 80.44,117.79 80.6,117.94 80.6,118.68 80.75,118.83 81.11,118.83 81.26,118.68 81.26,117.94 81.41,117.79 81.77,117.79 81.92,117.94 81.92,118.68 82.07,118.83 82.43,118.83 82.58,118.68 82.58,117.94 82.73,117.79 83.09,117.79 83.24,117.94 83.24,118.68 83.39,118.83 83.75,118.83 83.9,118.68 83.9,117.94 84.05,117.79 84.41,117.79 84.56,117.94 84.56,118.68 84.71,118.83 85.07,118.83 85.22,118.68 85.22,117.94 85.37,117.79 85.73,117.79 85.88,117.94 85.88,118.68 86.03,118.83 86.39,118.83 86.54,118.68 86.54,117.94 86.69,117.79 87.05,117.79 87.2,117.94 87.2,118.68 87.35,118.83 87.71,118.83 87.86,118.68 87.86,117.94 88.01,117.79 88.37,117.79 88.52,117.94 88.52,118.68 88.67,118.83 104.13,118.83 107.54,115.42 107.54,115.42 107.78,115.18 107.78,114.79 107.63,114.64 107.42,114.64 107.26,114.49 107.26,114.13 107.42,113.98 107.63,113.98 107.78,113.83 107.78,113.47 107.63,113.32 107.42,113.32 107.26,113.17 107.26,112.81 107.42,112.66 107.63,112.66 107.78,112.51 107.78,111.57 110.49,108.86 119.12,108.86 119.8,109.54 120.02,109.54 120.16,109.41 120.37,109.41 120.62,109.66 120.62,109.88 120.49,110.01 120.49,110.23 120.75,110.49 122.43,110.49 122.67,110.73 122.89,110.73 123.14,110.48 123.35,110.48 123.61,110.73 123.61,110.95 123.36,111.2 123.36,111.41 123.61,111.67 123.82,111.67 124.07,111.42 124.29,111.42 124.54,111.67 124.54,111.88 124.29,112.13 124.29,112.35 124.85,112.9 129.49,112.9 129.85,113.27 133.84,113.27 134.36,113.79 146.66,113.79 150.36,110.1 v1(150.36,108.99)
MCU_RGMII1_RXC_R: length 1.7
  TOP w0.132: U22.32 41.56,116.14 41.74,115.95 R121.2
MCU_RGMII1_TD0: length 140.1
  TOP w0.132: v1(43.8,111.65) 43.19,111.65 42.46,112.37 42.46,112.85 41.17,114.14 U22.28
  L10_SIG3 w0.084: v1(152.14,122.96) 152.6,122.5 152.6,121.7 151.52,120.62 151.49,120.62 151.13,120.27 139.46,120.27 138.98,120.75 120.48,120.75 119.55,119.82 113.53,119.82 107.85,125.51 85.71,125.51 84.97,124.76 43.42,124.76 42.42,123.76 40.57,123.76 38.66,121.85 38.66,119.67 40.16,118.17 40.16,114.92 41.92,113.16 42.96,113.16 43.37,112.75 43.37,112.07 v1(43.8,111.65)
  BOTTOM w0.132: RA7.4 152.78,122.32 v1(152.14,122.96)
MCU_RGMII1_TD0_R: length 15.9
  TOP w0.132: U34.M5 v1(150.36,105.79)
  L05_SIG2 w0.084: v1(152.14,118.13) 152.14,117.68 151.92,117.45 151.92,111.95 150.76,110.8 150.76,106.43 150.77,106.43 150.77,106.2 v1(150.36,105.79)
  BOTTOM w0.132: v1(152.14,118.13) 152.78,118.77 RA7.5
MCU_RGMII1_TD1: length 138
  TOP w0.132: U22.27 41.11,113.64 42.07,112.68 42.07,112.11 v1(42.48,111.7)
  L10_SIG3 w0.084: v1(152.14,122.05) 152.14,121.89 151.33,121.08 149.04,121.08 148.21,121.91 125.08,121.91 124.62,122.36 120.11,122.36 119.96,122.52 119.96,123.32 119.81,123.47 119.45,123.47 119.3,123.32 119.3,122.52 119.14,122.36 118.79,122.36 118.64,122.52 118.64,123.32 118.48,123.47 118.13,123.47 117.98,123.32 117.98,122.52 117.82,122.36 114.83,122.36 112.91,124.28 109.88,124.28 108.15,126.01 85.56,126.01 84.78,125.22 41.38,125.22 38.2,122.04 38.2,119.48 39.7,117.98 39.7,114.48 v1(42.48,111.7)
  BOTTOM w0.132: RA7.3 v1(152.14,122.05)
MCU_RGMII1_TD1_R: length 17.6
  TOP w0.132: U34.M4 v1(150.36,106.59)
  L05_SIG2 w0.084: v1(152.14,119.05) 151.68,119.51 150.81,119.51 150.42,119.11 150.42,115.58 149.34,114.5 149.34,112.62 149.17,112.45 149.17,109.6 149.16,107.23 149.39,107 149.4,107 149.95,107 v1(150.36,106.59)
  BOTTOM w0.132: RA7.6 v1(152.14,119.05)
MCU_RGMII1_TD2: length 141.2
  TOP w0.132: v1(41.56,111.7) 41.56,112.62 41.04,113.14 U22.26
  L10_SIG3 w0.084: v1(151,122.96) 151.46,122.5 151.46,121.86 151.14,121.54 149.23,121.54 148.4,122.36 126.72,122.36 124.18,124.9 123.27,124.9 123.12,124.75 123.12,123.97 122.97,123.82 122.61,123.82 122.46,123.97 122.46,124.75 122.31,124.9 121.95,124.9 121.8,124.75 121.8,123.97 121.65,123.82 121.29,123.82 121.14,123.97 121.14,124.75 120.98,124.9 109.9,124.9 108.34,126.47 40.78,126.47 36.94,122.63 36.94,119.71 38.66,118 38.66,113.17 39.67,112.15 41.1,112.15 v1(41.56,111.7)
  BOTTOM w0.132: RA7.2 151.64,122.32 v1(151,122.96)
MCU_RGMII1_TD2_R: length 14.4
  TOP w0.132: U34.M3 v1(150.36,107.39)
  L05_SIG2 w0.084: v1(151,118.13) 151,115.44 150.38,114.81 150.38,112.32 149.58,111.52 149.58,108.72 149.96,108.33 149.96,107.78 v1(150.36,107.39)
  BOTTOM w0.132: RA7.7 151.64,118.77 v1(151,118.13)
MCU_RGMII1_TD3: length 142
  TOP w0.132: v1(40.58,111.7) U22.25
  L10_SIG3 w0.084: v1(40.58,111.7) 39.11,111.7 37.64,113.17 37.64,118.37 36.49,119.52 36.49,122.44 36.49,122.82 40.59,126.92 100.83,126.92 102.17,128.26 112.42,128.26 113.24,127.44 118.31,127.44 118.46,127.29 118.46,126.25 118.61,126.1 118.97,126.1 119.12,126.25 119.12,127.29 119.27,127.44 119.63,127.44 119.78,127.29 119.78,126.25 119.93,126.1 120.29,126.1 120.44,126.25 120.44,127.29 120.59,127.44 120.95,127.44 121.1,127.29 121.1,126.25 121.25,126.1 121.61,126.1 121.76,126.25 121.76,127.29 121.91,127.44 125.2,127.44 129.82,122.82 150.23,122.82 v1(151,122.05)
  BOTTOM w0.132: RA7.1 v1(151,122.05)
MCU_RGMII1_TD3_R: length 13.4
  TOP w0.132: U34.M2 v1(150.36,108.19)
  L05_SIG2 w0.084: v1(150.36,108.19) 150.36,108.45 149.96,108.84 149.96,110.78 150.69,111.5 150.69,114.12 151.46,114.9 151.46,118.59 v1(151,119.05)
  BOTTOM w0.132: RA7.8 v1(151,119.05)
MCU_RGMII1_TX_CTL: length 145.3
  TOP w0.132: U22.37 40.52,118.89 v1(41.07,119.44)
  L10_SIG3 w0.084: v1(41.07,119.44) 40.61,119.9 40.61,121.51 41.48,122.38 43.93,122.38 44.08,122.22 44.08,120.39 44.23,120.23 44.95,120.23 45.1,120.38 45.1,122.12 45.36,122.38 45.85,122.38 46.11,122.12 46.11,120.41 46.28,120.23 47,120.23 47.16,120.39 47.16,122.61 47.35,122.8 47.62,122.8 47.78,122.64 47.78,121.98 47.93,121.83 48.29,121.83 48.44,121.98 48.44,122.64 48.59,122.8 48.91,122.8 49.22,122.49 53.73,122.49 54.04,122.8 104.79,122.8 105.51,122.08 105.72,122.08 106.23,122.58 106.44,122.58 106.69,122.33 106.69,122.11 106.19,121.61 106.19,121.39 106.44,121.14 106.66,121.14 107.16,121.65 107.38,121.65 107.63,121.4 107.63,121.18 107.12,120.68 107.12,120.46 109.21,118.37 109.65,118.37 109.8,118.52 109.8,118.97 109.95,119.12 110.31,119.12 110.46,118.97 110.46,118.52 110.61,118.37 113.02,118.37 113.84,117.55 113.84,116.17 115.51,114.5 118.37,114.5 118.75,114.88 118.75,115.09 118,115.85 118,116.06 118.25,116.31 118.47,116.31 119.22,115.56 119.44,115.56 119.69,115.81 119.69,116.03 118.96,116.75 118.96,116.97 119.12,117.12 121.24,117.12 121.39,117.27 121.39,117.81 121.55,117.96 121.9,117.96 122.05,117.81 122.05,117.27 122.21,117.12 122.56,117.12 122.72,117.27 122.72,117.81 122.87,117.96 123.22,117.96 123.38,117.81 123.38,117.27 123.53,117.12 123.88,117.12 124.04,117.27 124.04,117.81 124.19,117.96 124.54,117.96 124.7,117.81 124.7,117.27 124.85,117.12 131.15,117.12 131.37,117.33 131.37,117.55 131.12,117.8 131.12,118.01 131.37,118.26 131.59,118.26 131.83,118.02 132.05,118.02 132.27,118.24 135.51,118.24 135.67,118.07 137.35,118.07 137.53,117.89 139.82,117.89 139.97,117.74 139.97,117.31 140.12,117.16 140.43,117.16 140.58,117.31 140.58,117.74 140.73,117.89 141.45,117.89 141.61,117.74 141.61,117.37 141.76,117.22 142.55,117.22 142.71,117.06 143.26,117.06 143.41,117.21 143.41,117.46 143.56,117.61 143.92,117.61 144.07,117.46 144.07,117.21 144.22,117.06 144.58,117.06 144.73,117.21 144.73,117.46 144.88,117.61 145.24,117.61 145.39,117.46 145.39,117.21 145.54,117.06 146.09,117.06 146.48,116.66 v1(148.4,116.66)
  BOTTOM w0.132: R439.2 v1(148.4,116.66)
MCU_RGMII1_TX_CTL_R: length 10.3
  TOP w0.132: U34.N4 v1(149.56,106.59)
  L05_SIG2 w0.084: v1(148.78,113.29) 148.78,109.71 148.36,109.3 148.36,107.23 148.37,107.23 148.37,107.16 148.54,106.98 148.93,106.98 149.32,106.59 v1(149.56,106.59)
  BOTTOM w0.132: R439.1 148.4,113.67 v1(148.78,113.29)
MCU_RGMII1_TXC: length 148.8
  TOP w0.132: v1(41.84,114.1) 41.31,114.64 U22.29
  L10_SIG3 w0.084: v1(41.84,114.1) 40.77,115.18 40.77,118.43 40.01,119.19 40.01,122.34 40.79,123.13 43.16,123.13 43.44,123.41 98.89,123.41 100.39,124.9 107.6,124.9 115.21,117.28 118.22,117.28 119.2,118.27 119.42,118.27 119.68,118.01 119.89,118.01 120.15,118.26 120.15,118.48 119.89,118.73 119.89,118.95 121.06,120.13 121.34,120.13 121.5,119.98 121.5,118.81 121.65,118.66 122,118.66 122.16,118.81 122.16,119.98 122.31,120.13 122.66,120.13 122.82,119.98 122.82,118.81 122.97,118.66 123.32,118.66 123.48,118.81 123.48,119.98 123.63,120.13 123.99,120.13 124.14,119.98 124.14,118.81 124.29,118.66 124.65,118.66 124.8,118.81 124.8,119.98 124.95,120.13 125.31,120.13 125.46,119.98 125.46,117.98 125.58,117.86 125.99,117.86 126.12,117.98 126.12,119.98 126.27,120.13 126.63,120.13 126.78,119.98 126.78,117.98 126.91,117.86 127.31,117.86 127.44,117.98 127.44,119.98 127.59,120.13 127.95,120.13 128.1,119.98 128.1,117.98 128.23,117.86 128.63,117.86 128.76,117.98 128.76,119.98 128.91,120.13 130.02,120.13 131.05,119.1 136.55,119.1 136.97,118.68 137.6,118.68 137.78,118.5 147.58,118.5 v1(149.42,116.66)
  BOTTOM w0.132: R438.2 v1(149.42,116.66)
MCU_RGMII1_TXC_R: length 7
  TOP w0.132: v1(149.8,113.29) 149.8,109.23 U34.N1
  BOTTOM w0.132: v1(149.8,113.29) 149.8,114.77 R438.1
MCU_RTCK: length 2.5
  BOTTOM w0.132: R617.2 J34.9
MCU_SAFETY_ERRORZ: length 32.8
  TOP w0.132: U34.W3 v1(143.96,107.39)
  L05_SIG2 w0.084: v1(143.96,107.39) 144.36,107.8 144.36,109.6 144.37,112.12 140.95,115.54 137.56,115.54 136.01,117.09 121.67,117.09 v1(120.59,116.01)
  BOTTOM w0.132: TP40.1 v1(120.59,116.01)
MCU_SPI0_CLK: length 155
  L03_SIG1 w0.084: v1(117.81,116.63) 117.81,114.36 117.3,113.85 117.3,109.56 117.76,109.09 117.76,99.35 112.88,94.46 112.88,60.96 110.11,58.2 110.11,47.31 111.43,45.99 111.43,36.76 111.22,36.54 111.22,30.26 126.52,14.96 139.02,14.96 v1(140.24,16.18)
  L05_SIG2 w0.084: v1(142.81,116.6) 142.06,115.85 137.69,115.85 135.43,118.11 119.29,118.11 v1(117.81,116.63)
  BOTTOM w0.132: R432.1 142.54,115.89 142.54,116.33 v1(142.81,116.6) ; U111.16 v1(140.24,16.18)
MCU_SPI0_CLK/BOOTMODE6: length 7.7
  TOP w0.132: v1(143.89,110.55) 143.56,110.22 U34.Y1
  BOTTOM w0.132: R432.2 R442.2 143.38,111.07 v1(143.89,110.55)
MCU_SPI0_CS0: length 217.5
  TOP w0.132: U34.Y4 v1(143.16,106.59)
  L10_SIG3 w0.084: v1(143.16,106.59) 143.16,106.39 142.75,105.98 142.75,105.6 142.53,105.38 142.19,105.38 141.95,105.13 141.95,104.8 141.73,104.58 136.53,104.58 135.8,103.85 134.21,103.85 133.1,102.74 129.29,102.74 128.73,102.19 125.23,102.19 122.61,99.57 121.67,99.57 121.41,99.82 120.46,99.82 120.14,99.5 118.07,99.5 115.98,97.41 115.98,85.32 115.8,85.14 99.15,68.49 77.85,68.49 72.12,62.77 72.12,23.62 74.93,20.82 75.17,20.58 75.17,15.32 77.15,13.34 79.93,13.34 81.9,11.37 136.91,11.37 139.32,13.78 v1(139.32,16.18)
  BOTTOM w0.132: U111.15 140.03,15.68 139.81,15.89 139.6,15.89 v1(139.32,16.18)
MCU_SPI0_D0/BOOTMODE7: length 227.7
  TOP w0.132: U34.Y3 v1(143.16,107.39)
  L10_SIG3 w0.084: v1(143.16,107.39) 142.75,106.98 142.75,106.43 142.52,106.2 142.14,106.2 141.96,106.02 141.96,105.64 141.72,105.4 141.72,105.4 137.17,105.4 136.88,105.69 135.15,105.69 132.72,103.25 129.36,103.25 129.13,103.02 125.5,103.02 123.06,100.58 122.05,100.58 121.79,100.33 118.46,100.33 115.67,97.54 115.67,85.44 99.03,68.8 77.72,68.8 71.82,62.89 71.82,23.5 74.86,20.45 74.86,15.2 77.03,13.03 79.8,13.03 81.77,11.06 137.03,11.06 139.76,13.79 139.76,16.31 138.72,17.35 v1(135.85,17.35)
  BOTTOM w0.132: v1(135.85,17.35) R669.2 R668.1 U111.17
MCU_SYSCLKOUT: length 29.1
  TOP w0.132: U34.AB3 v1(141.56,107.39)
  L05_SIG2 w0.084: v1(121.67,112.78) 123.55,112.78 124.41,111.91 132.98,111.91 134.63,113.56 136.84,113.56 137.5,114.22 139.66,114.22 140.06,113.83 140.06,113.17 141.96,111.26 141.96,107.8 v1(141.56,107.39)
  BOTTOM w0.132: v1(121.67,112.78) 121.35,112.46 TP43.1
MCU_TCK: length 10.9
  BOTTOM w0.132: R610.2 42.99,56.7 43.53,57.25 45.31,57.25 46.16,56.39 46.16,54.43 44.26,52.52 J34.11
MCU_TCLK: length 2.1
  BOTTOM w0.132: R615.2 43.55,55.1 43.51,55.06 R610.1 R617.1
MCU_TDI: length 2.5
  BOTTOM w0.132: R619.2 J34.3
MCU_TDIS: length 3.1
  BOTTOM w0.132: J34.4 R639.2
MCU_TDO: length 2.5
  BOTTOM w0.132: R618.2 J34.7
MCU_TEST_POR: length 18
  TOP w0.132: U34.V4 v1(144.76,106.59)
  L05_SIG2 w0.084: v1(140.65,119.05) 141.06,118.64 142.87,118.64 144.4,117.11 144.4,113.09 145.95,111.55 145.95,109.15 145.95,109.15 145.95,107.21 145.69,106.96 145.13,106.96 v1(144.76,106.59)
  BOTTOM w0.132: R428.1 v1(140.65,119.05)
MCU_TMS: length 2.5
  BOTTOM w0.132: R620.2 J34.1
MCU_TRST#: length 4.1
  BOTTOM w0.132: R641.1 R640.2 J34.2
MCU_UART_SEL: length 103.6
  TOP w0.132: R32.1 124.13,154.5 123.48,155.15 U8.6 122.09,155.15 v1(121.82,155.42)
  L05_SIG2 w0.084: v1(205.91,161.61) 206.51,162.2 206.51,164.85 200,171.35 173.45,171.35 169.58,167.49 158.06,167.49 155.58,165.01 155.58,163.65 146.32,154.39 122.84,154.39 v1(121.82,155.42)
  BOTTOM w0.132: U65.6 122.04,155.65 v1(121.82,155.42) ; U109.5 v1(205.91,161.61)
MCU_UART_SEL_IO_EXP: length 283.2
  L03_SIG1 w0.084: v1(74.29,15.44) 77.49,12.24 89.68,12.24 95.54,6.39 102.05,6.39 102.87,5.56 104.7,5.56 104.88,5.74 107.66,5.74 109.17,4.23 121.2,4.23 130.05,13.08 191.73,13.08 197.09,18.44 197.09,65.34 201.3,69.55 201.3,153 v1(206.42,158.12)
  BOTTOM w0.132: v1(206.42,158.12) 206.06,158.12 205.91,158.26 U109.8 ; U110.16 75.86,17.01 v1(74.29,15.44)
MCU_XDS110_TCK: length 29.3
  L03_SIG1 w0.084: v1(48.89,30.84) 48.43,31.31 47.18,31.31 45.71,32.77 v1(45.71,55.1)
  BOTTOM w0.132: v1(45.71,55.1) R615.1 R609.1 ; U106.35 v1(48.89,30.84)
MCU_XDS110_TDI: length 36.4
  L03_SIG1 w0.084: v1(39.96,55.06) 39.43,54.53 39.43,44.87 42.33,41.97 42.33,31.32 43.27,30.38 49.64,30.38 v1(50.09,30.84)
  BOTTOM w0.132: U106.38 v1(50.09,30.84) ; v1(39.96,55.06) R612.1 R619.1
MCU_XDS110_TDO: length 44.4
  L03_SIG1 w0.084: v1(50.09,29.92) 49.64,29.47 42.89,29.47 40.45,31.91 40.45,42.35 36.67,46.13 36.67,55.25 36.99,55.56 40.44,55.56 v1(40.94,55.06)
  BOTTOM w0.132: v1(40.94,55.06) R611.1 R618.1 ; v1(50.09,29.92) 49.65,30.37 49.65,31.02 49.69,31.07 U106.37
MCU_XDS110_TMS: length 37.7
  L03_SIG1 w0.084: v1(48.89,29.92) 47.08,29.92 46.93,29.77 43.02,29.77 41.72,31.07 41.72,41.72 37.13,46.31 v1(37.13,55.06)
  BOTTOM w0.132: v1(37.13,55.06) R613.1 R620.1 ; U106.36 49.29,31.07 49.34,31.02 49.34,30.37 v1(48.89,29.92)
MCU_XDS110_TRST#: length 26.5
  L03_SIG1 w0.084: v1(39.18,39.78) 39.18,30.99 41,29.16 50.44,29.16 51.01,29.73 v1(51.01,30.82)
  BOTTOM w0.132: R640.1 R646.1 38.43,40.53 v1(39.18,39.78) ; U106.40 50.89,30.92 50.99,30.82 v1(51.01,30.82)
MIC-GATE: length 39.7
  TOP w0.132: Q1.1 37.34,151.76 37.08,152.02 37.08,153.41 v1(37.09,153.42)
  L05_SIG2 w0.084: v1(37.09,153.42) 55.63,153.42 58.69,156.48 v1(58.69,168.94)
  BOTTOM w0.132: R338.1 v1(58.69,168.94)
MIPI_TCK: length 8.7
  TOP w0.132: U42.2 v1(108.62,74.66)
  BOTTOM w0.132: v1(108.62,74.66) 104.24,79.04 R543.1
MIPI_TDI_R: length 17.5
  TOP w0.132: v1(103.1,100.09) 102.79,100.41 101.85,101.35 94.23,101.35 93.66,100.77 93.66,98.62 94.49,97.79 95.54,97.79 95.97,97.36 R196.1
  BOTTOM w0.132: v1(103.1,100.09) 103.73,99.47 J32.5
MIPI_TDO_R: length 8.8
  TOP w0.132: R202.2 v1(94.93,95)
  L12_SIG4 w0.084: v1(94.93,95) 94.93,97.62 v1(97.28,99.97)
  BOTTOM w0.132: J32.4 v1(97.28,99.97)
MIPI_TMS_R: length 3.3
  BOTTOM w0.132: J32.2 96.7,100.47 96.63,100.55 R470.2
MIPI_TRC_CLK: length 28.3
  BOTTOM w0.132: J32.13 106.59,97.47 106.81,97.69 106.81,98.11 107.01,98.31 108.47,98.31 108.71,98.55 108.71,100.94 108.21,101.44 103.79,101.44 103.65,101.59 103.65,102.38 103.78,102.51 104.44,102.51 104.57,102.38 104.57,101.94 104.7,101.81 105.08,101.81 105.21,101.94 105.21,102.38 105.34,102.51 105.72,102.51 105.85,102.38 105.85,101.94 105.98,101.81 106.36,101.81 106.49,101.94 106.49,102.38 106.62,102.51 109.74,102.51 114.16,98.1 RA9.12
MIPI_TRC_CTL: length 25.3
  BOTTOM w0.132: RA9.13 114.03,98.6 109.85,102.78 106.85,102.78 106.72,102.91 106.72,103.14 106.58,103.27 106.21,103.27 106.08,103.14 106.08,102.91 105.94,102.78 105.57,102.78 105.44,102.91 105.44,103.14 105.3,103.27 104.93,103.27 104.8,103.14 104.8,102.91 104.66,102.78 104.29,102.78 104.15,102.91 104.15,103.14 104.02,103.27 103.65,103.27 103.51,103.14 103.51,102.91 103.38,102.78 102.84,102.78 102.71,102.65 102.71,99.86 103.47,99.1 103.47,98.72 103.29,98.54 103,98.54 102.87,98.4 102.87,96.6 103,96.47 J32.17
MIPI_TRC_DAT00: length 21
  BOTTOM w0.132: RA9.11 114.28,97.6 109.63,102.25 107.11,102.25 106.97,102.12 106.97,101.83 107.11,101.7 108.35,101.7 108.98,101.07 108.98,97.21 107.74,95.97 J32.19
MIPI_TRC_DAT01: length 27.9
  BOTTOM w0.132: RA9.10 114.24,97.1 113.79,97.55 113.5,97.55 113.21,97.85 113.21,98.3 112.8,98.7 112.57,98.7 112.44,98.57 112.44,97.78 112.31,97.65 111.94,97.65 111.79,97.79 111.79,99.72 111.5,100.01 111.31,100.01 111.1,99.8 111.1,96.5 110.92,96.32 110.33,96.32 110.14,96.5 110.14,101.37 109.67,101.84 109.43,101.84 109.3,101.71 109.3,96.98 107.79,95.47 J32.21
MIPI_TRC_DAT02: length 11.8
  BOTTOM w0.132: RA9.9 114.4,96.53 113.67,97.26 111.5,97.26 111.37,97.13 111.37,96.15 111.14,95.92 108.62,95.92 107.67,94.97 J32.23
MIPI_TRC_DAT03: length 13
  BOTTOM w0.132: J32.25 107.62,94.47 108.2,95.05 111.48,95.05 111.63,95.19 111.63,96.73 111.9,97 113.51,97 114.29,96.21 114.29,95.53 114.43,95.4 RA10.16
MIPI_TRC_DAT04: length 13.3
  BOTTOM w0.132: J32.27 107.5,93.97 108.31,94.78 111.64,94.78 111.98,95.13 111.98,96.41 112.19,96.62 113.51,96.62 113.92,96.21 113.92,95.02 114.11,94.83 RA10.15
MIPI_TRC_DAT05: length 28.2
  BOTTOM w0.132: J32.29 107.65,93.47 109.29,91.83 110.39,91.83 110.8,91.43 111.07,91.43 111.29,91.65 111.29,92.13 112.05,92.89 112.05,93.08 111.7,93.43 111.52,93.43 110.82,92.73 109.2,92.73 108.13,93.8 108.13,94.02 108.55,94.44 108.84,94.44 109.46,93.82 110.93,93.82 111.06,93.95 111.06,94.31 111.19,94.45 111.57,94.45 111.7,94.31 111.7,93.95 111.83,93.82 112.15,93.82 112.28,93.95 112.28,95.04 112.41,95.17 113.19,95.17 113.33,95.31 113.33,95.68 113.19,95.81 112.41,95.81 112.28,95.95 112.28,96.22 112.41,96.35 113.4,96.35 113.62,96.14 113.62,94.47 113.75,94.33 RA10.14
MIPI_TRC_DAT06: length 27
  BOTTOM w0.132: RA10.13 113.52,93.83 111.56,91.87 111.56,84.02 111.42,83.89 110.74,83.89 110.61,84.02 110.61,86.89 111.06,87.33 111.06,90.69 110.37,91.38 108.87,91.38 107.28,92.97 J32.31
MIPI_TRC_DAT07: length 28.4
  BOTTOM w0.132: RA10.12 113.46,93.33 111.82,91.69 111.82,83.5 111.69,83.37 110.28,83.37 110.09,83.56 110.09,84.84 109.96,84.97 109.73,84.97 109.6,85.1 109.6,85.48 109.73,85.61 109.96,85.61 110.09,85.74 110.09,86.12 109.96,86.25 109.73,86.25 109.6,86.38 109.6,86.76 109.73,86.89 109.96,86.89 110.09,87.02 110.09,89.74 109.86,89.97 109.86,90.18 110.09,90.41 110.09,90.74 109.86,90.97 108.85,90.97 107.35,92.47 J32.33
MIPI_TRC_DAT08: length 27.1
  BOTTOM w0.132: J32.35 107.37,91.97 109.19,90.15 109.19,84.01 110.1,83.1 112.59,83.1 112.72,83.24 112.72,84.23 112.08,84.86 112.08,91.58 113.34,92.83 RA10.11
MIPI_TRC_DAT09: length 28
  BOTTOM w0.132: J32.37 107.44,91.47 108.92,89.98 108.92,83.9 109.99,82.84 113.57,82.84 113.73,83 113.73,83.6 112.35,84.97 112.35,91.47 113.21,92.33 RA10.10
MIPI_TRC_DAT10: length 27.1
  BOTTOM w0.132: J32.39 107.16,90.97 108.66,89.46 108.66,83.79 109.88,82.57 113.81,82.57 114.03,82.79 114.03,83.67 112.61,85.08 112.61,90.45 113.94,91.77 RA10.9
MIPI_TRC_DAT11: length 28
  BOTTOM w0.132: RA11.16 113.11,90.57 112.88,90.34 112.88,85.36 114.9,83.34 114.9,82.44 114.67,82.22 109.04,82.22 108.39,82.86 108.39,89.06 106.98,90.47 J32.41
MIPI_TRC_DAT12: length 27.1
  BOTTOM w0.132: J32.43 106.56,89.97 108.13,88.39 108.13,82.74 108.92,81.95 114.88,81.95 115.16,82.23 115.16,83.45 113.14,85.47 113.14,89.57 113.58,90.01 RA11.15
MIPI_TRC_DAT13: length 28
  BOTTOM w0.132: RA11.14 113.54,89.51 113.4,89.38 113.4,85.72 115.7,83.43 115.7,81.78 115.24,81.32 108.67,81.32 107.87,82.13 107.87,88.17 106.57,89.47 J32.45
MIPI_TRC_DAT14: length 27.4
  BOTTOM w0.132: J32.47 106.5,88.97 107.6,87.86 107.6,82.02 108.63,80.99 115.49,80.99 115.96,81.46 115.96,83.66 113.67,85.95 113.67,88.55 114.13,89.01 RA11.13
MIPI_TRC_DAT15: length 28
  BOTTOM w0.132: RA11.12 114.16,88.51 113.93,88.28 113.93,86.08 116.27,83.75 116.27,80.99 115.63,80.35 108.42,80.35 107.34,81.43 107.34,87.65 106.52,88.47 J32.49
MIPI_TRC_DAT16: length 27.4
  BOTTOM w0.132: RA11.11 114.48,88.01 114.2,87.73 114.2,86.19 116.53,83.86 116.53,80.86 115.76,80.08 108.28,80.08 107.07,81.29 107.07,87.29 106.39,87.97 J32.51
MIPI_TRC_DAT17: length 28.2
  BOTTOM w0.132: J32.53 106.4,87.47 106.81,87.06 106.81,80.22 107.57,79.46 115.92,79.46 116.95,80.48 116.95,83.82 114.46,86.3 114.46,87.31 114.66,87.51 RA11.10
MIPI_TRC_DAT18: length 27.4
  BOTTOM w0.132: RA11.9 115.1,86.36 117.22,84.25 117.22,80.33 116.08,79.19 107.11,79.19 106.55,79.76 106.55,86.69 106.27,86.97 J32.55
MIPI_TRC_DAT19: length 25.6
  BOTTOM w0.132: RA9.16 113.59,100.16 108.59,105.16 102.4,105.16 100.94,103.71 100.94,96.64 100.78,96.47 J32.18
MIPI_TRC_DAT20: length 25.2
  BOTTOM w0.132: J32.20 100.68,95.97 101.21,96.5 101.21,103.16 101.89,103.85 101.9,103.85 102.59,104.53 108.84,104.53 113.78,99.6 RA9.15
MIPI_TRC_DAT21: length 27.4
  BOTTOM w0.132: J32.22 100.93,95.47 101.47,96.01 101.47,103.06 102,103.58 102.98,103.58 103.11,103.72 103.11,104 103.24,104.13 103.62,104.13 103.75,104 103.75,103.72 103.88,103.58 104.26,103.58 104.39,103.72 104.39,104 104.52,104.13 104.9,104.13 105.03,104 105.03,103.72 105.16,103.58 105.54,103.58 105.67,103.72 105.67,104 105.8,104.13 106.18,104.13 106.31,104 106.31,103.72 106.44,103.58 109.42,103.58 113.9,99.1 RA9.14
MIPI_TRC_DAT22: length 28.5
  L10_SIG3 w0.084: v1(115.7,102.64) 115.1,102.64 114.87,102.87 110.55,102.87 108.48,100.8 106.58,100.8 105.26,99.48 105.04,99.48 104.87,99.65 104.66,99.65 104.4,99.4 104.4,99.19 104.58,99.01 104.58,98.8 103.37,97.59 103.15,97.59 102.5,98.24 102.29,98.24 102.04,97.99 102.04,97.77 102.68,97.12 102.68,96.91 102.43,96.65 102.22,96.65 101.57,97.3 101.35,97.3 101.1,97.05 101.1,96.84 101.75,96.19 101.75,95.97 101.4,95.62 v1(101.4,94.49)
  BOTTOM w0.132: J32.24 100.92,94.97 v1(101.4,94.49) ; R463.2 118.03,102.88 117.53,103.38 116.43,103.38 v1(115.7,102.64)
MIPI_TRC_DAT23: length 28.4
  L10_SIG3 w0.084: v1(115.7,101.73) 115.24,101.73 115.05,101.92 110.35,101.92 108.24,99.81 106.09,99.81 101.85,95.57 101.85,94.36 101.09,93.6 99.89,93.6 99.73,93.75 99.73,94.51 99.58,94.67 99.23,94.67 99.07,94.51 99.07,93.75 98.92,93.6 98.55,93.6 v1(97.68,94.47)
  BOTTOM w0.132: J32.26 v1(97.68,94.47) ; R466.2 116.27,101.85 116.14,101.73 v1(115.7,101.73)
MIPI_TRST#_R: length 3.5
  BOTTOM w0.132: J32.8 96.68,98.97 96.11,98.4 R475.2
MMC0_CALPAD: length 12.7
  TOP w0.132: U34.D24 v1(156.76,89.79)
  L03_SIG1 w0.084: v1(156.76,89.79) 156.36,90.18 155.79,90.18 155.56,89.95 155.56,85.64 157.23,83.97 157.23,82.31 v1(158.37,81.17)
  BOTTOM w0.132: R535.1 158.24,81.04 v1(158.37,81.17)
MMC0_CLK: length 32.3
  TOP w0.132: v1(162.18,50.36) 161.78,50.36 161.68,50.26 U51.M6
  L03_SIG1 w0.084: v1(160.41,70.57) 161.16,71.32 162.89,71.32 166.38,67.83 166.38,63.19 167.49,62.08 167.49,57.94 166.26,56.71 163.51,56.71 163.07,56.26 163.07,55.24 163.77,54.55 163.77,51.08 163.04,50.36 v1(162.18,50.36)
  BOTTOM w0.132: RA14.14 v1(160.41,70.57)
MMC0_CMD: length 31.3
  TOP w0.132: U51.M5 v1(161.18,50.36)
  L03_SIG1 w0.084: v1(161.18,50.36) 161.59,50.76 163.01,50.76 163.46,51.21 163.46,54.42 162.76,55.12 162.76,56.39 163.39,57.01 165.85,57.01 166.62,57.78 166.62,62.51 166.07,63.06 166.07,67.71 162.79,70.99 161.83,70.99 v1(161.41,70.57)
  BOTTOM w0.132: R625.2 161.38,50.16 v1(161.18,50.36) ; RA14.12 v1(161.41,70.57)
MMC0_DAT0: length 26
  TOP w0.132: U51.A3 160.18,58.38 159.07,59.5 v1(159.07,59.55) R264.2
  L03_SIG1 w0.084: v1(162.41,70.57) 162.78,70.57 165.42,67.93 165.42,59.61 164.04,58.23 160.39,58.23 v1(159.07,59.55)
  BOTTOM w0.132: RA14.10 v1(162.41,70.57)
MMC0_DAT1: length 21.7
  TOP w0.132: U51.A4 160.49,55.51 160.49,58.45 160.21,58.73 v1(160.21,59.55) R265.2
  L03_SIG1 w0.084: v1(160.21,59.55) 160.83,58.93 161.61,58.93 161.76,59.08 161.76,59.39 162.92,60.55 162.92,63.06 158.75,67.23 158.75,69.97 v1(159.35,70.57)
  BOTTOM w0.132: RA14.16 v1(159.35,70.57)
MMC0_DAT2: length 19.4
  TOP w0.132: R267.2 v1(162.5,59.55) 161.18,58.24 U51.A5
  L03_SIG1 w0.084: v1(162.5,59.55) 163.26,60.32 163.26,63.15 159.67,66.74 159.67,69.34 v1(159.35,69.66)
  BOTTOM w0.132: RA14.15 159.91,70.22 v1(159.35,69.66)
MMC0_DAT3: length 28.4
  TOP w0.094: 159.44,56.32 159.44,55.06 U51.B2
  TOP w0.132: R262.2 v1(156.78,59.55) 159.44,56.89 159.44,56.32
  L03_SIG1 w0.084: v1(165.1,71.36) 164.53,71.93 159.96,71.93 159.7,71.93 158.32,70.55 158.14,70.37 158.14,66.98 160.4,64.72 160.4,63.17 v1(156.78,59.55)
  BOTTOM w0.132: R533.2 v1(165.1,71.36)
MMC0_DAT4: length 26.7
  TOP w0.094: 159.92,56.32 159.93,56.32 159.93,55.08 U51.B3
  TOP w0.132: R263.2 v1(157.92,59.55) 159.92,57.55 159.92,56.32
  L03_SIG1 w0.084: v1(161.35,69.66) 160.73,69.04 160.73,66.11 163.7,63.14 163.7,60.33 162.9,59.52 162.9,59.27 162.26,58.62 160.56,58.62 159.8,59.38 159.8,59.78 159.51,60.07 158.45,60.07 v1(157.92,59.55)
  BOTTOM w0.132: v1(161.35,69.66) 161.91,70.22 RA14.11
MMC0_DAT5: length 28.1
  TOP w0.094: U51.B4 160.93,55.06 160.93,56.31 160.91,56.32
  TOP w0.132: R266.2 v1(161.35,59.55) 160.91,59.1 160.91,56.32
  L03_SIG1 w0.084: v1(166.12,71.36) 165.62,70.87 163.78,70.87 163.01,71.63 159.83,71.63 158.45,70.24 158.45,67.11 162.62,62.93 162.62,60.81 v1(161.35,59.55)
  BOTTOM w0.132: R532.2 v1(166.12,71.36)
MMC0_DAT6: length 19.9
  TOP w0.094: 161.45,56.32 161.44,56.32 161.44,55.08 U51.B5
  TOP w0.132: R268.2 v1(163.64,59.55) 161.45,57.36 161.45,56.32
  L03_SIG1 w0.084: v1(162.41,69.66) 161.65,68.89 161.65,65.63 164.08,63.19 164.08,59.99 v1(163.64,59.55)
  BOTTOM w0.132: RA14.9 162.98,70.22 v1(162.41,69.66)
MMC0_DAT7: length 22.8
  TOP w0.094: 162.43,56.32 162.43,55.18 162.31,55.06 161.93,55.06 U51.B6
  TOP w0.132: 162.43,56.32 162.43,57.2 v1(164.78,59.55) R269.2
  L03_SIG1 w0.084: v1(164.78,59.55) 164.78,68.14 162.81,70.1 160.8,70.1 v1(160.35,69.66)
  BOTTOM w0.132: v1(160.35,69.66) 160.91,70.22 RA14.13
MMC0_DS: length 21.5
  TOP w0.094: v1(162.05,52.07) 161.43,52.07 U51.H5
  TOP w0.132: R253.2 159.27,62.45 159.7,62.87 v1(159.7,64.01)
  L03_SIG1 w0.084: v1(162.05,52.07) 161.65,51.66 159.28,51.66 155.94,55.01 155.94,60.24 v1(159.7,64.01)
MMC0_VCTRL_TP: length 19.7
  TOP w0.132: U34.D23 v1(156.76,90.59)
  BOTTOM w0.122: 159.77,88.58 157.35,88.58 157.15,88.79 157.15,90.2 v1(156.76,90.59)
  BOTTOM w0.132: TP59.1 171.47,83.73 171.42,83.73 170.29,84.87 165.08,84.87 161.36,88.58 159.77,88.58
MMC1_CALPAD: length 11.9
  TOP w0.132: U34.F23 v1(155.16,90.59)
  L03_SIG1 w0.084: v1(155.16,90.59) 154.75,90.18 154.75,89.15 155.19,88.71 155.19,85.57 155.83,84.94 155.83,82.56 v1(157.23,81.17)
  BOTTOM w0.132: R536.1 v1(157.23,81.17)
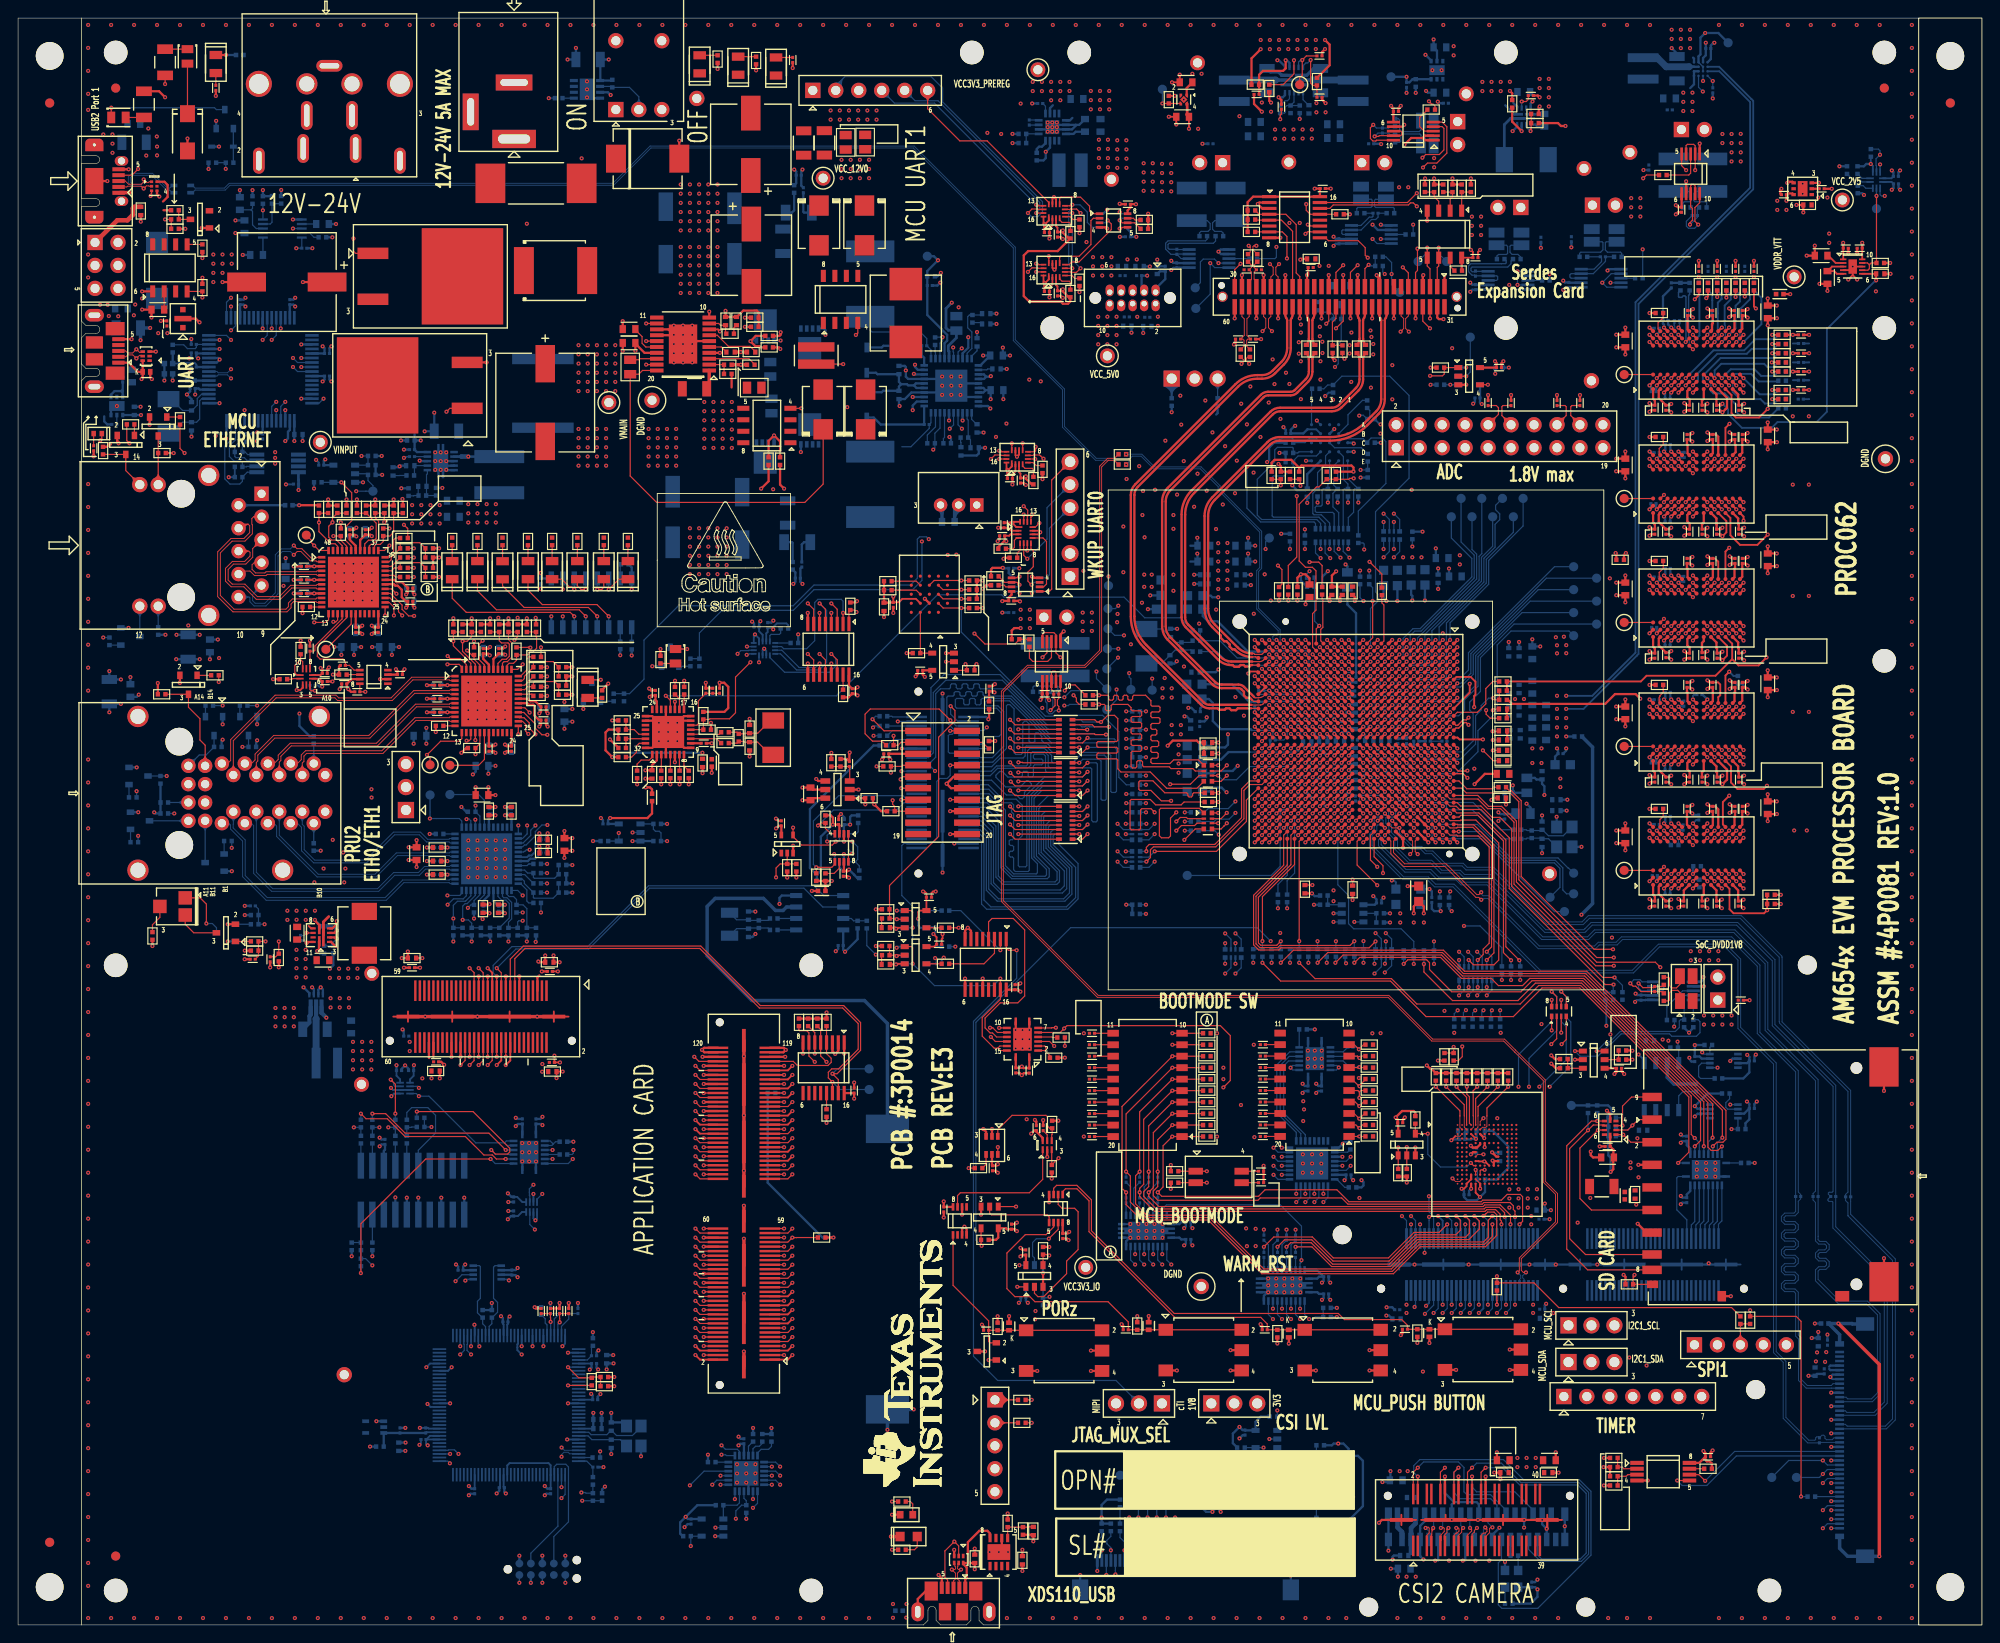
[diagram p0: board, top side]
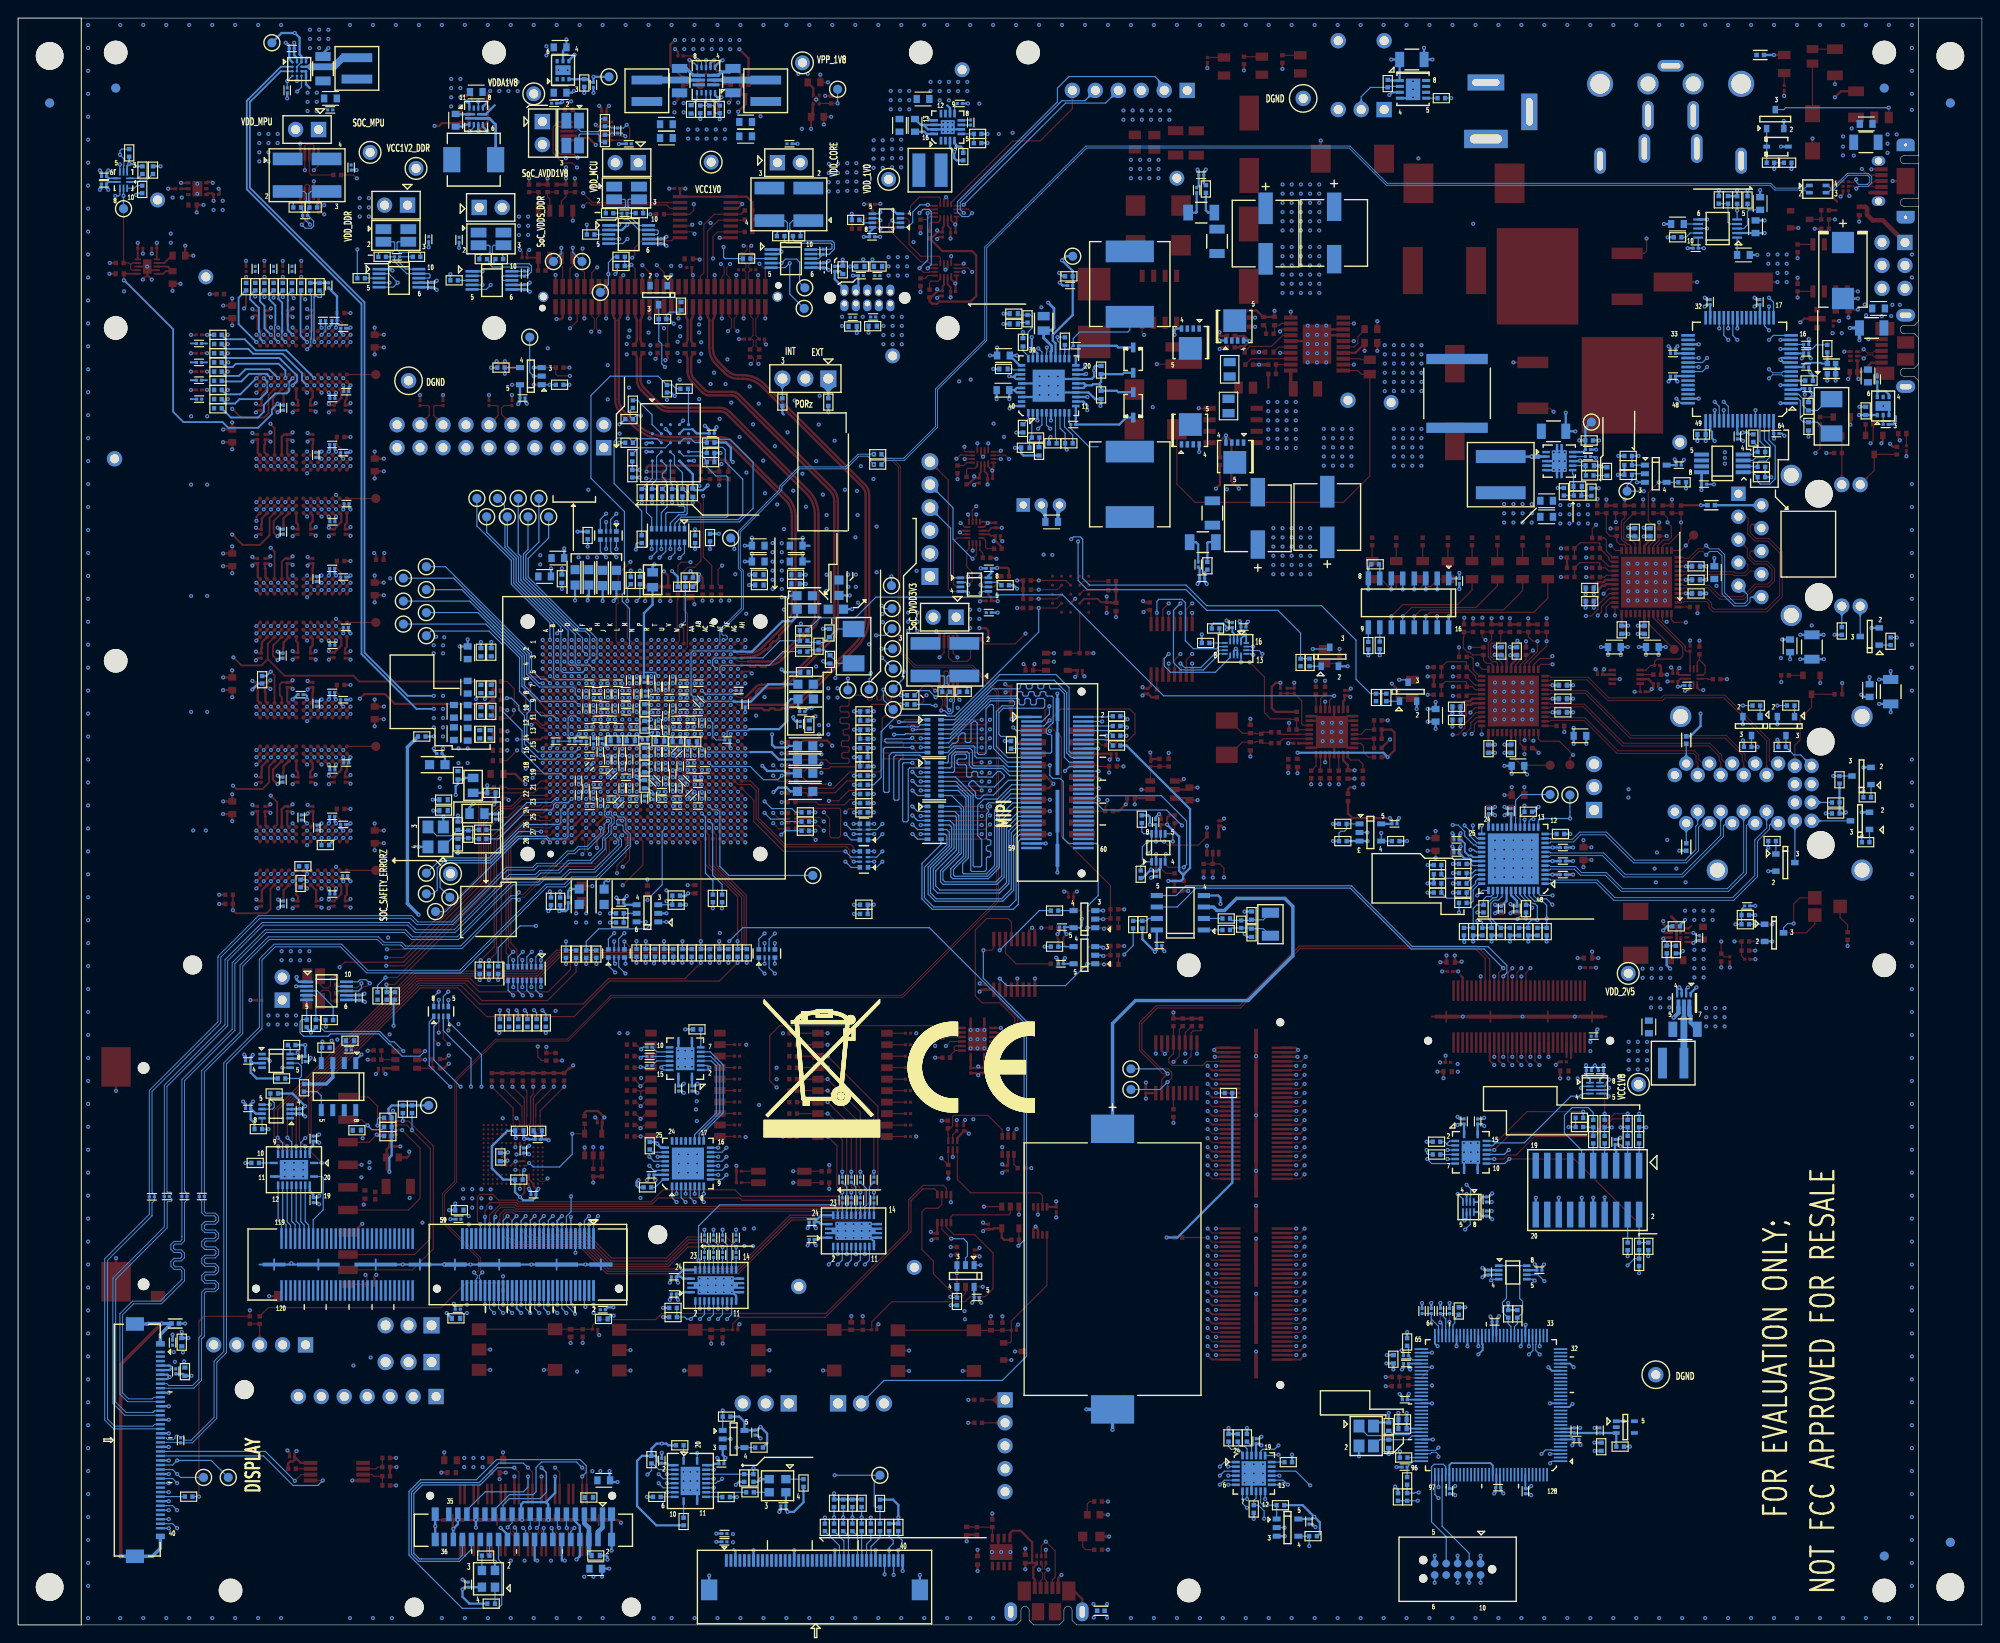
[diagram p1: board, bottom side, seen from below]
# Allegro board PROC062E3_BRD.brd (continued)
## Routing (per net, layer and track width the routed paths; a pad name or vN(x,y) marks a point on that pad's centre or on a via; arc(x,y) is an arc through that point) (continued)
MMC1_CLK: length 43.2
  TOP w0.132: J17.5 173.99,45.91 172.72,47.18 172.72,52.77 v1(174.7,54.75) U47.8
  L05_SIG2 w0.084: v1(164.08,71.36) 167.75,67.69 169.67,67.69 171.76,65.6 171.76,54.78 172.82,53.72 174.03,53.72 174.7,54.39 v1(174.7,54.75)
  BOTTOM w0.132: R534.1 v1(164.08,71.36)
MMC1_CLK_R: length 23.6
  TOP w0.132: U34.C27 v1(157.56,87.39)
  L03_SIG1 w0.084: v1(157.56,87.39) 161.55,87.39 162.78,86.16 162.78,80.23 v1(159.89,77.34)
  BOTTOM w0.132: v1(159.89,77.34) 161.67,77.34 164.08,74.93 R534.2
MMC1_CMD: length 49.2
  TOP w0.132: U47.1 v1(177.5,54.25) 178.35,53.41 J17.2 ; U34.C28 v1(157.56,86.59)
  L05_SIG2 w0.084: v1(157.56,86.59) 157.14,86.18 157.14,84.99 158.83,83.31 162.26,83.31 173.27,72.3 173.27,57.77 176.78,54.25 v1(177.5,54.25)
  BOTTOM w0.132: R616.2 177.34,54.09 v1(177.5,54.25)
MMC1_D0: length 68.1
  TOP w0.132: U47.7 175.36,55.32 174.19,55.32 v1(173.61,54.74) 171.58,52.7 171.58,42.74 173.33,40.99 J17.7 ; U34.D28 v1(156.76,86.59)
  L05_SIG2 w0.084: v1(173.61,54.74) 172.96,55.38 172.96,72.18 162.14,83 158.7,83 158.38,83.32 156.76,84.95 v1(156.76,86.59)
  BOTTOM w0.132: R607.2 v1(173.61,54.74)
MMC1_D1: length 72.4
  TOP w0.132: U34.E27 v1(155.96,87.39) ; J17.8 173.56,39.29 171.26,41.59 171.26,53.02 173.99,55.75 v1(174.63,55.75) U47.6
  L05_SIG2 w0.084: v1(155.96,87.39) 156.36,86.98 156.36,84.91 162,79.27 164.12,79.27 172.66,70.73 172.66,54.75 173.08,54.33 173.78,54.33 174.09,54.65 174.09,55.22 v1(174.63,55.75)
  BOTTOM w0.132: R606.2 v1(174.63,55.75)
MMC1_D2: length 52.7
  TOP w0.132: U34.D26 v1(156.76,88.19) ; J17.9 178.43,58.41 177.43,57.41 v1(177.43,55.25) U47.3
  L05_SIG2 w0.084: v1(156.76,88.19) 157.16,87.78 157.85,87.78 158.31,87.32 161.28,87.32 173.88,74.72 173.88,58.02 176.65,55.25 v1(177.43,55.25)
  BOTTOM w0.132: R608.2 177.29,56.12 177.43,55.99 v1(177.43,55.25)
MMC1_D3: length 52.4
  TOP w0.132: U47.2 178,54.75 v1(178.52,55.27) 179.16,55.91 J17.1 ; U34.D27 v1(156.76,87.39)
  L05_SIG2 w0.084: v1(156.76,87.39) 157.15,87 161.17,87 173.57,74.6 173.57,57.9 176.62,54.85 178.1,54.85 v1(178.52,55.27)
  BOTTOM w0.132: R614.2 176.99,54.81 178.06,54.81 v1(178.52,55.27)
MMC1_SD_EN: length 164.1
  TOP w0.132: v1(149.25,151.28) 148.97,151.56 148.97,152.4 148.21,153.16 144.91,153.16 144.58,153.49 U7.9
  L05_SIG2 w0.084: v1(149.25,151.28) 149.91,150.62 176.15,150.62 178.18,152.65 196.04,152.65 201.85,146.85 201.85,68.63 197.23,64.01 186.56,64.01 185.8,64.77 184.28,64.77 184.05,64.54 v1(183.52,64.54)
  BOTTOM w0.132: v1(183.52,64.54) 183.52,64.52 183.55,64.48 R735.2 183.64,63.79 U115.4
MMC1_SDCD: length 69.2
  TOP w0.132: U34.B24 v1(158.36,89.79) ; J17.G1 R310.2 178.6,38.58 v1(178.75,38.73)
  L10_SIG3 w0.084: v1(158.36,89.79) 159.71,89.79 163.03,86.48 163.03,84.37 166.91,80.49 173.31,80.49 180.41,73.39 180.41,40.39 v1(178.75,38.73)
MMC1_VCTRL_TP: length 23.6
  TOP w0.132: U34.E23 v1(155.96,90.59)
  BOTTOM w0.122: 159.77,87.26 158.71,87.26 158.43,86.98 156.61,86.98 156.36,87.23 156.36,90.18 v1(155.96,90.59)
  BOTTOM w0.132: TP61.1 170.5,81.6 170.5,83.72 169.9,84.32 164.88,84.32 161.94,87.26 159.77,87.26
OLDI0_A0N: length 113.6
  TOP w0.107: v1(161.8,81.07) 161.54,80.81 161.32,80.81 157.91,84.22 153.33,84.22 152.1,85.45 152.1,86.74 U34.J28
  BOTTOM w0.107: J38.8 200.71,26.7 200.51,26.49 197.87,26.49 197.19,27.17 197.19,31.76 196.86,32.08 196.86,36.82 196.51,37.18 195.48,37.18 195.29,37.36 195.29,37.63 195.48,37.81 196.51,37.81 196.86,38.17 196.86,38.68 196.51,39.04 195.48,39.04 195.29,39.23 195.29,39.49 195.48,39.68 196.51,39.68 196.86,40.04 196.86,40.54 196.51,40.9 195.48,40.9 195.29,41.09 195.29,41.36 195.48,41.54 196.51,41.54 196.86,41.9 196.86,42.41 196.51,42.77 195.48,42.77 195.29,42.96 195.29,43.22 195.48,43.41 196.51,43.41 196.86,43.77 196.86,44.27 196.51,44.63 195.48,44.63 195.29,44.82 195.29,45.08 195.48,45.27 196.51,45.27 196.86,45.63 196.86,46.88 197.13,47.14 R599.2 197.13,47.64 196.86,47.9 196.86,61.32 192.62,65.56 192.62,73.01 189.5,76.14 177.31,76.14 176.71,75.54 174.74,75.54 174.33,75.12 168.22,75.12 162.66,80.69 162,80.69 161.8,80.88 v1(161.8,81.07)
OLDI0_A0P: length 113.6
  TOP w0.107: v1(161.8,80.24) 161.53,80.51 161.2,80.51 157.78,83.93 153.21,83.93 151.81,85.33 151.81,86.74 U34.K28
  BOTTOM w0.107: v1(161.8,80.24) 161.96,80.39 162.54,80.39 168.1,74.83 174.45,74.83 174.86,75.24 176.83,75.24 177.43,75.84 189.38,75.84 192.33,72.89 192.33,65.44 196.57,61.2 R599.1 196.57,45.75 196.38,45.57 195.36,45.57 195,45.21 195,44.7 195.36,44.34 196.38,44.34 196.57,44.15 196.57,43.89 196.38,43.7 195.36,43.7 195,43.34 195,42.83 195.36,42.47 196.38,42.47 196.57,42.29 196.57,42.02 196.38,41.84 195.36,41.84 195,41.48 195,40.97 195.36,40.61 196.38,40.61 196.57,40.42 196.57,40.16 196.38,39.97 195.36,39.97 195,39.61 195,39.1 195.36,38.75 196.38,38.75 196.57,38.56 196.57,38.29 196.38,38.11 195.36,38.11 195,37.75 195,37.24 195.36,36.88 196.38,36.88 196.57,36.69 196.57,31.96 196.89,31.64 196.89,27.05 197.74,26.2 200.51,26.2 200.51,26.2 J38.9
OLDI0_A1N: length 113.7
  TOP w0.107: U34.L27 v1(150.36,87.39)
  BOTTOM w0.107: J38.11 202.15,25.2 202.33,25.01 204.96,25.01 205.61,25.67 205.61,34.31 204.39,35.53 201.3,35.53 198.76,38.08 198.76,39.28 199.12,39.64 199.8,39.64 199.98,39.82 199.98,40.09 199.8,40.27 199.12,40.27 198.76,40.63 198.76,41.14 199.12,41.5 199.8,41.5 199.98,41.69 199.98,41.95 199.8,42.14 199.12,42.14 198.76,42.5 198.76,42.88 198.76,46.75 198.5,47.02 R597.2 198.5,47.73 198.76,48 198.76,60.22 193.2,65.78 193.2,73.14 189.73,76.61 174.45,76.61 173.68,75.84 168.49,75.84 162.44,81.89 159.56,81.89 159.01,82.45 156.96,82.45 156.11,83.3 153.36,83.3 150.44,86.21 150.44,86.89 150.68,87.13 150.68,87.28 150.57,87.39 v1(150.36,87.39)
OLDI0_A1P: length 113.7
  TOP w0.107: U34.K27 v1(151.16,87.39)
  BOTTOM w0.107: J38.12 205.06,24.7 205.91,25.55 205.91,34.44 204.51,35.83 201.46,35.83 199.06,38.23 199.06,39.16 199.24,39.34 199.92,39.34 200.28,39.7 200.28,40.21 199.92,40.57 199.24,40.57 199.06,40.76 199.06,41.02 199.24,41.21 199.92,41.21 200.28,41.57 200.28,42.07 199.92,42.43 199.24,42.43 199.06,42.62 199.06,43 199.06,47.4 R597.1 199.06,60.34 193.49,65.9 193.49,73.27 189.85,76.91 174.33,76.91 173.56,76.14 168.61,76.14 162.56,82.19 159.69,82.19 159.13,82.74 157.09,82.74 156.23,83.59 153.48,83.59 150.74,86.33 150.74,86.77 151.16,87.19 v1(151.16,87.39)
OLDI0_A2N: length 113.8
  TOP w0.107: U34.K24 v1(151.96,89.79)
  BOTTOM w0.107: J38.14 202.06,23.7 202.24,23.51 205.23,23.51 206.38,24.66 206.38,38.24 200.69,43.92 200.69,46.78 200.61,46.86 200.25,46.86 200.15,46.96 200.15,47.11 R595.2 200.19,47.66 200.19,47.79 200.28,47.88 200.61,47.88 200.71,47.98 200.71,59.58 193.99,66.3 193.99,73.49 190.04,77.43 174.08,77.43 173.39,76.74 173.38,76.74 173.27,76.63 168.83,76.63 162.72,82.74 159.84,82.74 159.37,83.21 157.31,83.21 156.2,84.31 153.78,84.31 152.25,85.85 152.25,86.89 151.58,87.56 151.58,88.39 151.25,88.72 151.25,89.33 151.56,89.64 151.56,89.93 151.66,90.03 151.78,90.03 151.96,89.85 v1(151.96,89.79)
OLDI0_A2P: length 113.9
  TOP w0.107: U34.J24 v1(151.96,90.59)
  BOTTOM w0.107: v1(151.96,90.59) 152.27,90.27 152.27,90.01 152.34,89.95 152.34,89.63 152.09,89.38 151.73,89.38 151.55,89.21 151.55,88.84 151.88,88.51 151.88,87.68 152.54,87.02 152.54,85.97 153.9,84.61 156.33,84.61 157.43,83.5 159.5,83.5 159.97,83.03 162.84,83.03 168.95,76.92 173.15,76.92 173.26,77.03 173.26,77.03 173.96,77.73 190.17,77.73 194.28,73.61 194.28,66.42 201,59.71 R595.1 201,44.06 206.69,38.37 206.69,24.52 205.37,23.2 J38.15
OLDI0_A3N: length 113.5
  TOP w0.107: U34.J26 v1(151.96,88.99)
  BOTTOM w0.107: v1(151.96,88.99) 152.36,88.58 152.36,88.03 152.46,87.93 152.46,87.51 154.12,85.85 155.1,85.85 155.61,85.34 156.32,85.34 157.68,83.98 159.68,83.98 160.13,83.54 163.06,83.54 169.11,77.49 173.07,77.49 173.5,77.92 173.77,78.19 190.44,78.19 194.75,73.88 194.75,66.75 194.78,66.73 194.78,66.6 202.36,59.02 202.36,47.9 202.09,47.64 R594.2 202.09,46.95 202.36,46.69 202.36,45.32 202.37,45.31 202.36,45.3 202.36,45.26 207.28,40.35 207.28,22.78 206.49,21.99 202.28,21.99 202.07,22.2 J38.17
OLDI0_A3P: length 113.5
  TOP w0.107: U34.K26 151.95,88.19 v1(152.76,88.19)
  BOTTOM w0.107: v1(152.76,88.19) 152.76,87.93 152.76,87.93 152.76,87.63 154.24,86.14 155.22,86.14 155.73,85.64 156.44,85.64 157.8,84.28 159.8,84.28 160.25,83.83 163.18,83.83 169.23,77.79 172.95,77.79 173.2,78.04 173.65,78.48 190.56,78.48 195.05,74 195.05,73.9 195.07,73.88 195.07,66.73 202.65,59.14 R594.1 202.65,45.44 207.6,40.5 207.6,22.68 206.61,21.7 J38.18
OLDI0_CLKN: length 113.8
  TOP w0.107: U34.L25 v1(150.36,88.99)
  BOTTOM w0.107: J38.20 200.81,20.7 200.6,20.49 199.98,20.49 199.81,20.66 199.81,20.86 199.68,20.99 199.49,20.99 R598.2 199.09,20.82 198.9,20.82 198.79,20.7 198.79,20.54 198.69,20.44 198.02,20.44 195.49,22.97 195.49,29.18 194.42,30.25 194.42,62.19 190.49,66.12 190.49,73.68 188.85,75.33 181.4,75.33 178.51,72.44 168.33,72.44 158.8,81.97 156.75,81.97 155.95,82.77 153.22,82.77 149.73,86.26 149.73,87.38 150.26,87.9 150.26,88.4 150.37,88.52 150.87,88.52 150.96,88.61 150.96,89.01 150.88,89.1 150.47,89.1 v1(150.36,88.99)
OLDI0_CLKP: length 113.8
  TOP w0.107: U34.K25 v1(151.16,89.79)
  BOTTOM w0.107: v1(151.16,89.79) 150.76,89.4 150.2,89.4 149.96,89.15 149.96,88.02 149.44,87.5 149.44,86.14 153.1,82.47 155.83,82.47 156.63,81.67 158.68,81.67 168.2,72.15 178.63,72.15 181.52,75.03 188.72,75.03 190.2,73.56 190.2,66 194.13,62.06 194.13,30.12 195.2,29.05 195.2,22.85 197.9,20.15 R598.1 199.25,20.2 J38.21 201.43,20.2
OSC0: length 7.9
  BOTTOM w0.132: U106.88 63.1,21.32 63.36,21.05 65.11,21.05 65.54,21.49 C652.2 65.65,21.49 66.18,20.95 67.94,20.95 68.88,21.9 Y6.1
OSC1: length 5.8
  BOTTOM w0.132: Y6.3 66.59,20.5 C659.2 63.45,20.5 63.03,20.92 U106.89
OSC1_XI: length 9.8
  TOP w0.132: U34.C22 v1(157.56,91.39)
  BOTTOM w0.122: v1(157.56,91.39) 157.8,91.39 158.19,91 159.77,91
  BOTTOM w0.132: 159.77,91 160.91,91 163.91,87.99 R507.1
OSC1_XOUT: length 12
  TOP w0.132: U34.E22 v1(155.96,91.39)
  BOTTOM w0.132: R511.1 164.04,86.98 160.83,90.19 158.2,90.19 157.96,90.43 157.96,90.75 157.72,90.99 156.36,90.99 v1(155.96,91.39)
OSPI_CLK: length 18.8
  L12_SIG4 w0.084: v1(148.31,133.81) 147.94,133.43 147.94,131.77 148.2,131.51 148.2,129.46 145.52,126.78 145.52,123.99 142.76,121.23 v1(142.3,121.23)
  BOTTOM w0.132: R430.2 v1(142.3,121.23) ; R706.1 149.19,134.66 149.48,134.37 149.48,133.74 149.48,133.73 149.37,133.61 R398.1 148.75,133.86 148.36,133.86 v1(148.31,133.81)
OSPI_CS: length 17.7
  BOTTOM w0.132: R403.1 149.19,130.82 ; 149.19,130.82 148.75,131.26 146.48,131.26 U77.C2 ; 149.19,130.82 149.19,130.9 149.62,131.33 150.86,131.33 151.26,130.94 151.26,126.3 148.21,123.25 R429.2
OSPI_DQ0: length 10.5
  BOTTOM w0.132: RA8.4 145.04,121.92 144.11,122.84 143.31,122.84 143.18,122.97 143.18,125.22 143.66,125.71 R424.1 143.7,127.51 144.59,128.39 144.59,129.36 U77.D3
OSPI_DQ1: length 9.4
  BOTTOM w0.132: 147.05,125.71 R421.1 ; 147.05,125.71 146.66,125.71 146.54,125.58 RA8.7 ; 147.05,125.71 147.05,126.25 146.56,126.75 146.56,129.29 U77.D2
OSPI_DQ2: length 24
  BOTTOM w0.132: RA8.1 143.47,121.88 143.31,122.05 137.41,122.05 135.89,123.57 135.89,128.65 138.43,131.19 139.68,131.19 139.82,131.34 140.88,131.34 141.01,131.2 R402.1 142.32,130.83 142.75,131.26 143.59,131.26 U77.C4
OSPI_DQ3: length 18
  BOTTOM w0.132: RA8.3 144.54,121.88 143.85,122.58 138.82,122.58 138.68,122.71 138.68,126.99 138.82,127.13 139.99,127.13 141.01,128.14 R411.1 141.01,128.81 141.55,129.35 143.57,129.35 U77.D4
OSPI_DQ4: length 20.8
  BOTTOM w0.132: RA8.2 144.04,121.88 143.61,122.31 137.52,122.31 137.03,122.8 137.03,126.77 138.97,128.71 138.97,130.02 139.26,130.3 140.91,130.3 141.01,130.21 R406.1 141.52,129.68 141.65,129.81 U77.D5
OSPI_DQ5: length 10.7
  BOTTOM w0.132: U77.E3 145.03,126.41 144.84,126.22 R423.1 144.32,125.71 144.21,125.6 144.21,123.93 144.08,123.8 143.57,123.8 143.44,123.66 143.44,123.24 143.57,123.1 145.37,123.1 145.54,122.94 RA8.5
OSPI_DQ6: length 8.8
  BOTTOM w0.132: 145.91,125.71 145.48,126.14 145.48,126.56 145.92,127 145.92,127.38 145.48,127.82 145.48,128.26 U77.E2 ; 145.91,125.71 R422.1 ; 145.91,125.71 145.89,125.71 145.4,125.22 145.4,123.71 146.04,123.07 RA8.6
OSPI_DQ7: length 8.7
  BOTTOM w0.132: U77.E1 147.03,126.87 148.2,125.71 ; 148.2,125.71 R420.1 ; 148.2,125.71 147.8,125.71 147.69,125.59 147.69,123.11 147.1,122.53 RA8.8
OSPI_DQS: length 37.5
  TOP w0.132: U34.U2 v1(145.56,108.19)
  L03_SIG1 w0.084: v1(148.46,127.8) 148.87,127.39 148.87,123.62 148.69,123.44 141.48,123.44 140.21,122.17 140.21,115.82 143.48,112.55 143.48,109.69 143.57,109.6 143.57,108.36 143.56,108.35 143.56,106.43 143.79,106.2 145.72,106.2 145.96,106.45 145.96,107.53 145.56,107.94 v1(145.56,108.19)
  BOTTOM w0.132: R410.2 R732.1 v1(148.46,127.8)
OSPI_INT: length 41.7
  TOP w0.132: U34.N2 v1(149.56,108.19)
  BOTTOM w0.132: v1(149.56,108.19) 149.56,112.47 150.37,113.28 150.37,114.06 150.11,114.31 150.11,123.19 153.82,126.9 153.82,136.04 151.68,138.18 146.39,138.18 R33.1 144.82,137.2 144.4,136.78 R745.1
OSPI_LBCLKO_GPIO: length 57.6
  TOP w0.132: U34.U1 v1(145.56,108.99)
  L10_SIG3 w0.084: v1(151.13,149.48) 146.69,145.03 146.69,141.6 142.62,137.54 142.62,133.1 144.02,131.7 150.53,131.7 v1(150.66,131.83)
  L12_SIG4 w0.084: v1(150.66,131.83) 150.09,131.26 150.09,123.82 149.48,123.21 146.64,120.37 146.64,117.9 146.33,117.59 146.33,115.6 145.74,115.01 145.74,112.79 145.9,112.64 146.41,112.64 146.56,112.49 146.56,112.13 146.41,111.98 145.9,111.98 145.74,111.83 145.74,111.47 145.9,111.32 146.41,111.32 146.56,111.17 146.56,110.81 146.41,110.66 145.9,110.66 145.74,110.51 145.74,109.68 145.56,109.49 v1(145.56,108.99)
  BOTTOM w0.132: R705.2 150.91,149.69 v1(151.13,149.48)
OSPI_RSTN: length 26.9
  L10_SIG3 w0.084: v1(143.63,133.26) 143.63,136.39 145.92,138.68 161.8,138.68 162.04,138.44 v1(163.35,138.44)
  BOTTOM w0.132: v1(143.63,133.26) 143.63,133.22 U77.A4 ; U74.4 R385.1 v1(163.35,138.44)
PCIE0_PRSNTN: length 12.2
  TOP w0.132: J5.21 141.74,149.2 141.34,149.6 141.34,154.95 140.19,156.09 U7.4 137.23,156.09 R26.1
PCIE1_ATEST: length 29.4
  TOP w0.132: U34.AC13 v1(140.76,99.39)
  L05_SIG2 w0.084: v1(140.76,99.39) 141.15,99.78 141.15,100.03 141.15,100.03 141.15,101.95 140.9,102.2 138.09,102.2 137.67,102.62 135.83,102.62 135,103.44 131.06,103.44 130.68,103.06 122.94,103.06 120.5,105.5 v1(119.25,105.5)
  BOTTOM w0.132: v1(119.25,105.5) 119.25,104.71 TP51.1
PCIE1_PRSNTN: length 10.8
  TOP w0.132: R29.1 136.87,155.44 U7.5 139.71,155.44 140.94,154.21 J5.22
PCIE1_RESREF: length 24
  TOP w0.132: U34.AC14 v1(140.76,98.59)
  L10_SIG3 w0.084: v1(124.73,90.93) 124.27,91.39 124.27,93.15 124.54,93.42 124.82,93.42 125.67,94.27 125.67,94.87 127.58,96.79 130.06,96.79 133.06,99.78 140.12,99.78 140.35,99.55 140.35,99 v1(140.76,98.59)
  BOTTOM w0.132: R497.1 v1(124.73,90.93)
PCIE1_SGMII1_RXN1: length 62.2
  TOP w0.132: 136.36,101.82 136.41,101.82 136.44,101.79 137.41,101.79 arc(137.54,101.82) 137.66,101.9 U34.AG9
  TOP w0.267: J5.52 140.94,144.96 arc(140.92,144.79) 140.85,144.62 arc(140.76,144.5) 140.74,144.35 140.74,141.3 arc(140.54,140.31) 139.98,139.47 139,138.49 arc(138.34,138.05) 137.57,137.9 137.03,137.9 arc(135.88,137.67) 134.91,137.02 123.81,125.92 arc(123.54,125.51) 123.44,125.03 123.44,111.59 arc(123.78,109.89) 124.74,108.46 131.14,102.06 arc(131.41,101.88) 131.72,101.82 136.36,101.82
PCIE1_SGMII1_RXP1: length 62.2
  TOP w0.132: 136.36,101.42 137.12,101.42 U34.AH10
  TOP w0.267: J5.53 140.14,144.96 arc(140.16,144.79) 140.23,144.62 arc(140.31,144.5) 140.34,144.35 140.34,141.3 arc(140.18,140.46) 139.7,139.75 138.72,138.77 arc(138.19,138.41) 137.57,138.29 137.03,138.29 arc(135.73,138.03) 134.63,137.29 123.53,126.2 arc(123.18,125.66) 123.05,125.03 123.05,111.59 arc(123.42,109.74) 124.46,108.18 130.86,101.78 arc(131.26,101.51) 131.72,101.42 132.66,101.42 132.82,101.27 133.44,101.27 133.59,101.42 133.96,101.42 134.16,101.22 134.68,101.22 134.89,101.42 136.36,101.42
PCIE1_SGMII1_TXN1: length 4.3
  TOP w0.267: J5.50 142.54,144.96 arc(142.56,144.79) 142.63,144.62 arc(142.71,144.5) 142.74,144.35 142.74,142.3 arc(142.67,141.95) C58.2
PCIE1_SGMII1_TXN1_C: length 53.3
  TOP w0.132: U34.AH9 136.62,102.19 136.46,102.35
  TOP w0.267: 136.46,102.35 136.22,102.59 135.83,102.59 135.56,102.86 135.56,103.25 135.29,103.52 arc(135.14,103.62) 134.96,103.66 133.1,103.66 arc(132.61,103.74) 132.18,103.98 arc(132.12,104.03) 132.05,104.09 127.13,109.02 arc(126.68,109.69) 126.52,110.49 126.52,124.32 arc(126.68,125.13) 127.14,125.82 137.44,136.12 arc(137.81,136.36) 138.24,136.45 140.74,136.45 arc(140.98,136.5) 141.17,136.63 142.39,137.85 arc(142.65,138.23) 142.74,138.69 142.74,140.07 arc(142.67,140.42) C58.1
PCIE1_SGMII1_TXP1: length 4.3
  TOP w0.267: J5.49 143.34,144.96 arc(143.32,144.79) 143.25,144.62 arc(143.16,144.5) 143.14,144.35 143.14,142.3 arc(143.21,141.95) C59.2
PCIE1_SGMII1_TXP1_C: length 53.4
  TOP w0.132: 136.69,102.68 136.78,102.59 137.16,102.59 arc(137.53,102.66) 137.83,102.87 U34.AG8
  TOP w0.267: 136.69,102.68 135.57,103.8 arc(135.29,103.98) 134.96,104.05 133.1,104.05 arc(132.74,104.11) 132.43,104.29 arc(132.38,104.33) 132.33,104.37 127.41,109.29 arc(127.04,109.84) 126.91,110.49 126.91,124.32 arc(127.04,124.98) 127.42,125.54 137.72,135.84 arc(137.96,136) 138.24,136.06 140.74,136.06 arc(141.13,136.13) 141.45,136.35 142.67,137.57 arc(143.01,138.08) 143.14,138.69 143.14,140.07 arc(143.21,140.42) C59.1
PCIE_GPIO_RESET_IN: length 4.4
  TOP w0.132: J5.12 148.94,150.08 v1(149.35,150.5)
  BOTTOM w0.132: v1(149.35,150.5) 149.48,150.37 R705.1 R743.1
PGD: length 14.2
  L12_SIG4 w0.084: v1(22.97,161.11) 22.97,158.96 24.51,157.42 27.49,157.42 v1(30.39,154.51)
  BOTTOM w0.132: R347.1 R346.1 v1(22.97,161.11) ; v1(30.39,154.51) U66.8
PMIC_POWER-EN0: length 24.7
  TOP w0.132: U34.Y5 v1(143.16,105.79)
  L05_SIG2 w0.084: v1(143.16,105.79) 142.75,105.38 142.75,104.82 142.52,104.6 142.24,104.6 141.94,104.3 141.94,104.03 141.71,103.8 136.59,103.8 136.59,103.8 136.14,103.8 134.62,105.32 v1(122.87,105.32)
  BOTTOM w0.132: TP52.1 123.06,104.68 122.87,104.87 v1(122.87,105.32)
PMIC_POWER-EN1: length 23.4
  TOP w0.132: U34.AA5 v1(142.36,105.79)
  L05_SIG2 w0.084: v1(142.36,105.79) 141.95,106.2 141.72,106.2 141.72,106.2 138.19,106.2 137.97,106.43 136.14,106.43 134.56,108.01 v1(121.67,108.01)
  BOTTOM w0.132: TP49.1 v1(121.67,108.01)
PORZ_OUT: length 509.3
  TOP w0.132: v1(153.57,52.87) U48.2 R304.1 ; U34.C19 v1(157.56,93.79) ; J5.30 134.54,149.96 v1(135.19,150.62) ; U28.2 v1(102.62,106.58) ; U17.2 v1(160.14,138.18) ; J16.38 49.43,62.45 v1(48.93,61.95)
  L03_SIG1 w0.084: v1(163.58,56.07) 166.18,56.07 167.82,57.71 167.82,62.18 167.01,62.99 167.01,84.01 160.83,90.18 157.41,90.18 157.16,90.43 157.16,93.4 v1(157.56,93.79) 157.15,94.2 151.79,94.2 151.55,94.45 151.55,97.44 151.19,97.79 149.73,97.79 149.15,98.38 149.15,102.03 149.32,102.2 150.52,102.2 150.75,102.43 150.75,102.43 150.75,106.73 150.76,106.75 150.76,106.75 150.99,106.98 151.36,106.98 151.56,107.19 151.56,109.15 151.57,109.15 151.57,110.8 153.05,112.28 153.05,113.74 153.67,114.36 153.67,121.5 161.38,129.2 161.38,136.94 v1(160.14,138.18) 155.49,142.83 155.49,144.2 154.27,145.42 154.27,150.52 153.26,151.53 153.26,156.9 150.01,160.15 122.59,160.15 121.24,158.8 119.06,158.8 117.8,157.54 116.75,157.54 116.75,157.55 112.08,157.55 111.16,156.63 108.37,156.63 99.69,147.95 99.69,132.59 98.68,131.57 98.68,110.52 v1(102.62,106.58) 101.57,106.58 94.46,113.69 75.21,113.69 67.95,106.43 v1(67.95,87.68) ; v1(138.37,20.57) 152.84,20.57 157.23,24.96 157.23,33.83 v1(156.54,34.52) 156.54,35.93 152.21,40.26 152.21,51.51 v1(153.57,52.87)
  L05_SIG2 w0.084: v1(135.19,150.62) 138.56,147.24 152.6,147.24 155.19,144.65 155.19,143.12 v1(160.14,138.18) ; v1(138.37,20.57) 138.37,19.37 137.35,18.35 124.52,18.35 119.11,12.94 91.04,12.94 90.58,13.4 79.74,13.4 v1(77.11,10.77) ; v1(163.58,56.07) 162.31,54.8 155.5,54.8 v1(153.57,52.87)
  L12_SIG4 w0.084: v1(67.95,87.68) 68.45,87.18 68.45,75.12 54.8,61.47 49.41,61.47 v1(48.93,61.95)
  BOTTOM w0.132: U17.2 v1(160.14,138.18) 160.59,138.63 TP86.1 ; U108.2 v1(138.37,20.57) ; J35.16 157.04,35.02 v1(156.54,34.52) ; U86.2 v1(67.95,87.68) ; U113.2 v1(77.11,10.77)
PRG0_MDIODATA: length 82.2
  TOP w0.132: U34.AE26 v1(139.16,88.19) ; J18.53 85.12,42.36 v1(85.62,42.86) 86.07,42.86 86.08,42.87 R307.1
  L12_SIG4 w0.084: v1(139.16,88.19) 139.55,87.8 139.55,85.12 133.94,79.51 132.38,79.51 119.75,66.88 119.75,64.38 114.43,59.07 102.7,59.07 86.49,42.86 v1(85.62,42.86)
PRG0_MDIOMDCLK: length 77
  TOP w0.132: J18.59 v1(84.71,43.86) ; U34.AE28 v1(139.16,86.59)
  L12_SIG4 w0.084: v1(139.16,86.59) 139.16,85.16 133.81,79.82 132.26,79.82 119.44,67 119.44,64.51 114.31,59.37 102.58,59.37 86.61,43.4 85.17,43.4 v1(84.71,43.86)
PRG0_PRU0_GPO11_R: length 24.6
  TOP w0.132: U34.AB25 v1(141.56,88.99)
  L05_SIG2 w0.084: v1(141.56,88.99) 141.44,88.99 141.03,88.58 140.59,88.58 140.36,88.35 140.36,88.03 140.37,88.03 140.37,85.98 140.45,85.89 140.45,85.1 140.84,84.71 140.84,75.82 142.11,74.55 147.66,74.55 v1(148.78,75.67)
  BOTTOM w0.132: v1(148.78,75.67) R568.1
PRG0_PRU0_GPO12_R: length 29.1
  TOP w0.132: v1(150.12,75.63) 149.4,74.92 139.65,74.92 139.41,74.68 137.2,74.68 137.05,74.83 136.63,75.25 136.63,80.73 139.96,84.06 139.96,87.39 U34.AD27
  BOTTOM w0.132: RA15.5 v1(150.12,75.63)
PRG0_PRU0_GPO13_R: length 24.4
  TOP w0.132: U34.AC26 v1(140.76,88.19)
  L05_SIG2 w0.084: v1(150.12,76.55) 147.6,76.55 146,74.94 143.41,74.94 141.22,77.13 141.22,84.84 140.76,85.3 v1(140.76,88.19)
  BOTTOM w0.132: v1(150.12,76.55) 150.75,75.91 RA15.6
PRG0_PRU0_GPO14_R: length 26.6
  TOP w0.132: U34.AD26 v1(139.96,88.19)
  L05_SIG2 w0.084: v1(139.96,88.19) 139.96,84.2 139.83,84.07 139.83,78.04 140.34,77.53 140.34,75.56 141.86,74.04 149.66,74.04 v1(151.25,75.63)
  BOTTOM w0.132: RA15.7 v1(151.25,75.63)
PRG0_PRU0_GPO15_R: length 23.2
  TOP w0.132: U34.AA24 v1(142.36,89.79)
  L05_SIG2 w0.084: v1(151.25,76.55) 150.77,77.03 144.91,77.03 142.49,79.44 142.49,84.84 142.77,85.11 142.77,86.43 142.76,86.43 142.76,89.15 142.77,89.15 142.77,89.38 v1(142.36,89.79)
  BOTTOM w0.132: RA15.8 151.89,75.9 v1(151.25,76.55)
PRG0_PRU0GPO0: length 98
  TOP w0.132: U34.V24 v1(144.76,89.79) ; J18.35 v1(84.71,37.86)
  L12_SIG4 w0.084: v1(144.76,89.79) 145.15,90.18 146.52,90.18 146.75,89.95 146.75,86.27 142.27,81.79 142.27,79.68 142.11,79.53 142.11,72.05 139.88,69.81 127.47,69.81 123.24,65.59 123.24,62.49 112.49,51.74 104.01,51.74 89.67,37.4 85.17,37.4 v1(84.71,37.86)
PRG0_PRU0GPO1: length 93.3
  TOP w0.132: U34.W25 v1(143.96,88.99) ; J18.39 v1(84.71,38.86)
  L12_SIG4 w0.084: v1(84.71,38.86) 85.17,38.4 89.81,38.4 103.76,52.35 112.24,52.35 122.63,62.74 122.63,65.84 127.21,70.42 138.46,70.42 140.14,72.11 140.14,78.42 141.66,79.93 141.66,82.04 145.15,85.53 145.15,88.35 144.9,88.6 144.35,88.6 v1(143.96,88.99)
PRG0_PRU0GPO2: length 96.1
  TOP w0.132: U34.W24 v1(143.96,89.79) ; J18.33 85.12,37.36 v1(85.62,37.86)
  L12_SIG4 w0.084: v1(143.96,89.79) 144.36,89.38 145.72,89.38 145.96,89.13 145.96,85.92 141.96,81.92 141.96,79.81 141.16,79.01 141.16,72.11 139.17,70.12 127.34,70.12 122.94,65.71 122.94,62.62 112.37,52.05 103.88,52.05 89.69,37.86 v1(85.62,37.86)
PRG0_PRU0GPO3: length 116
  TOP w0.132: U34.AA27 v1(142.36,87.39) ; J18.23 v1(84.71,34.86)
  L12_SIG4 w0.084: v1(142.36,87.39) 141.96,87.78 141.96,92.35 142.19,92.58 147.45,92.58 147.83,92.2 147.83,91.69 148.5,91.02 148.88,91.02 149.12,90.78 149.12,86.01 144.41,81.29 144.41,74.79 145.12,74.08 145.12,72.01 142.01,68.9 127.84,68.9 124.16,65.21 124.16,59.69 114.62,50.15 113.99,50.15 113.29,49.45 103.01,49.45 87.96,34.4 85.17,34.4 v1(84.71,34.86)
PRG0_PRU0GPO4: length 103.2
  TOP w0.132: J18.31 v1(84.71,36.86) ; U34.Y24 v1(143.16,89.79)
  L12_SIG4 w0.084: v1(143.16,89.79) 143.55,90.18 143.55,90.73 143.79,90.98 147.32,90.98 147.55,90.75 147.55,85.98 143.76,82.2 143.76,78.58 143.19,78 143.19,72.11 140.59,69.51 127.59,69.51 123.55,65.46 123.55,62.36 112.62,51.44 104.13,51.44 89.1,36.4 85.17,36.4 v1(84.71,36.86)
PRG0_PRU0GPO5: length 84.9
  TOP w0.132: U34.V28 v1(144.76,86.59) ; v1(85.62,38.86) 85.12,38.36 J18.37
  L12_SIG4 w0.084: v1(144.76,86.59) 144.76,85.66 141.35,82.26 141.35,81.06 140.7,80.42 138.9,80.42 135.56,77.08 133.39,77.08 122.19,65.87 122.19,63.37 115.44,56.63 107.6,56.63 89.83,38.86 v1(85.62,38.86)
PRG0_PRU0GPO6: length 108.7
  TOP w0.132: U34.Y25 v1(143.16,88.99) ; J18.27 v1(84.71,35.86)
  L12_SIG4 w0.084: v1(84.71,35.86) 85.17,35.4 88.53,35.4 102.89,49.76 104.91,49.76 105.64,50.49 113.1,50.49 123.85,61.24 123.85,65.34 127.72,69.2 141.3,69.2 144.11,72.01 144.11,81.7 148.38,85.98 148.38,90.76 147.36,91.78 142.99,91.78 142.76,91.55 142.76,89.38 v1(143.16,88.99)
PRG0_PRU0GPO7: length 110.4
  TOP w0.132: J18.16 v1(75.82,32.86) ; U34.U27 v1(145.56,87.39)
  L10_SIG3 w0.084: v1(145.56,87.39) 145.95,87 145.95,85.62 144.02,83.69 144.02,79.25 144.93,78.33 145.66,78.33 148.17,75.82 148.17,71.01 145.41,68.25 127.95,68.25 123.62,63.92 123.62,62.87 114.29,53.54 103.95,53.54 85.78,35.37 83.25,35.37 80.74,32.86 v1(75.82,32.86)
PRG0_PRU0GPO8: length 106.9
  TOP w0.132: J18.20 v1(75.82,33.86) ; U34.V27 v1(144.76,87.39)
  L10_SIG3 w0.084: v1(144.76,87.39) 144.36,87 144.36,85.98 142.61,84.22 142.61,79.35 146.38,75.58 146.38,72.15 143.09,68.86 127.72,68.86 123.01,64.15 123.01,63.12 115.22,55.34 104.88,55.34 86.89,37.34 83.69,37.34 80.21,33.86 v1(75.82,33.86)
PRG0_PRU0GPO9: length 86
  TOP w0.132: U34.V26 v1(144.76,88.19) ; J18.43 v1(84.71,39.86)
  L12_SIG4 w0.084: v1(144.76,88.19) 144.36,87.8 144.36,85.7 141.05,82.39 141.05,81.19 140.58,80.72 138.77,80.72 135.43,77.38 133.27,77.38 121.88,65.99 121.88,63.5 115.32,56.93 103.59,56.93 86.05,39.4 85.17,39.4 v1(84.71,39.86)
PRG0_PRU0GPO10: length 111.3
  TOP w0.132: U34.U25 v1(145.56,88.99) ; v1(74.9,33.86) 75.4,33.36 J18.18
  L10_SIG3 w0.084: v1(74.9,33.86) 75.36,33.4 80.52,33.4 83.44,36.32 86.3,36.32 103.83,53.85 114.17,53.85 123.32,63 123.32,64.02 127.85,68.55 143.36,68.55 147.26,72.46 147.26,75.18 143.71,78.73 143.71,84.53 145.16,85.98 145.16,88.6 v1(145.56,88.99)
PRG0_PRU0GPO11: length 87.3
  TOP w0.132: v1(85.62,32.86) 85.12,32.36 J18.13
  L12_SIG4 w0.084: v1(148.78,73.27) 143.8,68.29 128.1,68.29 124.76,64.96 124.76,58.14 115.47,48.84 103.26,48.84 87.28,32.86 v1(85.62,32.86)
  BOTTOM w0.132: R568.2 v1(148.78,73.27)
PRG0_PRU0GPO12: length 88.7
  TOP w0.132: J18.15 v1(84.71,32.86)
  L12_SIG4 w0.084: v1(84.71,32.86) 85.17,32.4 87.25,32.4 103.39,48.54 115.59,48.54 125.07,58.02 125.07,64.83 128.22,67.98 144.82,67.98 v1(150,73.16)
  BOTTOM w0.132: RA15.4 149.99,73.72 149.99,73.17 v1(150,73.16)
PRG0_PRU0GPO13: length 89.8
  TOP w0.132: v1(85.62,31.86) 85.12,31.36 J18.9
  L12_SIG4 w0.084: v1(150,72.07) 145.61,67.68 128.35,67.68 125.37,64.7 125.37,57.89 115.72,48.23 104.87,48.23 88.49,31.86 v1(85.62,31.86)
  BOTTOM w0.132: RA15.3 150.75,72.83 v1(150,72.07)
PRG0_PRU0GPO14: length 90.6
  TOP w0.132: J18.11 v1(84.71,31.86)
  L12_SIG4 w0.084: v1(151.15,73.16) 150.69,72.7 150.69,72 146.06,67.37 128.48,67.37 125.68,64.58 125.68,57.76 115.85,47.93 106.27,47.93 89.74,31.4 85.17,31.4 v1(84.71,31.86)
  BOTTOM w0.132: v1(151.15,73.16) 151.15,73.18 151.25,73.28 RA15.2
PRG0_PRU0GPO15: length 91.7
  TOP w0.132: J18.7 v1(84.71,30.86)
  L12_SIG4 w0.084: v1(84.71,30.86) 85.17,30.4 90.35,30.4 107.57,47.62 115.97,47.62 125.98,57.64 125.98,64.45 128.6,67.07 146.47,67.07 151.14,71.74 v1(151.14,72.2)
  BOTTOM w0.132: RA15.1 151.89,72.95 v1(151.14,72.2)
PRG0_PRU0GPO16: length 26.3
  TOP w0.132: v1(147.76,75.65) 147.29,75.18 139.54,75.18 139.3,74.94 137.31,74.94 136.89,75.36 136.89,80.63 140.36,84.09 U34.AD28
  BOTTOM w0.132: R570.1 R569.1 v1(147.76,75.65)
PRG0_PRU0GPO17: length 21.9
  TOP w0.132: U34.U26 v1(145.56,88.19)
  BOTTOM w0.122: v1(145.56,88.19) 145.95,87.8 145.95,86.06
  BOTTOM w0.132: R590.1 R589.1 154.34,75.63 152.95,77.03 147.7,77.03 147.13,77.6 147.13,80.71 145.95,81.89 145.95,86.06
PRG0_PRU0GPO18: length 118.4
  TOP w0.132: U34.V25 v1(144.76,88.99) ; v1(74.9,32.86) 75.4,32.36 J18.14
  L10_SIG3 w0.084: v1(144.76,88.99) 145.15,89.38 146.52,89.38 146.75,89.15 146.75,85.53 144.32,83.11 144.32,80.09 145.26,79.15 146.98,79.15 149.19,76.94 149.19,71.59 145.54,67.94 128.12,67.94 123.93,63.75 123.93,63.18 123.93,62.75 114.42,53.24 111.66,53.24 110.81,52.39 103.8,52.39 85.81,34.4 83.04,34.4 81.04,32.4 75.36,32.4 v1(74.9,32.86)
PRG0_PRU0GPO19: length 117.7
  TOP w0.132: U34.U24 v1(145.56,89.79) ; J18.12 v1(75.82,31.86)
  L10_SIG3 w0.084: v1(75.82,31.86) 81.52,31.86 82.97,33.32 85.73,33.32 104.49,52.08 110.93,52.08 111.78,52.93 114.55,52.93 124.23,62.62 124.23,63.61 128.26,67.64 145.67,67.64 149.49,71.47 149.49,77.07 149.31,77.25 147.11,79.45 145.39,79.45 144.68,80.16 144.68,82.77 147.55,85.63 147.55,89.95 147.32,90.18 145.95,90.18 v1(145.56,89.79)
PRG0_PRU1GPO0: length 13.3
  TOP w0.132: U34.AB28 141.67,86.7 v1(141.67,75.65)
  BOTTOM w0.132: R576.1 R575.1 v1(141.67,75.65)
PRG0_PRU1GPO1: length 14.7
  TOP w0.132: U34.AC28 141.16,84.14 137.6,80.59 v1(137.6,75.65)
  BOTTOM w0.132: R580.1 R579.1 v1(137.6,75.65)
PRG0_PRU1GPO2: length 18.6
  TOP w0.132: v1(139.64,75.65) 139.19,75.21 137.42,75.21 137.16,75.47 137.16,80.52 140.76,84.11 140.76,87.39 U34.AC27
  BOTTOM w0.132: v1(139.64,75.65) R577.1 R578.1
PRG0_PRU1GPO3: length 15.9
  TOP w0.132: U34.AB26 v1(141.56,88.19)
  L05_SIG2 w0.084: v1(143.7,75.65) 141.95,77.41 141.95,87.8 v1(141.56,88.19)
  BOTTOM w0.132: R574.1 R573.1 v1(143.7,75.65)
PRG0_PRU1GPO4: length 20.4
  TOP w0.132: U34.AA25 v1(142.36,88.99)
  L05_SIG2 w0.084: v1(142.36,88.99) 141.96,88.6 141.37,88.6 141.15,88.38 141.15,85.76 141.64,85.27 141.64,77.14 143.53,75.25 145.33,75.25 v1(145.73,75.65)
  BOTTOM w0.132: v1(145.73,75.65) R571.1 R572.1
PRG0_PRU1GPO5: length 28.1
  TOP w0.132: U34.U23 v1(145.56,90.59)
  L10_SIG3 w0.084: v1(145.56,90.59) 145.96,91 147.45,91 148.35,90.1 148.35,84.51 147.17,83.33 147.17,82.31 148.2,81.28 153.67,81.28 156.58,78.37 v1(156.58,75.63)
  BOTTOM w0.132: v1(156.58,75.63) R587.1 R588.1
PRG0_PRU1GPO6: length 92.4
  TOP w0.132: v1(74.9,42.86) 75.4,42.36 J18.54 ; U34.AB27 v1(141.56,87.39)
  L10_SIG3 w0.084: v1(74.9,42.86) 75.36,43.32 77.93,43.32 82.29,47.68 89.73,47.68 104.3,62.24 115.88,62.24 118.5,64.86 118.5,65.7 127.14,74.33 134.6,74.33 135.7,75.43 135.7,78.68 141.15,84.12 141.15,86.98 v1(141.56,87.39)
PRG0_PRU1GPO7: length 83.6
  TOP w0.132: v1(85.62,39.86) 85.12,39.36 J18.41 ; U34.W28 v1(143.96,86.59)
  L12_SIG4 w0.084: v1(143.96,86.59) 143.96,85.73 140.74,82.51 140.74,81.32 140.45,81.03 138.65,81.03 135.31,77.69 133.14,77.69 121.58,66.12 121.58,63.63 115.19,57.24 103.46,57.24 86.08,39.86 v1(85.62,39.86)
PRG0_PRU1GPO8: length 107.7
  TOP w0.132: U34.W27 v1(143.96,87.39) ; J18.22 75.4,34.36 v1(74.9,34.86)
  L10_SIG3 w0.084: v1(143.96,87.39) 143.56,87 143.56,85.98 142.3,84.72 142.3,78.3 146.08,74.52 146.08,72.96 142.28,69.16 127.6,69.16 122.71,64.27 122.71,63.46 115.91,56.67 105.78,56.67 87.43,38.32 83.91,38.32 79.99,34.4 75.36,34.4 v1(74.9,34.86)
PRG0_PRU1GPO9: length 81.6
  TOP w0.132: v1(85.62,40.86) 85.12,40.36 J18.45 ; U34.Y28 v1(143.16,86.59)
  L12_SIG4 w0.084: v1(85.62,40.86) 86.22,40.86 103.21,57.85 114.94,57.85 120.97,63.88 120.97,66.37 132.89,78.3 135.05,78.3 140.26,83.5 140.68,83.5 143.16,85.98 v1(143.16,86.59)
PRG0_PRU1GPO10: length 80.1
  TOP w0.132: v1(85.62,41.86) 85.12,41.36 J18.49 ; U34.AA28 v1(142.36,86.59)
  L12_SIG4 w0.084: v1(85.62,41.86) 86.36,41.86 102.96,58.46 114.69,58.46 120.36,64.13 120.36,66.63 132.64,78.91 134.8,78.91 141.87,85.98 141.87,86.11 v1(142.36,86.59)
PRG0_PRU1GPO11: length 83.2
  TOP w0.132: J18.48 v1(75.82,40.86)
  L10_SIG3 w0.084: v1(140.34,79.3) 136.7,75.67 136.7,75.57 134.75,73.62 134.65,73.62 127.31,73.62 119.11,65.42 119.11,64.61 114.52,60.02 102.94,60.02 89.99,47.07 82.54,47.07 76.33,40.86 v1(75.82,40.86)
  BOTTOM w0.132: R527.2 v1(140.34,79.3)
PRG0_PRU1GPO11_R: length 10.1
  TOP w0.132: U34.AB24 v1(141.56,89.79)
  BOTTOM w0.122: v1(141.56,89.79) 141.16,89.4 141.16,86.06
  BOTTOM w0.132: 141.16,86.06 141.16,83.19 140.34,82.36 R527.1
PRG0_PRU1GPO12: length 84.2
  TOP w0.132: J18.50 75.4,41.36 v1(74.9,41.86)
  L10_SIG3 w0.084: v1(74.9,41.86) 75.36,42.32 77.36,42.32 82.41,47.37 89.86,47.37 102.81,60.33 114.4,60.33 118.81,64.74 118.81,65.56 127.17,73.92 134.62,73.92 136.4,75.7 136.4,76.38 v1(139.32,79.3)
  BOTTOM w0.132: R528.2 v1(139.32,79.3)
PRG0_PRU1GPO12_R: length 9.3
  TOP w0.132: U34.AC25 v1(140.76,88.99)
  BOTTOM w0.122: 140.36,86.06 140.36,88.6 v1(140.76,88.99)
  BOTTOM w0.132: R528.1 139.32,81.93 140.36,82.98 140.36,86.06
PRG0_PRU1GPO13: length 76.2
  TOP w0.132: v1(74.9,40.86) 75.4,40.36 J18.46
  L10_SIG3 w0.084: v1(133.48,73.16) 127.32,73.16 119.42,65.25 119.42,64.48 114.65,59.72 103.07,59.72 90.11,46.76 82.67,46.76 76.31,40.4 75.36,40.4 v1(74.9,40.86)
  BOTTOM w0.132: RA16.4 v1(133.48,73.16)
PRG0_PRU1GPO13_R: length 19.2
  TOP w0.132: U34.AD25 v1(139.96,88.99)
  L10_SIG3 w0.084: v1(139.96,88.99) 140.35,88.6 140.35,83.96 135.21,78.82 135.21,75.37 134.81,74.97 133.94,74.97 v1(133.48,75.43)
  BOTTOM w0.132: RA16.5 v1(133.48,75.43)
PRG0_PRU1GPO14: length 75.1
  TOP w0.132: J18.44 v1(75.82,39.86)
  L10_SIG3 w0.084: v1(133.48,72.07) 126.66,72.07 119.72,65.14 119.72,64.36 114.78,59.41 103.19,59.41 90.24,46.46 83.06,46.46 76.47,39.86 v1(75.82,39.86)
  BOTTOM w0.132: RA16.3 134.12,72.71 v1(133.48,72.07)
PRG0_PRU1GPO14_R: length 20.2
  TOP w0.132: U34.AD24 v1(139.96,89.79)
  L10_SIG3 w0.084: v1(139.96,89.79) 139.55,90.2 138.19,90.2 137.96,89.97 137.96,82.87 133.48,78.39 v1(133.48,76.52)
  BOTTOM w0.132: v1(133.48,76.52) 134.12,75.88 RA16.6
PRG0_PRU1GPO15: length 78.4
  TOP w0.132: J18.42 75.4,39.36 v1(74.9,39.86)
  L10_SIG3 w0.084: v1(134.62,73.16) 134.11,72.65 134.11,72.06 133.68,71.63 126.69,71.63 126.67,71.6 120.03,64.96 120.03,64.23 114.9,59.11 103.32,59.11 90.36,46.15 83.77,46.15 81.34,43.73 81.34,43.17 77.58,39.4 75.36,39.4 v1(74.9,39.86)
  BOTTOM w0.132: RA16.2 v1(134.62,73.16)
PRG0_PRU1GPO15_R: length 15.5
  TOP w0.132: U34.AE27 v1(139.16,87.39)
  L10_SIG3 w0.084: v1(139.16,87.39) 138.76,87 138.76,83.24 134.11,78.59 134.11,75.94 v1(134.62,75.43)
  BOTTOM w0.132: RA16.7 v1(134.62,75.43)
PRG0_PRU1GPO16: length 79.4
  TOP w0.132: J18.38 75.4,38.36 v1(74.9,38.86)
  L10_SIG3 w0.084: v1(74.9,38.86) 75.36,38.4 77.01,38.4 81.71,43.11 81.71,43.66 83.89,45.85 90.49,45.85 103.45,58.8 115.03,58.8 120.33,64.1 120.33,64.9 126.76,71.32 133.87,71.32 v1(134.62,72.07)
  BOTTOM w0.132: v1(134.62,72.07) 135.26,72.71 RA16.1
PRG0_PRU1GPO16_R: length 18.7
  TOP w0.132: U34.AC24 v1(140.76,89.79)
  L10_SIG3 w0.084: v1(140.76,89.79) 140.35,89.38 139.79,89.38 139.56,89.15 139.56,83.61 134.62,78.66 v1(134.62,76.52)
  BOTTOM w0.132: RA16.8 135.26,75.88 v1(134.62,76.52)
PRG0_PRU1GPO17: length 103.9
  TOP w0.132: U34.Y27 v1(143.16,87.39) ; J18.24 v1(75.82,34.86)
  L10_SIG3 w0.084: v1(75.82,34.86) 79.88,34.86 84.42,39.4 88.09,39.4 105.66,56.97 115.79,56.97 122.4,63.59 122.4,64.4 127.47,69.47 141.57,69.47 145.17,73.08 145.17,74.92 141.99,78.11 141.99,85.2 142.76,85.98 142.76,86.93 143.16,87.32 v1(143.16,87.39)
PRG0_PRU1GPO18: length 82.6
  TOP w0.132: J18.51 v1(84.71,41.86) ; U34.Y26 v1(143.16,88.19)
  L12_SIG4 w0.084: v1(143.16,88.19) 142.75,87.78 142.75,86.11 140.45,83.81 140.13,83.81 134.93,78.6 132.76,78.6 120.66,66.5 120.66,64 114.81,58.15 103.08,58.15 86.33,41.4 85.17,41.4 v1(84.71,41.86)
PRG0_PRU1GPO19: length 83.9
  TOP w0.132: J18.47 v1(84.71,40.86) ; U34.W26 v1(143.96,88.19)
  L12_SIG4 w0.084: v1(143.96,88.19) 143.56,87.8 143.56,85.96 140.67,83.06 140.25,83.06 135.18,77.99 133.02,77.99 121.27,66.25 121.27,63.75 115.06,57.54 103.33,57.54 86.19,40.4 85.17,40.4 v1(84.71,40.86)
PRG0_RGMII1_ETH1_CLK: length 67.7
  TOP w0.132: R204.2 v1(71.12,93.01) ; J18.4 v1(75.82,29.86)
  L03_SIG1 w0.084: v1(75.82,29.86) 75.41,30.27 74.74,30.27 74.13,30.87 74.13,71.35 72.21,73.27 72.21,89.09 71.12,90.18 v1(71.12,93.01)
PRG0_RGMII2_ETH2_CLK: length 38.1
  TOP w0.132: v1(74.9,60.86) 75.4,60.36 J18.106 ; R205.2 v1(72.14,93.01)
  L03_SIG1 w0.084: v1(72.14,93.01) 72.14,91 72.52,90.61 72.52,73.39 76.23,69.68 76.23,61.69 75.8,61.27 75.31,61.27 v1(74.9,60.86)
PRG1_MDIODATA: length 75
  TOP w0.132: J18.99 v1(84.71,58.86) ; U34.AD18 v1(139.96,94.59)
  L12_SIG4 w0.084: v1(84.71,58.86) 85.25,59.4 90.76,59.4 103.95,72.59 105.03,72.59 119.53,87.09 119.53,87.67 122.24,90.37 124.82,90.37 125.41,90.97 125.41,91.69 127.21,93.48 129.81,93.48 132.21,95.88 134.71,95.88 135.6,95 139.55,95 v1(139.96,94.59)
  BOTTOM w0.132: R605.1 v1(84.71,58.86)
PRG1_MDIOMDCLK: length 71
  TOP w0.132: J18.95 v1(84.71,57.86) ; U34.AH18 v1(136.76,94.59)
  L12_SIG4 w0.084: v1(136.76,94.59) 134.7,94.59 134.12,95.16 134.12,95.31 133.86,95.58 132.41,95.58 129.29,92.46 127.27,92.46 126.05,91.23 126.05,90.92 125.23,90.11 125.23,89.77 124.92,89.46 121.75,89.46 119.84,87.54 119.84,86.96 105.16,72.28 104.08,72.28 90.2,58.4 85.25,58.4 v1(84.71,57.86)
PRG1_PRU0_GPO11_R: length 11.1
  TOP w0.132: U34.AF21 v1(138.36,92.19)
  L05_SIG2 w0.084: v1(138.36,92.19) 137.96,91.8 136.61,91.8 136.14,91.33 136.14,91.33 135.7,90.89 135.7,89.85 133.99,88.14 133.48,88.14 v1(132.78,87.44)
  BOTTOM w0.132: R508.1 132.33,87.88 v1(132.78,87.44)
PRG1_PRU0_GPO12_R: length 18.4
  TOP w0.132: v1(124.77,85.6) 124.77,86.04 125.09,86.36 132.33,86.36 135.3,89.32 135.3,92.5 136.19,93.39 U34.AH20
  BOTTOM w0.132: RA13.5 v1(124.77,85.6)
PRG1_PRU0_GPO13_R: length 17.6
  TOP w0.132: v1(125.69,85.6) 132.52,85.6 135.83,88.9 135.83,91.26 U34.AH21
  BOTTOM w0.132: RA13.6 125.05,84.96 v1(125.69,85.6)
PRG1_PRU0_GPO14_R: length 19.9
  TOP w0.132: U34.AG20 137.56,92.99 136.21,92.99 135.56,92.34 135.56,89.21 132.44,86.1 125.55,86.1 125.22,85.77 125.22,84.91 v1(124.77,84.46)
  BOTTOM w0.132: RA13.7 v1(124.77,84.46)
PRG1_PRU0_GPO15_R: length 22
  TOP w0.132: U34.AD19 v1(139.96,93.79)
  L05_SIG2 w0.084: v1(125.69,84.46) 127.01,85.79 128.59,85.79 132.14,89.34 134.75,89.34 135.38,89.98 135.38,91.88 136.08,92.58 137.39,92.58 137.39,92.58 139.32,92.58 139.55,92.81 139.55,93.31 139.96,93.72 v1(139.96,93.79)
  BOTTOM w0.132: RA13.8 125.05,83.82 v1(125.69,84.46)
PRG1_PRU0GPO0: length 85.1
  TOP w0.132: U34.AE22 v1(139.16,91.39) ; J18.88 v1(75.82,55.86)
  L10_SIG3 w0.084: v1(139.16,91.39) 138.75,91.8 138.75,92.35 138.52,92.58 136.14,92.58 135.18,91.62 132.64,91.62 130.51,89.48 130.51,83.38 116.45,69.32 104.46,69.32 96.59,61.45 89.77,61.45 88.71,60.39 83.44,60.39 78.91,55.86 v1(75.82,55.86)
PRG1_PRU0GPO1: length 80.6
  TOP w0.132: U34.AG24 v1(137.56,89.79) ; J18.76 v1(75.82,52.86)
  L10_SIG3 w0.084: v1(137.56,89.79) 137.16,89.4 135.85,89.4 131.91,85.46 131.91,83.05 116.89,68.04 104.91,68.04 93.81,56.95 89.72,56.95 89.16,56.39 83.13,56.39 79.6,52.86 v1(75.82,52.86)
PRG1_PRU0GPO2: length 82.9
  TOP w0.132: U34.AF23 v1(138.36,90.59) ; J18.80 v1(75.82,53.86)
  L10_SIG3 w0.084: v1(138.36,90.59) 137.96,90.98 136.4,90.98 134.76,89.34 132.69,89.34 131.19,87.84 131.19,83.2 116.64,68.65 104.65,68.65 94.74,58.74 91.69,58.74 91.27,58.32 84.19,58.32 79.73,53.86 v1(75.82,53.86)
PRG1_PRU0GPO3: length 88.6
  TOP w0.132: v1(74.9,56.86) 75.4,56.36 J18.90 ; U34.AD21 v1(139.96,92.19)
  L10_SIG3 w0.084: v1(74.9,56.86) 75.36,56.4 76.98,56.4 84.66,64.08 98.8,64.08 104.33,69.62 116.32,69.62 130.2,83.5 130.2,90.19 132.72,92.71 135.47,92.71 136.14,93.38 139.32,93.38 139.56,93.13 139.56,92.58 v1(139.96,92.19)
PRG1_PRU0GPO4: length 84.1
  TOP w0.132: J18.78 75.4,53.36 v1(74.9,53.86) ; U34.AG23 v1(137.56,90.59)
  L10_SIG3 w0.084: v1(137.56,90.59) 137.16,90.2 136.14,90.2 134.08,88.14 132.21,88.14 131.5,87.43 131.5,83.07 116.77,68.34 104.78,68.34 93.75,57.32 83.62,57.32 79.71,53.4 75.36,53.4 v1(74.9,53.86)
PRG1_PRU0GPO5: length 85.2
  TOP w0.132: J18.60 v1(75.82,43.86) ; U34.AF27 v1(138.36,87.39)
  L12_SIG4 w0.084: v1(138.36,87.39) 137.95,86.98 137.95,85.25 133.43,80.73 131.88,80.73 118.53,67.38 118.53,64.89 113.93,60.29 101.19,60.29 89.69,48.79 85.05,48.79 80.12,43.86 v1(75.82,43.86)
PRG1_PRU0GPO6: length 83.3
  TOP w0.132: U34.AF22 v1(138.36,91.39) ; J18.84 v1(75.82,54.86)
  L10_SIG3 w0.084: v1(75.82,54.86) 80.06,54.86 84.58,59.37 94.95,59.37 104.58,69.01 116.57,69.01 130.81,83.25 130.81,88.6 132.52,90.31 134.67,90.31 136.14,91.78 137.96,91.78 v1(138.36,91.39)
PRG1_PRU0GPO7: length 84
  TOP w0.132: U34.AG27 v1(137.56,87.39) ; J18.66 75.4,50.36 v1(74.9,50.86)
  L10_SIG3 w0.084: v1(74.9,50.86) 75.36,50.4 79.29,50.4 80.26,51.37 90.61,51.37 105.76,66.52 118.8,66.52 126.92,74.63 129.18,74.63 137.16,82.62 137.16,87 v1(137.56,87.39)
PRG1_PRU0GPO8: length 87.1
  TOP w0.132: v1(74.9,43.86) 75.4,43.36 J18.58 ; U34.AF28 v1(138.36,86.59)
  L12_SIG4 w0.084: v1(138.36,86.59) 138.36,85.22 133.56,80.43 132.01,80.43 118.83,67.26 118.83,64.76 114.05,59.98 101.31,59.98 89.82,48.49 86.02,48.49 80.93,43.4 75.36,43.4 v1(74.9,43.86)
PRG1_PRU0GPO9: length 84.8
  TOP w0.132: v1(74.9,49.86) 75.4,49.36 J18.62 ; U34.AF26 v1(138.36,88.19)
  L12_SIG4 w0.084: v1(74.9,49.86) 75.67,49.1 89.57,49.1 107.21,66.74 116.84,66.74 131.14,81.04 133.31,81.04 137.16,84.9 137.16,87.55 137.39,87.78 137.95,87.78 v1(138.36,88.19)
PRG1_PRU0GPO10: length 81.9
  TOP w0.132: v1(74.9,52.86) 75.4,52.36 J18.74 ; U34.AH25 v1(136.76,88.99)
  L10_SIG3 w0.084: v1(136.76,88.99) 135.87,88.99 132.21,85.33 132.21,82.93 117.02,67.73 105.25,67.73 94.16,56.64 89.85,56.64 88.52,55.32 82.48,55.32 79.57,52.4 75.36,52.4 v1(74.9,52.86)
PRG1_PRU0GPO11: length 71.3
  TOP w0.132: v1(74.9,58.86) 75.4,58.36 J18.98
  L10_SIG3 w0.084: v1(74.9,58.86) 75.36,58.4 78.11,58.4 84.41,64.69 98.54,64.69 107.37,73.52 117.02,73.52 128.4,84.9 128.4,87.26 v1(129.02,87.88)
  BOTTOM w0.132: R508.2 v1(129.02,87.88)
PRG1_PRU0GPO12: length 61.2
  TOP w0.132: J18.110 75.4,61.36 v1(74.9,61.86)
  L10_SIG3 w0.084: v1(122.5,85.6) 121.77,84.87 121.42,84.87 119.19,82.64 114.16,82.64 97.13,65.61 84.03,65.61 79.76,61.34 75.42,61.34 v1(74.9,61.86)
  BOTTOM w0.132: RA13.4 v1(122.5,85.6)
PRG1_PRU0GPO13: length 61.3
  TOP w0.132: J18.114 75.28,62.36 v1(74.78,62.87)
  L10_SIG3 w0.084: v1(74.78,62.87) 75.29,62.36 79.05,62.36 82.6,65.91 97,65.91 114.04,82.94 118.93,82.94 v1(121.58,85.6)
  BOTTOM w0.132: RA13.3 122.22,84.96 v1(121.58,85.6)
PRG1_PRU0GPO14: length 59.5
  TOP w0.132: J18.100 v1(75.82,58.86)
  L10_SIG3 w0.084: v1(122.5,84.46) 120.07,82.03 114.41,82.03 97.38,65 84.28,65 78.14,58.86 v1(75.82,58.86)
  BOTTOM w0.132: RA13.2 v1(122.5,84.46)
PRG1_PRU0GPO15: length 61.4
  TOP w0.132: v1(74.9,59.86) 75.4,59.36 J18.102
  L10_SIG3 w0.084: v1(74.9,59.86) 75.43,60.39 79.24,60.39 84.15,65.3 97.26,65.3 114.29,82.33 119.46,82.33 v1(121.58,84.46)
  BOTTOM w0.132: RA13.1 122.22,83.82 v1(121.58,84.46)
PRG1_PRU0GPO16: length 88
  TOP w0.132: J18.94 75.4,57.36 v1(74.9,57.86) ; U34.AD20 v1(139.96,92.99)
  L10_SIG3 w0.084: v1(74.9,57.86) 75.36,57.4 77.54,57.4 84.53,64.39 98.67,64.39 107.5,73.22 117.35,73.22 129.86,85.72 129.86,90.28 132.67,93.09 135.05,93.09 136.14,94.18 140.12,94.18 140.35,93.95 140.35,93.38 v1(139.96,92.99)
PRG1_PRU0GPO17: length 81.9
  TOP w0.132: v1(74.9,51.86) 75.4,51.36 J18.70 ; U34.AH26 v1(136.76,88.19)
  L10_SIG3 w0.084: v1(136.76,88.19) 135.93,88.19 132.82,85.08 132.82,82.67 117.27,67.12 105.5,67.12 91.69,53.32 81.35,53.32 79.43,51.4 75.36,51.4 v1(74.9,51.86)
PRG1_PRU0GPO18: length 80.7
  TOP w0.132: J18.72 v1(75.82,51.86) ; U34.AG25 v1(137.56,88.99)
  L10_SIG3 w0.084: v1(137.56,88.99) 137.16,88.6 135.91,88.6 132.51,85.2 132.51,82.8 117.15,67.43 105.38,67.43 92.26,54.32 81.92,54.32 79.46,51.86 v1(75.82,51.86)
PRG1_PRU0GPO19: length 81.2
  TOP w0.132: U34.AG26 v1(137.56,88.19) ; J18.68 v1(75.82,50.86)
  L10_SIG3 w0.084: v1(137.56,88.19) 137.16,87.8 136.61,87.8 136.36,87.55 136.36,86.16 136.54,85.98 136.54,84.75 118.61,66.82 105.63,66.82 91.13,52.32 80.78,52.32 79.32,50.86 v1(75.82,50.86)
PRG1_PRU1GPO0: length 71.8
  TOP w0.132: J18.63 v1(84.71,49.86) ; U34.AH24 v1(136.76,89.79)
  L12_SIG4 w0.084: v1(136.76,89.79) 136.36,89.79 135.91,89.33 135.91,88.66 133.17,85.93 133.17,84.75 116.08,67.65 106.83,67.65 89.58,50.4 85.25,50.4 v1(84.71,49.86)
PRG1_PRU1GPO1: length 71.8
  TOP w0.132: U34.AH23 v1(136.76,90.59) ; J18.67 v1(84.71,50.86)
  L12_SIG4 w0.084: v1(84.71,50.86) 85.25,51.4 89.72,51.4 106.58,68.26 115.82,68.26 132.54,84.98 132.54,86.44 135.3,89.2 135.3,89.63 136.26,90.59 v1(136.76,90.59)
PRG1_PRU1GPO2: length 73
  TOP w0.132: U34.AG21 v1(137.56,92.19) ; J18.77 85.12,53.36 v1(85.62,53.86)
  L12_SIG4 w0.084: v1(85.62,53.86) 90.88,53.86 106.2,69.18 113.53,69.18 130.43,86.07 130.43,89.41 132.69,91.67 135.05,91.67 135.57,92.19 v1(137.56,92.19)
PRG1_PRU1GPO3: length 72.8
  TOP w0.132: J18.75 v1(84.71,52.86) ; U34.AH22 v1(136.76,91.39)
  L12_SIG4 w0.084: v1(84.71,52.86) 85.25,53.4 90.85,53.4 106.32,68.87 115.57,68.87 131.93,85.23 131.93,89.72 132.81,90.6 132.92,90.6 132.93,90.61 135.22,90.61 135.99,91.39 v1(136.76,91.39)
PRG1_PRU1GPO4: length 75.8
  TOP w0.132: v1(85.62,50.86) 85.12,50.36 J18.65 ; U34.AE21 v1(139.16,92.19)
  L12_SIG4 w0.084: v1(139.16,92.19) 138.75,91.78 138.75,90.43 138.52,90.2 136.3,90.2 135.6,89.5 135.6,88.99 132.84,86.23 132.84,84.85 115.95,67.96 106.7,67.96 89.6,50.86 v1(85.62,50.86)
PRG1_PRU1GPO5: length 83.3
  TOP w0.132: U34.AC22 v1(140.76,91.39) ; J18.55 v1(84.71,42.86)
  L12_SIG4 w0.084: v1(140.76,91.39) 140.36,91 140.36,85.51 134.07,79.21 132.51,79.21 120.05,66.75 120.05,64.26 114.56,58.76 102.83,58.76 86.47,42.4 85.17,42.4 v1(84.71,42.86)
PRG1_PRU1GPO6: length 73.7
  TOP w0.132: J18.71 v1(84.71,51.86) ; U34.AG22 v1(137.56,91.39)
  L12_SIG4 w0.084: v1(84.71,51.86) 85.17,52.32 90.21,52.32 106.45,68.57 115.7,68.57 132.23,85.1 132.23,87.54 132.59,87.9 133.5,87.9 134.16,88.56 134.16,90.04 134.43,90.31 135.47,90.31 136.14,90.98 137.15,90.98 v1(137.56,91.39)
PRG1_PRU1GPO8: length 79.7
  TOP w0.132: v1(85.62,43.86) 85.12,43.36 J18.57 ; U34.AE24 v1(139.16,89.79)
  L12_SIG4 w0.084: v1(139.16,89.79) 138.75,89.38 138.75,85.19 133.69,80.12 132.13,80.12 119.14,67.13 119.14,64.64 114.18,59.68 102.45,59.68 86.63,43.86 v1(85.62,43.86)
PRG1_PRU1GPO9: length 83.8
  TOP w0.132: J18.64 v1(75.82,49.86) ; U34.AF25 v1(138.36,88.99)
  L12_SIG4 w0.084: v1(75.82,49.86) 76.28,49.4 89.44,49.4 107.08,67.04 116.71,67.04 131.01,81.34 133.18,81.34 136.72,84.88 136.72,85.98 136.36,86.33 136.36,88.35 136.59,88.58 137.95,88.58 v1(138.36,88.99)
PRG1_PRU1GPO10: length 73.5
  TOP w0.132: U34.AF24 v1(138.36,89.79) ; v1(85.62,49.86) 85.12,49.36 J18.61
  L12_SIG4 w0.084: v1(138.36,89.79) 137.96,89.4 136.61,89.4 136.21,89 136.21,88.54 133.48,85.8 133.48,84.62 116.2,67.35 106.96,67.35 89.47,49.86 v1(85.62,49.86)
PRG1_PRU1GPO11: length 63.9
  TOP w0.132: v1(85.62,54.86) 85.12,54.36 J18.81
  L12_SIG4 w0.084: v1(85.62,54.86) 91.02,54.86 105.95,69.79 108.98,69.79 111.2,72.01 115.5,72.01 128.51,85.02 128.51,87.06 128.54,87.08 128.54,89.43 v1(129.02,89.92)
  BOTTOM w0.132: R499.2 v1(129.02,89.92)
PRG1_PRU1GPO11_R: length 14
  TOP w0.132: U34.AC20 v1(140.76,92.99)
  L05_SIG2 w0.084: v1(140.76,92.99) 140.35,93.4 140.35,93.95 140.12,94.18 136.59,94.18 134.62,92.21 v1(134.62,91.12)
  BOTTOM w0.132: R499.1 131.19,89.92 131.6,90.33 133.83,90.33 v1(134.62,91.12)
PRG1_PRU1GPO12: length 63.7
  TOP w0.132: J18.79 v1(84.71,53.86)
  L12_SIG4 w0.084: v1(129.02,88.9) 129.48,88.44 129.48,85.55 113.41,69.48 106.07,69.48 90.99,54.4 85.25,54.4 v1(84.71,53.86)
  BOTTOM w0.132: R505.2 v1(129.02,88.9)
PRG1_PRU1GPO12_R: length 12.3
  TOP w0.132: U34.AE20 v1(139.16,92.99)
  L05_SIG2 w0.084: v1(134.62,89.85) 135.06,90.3 135.06,92.12 136.32,93.38 138.76,93.38 v1(139.16,92.99)
  BOTTOM w0.132: v1(134.62,89.85) 133.93,89.16 132.52,89.16 132.26,88.9 R505.1
PRG1_PRU1GPO13: length 55.7
  TOP w0.132: J18.91 v1(84.71,56.86)
  L12_SIG4 w0.084: v1(84.71,56.86) 85.19,57.34 92.21,57.34 105.57,70.7 108.45,70.7 120.45,82.7 120.45,87.02 121.51,88.07 121.93,88.07 v1(122.5,88.64)
  BOTTOM w0.132: RA12.4 v1(122.5,88.64)
PRG1_PRU1GPO13_R: length 18.2
  TOP w0.132: U34.AF19 v1(138.36,93.79)
  L12_SIG4 w0.084: v1(124.77,88.64) 125.23,89.1 125.52,89.1 126.71,90.29 126.71,91.46 127.4,92.15 130.19,92.15 132.48,94.44 134.24,94.44 134.5,94.18 137.96,94.18 v1(138.36,93.79)
  BOTTOM w0.132: RA12.5 v1(124.77,88.64)
PRG1_PRU1GPO14: length 54.2
  TOP w0.132: v1(85.62,57.86) 85.12,57.36 J18.93
  L12_SIG4 w0.084: v1(121.58,88.64) 120.14,87.2 120.14,85.56 105.58,71.01 104.65,71.01 91.5,57.86 v1(85.62,57.86)
  BOTTOM w0.132: RA12.3 122.22,88.01 v1(121.58,88.64)
PRG1_PRU1GPO14_R: length 16.4
  TOP w0.132: U34.AH19 v1(136.76,93.79)
  L12_SIG4 w0.084: v1(136.76,93.79) 135.95,93.79 135.43,93.27 131.94,93.27 130.49,91.82 127.5,91.82 127.01,91.34 127.01,89.97 v1(125.69,88.64)
  BOTTOM w0.132: RA12.6 125.05,88.01 v1(125.69,88.64)
PRG1_PRU1GPO15: length 55.7
  TOP w0.132: J18.83 v1(84.71,54.86)
  L12_SIG4 w0.084: v1(84.71,54.86) 85.25,55.4 88.17,55.4 88.86,56.1 91.83,56.1 105.82,70.09 108.7,70.09 122.04,83.43 122.04,87.05 v1(122.5,87.51)
  BOTTOM w0.132: RA12.2 v1(122.5,87.51)
PRG1_PRU1GPO15_R: length 17
  TOP w0.132: U34.AG19 v1(137.56,93.79)
  L12_SIG4 w0.084: v1(124.77,87.51) 125.45,88.19 125.87,88.19 127.32,89.63 127.32,90.23 127.76,90.68 130.05,90.68 132.33,92.96 135.71,92.96 136.14,93.4 137.16,93.4 v1(137.56,93.79)
  BOTTOM w0.132: RA12.7 v1(124.77,87.51)
PRG1_PRU1GPO16: length 55.8
  TOP w0.132: J18.87 v1(84.71,55.86)
  L12_SIG4 w0.084: v1(84.71,55.86) 85.25,56.4 91.7,56.4 105.69,70.4 108.58,70.4 121.12,82.94 121.12,87.04 v1(121.58,87.51)
  BOTTOM w0.132: v1(121.58,87.51) 122.22,86.87 RA12.1
PRG1_PRU1GPO16_R: length 18.9
  TOP w0.132: U34.AE19 v1(139.16,93.79)
  L12_SIG4 w0.084: v1(125.69,87.51) 127.62,89.44 127.62,90.11 127.89,90.37 130.38,90.37 132.6,92.6 136.79,92.6 137.59,93.4 138.76,93.4 v1(139.16,93.79)
  BOTTOM w0.132: v1(125.69,87.51) 125.05,86.87 RA12.8
PRG1_RGMII1_ETH1_CLK: length 70.2
  TOP w0.132: J18.3 v1(84.71,29.86) ; R206.2 v1(73.15,93.01)
  L03_SIG1 w0.084: v1(84.71,29.86) 82.99,31.57 82.99,69.28 73.15,79.12 v1(73.15,93.01)
PRG1_RGMII2_ETH2_CLK: length 39.8
  TOP w0.132: J18.103 v1(84.71,59.86) ; R207.2 v1(74.17,93.01)
  L03_SIG1 w0.084: v1(74.17,93.01) 74.17,79.5 83.88,69.79 83.88,60.68 v1(84.71,59.86)
PRG2_ETH1_D0M: length 31.4
  TOP w0.107: U31.2 47.77,104.48 47.69,104.57 43.66,104.57 41.37,102.28 35.33,102.28 35.03,102.59 28.54,102.59 23.8,97.84 23.8,94.05 J14.A2
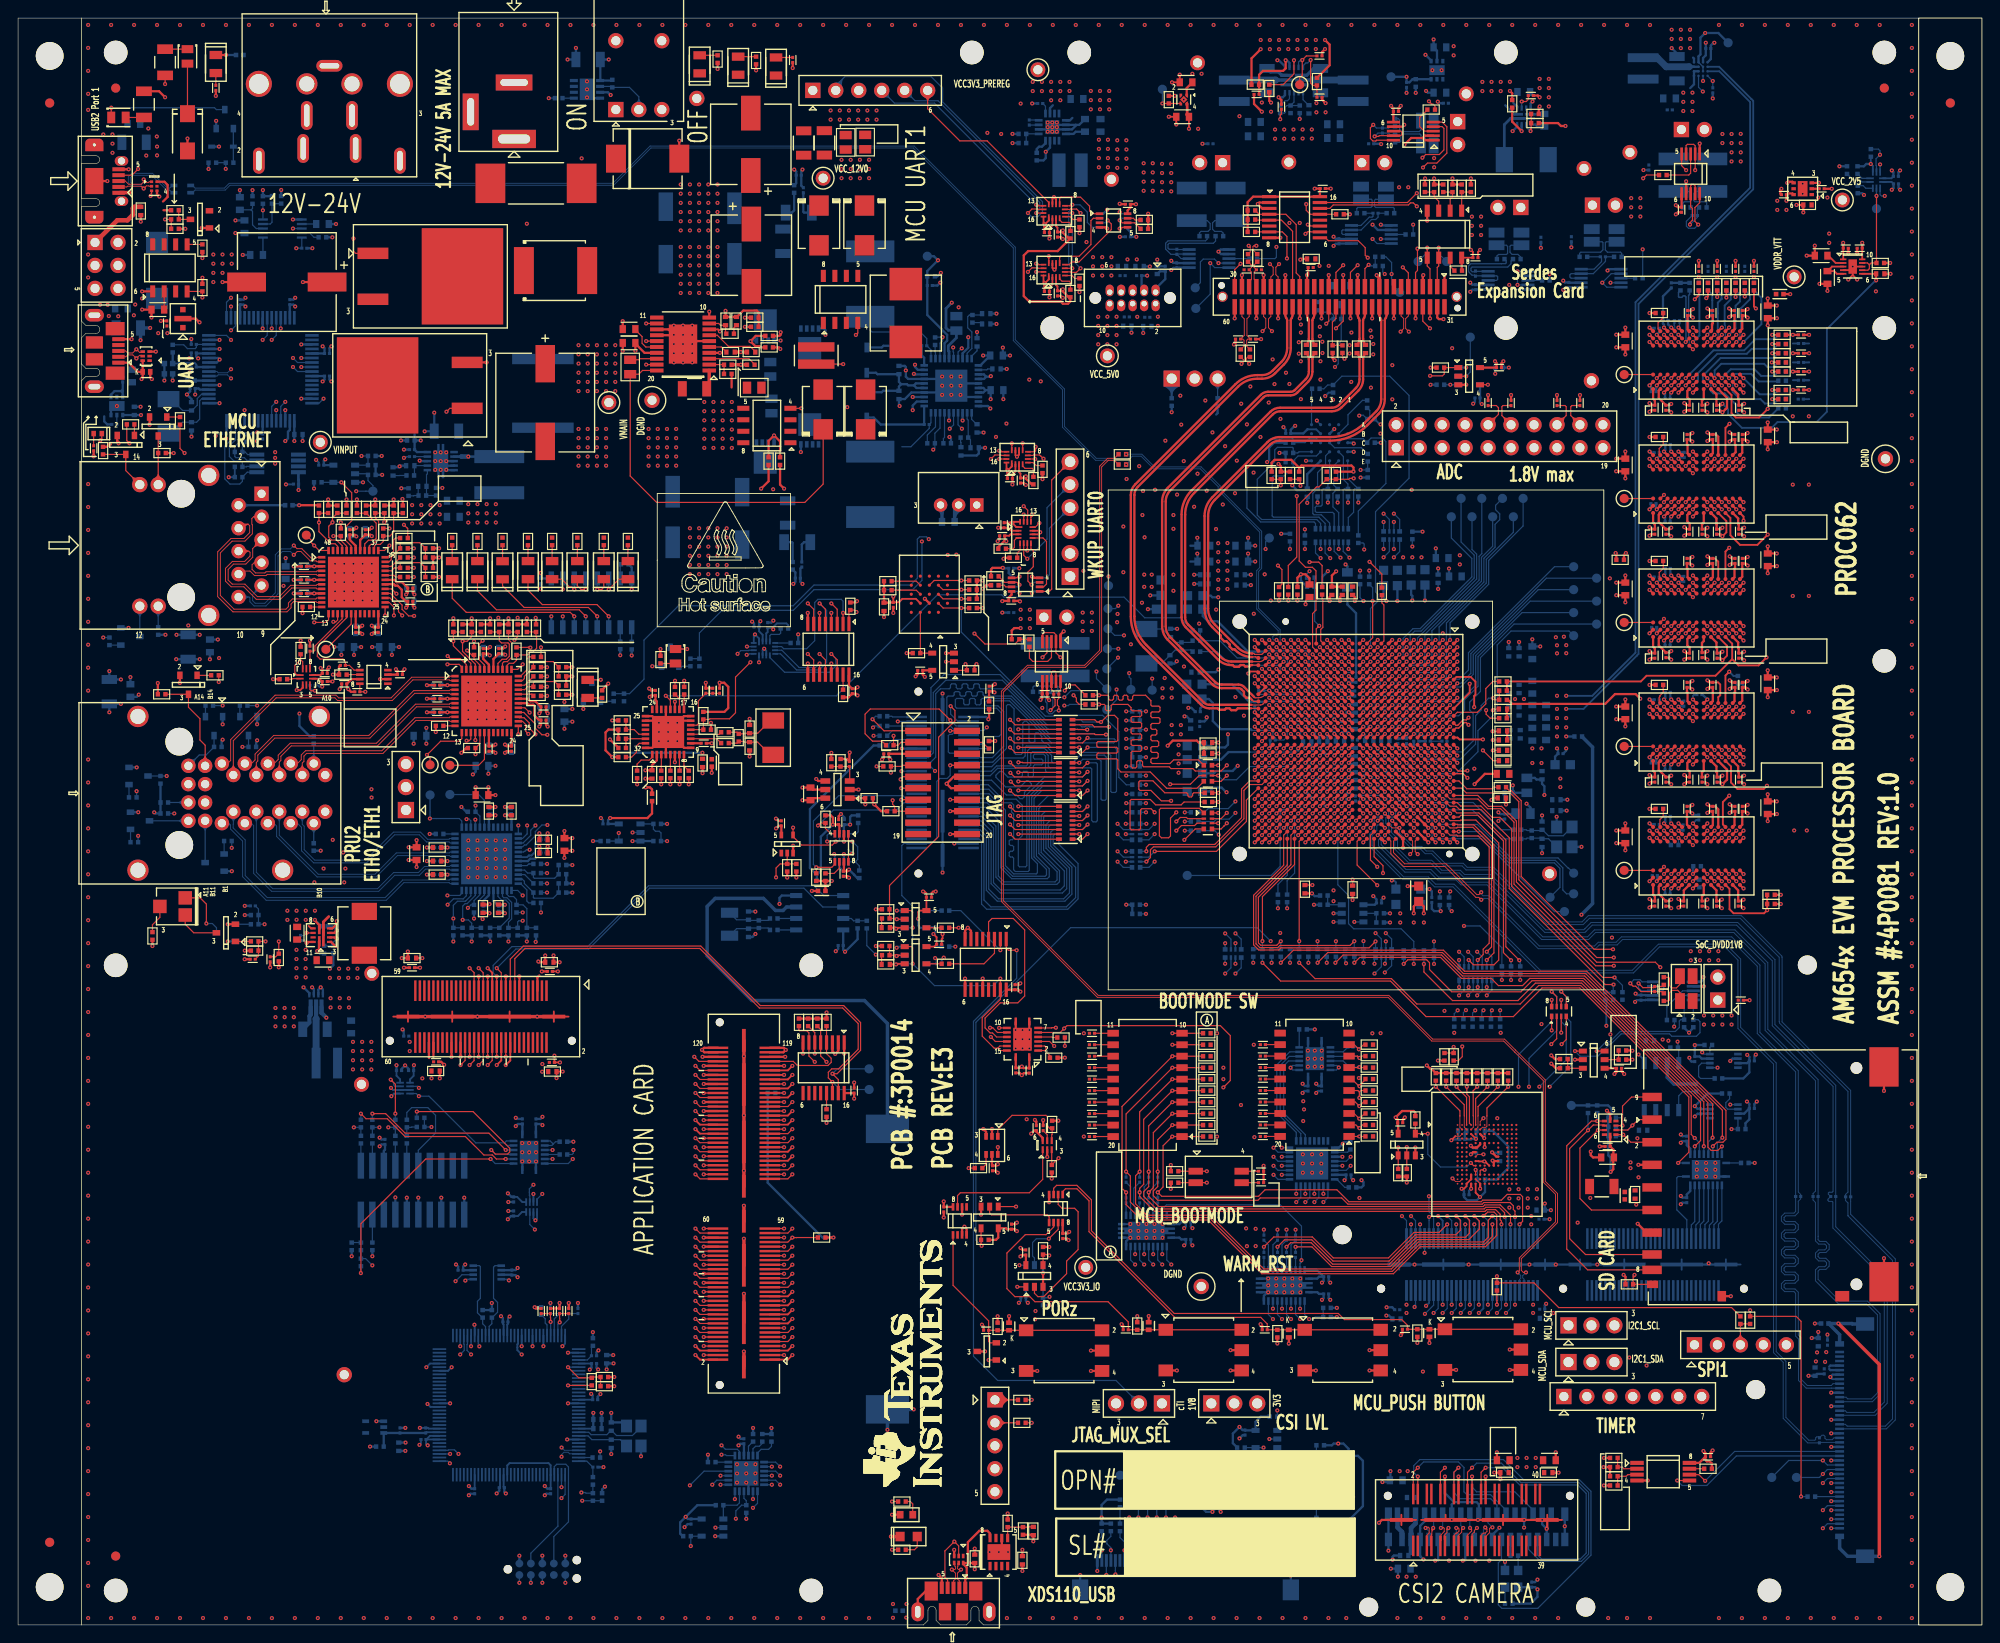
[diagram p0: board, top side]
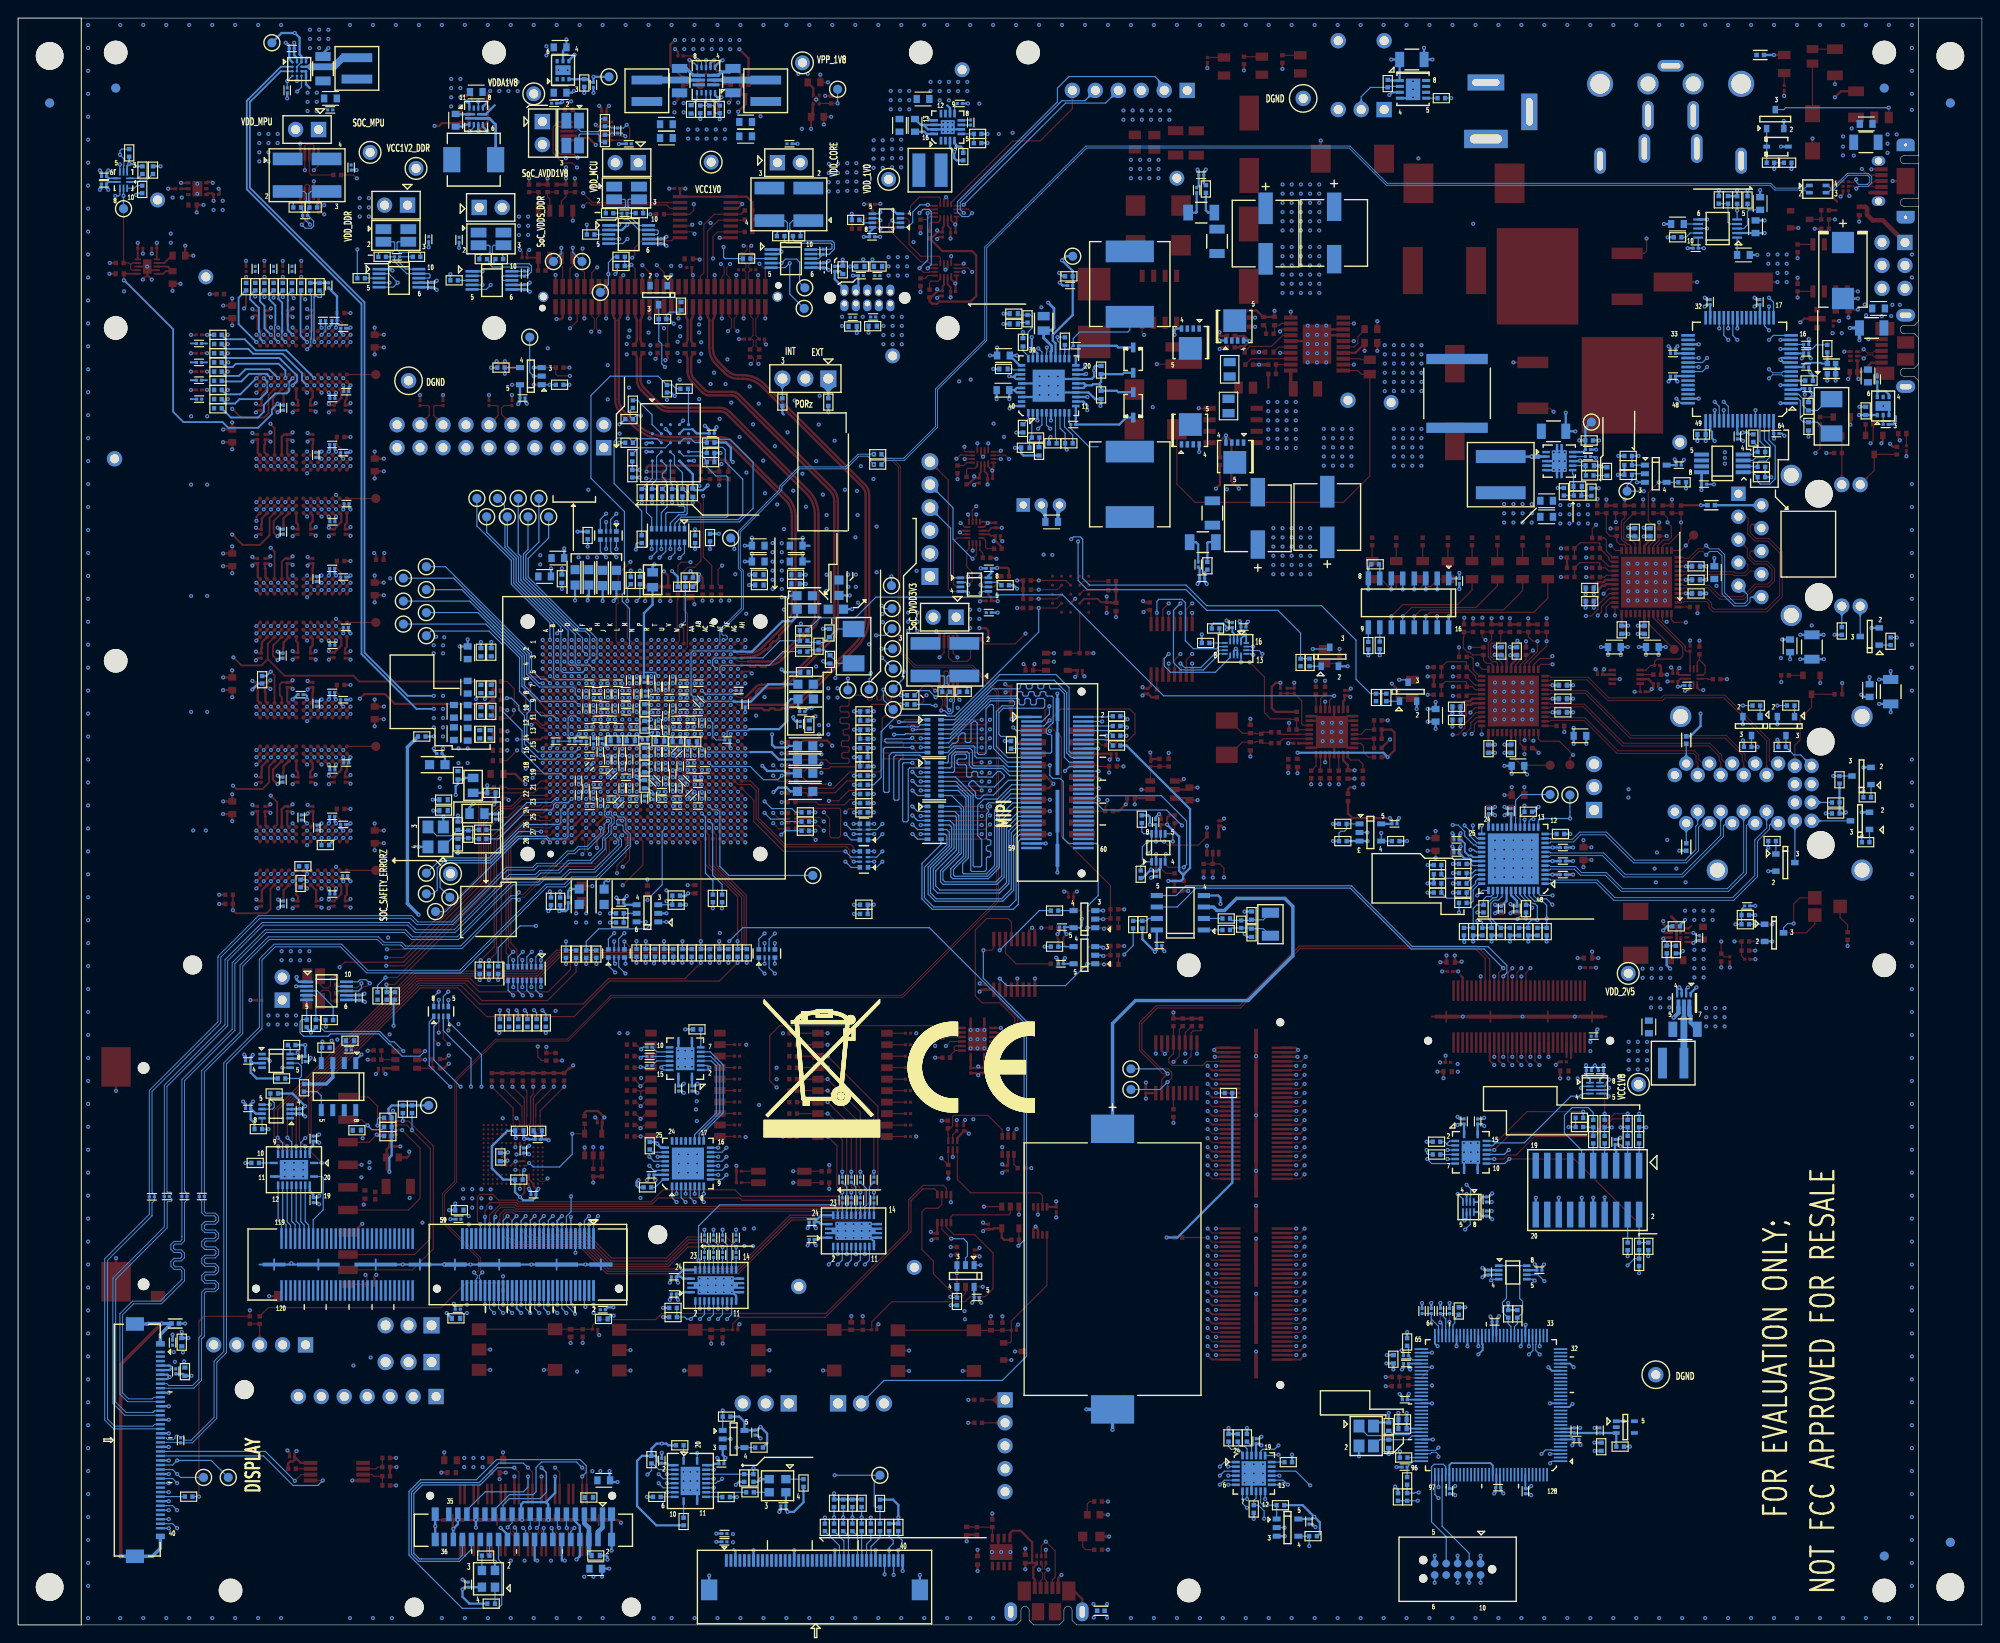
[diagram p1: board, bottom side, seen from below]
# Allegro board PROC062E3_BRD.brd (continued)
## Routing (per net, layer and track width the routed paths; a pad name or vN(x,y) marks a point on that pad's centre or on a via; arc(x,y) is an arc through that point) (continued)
PRG2_ETH1_D0P: length 31.4
  TOP w0.107: U31.1 47.8,104.98 47.68,104.87 43.54,104.87 41.25,102.58 35.46,102.58 35.15,102.88 28.42,102.88 23.51,97.97 23.51,95.66 23.16,95.31 J14.A1
PRG2_ETH1_D1M: length 27
  TOP w0.107: J14.A4 26.34,95.43 26.5,95.59 26.5,96.24 28.39,98.13 38.91,98.13 43.87,103.09 47.7,103.09 47.8,102.98 U31.5
PRG2_ETH1_D1P: length 27
  TOP w0.107: J14.A3 25.81,95.31 26.21,95.71 26.21,96.36 28.27,98.42 38.79,98.42 43.74,103.38 47.7,103.38 47.81,103.48 U31.4
PRG2_ETH1_D2M: length 23.7
  TOP w0.107: J14.A6 28.88,95.47 29.06,95.65 29.06,96.12 30.21,97.27 39.75,97.27 44.07,101.59 47.69,101.59 47.79,101.49 U31.8
PRG2_ETH1_D2P: length 23.7
  TOP w0.107: J14.A5 28.31,95.31 28.77,95.77 28.77,96.24 30.09,97.56 39.63,97.56 43.95,101.88 47.69,101.88 47.79,101.99 48.32,101.99
PRG2_ETH1_D3M: length 20.6
  TOP w0.107: J14.A8 31.42,95.37 31.61,95.55 31.61,96.14 31.91,96.43 40.35,96.43 44,100.09 47.68,100.09 47.78,99.99 U31.11
PRG2_ETH1_D3P: length 20.6
  TOP w0.107: J14.A7 30.88,95.31 31.32,95.75 31.32,96.26 31.78,96.73 40.23,96.73 43.88,100.38 47.68,100.38 47.78,100.49 U31.10
PRG2_ETH1_GPIO_0: length 43
  TOP w0.132: U31.39 53.57,106.41 53.74,106.59 54.1,106.59 54.58,107.07 54.58,108.68 54.23,109.03 R143.1 R144.2 55.24,109.35 v1(54.9,109)
  L05_SIG2 w0.084: v1(26.43,101.73) 33.53,108.82 33.53,110.49 34.49,111.46 39.38,111.46 40.83,110.01 46.4,110.01 48.01,108.39 51.8,108.39 52.41,109 v1(54.9,109)
  BOTTOM w0.132: R467.2 v1(26.43,101.73)
PRG2_ETH1_GPIO_1: length 6.8
  TOP w0.132: R141.2 R142.1 53.21,108.9 53.46,108.66 54.19,108.66 54.32,108.53 54.32,107.18 53.99,106.85 53.52,106.85 53.07,106.4 U31.40
PRG2_ETH1_LED1: length 4.3
  BOTTOM w0.132: Q16.3 J14.A11
PRG2_ETH1_LED2: length 24.6
  L05_SIG2 w0.084: v1(24.81,97.16) 24.81,99.52 23.75,100.58 17.45,100.58 14.53,97.66 14.53,93.98 15.47,93.03 J14.A13
  BOTTOM w0.132: Q12.3 R481.1 v1(24.81,97.16)
PRG2_ETH1_LED3: length 5
  BOTTOM w0.132: J14.A14 20.04,96.27 20.8,96.27 21.67,97.14 R482.1 Q13.3
PRG2_ETH1_LED_1000: length 37.9
  TOP w0.132: U31.46 50.07,106.41 48.13,108.34 v1(48.13,108.85) R137.2 R138.1
  L05_SIG2 w0.084: v1(22.62,101.73) 32.65,111.76 39.51,111.76 40.96,110.31 46.67,110.31 v1(48.13,108.85)
  BOTTOM w0.132: R468.2 v1(22.62,101.73)
PRG2_ETH1_LED_ACT: length 60.5
  TOP w0.132: U31.45 50.57,106.31 49.15,107.73 v1(49.15,108.85) 49.65,108.85 50.16,109.36 R139.1 R140.2
  L05_SIG2 w0.084: v1(49.15,108.85) 47.38,110.62 41.08,110.62 39.62,112.08 32.16,112.08 24.86,104.78 20.78,104.78 13.92,97.92 13.92,87.95 v1(13.28,87.31)
  BOTTOM w0.132: R512.1 v1(13.28,87.31)
PRG2_ETH1_LED_LINK/MCUBOOTMODE5: length 224
  TOP w0.132: v1(47.5,107.2) 47.77,106.93 48.89,106.93 49.57,106.26 U31.47 ; U34.Y2 143.16,108.19 143.16,111.91 143.53,112.28 143.53,116.63 143.13,117.03 142.37,117.03 141.67,117.73 141.67,124 143.58,125.92 143.85,125.92 144.7,126.77 R87.2 R88.1 147.15,126.77 147.25,126.87 v1(147.7,126.87)
  L10_SIG3 w0.084: v1(147.7,126.87) 147.32,126.87 145.92,125.48 139.32,125.48 138.96,125.83 138.96,133.26 132.65,139.57 122.2,139.57 119.37,136.73 106.56,136.73 104.83,135.01 98.62,135.01 98.04,135.59 84.2,135.59 82.38,133.78 73.85,133.78 73.43,133.36 31.11,133.36 23.22,125.47 23.22,112.96 25.7,110.47 25.7,99.64 27.51,97.83 39.18,97.83 43.31,101.95 43.31,103.89 46.61,107.19 47.48,107.19 v1(47.5,107.2)
PRG2_ETH2_D0M: length 32.7
  BOTTOM w0.107: J14.B2 23.8,88.62 23.79,88.61 23.79,88.19 25.12,86.86 25.12,82.91 27.56,80.48 40.59,80.48 42.53,82.43 47.68,82.43 47.77,82.52 U88.2
PRG2_ETH2_D0P: length 32.7
  BOTTOM w0.107: J14.B1 23.28,88.71 23.5,88.5 23.5,88.06 24.83,86.73 24.83,82.79 27.43,80.18 40.71,80.18 42.66,82.13 47.68,82.13 47.78,82.02 U88.1
PRG2_ETH2_D1M: length 30.5
  BOTTOM w0.107: U88.5 47.82,84.02 47.71,83.92 44.94,83.92 44.26,83.25 41.53,83.25 39.75,81.47 28.16,81.47 26.34,83.28 J14.B4
PRG2_ETH2_D1P: length 30.5
  BOTTOM w0.107: J14.B3 25.79,88.71 26.05,88.45 26.05,83.16 28.04,81.17 39.87,81.17 41.65,82.95 44.38,82.95 45.06,83.63 47.72,83.63 47.82,83.52 U88.4
PRG2_ETH2_D2M: length 24.9
  BOTTOM w0.107: J14.B6 28.88,87.36 33.19,83.06 39.47,83.06 41.83,85.42 47.69,85.42 47.79,85.52 U88.8
PRG2_ETH2_D2P: length 24.9
  BOTTOM w0.107: U88.7 47.82,85.02 47.71,85.13 41.95,85.13 39.59,82.77 33.07,82.77 28.59,87.24 28.59,88.4 28.28,88.71 J14.B5
PRG2_ETH2_D3M: length 23.1
  BOTTOM w0.107: U88.11 47.74,87.02 47.65,86.93 45.29,86.93 44.5,87.72 41.51,87.72 38.41,84.62 32.8,84.62 31.64,85.78 31.64,88.37 31.42,88.59 J14.B8
PRG2_ETH2_D3P: length 23.2
  BOTTOM w0.107: J14.B7 30.88,88.71 31.35,88.25 31.35,85.66 32.68,84.33 38.53,84.33 41.63,87.43 44.38,87.43 45.16,86.64 47.66,86.64 47.78,86.52 U88.10
PRG2_ETH2_GPIO_0: length 61.2
  L05_SIG2 w0.084: v1(55.8,77.92) 54.97,77.09 46.92,77.09 43.49,80.52 19.21,80.52 12.19,87.54 12.19,91.34 v1(13.1,92.25)
  BOTTOM w0.132: R495.2 v1(13.1,92.25) ; U88.39 53.57,80.61 53.71,80.46 54.06,80.46 54.58,79.95 54.58,78.11 54.23,77.77 R556.1 R555.2 55.24,77.79 55.38,77.92 v1(55.8,77.92)
PRG2_ETH2_GPIO_1: length 6.4
  BOTTOM w0.132: R558.2 R557.1 53.23,77.14 54.31,78.22 54.31,79.84 53.95,80.2 53.47,80.2 53.07,80.61 U88.40
PRG2_ETH2_LED1: length 4.6
  BOTTOM w0.132: Q15.3 J14.B11
PRG2_ETH2_LED2: length 52.5
  L03_SIG1 w0.084: v1(16.43,93.93) 16.43,88.95 15.37,87.88 15.37,84.85 16.65,83.57 20.57,83.57 23.62,86.61 33.53,86.61 35.69,88.77 35.69,90.68 34.29,92.08 21.64,92.08 J14.B13
  BOTTOM w0.132: Q14.3 R490.1 v1(16.43,93.93)
PRG2_ETH2_LED3: length 11.2
  TOP w0.132: J14.B14 20.68,97.34 20.11,97.92 20.11,100.27 18.84,101.54 Q5.3 R178.1
PRG2_ETH2_LED_1000: length 66.8
  TOP w0.132: R161.2 v1(22.19,104.33)
  L05_SIG2 w0.084: v1(22.19,104.33) 20.76,104.33 14.22,97.79 14.22,86.16 19.48,80.9 43.56,80.9 46.3,78.16 v1(48.13,78.16)
  BOTTOM w0.132: R561.1 R562.2 v1(48.13,78.16) 48.13,79.63 48.58,80.07 49.47,80.07 50.07,80.67 U88.46
PRG2_ETH2_LED_ACT: length 38.7
  L05_SIG2 w0.084: v1(23.62,85.98) 23.11,85.47 23.11,83.06 24.97,81.2 43.69,81.2 46.28,78.61 48.57,78.61 v1(49.17,78.01)
  BOTTOM w0.132: R559.2 R560.1 50.16,77.65 49.8,78.01 v1(49.17,78.01) 49.17,79.54 49.44,79.81 49.65,79.81 50.57,80.72 U88.45 ; R515.1 v1(23.62,85.98)
PRG2_ETH2_LED_LINK/MCUBOOTMODE8: length 228.5
  TOP w0.132: U34.AC5 v1(140.76,105.79) ; R81.1 R82.2 v1(139.64,126.1)
  L03_SIG1 w0.084: v1(139.64,126.1) 137.4,123.86 137.4,110.76 138.76,109.39 138.76,106.43 138.99,106.2 140.35,106.2 v1(140.76,105.79)
  L10_SIG3 w0.084: v1(139.64,126.1) 139.64,126.59 140.51,127.46 140.51,133.63 134.27,139.87 122.08,139.87 119.24,137.04 106.43,137.04 104.7,135.31 98.75,135.31 98.16,135.9 84.07,135.9 83,134.83 74.28,134.83 73.12,133.67 30.97,133.67 22.94,125.64 22.94,112.81 25.4,110.35 25.4,99.51 27.38,97.52 43.06,97.52 46.61,93.98 46.61,80.58 v1(47.5,79.69)
  BOTTOM w0.132: v1(47.5,79.69) 48.14,80.34 49.22,80.34 49.57,80.68 U88.47
PRG2_ETH_LED0: length 118.8
  TOP w0.132: v1(142.37,153.92) 142.58,154.14 U7.10
  L03_SIG1 w0.084: v1(142.37,153.92) 140.08,153.92 139.32,154.69 130.43,154.69 128.91,153.16 125.35,153.16 124.84,152.65 118.75,152.65 117.98,151.89 113.41,151.89 112.9,151.38 109.07,151.38 103.5,145.82 103.5,145.54 101.73,143.76 101.73,131.57 100.46,130.3 100.46,120.4 v1(100.71,120.14)
  BOTTOM w0.132: R464.2 R737.2 67.61,103.04 69.22,104.65 69.22,108.97 73.03,112.78 85.73,112.78 88.01,115.06 98.68,115.06 99.44,115.82 99.44,120.14 99.69,120.4 100.46,120.4 v1(100.71,120.14)
PRG2_ETH_LED1: length 108.7
  TOP w0.132: U7.11 142.77,154.79 v1(142.62,154.94)
  L03_SIG1 w0.084: v1(99.95,119.89) 99.95,130.56 101.47,132.08 101.47,145.54 107.68,151.75 112.76,151.75 113.55,152.54 118.27,152.54 118.89,153.16 124.33,153.16 124.84,153.67 127.89,153.67 129.92,155.7 142.11,155.7 142.62,155.19 v1(142.62,154.94)
  BOTTOM w0.132: v1(99.95,119.89) 99.95,115.57 98.93,114.55 88.01,114.55 85.72,112.27 77.85,112.27 75.34,109.76 R738.2 R458.2
PRG2_MDC: length 182.6
  TOP w0.132: v1(109.69,87.51) 110.26,86.95 RA5.16 ; J5.16 145.74,149.66 v1(146.54,150.46) ; U31.16 v1(50.57,97.9)
  L05_SIG2 w0.084: v1(50.57,97.9) 49.53,96.86 49.53,90.15 v1(50.57,89.11) 56.15,89.11 56.78,89.74 85.33,89.74 85.98,89.09 93.6,89.09 94.42,88.27 108.94,88.27 v1(109.69,87.51)
  L12_SIG4 w0.084: v1(109.69,87.51) 110.1,87.1 110.91,87.1 111.56,87.74 111.56,107.13 112.74,108.31 118.94,108.31 120.12,109.49 120.12,122.94 134.49,137.31 134.49,139.67 134.05,140.11 134.05,143.73 131.08,146.71 131.08,152.59 134.32,155.84 144.34,155.84 146.54,153.64 v1(146.54,150.46)
  BOTTOM w0.132: U88.16 v1(50.57,89.11)
PRG2_MDIO: length 180.2
  TOP w0.132: RA3.11 v1(110.61,94.33) ; v1(50.58,96.34) R198.1 51.07,97.51 U31.17 ; J5.15 v1(146.54,149.37)
  L05_SIG2 w0.084: v1(110.61,94.33) 111.07,93.88 111.07,89.32 110.8,89.05 94.4,89.05 93.27,90.18 54.16,90.18 54.03,90.05 51.2,90.05 v1(50.58,90.67) 49.85,91.4 49.85,95.6 v1(50.58,96.34)
  L12_SIG4 w0.084: v1(110.61,94.33) 111.25,94.98 111.25,107.25 112.61,108.61 118.81,108.61 119.81,109.61 119.81,123.06 134.19,137.44 134.19,139.55 133.75,139.99 133.75,143.6 130.77,146.58 130.77,152.72 134.2,156.15 144.5,156.15 147,153.65 147,149.83 v1(146.54,149.37)
  BOTTOM w0.132: U88.17 51.07,89.5 R498.1 v1(50.58,90.67)
PRG2_PRU0_GP0: length 40.2
  TOP w0.132: U34.AF18 v1(138.36,94.59) ; RA1.4 v1(117.35,98.1)
  L05_SIG2 w0.084: v1(117.35,98.1) 114.92,98.1 114.76,97.94 114.76,94.96 114.61,94.81 114.1,94.81 113.95,94.96 113.95,98.81 114.15,99.01 117.38,99.01 117.82,98.57 118.48,98.57 120.62,96.42 125.24,96.42 125.8,95.87 133.79,95.87 134.5,96.58 137.72,96.58 137.95,96.35 137.95,95 v1(138.36,94.59)
  BOTTOM w0.132: RA1.4 v1(117.35,98.1)
PRG2_PRU0_GP1: length 46.2
  TOP w0.132: v1(120.31,98.52) 119.12,98.52 119.04,98.6 RA1.5 ; U34.AE18 v1(139.16,94.59)
  L05_SIG2 w0.084: v1(120.31,98.52) 118.65,100.17 118.65,100.7 118.81,100.85 120.17,100.85 121.08,99.94 121.08,99 121.5,98.58 122.82,98.58 122.98,98.42 122.98,98.16 123.1,98.04 123.44,98.04 123.59,98.19 123.59,99.03 123.74,99.18 124.05,99.18 124.2,99.03 124.2,98.21 124.35,98.06 124.75,98.06 124.9,98.21 124.9,98.4 125.06,98.55 125.36,98.55 125.51,98.4 125.51,98.09 125.67,97.94 128.72,97.94 128.87,97.79 128.87,97.37 129.02,97.22 129.33,97.22 129.48,97.37 129.48,98.31 129.65,98.48 129.93,98.48 130.09,98.32 130.09,97.37 130.24,97.22 130.55,97.22 130.7,97.37 130.7,98.22 130.9,98.42 131.1,98.42 131.31,98.2 131.31,97.37 131.46,97.22 131.79,97.22 131.94,97.37 131.94,97.94 132.09,98.09 134.1,98.09 134.26,97.94 134.26,97.84 134.41,97.69 134.71,97.69 134.86,97.84 134.86,98.52 135.02,98.68 135.36,98.68 135.85,98.18 138.07,98.18 138.27,97.98 138.72,97.98 139.55,97.15 139.55,94.98 v1(139.16,94.59)
  BOTTOM w0.132: v1(120.31,98.52) 119.12,98.52 119.04,98.6 RA1.5
PRG2_PRU0_GP2: length 49
  TOP w0.132: v1(118.27,98.15) 117.71,97.6 RA1.3 ; U34.AH17 v1(136.76,95.39)
  L05_SIG2 w0.084: v1(118.27,98.15) 117.78,97.67 117.78,96.85 118.13,96.5 118.7,96.5 120.25,94.95 120.25,92.68 120.4,92.52 121.65,92.52 121.81,92.68 121.81,93.18 122.04,93.42 124.99,93.42 126.21,92.2 127.81,92.2 127.96,92.35 127.96,93.63 128.11,93.78 128.42,93.78 128.57,93.63 128.57,92.27 128.72,92.11 129.03,92.11 129.18,92.27 129.18,93.63 129.33,93.78 129.64,93.78 129.79,93.63 129.79,92 129.94,91.85 130.21,91.85 130.4,92.04 130.4,93.63 130.55,93.78 130.85,93.78 131.05,93.58 131.05,91.05 131.21,90.9 131.97,90.9 132.12,91.05 132.12,93.28 132.27,93.43 134.19,93.43 136.14,95.39 v1(136.76,95.39)
  BOTTOM w0.132: RA1.3 121.15,97.6 121.31,97.76 121.31,97.95 121.22,98.04 118.38,98.04 v1(118.27,98.15)
PRG2_PRU0_GP3: length 40.6
  TOP w0.132: U34.AG18 v1(137.56,94.59) ; RA1.2 v1(117.35,97.1)
  L05_SIG2 w0.084: v1(117.35,97.1) 116.86,97.59 115.55,97.59 115.4,97.44 115.4,95.3 115.7,95 116.38,95 117.29,95.91 118.54,95.91 119.82,94.63 119.82,92.17 120.25,91.75 121.77,91.75 122.37,92.35 125.06,92.35 125.74,91.67 127.72,91.67 128.11,91.27 128.11,90.68 128.35,90.44 129.09,90.44 129.24,90.6 129.24,91.18 129.39,91.33 129.7,91.33 129.85,91.18 129.85,90.6 130,90.44 130.35,90.44 130.5,90.29 130.5,89.23 130.66,89.08 130.96,89.08 131.11,89.23 131.11,90.29 131.26,90.44 132.89,90.44 133.14,90.69 133.14,92.65 133.45,92.96 134.3,92.96 136.32,94.98 137.16,94.98 v1(137.56,94.59)
  BOTTOM w0.132: RA1.2 v1(117.35,97.1)
PRG2_PRU0_GP4: length 57.7
  TOP w0.132: U34.AG17 v1(137.56,95.39) ; RA1.1 117.71,96.53 v1(118.27,97.1)
  L05_SIG2 w0.084: v1(137.56,95.39) 137.16,95.78 134.97,95.78 133.63,94.44 132.81,94.44 131.83,95.42 131.43,95.42 131.28,95.27 131.28,94.42 131.13,94.27 130.83,94.27 130.67,94.42 130.67,95.27 130.52,95.42 130.22,95.42 130.06,95.27 130.06,94.42 129.91,94.27 129.61,94.27 129.45,94.42 129.45,95.27 129.3,95.42 129.02,95.42 128.36,94.75 126.8,94.75 126.65,94.6 126.65,93.15 126.47,92.98 126.17,92.98 125.81,93.34 125.81,95.42 125.62,95.61 125.14,95.61 124.99,95.45 124.99,94.63 124.84,94.48 124.53,94.48 124.38,94.63 124.38,95.45 124.23,95.61 123.86,95.61 123.71,95.45 123.71,93.98 123.56,93.83 123.25,93.83 123.1,93.98 123.1,95.86 122.95,96.01 121.89,96.01 121.61,95.73 121.61,93.86 121.43,93.69 121.02,93.69 120.87,93.84 120.87,95.26 119.03,97.1 v1(118.27,97.1)
  BOTTOM w0.132: RA1.1 116.61,96.54 120.5,96.54 120.84,96.21 120.84,92.23 120.95,92.11 121.33,92.11 121.47,92.24 121.47,96.91 121.28,97.1 v1(118.27,97.1)
PRG2_PRU0_GP5: length 56
  TOP w0.132: U34.AF17 v1(138.36,95.39) ; RA3.8 v1(117.35,95.4)
  L05_SIG2 w0.084: v1(138.36,95.39) 138.75,95.78 138.75,97.15 138.52,97.38 133.41,97.38 132.87,96.84 125.68,96.84 124.92,97.6 120.27,97.6 118.4,99.47 113.49,99.47 113.34,99.32 113.34,94.35 113.49,94.19 116.15,94.19 v1(117.35,95.4)
  BOTTOM w0.132: v1(117.35,95.4) 117.75,95.79 119.56,95.79 119.76,95.6 119.76,91.38 119.89,91.25 120.2,91.25 120.34,91.38 120.34,96.03 120.12,96.25 117.45,96.25 RA3.8
PRG2_PRU0_GP6: length 43.8
  TOP w0.132: RA3.7 117.71,94.83 v1(118.27,95.4) ; R209.2 130.02,92.08 129.88,91.94 129.88,91.75 129.75,91.62 129.49,91.62 129.35,91.75 129.35,91.94 129.22,92.08 126.81,92.08 125.49,93.4 124.07,93.4 123.94,93.27 123.94,92.48 124.07,92.34 125.27,92.34 126.43,91.19 v1(127.51,91.19)
  L05_SIG2 w0.084: v1(118.27,95.4) 119.33,94.34 119.33,91.79 119.73,91.38 124.85,91.38 125.05,91.19 v1(127.51,91.19)
  BOTTOM w0.132: RA3.7 118.6,94.83 118.73,94.7 118.73,89.02 118.89,88.86 119.22,88.86 119.35,88.99 119.35,95.27 119.22,95.4 v1(118.27,95.4)
PRG2_PRU0_GP7: length 40.5
  TOP w0.132: RA3.6 v1(117.35,94.33) ; U34.AC19 v1(140.76,93.79)
  L03_SIG1 w0.084: v1(117.35,94.33) 117.81,93.88 117.81,88.38 118.1,88.1 119.04,88.1 119.19,88.25 119.19,89.55 119.34,89.7 119.7,89.7 119.85,89.55 119.85,88.25 120,88.1 126.94,88.1 127.19,88.34 130.18,88.34 131.56,86.96 135.3,86.96 136.14,87.8 136.95,87.8 137.16,88.01 137.16,92.39 137.35,92.58 140.1,92.58 140.35,92.83 140.35,93.23 140.76,93.64 v1(140.76,93.79)
  BOTTOM w0.132: RA3.6 v1(117.35,94.33)
PRG2_PRU0_GP8: length 31.2
  TOP w0.132: v1(125.69,89.92) 125.29,90.31 124.26,90.31 124.13,90.18 124.13,88.11 123.99,87.98 123.12,87.98 122.97,88.13 122.97,91.2 123.1,91.34 125.21,91.34 125.8,90.74 128.62,90.74 128.94,91.06 R211.2 ; v1(118.27,94.4) 117.71,93.83 RA3.5
  L05_SIG2 w0.084: v1(118.27,94.4) 118.82,93.85 118.82,91.75 120.25,90.32 125.28,90.32 v1(125.69,89.92)
  BOTTOM w0.132: RA3.5 117.71,93.83 v1(118.27,94.4)
PRG2_PRU0_GP9: length 23
  TOP w0.132: v1(128.97,86.87) 130.18,88.08 RA4.4 ; RA3.4 v1(117.35,93.33)
  L05_SIG2 w0.084: v1(128.97,86.87) 117.16,86.87 116.59,87.44 116.59,92.57 v1(117.35,93.33)
  BOTTOM w0.132: RA3.4 v1(117.35,93.33)
PRG2_PRU0_GP10: length 26.1
  TOP w0.132: RA3.3 117.71,92.83 v1(118.27,93.4) ; RA4.3 130.37,88.71 130.11,88.45 128.65,88.45 v1(128.08,87.88)
  L05_SIG2 w0.084: v1(118.27,93.4) 117.81,92.94 117.81,89.38 118.08,89.11 118.67,89.11 118.83,88.96 118.83,88.54 118.98,88.39 119.28,88.39 119.44,88.54 119.44,89.22 119.59,89.38 119.89,89.38 120.05,89.22 120.05,88.54 120.2,88.39 120.5,88.39 120.66,88.54 120.66,88.96 120.81,89.11 122.96,89.11 123.11,88.96 123.11,88.52 123.26,88.37 123.57,88.37 123.72,88.52 123.72,88.96 123.87,89.11 126.85,89.11 v1(128.08,87.88)
  BOTTOM w0.132: v1(118.27,93.4) 117.71,92.83 RA3.3
PRG2_PRU0_GP11: length 26.5
  TOP w0.132: v1(128.08,88.9) 128.53,89.35 129.2,89.35 129.34,89.21 RA4.2 ; RA3.2 v1(117.35,92.33)
  L05_SIG2 w0.084: v1(117.35,92.33) 116.9,91.88 116.9,88.32 117.15,88.06 118.86,88.06 119.02,87.91 119.02,87.56 119.17,87.41 120.69,87.41 120.85,87.56 120.85,87.91 121,88.06 123.01,88.06 123.16,87.91 123.16,87.51 123.32,87.35 123.62,87.35 123.77,87.51 123.77,87.91 123.93,88.06 126.15,88.06 126.76,87.45 129.47,87.45 129.62,87.6 129.62,88.16 129.47,88.31 128.67,88.31 v1(128.08,88.9)
  BOTTOM w0.132: RA3.2 v1(117.35,92.33)
PRG2_PRU0_GP16: length 27.7
  TOP w0.132: RA4.1 131.12,89.86 130.62,90.36 126.36,90.36 126.21,90.2 126.21,87.33 126.44,87.1 127.23,87.1 127.44,87.31 127.44,89.28 v1(128.08,89.92) ; RA3.1 117.71,91.77 v1(118.27,92.33)
  L05_SIG2 w0.084: v1(118.27,92.33) 118.27,91.67 120.43,89.51 127.67,89.51 v1(128.08,89.92)
  BOTTOM w0.132: v1(118.27,92.33) 117.71,91.77 RA3.1
PRG2_PRU1_GP0: length 40.1
  TOP w0.132: U34.AH15 v1(136.76,96.99) ; RA5.8 v1(117.35,90.57)
  L12_SIG4 w0.084: v1(136.76,96.99) 135.65,96.99 134.54,98.09 131.19,98.09 130.59,97.5 130.38,97.5 130.31,97.57 130.09,97.57 129.88,97.35 129.88,97.13 129.95,97.07 129.95,96.85 129.73,96.64 129.51,96.64 129.45,96.7 129.23,96.7 129.01,96.49 129.01,96.27 129.08,96.2 129.08,95.99 128.87,95.77 127.73,95.77 127.57,95.92 127.57,96.26 127.42,96.41 127.12,96.41 126.96,96.26 126.96,95.92 126.81,95.77 126.51,95.77 126.35,95.92 126.35,96.29 126.17,96.47 125.9,96.47 125.74,96.32 125.74,95.92 125.59,95.77 125.31,95.77 125.05,95.5 124.11,95.5 123.95,95.66 123.95,95.98 123.8,96.13 123.5,96.13 123.34,95.98 123.34,95.66 123.19,95.5 122.89,95.5 122.73,95.66 122.73,95.98 122.58,96.13 122.28,96.13 122.12,95.98 122.12,95.66 121.9,95.43 118.99,95.43 118.84,95.28 118.84,91.9 118.61,91.68 117.94,91.68 117.79,91.83 117.79,94.84 117.63,94.99 116.47,94.99 116.32,94.84 116.32,91.61 v1(117.35,90.57)
  BOTTOM w0.132: RA5.8 v1(117.35,90.57)
PRG2_PRU1_GP1: length 42.9
  TOP w0.132: RA5.7 117.71,90.01 v1(118.27,90.57) ; U34.AC16 v1(140.76,96.19)
  L12_SIG4 w0.084: v1(140.76,96.19) 140.36,96.58 136.15,96.58 136.14,96.58 135.25,96.58 134.61,97.21 131.17,97.21 128.71,94.75 125.95,94.75 125.8,94.6 125.8,94.16 125.65,94.01 125.29,94.01 125.14,94.16 125.14,94.6 124.99,94.75 124.16,94.75 124.01,94.6 124.01,93.15 123.85,93 123.55,93 123.4,93.15 123.4,94.6 123.25,94.75 122.97,94.75 122.76,94.55 122.06,94.55 121.91,94.7 121.91,94.96 121.76,95.12 121.45,95.12 121.3,94.96 121.3,94.7 121.15,94.55 120.84,94.55 120.69,94.7 120.69,94.96 120.54,95.12 120.24,95.12 120.08,94.96 120.08,94.7 119.93,94.55 119.58,94.55 119.43,94.4 119.43,94.06 119.58,93.91 121.89,93.91 122.05,93.75 122.05,93.22 121.89,93.07 119.58,93.07 119.43,92.92 119.43,90.72 119.27,90.57 v1(118.27,90.57)
  BOTTOM w0.132: RA5.7 117.71,90.01 v1(118.27,90.57)
PRG2_PRU1_GP2: length 40.2
  TOP w0.132: RA5.6 v1(117.35,89.51) ; U34.AD17 v1(139.96,95.39)
  L12_SIG4 w0.084: v1(139.96,95.39) 139.55,95.8 135.33,95.8 134.26,96.86 132.27,96.86 130.31,94.89 130.09,94.89 129.89,95.09 129.68,95.09 129.46,94.88 129.46,94.66 129.66,94.46 129.66,94.25 129.25,93.84 126.59,93.84 125.16,92.41 123.95,92.41 123.8,92.25 123.8,90.99 123.64,90.84 123.34,90.84 123.19,90.99 123.19,92.25 123.03,92.41 121.4,92.41 121.25,92.25 121.25,90.36 121.09,90.21 120.81,90.21 120.64,90.38 120.64,92.25 120.48,92.41 120.11,92.41 119.96,92.25 119.96,88.68 119.7,88.42 119.21,88.42 119.06,88.57 119.06,89.86 118.81,90.11 117.96,90.11 v1(117.35,89.51)
  BOTTOM w0.132: RA5.6 v1(117.35,89.51)
PRG2_PRU1_GP3: length 42.4
  TOP w0.132: RA5.5 117.71,89.01 v1(118.27,89.57) ; U34.AH14 v1(136.76,98.59)
  L12_SIG4 w0.084: v1(118.27,89.57) 118.73,89.11 118.73,88.38 118.32,87.98 115.7,87.98 115.04,88.64 115.04,96.56 116.11,97.63 120.11,97.63 121.02,98.54 124.86,98.54 125.41,99.1 129.26,99.1 131.2,101.04 134.3,101.04 v1(136.76,98.59)
  BOTTOM w0.132: v1(118.27,89.57) 117.71,89.01 RA5.5
PRG2_PRU1_GP4: length 40.1
  TOP w0.132: RA5.4 v1(117.35,88.51) ; U34.AG14 v1(137.56,97.79)
  L12_SIG4 w0.084: v1(117.35,88.51) 115.75,88.51 115.43,88.84 115.43,96.16 115.84,96.57 118.82,96.57 118.98,96.73 118.98,97.1 119.13,97.25 119.43,97.25 119.59,97.1 119.59,96.73 119.74,96.57 120.72,96.57 121.77,97.62 122.95,97.62 123.1,97.77 123.1,98.05 123.25,98.21 123.56,98.21 123.71,98.05 123.71,97.77 123.86,97.62 124.17,97.62 124.32,97.77 124.32,98.05 124.47,98.21 124.78,98.21 124.93,98.05 124.93,97.77 125.08,97.62 125.41,97.62 125.59,97.8 125.62,97.8 125.77,97.96 125.77,98.52 125.92,98.67 126.23,98.67 126.38,98.52 126.38,97.96 126.53,97.8 128.56,97.8 130.79,100.03 134.32,100.03 136.29,98.06 137.29,98.06 v1(137.56,97.79)
  BOTTOM w0.132: RA5.4 v1(117.35,88.51)
PRG2_PRU1_GP5: length 42.8
  TOP w0.132: RA5.3 117.71,88.01 v1(118.27,88.57) ; U34.AG15 v1(137.56,96.99)
  L12_SIG4 w0.084: v1(118.27,88.57) 117.79,89.05 116.13,89.05 115.97,89.2 115.97,89.74 116.13,89.89 116.65,89.89 116.81,90.04 116.81,90.35 116.65,90.5 116.02,90.5 115.82,90.71 115.82,95.6 116.17,95.95 121.36,95.95 121.88,96.47 123.08,96.47 123.23,96.62 123.23,97.1 123.38,97.25 123.69,97.25 123.84,97.1 123.84,96.62 123.99,96.47 124.91,96.47 125.22,96.79 125.71,96.79 125.87,96.94 125.87,97.34 126.02,97.49 126.32,97.49 126.48,97.34 126.48,96.94 126.63,96.79 128.67,96.79 129.21,97.32 129.21,97.54 129.11,97.63 129.11,97.85 129.33,98.07 129.54,98.07 129.64,97.97 129.85,97.97 130.07,98.19 130.07,98.4 129.97,98.5 129.97,98.71 130.19,98.93 130.4,98.93 130.5,98.83 130.71,98.83 130.9,99.02 132.96,99.02 133.11,99.17 133.11,99.43 133.26,99.58 133.57,99.58 133.72,99.43 133.72,99.17 133.87,99.02 134.28,99.02 135.79,97.5 137.04,97.5 v1(137.56,96.99)
  BOTTOM w0.132: v1(118.27,88.57) 117.71,88.01 RA5.3
PRG2_PRU1_GP6: length 30.3
  TOP w0.132: RA2.3 130.6,93.98 129.64,93.03 v1(127.4,93.03) ; RA5.2 v1(117.35,87.51)
  L10_SIG3 w0.084: v1(117.35,87.51) 118.22,86.65 118.95,86.65 119.1,86.8 119.1,88.59 119.26,88.74 119.61,88.74 119.76,88.59 119.76,88.18 119.92,88.03 120.87,88.03 121.02,87.88 121.02,87.52 120.87,87.37 119.92,87.37 119.76,87.22 119.76,86.8 119.92,86.65 123.04,86.65 123.19,86.8 123.19,87.92 123.34,88.07 123.7,88.07 123.85,87.92 123.85,86.8 124,86.65 126.4,86.65 127.1,87.35 127.1,91.02 127.1,91.02 127.1,91.35 127.08,91.38 127.08,92.7 v1(127.4,93.03)
  BOTTOM w0.132: RA5.2 v1(117.35,87.51)
PRG2_PRU1_GP7: length 43
  TOP w0.132: v1(118.27,87.51) 117.71,86.95 RA5.1 ; U34.AE15 v1(139.16,96.99)
  L10_SIG3 w0.084: v1(139.16,96.99) 139.55,96.6 139.55,96.03 139.31,95.79 136.18,95.79 134.78,94.39 131.99,94.39 131.03,93.42 127.51,93.42 127.49,93.43 127.23,93.43 126.68,92.89 126.68,89.89 125.94,89.15 118.16,89.15 118.15,89.17 118.1,89.17 117.76,89.51 117.76,92.5 117.52,92.74 116.65,92.74 116.38,92.48 116.38,88.39 116.78,87.99 117.79,87.99 v1(118.27,87.51)
  BOTTOM w0.132: RA5.1 117.71,86.95 v1(118.27,87.51)
PRG2_PRU1_GP8: length 33.8
  TOP w0.132: RA2.4 131.12,93.33 130.37,92.58 127,92.58 125.2,94.38 121.96,94.38 121.61,94.73 121.61,95.7 121.48,95.83 119.43,95.83 119.29,95.96 119.29,96.34 119.43,96.47 121.48,96.47 121.61,96.6 121.61,96.98 121.48,97.11 119.43,97.11 119.29,97.24 119.29,97.62 119.43,97.75 121.48,97.75 121.61,97.88 121.61,100.28 121.25,100.64 120.5,100.64 v1(119.76,99.91) 119.31,99.91 119.06,100.16 RA1.8
  BOTTOM w0.132: RA1.8 117.51,100.16 117.76,99.91 v1(119.76,99.91)
PRG2_PRU1_GP9: length 28.8
  TOP w0.132: RA1.7 118.8,99.6 119.03,99.37 v1(120.64,99.37)
  L10_SIG3 w0.084: v1(120.64,99.37) 121.32,98.69 121.32,98.08 121.17,97.93 119.92,97.93 119.77,97.78 119.77,97.42 119.92,97.27 121.17,97.27 121.32,97.11 121.32,96.76 121.17,96.61 119.92,96.61 119.77,96.45 119.77,96.1 119.92,95.95 121.17,95.95 121.32,95.79 121.32,95.44 121.17,95.29 119.92,95.29 119.77,95.13 119.77,94.78 119.92,94.63 121.17,94.63 121.32,94.47 121.32,94.12 121.17,93.97 119.92,93.97 119.77,93.81 119.77,93.46 119.92,93.3 121.17,93.3 121.32,93.15 121.32,92.1 121.47,91.95 v1(122.54,91.95)
  BOTTOM w0.132: v1(120.64,99.37) 118.49,99.37 118.4,99.46 118.07,99.46 117.97,99.37 117.64,99.37 117.41,99.6 RA1.7 ; R494.2 v1(122.54,91.95)
PRG2_PRU1_GP10: length 20.4
  TOP w0.132: v1(118.23,99.07) 117.22,99.07 117.19,99.1 RA1.6
  L10_SIG3 w0.084: v1(118.23,99.07) 118.78,98.52 118.78,90.08 118.94,89.92 119.65,89.92 119.8,90.07 119.8,90.78 119.95,90.93 120.31,90.93 120.46,90.78 120.46,90.07 120.61,89.92 120.97,89.92 121.12,90.07 121.12,90.78 121.27,90.93 121.63,90.93 121.78,90.78 121.78,90.07 121.93,89.92 v1(122.54,89.92)
  BOTTOM w0.132: v1(118.23,99.07) 117.78,99.07 117.76,99.1 RA1.6 ; R500.2 v1(122.54,89.92)
PRG2_PRU1_GP11: length 30
  TOP w0.132: RA2.1 131.12,95.13 130.54,95.72 127.79,95.72 127.38,95.31 125.42,95.31 125.27,95.47 125.27,95.77 125.4,95.91 125.95,95.91 126.08,96.04 126.08,96.41 125.95,96.55 125.4,96.55 125.27,96.68 125.27,97.05 125.4,97.19 126,97.19 126.13,97.32 126.13,97.69 126,97.83 125.4,97.83 125.27,97.96 125.27,98.33 125.4,98.47 125.8,98.47 125.93,98.6 125.93,98.97 125.8,99.11 125.4,99.11 125.27,99.24 125.27,99.61 125.4,99.75 126.15,99.75 126.28,99.88 126.28,100.25 126.15,100.39 125.4,100.39 125.27,100.52 125.27,100.89 125.4,101.03 126.15,101.03 126.28,101.16 126.28,101.53 126.15,101.67 125.4,101.67 125.27,101.8 125.27,102.28 124.68,102.87 123.38,102.87 123.25,102.74 123.25,102.46 123.12,102.33 122.85,102.33 122.72,102.46 122.72,102.74 122.59,102.87 122.33,102.87 122.19,102.74 122.19,102.46 122.06,102.33 121.8,102.33 121.67,102.46 121.67,102.74 121.53,102.87 121.27,102.87 121.14,102.74 121.14,102.46 121.01,102.33 120.74,102.33 120.61,102.46 120.61,102.74 120.48,102.87 v1(119.54,102.87) R180.1
  BOTTOM w0.132: R180.1 v1(119.54,102.87)
PRG2_PRU1_GP16: length 30.2
  TOP w0.132: R183.1 v1(119.54,101.85) 120.11,101.85 120.24,101.72 120.24,101.29 120.38,101.16 120.75,101.16 120.88,101.29 120.88,101.72 121.02,101.85 122.73,101.85 123.08,101.5 123.08,101.28 123.21,101.15 124.12,101.15 124.25,101.02 124.25,100.64 124.12,100.51 123.21,100.51 123.08,100.38 123.08,100 123.21,99.87 124.12,99.87 124.25,99.74 124.25,99.36 124.12,99.23 123.21,99.23 123.08,99.1 123.08,98.72 123.21,98.59 124.12,98.59 124.25,98.46 124.25,98.08 124.12,97.95 123.21,97.95 123.08,97.82 123.08,97.44 123.21,97.31 124.12,97.31 124.25,97.18 124.25,96.8 124.12,96.67 123.21,96.67 123.08,96.54 123.08,94.98 123.24,94.83 123.58,94.83 123.71,94.96 123.71,95.5 123.84,95.63 124.22,95.63 124.35,95.5 124.35,95.09 124.48,94.96 127.29,94.96 127.5,94.75 129.91,94.75 130.18,94.48 RA2.2
  BOTTOM w0.132: R183.1 v1(119.54,101.85)
PRG2_RGMII1_ETH1_CLK: length 30.1
  TOP w0.132: U31.15 50.07,98.03 49.88,97.85 v1(49.59,97.85) ; R170.2 v1(73.66,104.47)
  L10_SIG3 w0.084: v1(73.66,104.47) 73.66,102.11 72.05,100.49 61.06,100.49 59.56,99 50.74,99 v1(49.59,97.85)
PRG2_RGMII1_ETH1_CLK_OUT: length 7.1
  TOP w0.132: 51.57,98.74 51.57,95.76 50.93,95.12 TP17.1
PRG2_RGMII1_ETH1_RBIAS: length 1.3
  TOP w0.132: U31.12 R188.1
PRG2_RGMII1_RD0: length 75.5
  TOP w0.132: R168.1 v1(58.5,103.82) ; RA1.13 v1(110.61,98.1)
  L05_SIG2 w0.084: v1(110.61,98.1) 110.15,98.55 110.15,100.36 109.38,101.13 100.1,101.13 96.51,104.72 78.55,104.72 73.03,110.25 56.79,110.25 56.52,109.98 54.46,107.91 54.46,105.57 56.21,103.82 v1(58.5,103.82)
PRG2_RGMII1_RD0_R: length 6.3
  TOP w0.132: R179.1 R167.2 59.33,104.39 57.09,104.39 56.98,104.28 R168.2 56.35,103.82 56.02,103.48 U31.33
PRG2_RGMII1_RD1: length 72.5
  TOP w0.132: v1(109.69,99.1) 110.19,98.6 RA1.12 ; R162.1 v1(58.5,104.96)
  L05_SIG2 w0.084: v1(109.69,99.1) 108.12,100.67 99.91,100.67 96.42,104.17 92.66,104.17 92.25,103.76 78.87,103.76 72.84,109.79 56.98,109.79 54.91,107.72 54.91,105.8 55.76,104.96 v1(58.5,104.96)
PRG2_RGMII1_RD1_R: length 2.1
  TOP w0.132: R162.2 56.98,104.95 56.02,103.98 U31.34
PRG2_RGMII1_RD2: length 73.6
  TOP w0.132: R157.1 v1(58.5,105.97) ; v1(109.69,98.1) 110.19,97.6 RA1.14
  L05_SIG2 w0.084: v1(109.69,98.1) 108.07,99.72 107.53,99.72 107.44,99.81 106.88,99.81 106.63,99.55 100.39,99.55 96.63,103.31 76.4,103.31 70.37,109.33 67.79,109.33 67.64,109.18 67.64,108.9 67.49,108.75 67.13,108.75 66.98,108.9 66.98,109.18 66.83,109.33 66.47,109.33 66.32,109.18 66.32,108.9 66.17,108.75 65.81,108.75 65.66,108.9 65.66,109.18 65.51,109.33 65.15,109.33 65,109.18 65,108.9 64.85,108.75 64.49,108.75 64.34,108.9 64.34,109.18 64.19,109.33 57.17,109.33 55.37,107.54 55.37,106.07 55.79,105.65 58.17,105.65 v1(58.5,105.97)
PRG2_RGMII1_RD2_R: length 7.1
  TOP w0.132: R163.2 R158.1 59.78,105.99 59.17,106.59 57.07,106.59 56.98,106.51 R157.2 56.98,105.96 55.99,104.97 55.99,104.72 55.76,104.48 U31.35
PRG2_RGMII1_RD3: length 74.2
  TOP w0.132: R154.1 v1(57.82,108.17) ; RA1.15 v1(110.61,97.1)
  L05_SIG2 w0.084: v1(57.82,108.17) 59.28,108.17 59.43,108.32 59.43,108.66 59.59,108.81 59.94,108.81 60.09,108.66 60.09,108.32 60.25,108.17 60.6,108.17 60.75,108.32 60.75,108.66 60.91,108.81 61.26,108.81 61.41,108.66 61.41,108.32 61.57,108.17 61.92,108.17 62.07,108.32 62.07,108.66 62.23,108.81 62.58,108.81 62.73,108.66 62.73,108.32 62.89,108.17 69.11,108.17 70.67,106.62 70.88,106.62 71.14,106.87 71.35,106.87 71.6,106.62 71.6,106.4 71.35,106.15 71.35,105.93 72.13,105.16 73.66,105.16 76.51,102.31 77.23,102.31 77.38,102.46 77.38,102.64 77.53,102.79 77.89,102.79 78.04,102.64 78.04,102.46 78.19,102.31 78.55,102.31 78.7,102.46 78.7,102.64 78.85,102.79 79.21,102.79 79.36,102.64 79.36,102.46 79.52,102.31 79.87,102.31 80.02,102.46 80.02,102.64 80.18,102.79 80.53,102.79 80.68,102.64 80.68,102.46 80.84,102.31 81.19,102.31 81.34,102.46 81.34,102.64 81.5,102.79 81.85,102.79 82,102.64 82,102.46 82.16,102.31 82.51,102.31 82.66,102.46 82.66,102.64 82.82,102.79 83.17,102.79 83.33,102.64 83.33,102.46 83.48,102.31 83.83,102.31 83.99,102.46 83.99,102.64 84.14,102.79 84.49,102.79 84.65,102.64 84.65,102.46 84.8,102.31 85.15,102.31 85.31,102.46 85.31,102.64 85.46,102.79 85.81,102.79 85.97,102.64 85.97,102.46 86.12,102.31 86.47,102.31 86.63,102.46 86.63,102.64 86.78,102.79 87.14,102.79 87.29,102.64 87.29,102.46 87.44,102.31 87.8,102.31 87.95,102.46 87.95,102.64 88.1,102.79 88.46,102.79 88.61,102.64 88.61,102.46 88.76,102.31 89.12,102.31 89.27,102.46 89.27,102.64 89.42,102.79 89.78,102.79 89.93,102.64 89.93,102.46 90.08,102.31 90.44,102.31 90.59,102.46 90.59,102.64 90.74,102.79 91.1,102.79 91.25,102.64 91.25,102.46 91.4,102.31 93.71,102.31 93.86,102.46 93.86,102.56 94.01,102.72 94.37,102.72 94.52,102.56 94.52,102.46 94.67,102.31 95.03,102.31 95.18,102.46 95.18,102.56 95.34,102.72 95.69,102.72 95.84,102.56 95.84,102.46 96,102.31 96.98,102.31 100.78,98.51 108.63,98.51 109.51,97.64 110.07,97.64 v1(110.61,97.1)
PRG2_RGMII1_RD3_R: length 3.3
  TOP w0.132: U31.36 55.57,104.98 56.26,105.68 56.26,106.9 56.47,107.12 R154.2
PRG2_RGMII1_RX_CTL: length 73.8
  TOP w0.132: R152.1 56.63,108.17 v1(56.66,108.14) ; v1(109.69,97.1) 110.26,96.53 RA1.16
  L05_SIG2 w0.084: v1(109.69,97.1) 104.13,97.1 103.98,97.25 103.98,97.8 103.82,97.95 103.52,97.95 103.37,97.8 103.37,97.25 103.21,97.1 102.91,97.1 102.76,97.25 102.76,97.8 102.6,97.95 102.3,97.95 102.15,97.8 102.15,97.25 102,97.1 101.55,97.1 96.79,101.85 75.38,101.85 75.22,102 75.22,102.54 75.07,102.69 74.77,102.69 74.61,102.54 74.61,102 74.46,101.85 74.04,101.85 70.41,105.49 69.84,105.49 69.68,105.64 69.68,106.34 69.53,106.5 69.18,106.5 69.02,106.34 69.02,105.64 68.87,105.49 68.52,105.49 68.36,105.64 68.36,106.34 68.21,106.5 67.86,106.5 67.7,106.34 67.7,105.64 67.55,105.49 67.37,105.49 65.29,107.56 63.96,107.56 63.81,107.41 63.81,107.14 63.66,106.99 63.3,106.99 63.15,107.14 63.15,107.41 63,107.56 62.64,107.56 62.49,107.41 62.49,107.14 62.34,106.99 61.98,106.99 61.83,107.14 61.83,107.41 61.68,107.56 57.24,107.56 v1(56.66,108.14)
PRG2_RGMII1_RX_CTL_R: length 7.7
  TOP w0.132: U31.38 54.07,106.17 54.3,106.41 54.79,106.41 55.12,106.74 R152.2 56.31,107.33 56.62,107.64 56.9,107.64 57.34,108.08 57.34,109.3 57.28,109.36 R146.1 R145.1
PRG2_RGMII1_RXC: length 75.3
  TOP w0.132: R181.1 v1(58.5,102.8) ; v1(110.62,95.45) 111.07,95.45 111.12,95.4 RA3.9
  L05_SIG2 w0.084: v1(110.62,95.45) 110.06,94.89 109.27,94.89 108.45,95.71 108.16,95.71 108.01,95.55 108.01,95.05 107.86,94.89 107.55,94.89 107.4,95.05 107.4,95.55 107.25,95.71 106.94,95.71 106.79,95.55 106.79,95.05 106.64,94.89 106.33,94.89 106.18,95.05 106.18,95.55 106.03,95.71 105.72,95.71 105.57,95.55 105.57,95.05 105.42,94.89 105.11,94.89 104.96,95.05 104.96,95.55 104.81,95.71 104.5,95.71 104.35,95.55 104.35,95.05 104.2,94.89 103.89,94.89 103.74,95.05 103.74,95.55 103.59,95.71 100.97,95.71 95.89,100.79 89.39,100.79 89.24,100.63 89.24,100.24 89.09,100.09 88.78,100.09 88.63,100.24 88.63,100.63 88.48,100.79 88.17,100.79 88.02,100.63 88.02,100.24 87.87,100.09 87.56,100.09 87.41,100.24 87.41,100.63 87.26,100.79 86.95,100.79 86.8,100.63 86.8,100.24 86.65,100.09 86.34,100.09 86.19,100.24 86.19,100.63 86.04,100.79 85.73,100.79 85.58,100.63 85.58,100.24 85.43,100.09 85.12,100.09 84.97,100.24 84.97,100.63 84.82,100.79 84.51,100.79 84.36,100.63 84.36,100.24 84.21,100.09 83.9,100.09 83.75,100.24 83.75,100.63 83.6,100.79 65.16,100.79 65.01,100.63 65.01,100.05 64.85,99.9 64.55,99.9 64.4,100.05 64.4,100.63 64.24,100.79 63.94,100.79 63.79,100.63 63.79,100.05 63.63,99.9 63.33,99.9 63.18,100.05 63.18,100.63 63.02,100.79 62.72,100.79 62.57,100.63 62.57,100.05 62.41,99.9 62.11,99.9 61.96,100.05 61.96,100.63 61.81,100.79 60.51,100.79 v1(58.5,102.8)
PRG2_RGMII1_RXC_R: length 1.7
  TOP w0.132: U31.32 56.8,102.98 R181.2
PRG2_RGMII1_TD0: length 76.1
  TOP w0.132: v1(109.73,94.28) 110.18,93.83 RA3.12 ; U31.28 55.34,100.97 55.93,100.97 57.2,99.7 57.2,99.22 57.92,98.49 v1(58.53,98.49)
  L05_SIG2 w0.084: v1(109.73,94.28) 103.44,94.28 103.18,94.03 101.28,94.03 97.4,97.92 96.58,97.92 95.71,98.79 93.52,98.79 93.37,98.95 93.37,99.92 93.22,100.08 92.91,100.08 92.76,99.92 92.76,98.95 92.61,98.79 92.3,98.79 92.15,98.95 92.15,99.92 92,100.08 91.69,100.08 91.54,99.92 91.54,98.95 91.39,98.79 91.08,98.79 90.93,98.95 90.93,99.92 90.78,100.08 90.47,100.08 90.32,99.92 90.32,98.95 90.17,98.79 89.57,98.79 89.1,99.26 87.43,99.26 87.28,99.11 87.28,98.84 87.12,98.69 86.82,98.69 86.67,98.84 86.67,99.11 86.51,99.26 86.21,99.26 86.06,99.11 86.06,98.84 85.9,98.69 85.6,98.69 85.45,98.84 85.45,99.11 85.29,99.26 83.91,99.26 83.76,99.11 83.76,98.87 83.61,98.72 83.3,98.72 83.15,98.87 83.15,99.11 83,99.26 82.69,99.26 82.54,99.11 82.54,98.87 82.39,98.72 82.08,98.72 81.93,98.87 81.93,99.11 81.78,99.26 80.14,99.26 79.99,99.11 79.99,98.98 79.83,98.83 79.48,98.83 79.32,98.98 79.32,99.11 79.17,99.26 78.82,99.26 78.66,99.11 78.66,98.98 78.51,98.83 78.16,98.83 78,98.98 78,99.11 77.85,99.26 77.5,99.26 77.34,99.11 77.34,98.98 77.19,98.83 76.84,98.83 76.68,98.98 76.68,99.11 76.53,99.26 76.18,99.26 76.02,99.11 76.02,98.98 75.87,98.83 75.51,98.83 75.36,98.98 75.36,99.11 75.21,99.26 74.85,99.26 74.7,99.11 74.7,98.98 74.55,98.83 74.19,98.83 74.04,98.98 74.04,99.11 73.89,99.26 64.08,99.26 63.32,98.49 v1(58.53,98.49)
PRG2_RGMII1_TD1: length 77
  TOP w0.132: v1(57.21,98.54) 56.53,99.23 56.53,99.81 55.96,100.38 55.42,100.38 U31.27 ; RA3.13 v1(110.61,93.33)
  L05_SIG2 w0.084: v1(110.61,93.33) 110.16,93.78 108.62,93.78 108.47,93.63 108.47,93.37 108.32,93.21 108.01,93.21 107.86,93.37 107.86,93.63 107.71,93.78 107.4,93.78 107.25,93.63 107.25,93.23 107.1,93.08 106.79,93.08 106.64,93.23 106.64,93.63 106.49,93.78 106.18,93.78 106.03,93.63 106.03,93.23 105.88,93.08 105.58,93.08 105.42,93.23 105.42,93.63 105.27,93.78 104.84,93.78 104.63,93.57 100.1,93.57 98.29,95.38 98.29,95.6 98.44,95.74 98.44,95.96 98.23,96.18 98.01,96.18 97.86,96.03 97.65,96.03 96.14,97.54 96.09,97.54 96.08,97.55 94.52,97.55 93.83,98.23 91.14,98.23 90.99,98.08 90.99,97.77 90.84,97.62 90.53,97.62 90.38,97.77 90.38,98.08 90.23,98.23 89.92,98.23 89.77,98.08 89.77,97.77 89.62,97.62 89.31,97.62 89.16,97.77 89.16,98.08 89.01,98.23 88.7,98.23 88.55,98.08 88.55,97.77 88.4,97.62 88.1,97.62 87.94,97.77 87.94,98.08 87.79,98.23 87.49,98.23 87.33,98.08 87.33,97.77 87.18,97.62 86.88,97.62 86.72,97.77 86.72,98.08 86.57,98.23 86.27,98.23 86.11,98.08 86.11,97.77 85.96,97.62 85.66,97.62 85.5,97.77 85.5,98.08 85.35,98.23 85.05,98.23 84.89,98.08 84.89,97.77 84.74,97.62 84.44,97.62 84.29,97.77 84.29,98.08 84.13,98.23 83.83,98.23 83.68,98.08 83.68,97.77 83.52,97.62 83.22,97.62 83.07,97.77 83.07,98.08 82.91,98.23 82.61,98.23 82.46,98.08 82.46,97.77 82.3,97.62 82,97.62 81.85,97.77 81.85,98.08 81.69,98.23 81.39,98.23 81.24,98.08 81.24,97.77 81.08,97.62 80.78,97.62 80.63,97.77 80.63,98.08 80.48,98.23 80.17,98.23 80.02,98.08 80.02,97.77 79.87,97.62 79.56,97.62 79.41,97.77 79.41,98.08 79.26,98.23 78.95,98.23 78.8,98.08 78.8,97.77 78.65,97.62 78.34,97.62 78.19,97.77 78.19,98.08 78.04,98.23 70.79,98.23 70.51,98.51 64.41,98.51 63.69,97.79 57.97,97.79 v1(57.21,98.54)
PRG2_RGMII1_TD2: length 75.9
  TOP w0.132: U31.26 55.78,99.99 56.13,99.64 56.13,98.88 v1(56.43,98.59) ; v1(109.77,93.32) 110.26,92.83 RA3.14
  L05_SIG2 w0.084: v1(56.43,98.59) 57.93,97.09 66.55,97.09 66.7,97.24 66.7,97.9 66.85,98.06 67.16,98.06 67.31,97.9 67.31,97.24 67.46,97.09 67.77,97.09 67.92,97.24 67.92,97.9 68.07,98.06 68.38,98.06 68.53,97.9 68.53,97.24 68.68,97.09 68.99,97.09 69.14,97.24 69.14,97.9 69.29,98.06 69.6,98.06 69.75,97.9 69.75,97.24 69.9,97.09 85.7,97.09 85.85,96.94 85.85,96.39 86.01,96.24 86.31,96.24 86.46,96.39 86.46,96.94 86.61,97.09 86.92,97.09 87.07,96.94 87.07,96.39 87.22,96.24 87.53,96.24 87.68,96.39 87.68,96.94 87.83,97.09 88.14,97.09 88.29,96.94 88.29,96.39 88.44,96.24 88.75,96.24 88.9,96.39 88.9,96.94 89.05,97.09 95.89,97.09 100.36,92.62 103.72,92.62 103.87,92.47 103.87,92.03 104.02,91.88 104.33,91.88 104.48,92.03 104.48,92.47 104.63,92.62 104.94,92.62 105.09,92.47 105.09,92.03 105.24,91.88 105.55,91.88 105.7,92.03 105.7,92.47 105.85,92.62 106.16,92.62 106.31,92.47 106.31,92.03 106.46,91.88 106.77,91.88 106.92,92.03 106.92,92.47 107.07,92.62 109.01,92.62 109.39,93 109.45,93 v1(109.77,93.32)
PRG2_RGMII1_TD3: length 77.5
  TOP w0.132: v1(55.32,98.54) U31.25 ; RA3.15 v1(110.61,92.33)
  L05_SIG2 w0.084: v1(110.61,92.33) 107.86,89.59 97.29,89.59 91.88,95 72.44,95 72.38,95.06 65.56,95.06 65.41,94.91 65.41,94.27 65.25,94.12 64.95,94.12 64.8,94.27 64.8,94.91 64.64,95.06 64.34,95.06 64.19,94.91 64.19,94.27 64.03,94.12 63.73,94.12 63.58,94.27 63.58,94.91 63.42,95.06 63.12,95.06 62.97,94.91 62.97,94.27 62.82,94.12 62.51,94.12 62.36,94.27 62.36,94.91 62.21,95.06 61.9,95.06 61.75,94.91 61.75,94.27 61.6,94.12 61.29,94.12 61.14,94.27 61.14,94.91 60.99,95.06 60.68,95.06 60.53,94.91 60.53,94.27 60.38,94.12 60.07,94.12 59.92,94.27 59.92,94.91 59.77,95.06 59.46,95.06 59.31,94.91 59.31,94.27 59.16,94.12 58.85,94.12 58.7,94.27 58.7,94.91 58.55,95.06 58.24,95.06 58.09,94.91 58.09,94.27 57.94,94.12 57.63,94.12 57.48,94.27 57.48,94.91 57.33,95.06 56.52,95.06 55.32,96.27 v1(55.32,98.54)
PRG2_RGMII1_TX_CTL: length 76.2
  TOP w0.132: v1(55.8,106.29) 55.25,105.73 U31.37 ; v1(109.71,95.44) 110.02,95.13 110.02,95.12 110.31,94.83 RA3.10
  L05_SIG2 w0.084: v1(109.71,95.44) 109.38,95.77 109.38,95.77 109.37,95.77 109.32,95.77 108.78,96.32 101.68,96.32 96.6,101.39 68.11,101.39 67.95,101.55 67.95,104.19 67.8,104.34 67.5,104.34 67.34,104.19 67.34,101.55 67.19,101.39 66.85,101.39 65.64,102.6 65.42,102.6 64.93,102.11 64.72,102.11 64.5,102.33 64.5,102.54 64.99,103.03 64.99,103.25 64.78,103.47 64.56,103.47 64.07,102.97 63.85,102.97 63.64,103.19 63.64,103.4 64.13,103.9 64.13,104.11 63.77,104.47 63.55,104.47 63.09,104.01 62.87,104.01 62.66,104.23 62.66,104.44 63.12,104.91 63.12,105.12 61.63,106.61 56.13,106.61 v1(55.8,106.29)
PRG2_RGMII1_TXC: length 76.4
  TOP w0.132: U31.29 56.04,101.49 v1(56.57,100.95) ; v1(109.69,92.33) 110.26,91.77 RA3.16
  L05_SIG2 w0.084: v1(109.69,92.33) 108.22,90.86 100.87,90.86 99.84,91.88 96.9,91.88 93.15,95.63 85.07,95.63 84.92,95.78 84.92,96.33 84.77,96.48 84.46,96.48 84.31,96.33 84.31,95.78 84.16,95.63 83.85,95.63 83.7,95.78 83.7,96.33 83.55,96.48 83.25,96.48 83.09,96.33 83.09,95.78 82.94,95.63 80.71,95.63 80.43,95.91 66.47,95.91 65.9,96.48 64.18,96.48 64.03,96.33 64.03,95.84 63.88,95.69 63.58,95.69 63.42,95.84 63.42,96.33 63.27,96.48 62.97,96.48 62.81,96.33 62.81,95.84 62.66,95.69 62.36,95.69 62.2,95.84 62.2,96.33 62.05,96.48 61.75,96.48 61.59,96.33 61.59,95.84 61.44,95.69 61.14,95.69 60.98,95.84 60.98,96.33 60.83,96.48 60.53,96.48 60.37,96.33 60.37,95.84 60.22,95.69 59.92,95.69 59.77,95.84 59.77,96.33 59.61,96.48 59.31,96.48 59.16,96.33 59.16,95.84 59,95.69 58.7,95.69 58.55,95.84 58.55,96.33 58.39,96.48 58,96.48 58,96.48 57.5,96.48 55.93,98.05 55.93,100.3 v1(56.57,100.95)
PRG2_RGMII2_ETH2_CLK: length 41.4
  TOP w0.132: R169.2 v1(72.64,104.47)
  L12_SIG4 w0.084: v1(49.59,89.16) 50.74,88.01 60,88.01 60.38,88.39 70.93,88.39 73.56,91.02 73.56,103.56 v1(72.64,104.47)
  BOTTOM w0.132: U88.15 50.07,88.98 49.88,89.16 v1(49.59,89.16)
PRG2_RGMII2_ETH2_CLK_OUT: length 7.1
  BOTTOM w0.132: 51.57,88.27 51.57,91.25 50.93,91.88 TP55.1
PRG2_RGMII2_ETH2_RBIAS: length 1.3
  BOTTOM w0.132: U88.12 R509.1
PRG2_RGMII2_RD0: length 73.8
  TOP w0.132: RA5.9 v1(110.61,90.57)
  L10_SIG3 w0.084: v1(58.5,83.19) 61.43,83.19 63.98,85.75 71.73,85.75 73.13,87.14 73.41,87.14 73.56,86.99 73.56,85.81 73.71,85.66 74.07,85.66 74.22,85.81 74.22,86.99 74.37,87.14 74.73,87.14 74.88,86.99 74.88,85.81 75.03,85.66 75.39,85.66 75.54,85.81 75.54,86.99 75.69,87.14 76.05,87.14 76.2,86.99 76.2,85.81 76.35,85.66 76.71,85.66 76.86,85.81 76.86,86.99 77.01,87.14 77.37,87.14 77.52,86.99 77.52,85.81 77.67,85.66 78.03,85.66 78.18,85.81 78.18,86.99 78.33,87.14 78.69,87.14 78.84,86.99 78.84,85.81 78.99,85.66 79.35,85.66 79.5,85.81 79.5,86.99 79.65,87.14 101.94,87.14 105.82,91.03 110.15,91.03 v1(110.61,90.57)
  BOTTOM w0.132: R519.1 v1(58.5,83.19)
PRG2_RGMII2_RD0_R: length 6.3
  BOTTOM w0.132: U88.33 56.02,83.52 56.35,83.19 R519.2 56.98,82.72 57.09,82.62 59.33,82.62 R520.2 R518.1
PRG2_RGMII2_RD1: length 72.4
  TOP w0.132: v1(109.69,90.57) 110.26,90.01 RA5.10
  L10_SIG3 w0.084: v1(109.69,90.57) 109.24,90.57 104.68,86.01 89.95,86.01 89.14,85.21 88.42,85.21 88.27,85.36 88.27,86.54 88.12,86.69 87.76,86.69 87.61,86.54 87.61,85.36 87.46,85.21 87.1,85.21 86.95,85.36 86.95,86.54 86.8,86.69 86.44,86.69 86.29,86.54 86.29,85.36 86.14,85.21 84.28,85.21 84.13,85.36 84.13,86.26 83.97,86.41 83.62,86.41 83.47,86.26 83.47,85.36 83.31,85.21 82.96,85.21 82.81,85.36 82.81,86.26 82.65,86.41 82.3,86.41 82.15,86.26 82.15,85.36 81.99,85.21 81.64,85.21 81.49,85.36 81.49,86.26 81.33,86.41 80.98,86.41 80.82,86.26 80.82,85.36 80.67,85.21 64.57,85.21 61.92,82.55 59,82.55 v1(58.5,82.05)
  BOTTOM w0.132: R523.1 v1(58.5,82.05)
PRG2_RGMII2_RD1_R: length 2.1
  BOTTOM w0.132: R523.2 56.98,82.06 56.02,83.02 U88.34
PRG2_RGMII2_RD2: length 73
  TOP w0.132: RA5.11 v1(110.61,89.51)
  L10_SIG3 w0.084: v1(110.61,89.51) 110.09,90.03 109.4,90.03 104.83,85.46 97.99,85.46 97.83,85.31 97.83,84.93 97.68,84.78 97.33,84.78 97.17,84.93 97.17,85.31 97.02,85.46 96.62,85.46 96.47,85.31 96.47,83.98 96.31,83.83 95.96,83.83 95.81,83.98 95.81,85.31 95.65,85.46 95.3,85.46 95.14,85.31 95.14,83.98 94.99,83.83 94.64,83.83 94.48,83.98 94.48,85.31 94.33,85.46 93.86,85.46 92.66,84.26 76.16,84.26 76.01,84.11 76.01,83.95 75.85,83.8 75.5,83.8 75.35,83.95 75.35,84.11 75.19,84.26 74.84,84.26 74.69,84.11 74.69,83.95 74.53,83.8 74.18,83.8 74.03,83.95 74.03,84.11 73.87,84.26 73.52,84.26 73.37,84.11 73.37,83.95 73.21,83.8 72.86,83.8 72.71,83.95 72.71,84.11 72.55,84.26 72.2,84.26 72.04,84.11 72.04,83.95 71.89,83.8 71.54,83.8 71.38,83.95 71.38,84.11 71.23,84.26 70.88,84.26 70.72,84.11 70.72,83.95 70.57,83.8 70.22,83.8 70.06,83.95 70.06,84.11 69.91,84.26 69.56,84.26 69.4,84.11 69.4,83.95 69.25,83.8 68.9,83.8 68.74,83.95 68.74,84.11 68.59,84.26 68.23,84.26 68.08,84.11 68.08,83.95 67.93,83.8 67.57,83.8 67.42,83.95 67.42,84.11 67.27,84.26 66.91,84.26 66.76,84.11 66.76,83.95 66.61,83.8 66.25,83.8 66.1,83.95 66.1,84.11 65.95,84.26 65.21,84.26 61.47,80.52 59.01,80.52 v1(58.5,81.03)
  BOTTOM w0.132: R525.1 v1(58.5,81.03)
PRG2_RGMII2_RD2_R: length 7.1
  BOTTOM w0.132: R522.2 R524.1 59.78,81.02 59.17,80.41 57.07,80.41 56.98,80.5 R525.2 56.98,81.05 55.99,82.04 55.99,82.29 55.76,82.52 U88.35
PRG2_RGMII2_RD3: length 71.1
  TOP w0.132: RA5.12 110.26,89.01 v1(109.69,89.57)
  L10_SIG3 w0.084: v1(57.82,78.84) 61.69,78.84 64.58,81.72 65.22,81.72 65.38,81.88 65.38,82.36 65.53,82.51 65.88,82.51 66.04,82.36 66.04,81.88 66.19,81.72 66.54,81.72 66.7,81.88 66.7,82.36 66.85,82.51 67.2,82.51 67.36,82.36 67.36,81.88 67.51,81.72 67.87,81.72 68.02,81.88 68.02,82.36 68.17,82.51 68.53,82.51 68.68,82.36 68.68,81.88 68.83,81.72 69.19,81.72 69.34,81.88 69.34,82.36 69.49,82.51 69.85,82.51 70,82.36 70,81.88 70.15,81.72 70.51,81.72 70.66,81.88 70.66,82.36 70.81,82.51 71.17,82.51 71.32,82.36 71.32,81.88 71.47,81.72 104.56,81.72 110.15,87.32 110.15,89.12 v1(109.69,89.57)
  BOTTOM w0.132: R537.1 v1(57.82,78.84)
PRG2_RGMII2_RD3_R: length 3.3
  BOTTOM w0.132: U88.36 55.57,82.02 56.26,81.33 56.26,80.1 56.47,79.89 R537.2
PRG2_RGMII2_RX_CTL: length 73
  TOP w0.132: RA5.13 v1(110.61,88.51)
  L10_SIG3 w0.084: v1(55.8,78.84) 56.99,77.65 62.46,77.65 65,80.19 68.69,80.19 68.84,80.04 68.84,79.36 69,79.21 69.35,79.21 69.5,79.36 69.5,80.04 69.66,80.19 70.01,80.19 70.16,80.04 70.16,79.36 70.32,79.21 70.67,79.21 70.83,79.36 70.83,80.04 70.98,80.19 71.33,80.19 71.49,80.04 71.49,79.36 71.64,79.21 71.99,79.21 72.15,79.36 72.15,80.04 72.3,80.19 72.65,80.19 72.81,80.04 72.81,79.36 72.96,79.21 73.31,79.21 73.47,79.36 73.47,80.04 73.62,80.19 104.31,80.19 111.07,86.94 111.07,88.05 v1(110.61,88.51)
  BOTTOM w0.132: R541.1 v1(55.8,78.84)
PRG2_RGMII2_RX_CTL_R: length 6.8
  BOTTOM w0.132: R553.1 R554.1 56.26,79.26 55.84,79.68 R541.2 55.12,80.27 54.79,80.6 54.3,80.6 54.07,80.83 U88.38
PRG2_RGMII2_RXC: length 72.4
  TOP w0.132: v1(109.69,88.57) 110.26,88.01 RA5.14
  L10_SIG3 w0.084: v1(58.5,84.21) 58.04,83.75 58.04,80.23 58.39,79.88 61.7,79.88 64.93,83.12 73.25,83.12 73.4,82.97 73.4,82.55 73.55,82.4 73.91,82.4 74.06,82.55 74.06,82.97 74.21,83.12 74.57,83.12 74.72,82.97 74.72,82.55 74.87,82.4 75.23,82.4 75.38,82.55 75.38,82.97 75.53,83.12 75.89,83.12 76.04,82.97 76.04,82.55 76.2,82.4 76.55,82.4 76.7,82.55 76.7,82.97 76.86,83.12 77.21,83.12 77.36,82.97 77.36,82.55 77.52,82.4 77.87,82.4 78.02,82.55 78.02,82.97 78.18,83.12 78.53,83.12 78.68,82.97 78.68,82.55 78.84,82.4 79.19,82.4 79.34,82.55 79.34,82.97 79.5,83.12 79.85,83.12 80.01,82.97 80.01,82.55 80.16,82.4 80.51,82.4 80.67,82.55 80.67,82.97 80.82,83.12 97.29,83.12 99.02,84.85 105.97,84.85 v1(109.69,88.57)
  BOTTOM w0.132: R517.1 v1(58.5,84.21)
PRG2_RGMII2_RXC_R: length 1.7
  BOTTOM w0.132: R517.2 56.6,84.21 56.59,84.2 56.46,84.2 56.29,84.02 U88.32
PRG2_RGMII2_TD0: length 73.1
  TOP w0.132: RA1.9 v1(110.61,100.16)
  L10_SIG3 w0.084: v1(58.53,88.51) 59.75,89.74 89.71,89.74 91.35,88.1 92.76,88.1 92.92,88.25 92.92,89.21 93.07,89.36 93.42,89.36 93.58,89.21 93.58,88.25 93.73,88.1 94.08,88.1 94.24,88.25 94.24,89.21 94.39,89.36 94.74,89.36 94.9,89.21 94.9,88.25 95.05,88.1 100.51,88.1 108.51,96.1 108.51,98.56 109.57,99.62 110.07,99.62 v1(110.61,100.16)
  BOTTOM w0.132: U88.28 55.4,86.11 55.8,86.11 56,86.3 56.18,86.3 57.2,87.31 57.2,87.78 57.92,88.51 v1(58.53,88.51)
PRG2_RGMII2_TD1: length 72.1
  TOP w0.132: v1(109.69,100.16) 110.26,99.6 RA1.10
  L10_SIG3 w0.084: v1(109.69,100.16) 109.24,100.16 104.9,95.83 104.9,94.01 101.09,90.2 98.96,90.2 98.81,90.04 98.81,89.34 98.66,89.18 98.3,89.18 98.15,89.34 98.15,90.04 98,90.2 97.64,90.2 97.49,90.04 97.49,89.34 97.33,89.18 96.98,89.18 96.83,89.34 96.83,90.04 96.67,90.2 96.32,90.2 96.17,90.04 96.17,89.34 96.01,89.18 95.66,89.18 95.51,89.34 95.51,90.04 95.35,90.2 58.95,90.2 v1(57.21,88.46)
  BOTTOM w0.132: v1(57.21,88.46) 56.69,87.94 56.69,87.37 55.85,86.52 U88.27
PRG2_RGMII2_TD2: length 74.3
  TOP w0.132: RA1.11 v1(110.61,99.1)
  L10_SIG3 w0.084: v1(56.29,88.46) 56.29,87.53 56.89,86.93 60.33,86.93 61.71,88.3 62.05,88.3 62.2,88.15 62.2,87.49 62.36,87.33 62.71,87.33 62.86,87.49 62.86,88.15 63.02,88.3 63.37,88.3 63.52,88.15 63.52,87.49 63.68,87.33 64.03,87.33 64.18,87.49 64.18,88.15 64.34,88.3 64.69,88.3 64.84,88.15 64.84,87.49 65,87.33 65.35,87.33 65.5,87.49 65.5,88.15 65.66,88.3 71.45,88.3 72.11,87.64 101.79,87.64 108.97,94.82 108.97,98.02 109.59,98.64 110.15,98.64 v1(110.61,99.1)
  BOTTOM w0.132: U88.26 55.78,87.02 56.29,87.53 v1(56.29,88.46)
PRG2_RGMII2_TD3: length 75.6
  TOP w0.132: v1(115.75,103.38) 116.38,104.01 116.9,104.01 118.03,102.88 R180.2
  L10_SIG3 w0.084: v1(115.75,103.38) 110.27,103.38 108.15,101.26 100.2,101.26 100.05,101.1 100.05,99.97 99.9,99.82 99.54,99.82 99.39,99.97 99.39,101.1 99.24,101.26 98.88,101.26 98.73,101.1 98.73,99.97 98.58,99.82 98.22,99.82 98.07,99.97 98.07,101.1 97.92,101.26 91.2,101.26 80.59,90.65 57.51,90.65 v1(55.32,88.46)
  BOTTOM w0.132: v1(55.32,88.46) U88.25
PRG2_RGMII2_TX_CTL: length 75.5
  TOP w0.132: RA5.15 v1(110.61,87.51)
  L10_SIG3 w0.084: v1(110.61,87.51) 110.61,87.13 104.12,80.64 78.18,80.64 78.03,80.8 78.03,81.11 77.88,81.27 77.52,81.27 77.37,81.11 77.37,80.8 77.22,80.64 76.86,80.64 76.71,80.8 76.71,81.11 76.56,81.27 76.2,81.27 76.05,81.11 76.05,80.8 75.9,80.64 75.54,80.64 75.39,80.8 75.39,81.11 75.23,81.27 74.88,81.27 74.73,81.11 74.73,80.8 74.57,80.64 74.22,80.64 74.07,80.8 74.07,81.11 73.91,81.27 73.56,81.27 73.41,81.11 73.41,80.8 73.25,80.64 72.9,80.64 72.75,80.8 72.75,81.11 72.59,81.27 72.24,81.27 72.09,81.11 72.09,80.8 71.93,80.64 71.58,80.64 71.42,80.8 71.42,81.11 71.27,81.27 70.92,81.27 70.76,81.11 70.76,80.8 70.61,80.64 70.26,80.64 70.1,80.8 70.1,81.11 69.95,81.27 69.6,81.27 69.44,81.11 69.44,80.8 69.29,80.64 68.94,80.64 68.78,80.8 68.78,81.11 68.63,81.27 68.28,81.27 68.12,81.11 68.12,80.8 67.97,80.64 67.61,80.64 67.46,80.8 67.46,81.11 67.31,81.27 66.95,81.27 66.8,81.11 66.8,80.8 66.65,80.64 66.29,80.64 66.14,80.8 66.14,81.11 65.99,81.27 65.63,81.27 65.48,81.11 65.48,80.8 65.33,80.64 64.15,80.64 61.63,78.13 57.19,78.13 55.8,79.51 v1(55.8,80.72)
  BOTTOM w0.132: U88.37 55.25,81.27 v1(55.8,80.72)
PRG2_RGMII2_TXC: length 75.9
  TOP w0.132: v1(116.71,102.87) 117.03,102.55 117.03,102.17 117.35,101.85 R183.2
  L10_SIG3 w0.084: v1(116.71,102.87) 116.4,103.19 116.4,103.44 115.92,103.92 110.05,103.92 108.32,102.19 91.26,102.19 80.34,91.26 57.25,91.26 54.71,88.72 54.71,88.09 56.57,86.23 v1(56.57,85.77)
  BOTTOM w0.132: v1(56.57,85.77) 56.22,85.77 56.04,85.6 55.97,85.6 55.9,85.52 U88.29
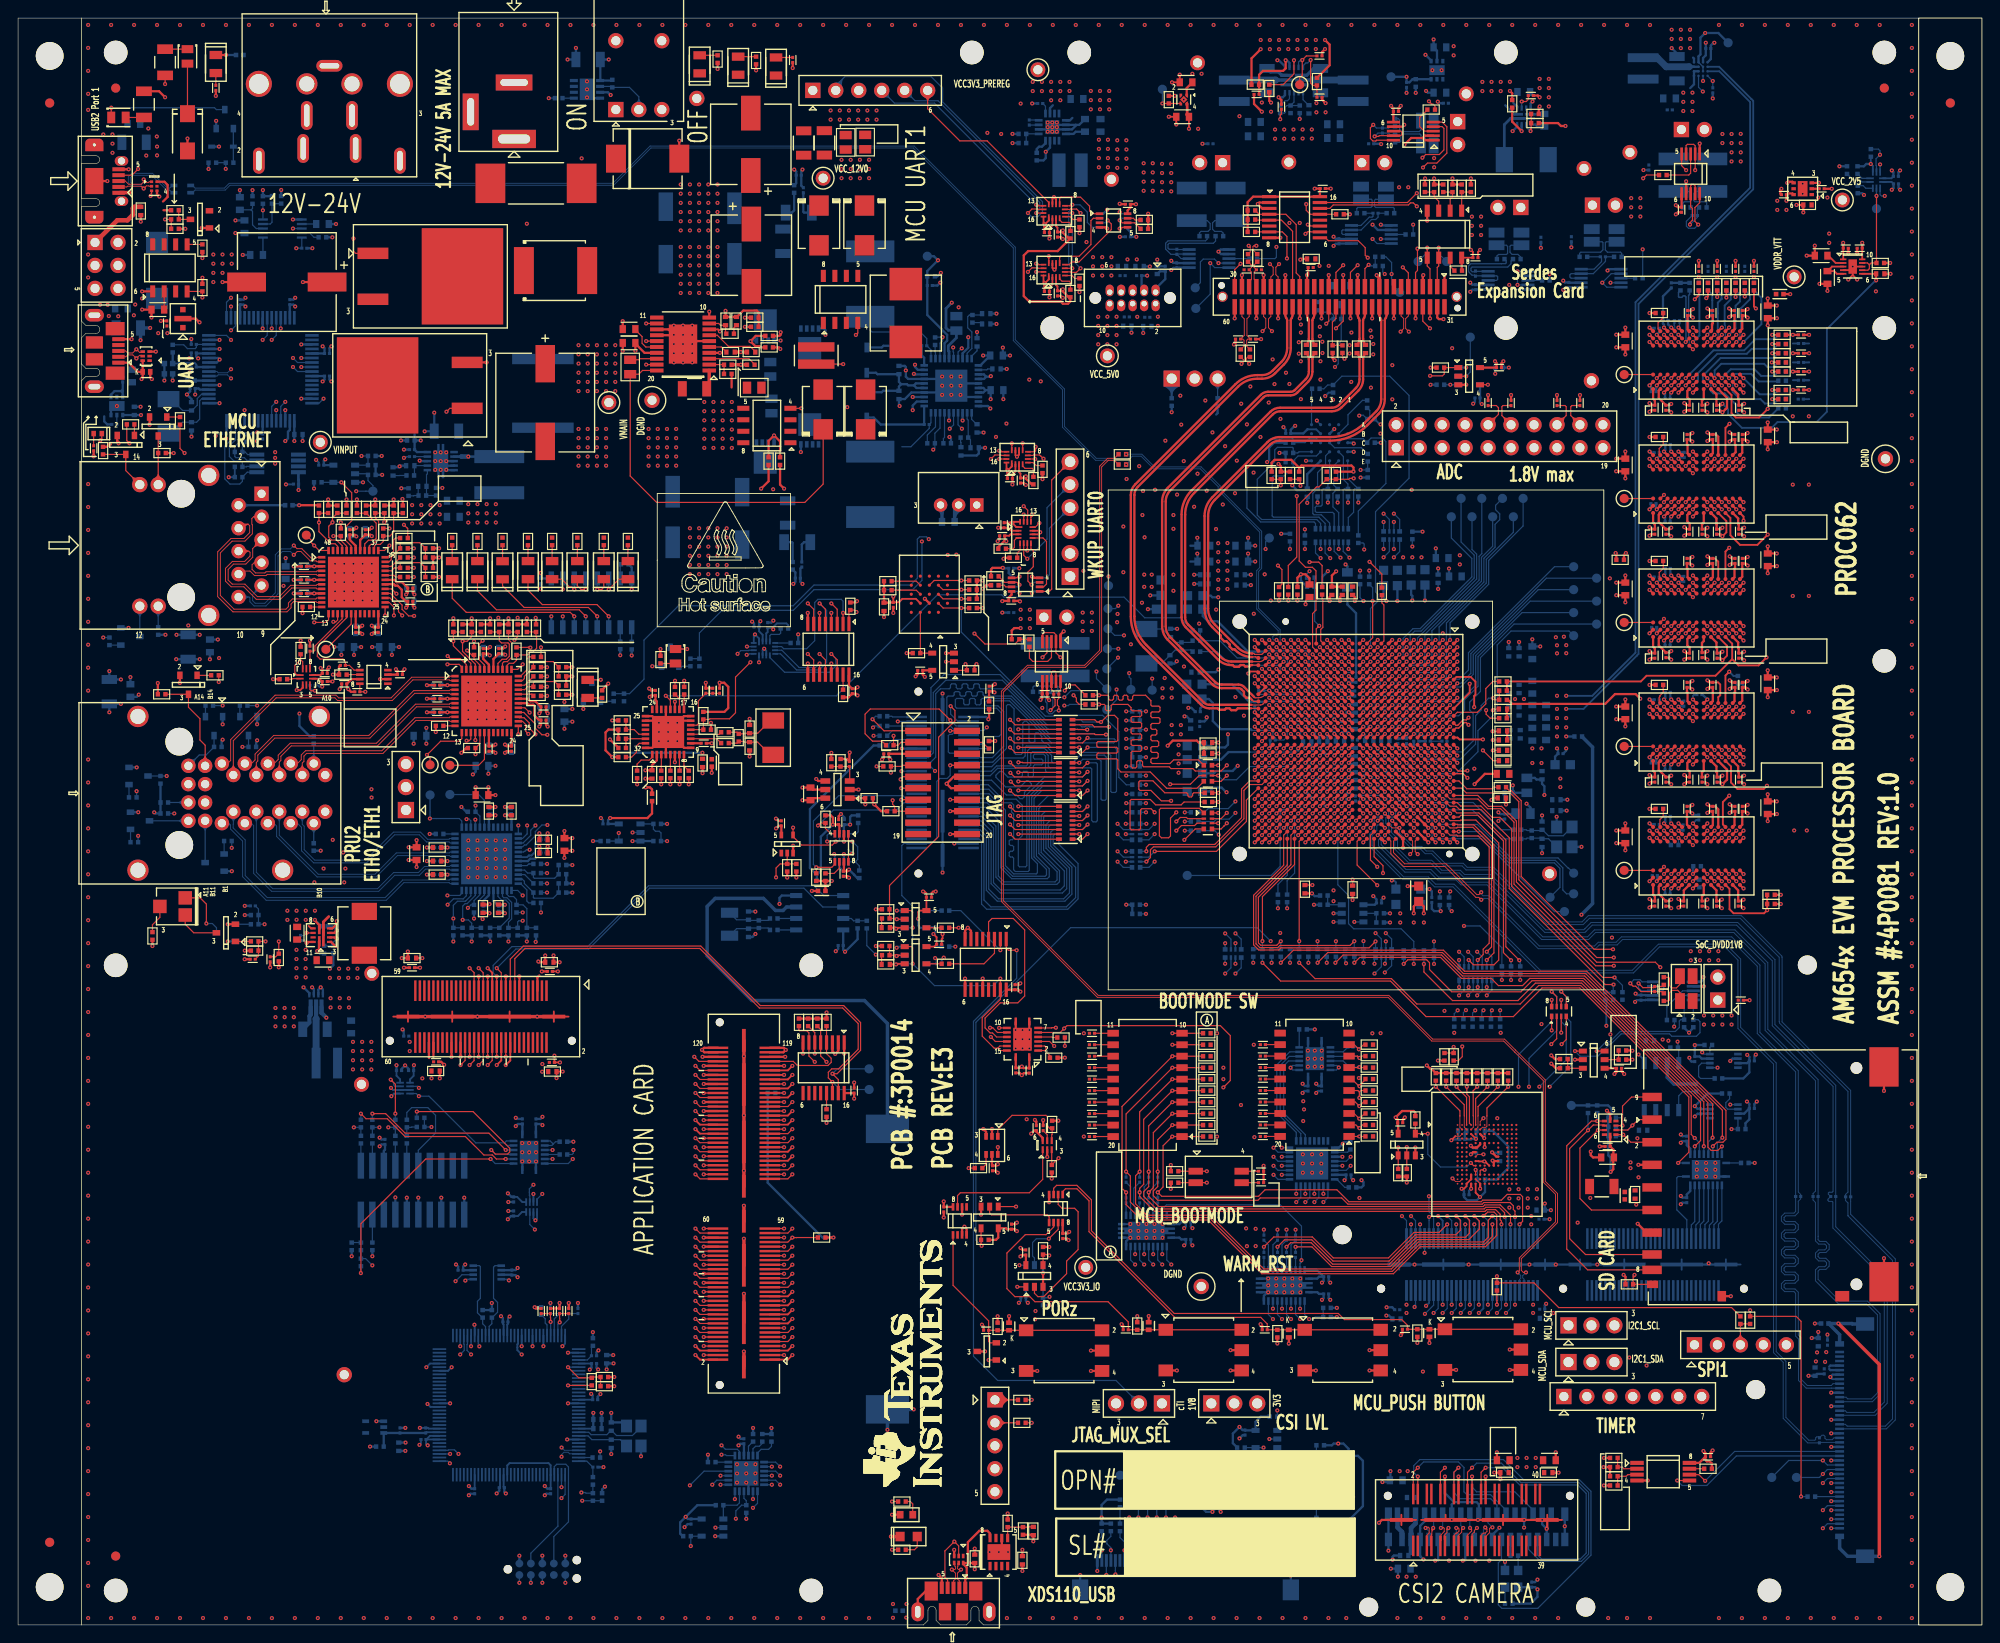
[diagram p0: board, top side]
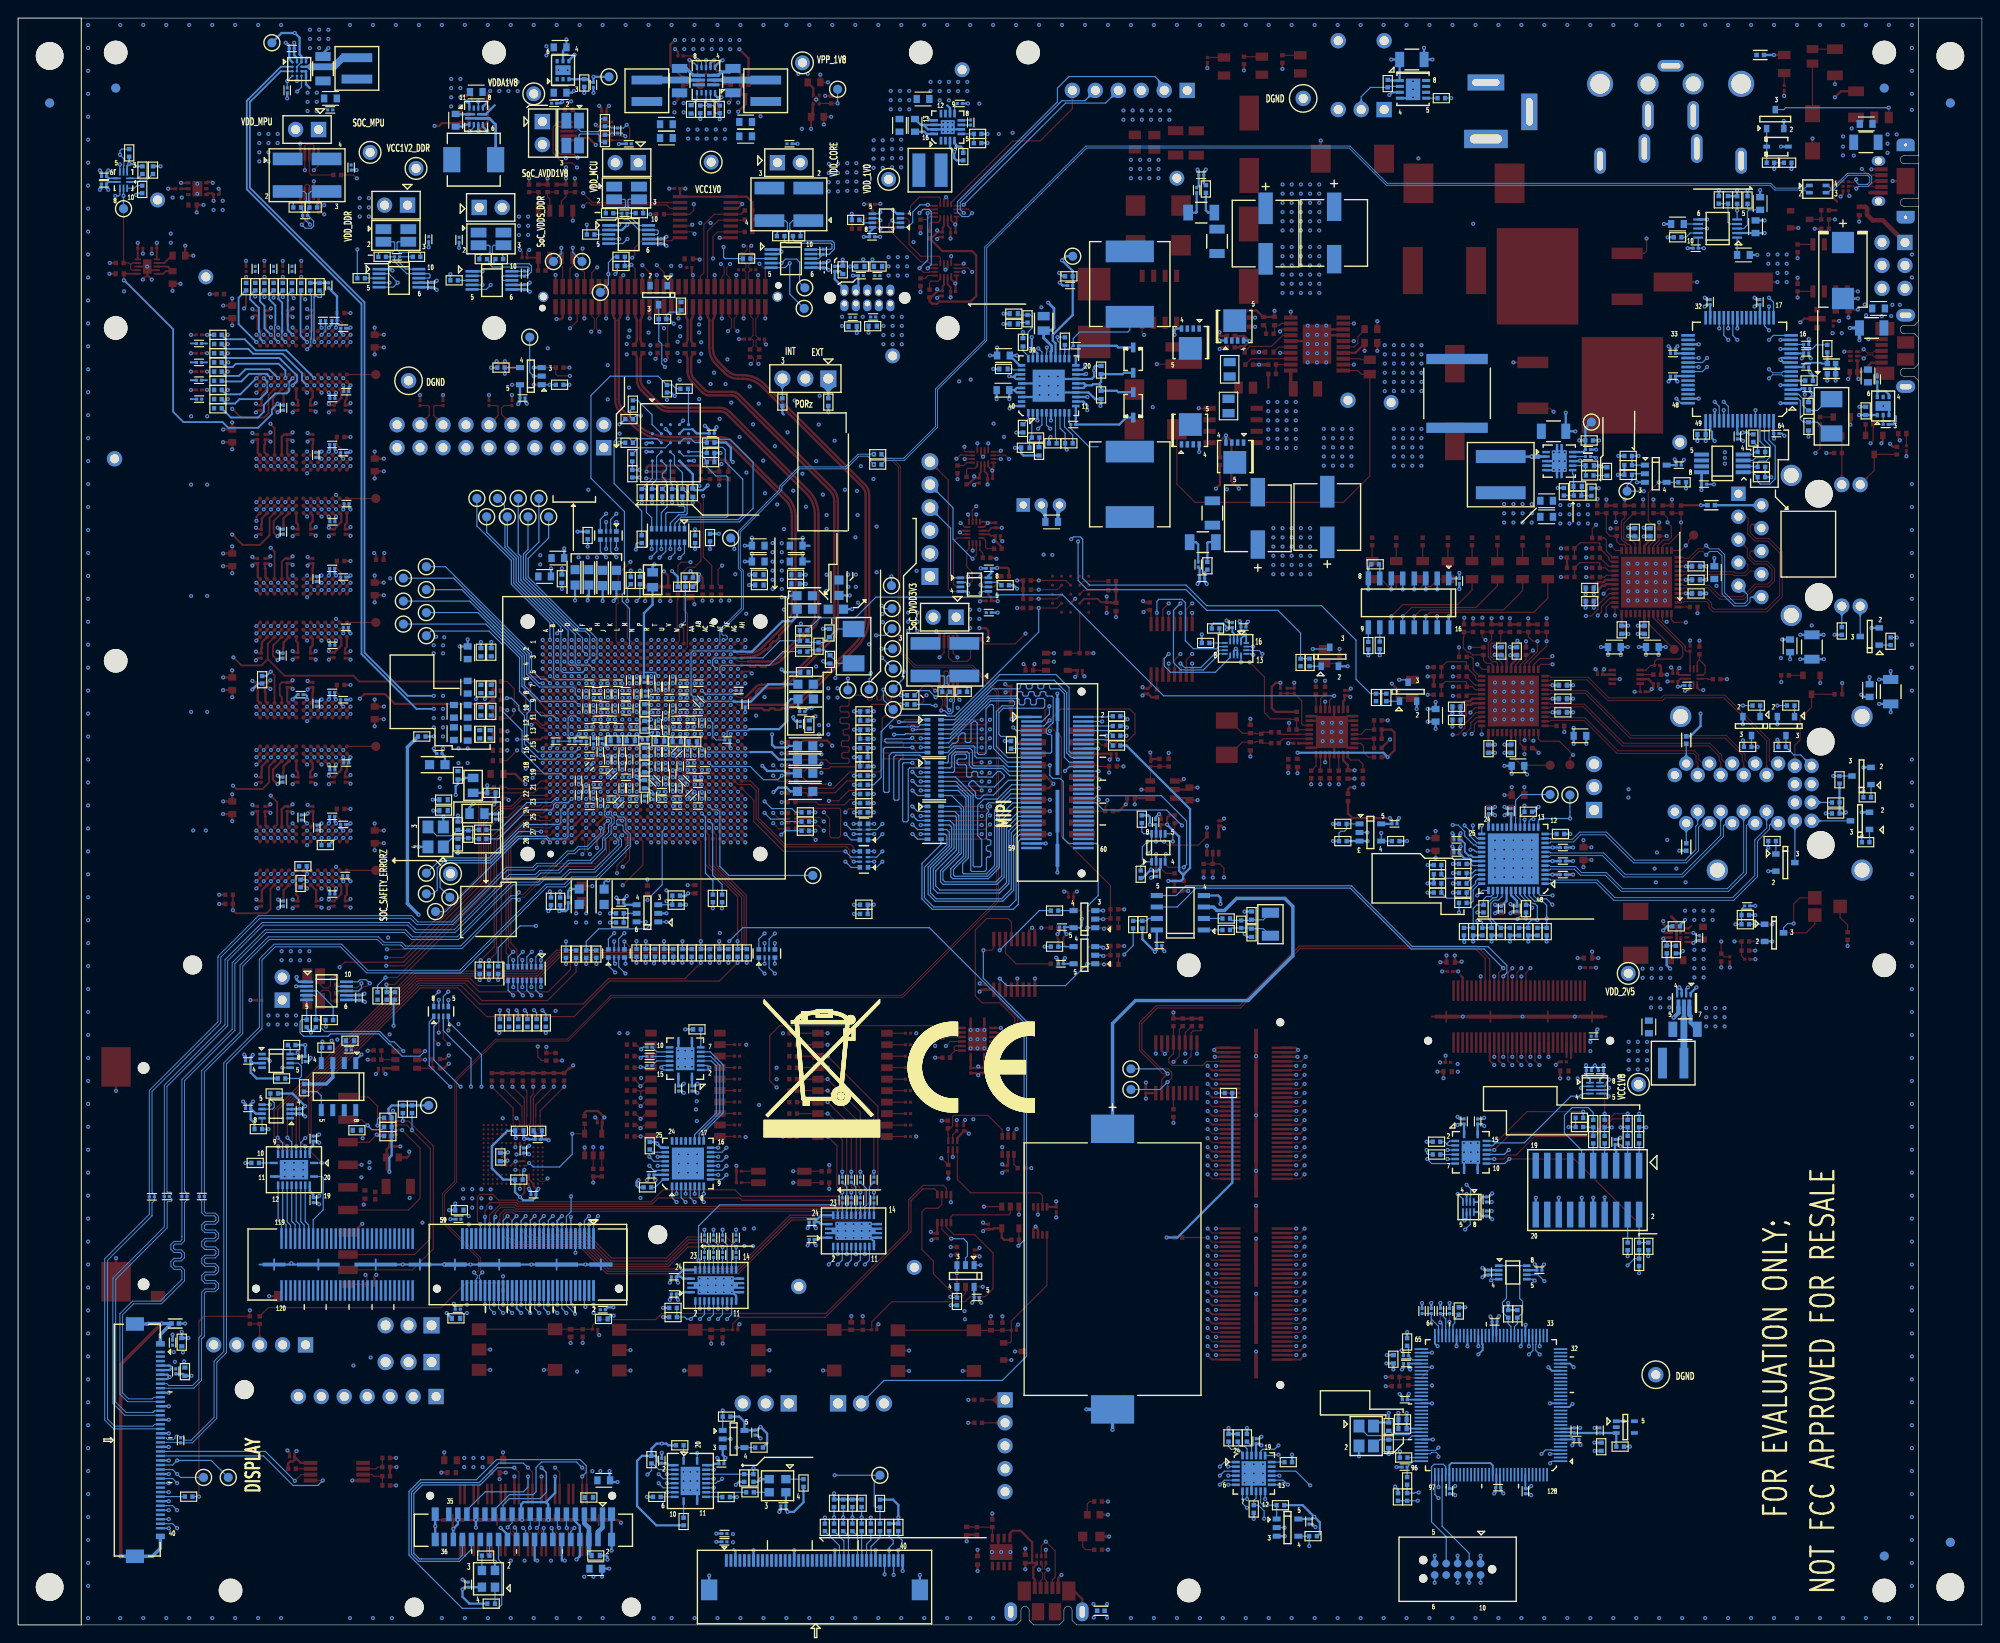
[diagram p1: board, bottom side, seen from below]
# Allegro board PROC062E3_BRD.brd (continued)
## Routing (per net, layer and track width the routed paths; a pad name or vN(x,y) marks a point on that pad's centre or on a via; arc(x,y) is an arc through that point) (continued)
PRG2_RGMII_INTN: length 261.1
  TOP w0.132: v1(49.66,107.82) 50.15,107.33 R151.1 50.42,106.86 51.07,106.22 U31.44
  L03_SIG1 w0.084: v1(49.74,79.34) 48.2,80.89 48.2,106.36 v1(49.66,107.82)
  L05_SIG2 w0.084: v1(39.09,91.55) 39.09,84.73 42.01,81.81 56.33,81.81 57.52,80.63 61.59,80.63 62.27,81.3 86.19,81.3 91.79,75.69 110.64,75.69 122.07,64.26 122.07,57.53 126.27,53.33 128.18,53.33 132.04,57.19 132.04,66.16 135.07,69.19 156.06,69.19 157.86,70.99 162.57,70.99 167.33,66.23 167.33,63.3 170.79,59.84 170.79,54.44 174.3,50.93 176.92,50.93 177.93,51.94 178.65,51.94 184.67,57.96 188.95,57.96 v1(189.34,57.57)
  L12_SIG4 w0.084: v1(49.74,79.34) 49.33,78.93 42.23,78.93 39.09,82.07 v1(39.09,91.55)
  BOTTOM w0.132: U88.44 51.07,80.79 50.42,80.14 R542.1 50.08,79.68 49.75,79.34 v1(49.74,79.34) ; U45.5 v1(189.34,57.57)
PRG2_RGMII_INTN_3V3: length 58.3
  TOP w0.132: U34.A22 161.41,91.79 162.62,90.58 164.06,90.58 165.69,88.94 165.69,82.21 174.57,73.33 181.05,73.33 v1(181.61,72.77)
  L03_SIG1 w0.084: v1(181.61,72.77) 182.6,72.77 184.01,71.36 184.01,67.55 185.83,65.72 185.83,58.52 v1(189.48,54.86)
  BOTTOM w0.132: v1(189.48,54.86) R270.1 U45.8
PRG2_RGMII_RESETN: length 64.7
  TOP w0.132: 51.57,105.73 51.57,106.22 50.99,106.8 50.99,108.52 v1(51.37,108.9)
  L03_SIG1 w0.084: v1(51.37,108.9) 51.37,107.89 48.5,105.02 48.5,81.29 51.05,78.75 51.05,78.43 v1(51.37,78.11)
  L12_SIG4 w0.084: v1(51.37,78.11) 52.01,77.47 61.02,77.47 66.43,82.87 v1(66.43,87.63)
  BOTTOM w0.132: v1(51.37,78.11) 50.94,78.53 50.94,80.16 51.57,80.78 51.57,81.27 ; v1(66.43,87.63) U86.4 R514.1
PRG_EARTH: length 3.2
  BOTTOM w0.254: v1(11.37,101.91) C489.1 v1(10.09,100.99) ; v1(13.35,102.93) 13.1,102.69 R473.1
PRI_INN: length 6.2
  TOP w0.132: R173.2 C145.1 R172.1 76.05,103.07 75.22,102.25 75.22,99.71 75.07,99.56 U32.14
R_PRG2_PRU1_GP6: length 10.3
  TOP w0.132: U34.AC17 v1(140.76,95.39) ; RA2.6 v1(132.71,93.98)
  BOTTOM w0.122: 136.18,94.97 136.19,94.98 140.35,94.98 v1(140.76,95.39)
  BOTTOM w0.132: 136.18,94.97 134.73,93.52 133.17,93.52 v1(132.71,93.98)
R_PRG2_PRU1_GP8: length 11.6
  TOP w0.132: U34.AD15 v1(139.96,96.99) ; RA2.5 133.03,93.35 133.67,93.98 v1(133.67,93.98)
  L10_SIG3 w0.084: v1(139.96,96.99) 140.35,96.6 140.35,95.23 140.12,95 136.14,95 135.13,93.98 v1(133.67,93.98)
R_PRG2_PRU1_GP11: length 10.4
  TOP w0.132: RA2.8 v1(132.71,95.12) ; U34.AD14 v1(139.96,98.59)
  L10_SIG3 w0.084: v1(139.96,98.59) 139.56,98.98 138.99,98.98 138.76,98.75 138.76,98.45 138.52,98.2 135.79,98.2 v1(132.71,95.12)
R_PRG2_PRU1_GP16: length 9.8
  TOP w0.132: U34.AE14 v1(139.16,98.59) ; RA2.7 133.03,94.48 133.67,95.12 v1(133.67,95.12)
  L10_SIG3 w0.084: v1(133.67,95.12) 133.99,95.44 133.99,95.67 135.72,97.4 138.36,97.4 139.16,98.2 v1(139.16,98.59)
R_SOC_SPI1_CS1: length 3.1
  TOP w0.132: v1(163.54,35.43) R311.2
  BOTTOM w0.132: R311.2 v1(163.54,35.43)
RAMP: length 2.1
  TOP w0.132: U14.5 77.77,141.41 C62.1
REFCLK0N: length 5.5
  TOP w0.107: J5.58 136.14,144.77 135.89,144.53 135.89,142.67 R60.1 135.99,142.28 135.86,142.15 135.86,141.5 R725.1
REFCLK0N_R: length 52
  TOP w0.107: U34.AF9 v1(138.36,102.59) ; R725.2 135.98,140.3 135.83,140.15 135.83,139.84 v1(136.14,139.53)
  L12_SIG4 w0.076: v1(136.14,139.53) 135.88,139.53 135.75,139.41 135.75,136.23 126.95,127.43 126.95,106.42 129.9,103.48 134.79,103.48 135.88,102.39 138.15,102.39 v1(138.36,102.59)
REFCLK0P: length 5.4
  TOP w0.107: J5.59 135.34,144.77 135.6,144.52 135.6,142.68 R59.1 135.44,142.28 135.57,142.15 135.57,141.5 R724.1
REFCLK0P_R: length 52.1
  TOP w0.107: U34.AF10 v1(138.36,101.79) ; R724.2 135.54,139.97 135.54,139.78 v1(135.29,139.53)
  L12_SIG4 w0.076: v1(138.36,101.79) 138.03,102.11 135.76,102.11 134.67,103.2 129.78,103.2 126.67,106.31 126.67,127.55 135.47,136.35 135.47,139.35 v1(135.29,139.53)
REFCLK1N: length 3.2
  TOP w0.107: R727.1 136.68,150.48 136.68,150.21 R40.1 136.69,149.7 136.69,148.91 136.94,148.66 J5.27
REFCLK1N_R: length 63.4
  TOP w0.107: U34.AE8 v1(139.16,103.39) ; R727.2 136.55,152.16 136.55,152.5 136.65,152.61 v1(136.94,152.61)
  L12_SIG4 w0.076: v1(136.94,152.61) 136.59,152.25 136.59,145.88 136.27,145.57 136.27,141.17 137.24,140.21 137.24,135.99 128.99,127.74 128.99,111.76 130.25,110.5 130.25,106.13 132.08,104.3 135.32,104.3 136.17,103.45 137.82,103.45 138.14,103.77 138.77,103.77 v1(139.16,103.39)
REFCLK1P: length 3.2
  TOP w0.107: J5.28 136.14,148.65 136.39,148.9 136.39,149.7 R39.1 136.39,150.19 136.39,150.47 R726.1
REFCLK1P_R: length 63.4
  TOP w0.107: R726.2 136.26,151.92 136.26,152.43 v1(136.08,152.61) ; U34.AE9 v1(139.16,102.59)
  L12_SIG4 w0.076: v1(136.08,152.61) 136.31,152.38 136.31,146 135.99,145.68 135.99,141.06 136.96,140.09 136.96,136.1 128.72,127.86 128.72,111.65 129.97,110.39 129.97,106.02 131.79,104.2 131.79,104.2 131.96,104.03 135.2,104.03 136.06,103.17 137.82,103.17 137.99,103.01 138.74,103.01 v1(139.16,102.59)
RESET_SOC_MPU: length 331.7
  L03_SIG1 w0.084: v1(79.27,13.93) 77.13,13.93 76.2,14.86 76.2,18.16 72.3,22.06 72.3,44.98 56.32,60.96 48.72,60.96 40.54,69.14 40.54,110.61 39.62,111.52 39.62,123.83 35.92,127.53 35.92,141.25 33.27,143.89 33.27,155.19 34.82,156.74 69.24,156.74 76.45,163.96 101.09,163.96 104.14,167 126.11,167 127.25,168.15 133.35,168.15 135.34,170.14 157.3,170.14 159.83,167.61 170.26,167.61 174.18,171.54 186.71,171.54 v1(187.41,170.83)
  BOTTOM w0.132: C682.1 v1(187.41,170.83) U59.D1 ; U110.12 v1(79.27,13.93)
RESETSTATZ: length 28.4
  TOP w0.132: U34.D19 v1(156.76,93.79)
  BOTTOM w0.122: v1(156.76,93.79) 157.16,94.19 159,94.19 159.77,94.95
  BOTTOM w0.132: TP48.1 171.51,109.97 165.09,109.97 163.57,108.45 163.57,101.08 161.44,98.95 161.44,96.62 159.77,94.95
RT: length 5.3
  TOP w0.132: U14.3 80.82,140.11 81.45,139.48 R65.1
SEL_XDS: length 81.2
  TOP w0.132: v1(90.42,86.68) 90.04,86.29 86.64,86.29 85.7,87.23 U36.4 v1(85.7,88.22)
  L12_SIG4 w0.084: v1(44.32,58.51) 64.78,58.51 79.3,73.02 79.3,81.82 v1(85.7,88.22)
  BOTTOM w0.132: U97.4 44.03,58.8 v1(44.32,58.51) 45.44,58.51 50.61,53.34 53.78,53.34 ; 53.78,53.34 54.07,53.05 U98.14 ; 53.78,53.34 54,53.55 U98.15 ; U87.6 90.82,86.81 90.69,86.68 v1(90.42,86.68)
SEL_XDS110_INV: length 158.4
  TOP w0.132: J13.8 v1(103.07,95.12) ; U41.1 98.8,75.05 98.93,74.93 v1(98.93,73.15) ; 108.33,63.82 108.59,63.56 U43.15 ; 108.33,63.82 107.95,63.82 106.62,65.15 106.62,67.21 108.62,69.22 U42.15 v1(108.62,71.52) ; 108.33,63.82 108.57,64.06 U43.14 ; v1(98.93,77.14) 98.93,78.88 98.76,79.04 U39.1 ; R215.1 R216.1 ; R215.1 U36.2 ; R215.1 84.27,84.21 83.82,83.76 v1(83.82,82.72)
  L05_SIG2 w0.084: v1(83.82,82.72) 84.29,83.19 89.79,83.19 95.5,77.47 98.6,77.47 v1(98.93,77.14)
  L10_SIG3 w0.084: v1(98.93,73.15) 94.87,69.1 77.6,69.1 66.93,58.43 65.29,58.43 60.2,53.34 60.2,49.92 v1(57.97,47.69)
  L12_SIG4 w0.084: v1(57.97,47.69) 57.5,48.16 48.6,48.16 47.69,47.24 47.69,38.73 v1(48.38,38.04)
  BOTTOM w0.132: v1(98.93,77.14) 98.93,79.51 97.73,80.71 97.73,86.24 97.95,86.47 J32.58 101.01,86.47 101.6,87.06 101.6,93.34 101.92,93.66 102.74,93.66 103.07,93.99 v1(103.07,95.12) ; v1(98.93,77.14) v1(98.93,73.15) ; v1(98.93,77.14) U90.1 ; v1(48.38,38.04) 49.09,38.75 U103.6 ; v1(57.97,47.69) 57.39,47.11 U101.4 ; v1(98.93,73.15) 101.34,70.74 107.84,70.74 v1(108.62,71.52) ; v1(98.93,73.15) U92.1
SERDES_BRD_DET: length 151.7
  TOP w0.132: v1(145.74,143.47) 146.54,144.27 J5.45 ; R236.1 87.38,66.26 88.1,65.54 U46.6 v1(88.1,63.21)
  L12_SIG4 w0.084: v1(145.74,143.47) 145.1,144.11 145.1,147.13 146.13,148.16 146.13,153.62 144.21,155.54 134.45,155.54 131.38,152.47 131.38,146.83 135.24,142.97 135.24,140.45 134.83,140.04 134.83,137.12 122.68,124.97 122.68,112.97 122.71,112.94 122.71,110.78 118.48,106.55 113.25,106.55 112.47,105.78 112.47,80.46 104.91,72.89 103.82,72.89 93.71,62.78 88.54,62.78 v1(88.1,63.21)
SOC_DDR_VREFCA: length 39.4
  TOP w0.254: v1(176.67,118.61) 176.75,118.53 R728.2 ; U34.F12 v1(155.16,100.19)
  L12_SIG4 w0.127: v1(155.16,100.19) 154.76,100.58 154.76,104.35 154.99,104.58 159.57,104.58
  L12_SIG4 w0.254: 159.57,104.58 163.3,108.31 167.35,108.31 176.67,117.63 v1(176.67,118.61)
  BOTTOM w0.122: C504.1 C505.1 156.17,98.25 156.35,98.43 156.35,100.35 156.11,100.58 155.55,100.58 v1(155.16,100.19)
SOC_DVDD1V8: length 21.2
  TOP w0.254: U34.N6 v1(149.56,104.99) ; U34.AB23 v1(141.56,90.59) ; U34.AA20 v1(142.36,92.99) ; U34.T7 v1(146.36,104.19) ; U34.H21 v1(153.56,92.19) ; U34.W20 v1(143.96,92.99) ; U34.Y23 v1(143.16,90.59) ; U34.P7 v1(148.76,104.19) ; U34.U20 v1(145.56,92.99) ; U34.U22 v1(145.56,91.39) ; U34.R8 v1(147.16,103.39) ; U34.P9 v1(148.76,102.59) ; U34.Y20 v1(143.16,92.99) ; U34.T21 v1(146.36,92.19) ; U34.T9 v1(146.36,102.59) ; U34.N8 v1(149.56,103.39) ; U34.V21 v1(144.76,92.19) ; U34.R6 v1(147.16,104.99) ; U34.AA22 v1(142.36,91.39) ; U34.V23 v1(144.76,90.59) ; U34.H19 v1(153.56,93.79) ; U34.AB19 v1(141.56,93.79) ; U34.F20 v1(155.16,92.99) ; U34.AC18 v1(140.76,94.59) ; U34.Y21 v1(143.16,92.19) ; U34.T20 v1(146.36,92.99) ; U34.G20 v1(154.36,92.99) ; U34.AB21 v1(141.56,92.19) ; U34.W22 v1(143.96,91.39)
  L03_SIG1 w0.122: v1(146.36,102.59) 146.75,102.98 149.15,102.98 v1(149.56,103.39)
  BOTTOM w0.203: v1(143.16,92.99) 143.31,93.15 C548.1 ; C547.1 146.36,93.02 v1(146.36,92.99)
  BOTTOM w0.254: v1(147.16,103.39) 147.2,103.34 C435.1
  vias: v1(170.55,93.65) v1(170.55,92.71) v1(184.98,74.55) v1(184.98,73.55) v1(185.99,74.55) v1(185.99,73.55) v1(187.01,74.55) v1(187.01,73.55) v1(188.02,74.55) v1(188.02,73.55)
SOC_DVDD3V3: length 51.7
  TOP w0.254: U34.H16 v1(153.56,96.19) ; U34.AA21 v1(142.36,92.19) ; U34.AB11 v1(141.56,100.99) ; U34.W8 v1(143.96,103.39) ; U34.N20 v1(149.56,92.99) ; U34.R22 v1(147.16,91.39) ; U34.Y7 v1(143.16,104.19) ; U34.AC10 v1(140.76,101.79) ; U34.G15 v1(154.36,96.99) ; U34.U8 v1(145.56,103.39) ; U34.AA18 v1(142.36,94.59) ; U34.G18 v1(154.36,94.59) ; U34.P21 v1(148.76,92.19) ; U34.R20 v1(147.16,92.99) ; U34.AB17 v1(141.56,95.39) ; U34.U6 v1(145.56,104.99) ; U34.V7 v1(144.76,104.19) ; U34.N22 v1(149.56,91.39)
  L03_SIG1 w0.203: v1(126.56,102.62) 124.9,102.62 120.68,106.85 120.68,114.95 121.3,115.57 121.3,130.02 125.46,134.19 v1(127.57,134.19)
  L06_PWR1 w0.254: 142.62,94.87 142.36,94.6 v1(142.36,94.59)
  BOTTOM w0.254: FL13.1 154.16,94.78 v1(154.36,94.59) ; v1(154.36,96.99) 154.34,97 C506.1 ; v1(142.36,92.19) 142.38,92.19 C560.1 ; R395.2 v1(127.57,134.19)
  vias: v1(117.73,112.01) v1(117.73,111) v1(117.73,109.98) v1(118.74,112.01) v1(118.74,111) v1(118.74,109.98) v1(126.56,103.63) v1(127.57,103.63) v1(127.57,102.62) v1(127.57,99.57) v1(127.57,98.55) v1(128.59,99.57) v1(128.59,98.55)
SOC_EMU0: length 175
  TOP w0.132: U34.AA2 v1(142.36,108.19)
  L03_SIG1 w0.084: v1(89.47,86.69) 90.59,87.81 90.59,98.7 93.46,101.58 101.6,101.58 103.63,103.61 103.63,108.81 102.81,109.64 v1(102.81,118.4)
  L05_SIG2 w0.084: v1(142.36,108.19) 142.75,108.58 142.75,109.6 142.75,109.6 142.75,112 141.97,112.77 141.97,113.51 140.65,114.83 137.25,114.83 136.59,114.17 133.81,114.17 132.91,113.27 125.08,113.27 123.67,114.68 114.79,114.68 113.44,116.03 113.44,118.07 111.92,119.59 110.11,119.59 109.56,119.03 109.3,119.03 103.44,119.03 v1(102.81,118.4)
  L12_SIG4 w0.084: v1(89.47,86.69) 84.84,86.69 79.6,81.45 79.6,72.9 63.75,57.05 63.75,50.79 62.49,49.52 49.54,49.52 47.38,47.37 47.38,38.21 47.97,37.63 48.99,37.63 v1(49.46,38.1)
  BOTTOM w0.132: v1(89.47,86.69) 89.47,87.38 89.63,87.54 U87.5 ; v1(49.46,38.1) 49.61,38.25 U103.5
SOC_EMU1: length 163.1
  TOP w0.132: U34.AA1 v1(142.36,108.99)
  L03_SIG1 w0.084: v1(90.25,85.29) 90.66,84.88 91.55,84.88 91.86,85.19 91.86,87.83 92.6,88.57 92.6,90.93 90.95,92.58 90.95,98.63 93.59,101.27 101.73,101.27 103.94,103.48 103.94,108.94 103.11,109.76 103.11,116.84 103.76,117.49 v1(103.76,118.43)
  L05_SIG2 w0.084: v1(103.76,118.43) 104.22,118.43 104.47,118.68 109.79,118.68 110.39,119.28 111.79,119.28 113.13,117.94 113.13,115.91 114.66,114.38 123.62,114.38 125.03,112.97 133.03,112.97 133.94,113.87 136.71,113.87 137.37,114.53 140.52,114.53 141.07,113.98 141.07,112.99 142.38,111.68 142.38,109.41 142.36,109.38 v1(142.36,108.99)
  L12_SIG4 w0.084: v1(54.28,38.13) 54.28,41.04 56.59,43.35 57.32,43.35 64.36,50.39 64.36,56.79 80.21,72.64 80.21,81.2 84.3,85.29 v1(90.25,85.29)
  BOTTOM w0.132: U103.4 54.16,38.25 v1(54.28,38.13) ; U87.4 90.32,85.29 90.25,85.29 v1(90.25,85.29)
SOC_FT4232_MCU_UART1_CTS_1V8: length 8.4
  TOP w0.132: U12.9 115.18,151.32 115.31,151.45 117.34,151.45 118.64,152.75 118.64,155.38 118.9,155.65 U8.2
SOC_FT4232_MCU_UART1_RX_1V8: length 8.9
  TOP w0.132: v1(120.49,155.42) 120.89,155.02 120.89,154.39 117.31,150.81 116.52,150.81 116.22,150.51 U12.8
  BOTTOM w0.132: U65.2 120.21,155.15 v1(120.49,155.42)
SOC_FT4232_WKUP_UART0_CTS_3V3: length 7.3
  TOP w0.132: U23.2 113.42,114.86 113.73,115.17 113.73,119.89 113.34,120.28 U21.9
SOC_FT4232_WKUP_UART0_RX_3V3: length 6.1
  TOP w0.132: U21.8 112.01,119.1 112.27,118.84 112.27,117.09 111.67,116.49 111.67,115.5 v1(112.07,115.09)
  BOTTOM w0.132: v1(112.07,115.09) 112.35,115.36 U83.2
SOC_I2C0_SCL: length 337
  TOP w0.132: J16.21 53.43,72.17 v1(52.93,72.67) ; U34.D20 v1(156.76,92.99)
  L03_SIG1 w0.084: v1(60.24,111.6) 58.36,109.73 48.01,109.73 42.89,104.61 J33.3 41.76,94.12 41.76,78.51 46.86,73.41 52.19,73.41 v1(52.93,72.67) 52.47,72.21 52.47,68.76 58.75,62.48 58.75,59.8 72.91,45.64 72.91,23.71 v1(77.79,18.83)
  L05_SIG2 w0.084: v1(159.19,68.01) 158.32,68.88 136.74,68.88 135.74,67.88 135.03,67.17 135.03,66.92 135.03,58.88 128.56,52.41 125.89,52.41 121.16,57.15 121.16,63.88 115.8,69.24 55.42,69.24 53.39,71.27 53.39,72.21 v1(52.93,72.67)
  L12_SIG4 w0.084: v1(156.76,92.99) 157.16,92.58 157.16,92.06 157.4,91.82 157.73,91.82 158.91,90.64 160.18,90.64 163.79,87.03 163.79,86.83 163.79,73.62 161.02,70.85 161.02,70.32 160.96,70.26 160.96,69.41 159.93,68.38 159.57,68.38 v1(159.19,68.01)
  BOTTOM w0.132: R586.2 158.81,67.63 v1(159.19,68.01) ; v1(52.93,72.67) 55.05,74.79 63.1,74.79 69.83,81.52 86.91,81.52 88.99,79.44 U91.6 ; U110.19 78.33,18.74 78.23,18.83 v1(77.79,18.83) ; U84.15 v1(60.24,111.6)
SOC_I2C0_SDA: length 340.6
  TOP w0.132: U34.C21 v1(157.56,92.19) ; J16.23 v1(52.93,71.75)
  L03_SIG1 w0.084: v1(77.79,19.87) 73.21,24.44 73.21,45.77 59.05,59.93 59.05,62.61 52.93,68.74 v1(52.93,71.75) 53.34,72.16 53.34,72.84 52.46,73.71 46.99,73.71 42.13,78.57 42.13,87.08 44.02,88.98 44.02,91.58 J33.2 44.45,94.27 44.45,105.74 48.12,109.4 58.73,109.4 60.71,111.38 60.71,114.12 v1(60.24,114.59)
  L05_SIG2 w0.084: v1(160.11,68.03) 159.68,67.6 158.71,67.6 157.73,68.58 136.87,68.58 135.87,67.58 135.33,67.04 135.33,58.76 128.68,52.11 125.77,52.11 120.85,57.02 120.85,63.68 120.67,63.86 115.6,68.94 55.29,68.94 52.93,71.3 v1(52.93,71.75)
  L12_SIG4 w0.084: v1(157.56,92.19) 157.82,92.19 159.14,90.88 160.08,90.88 160.33,90.88 164.03,87.18 164.03,73.31 161.8,71.07 161.8,69.58 160.24,68.03 v1(160.11,68.03)
  BOTTOM w0.132: v1(160.11,68.03) 159.83,67.75 R585.2 ; U110.20 79.77,19.2 79.53,19.44 78.21,19.44 v1(77.79,19.87) ; U91.5 89.09,80.71 88.01,81.79 69.72,81.79 62.99,75.06 54.61,75.06 52.53,72.98 52.53,72.15 v1(52.93,71.75) ; U84.2 v1(60.24,114.59)
SOC_I2C1_SCL: length 113.1
  TOP w0.132: U34.B21 v1(158.36,92.19)
  L12_SIG4 w0.084: v1(158.36,92.19) 158.36,92.09 159.26,91.19 160.5,91.19 164.34,87.35 164.34,73.28 164.13,73.07 162.03,70.98 162.03,69.48 160.66,68.1 160.66,67.69 160.91,67.44 162.06,67.44 162.46,67.84 162.46,68.06 162.81,68.41 163.49,68.41 v1(163.89,68.01) 166.24,65.66 166.24,63.88 172.85,57.28 172.85,40.89 176.53,37.21 176.53,33.15 178.31,31.37 182.63,31.37 196.34,17.65 199.04,17.65 v1(199.58,18.2)
  BOTTOM w0.132: R581.2 v1(163.89,68.01) ; J38.26 200.08,17.7 v1(199.58,18.2) 195.81,18.2 TP67.1
SOC_I2C1_SDA: length 117.8
  TOP w0.132: U34.E21 v1(155.96,92.19)
  L12_SIG4 w0.084: v1(155.96,92.19) 156.35,91.8 156.87,91.8 157.19,91.48 157.19,91.24 157.4,91.02 157.87,91.02 158.48,90.41 159.91,90.41 163.56,86.76 163.56,73.77 160.79,71 160.79,70.42 160.72,70.36 160.72,69.5 159.83,68.62 159.28,68.62 158.75,68.09 158.75,67.34 159.03,67.06 162.49,67.06 162.98,67.55 v1(162.98,68.01) 165.48,65.51 165.48,64.21 171.83,57.86 171.83,41.4 175.26,37.97 175.26,30.35 176.53,29.08 178.44,30.99 182.63,30.99 196.28,17.34 198.94,17.34 v1(199.58,16.7)
  BOTTOM w0.132: v1(162.98,68.01) 162.98,67.86 162.88,67.75 R582.2 ; TP68.1 199.2,16.32 v1(199.58,16.7) 200.08,17.2 J38.27
SOC_I2C2_SCL: length 483.7
  TOP w0.132: U27.5 113.28,109.56 113.51,109.79 114.54,109.79 114.78,109.56 U27.2 114.78,107.56 v1(115.28,107.06) ; U34.T27 v1(146.36,87.39) ; v1(184.46,160.97) 183.96,161.47 U3.5 ; U44.1 v1(172.17,63.5) ; v1(155.36,161.26) 155.86,161.76 156.9,161.76 158,162.86 158,165.77 157.48,166.29 U2.5 ; R325.1 v1(112.09,24.9)
  L03_SIG1 w0.084: v1(149.78,153.35) 150.19,153.76 150.87,153.76 151.1,153.52 151.1,151.36 149.73,149.99 149.73,148.76 149.25,148.28 134.24,148.28 v1(131.83,150.69) 131.51,150.36 126.97,150.36 126.47,149.87 118.47,149.87 117.63,149.03 113.46,149.03 110.82,146.39 110.82,133.59 109.08,131.85 109.08,130.41 109.28,130.2 109.28,128.79 108.64,128.15 108.64,124.41 114.81,118.24 114.81,107.53 v1(115.28,107.06) 112.57,104.36 112.57,61.09 109.81,58.32 109.81,49.48 105.66,45.34 105.66,42.55 104.56,41.44 104.56,31.33 110.99,24.9 v1(112.09,24.9) 112.52,24.47 112.52,14.41 v1(121.35,5.59) ; v1(184.46,160.97) 184.87,161.38 185.78,161.38 185.93,161.23 185.93,157.35 176.69,148.11 175.59,148.11 v1(175.18,148.52)
  L05_SIG2 w0.084: v1(145.47,77.79) 145.95,78.27 145.95,86.99 v1(146.36,87.39) ; v1(149.78,153.35) 150.19,152.95 150.87,152.95 151.79,153.87 151.79,158.73 152.89,159.83 153.93,159.83 v1(155.36,161.26)
  L10_SIG3 w0.084: v1(142.12,57.95) 142.44,57.63 143.61,57.63 144.03,58.05 144.08,58.05 146.76,60.73 146.76,62.79 148.08,64.11 148.74,64.11 152.59,60.26 164.15,60.26 168.57,64.68 170.98,64.68 v1(172.17,63.5) ; v1(175.18,148.52) 173.66,146.99 166.18,146.99 v1(164.9,148.27) 161.48,148.27 158.45,151.3 151.83,151.3 v1(149.78,153.35)
  L12_SIG4 w0.084: v1(145.47,77.79) 147,76.26 147,74.68 147.64,74.04 151.07,74.04 151.6,73.51 151.6,71.4 146.95,66.75 146.95,59.12 145.79,57.95 v1(142.12,57.95) 140.76,56.6 140.76,49.38 139.32,47.94 137.1,47.94 135.38,46.23 135.38,41.72 135.98,41.12 142.19,41.12 143.68,39.64 143.68,32.54 140.73,29.59 140.73,8.78 137.54,5.59 v1(121.35,5.59)
  BOTTOM w0.132: U89.1 v1(145.47,77.79) ; U93.5 R592.2 185.78,66.97 185.99,66.76 185.99,65.53 185.6,65.14 182.88,65.14 182.62,65.4 177.28,65.4 176.13,64.25 176.01,64.25 174.69,62.93 172.74,62.93 v1(172.17,63.5) ; U68.5 132.33,150.19 v1(131.83,150.69) 131.83,147.26 TP73.1 ; U70.5 165.4,147.77 v1(164.9,148.27) ; U69.2 176.18,149.52 v1(175.18,148.52) 175.68,148.02 U69.5 ; v1(121.35,5.59) 121.35,6.04 121.35,6.04 J41.36 ; v1(149.78,153.35) 150.28,152.85 U67.5
SOC_I2C2_SDA: length 469.8
  TOP w0.132: v1(185.46,160.97) U3.2 185.46,163.66 185.29,163.83 184.59,163.83 184.46,163.7 U3.4 ; U2.4 157.48,165.79 157.67,165.6 157.67,163.21 157.16,162.7 155.65,162.7 v1(155.3,162.35) ; R326.1 v1(112.09,22.36) ; U34.R25 v1(147.16,88.99) ; U44.6 v1(174.57,63.5) ; v1(113.28,107.06) 113.78,107.55 U27.4
  L03_SIG1 w0.084: v1(176.1,148.52) 176.66,148.52 185.46,157.32 v1(185.46,160.97) ; v1(120.35,5.52) 120.35,6.02 112.09,14.27 v1(112.09,22.36) 112.09,23.16 104.25,31 104.25,41.77 105.28,42.8 105.28,45.47 109.5,49.69 109.5,58.45 112.27,61.21 112.27,106.05 v1(113.28,107.06) 114.57,108.35 114.57,118.14 108.4,124.31 108.4,124.4 108.33,124.47 108.33,128.27 108.9,128.84 108.9,130.16 108.84,130.22 108.84,131.95 110.52,133.62 110.52,146.52 113.46,149.47 114.71,149.47 115.93,150.69 117.59,150.69 118.75,151.84 131.59,151.84 v1(132.75,150.69) 134.85,148.58 148.2,148.58 148.72,149.1 148.72,151.37 v1(150.7,153.35)
  L05_SIG2 w0.084: v1(155.3,162.35) 153.32,160.38 152.96,160.38 151.2,158.62 151.2,153.86 v1(150.7,153.35) ; v1(147.76,77.79) 146.75,78.81 146.75,88.58 v1(147.16,88.99)
  L10_SIG3 w0.084: v1(150.7,153.35) 152.44,151.61 158.58,151.61 161.28,148.9 165.18,148.9 v1(165.81,148.27) 166.79,147.3 173.2,147.3 174.83,148.92 175.69,148.92 v1(176.1,148.52) ; v1(142.2,57.04) 141.71,57.53 141.71,58.12 141.95,58.36 143.96,58.36 146.46,60.86 146.46,62.92 147.95,64.41 148.87,64.41 152.72,60.57 164.02,60.57 168.44,64.99 173.08,64.99 v1(174.57,63.5)
  L12_SIG4 w0.084: v1(120.35,5.52) 120.79,5.08 137.46,5.08 141.03,8.65 141.03,29.46 144.6,33.03 144.6,39.15 142.31,41.43 136.75,41.43 136.4,41.78 136.4,46.74 137.03,47.37 139.18,47.37 141.07,49.26 141.07,55.91 v1(142.2,57.04) 145.31,57.04 147.26,58.99 147.26,66.62 151.9,71.27 151.9,73.64 151.19,74.35 149.45,74.35 148.17,75.63 148.17,77.38 v1(147.76,77.79)
  BOTTOM w0.132: v1(150.7,153.35) U67.4 ; TP74.1 130.75,148.53 130.75,150.81 131.06,151.13 132.3,151.13 v1(132.75,150.69) U68.4 ; U70.2 165.94,149.27 165.81,149.14 v1(165.81,148.27) U70.4 ; U89.6 v1(147.76,77.79) ; v1(176.1,148.52) U69.4 ; v1(174.57,63.5) 175.59,64.52 176.02,64.52 177.18,65.67 183.27,65.67 183.71,66.1 183.71,66.83 183.85,66.97 R593.2 184.24,69.53 184.37,69.66 U93.4 ; v1(120.35,5.52) J41.38
SOC_MAIN_UART0_CTS_3V3: length 52.9
  TOP w0.132: U19.9 v1(111.09,130.75) ; U34.AG11 v1(137.56,100.19)
  L03_SIG1 w0.084: v1(137.56,100.19) 137.31,100.19 136.92,99.8 136.12,99.8 135.93,99.61 130.15,99.61 130.07,99.69 129.84,99.69 129.57,99.97 126.57,99.97 120.07,106.48 120.07,126.84 116.97,129.94 111.9,129.94 v1(111.09,130.75)
SOC_MAIN_UART0_RTS_3V3: length 59.8
  TOP w0.132: U34.AD11 v1(139.96,100.99) ; v1(113.4,129.04) 113.08,129.35 113.06,129.35 112.95,129.46 112.31,129.46 112.26,129.41 U19.7
  L03_SIG1 w0.084: v1(113.4,129.04) 112.97,129.47 112.3,129.47 112.07,129.23 112.07,126.28 113.44,124.9 118.05,124.9 119.46,123.49 119.46,106.22 124.02,101.66 124.02,100.52 126.44,98.09 135.24,98.09 135.44,98.3 136.4,98.3 136.51,98.18 136.92,98.18 137.16,98.42 137.16,98.93 137.23,99 139.32,99 139.56,99.25 139.56,100.38 139.83,100.65 139.83,100.86 v1(139.96,100.99)
SOC_MAIN_UART0_RX_3V3: length 53.3
  TOP w0.132: U19.8 112.41,129.81 112.52,129.92 v1(112.52,130.37) ; U34.AF11 v1(138.36,100.99)
  L03_SIG1 w0.084: v1(112.52,130.37) 116.97,130.37 120.99,126.34 120.99,115.85 120.37,115.22 120.37,106.6 126.01,100.97 129.13,100.97 130.25,99.85 135.69,99.85 136.42,100.58 137.95,100.58 v1(138.36,100.99)
SOC_MAIN_UART0_TX_3V3: length 54
  TOP w0.132: U19.6 v1(112.49,129.01) ; U34.AE11 v1(139.16,100.99)
  L03_SIG1 w0.084: v1(139.16,100.99) 138.76,100.6 138.76,100.05 138.5,99.78 137.37,99.78 137.15,99.55 137.15,99.23 136.92,99 136.26,99 136.14,99.11 125.86,99.11 124.32,100.65 124.32,101.79 119.76,106.35 119.76,125.98 118.24,127.51 113.99,127.51 v1(112.49,129.01)
SOC_MAIN_UART1_RX_1V8: length 86.7
  TOP w0.132: v1(87.33,113.03) 87.98,112.38 U26.7 ; U34.AE23 v1(139.16,90.59)
  L05_SIG2 w0.084: v1(139.16,90.59) 139.16,90.39 138.75,89.98 138.75,88.71 138.62,88.58 136.43,88.58 135.86,88.01 135.15,88.01 133.53,86.39 131.09,86.39 127.13,82.42 119.66,82.42 111.94,90.15 111.94,101.41 104.84,108.51 96.33,108.51 93.41,105.59 87.12,105.59 85.78,106.93 85.78,111.48 v1(87.33,113.03)
SOC_MAIN_UART1_TX_1V8: length 93.2
  TOP w0.132: U34.AD23 v1(139.96,90.59) ; U26.4 v1(89.93,111.99)
  L05_SIG2 w0.084: v1(139.96,90.59) 139.57,90.21 139.57,89.96 139.56,89.95 139.56,88.85 139.32,88.6 139.01,88.6 138.76,88.35 138.76,88.03 138.52,87.78 136.42,87.78 136.34,87.7 135.27,87.7 133.65,86.08 131.21,86.08 127.25,82.12 119.54,82.12 111.63,90.02 111.63,101.28 104.71,108.2 96.65,108.2 93.66,105.22 87.06,105.22 85.47,106.81 85.47,112.33 87.19,114.05 89.92,114.05 90.39,113.57 90.39,112.44 v1(89.93,111.99)
SOC_MCU_SCL: length 354.7
  TOP w0.132: J5.2 156.94,150.21 157.1,150.37 U9.6 v1(157.1,152.39)
  L03_SIG1 w0.084: v1(157.1,152.39) 158.71,152.39 164.21,146.89 177.99,146.89 179.27,148.17 193.22,148.17 199.39,141.99 199.39,80.84 190.13,71.58 190.13,40.02 186.69,36.58 186.69,28.83 187.58,27.94 187.58,24.26 186.5,23.18 170.75,23.18 169.8,24.13 169.8,26.29 170.56,27.05 174.12,27.05 175.13,28.07 175.13,31.37 173.99,32.51 J44.2 173.99,34.8 172.64,36.14 161.67,36.14 160.94,35.41 160.94,34.93 v1(160.54,34.52) 160.54,20.58 158.43,18.48 142.61,18.48 v1(142.07,19.01) 141.62,19.01 140.26,17.65 138.89,17.65 136.81,15.57 126.77,15.57 113.22,29.12 113.22,36.86 112.65,37.43 112.65,46.48 121.34,55.16 121.34,75.28 v1(124.73,78.68)
  BOTTOM w0.132: U111.20 v1(142.07,19.01) ; v1(157.1,152.39) 157.1,151.73 TP69.1 ; v1(160.54,34.52) 161.04,35.02 J35.32 ; R545.2 v1(124.73,78.68)
SOC_MCU_SCL_R: length 102.4
  TOP w0.132: U34.AD8 v1(139.96,103.39)
  L12_SIG4 w0.084: v1(139.96,103.39) 139.96,103.38 140.31,103.02 142.45,103.02 142.75,102.72 142.75,100.87 143.06,100.56 149.76,100.56 149.99,100.33 149.99,94.44 150.2,94.22 150.51,94.22 150.79,93.94 150.79,91.24 151.06,90.96 155.31,90.96 155.59,90.68 155.59,90.44 155.86,90.16 156.11,90.16 156.39,89.88 156.39,88.84 156.6,88.62 160.43,88.62 162.56,86.49 162.56,77.09 160.91,75.44 160.91,73.03 158.88,70.99 158.88,70.06 156.99,68.17 156.99,66.32 158.54,64.77 158.74,64.77 163.83,64.77 168.66,59.94 168.66,56.26 171.32,53.59 171.32,38.99 172.21,38.1 172.21,34.04 171.45,33.27 J44.1
SOC_MCU_SDA: length 356.5
  TOP w0.132: J5.3 156.14,150.06 155.83,150.37 U9.5 v1(155.83,152.39)
  L03_SIG1 w0.084: v1(155.83,152.39) 156.24,152.8 159.12,152.8 164.72,147.19 177.87,147.19 179.14,148.47 193.37,148.47 199.69,142.15 199.69,80.71 190.44,71.45 190.44,39.81 188.85,38.23 188.85,35.31 189.23,34.93 189.23,25.4 186.56,22.73 170.18,22.73 169.29,23.62 169.29,26.67 170.05,27.43 172.34,27.43 J45.2 173.99,30.73 172.72,32 172.72,34.29 171.1,35.91 162.02,35.91 161.54,35.43 v1(161.54,35.43) 162.05,34.92 162.05,20.51 159.7,18.16 141.22,18.16 v1(140.24,17.18) 138.84,17.18 136.93,15.27 126.64,15.27 112.92,28.99 112.92,36.73 112.35,37.3 112.35,46.61 121.03,55.29 121.03,76 v1(124.73,79.69)
  BOTTOM w0.132: v1(155.83,152.39) 155.83,151.87 TP70.1 ; U111.18 v1(140.24,17.18) ; J35.34 v1(161.54,35.43) ; R538.2 v1(124.73,79.69)
SOC_MCU_SDA_R: length 108
  TOP w0.132: U34.AD7 v1(139.96,104.19)
  L12_SIG4 w0.084: J45.1 172.78,30.42 172.78,38.16 171.56,39.39 171.56,53.69 168.89,56.36 168.89,60.04 163.93,65.01 158.64,65.01 157.23,66.42 157.23,68.07 158.24,69.09 159.31,69.09 159.72,69.5 159.72,71.08 161.79,73.14 161.79,75.17 162.94,76.33 162.94,86.49 160.02,89.41 157.41,89.41 157.19,89.64 157.19,89.88 156.91,90.16 156.66,90.16 156.39,90.44 156.39,90.68 156.05,91.02 155.8,91.02 155.58,91.25 155.58,91.57 155.38,91.76 151.8,91.76 151.59,91.98 151.59,93.88 151.31,94.16 151.06,94.16 150.72,94.5 150.72,101.14 150.45,101.42 143.8,101.42 143.59,101.64 143.59,103.56 143.32,103.82 140.6,103.82 140.23,104.19 v1(139.96,104.19)
SOC_MCU_UART1_CTS_1V8: length 82.9
  TOP w0.132: U34.P1 v1(148.76,108.99) ; v1(121.81,154.51) 121.95,154.65 U8.5
  L03_SIG1 w0.084: v1(148.76,108.99) 149.23,109.46 149.23,111.12 150.91,112.81 150.91,113.46 151.42,113.97 151.42,125.5 153.6,127.68 153.6,139.87 152.03,141.43 152.03,143.84 152.71,144.52 152.71,149.3 151.43,150.58 151.43,156.05 150.73,156.75 128.81,156.75 127.05,154.99 122.3,154.99 v1(121.81,154.51)
SOC_MCU_UART1_RTS_1V8: length 105.2
  TOP w0.132: U12.7 v1(116.58,150.11) ; U6.7 116.36,156.63 116.4,156.67 117.05,156.67 v1(117.49,156.23) ; U34.N3 v1(149.56,107.39)
  L03_SIG1 w0.084: v1(149.56,107.39) 149.95,107.78 149.95,109.6 149.95,109.6 149.95,110.83 152.12,113.01 152.12,117.2 152.65,117.73 152.65,120.91 158.94,127.2 158.94,137.48 155.18,141.24 155.18,143.23 153.96,144.45 153.96,150.39 152.95,151.41 152.95,156.8 150.06,159.69 129.59,159.69 129.39,159.48 129.08,159.18 122.05,159.18 121.36,158.49 119.76,158.49 v1(117.49,156.23)
  BOTTOM w0.132: v1(117.49,156.23) 117.1,156.62 116.42,156.62 116.18,156.39 116.18,150.51 v1(116.58,150.11)
SOC_MCU_UART1_RX_1V8: length 88.2
  TOP w0.132: U34.P4 v1(148.76,106.59)
  L03_SIG1 w0.084: v1(121.82,156.34) 122.54,155.61 127.24,155.61 129.35,157.72 150.19,157.72 151.73,156.18 151.73,150.61 153.02,149.32 153.02,144.39 152.34,143.72 152.34,141.56 154.28,139.62 154.28,138.49 156.06,136.71 156.06,124.75 151.73,120.42 151.73,113.13 149.61,111 149.61,109.22 149.16,108.78 149.16,107 v1(148.76,106.59)
  BOTTOM w0.132: U65.5 122,156.15 v1(121.82,156.34)
SOC_MCU_UART1_TX_1V8: length 85.4
  TOP w0.132: U34.P5 v1(148.76,105.79) ; U6.6 v1(116.58,156.23) ; U12.6 116.36,149.71 116.4,149.67 117.05,149.67 v1(117.49,150.11)
  L05_SIG2 w0.084: v1(148.76,105.79) 148.36,105.79 147.83,106.33 147.83,109.35 147.75,109.42 147.75,112.34 145.29,114.81 145.29,116.97 144.63,117.62 144.63,122.32 144.44,122.52 144.44,125.69 136.65,133.48 125.35,133.48 123.38,135.44 113.54,135.44 111.32,137.67 111.32,144.97 115.7,149.35 116.73,149.35 v1(117.49,150.11)
  BOTTOM w0.132: v1(116.58,156.23) 116.58,151.03 v1(117.49,150.11)
SOC_MMC0_CD: length 31.5
  TOP w0.132: v1(176.54,71.64) 175.25,71.64 165.16,81.72 165.16,88.06 163.87,89.36 163.02,89.36 161.76,90.61 159.52,90.61 159.15,90.99 U34.A23
  BOTTOM w0.132: v1(176.54,71.64) 177.42,70.76 R739.1
SOC_MMC0_CLK: length 24.5
  TOP w0.132: U34.B25 158.35,88.99 159.48,88.99 159.55,89.06 161.21,89.06 163.73,86.53 163.73,73.56 163.21,73.04 160.94,73.04 v1(160.41,73.57)
  BOTTOM w0.132: RA14.3 v1(160.41,73.57)
SOC_MMC0_CMD: length 19.2
  TOP w0.132: U34.B27 158.35,87.39 159.09,87.39 159.19,87.3 161.47,87.3 162.68,86.09 162.68,75.43 162.02,74.77 162.02,74.18 v1(161.41,73.57)
  BOTTOM w0.132: RA14.5 v1(161.41,73.57)
SOC_MMC0_DAT0: length 19.2
  TOP w0.132: v1(162.41,73.57) 163.21,74.36 163.21,86.31 160.99,88.53 159.21,88.53 159.15,88.59 U34.A26
  BOTTOM w0.132: RA14.7 v1(162.41,73.57)
SOC_MMC0_DAT1: length 18.1
  TOP w0.132: U34.E25 v1(155.96,88.99)
  L03_SIG1 w0.084: v1(159.35,73.57) 158.94,73.98 158.94,82.69 156.35,85.28 156.35,88.6 v1(155.96,88.99)
  BOTTOM w0.132: RA14.1 v1(159.35,73.57)
SOC_MMC0_DAT2: length 17.2
  TOP w0.132: U34.C26 v1(157.56,88.19)
  L03_SIG1 w0.084: v1(159.35,74.49) 159.35,82.71 157.16,84.9 157.16,87.8 v1(157.56,88.19)
  BOTTOM w0.132: v1(159.35,74.49) 159.91,73.92 RA14.2
SOC_MMC0_DAT3: length 21
  TOP w0.132: U34.A25 159.35,89.39 159.55,89.59 161.43,89.59 164.26,86.75 164.26,74.39 v1(165.1,73.55)
  BOTTOM w0.132: R533.1 v1(165.1,73.55)
SOC_MMC0_DAT4: length 24.6
  TOP w0.132: U34.E24 v1(155.96,89.79)
  L03_SIG1 w0.084: v1(155.96,89.79) 156.35,89.4 158.52,89.4 158.52,89.4 160.83,89.4 163.69,86.54 163.69,79.63 161.8,77.74 161.8,74.93 v1(161.35,74.49)
  BOTTOM w0.132: RA14.6 161.91,73.92 v1(161.35,74.49)
SOC_MMC0_DAT5: length 21.8
  TOP w0.132: v1(166.01,73.55) 164.53,75.04 164.53,86.86 161.54,89.85 159.1,89.85 U34.A24
  BOTTOM w0.132: v1(166.01,73.55) 166.01,73.37 166.12,73.27 R532.1
SOC_MMC0_DAT6: length 19.9
  TOP w0.132: v1(162.41,74.49) 162.94,75.01 162.94,86.2 160.88,88.27 159.17,88.27 159.09,88.19 158.36,88.19 U34.B26
  BOTTOM w0.132: v1(162.41,74.49) 162.98,73.92 RA14.8
SOC_MMC0_DAT7: length 22.8
  TOP w0.132: U34.D25 v1(156.76,88.99)
  L03_SIG1 w0.084: v1(160.35,74.49) 160.35,77.37 163.08,80.1 163.08,86.29 160.77,88.6 159.77,88.6 159.77,88.6 157.15,88.6 v1(156.76,88.99)
  BOTTOM w0.132: RA14.4 160.91,73.92 v1(160.35,74.49)
SOC_MMC0_DS: length 36.2
  TOP w0.132: v1(158.75,63.96) R253.1 R252.2 ; U34.C25 v1(157.56,88.99)
  L03_SIG1 w0.084: v1(157.56,88.99) 160.81,88.99 163.39,86.42 163.39,79.79 160.82,77.22 160.82,73.32 160.4,72.9 158.24,72.9 157.1,71.75 157.1,65.61 v1(158.75,63.96)
SOC_MMC0_WP: length 31.9
  TOP w0.132: v1(176.44,70.86) 175.52,70.86 164.9,81.48 164.9,87.1 161.77,90.23 159.39,90.23 159.03,90.59 158.36,90.59 U34.B23
  BOTTOM w0.132: R741.2 R740.1 176.4,70.82 v1(176.44,70.86)
SOC_OSPI_CLK: length 12.3
  TOP w0.132: U34.V1 v1(144.76,108.99)
  L03_SIG1 w0.084: v1(144.76,108.99) 144.76,112.56 142.3,115.01 v1(142.3,119.05)
  BOTTOM w0.132: R430.1 v1(142.3,119.05)
SOC_OSPI_DQ0: length 26.5
  TOP w0.132: U34.U4 v1(145.56,106.59)
  L03_SIG1 w0.084: v1(145.56,106.59) 145.15,107 144.59,107 144.36,107.23 144.36,109.15 144.37,109.15 144.37,112.17 141.1,115.44 141.1,121.28 141.73,121.92 145.54,121.92 146.14,121.32 146.14,120.15 v1(145.04,119.05)
  BOTTOM w0.132: RA8.13 v1(145.04,119.05)
SOC_OSPI_DQ1: length 27.7
  TOP w0.132: U34.U5 v1(145.56,105.79)
  L03_SIG1 w0.084: v1(147.23,118.1) 147.59,118.45 147.59,120.88 147.74,121.03 150.22,121.03 150.37,120.88 150.37,118.15 151.12,117.4 151.12,114.1 150.51,113.49 150.51,113 148.84,111.34 148.84,109.73 148.28,109.16 148.28,107.88 148.27,107.87 148.27,107.85 147.95,107.54 147.95,106.04 147.32,105.4 145.95,105.4 v1(145.56,105.79)
  BOTTOM w0.132: v1(147.23,118.1) 146.54,118.79 RA8.10
SOC_OSPI_DQ2: length 13.4
  TOP w0.132: U34.T2 v1(146.36,108.19)
  L03_SIG1 w0.084: v1(144.04,118.05) 144.04,115.04 145.44,113.64 145.44,112.88 145.95,112.37 145.95,108.87 146.36,108.46 v1(146.36,108.19)
  BOTTOM w0.132: RA8.16 143.47,118.61 v1(144.04,118.05)
SOC_OSPI_DQ3: length 18.8
  TOP w0.132: U34.T3 v1(146.36,107.39)
  L03_SIG1 w0.084: v1(145.1,118.05) 144.53,118.62 144.53,119.35 144.37,119.51 143.54,119.51 143.38,119.35 143.38,114.36 145.16,112.58 145.16,108.83 145.39,108.6 145.72,108.6 145.96,108.36 145.96,108.04 146.36,107.64 v1(146.36,107.39)
  BOTTOM w0.132: RA8.14 144.54,118.61 v1(145.1,118.05)
SOC_OSPI_DQ4: length 15.2
  TOP w0.132: U34.T4 v1(146.36,106.59)
  L03_SIG1 w0.084: v1(146.36,106.59) 146.76,107 146.76,112.06 145.74,113.08 145.74,113.77 144.44,115.07 144.44,116.77 144.65,116.98 144.65,118.01 144.04,118.62 v1(144.04,119.05)
  BOTTOM w0.132: RA8.15 v1(144.04,119.05)
SOC_OSPI_DQ5: length 26.6
  TOP w0.132: U34.T5 v1(146.36,105.79)
  L03_SIG1 w0.084: v1(146.36,105.79) 146.76,106.2 147.35,106.2 147.7,106.55 147.7,107.6 148.05,107.95 148.05,107.97 148.05,107.97 148.05,109.44 148.46,109.86 148.46,111.39 150.2,113.13 150.2,113.61 150.81,114.22 150.81,117.27 150.06,118.02 150.06,120.37 149.91,120.52 148.04,120.52 147.89,120.37 147.89,117.83 147.64,117.58 147.19,117.58 147.03,117.74 146.37,117.74 146.24,117.87 v1(146.24,118.1)
  BOTTOM w0.132: v1(146.24,118.1) 145.54,118.8 RA8.12
SOC_OSPI_DQ6: length 27.5
  TOP w0.132: U34.R2 v1(147.16,108.19)
  L03_SIG1 w0.084: v1(146.04,119.05) 145.51,118.52 145.51,117.09 145.35,116.94 145.35,115.13 145.67,114.81 149.07,114.81 149.23,114.96 149.23,115.54 149.07,115.7 147.38,115.7 147.23,115.85 147.23,116.06 148.26,117.09 150.03,117.09 150.18,116.94 150.18,114.88 149.23,113.92 147.23,113.92 147.08,113.77 147.08,109.87 147.57,109.38 147.57,108.61 v1(147.16,108.19)
  BOTTOM w0.132: RA8.11 v1(146.04,119.05)
SOC_OSPI_DQ7: length 27.5
  TOP w0.132: U34.R3 v1(147.16,107.39)
  L03_SIG1 w0.084: v1(147.1,119.05) 147.1,120.12 146.95,120.27 146.6,120.27 146.44,120.12 146.44,118.88 146.21,118.64 146.07,118.64 145.83,118.4 145.83,117.19 146.3,116.71 147.44,116.71 148.21,117.48 148.21,119.86 148.36,120.02 149.61,120.02 149.76,119.86 149.76,117.9 150.49,117.17 150.49,114.56 149.39,113.46 149.39,112.94 147.83,111.38 147.83,108.06 v1(147.16,107.39)
  BOTTOM w0.132: RA8.9 v1(147.1,119.05)
SOC_PORZ: length 339.5
  TOP w0.132: U34.W5 v1(143.96,105.79) ; R299.2 v1(105.12,50.55) ; U34.E19 v1(155.96,93.79)
  L05_SIG2 w0.084: v1(148.34,47.24) 147.07,47.24 145.61,48.7 141.24,48.7 140.27,47.74 127.25,47.74 126.03,48.96 124.4,48.96 119.89,53.47 108.04,53.47 v1(105.12,50.55) ; v1(151.89,149.48) 153.67,149.48 154.46,150.27 191.66,150.27 201.28,140.65 201.28,69.96 196.97,65.65 186.57,65.65 185.55,66.67 177.42,66.67 v1(176.09,65.34)
  L10_SIG3 w0.084: v1(155.96,93.79) 155.56,93.4 153.4,93.4 153.16,93.64 153.16,102.87 ; v1(176.09,65.34) 176.09,63.18 171.67,58.77 171.67,44.99 170.56,43.88 156.06,43.88 152.69,47.24 v1(148.34,47.24) ; v1(151.89,149.48) 151.52,149.85 150.11,149.85 146.43,146.18 146.43,141.69 142.38,137.64 142.38,130.94 145,128.33 148.84,128.33 154.75,122.41 154.75,119.89 v1(154.19,119.33) 154.75,118.76 154.75,106.36 154.59,106.2 154.2,106.2 153.97,105.96 153.96,105.95 153.96,103.25 153.95,103.23 153.95,103.23 153.72,103 153.29,103 153.16,102.87 ; 153.16,102.87 153.04,103 148.59,103 148.08,103.51 148.08,104.27 147.76,104.58 147,104.58 146.81,104.78 146.81,104.78 146.77,104.83 146.77,104.89 146.76,104.9 146.76,105.27 146.63,105.4 144.35,105.4 v1(143.96,105.79)
  BOTTOM w0.132: R743.2 151.26,151.38 151.89,150.75 v1(151.89,149.48) 151.89,148.34 TP28.1 ; R427.1 v1(154.19,119.33)
SOC_POWER_MON_PORZ: length 10
  TOP w0.132: U50.1 108.34,54.81 109.92,56.39 113.67,56.39 113.83,56.23 113.83,55.21 114.08,54.95 R289.2 114.35,54.28 114.31,54.24 U49.4
SOC_SAFETY_ERRORZ: length 22.6
  TOP w0.132: U34.E20 v1(155.96,92.99)
  L05_SIG2 w0.084: TP57.1 165.99,86.49 165.99,92.96 165.65,93.31 163.6,93.31 162.68,92.38 159.08,92.38 158.86,92.6 156.35,92.6 v1(155.96,92.99)
SOC_SERDES_REFCLK0_N: length 53.7
  TOP w0.107: J5.24 139.34,149.15 139.09,149.4 139.09,150.23 v1(139.44,150.58) ; U34.AG5 v1(137.56,105.79)
  L12_SIG4 w0.076: v1(139.44,150.58) 139.1,150.58 138.88,150.37 138.88,144.25 139.61,143.53 139.61,135.39 135.46,131.24 135.46,114.83 133.5,112.88 133.5,109.31 137.27,105.54 137.46,105.54 137.56,105.63 v1(137.56,105.79)
SOC_SERDES_REFCLK0_P: length 53.7
  TOP w0.107: U34.AG6 v1(137.56,104.99) ; v1(138.43,150.58) 138.8,150.22 138.8,149.41 138.54,149.15 J5.25
  L12_SIG4 w0.076: v1(138.43,150.58) 138.61,150.41 138.61,144.13 139.33,143.41 139.33,135.51 135.18,131.36 135.18,114.95 133.22,112.99 133.22,109.19 137.16,105.26 137.29,105.26 v1(137.56,104.99)
SOC_SERDES_REFCLK1_N: length 47.9
  TOP w0.107: J5.55 138.54,144.77 138.27,144.51 138.27,143.55 v1(138.66,143.16) ; U34.AH6 v1(136.76,104.99)
  L12_SIG4 w0.076: v1(136.76,104.99) 136.5,104.73 135.97,104.73 131.53,109.17 131.53,114.48 132.11,115.05 132.11,129.8 138.12,135.82 138.12,143.04 138.32,143.24 138.57,143.24 v1(138.66,143.16)
SOC_SERDES_REFCLK1_P: length 47.9
  TOP w0.107: J5.56 137.74,144.77 137.98,144.54 137.98,143.52 v1(137.62,143.16) ; U34.AH7 v1(136.76,104.19)
  L12_SIG4 w0.076: v1(136.76,104.19) 136.49,104.46 135.85,104.46 131.26,109.05 131.26,114.59 131.83,115.16 131.83,129.91 137.85,135.93 137.85,142.93 v1(137.62,143.16)
SOC_SPI0_CLK: length 124.3
  TOP w0.132: R136.1 v1(104.3,112.52) 102.3,112.52 U24.B2 ; J16.20 v1(53.93,62.87)
  L10_SIG3 w0.084: v1(53.93,62.87) 53.93,64.22 55.02,65.31 55.02,79.85 53.38,81.5 53.38,88.3 56.95,91.87 79.24,91.87 98.74,111.38 103.16,111.38 v1(104.3,112.52)
  BOTTOM w0.132: v1(104.3,112.52) 104.3,109.86 113.6,100.56 114.53,100.56 114.62,100.65 119.93,100.65 121.73,98.85 121.73,93.78 122.54,92.96 R491.1
SOC_SPI0_CLK_R: length 16.4
  TOP w0.132: U34.AH13 v1(136.76,99.39)
  L10_SIG3 w0.084: v1(124.73,92.96) 125.19,92.96 126.24,94.02 126.24,94.82 127.29,95.87 130.32,95.87 132.54,98.09 134.16,98.09 135.46,99.39 v1(136.76,99.39)
  BOTTOM w0.132: R491.2 v1(124.73,92.96)
SOC_SPI0_CS0: length 44.4
  TOP w0.132: U34.AG13 v1(137.56,98.59) ; U24.C2 102.28,113.54 v1(104.3,113.54) R133.1
  L05_SIG2 w0.084: v1(137.56,98.59) 137.16,98.98 125.38,98.98 124.79,99.57 122.17,99.57 121.4,100.34 121.4,100.57 119.71,102.26 118.53,102.26 116.4,104.39 112.27,104.39 105.35,111.31 105.35,112.49 v1(104.3,113.54)
SOC_SPI0_CS1: length 113.8
  TOP w0.132: U34.AF13 v1(138.36,99.39) ; J16.24 v1(52.93,62.87)
  L10_SIG3 w0.084: v1(52.93,62.87) 53.34,62.46 56.62,62.46 57.61,63.45 69.1,63.45 85.39,79.73 104.5,79.73 112.78,88 112.78,100.98 v1(113.26,101.47)
  L12_SIG4 w0.084: v1(113.26,101.47) 114.04,100.69 125.35,100.69 126.67,102.01 135.04,102.01 136.46,100.58 137.73,100.58 137.96,100.35 137.96,99.78 v1(138.36,99.39)
SOC_SPI0_D0: length 144.7
  TOP w0.132: v1(51.93,61.95) 52.43,62.45 J16.26 ; U34.AE13 v1(139.16,99.39) ; R123.1 v1(104.3,115.57) 101.3,115.57 U24.D3
  L05_SIG2 w0.084: v1(139.16,99.39) 138.91,99.39 138.52,99.78 130.53,99.78 130.3,100.01 123.89,100.01 123.25,100.65 122.36,100.65 118.11,104.9 112.52,104.9 105.85,111.57 105.85,114.02 v1(104.3,115.57)
  L10_SIG3 w0.084: v1(104.3,115.57) 104.76,115.11 104.76,114.36 104.49,114.1 104.11,114.1 101.7,111.68 98.62,111.68 79.11,92.18 54.9,92.18 53.44,90.71 53.44,89.25 52.33,88.15 52.33,81.91 54.64,79.6 54.64,65.56 52.39,63.31 52.39,62.41 v1(51.93,61.95)
SOC_SPI0_D1: length 143.7
  TOP w0.132: U34.AD13 v1(139.96,99.39) ; J16.28 v1(51.93,62.87) ; U24.D2 102.27,114.55 v1(104.3,114.55) R126.1
  L05_SIG2 w0.084: v1(104.3,114.55) 103.85,115.01 103.85,115.76 104.11,116.03 104.49,116.03 107.15,113.37 107.15,111.04 112.78,105.41 118.03,105.41 121.72,101.73 126.05,101.73 126.78,100.99 135.86,100.99 136.27,100.58 139.33,100.58 139.56,100.35 139.56,100.03 139.57,100.03 139.57,99.96 139.96,99.57 v1(139.96,99.39)
  L10_SIG3 w0.084: v1(104.3,114.55) 103.82,114.55 101.26,111.99 98.49,111.99 81.37,94.87 69.72,94.87 69.52,95.07 57.33,95.07 53.22,90.97 52.6,90.97 51.36,89.73 51.36,78.76 52.65,77.47 52.65,75.2 53.39,74.46 53.39,65.07 51.93,63.61 v1(51.93,62.87)
SOC_SPI1_CLK: length 192.6
  L03_SIG1 w0.084: v1(112.51,34.73) 112.51,36.71 112.04,37.18 112.04,46.24 110.72,47.56 110.72,57.94 113.49,60.71 113.49,92.11 117.29,95.91 122.47,95.91 123.06,95.32 123.06,94.5 v1(122.54,93.98)
  L05_SIG2 w0.084: v1(164.54,34.52) 167.19,31.86 182.69,31.86 183.84,33.02 190.97,33.02 J20.4
  L10_SIG3 w0.084: v1(164.54,34.52) 163.36,33.34 152.22,33.34 151.07,32.18 115.06,32.18 v1(112.51,34.73)
  L12_SIG4 w0.084: v1(200.51,14.7) 203.2,17.39 203.2,32.26 201.04,34.42 196.43,34.42 J20.4
  BOTTOM w0.132: J38.32 v1(200.51,14.7) ; R489.1 v1(122.54,93.98) ; J35.48 165.04,35.02 v1(164.54,34.52)
SOC_SPI1_CLK_R: length 16.7
  TOP w0.132: U34.AH12 v1(136.76,100.19)
  L10_SIG3 w0.084: v1(136.76,100.19) 136.14,100.19 136.08,100.13 132.46,100.13 130.25,97.92 127.12,97.92 125.35,96.15 125.35,95.89 124.73,95.26 v1(124.73,93.98)
  BOTTOM w0.132: R489.2 v1(124.73,93.98)
SOC_SPI1_CS: length 3.4
  TOP w0.132: J20.3 R316.1 R317.1
SOC_SPI1_CS0: length 145.8
  TOP w0.132: v1(197.17,14.2) 197.17,33.6 196.62,34.14 R317.2 v1(191.54,34.82) ; U34.AD12 v1(139.96,100.19)
  L05_SIG2 w0.084: v1(145.47,81.28) 145.15,81.6 145.15,85.97 145.15,85.98 145.15,97.22 144.44,97.93 140.83,97.93 140.35,98.41 140.35,99.8 v1(139.96,100.19)
  L10_SIG3 w0.084: v1(145.47,81.28) 146.1,80.65 148.21,80.65 153.67,75.18 158.62,75.18 163.2,79.76 173.1,79.76 174.88,77.98 174.88,76.69 176.01,75.56 176.91,75.56 180.11,72.37 180.11,42.13 176.97,39 176.97,36.51 178.66,34.82 v1(191.54,34.82)
  BOTTOM w0.132: R675.1 v1(197.17,14.2)
SOC_SPI1_CS1: length 121.4
  TOP w0.132: R316.2 189.49,35.12 170.37,35.12 167.64,37.85 R311.1 v1(163.54,38.58) ; U34.AG12 v1(137.56,99.39)
  L03_SIG1 w0.084: v1(139.57,76.57) 140.21,75.93 140.21,57.66 v1(142.11,55.75)
  L05_SIG2 w0.084: v1(142.11,55.75) 143.27,56.91 164.07,56.91 166.35,54.63 166.35,45.21 165.54,44.4 165.54,40.59 v1(163.54,38.58) ; v1(137.56,99.39) 137.96,98.98 138.52,98.98 138.75,98.75 138.75,98.36 139.73,97.38 140.12,97.38 140.36,97.13 140.36,96.83 140.59,96.6 141.02,96.6 141.16,96.45 141.16,89.6 140.94,89.38 140.57,89.38 140.35,89.16 140.35,88.77 140.17,88.6 140.12,88.6 140.12,88.6 139.78,88.6 139.55,88.37 139.55,86.43 139.55,86.43 139.55,84.55 138.81,83.82 138.81,77.33 v1(139.57,76.57)
SOC_SPI1_MISO: length 185.1
  TOP w0.132: U34.AF12 v1(138.36,100.19)
  L05_SIG2 w0.084: J20.2 186.53,32.38 183.77,32.38 182.94,31.56 166.81,31.56 164.08,34.29 164.08,34.98 v1(164.54,35.43) ; v1(138.36,100.19) 138.54,100 138.79,100 138.99,99.8 139.3,99.8 139.32,99.78 139.32,99.78 139.55,99.55 139.55,98.34 140.37,97.51 144.13,97.51 144.36,97.28 144.36,81.19 v1(145.47,80.09)
  L10_SIG3 w0.084: v1(145.47,80.09) 145.8,79.76 148.67,79.76 153.54,74.88 158.83,74.88 163.4,79.45 172.97,79.45 174.57,77.85 174.57,76.57 175.88,75.26 176.78,75.26 179.8,72.24 179.8,42.26 173.48,35.94 165.05,35.94 v1(164.54,35.43)
  L12_SIG4 w0.084: v1(200.51,12.7) 203.5,15.7 203.5,32.38 201.17,34.72 196.14,34.72 193.8,32.38 189.31,32.38 J20.2
  BOTTOM w0.132: J38.36 v1(200.51,12.7) ; J35.46 v1(164.54,35.43)
SOC_SPI1_MOSI: length 230.2
  TOP w0.132: U34.AE12 v1(139.16,100.19)
  L03_SIG1 w0.084: v1(111.54,55.95) 115.1,59.51 115.1,64.31 114.21,65.19 114.21,70.61 126.1,82.5 137.24,82.5 140.36,85.63 140.36,92.35 140.61,92.6 140.92,92.6 141.16,92.84 141.16,94.75 141.41,95 144.92,95 145.15,95.23 145.15,97.93 144.91,98.17 140.53,98.17 140.36,98.33 140.36,101.13 140.1,101.4 139.7,101.4 139.55,101.24 139.55,100.75 139.16,100.36 v1(139.16,100.19)
  L05_SIG2 w0.084: v1(111.54,55.95) 112.24,55.24 120.48,55.24 125.14,50.58 126.34,50.58 127.05,49.87 130.38,49.87 135.07,54.56 153.77,54.56 155.73,56.52 163.96,56.52 165.49,54.98 165.49,46.05 164.93,45.49 164.93,44.95 164.53,44.55 164.53,41.27 163,39.75 163,35.05 v1(163.54,34.52) 163.54,34.06 166.61,30.99 J20.1
  L12_SIG4 w0.084: v1(199.58,12.7) 200.02,12.26 201.36,12.26 203.81,14.71 203.81,32.51 201.29,35.03 196.01,35.03 193.75,32.77 187.16,32.77 J20.1
  BOTTOM w0.132: J38.35 200.08,13.2 v1(199.58,12.7) ; J35.44 164.04,35.02 v1(163.54,34.52)
SOC_TCK: length 134.9
  TOP w0.132: R241.2 v1(115.76,64.06) ; U34.AA4 v1(142.36,106.59)
  L03_SIG1 w0.084: v1(115.76,64.06) 116.08,64.38 116.08,71.62 126.35,81.89 139.04,81.89 141.96,84.81 141.96,92.35 142.21,92.6 142.52,92.6 142.75,92.83 142.75,93.13 143.01,93.4 146.52,93.4 146.75,93.63 146.75,99.55 146.5,99.8 142.19,99.8 141.96,100.03 141.96,105.95 142.36,106.34 v1(142.36,106.59)
  L05_SIG2 w0.084: v1(115.76,64.06) 115.3,63.6 114.14,63.6 113.21,64.53 113.21,66.08 112.63,66.65 81.63,66.65 79.56,64.59 73.44,64.59 v1(61.4,52.55)
  BOTTOM w0.132: v1(61.4,52.55) 61.4,52.2 61.26,52.05 R623.2
SOC_TDI: length 171.8
  TOP w0.132: U43.4 114.08,64.56 v1(114.58,64.06) ; U34.C20 v1(157.56,92.99)
  L05_SIG2 w0.084: v1(157.73,67.94) 157.4,68.27 137,68.27 135.99,67.27 135.64,66.92 135.64,56.49 130.65,51.5 125.52,51.5 120.24,56.77 120.24,63.41 119.19,64.46 115.59,64.46 115.18,64.06 v1(114.58,64.06) 116.21,65.69 116.21,66.04 113.92,68.33 74.63,68.33 60.2,53.89 60.2,53.65 v1(59.1,52.55)
  L12_SIG4 w0.084: v1(157.56,92.99) 157.39,92.99 156.98,93.4 155.76,93.4 155.58,93.22 155.58,92.05 155.86,91.76 156.11,91.76 156.39,91.48 156.39,91.24 156.6,91.02 156.88,91.02 157.19,90.72 157.19,90.44 157.45,90.17 159.77,90.17 163.32,86.61 163.32,73.95 162.57,73.2 162.48,73.2 159.96,70.68 159.96,69.41 159.4,68.85 158.64,68.85 v1(157.73,67.94)
  BOTTOM w0.132: v1(59.1,52.55) U98.4
SOC_TDO: length 204.5
  TOP w0.132: R208.2 164.55,92.68 164.9,92.33 165.1,92.33 166.22,91.21 166.22,82.83 174.29,74.76 v1(176.38,74.76)
  L05_SIG2 w0.084: v1(44.32,59.42) 43.69,58.78 43.69,55.25 50.23,48.7 v1(56.99,48.7) 58.65,50.36 58.65,52.68 74.6,68.63 115.47,68.63 120.55,63.55 120.55,56.9 125.64,51.8 128.81,51.8 134.54,57.53 v1(135.23,57.53)
  L10_SIG3 w0.084: v1(176.38,74.76) 177.58,73.56 177.58,70.57 174.14,67.12 173.59,67.12 168.3,67.12 163.17,61.99 162.35,61.18 152.97,61.18 149.12,65.02 147.7,65.02 147.25,64.58 142.39,64.58 135.66,57.85 135.55,57.85 v1(135.23,57.53)
  BOTTOM w0.132: v1(44.32,59.42) 44.15,59.6 U97.2 ; U101.2 56.59,47.48 56.54,47.53 56.54,47.87 56.54,48.26 v1(56.99,48.7)
SOC_TMS: length 178.8
  TOP w0.132: U34.A21 159.62,92.59 160.15,92.06 164.99,92.06 165.96,91.1 165.96,82.46 174.56,73.85 v1(176.47,73.85) ; U43.6 115.24,65.56 v1(115.68,65.99) 115.99,66.31 132.95,66.31 134.05,65.21 134.05,60.24 v1(133.29,59.47)
  L05_SIG2 w0.084: v1(59.1,51.55) 60.59,53.04 60.59,53.73 72.07,65.21 79.32,65.21 81.38,67.26 114.41,67.26 v1(115.68,65.99)
  L10_SIG3 w0.084: v1(133.29,59.47) 136.85,59.47 142.08,64.7 142.26,64.88 147.13,64.88 147.58,65.33 149.25,65.33 153.1,61.48 162.23,61.48 168.17,67.42 173.71,67.42 174.01,67.42 177.28,70.69 177.28,73.04 v1(176.47,73.85)
  BOTTOM w0.132: U98.6 v1(59.1,51.55)
SOC_TRST#: length 144.2
  TOP w0.132: U34.AA3 v1(142.36,107.39) ; U43.7 114.29,66.06 114.32,66.09 v1(114.77,66.09) ; R130.1 v1(141.48,113.33)
  L03_SIG1 w0.084: v1(114.77,66.09) 114.77,70.74 126.23,82.2 138.91,82.2 141.16,84.44 141.16,92.35 141.39,92.58 141.7,92.58 141.96,92.84 141.96,92.84 141.96,93.95 142.19,94.18 145.7,94.18 145.95,94.43 145.95,98.75 145.7,99 141.39,99 141.16,99.23 141.16,105.95 141.41,106.2 141.72,106.2 141.96,106.45 141.96,107 v1(142.36,107.39) 142.36,107.46 142.76,107.87 142.76,111.74 141.8,112.71 141.8,113.01 v1(141.48,113.33)
  L05_SIG2 w0.084: v1(61.34,51.55) 60.9,52 60.9,53.61 72.22,64.93 79.47,64.93 81.5,66.96 113.89,66.96 v1(114.77,66.09)
  BOTTOM w0.132: U98.7 60.84,51.05 v1(61.34,51.55)
SOC_UART1_CTS_1V8: length 76.5
  TOP w0.132: U26.12 89.28,106.78 v1(88.63,107.43) ; U34.AD22 v1(139.96,91.39)
  L05_SIG2 w0.084: v1(88.63,107.43) 90.01,108.81 104.96,108.81 112.24,101.54 112.24,90.28 119.79,82.73 127,82.73 130.96,86.69 133.1,86.69 133.93,87.53 134.24,87.53 135.38,88.67 135.59,88.67 136.3,89.38 137.77,89.38 137.96,89.58 137.96,90.08 138.08,90.2 138.52,90.2 138.75,90.43 138.75,90.43 138.76,90.45 138.76,90.75 139.01,91 139.56,91 v1(139.96,91.39)
SOC_UART1_RTS_1V8: length 78.4
  TOP w0.132: U34.AC21 v1(140.76,92.19) ; U26.9 v1(87.33,106.39)
  L05_SIG2 w0.084: v1(87.33,106.39) 87.65,106.71 87.65,107.1 89.67,109.12 105.09,109.12 112.55,101.66 112.55,90.4 119.92,83.03 126.87,83.03 130.84,86.99 132.97,86.99 133.81,87.83 134.11,87.83 136,89.73 136,90.54 136.46,91 138.52,91 138.75,91.23 138.75,91.53 138.99,91.78 140.35,91.78 v1(140.76,92.19)
SOC_USB1_VBUS: length 184.2
  TOP w0.132: v1(16.25,155.53) R28.2 16.93,155.52 R34.1 ; U34.AF6 v1(138.36,104.99)
  L05_SIG2 w0.084: v1(140.59,155.13) 137.7,158.02 120.28,158.02 116.16,153.9 106.65,153.9 105.73,152.97 18.81,152.97 v1(16.25,155.53)
  L12_SIG4 w0.084: v1(140.59,155.13) 141.03,154.69 141.03,149.62 141.96,148.69 141.96,145.79 141,144.83 141,133.12 140.46,132.59 140.46,132.21 137.33,129.07 137.33,117.58 137.15,117.4 137.15,109.6 137.15,109.6 137.15,107.58 137.95,106.78 137.95,105.4 v1(138.36,104.99)
SOC_VDDS_DDR: length 3.4
  TOP w0.203: U34.G14 v1(154.36,98.59) ; U34.G10 v1(154.36,101.79) ; U34.H7 v1(153.56,104.19) ; U34.H9 v1(153.56,102.59) ; U34.G8 v1(154.36,103.39) ; U34.H13 v1(153.56,99.39)
  vias: v1(160.77,155.83) v1(160.77,154.81) v1(160.77,153.8) v1(161.79,155.83) v1(161.79,154.81) v1(161.79,153.8) v1(170.05,109.29) v1(170.18,108.4) v1(170.18,107.51) v1(170.94,109.35) v1(171.2,108.41) v1(171.2,107.52)
SOC_WARM_RESETZ: length 131.3
  TOP w0.132: U55.4 R309.1 113.93,40.98 114.02,40.89 v1(114.03,40.89) ; U34.F17 v1(155.16,95.39)
  L03_SIG1 w0.084: v1(172.47,44.51) 170.38,46.6 170.38,60.51 167.96,62.93 167.96,83.92 159.39,92.49 159.39,94.61 159,95 155.55,95 v1(155.16,95.39)
  L10_SIG3 w0.084: v1(172.47,44.51) 170.5,42.55 168.66,42.55 163.13,37.02 163.13,34.35 162.42,33.64 152.1,33.64 150.94,32.49 121.97,32.49 114.03,40.43 v1(114.03,40.89)
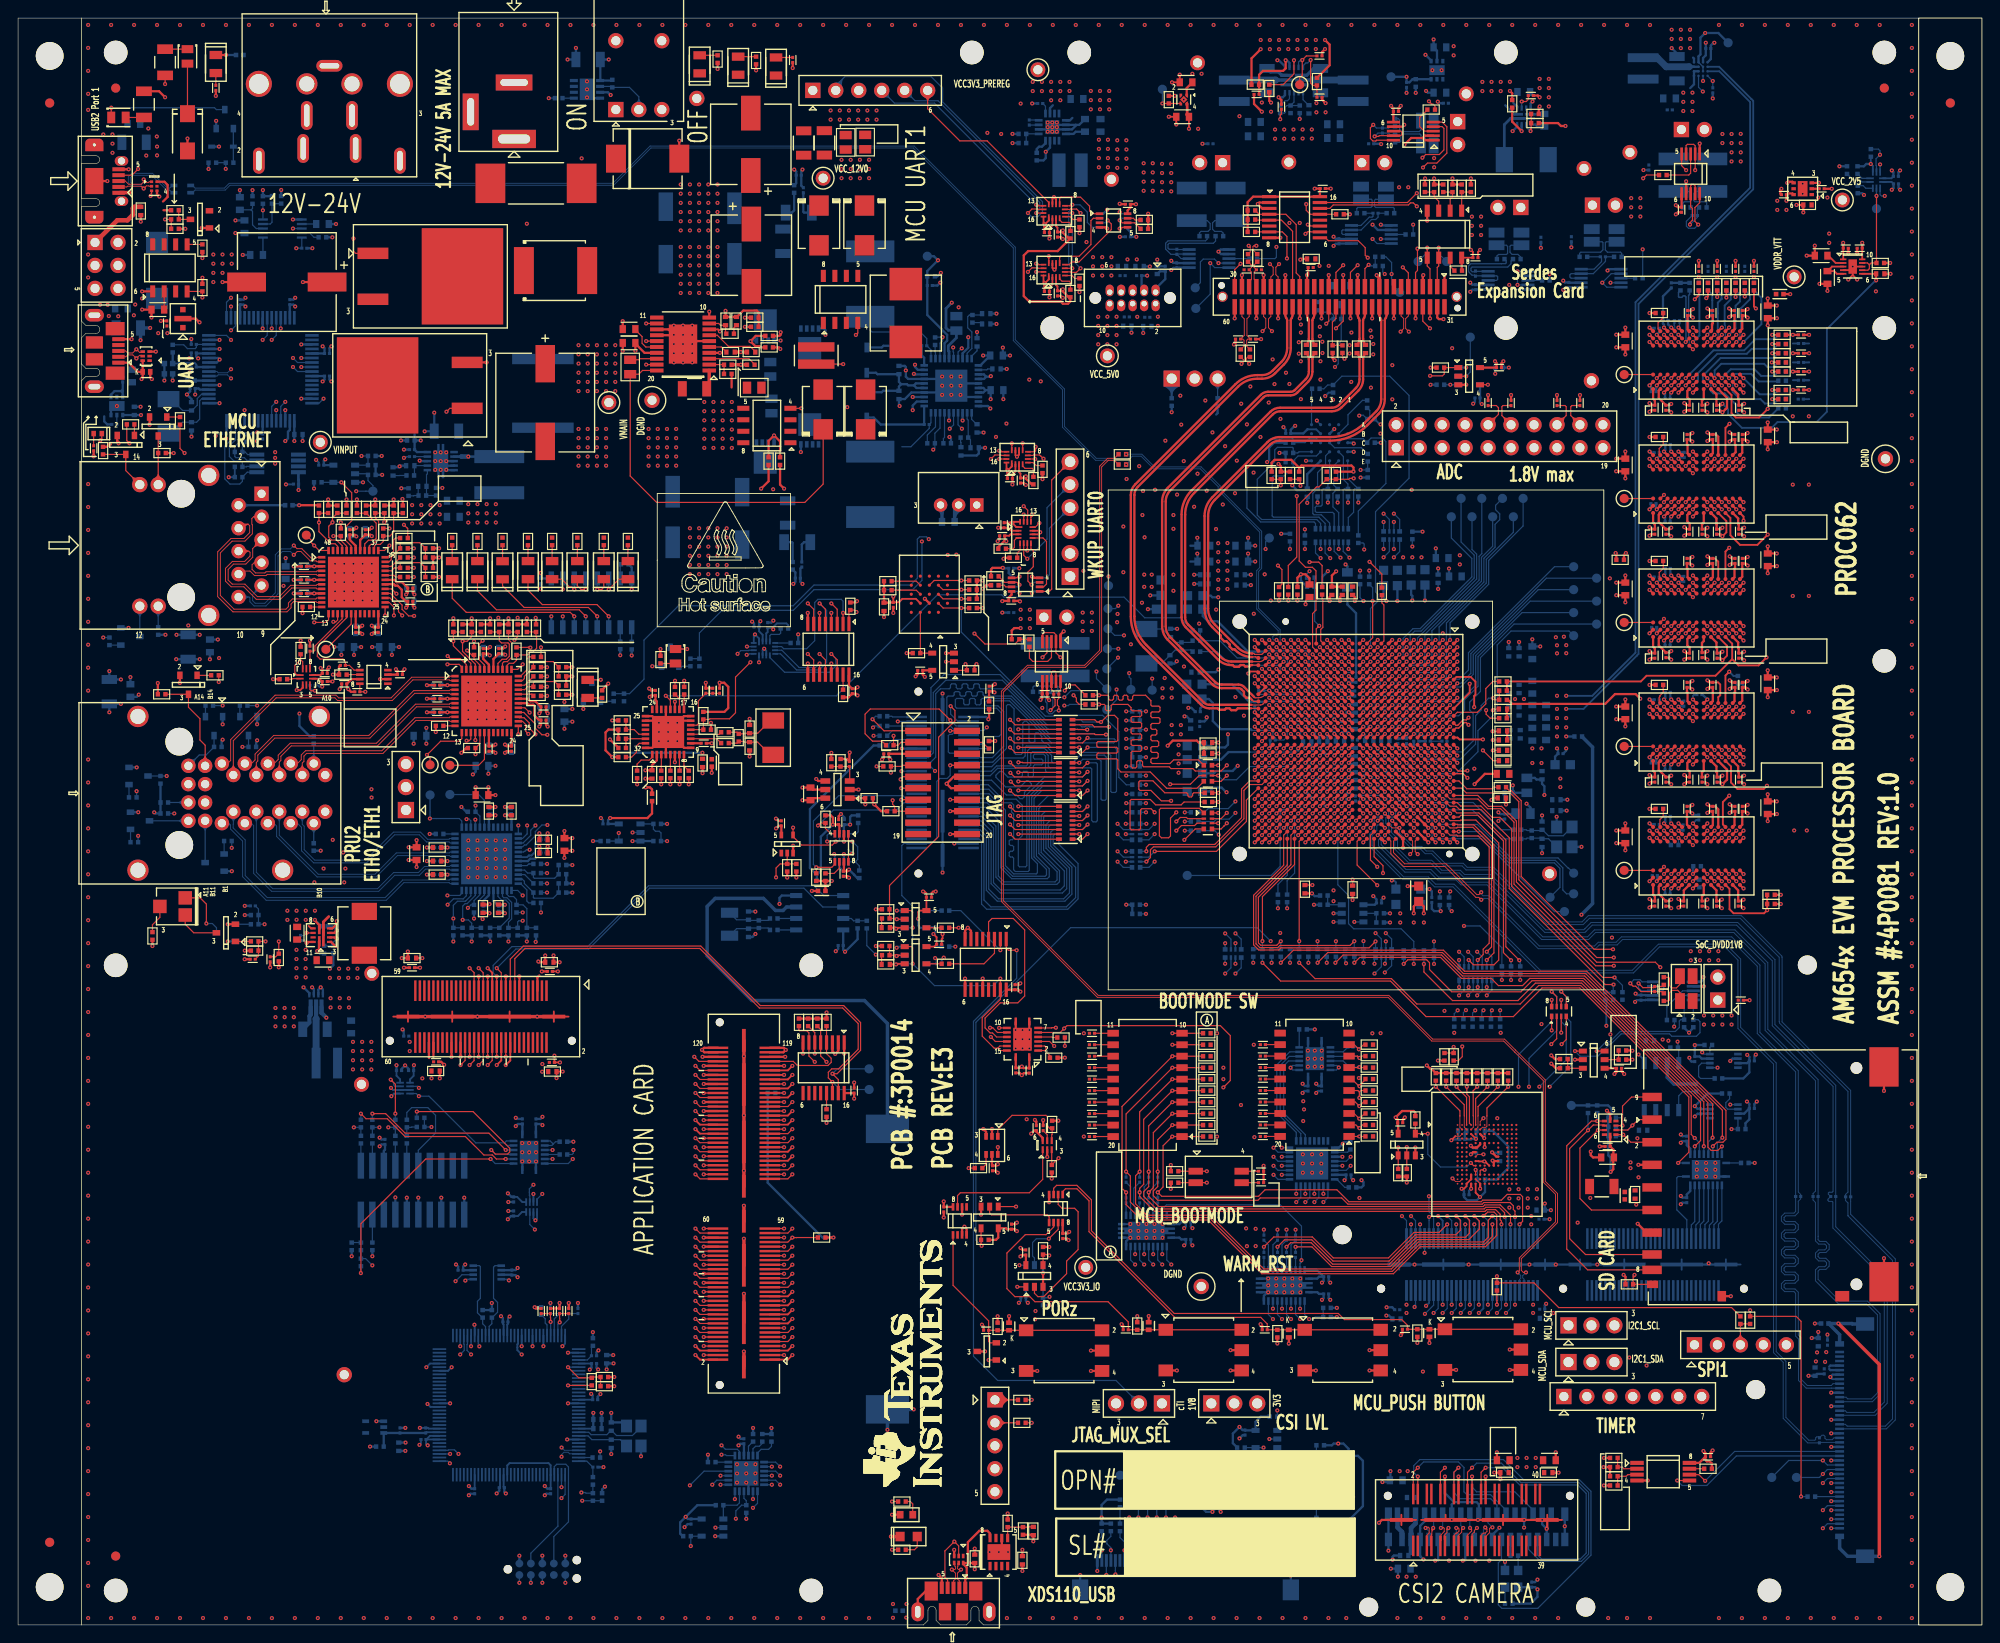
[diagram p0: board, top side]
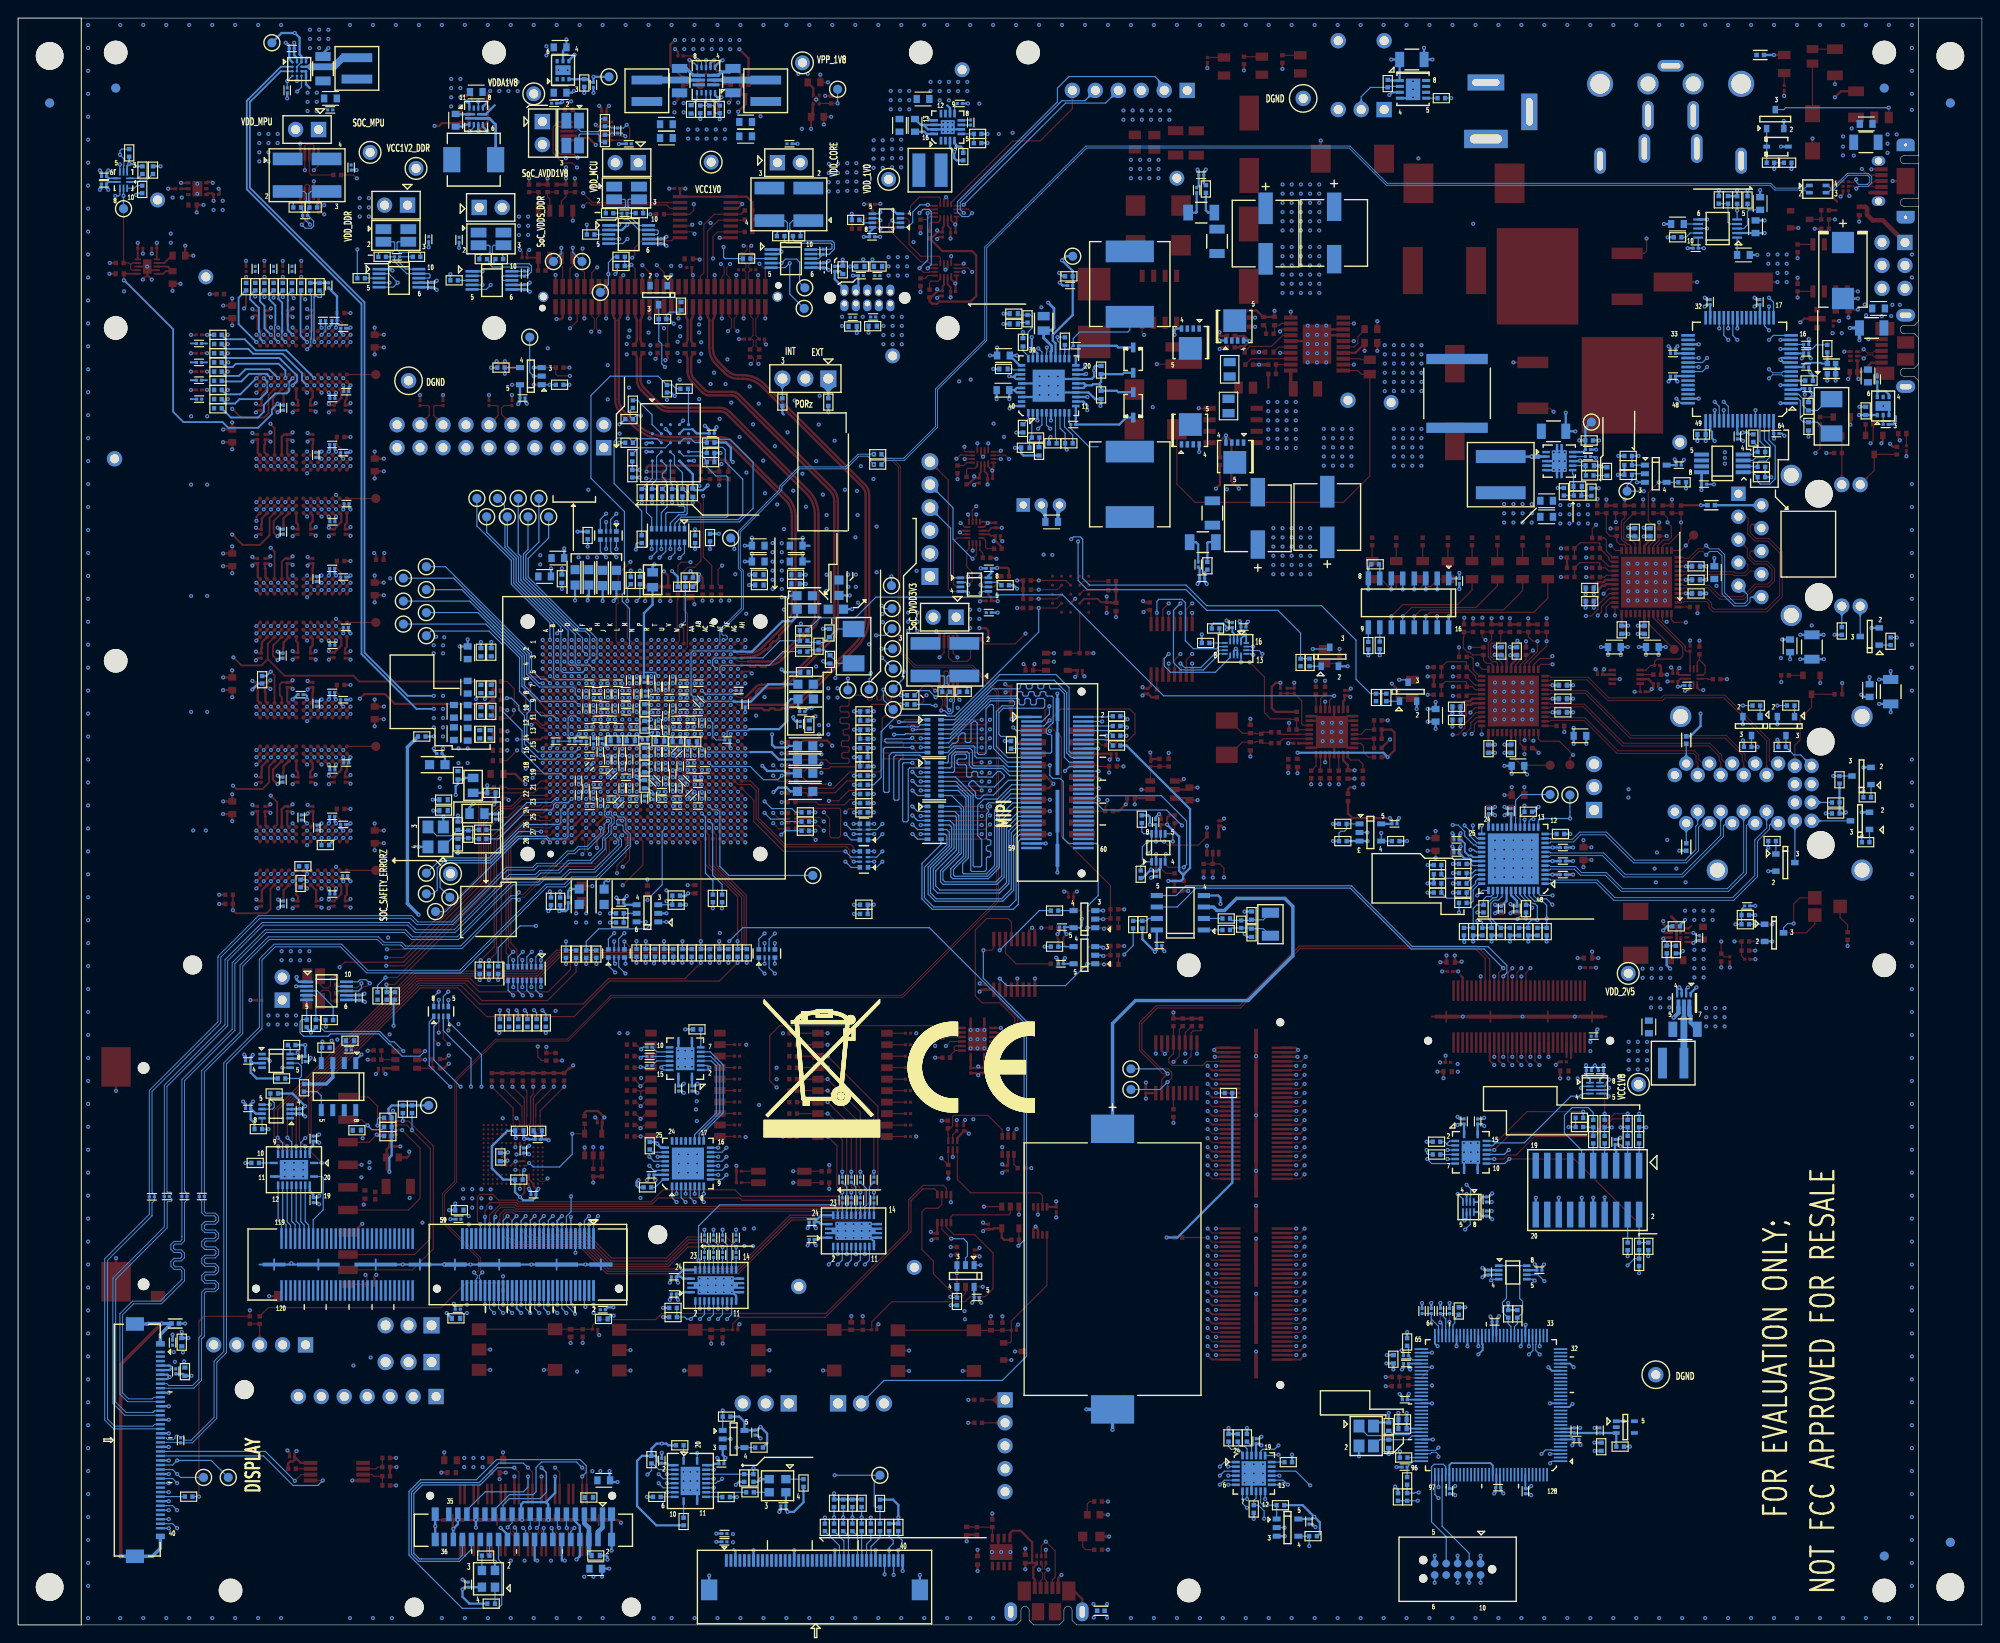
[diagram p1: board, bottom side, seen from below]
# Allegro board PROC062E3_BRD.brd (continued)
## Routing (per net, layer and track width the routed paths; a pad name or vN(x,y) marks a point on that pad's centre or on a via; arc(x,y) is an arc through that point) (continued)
SOC_WKUP_SCL: length 573.4
  TOP w0.132: v1(186.56,15.94) 185.87,16.63 U56.6 ; U34.AC7 v1(140.76,104.19) ; U7.14 145.06,156.74 145.44,157.13 153.75,157.13 153.98,157.35 154.29,157.35 v1(154.68,156.97) ; U46.14 v1(90.05,60.08) 89.6,60.53 89.6,61.15 89.98,61.53 90.74,61.53 92.9,63.7 92.9,66.55 91.19,68.26 81.98,68.26 75.39,74.85 56.06,74.85 54.93,73.73 J16.15 ; J5.33 v1(156.14,144.56)
  L03_SIG1 w0.084: v1(156.14,144.56) 154.88,145.82 154.88,150.82 153.87,151.84 153.87,156.15 v1(154.68,156.97)
  L05_SIG2 w0.084: v1(186.31,169.67) 185.48,170.5 173.47,170.5 169.8,166.83 162.31,166.83 160.66,165.18 160.66,160.72 157.43,157.49 155.21,157.49 v1(154.68,156.97) ; v1(90.05,60.08) 91.39,58.74 117.41,58.74 125.26,50.89 126.47,50.89 127.18,50.18 130.26,50.18 136.25,56.17 136.25,66.66 137.25,67.67 155.47,67.67 156.46,66.67 159.8,66.67 v1(161.14,68.01) 161.14,66.95 164.85,63.25 166.52,63.25 170.18,59.59 170.18,53.59 178.8,44.97 190.25,44.97 196.72,38.5 196.72,17.08 195.58,15.94 v1(186.56,15.94)
  L12_SIG4 w0.084: v1(161.14,68.01) 162.15,69.02 164.96,69.02 167.18,66.8 167.18,63.82 170.45,60.55 191.77,60.55 201.03,69.81 201.03,140.86 193.36,148.53 193.36,164.09 187.78,169.67 v1(186.31,169.67) ; v1(186.56,15.94) 180.15,22.35 170.82,22.35 169.15,24.02 169.15,31.01 165.1,35.05 165.1,35.4 164.69,35.81 155.06,35.81 v1(154.43,35.18) ; v1(156.14,144.56) 156.83,143.87 156.83,142.4 148.67,134.24 148.21,134.24 146.91,132.94 146.91,128.91 146.79,128.79 146.79,128.43 143.26,124.89 143.26,123.1 141.84,121.69 141.84,120.37 143.38,118.83 143.38,111.13 141.97,109.71 141.97,104.88 141.71,104.62 141.19,104.62 v1(140.76,104.19)
  BOTTOM w0.132: v1(186.56,15.94) 189.82,19.2 J38.23 ; v1(186.31,169.67) 185.83,170.15 U59.D3 ; v1(154.43,35.18) 154.54,35.28 J35.6 ; v1(161.14,68.01) 160.85,67.72 R584.2 ; v1(90.05,60.08) 90.89,59.25 TP71.1
SOC_WKUP_SDA: length 580.8
  TOP w0.132: J16.17 54.43,73.68 55.87,75.12 75.5,75.12 82.09,68.53 91.3,68.53 93.16,66.66 93.16,63.59 90.57,60.99 v1(90.05,60.99) 90.7,60.34 U46.15 ; v1(183.47,15.98) U56.5 ; v1(156.14,143.47) 155.34,144.27 J5.34 ; U7.15 153.64,157.39 v1(154.68,158.43) ; U34.AD6 v1(139.96,104.99)
  L03_SIG1 w0.084: v1(156.14,143.47) 156.14,143.98 154.57,145.55 154.57,150.64 153.56,151.66 153.56,157.31 v1(154.68,158.43)
  L05_SIG2 w0.084: v1(183.47,15.98) 184.88,14.57 195.29,14.57 197.1,16.38 197.1,38.55 190.38,45.27 178.88,45.27 170.48,53.67 170.48,59.71 166.65,63.55 164.97,63.55 162.05,66.47 v1(162.05,68.01) 161.65,68.41 160.97,68.41 160.73,68.18 160.73,68.07 159.68,67.02 156.55,67.02 155.6,67.97 137.12,67.97 136.12,66.97 135.94,66.79 135.94,56.29 130.13,50.48 127.3,50.48 126.59,51.19 125.39,51.19 117.53,59.05 91.99,59.05 v1(90.05,60.99) ; v1(186.33,170.84) 173.38,170.84 169.67,167.13 162.18,167.13 160.35,165.3 160.35,160.85 157.3,157.8 155.31,157.8 v1(154.68,158.43)
  L12_SIG4 w0.084: v1(186.33,170.84) 187.03,170.14 187.74,170.14 193.67,164.22 193.67,148.74 201.33,141.07 201.33,69.69 191.9,60.25 170.32,60.25 166.88,63.69 166.88,66.42 164.58,68.72 162.3,68.72 162.05,68.47 v1(162.05,68.01) ; v1(139.96,104.99) 139.96,105.06 140.36,105.47 140.36,109.15 141.61,110.39 141.61,112.33 141.08,112.86 141.08,118.04 141.37,118.33 141.37,123.92 146.32,128.88 146.32,133.02 148.01,134.71 148.21,134.71 148.47,134.71 156.14,142.38 v1(156.14,143.47) ; v1(183.47,15.98) 183.47,18.58 180.85,21.21 170.82,21.21 168.91,23.11 168.91,30.67 164.69,34.89 156.05,34.89 v1(155.58,34.42)
  BOTTOM w0.132: v1(155.58,34.42) 156.54,35.38 J35.14 ; U59.D2 v1(186.33,170.84) ; TP72.1 90.59,61.53 v1(90.05,60.99) ; R583.2 161.86,67.82 v1(162.05,68.01) ; J38.24 190.02,18.7 186.75,15.43 184.02,15.43 v1(183.47,15.98)
SOC_WKUP_UART0_CTS_3V3: length 40.6
  TOP w0.132: U23.5 110.61,115.86 v1(110.75,116) ; U34.AC2 v1(140.76,108.19)
  L05_SIG2 w0.084: v1(110.75,116) 109.98,115.24 109.98,109.98 111.12,108.84 118.81,108.84 119.89,109.92 126.56,109.92 127.54,108.93 135.01,108.93 136.14,107.8 140.36,107.8 v1(140.76,108.19)
SOC_WKUP_UART0_RTS_3V3: length 40.6
  TOP w0.132: U34.AC1 v1(140.76,108.99) ; U21.7 v1(111.61,118.88)
  L05_SIG2 w0.084: v1(140.76,108.99) 140.2,109.54 128.13,109.54 127.15,110.53 120.87,110.53 117.6,113.79 114.82,113.79 112.83,115.78 112.83,117.66 v1(111.61,118.88)
  L12_SIG4 w0.084: v1(111.61,118.88) 113.72,118.88 114.05,118.55 J11.2
SOC_WKUP_UART0_RX_3V3: length 38.4
  TOP w0.132: U34.AB1 v1(141.56,108.99)
  L05_SIG2 w0.084: v1(110.74,114.18) 110.39,113.82 110.39,110.08 111.12,109.35 118.89,109.35 119.76,110.22 126.76,110.22 127.75,109.24 135.51,109.24 136.14,108.6 141.16,108.6 v1(141.56,108.99)
  BOTTOM w0.132: v1(110.74,114.18) 110.56,114.36 U83.5
SOC_WKUP_UART0_TX_3V3: length 56
  TOP w0.132: v1(111.61,117.96) 111.21,118.36 U21.6 ; U34.AB5 v1(141.56,105.79)
  L05_SIG2 w0.084: v1(141.56,105.79) 141.16,105.4 137.23,105.4 136.72,105.92 135.7,105.92 134.15,107.47 111.74,107.47 109.6,109.61 109.6,116.45 111.12,117.96 v1(111.61,117.96)
  BOTTOM w0.132: J11.5 113.78,123.62 113.78,120.14 v1(111.61,117.96)
SPI0_RSTN: length 5.8
  TOP w0.132: U28.4 R153.1 U24.A4
SPI0_WP: length 3.4
  TOP w0.132: U24.C4 99.33,114.49 R127.1
SS: length 5.9
  TOP w0.132: C63.1 81.53,140.89 80.94,141.48 78.55,141.48 77.32,142.71 U14.7
SUPERVISOR_DEBOUNCE_RSTN: length 26.9
  TOP w0.132: Q7.2 107.49,31.21 107.33,31.37 C243.1 ; U54.1 103.39,37.58 107.33,33.64 C243.1 ; C243.1 R319.1 D11.1 SW8.1 SW8.2
SUPERVISOR_MR_RSTN: length 14.7
  TOP w0.132: U49.1 113.31,49.3 111.82,47.82 104.2,47.82 103.89,47.5 103.89,46.25
SYS_BOOTMODE0: length 23.3
  L05_SIG2 w0.084: v1(144.35,46.79) 144.35,46.33 143.13,45.11 135.02,45.11 132.41,42.5 128.27,42.5 127.21,41.44 126.94,41.44 v1(126.53,41.02)
  BOTTOM w0.132: U99.1 144.85,47.28 144.35,46.79 v1(144.35,46.79) ; U102.3 v1(126.53,41.02)
SYS_BOOTMODE1: length 25.6
  L05_SIG2 w0.084: v1(126.53,39.88) 126.53,39.96 128.12,41.54 131.89,41.54 135.15,44.81 143.25,44.81 144.8,46.36 144.8,47.25 v1(144.35,47.7)
  BOTTOM w0.132: v1(126.53,39.88) 126.03,40.38 U102.4 ; U99.2 v1(144.35,47.7)
SYS_BOOTMODE2: length 23.6
  L05_SIG2 w0.084: v1(143.35,46.79) 143.35,46.33 142.74,45.72 134.77,45.72 132.16,43.11 127.99,43.11 126.94,42.05 126.1,42.05 125.53,41.48 v1(125.53,41.02)
  BOTTOM w0.132: U102.5 v1(125.53,41.02) ; v1(143.35,46.79) 143.35,46.79 143.85,47.28 U99.3
SYS_BOOTMODE3: length 26.1
  L05_SIG2 w0.084: v1(143.35,47.7) 143.8,47.25 143.8,46.36 142.86,45.42 134.9,45.42 132.28,42.8 128.14,42.8 127.09,41.74 126.45,41.74 125.98,41.28 125.98,40.34 v1(125.53,39.88)
  BOTTOM w0.132: U102.6 125.03,40.38 v1(125.53,39.88) ; U99.4 v1(143.35,47.7)
SYS_BOOTMODE4: length 28.5
  L05_SIG2 w0.084: v1(142.35,46.79) 141.89,46.33 123.67,46.33 122.54,45.2 122.54,42.65 123.71,41.48 124.07,41.48 v1(124.53,41.02)
  BOTTOM w0.132: v1(142.35,46.79) 142.35,46.79 142.85,47.28 U99.5 ; U102.7 v1(124.53,41.02)
SYS_BOOTMODE5: length 26.1
  L05_SIG2 w0.084: v1(124.53,39.88) 124.98,40.34 124.98,41.51 125.83,42.35 126.81,42.35 127.87,43.41 132.03,43.41 134.65,46.03 142.23,46.03 142.8,46.6 142.8,47.25 v1(142.35,47.7)
  BOTTOM w0.132: U99.6 v1(142.35,47.7) ; v1(124.53,39.88) 124.03,40.38 U102.8
SYS_BOOTMODE6: length 27.4
  L05_SIG2 w0.084: v1(123.53,41.02) 122.24,42.31 122.24,45.35 123.67,46.79 v1(141.35,46.79)
  BOTTOM w0.132: U99.7 141.85,47.28 141.35,46.79 v1(141.35,46.79) ; U102.9 v1(123.53,41.02)
SYS_BOOTMODE7: length 29.6
  L05_SIG2 w0.084: v1(123.53,39.88) 121.93,41.47 121.93,45.44 121.98,45.52 123.55,47.09 140.74,47.09 v1(141.35,47.7)
  BOTTOM w0.132: U99.8 v1(141.35,47.7) ; v1(123.53,39.88) 123.03,40.38 U102.10
SYS_BOOTMODE8: length 29.7
  L12_SIG4 w0.084: v1(141.77,34.99) 143.07,36.29 143.07,38.57 142.3,39.33 141.95,39.69 135.38,39.69 134.42,40.65 134.42,49.33 134.89,49.8 v1(138.83,49.8)
  BOTTOM w0.132: U99.9 139.33,49.3 138.83,49.8 v1(138.83,49.8) ; U105.3 v1(141.77,34.99)
SYS_BOOTMODE9: length 33.1
  L12_SIG4 w0.084: v1(139.75,49.8) 139.29,50.26 134.81,50.26 134.11,49.57 134.11,40.52 135.25,39.38 141.82,39.38 142,39.2 142.76,38.44 142.76,36.65 141.31,35.2 141.31,34.3 v1(141.77,33.85)
  BOTTOM w0.132: U105.4 141.27,34.35 v1(141.77,33.85) ; U99.10 v1(139.75,49.8)
SYS_BOOTMODE10: length 31.3
  L12_SIG4 w0.084: v1(140.77,34.99) 141.06,35.28 141.06,35.39 142.25,36.59 142.25,38.52 141.69,39.08 135.13,39.08 133.81,40.4 133.81,49.69 135.32,51.21 137.9,51.21 138.3,50.8 v1(138.83,50.8)
  BOTTOM w0.132: U99.11 139.33,50.3 138.83,50.8 v1(138.83,50.8) ; U105.5 v1(140.77,34.99)
SYS_BOOTMODE11: length 30.4
  L12_SIG4 w0.084: v1(140.77,33.85) 140.31,34.3 140.31,35.34 139.54,36.11 137.67,36.11 133.5,40.27 133.5,49.82 135.19,51.51 138.23,51.51 138.48,51.26 139.29,51.26 v1(139.75,50.8)
  BOTTOM w0.132: U105.6 140.27,34.35 v1(140.77,33.85) ; U99.12 v1(139.75,50.8)
SYS_BOOTMODE12: length 28
  L12_SIG4 w0.084: v1(138.83,51.8) 135.06,51.8 133.2,49.95 133.2,40.14 137.54,35.8 139.41,35.8 139.77,35.45 v1(139.77,34.99)
  BOTTOM w0.132: U99.13 139.33,51.3 138.83,51.8 v1(138.83,51.8) ; U105.7 v1(139.77,34.99)
SYS_BOOTMODE13: length 31
  L12_SIG4 w0.084: v1(139.75,51.8) 139.29,52.26 135.08,52.26 132.89,50.07 132.89,40.02 137.41,35.5 138.91,35.5 139.31,35.09 139.31,34.3 v1(139.77,33.85)
  BOTTOM w0.132: U99.14 v1(139.75,51.8) ; v1(139.77,33.85) 139.27,34.35 U105.8
SYS_BOOTMODE14: length 28.7
  L12_SIG4 w0.084: v1(138.83,52.8) 135.19,52.8 132.59,50.2 132.59,39.89 137.49,34.99 v1(138.77,34.99)
  BOTTOM w0.132: U99.15 139.33,52.3 138.83,52.8 v1(138.83,52.8) ; U105.9 v1(138.77,34.99)
SYS_BOOTMODE15: length 31.4
  L12_SIG4 w0.084: v1(138.77,33.85) 138.16,33.85 132.28,39.73 132.28,50.32 135.22,53.26 139.29,53.26 v1(139.75,52.8)
  BOTTOM w0.132: U99.16 v1(139.75,52.8) ; v1(138.77,33.85) 138.27,34.35 U105.10
SYS_BOOTMODE16: length 11.2
  BOTTOM w0.132: U99.19 142.35,54.25 139.96,56.64 139.96,61.87 140.5,62.41 U95.4
SYS_BOOTMODE17: length 11.8
  BOTTOM w0.132: U95.5 140.57,62.91 139.57,61.91 139.57,56.65 141.85,54.37 U99.18
SYS_BOOTMODE18: length 12.4
  BOTTOM w0.132: U99.17 141.35,54.5 139.19,56.66 139.19,61.98 140.62,63.41 U95.6
TCA6424_EXP_INT: length 1.9
  BOTTOM w0.132: R630.1 146.72,48.41 145.83,49.3 U99.32
TCA9555_EXP_INT: length 1.8
  BOTTOM w0.132: U110.22 80.77,19.77 80.84,19.84 80.84,19.85 81.27,20.28 R661.1
TEMP_DIODE_P: length 22.3
  TOP w0.132: U34.W6 v1(143.96,104.99)
  L05_SIG2 w0.084: v1(143.96,104.99) 143.55,104.58 143.02,104.58 142.74,104.3 142.74,103.99 142.51,103.76 142.2,103.76 141.98,103.54 141.98,103.24 141.75,103 138.19,103 137.94,103.25 135.89,103.25 134.84,104.31 125.82,104.31 v1(125.41,104.71)
  BOTTOM w0.132: TP53.1 v1(125.41,104.71)
TEST_GPIO1: length 48.6
  TOP w0.132: U53.1 v1(110.36,46.29)
  L03_SIG1 w0.084: v1(124.9,11.89) 124.24,11.23 122.87,11.23 122.1,12 122.1,17.25 107.61,31.74 107.61,43.53 v1(110.36,46.29)
  BOTTOM w0.132: R692.1 v1(124.9,11.89) R683.1
TEST_GPIO2: length 37.5
  L03_SIG1 w0.084: v1(110.73,39.81) 108.83,37.9 108.83,30.95 123.89,15.89 v1(123.89,11.89)
  BOTTOM w0.132: U104.1 v1(110.73,39.81) ; R693.1 v1(123.89,11.89) R684.1
TEST_GPIO3: length 291
  TOP w0.132: v1(156.15,138.21) 157.52,138.21 157.71,138.41 R66.1 U17.1
  L03_SIG1 w0.084: v1(156.15,138.21) 154.58,139.78 154.58,141.03 154.57,141.03 154.57,142.97 153.32,144.23 153.32,149.35 152.04,150.64 152.04,156.31 150.32,158.03 129.22,158.03 127.99,156.79 121.65,156.79 121.33,157.12 119.96,157.12 118.81,155.97 118.81,153.68 v1(118.15,153.02)
  L12_SIG4 w0.084: v1(118.15,153.02) 116.95,153.02 110.36,146.43 110.36,136.11 105.92,131.66 105.92,129.21 100.71,124.01 100.71,121.92 101.73,120.9 101.73,114.52 104.06,112.19 104.06,86.02 102.81,84.76 84.2,84.76 80.56,81.11 80.56,72.56 68.15,60.15 68.15,16.96 72.74,12.37 91.61,12.37 92.07,12.82 121.94,12.82 v1(122.87,11.89)
  BOTTOM w0.132: R694.1 v1(122.87,11.89)
TEST_GPIO4: length 79.1
  L03_SIG1 w0.084: v1(147.36,51.8) 150.27,51.8 151.9,50.16 151.9,40.13 156.08,35.95 156.08,34.37 156.92,33.53 156.92,25.08 152.82,20.98 138.2,20.98 133.78,16.56 v1(126.87,16.56)
  BOTTOM w0.132: v1(147.36,51.8) 147.36,51.8 146.87,51.3 U99.28 ; v1(126.87,16.56) TP65.1 122.49,15.94 122.49,13.14 122.38,13.02 R685.1 R695.1
TEST_PORZN: length 33.4
  TOP w0.132: Q7.1 v1(107.33,29.31)
  L03_SIG1 w0.084: v1(107.33,29.31) 109.6,29.31 121.79,17.12 121.79,11.87 122.75,10.92 125.97,10.92 v1(126.94,11.89)
  BOTTOM w0.132: R690.1 v1(126.94,11.89) R681.1
TEST_POWERDOWN: length 254.6
  L12_SIG4 w0.084: v1(27.07,156.53) 27.07,153.84 32,148.91 32,129.79 31.63,129.42 31.63,120.65 32.13,120.14 32.13,109.64 36,105.76 36,86.93 26.29,77.22 26.29,16.57 31.64,11.23 127.29,11.23 v1(127.95,11.89)
  BOTTOM w0.132: R689.1 v1(127.95,11.89) ; R352.2 v1(27.07,156.53) U66.5
TEST_WARMRESETN: length 35.8
  TOP w0.132: U55.1 v1(110.49,37.41)
  L03_SIG1 w0.084: v1(110.49,37.41) 109.13,36.05 109.13,31.08 125.92,14.29 v1(125.92,11.89)
  BOTTOM w0.132: R682.1 v1(125.92,11.89) R691.1
TG: length 5.8
  TOP w0.132: R4.1 142.46,173.61 v1(142.01,173.16) 142.01,171.49 141.73,171.21 TP3.1
  BOTTOM w0.132: U61.7 141.6,172.94 141.82,173.17 142.01,173.17 v1(142.01,173.16)
TIMER_IO0: length 97.7
  TOP w0.132: U34.B22 158.36,91.39 161.44,91.39 162.51,90.32 163.95,90.32 165.43,88.83 165.43,81.97 174.46,72.94 v1(176.47,72.94)
  L03_SIG1 w0.084: J19.1 172.8,23.41 184.2,23.41 184.91,24.13 184.91,26.8 182.56,29.15 182.56,62.61 177.6,67.58 177.6,71.81 v1(176.47,72.94)
TIMER_IO1: length 76
  TOP w0.132: U34.C23 v1(157.56,90.59)
  L03_SIG1 w0.084: J19.2 175.37,27.16 175.37,31.47 175.32,31.51 175.32,40.96 170.07,46.21 170.07,60.35 167.35,63.08 167.35,84.1 160.86,90.59 v1(157.56,90.59)
TIMER_IO2: length 47.2
  TOP w0.132: RA6.1 v1(169.59,65.79)
  L03_SIG1 w0.084: J19.3 176.02,25.27 178.55,27.8 178.55,33.03 177.93,33.66 177.93,39.65 170.68,46.9 170.68,62.49 169.1,64.07 169.1,65.3 v1(169.59,65.79)
TIMER_IO3: length 46.6
  TOP w0.132: RA6.2 170.15,64.86 v1(169.55,64.26)
  L03_SIG1 w0.084: v1(169.55,64.26) 170.99,62.82 170.99,47.02 178.18,39.83 178.18,34.42 179.2,33.4 179.2,27.05 178.56,26.42 J19.4
TIMER_IO6: length 46.8
  TOP w0.132: RA6.3 v1(170.65,65.53)
  L03_SIG1 w0.084: v1(170.65,65.53) 170.19,65.07 170.19,64.13 171.29,63.02 171.29,47.15 181.1,37.34 J19.5
TIMER_IO7: length 47.6
  TOP w0.132: v1(170.69,64.26) 171.2,64.78 RA6.4
  L03_SIG1 w0.084: v1(170.69,64.26) 171.6,63.35 171.6,47.28 181.86,37.01 181.86,27.05 J19.6
TM4C129_RSTN: length 28.6
  TOP w0.132: R323.2 v1(60.81,26.5)
  L03_SIG1 w0.084: v1(55.44,4.66) 56.39,5.61 56.39,14.25 62.04,19.9 62.04,25.28 v1(60.81,26.5)
  BOTTOM w0.132: J40.10 v1(55.44,4.66)
TM4C129_TCK: length 14.1
  BOTTOM w0.132: J40.4 59.25,9.78 60.86,11.4 60.86,17.48 60.56,17.78 59.57,17.78 59.29,17.51 U106.100
TM4C129_TDI: length 13.7
  L03_SIG1 w0.084: v1(57.98,4.66) 59.25,5.93 59.25,14.39 v1(60.09,15.24)
  BOTTOM w0.132: J40.8 v1(57.98,4.66) ; U106.98 v1(60.09,15.24)
TM4C129_TDO: length 13.2
  L03_SIG1 w0.084: v1(60.52,4.66) 60.09,5.08 v1(60.09,14.03)
  BOTTOM w0.132: U106.97 60.49,14.43 v1(60.09,14.03) ; J40.6 v1(60.52,4.66)
TM4C129_TMS: length 11.1
  BOTTOM w0.132: J40.2 56.71,7.94 59.69,10.92 U106.99
TMP1_ADD0: length 2.4
  BOTTOM w0.132: U89.5 R544.2 R547.2
TMP1_ADD1: length 2.6
  BOTTOM w0.132: U89.3 R539.2 R526.2
TMP2_ADD0: length 2.6
  TOP w0.132: R247.1 R256.2 U44.5
TMP2_ADD1: length 2.7
  TOP w0.132: R255.2 R261.2 U44.3
USB0_ATEST: length 22.8
  TOP w0.132: U34.AD10 v1(139.96,101.79)
  L05_SIG2 w0.084: v1(121.48,103.5) 122.87,102.11 137.41,102.11 138.14,101.38 139.55,101.38 v1(139.96,101.79)
  BOTTOM w0.132: v1(121.48,103.5) 121.48,102.36 TP54.1
USB0_DM: length 45.5
  TOP w0.104: U34.AE2 v1(139.16,108.19) ; J5.36 153.74,144.84 153.44,144.54 153.44,143.45 v1(153.8,143.1)
  L12_SIG4 w0.089: v1(139.16,108.19) 138.73,108.62 138.73,109.06 138.76,109.08 138.76,111.6 138.05,112.31 138.05,114.78 138.72,115.46 138.72,117.74 140.45,119.47 140.45,128.72 153.57,141.84 153.57,142.87 v1(153.8,143.1)
USB0_DP: length 45.4
  TOP w0.104: U34.AF1 v1(138.36,108.99) ; v1(152.88,143.1) 153.23,143.44 153.23,144.55 152.94,144.84 J5.37
  L12_SIG4 w0.089: v1(152.88,143.1) 152.88,143.29 153,143.41 153.25,143.41 153.35,143.31 153.35,141.93 140.23,128.81 140.23,119.56 138.51,117.83 138.51,115.55 137.83,114.87 137.83,112.22 138.54,111.51 138.54,109.17 v1(138.36,108.99)
USB0_DRV_VBUS: length 64.2
  TOP w0.132: J5.5 154.54,149.66 154.75,149.87 v1(154.75,152.3) ; U34.AD9 v1(139.96,102.59)
  L12_SIG4 w0.084: v1(139.96,102.59) 139.96,102.87 139.59,103.24 139.59,103.24 139.53,103.3 139.53,104.28 139.86,104.62 140.91,104.62 141.13,104.84 141.13,109.38 142.01,110.26 142.01,113.9 141.35,114.55 141.35,117.86 141.61,118.11 141.61,123.83 146.56,128.78 146.56,132.92 148.11,134.48 148.57,134.48 156.59,142.49 156.59,143.76 156.34,144.02 155.96,144.02 154.75,145.22 v1(154.75,152.3)
USB0_ID_SOC: length 60.2
  TOP w0.132: v1(148.14,150.46) 147.34,149.66 J5.14 ; U34.AF7 v1(138.36,104.19)
  L12_SIG4 w0.084: v1(148.14,150.46) 149.23,149.37 149.23,149.1 154.56,143.76 154.56,141.18 148.33,134.95 147.92,134.95 146.09,133.12 146.09,128.97 141.13,124.02 141.13,118.53 140.84,118.24 140.84,112.65 141.35,112.14 141.35,110.49 140.46,109.6 139.95,109.6 139.56,109.21 139.56,104.77 139.38,104.58 138.75,104.58 v1(138.36,104.19)
USB0_PCIE0_SGMII0_RXN0: length 55
  TOP w0.132: 136.47,107.1 136.49,107.12 136.85,107.12 136.85,107.12 arc(137.01,107.09) U34.AH3
  TOP w0.267: J5.40 150.54,144.96 arc(150.56,144.79) 150.63,144.62 arc(150.71,144.5) 150.74,144.35 150.74,135.64 arc(150.6,134.9) 150.18,134.28 148.92,133.02 arc(147.16,131.84) 145.09,131.43 139.5,131.43 arc(138.78,131.29) 138.18,130.89 132.07,124.78 arc(131.43,123.82) 131.2,122.69 131.2,112.47 arc(131.43,111.36) 132.06,110.42 132.99,109.48 132.99,109.22 133.38,108.84 133.63,108.84 133.99,108.49 133.99,108.25 134.29,107.95 134.52,107.95 134.6,107.87 arc(135.45,107.3) 136.47,107.1
USB0_PCIE0_SGMII0_RXP0: length 55.1
  TOP w0.132: U34.AG2 137.62,107.46 arc(137.55,107.41) 137.47,107.39 136.75,107.39 136.65,107.49 136.49,107.49
  TOP w0.267: 136.49,107.49 136.47,107.49 arc(135.61,107.66) 134.87,108.15 132.33,110.69 arc(131.79,111.51) 131.6,112.47 131.6,122.69 arc(131.79,123.67) 132.35,124.5 138.46,130.61 arc(138.93,130.93) 139.5,131.04 145.09,131.04 arc(147.31,131.48) 149.2,132.74 150.46,134 arc(150.96,134.75) 151.14,135.64 151.14,144.35 arc(151.16,144.5) 151.25,144.62 arc(151.32,144.79) 151.34,144.96 J5.39
USB0_PCIE0_SGMII0_TXN0: length 4.3
  TOP w0.267: J5.43 148.14,144.96 arc(148.16,144.79) 148.23,144.62 arc(148.31,144.5) 148.34,144.35 148.34,142.3 arc(148.27,141.95) C60.2
USB0_PCIE0_SGMII0_TXN0_C: length 52.3
  TOP w0.132: 136.49,106.21 137.14,106.21 U34.AH4
  TOP w0.267: 136.49,106.21 136.33,106.21 136.17,106.05 135.71,106.05 135.55,106.21 135.19,106.21 135,106.02 134.52,106.02 134.33,106.21 134.18,106.21 arc(133.38,106.37) 132.7,106.82 129.12,110.4 arc(128.78,110.91) 128.66,111.51 128.66,122.86 arc(128.95,124.3) 129.77,125.53 138.49,134.24 arc(138.97,134.57) 139.55,134.68 145.29,134.68 arc(145.72,134.77) 146.09,135.01 147.95,136.87 arc(148.24,137.31) 148.34,137.82 148.34,140.07 arc(148.27,140.42) C60.1
USB0_PCIE0_SGMII0_TXP0: length 4.3
  TOP w0.267: J5.42 148.94,144.96 arc(148.92,144.79) 148.85,144.62 arc(148.76,144.5) 148.74,144.35 148.74,142.3 arc(148.81,141.95) C61.2
USB0_PCIE0_SGMII0_TXP0_C: length 52.3
  TOP w0.132: U34.AG3 137.75,106.78 arc(137.53,106.64) 137.28,106.59 136.5,106.59 136.49,106.6
  TOP w0.267: 136.49,106.6 134.18,106.6 arc(133.53,106.73) 132.98,107.1 129.4,110.68 arc(129.15,111.06) 129.06,111.51 129.06,122.86 arc(129.31,124.15) 130.05,125.25 138.77,133.97 arc(139.13,134.21) 139.55,134.29 145.29,134.29 arc(145.88,134.41) 146.37,134.73 148.23,136.59 arc(148.6,137.16) 148.74,137.82 148.74,140.07 arc(148.81,140.42) C61.1
USB0_RESREF: length 19.6
  TOP w0.132: U34.AC9 v1(140.76,102.59)
  L10_SIG3 w0.084: v1(140.76,102.59) 140.36,102.2 136.96,102.2 136.14,101.38 131.54,101.38 129.17,99.01 126.71,99.01 v1(124.73,97.03)
  BOTTOM w0.132: R483.1 v1(124.73,97.03)
USB0_VBUS: length 5.3
  TOP w0.132: v1(144.66,143.98) 144.94,144.26 J5.47
  BOTTOM w0.132: C691.1 144.07,145.26 145.11,145.26 145.48,144.9 R380.1 145.18,144.5 v1(144.66,143.98)
USB0_VBUS_SOC: length 18
  TOP w0.132: U34.AE7 v1(139.16,104.19)
  L10_SIG3 w0.084: v1(139.16,104.19) 138.75,103.78 137.35,103.78 135.8,102.23 129.41,102.23 128.27,101.09 v1(124.73,101.09)
  BOTTOM w0.132: v1(124.73,101.09) R469.2 R471.1
USB1_AB_DM: length 12.6
  TOP w0.104: J3.2 12.02,159.12 12.1,159.19 13.63,159.19 v1(13.89,158.93) 14.19,159.23 14.45,159.23 14.49,159.19 U4.2
  BOTTOM w0.104: FL8.4 17.05,159.28 16.76,158.98 16.5,158.98 14.87,160.62 12.57,160.62 12.19,160.24 12.19,159.56 12.57,159.18 13.64,159.18 v1(13.89,158.93)
USB1_AB_DP: length 12.6
  TOP w0.104: J3.3 11.86,159.77 12.22,159.41 13.61,159.41 13.89,159.69 v1(13.89,159.95) 14.24,159.6 14.41,159.6 14.5,159.69 U4.1
  BOTTOM w0.104: v1(13.89,159.95) 13.89,159.64 13.65,159.4 12.66,159.4 12.41,159.65 12.41,160.15 12.66,160.4 14.78,160.4 16.41,158.77 16.76,158.77 17.05,158.48 FL8.3
USB1_AB_ID: length 214.7
  TOP w0.132: U34.AF5 v1(138.36,105.79) ; v1(14.66,158.12) 14.76,158.22 U4.3 ; v1(13.27,161.1) 12.59,160.42 J3.4
  L05_SIG2 w0.084: v1(141.73,155.13) 141.33,154.72 140.42,154.72 137.43,157.71 120.48,157.71 114.98,152.21 111.57,152.21 110.87,151.51 77.91,151.51 77.57,151.85 26.64,151.85 26.1,152.4 17.34,152.4 15.24,154.5 15.24,157.53 v1(14.66,158.12) 14.66,160.1 13.65,161.1 v1(13.27,161.1)
  L12_SIG4 w0.084: v1(138.36,105.79) 138.75,106.18 138.75,107.55 138.52,107.78 138.21,107.78 137.96,108.03 137.96,108.03 137.95,108.05 137.95,109.58 137.45,110.07 137.45,117.27 138.77,118.59 138.77,129.56 142.32,133.11 142.32,148.77 141.34,149.75 141.34,154.73 v1(141.73,155.13) ; v1(13.27,161.1) 13.75,161.1 15.19,159.67 15.19,151.33 12.83,148.97 9.59,148.97 J4.5
USB1_CM_DM: length 127.6
  BOTTOM w0.104: FL8.1 19.29,159.28 19.58,158.98 22.82,158.98 23.34,159.51 65.76,159.51 69.89,163.64 99.09,163.64 110.27,152.45 110.27,142.2 115.71,136.77 115.71,132.61 119.24,129.08 121.23,129.08 R397.2
USB1_CM_DP: length 127.6
  BOTTOM w0.104: FL8.2 19.29,158.48 19.58,158.77 22.9,158.77 23.43,159.3 65.85,159.3 69.98,163.42 99,163.42 110.06,152.36 110.06,142.11 115.49,136.68 115.49,132.52 119.15,128.87 121.22,128.87 R400.2
USB1_DM: length 33.4
  TOP w0.104: U34.AD2 v1(139.96,108.19)
  BOTTOM w0.104: v1(139.96,108.19) 139.56,108.59 139.56,110.12 137.19,112.5 137.19,116.57 137.52,116.9 137.52,121.01 132.93,125.66 132.93,126.04 130.82,128.14 125.67,128.14 124.27,129.54 v1(122.53,129.54)
USB1_DP: length 33.4
  TOP w0.104: U34.AE1 v1(139.16,108.99)
  BOTTOM w0.104: v1(122.53,128.4) 122.89,128.75 122.89,128.99 123.22,129.32 124.18,129.32 125.58,127.93 130.73,127.93 132.72,125.95 132.72,125.57 137.3,120.92 137.3,116.99 136.97,116.66 136.97,112.41 139.34,110.03 139.34,109.64 139.22,109.51 138.9,109.51 138.75,109.36 138.75,109.12 138.87,108.99 v1(139.16,108.99)
USB1_DRV_VBUS: length 20.1
  TOP w0.132: U34.AC8 v1(140.76,103.39)
  L10_SIG3 w0.084: v1(124.73,99.06) 125.77,100.1 129.55,100.1 131.31,101.85 136.07,101.85 137.21,103 140.36,103 v1(140.76,103.39)
  BOTTOM w0.132: R477.1 R474.2 v1(124.73,99.06)
USB1_DRVBUS: length 148.1
  TOP w0.132: v1(20.38,146.88) R50.1 U11.4
  L03_SIG1 w0.084: v1(122.54,98.04) 118.3,102.29 118.3,118.87 117.45,119.72 115.16,119.72 114.11,120.78 114.11,122.43 110.73,125.8 110.73,127.38 110.87,127.52 110.87,129.96 110.56,130.27 110.38,130.45 110.38,131.59 111.82,133.03 v1(111.82,137.79)
  L10_SIG3 w0.084: v1(111.82,137.79) 111.82,141.54 111.38,141.99 95.25,141.99 89.34,147.89 21.4,147.89 v1(20.38,146.88)
  BOTTOM w0.132: R477.2 v1(122.54,98.04)
USB1_HDMI_GPMC_DM: length 152.8
  TOP w0.104: R74.1 121.23,129.08 120.47,129.08 119.61,128.22 119.61,107.85 117.94,106.18 111.62,106.18 108.74,103.3 108.74,80.06 119.35,69.44 151.5,69.44 156.34,64.6 164.29,64.6 165.51,63.39 168.67,60.22 168.67,49 170.02,47.65 170.02,44.61 166.01,40.6 166.01,39.19 v1(165.83,39.01)
  BOTTOM w0.104: J35.52 166.04,38.21 166.17,38.34 166.17,38.67 v1(165.83,39.01)
USB1_HDMI_GPMC_DP: length 152.8
  TOP w0.104: v1(166.74,39.01) 166.45,39.01 166.23,39.23 166.23,40.51 170.23,44.52 170.23,47.74 168.88,49.09 168.88,60.31 165.6,63.6 164.38,64.82 156.43,64.82 151.59,69.66 119.44,69.66 108.95,80.15 108.95,103.21 111.71,105.97 118.03,105.97 119.82,107.76 119.82,128.13 120.56,128.87 121.22,128.87 R76.1
  BOTTOM w0.104: J35.54 166.54,38.25 166.38,38.4 166.38,38.65 v1(166.74,39.01)
USB1_HDMI_GPMC_DRVBUS: length 132.6
  L03_SIG1 w0.084: v1(122.54,99.06) 122.95,98.65 122.95,96.43 122.73,96.22 117.17,96.22 113.18,92.23 113.18,60.84 110.42,58.07 110.42,47.43 111.74,46.11 111.74,36.86 112.1,36.49 112.1,34.17 v1(112.46,33.82)
  L10_SIG3 w0.084: v1(112.46,33.82) 114.4,31.88 151.19,31.88 152.35,33.03 163.63,33.03 164.94,34.35 164.94,34.84 v1(165.54,35.43)
  BOTTOM w0.132: J35.50 v1(165.54,35.43) ; R474.1 v1(122.54,99.06)
USB1_SHIELD: length 1.4
  TOP w0.254: J3.10 v1(9.87,159.77)
  vias: v1(9.42,164.92) v1(10.44,164.92) v1(10.44,163.91) v1(10.44,162.89)
USB1_VBUS: length 14
  TOP w0.203: 11.15,158.47 11.26,158.58 12.3,158.58 12.41,158.47
  TOP w0.254: 16.08,156.54 R25.1 ; 16.03,157.51 16.54,158.01 16.54,159.33 16.18,159.69 U4.6
  TOP w0.356: 12.41,158.47 J3.1
  TOP w0.508: J4.1 10.96,155.42 12.09,155.42 12.7,156.03 12.7,156.74 12.87,156.91 C19.1
UVLO_REF: length 2.7
  TOP w0.132: R68.2 R64.1 78.05,139.46 U14.2
VMAIN: length 166.9
  TOP w0.254: Q2.3 v1(51.81,139.7) ; R68.1 78.91,136.93 ; U35.5 87.86,92.43 C179.1 v1(86.74,92.66) ; R200.1 v1(89.93,96.49) ; R9.1 v1(21.87,169.19) ; U14.4 v1(77.61,140.76)
  TOP w0.381: C69.1 76.43,137.06 U14.1
  L03_SIG1 w0.254: v1(61.98,141.6) 60.07,139.7 v1(51.81,139.7) 48.59,139.7 v1(34.75,153.54)
  L05_SIG2 w0.254: v1(78.93,135.32) 80.26,136.65 98.93,136.65 101.6,139.32 105.57,139.32 v1(106.72,140.46) ; v1(106.72,140.46) 106.72,145 105.41,146.3 v1(103.25,146.3) ; v1(106.72,140.46) 108.33,138.85 108.33,135.41 v1(107.52,134.6)
  L10_SIG3 w0.254: v1(34.75,153.54) 33.97,154.32 33.97,157.08 v1(21.87,169.19)
  L12_SIG4 w0.254: v1(78.93,130.24) 78.93,110.68 89.93,99.68 v1(89.93,96.49) 86.74,93.3 v1(86.74,92.66)
  BOTTOM w0.254: U75.31 106.41,139.37 C323.1 v1(106.72,140.46) ; v1(107.52,134.6) 107.25,134.87 U75.40 ; R359.1 v1(34.75,153.54)
  BOTTOM w0.305: v1(103.25,146.3) 102.62,145.67 102.62,143.51 102.87,143.26 103.72,143.26 C340.1 103.76,142.42 102.87,141.53 102.87,140.98 102.95,140.9 U75.25
  vias: v1(61.98,140.59) v1(61.98,139.57) v1(61.98,138.56) v1(61.98,137.54) v1(61.98,136.53) v1(62.99,141.6) v1(62.99,140.59) v1(62.99,139.57) v1(62.99,138.56) v1(62.99,137.54) v1(62.99,136.53) v1(64.01,141.6) v1(64.01,140.59) v1(64.01,139.57) v1(64.01,138.56) v1(64.01,137.54) v1(64.01,136.53) v1(65.02,141.6) v1(65.02,140.59) v1(65.02,139.57) v1(65.02,138.56) v1(65.02,137.54) v1(65.02,136.53) v1(66.03,140.59) v1(66.04,141.6) v1(66.04,139.57) v1(66.04,138.56) v1(66.04,137.54) v1(66.04,136.53) v1(75.88,135.32) v1(75.88,134.3) v1(75.88,133.29) v1(75.88,132.27) v1(75.88,131.25) v1(75.88,130.24) v1(76.9,135.32) v1(76.9,134.3) v1(76.9,133.29) v1(76.9,132.27) v1(76.9,131.25) v1(76.9,130.24) v1(77.91,135.32) v1(77.91,134.3) v1(77.91,133.29) v1(77.91,132.27) v1(77.91,131.25) v1(77.91,130.24) v1(78.93,134.3) v1(78.93,133.29) v1(78.93,132.27) v1(78.93,131.25)
VOUT1_DATA20: length 73.4
  TOP w0.132: U34.T28 v1(146.36,86.59)
  L03_SIG1 w0.084: v1(136.86,41.92) 136.37,42.41 136.37,45.5 141.41,50.55 141.41,52.44 146.5,57.53 146.5,65.51 145.16,66.85 145.16,75.66 146.36,76.86 v1(146.36,86.59)
  L10_SIG3 w0.084: v1(136.86,41.92) 136.86,41.34 138.24,39.95 150.67,39.95 v1(155.04,44.32)
  BOTTOM w0.132: v1(155.04,44.32) J35.7
VOUT1_DATA21: length 34.8
  TOP w0.132: RA6.8 v1(169.59,69.16) ; U34.P23 v1(148.76,90.59)
  L05_SIG2 w0.084: v1(148.76,90.59) 149.16,90.18 150.52,90.18 150.76,89.94 150.76,89.25 151.56,88.45 151.56,86.62 156.82,81.37 156.82,80.1 159.17,77.75 162.49,77.75 168.98,71.25 168.98,69.77 v1(169.59,69.16)
  BOTTOM w0.132: RA6.8 v1(169.59,69.16)
VOUT1_DATA21_TEST_HDR: length 37.4
  L12_SIG4 w0.084: v1(154.04,45.24) 154.04,50.8 158.48,55.24 164.21,55.24 167.54,58.57 167.54,59.74 167.27,60.01 166.38,60.01 v1(165.93,59.55)
  BOTTOM w0.132: v1(154.04,45.24) 154.54,44.74 J35.5 ; v1(165.93,59.55) 165.93,63.1 169.59,66.77 RA17.4
VOUT1_DATA22: length 55.4
  TOP w0.132: U34.R26 v1(147.16,88.19)
  L03_SIG1 w0.084: v1(147.16,88.19) 146.76,88.58 146.76,89.15 146.99,89.38 147.55,89.38 148.35,90.18 148.92,90.18 149.16,89.93 149.16,89.63 149.39,89.4 150.89,89.4 152.74,87.54 152.74,84.8 154.93,82.62 154.93,45.21 v1(154.04,44.32)
  BOTTOM w0.132: J35.3 v1(154.04,44.32)
VOUT1_DATA23: length 40.1
  TOP w0.132: RA6.7 170.15,69.52 v1(169.59,70.08) ; U34.R23 v1(147.16,90.59)
  L05_SIG2 w0.084: v1(147.16,90.59) 147.55,90.59 147.93,90.98 147.93,91.37 148.35,91.78 150.52,91.78 150.75,91.55 150.75,91.25 150.99,91 151.3,91 151.55,90.75 151.55,90.43 151.79,90.18 152.12,90.18 152.35,89.95 152.35,89.61 153.36,88.6 154.57,88.6 154.83,88.33 154.83,86.25 155.45,85.63 155.45,84.53 157.89,82.09 157.89,80.97 160.51,78.35 162.32,78.35 169.59,71.08 v1(169.59,70.08)
  BOTTOM w0.132: RA6.7 170.15,69.52 v1(169.59,70.08)
VOUT1_DATA23_TEST_HDR: length 35.2
  L12_SIG4 w0.084: v1(153.04,45.24) 153.04,50.23 158.36,55.55 164.08,55.55 167.08,58.55 v1(167.08,59.55)
  BOTTOM w0.132: RA17.3 170.15,65.75 167.08,62.69 v1(167.08,59.55) ; v1(153.04,45.24) 153.54,44.74 J35.1
VOUT1_DE: length 45.4
  TOP w0.132: RA6.5 171.2,69.52 v1(170.65,70.08) ; U34.T23 v1(146.36,90.59)
  L05_SIG2 w0.084: v1(146.36,90.59) 146.36,90.84 146.75,91.23 146.75,93.2 146.93,93.38 152.12,93.38 152.35,93.15 152.35,91.16 152.51,91 152.95,91 153.15,90.8 153.15,90.75 153.15,90.75 153.15,90.33 153.28,90.2 155.3,90.2 155.55,89.95 155.55,86.41 156.06,85.9 156.06,84.78 161.88,78.96 162.58,78.96 170.65,70.88 v1(170.65,70.08)
  BOTTOM w0.132: v1(170.65,70.08) 171.2,69.52 RA6.5
VOUT1_DE_TEST_HDR: length 40.8
  L03_SIG1 w0.084: v1(159.54,34.52) 160.08,35.06 160.08,35.94 163.51,39.37 163.51,48.13 169.37,53.99 v1(169.37,59.55)
  BOTTOM w0.132: v1(159.54,34.52) 160.04,35.02 J35.28 ; v1(169.37,59.55) 171.7,61.88 171.7,66.72 171.2,67.22 RA17.1
VOUT1_HSYNC: length 42.3
  TOP w0.132: U34.T24 v1(146.36,89.79) ; RA6.6 v1(170.65,69.16)
  L05_SIG2 w0.084: v1(146.36,89.79) 146.76,90.2 146.76,90.75 147.01,91 147.32,91 147.57,91.25 147.57,92.33 147.83,92.58 151.35,92.58 151.56,92.37 151.56,91.24 151.81,90.98 152.12,90.98 152.35,90.75 152.35,90.27 152.43,90.18 152.92,90.18 153.15,89.95 153.15,89.65 153.39,89.4 154.91,89.4 155.24,89.07 155.24,86.26 155.75,85.75 155.75,84.65 161.76,78.65 162.45,78.65 170.24,70.86 170.24,69.57 v1(170.65,69.16)
  BOTTOM w0.132: RA6.6 v1(170.65,69.16)
VOUT1_HSYNC_TEST_HDR: length 38.5
  L03_SIG1 w0.084: v1(168.23,59.55) 168.23,53.28 162.58,47.63 162.58,39.2 159.54,36.16 v1(159.54,35.43)
  BOTTOM w0.132: J35.26 v1(159.54,35.43) ; RA17.2 170.65,66.77 171.2,66.22 171.2,62.52 v1(168.23,59.55)
VOUT1_PCLK: length 101.4
  TOP w0.132: U34.R24 v1(147.16,89.79)
  L03_SIG1 w0.084: v1(136.86,43.83) 138.17,42.52 138.17,41.67 137.6,41.1 135.71,41.1 134.38,42.43 134.38,50.52 134.38,50.95 137.74,54.32 141.57,54.32 144.68,57.42 144.68,65.61 142.18,68.11 142.18,82.11 144.97,84.9 144.97,86.17 145.16,86.36 145.16,89.95 145.39,90.18 146.76,90.18 v1(147.16,89.79)
  L10_SIG3 w0.084: v1(136.86,43.83) 136.05,44.64 134.81,44.64 134.11,43.94 134.11,41.27 136.65,38.73 153.32,38.73 v1(157.54,34.52)
  BOTTOM w0.132: J35.20 158.04,35.02 v1(157.54,34.52)
VOUT1_VSYNC: length 85.9
  TOP w0.132: U34.T25 v1(146.36,88.99)
  L03_SIG1 w0.084: v1(135.8,43.88) 135.8,51.16 138.02,53.38 141.92,53.38 145.59,57.04 145.59,65.99 144.11,67.47 144.11,75.04 145.96,76.89 145.96,88.59 v1(146.36,88.99)
  L10_SIG3 w0.084: v1(135.8,43.88) 134.94,43.01 134.94,41.31 136.9,39.34 153.57,39.34 153.93,38.99 154.56,38.99 157.94,35.6 157.94,35.11 v1(158.54,34.52)
  BOTTOM w0.132: v1(158.54,34.52) 159.04,35.02 J35.24
VOUT_D0_BOOTMODE0: length 120.2
  TOP w0.132: U34.M27 149.55,87.39 149.55,84.64 v1(150.3,83.88) ; v1(166.04,44.32) 166.38,44.66 166.38,47.38 166.12,47.64 164.67,47.64 164.04,47.01 161.97,47.01 161.79,46.82 147.17,46.82 145.84,48.15 137.9,48.15 137.18,47.43 126.46,47.43 v1(126.03,47.87) 126.62,48.46 126.62,53.02 v1(127.64,54.04) SW3.1 R297.1
  L05_SIG2 w0.084: v1(127.64,54.04) 128.89,55.3 128.89,61.42 127.94,62.37 127.62,62.37 126.64,63.35 126.64,65.62 131.43,70.41 152.26,70.41 154.93,73.08 154.93,81.1 152.15,83.88 v1(150.3,83.88)
  BOTTOM w0.132: J35.51 v1(166.04,44.32) ; R631.1 v1(126.03,47.87)
VOUT_D1_BOOTMODE1: length 121.5
  TOP w0.132: R293.1 SW3.2 v1(127.65,55.31) 126.03,53.69 v1(126.03,50.15) 126.03,48.5 125.54,48.01 125.54,47.5 126.05,46.99 137.11,46.99 137.37,47.24 146.37,47.24 147.06,46.56 161.9,46.56 162.08,46.74 164.98,46.74 165.35,46.37 165.35,45.97 165.54,45.79 v1(165.54,45.15) ; U34.M23 v1(150.36,90.59)
  L05_SIG2 w0.084: v1(127.65,55.31) 125.11,57.84 125.11,66.25 131.49,72.62 151.31,72.62 151.77,73.08 151.77,76.63 148.22,80.18 147.07,81.33 147.07,85.52 147.55,86 147.55,89.93 148.59,90.98 149.96,90.98 v1(150.36,90.59)
  BOTTOM w0.132: J35.49 v1(165.54,45.15) ; R626.1 v1(126.03,50.15)
VOUT_D2_BOOTMODE2: length 115.2
  TOP w0.132: v1(165.04,44.32) 165.04,45.34 163.9,46.48 162.19,46.48 162.01,46.3 126.15,46.3 125.03,47.42 v1(125.03,47.87) 125.03,47.87 125.54,48.38 125.54,54.47 v1(127.65,56.58) SW3.3 R287.1 ; v1(150.94,83.19) 150.94,84.01 149.96,84.99 U34.M28
  L05_SIG2 w0.084: v1(150.94,83.19) 151.69,83.19 153.86,81.01 153.86,72.8 151.77,70.71 131.3,70.71 126.33,65.75 126.33,63.23 127.49,62.06 127.82,62.06 128.59,61.29 128.59,57.52 v1(127.65,56.58)
  BOTTOM w0.132: J35.47 v1(165.04,44.32) ; R632.1 v1(125.03,47.87)
VOUT_D3_BOOTMODE3: length 119.1
  TOP w0.132: U34.M24 v1(150.36,89.79) ; v1(164.39,45.17) 164.39,45.62 163.79,46.21 162.3,46.21 162.12,46.03 125.86,46.03 124.47,47.42 124.47,47.95 125.03,48.5 v1(125.03,50.15) 125.03,55.23 v1(127.65,57.85) SW3.4 R282.1
  L05_SIG2 w0.084: v1(127.65,57.85) 125.42,60.08 125.42,66.12 130.92,71.63 151.39,71.63 152.07,72.31 152.07,76.76 148.35,80.48 148.35,89.15 148.59,89.39 149.74,89.39 149.95,89.6 150.17,89.6 v1(150.36,89.79)
  BOTTOM w0.132: J35.45 164.54,45.02 v1(164.39,45.17) ; R627.1 v1(125.03,50.15)
VOUT_D4_BOOTMODE4: length 111.5
  TOP w0.132: v1(164.04,44.32) 164.04,44.69 163.89,44.83 163.89,45.45 163.39,45.95 162.41,45.95 162.23,45.77 125.68,45.77 124.03,47.42 v1(124.03,47.87) 124.03,48.31 124.47,48.76 124.47,55.95 v1(127.65,59.12) SW3.5 R278.1 ; U34.N24 v1(149.56,89.79)
  L03_SIG1 w0.084: v1(149.56,89.79) 149.95,90.18 149.95,91.55 149.72,91.78 143.79,91.78 143.56,91.55 143.56,91.54 143.55,91.52 143.55,85 138.94,80.39 135.76,80.39 126.68,71.31 126.68,60.08 v1(127.65,59.12)
  BOTTOM w0.132: R633.1 v1(124.03,47.87) ; J35.43 v1(164.04,44.32)
VOUT_D5_BOOTMODE5: length 121.8
  TOP w0.132: R274.1 SW3.6 v1(127.65,60.39) 124.03,56.77 v1(124.03,50.15) 123.58,49.71 123.58,46.59 124.84,45.34 131.81,45.34 137.76,39.39 151.86,39.39 154.85,42.37 162.05,42.37 162.59,42.91 162.59,44.79 v1(163.04,45.24) ; U34.N27 v1(148.76,87.39)
  L05_SIG2 w0.084: v1(127.65,60.39) 126.03,62.01 126.03,65.87 131.17,71.02 151.64,71.02 152.68,72.05 152.68,76.68 153.56,77.55 153.56,79.7 149.16,84.1 149.16,86.99 v1(148.76,87.39)
  BOTTOM w0.132: R628.1 v1(124.03,50.15) ; J35.41 163.54,44.74 v1(163.04,45.24)
VOUT_D6_BOOTMODE6: length 124.2
  TOP w0.132: v1(163.04,44.32) 163.04,42.99 162.16,42.11 154.96,42.11 151.97,39.13 137.65,39.13 131.7,45.07 124.73,45.07 123,46.8 123,49.68 v1(122.53,50.15) 122.53,56.54 v1(127.65,61.66) SW3.7 R260.1 ; U34.N28 v1(148.76,86.59)
  L05_SIG2 w0.084: v1(148.76,86.59) 148.76,84.07 152.37,80.45 152.37,72.18 151.52,71.32 131.05,71.32 125.72,66 125.72,61.41 127.26,59.86 127.99,59.86 128.16,60.03 128.16,61.14 v1(127.65,61.66)
  BOTTOM w0.132: R629.1 v1(122.53,50.15) ; J35.39 v1(163.04,44.32)
VOUT_D7_BOOTMODE7: length 130.5
  TOP w0.132: v1(162.04,45.24) 162.04,45.24 162.31,45.5 162.34,45.5 162.52,45.68 163.22,45.68 163.51,45.39 163.51,43.09 162.27,41.85 162.05,41.85 155.07,41.85 152.08,38.86 137.54,38.86 131.59,44.81 124.23,44.81 122.53,46.51 v1(122.53,47.87) 122.08,48.31 122.08,57.36 v1(127.65,62.93) SW3.8 R251.1 ; U34.M25 v1(149.56,88.99)
  L05_SIG2 w0.084: v1(127.65,62.93) 126.94,63.63 126.94,65.49 131.55,70.1 153.06,70.1 155.87,72.91 155.87,80.59 151.24,85.22 150.5,85.22 149.48,86.23 149.48,87.5 149.16,87.82 149.16,88.6 v1(149.56,88.99)
  BOTTOM w0.132: v1(162.04,45.24) 162.54,44.74 J35.37 ; R634.1 v1(122.53,47.87)
VOUT_D8_BOOTMODE8: length 106.8
  TOP w0.132: U34.N23 v1(149.56,90.59) ; v1(161.04,45.24) 161.59,44.68 161.59,43.8 160.43,42.64 154.74,42.64 151.75,39.65 145.26,39.65 143.08,41.83 v1(141.27,41.83) ; R245.1 SW3.9 v1(127.65,64.2)
  L03_SIG1 w0.084: v1(141.27,41.83) 139.61,40.18 135.33,40.18 129.49,46.02 129.49,62.36 v1(127.65,64.2) 127.19,64.66 127.19,71.06 136.02,79.88 139.07,79.88 144.35,85.16 144.35,90.75 144.59,91 149.15,91 v1(149.56,90.59)
  BOTTOM w0.132: J35.33 161.54,44.74 v1(161.04,45.24) ; R642.1 v1(141.27,41.83)
VOUT_D9_BOOTMODE9: length 121.7
  TOP w0.132: R240.1 SW3.10 v1(127.65,65.47) ; U34.M26 v1(149.56,88.19)
  L03_SIG1 w0.084: v1(141.27,43.74) 139.81,42.28 139.81,41.69 138.61,40.49 135.46,40.49 129.79,46.15 129.79,63.32 v1(127.65,65.47)
  L05_SIG2 w0.084: v1(141.27,43.74) 140.75,44.26 139.03,44.26 138.81,44.04 138.81,43.24 139.7,42.35 142.39,42.35 145.31,39.43 156.6,39.43 161.04,43.87 v1(161.04,44.32) ; v1(127.65,65.47) 131.98,69.8 153.19,69.8 155.99,72.61 156.17,72.78 156.17,80.47 156.17,80.72 151.29,85.6 150.56,85.6 149.83,86.32 149.83,87.91 v1(149.56,88.19)
  BOTTOM w0.132: R635.1 v1(141.27,43.74) ; J35.31 v1(161.04,44.32)
VOUT_D10_BOOTMODE10: length 83
  TOP w0.132: v1(150.3,81.85) 148.08,84.08 148.08,86.71 U34.P28 ; R295.1 v1(148.32,54.05) SW2.1 ; v1(160.04,45.24) 160.48,44.79 160.48,43.33 160.06,42.9 154.63,42.9 151.64,39.92 145.37,39.92 142.99,42.29 140.72,42.29 v1(140.27,41.83)
  L03_SIG1 w0.084: v1(148.32,54.05) 152.17,57.89 152.17,79.99 v1(150.3,81.85)
  L12_SIG4 w0.084: v1(148.32,54.05) 146.38,54.05 145.11,52.78 145.11,49.61 143.83,48.32 143.83,45.39 v1(140.27,41.83)
  BOTTOM w0.132: R643.1 v1(140.27,41.83) ; v1(160.04,45.24) 160.54,44.74 J35.29
VOUT_D11_BOOTMODE11: length 78.5
  TOP w0.132: SW2.2 147.94,55.32 148.3,54.97 v1(148.34,54.97) 148.69,55.32 R291.1 ; U34.P27 v1(147.96,87.39)
  L03_SIG1 w0.084: v1(147.96,87.39) 147.96,83.55 148.51,82.99 148.51,76.59 149.25,75.86 149.25,72.8 147.75,71.3 147.75,62.73 148.25,62.23 148.46,62.23 148.84,61.85 148.84,59.53 148.42,59.11 148.08,59.11 147.26,58.28 147.26,56.05 v1(148.34,54.97)
  L05_SIG2 w0.084: v1(160.04,44.32) 156.3,40.59 145.01,40.59 142.64,42.96 141.04,42.96 v1(140.27,43.74)
  L12_SIG4 w0.084: v1(148.34,54.97) 146.66,54.97 144.72,53.02 144.72,50.07 142.75,48.1 142.75,46.23 v1(140.27,43.74)
  BOTTOM w0.132: J35.27 v1(160.04,44.32) ; R636.1 v1(140.27,43.74)
VOUT_D12_BOOTMODE12: length 85.1
  TOP w0.132: R285.1 148.91,56.59 v1(148.33,56.01) 147.74,56.59 SW2.3 ; v1(159.04,45.24) 159.48,44.79 159.48,43.66 158.99,43.17 154.52,43.17 151.61,40.26 145.42,40.26 143.07,42.61 140.04,42.61 v1(139.27,41.83) ; U34.N26 v1(148.76,88.19)
  L03_SIG1 w0.084: v1(148.76,88.19) 148.94,88 148.94,87.79 149.23,87.5 149.23,84.53 149.12,84.42 149.12,78.27 150.52,76.87 150.52,72.25 151.25,71.52 151.25,61.46 148.59,58.8 148.21,58.8 147.56,58.15 147.56,56.77 v1(148.33,56.01)
  L12_SIG4 w0.084: v1(148.33,56.01) 146.62,56.01 143.51,52.9 143.51,49.85 141.86,48.2 141.86,46.35 139.7,44.2 139.7,42.27 v1(139.27,41.83)
  BOTTOM w0.132: R644.1 v1(139.27,41.83) ; v1(159.04,45.24) 159.54,44.74 J35.25
VOUT_D13_BOOTMODE13: length 86.7
  TOP w0.132: R280.1 148.78,57.86 v1(148.32,57.4) 147.87,57.86 SW2.4 ; U34.N25 v1(148.76,88.99)
  L03_SIG1 w0.084: v1(148.32,57.4) 151.56,60.64 151.56,73.61 150.83,74.34 150.83,77 149.43,78.4 149.43,84.3 151.67,86.54 151.67,87.5 151.39,87.78 149.41,87.78 149.16,88.03 149.16,88.33 148.76,88.74 v1(148.76,88.99)
  L05_SIG2 w0.084: v1(159.04,44.32) 159.49,44.78 160.23,44.78 160.49,44.51 160.49,43.78 157,40.28 144.89,40.28 142.51,42.66 140.35,42.66 v1(139.27,43.74)
  L12_SIG4 w0.084: v1(139.27,43.74) 139.27,46.57 142.49,49.8 142.49,52.64 147.26,57.4 v1(148.32,57.4)
  BOTTOM w0.132: R637.1 v1(139.27,43.74) ; J35.23 v1(159.04,44.32)
VOUT_D14_BOOTMODE14: length 101.1
  TOP w0.132: SW2.5 148.16,59.13 148.32,58.97 ; 148.32,58.97 148.49,59.13 R276.1 ; 148.32,58.97 v1(148.32,58.32) ; U34.P24 v1(148.76,89.79)
  L03_SIG1 w0.084: v1(148.76,89.79) 148.94,89.6 148.94,89.44 149.16,89.21 149.16,88.83 149.39,88.6 151.3,88.6 151.89,88.01 151.89,86.23 149.73,84.07 149.73,81.66 150.5,80.9 150.5,77.88 151.86,76.51 151.86,59.79 148.59,56.52 148.25,56.52 147.87,56.9 147.87,57.85 148,57.98 148,58 v1(148.32,58.32)
  L05_SIG2 w0.084: v1(158.04,45.24) 158.58,45.78 161.14,45.78 161.49,45.43 161.49,43.89 156.73,39.13 145.18,39.13 143.23,41.08 139.32,41.08 137.77,42.64 v1(137.77,43.74)
  L12_SIG4 w0.084: v1(137.77,43.74) 137.77,45.5 141.37,49.11 141.37,52.66 147.03,58.32 v1(148.32,58.32)
  BOTTOM w0.132: v1(158.04,45.24) 158.54,44.74 J35.21 ; R638.1 v1(137.77,43.74)
VOUT_D15_BOOTMODE15: length 78.7
  TOP w0.132: v1(137.77,41.83) 138.86,42.93 143.13,42.93 145.45,40.61 151.54,40.61 154.37,43.43 157.15,43.43 v1(158.04,44.32) ; SW2.6 147.5,60.4 148.29,59.61 148.34,59.61 v1(148.34,59.6) 148.34,59.7 149,60.35 R272.1 ; U34.R27 v1(147.16,87.39)
  L03_SIG1 w0.084: v1(148.34,59.6) 146.81,61.14 146.81,66.17 146.08,66.9 146.08,75.34 146.76,76.02 146.76,87 v1(147.16,87.39)
  L10_SIG3 w0.084: v1(158.04,44.32) 157.48,44.88 157.48,48.51 156.15,49.85 153.73,49.85 148.97,54.61 148.97,59.43 148.8,59.6 v1(148.34,59.6)
  BOTTOM w0.132: J35.19 v1(158.04,44.32) ; R645.1 v1(137.77,41.83)
VOUT_D16: length 51.5
  TOP w0.132: U34.R28 v1(147.16,86.59)
  L03_SIG1 w0.084: v1(147.16,86.59) 147.16,85.98 147.07,85.89 147.07,75.9 146.38,75.21 146.38,67.03 147.11,66.3 147.11,61.68 v1(148.27,60.52)
  L10_SIG3 w0.084: v1(148.27,60.52) 147.83,60.07 147.83,53.4 152.72,48.51 156.08,48.51 156.59,48.01 156.59,44.77 v1(157.04,44.32)
  BOTTOM w0.132: J35.15 v1(157.04,44.32)
VOUT_D17_BOOTMODE16: length 56.3
  TOP w0.132: R258.1 148.39,61.67 148.34,61.72 v1(148.32,61.72) 148.28,61.67 SW2.7 ; U34.P25 v1(147.96,88.99)
  L03_SIG1 w0.084: v1(148.32,61.72) 147.45,62.6 147.45,71.88 148.21,72.64 148.21,82.87 147.56,83.51 147.56,88.6 v1(147.96,88.99)
  L10_SIG3 w0.084: v1(156.02,47.43) 153.37,47.43 147.37,53.43 147.37,60.04 147.68,60.35 147.68,61.07 v1(148.32,61.72)
  BOTTOM w0.132: R603.1 147.81,61.7 148.31,61.7 v1(148.32,61.72) ; v1(156.02,47.43) 156.02,45.72 156.54,45.2 J35.13
VOUT_D18_BOOTMODE17: length 54.7
  TOP w0.132: SW2.8 148.12,62.94 v1(148.32,62.74) 148.53,62.94 R249.1 ; U34.P26 v1(147.96,88.19)
  L03_SIG1 w0.084: v1(148.32,62.74) 149.05,63.46 149.05,71.6 149.55,72.11 149.55,75.98 148.82,76.72 148.82,83.12 148.36,83.57 148.36,87.78 v1(147.96,88.19)
  L10_SIG3 w0.084: v1(156.04,45.14) 155.23,45.14 147.24,53.12 147.07,53.3 147.07,60.17 147.37,60.48 147.37,61.78 v1(148.32,62.74)
  BOTTOM w0.132: v1(156.04,45.14) 156.04,44.75 156.04,44.75 J35.11 ; v1(148.32,62.74) 148.16,62.91 R602.1
VOUT_D19_BOOTMODE18: length 109.9
  TOP w0.132: SW2.9 147.75,64.21 v1(148.27,63.69) 148.79,64.21 R243.1 ; U34.U28 v1(145.56,86.59)
  L03_SIG1 w0.084: v1(135.89,41.91) 134.99,42.81 134.99,50.8 137.96,53.77 141.89,53.77 145.28,57.17 145.28,65.87 143.19,67.96 143.19,77.24 144.74,78.78 144.74,83.81 145.56,84.62 v1(145.56,86.59)
  L10_SIG3 w0.084: v1(155.54,41.17) 155.08,41.17 153.56,39.65 137.48,39.65 135.89,41.24 v1(135.89,41.91) 136.91,42.93 141.61,42.93 145.42,46.74 145.42,58.95 147.07,60.61 147.07,62.48 v1(148.27,63.69)
  BOTTOM w0.132: v1(148.27,63.69) 148.04,63.93 R601.1 ; J35.9 v1(155.54,41.17)
VPHY_3V3_FT4232: length 6.1
  L05_SIG2 w0.203: v1(17.1,137.69) 18.03,137.69 v1(19.58,136.14)
  BOTTOM w0.254: v1(19.58,136.14) C331.2 19.97,136.82 20.09,136.69 U73.4 ; FL10.1 v1(17.1,137.69)
VPLL_3V3_FT4232: length 5.6
  BOTTOM w0.203: C324.2 19.71,139.45 19.51,139.66 17.79,139.66 17.71,139.57 FL9.1
  BOTTOM w0.254: R381.2 FL9.1 ; U73.9 C324.2
VPP_1V8: length 103.1
  TOP w0.254: U1.1 129.23,170.06 C5.1
  L08_PWR3 w0.254: 160.02,158.78 161.11,159.87 161.11,166.28 159.62,167.77 154.24,167.77 152.02,169.99 134.18,169.99 133.1,171.07
  L08_PWR3 w0.381: 160.02,158.78 160.02,150.75 161.11,149.66 161.11,139.76 163.2,137.67 163.2,135.64 161.29,133.73 161.29,115.82 159.39,113.92 149.04,113.92 146.8,116.16 v1(146.8,117.35)
  BOTTOM w0.254: FL17.1 147,117.14 v1(146.8,117.35)
  vias: v1(129.86,171.64) v1(130.87,171.64)
VPP_CORE_MCU: length 33.3
  TOP w0.132: U34.T6 v1(146.36,104.99) ; U34.F21 v1(155.16,92.19)
  L10_SIG3 w0.122: v1(146.36,104.99) 146.36,104.74 146.75,104.35 146.75,103.95 146.9,103.8 147.34,103.8 147.57,103.57 147.57,96.82 148.59,95.8 151.34,95.8 151.55,95.6 151.55,92.81 151.76,92.6 154.75,92.6 v1(155.16,92.19)
  BOTTOM w0.122: 147.96,105.41 147.94,105.4 146.76,105.4 v1(146.36,104.99)
  BOTTOM w0.254: FL17.2 147,112.9 147.96,111.95 C414.1
VPP_LDO_EN: length 113.6
  TOP w0.132: U1.3 R6.2 v1(126.54,168.35) ; U34.R1 v1(147.16,108.99)
  L12_SIG4 w0.084: v1(147.16,108.99) 146.88,109.27 146.88,109.6 146.88,115.89 148.27,117.28 148.27,121.35 151.32,124.4 151.32,133.29 152.78,134.75 159.25,134.75 161.09,136.59 161.09,145.08 162.5,146.49 162.5,156.08 161.42,157.16 161.42,169.8 158.65,172.57 139.04,172.57 134.83,168.35 v1(126.54,168.35)
  BOTTOM w0.132: TP80.1 v1(126.54,168.35)
VREF: length 7.7
  BOTTOM w0.203: U106.9 45.16,21.32 C654.1
  BOTTOM w0.254: R663.2 U107.3 C655.1 C654.1
VSENSE: length 4
  BOTTOM w0.132: U80.6 45.26,127.37 45.16,127.27 C361.2 45.16,125.01 R425.2 R418.1
WARM_RST: length 16.5
  TOP w0.132: U55.2 112.39,36.7 112.78,36.32 113.41,36.32 115.95,38.86 115.95,40.26 117.22,41.53 117.22,45.72 116.84,46.1 115.44,46.1 115.02,46.53 U52.2
WKUP_GPIO0_13: length 8.1
  TOP w0.132: U53.2 107.44,45.57 107.64,45.37 113.79,45.37 114.02,45.15 U52.5
WKUP_GPIO0_13_INTN: length 103.7
  TOP w0.132: U34.R5 v1(147.16,105.79) ; v1(106.55,41.95) 106.49,42.01 R308.1 U53.4
  L10_SIG3 w0.084: v1(138.52,75.66) 138.52,76.39 141.51,79.38 141.51,85.98 141.96,86.43 141.96,97.15 142.76,97.95 142.76,104.35 143.01,104.6 143.32,104.6 143.56,104.85 143.56,106.75 143.81,107 147.3,107 147.55,106.75 147.55,106.18 v1(147.16,105.79)
  BOTTOM w0.132: v1(106.55,41.95) 105.92,42.58 105.92,66.67 116.4,77.15 137.03,77.15 v1(138.52,75.66)
WKUP_GPIO0_27: length 6.8
  TOP w0.132: v1(113.98,42.74) 115.02,43.77 U52.7
  BOTTOM w0.132: v1(113.98,42.74) 112.61,42.74 112.19,42.32 112.19,40.81 112.39,40.6 U104.2
WKUP_GPIO0_27_INTN: length 96.4
  TOP w0.132: U34.P2 v1(148.76,108.19)
  L03_SIG1 w0.084: v1(148.76,108.19) 148.76,107.99 148.21,107.44 148.21,104.69 147.32,103.8 146.15,103.8 145.97,103.61 145.97,102.41 146.18,102.2 147.61,102.2 147.83,101.98 147.83,92.84 147.57,92.58 142.94,92.58 142.75,92.39 142.75,84.83 138.81,80.9 135.64,80.9 125.41,70.68 125.41,55.94 115.44,45.97 115.44,37.68 v1(114.07,36.3)
  BOTTOM w0.132: v1(114.07,36.3) 113.97,36.21 R647.1 U104.4
WKUP_LFOSC_RTC_XIN: length 69.6
  TOP w0.132: U34.AE4 v1(139.96,106.59)
  L10_SIG3 w0.084: v1(139.96,106.59) 139.55,106.18 137.53,106.18 137.35,106.36 134.05,106.36 131.72,104.04 124.61,104.04 121.54,100.96 118.24,100.96 115.06,97.79 115.06,85.85 104.9,75.69 100.15,75.69 99.82,75.36 96.05,75.36 v1(94.86,74.17)
  BOTTOM w0.132: v1(94.86,74.17) 93.85,75.17 R551.2
WKUP_LFOSC_XIN: length 2.1
  BOTTOM w0.132: U91.1 R564.1
WKUP_LFOSC_XOUT: length 2.1
  BOTTOM w0.132: U91.2 R550.1
WKUP_OSC0_XIN: length 13.4
  TOP w0.132: U34.AD5 v1(139.96,105.79)
  BOTTOM w0.122: v1(139.96,105.79) 140.36,106.2 140.36,106.78 140.14,107 136.18,107
  BOTTOM w0.132: 136.18,107 134.81,107 132.9,108.9 R450.1 130.72,109.52 130.72,109.52 R448.2
WKUP_OSC0_XOUT: length 11.3
  TOP w0.132: U34.AE6 v1(139.16,104.99)
  BOTTOM w0.122: v1(139.16,104.99) 139.56,105.4 139.56,105.93 139.32,106.18 136.2,106.18
  BOTTOM w0.132: 136.2,106.18 134.1,106.18 132.59,107.7 R457.1
WKUP_UART_SEL: length 137.9
  TOP w0.132: R120.2 108.43,116.02 109.08,115.36 U23.6 110.47,115.36 v1(110.74,115.09)
  L03_SIG1 w0.084: v1(76.77,15.51) 76.77,15.06 77.22,14.61 85.59,14.61 97.69,26.71 97.69,57.06 93.21,61.55 93.21,91.19 91.56,92.83 91.56,98.1 94.12,100.66 102.7,100.66 105.22,103.18 105.22,106.71 105.05,106.88 105.05,112.17 107.97,115.09 v1(110.74,115.09)
  BOTTOM w0.132: U83.6 110.52,114.86 v1(110.74,115.09) ; U110.14 77.27,16.01 v1(76.77,15.51)
XDS110_DIR: length 2.9
  BOTTOM w0.132: R621.2 59.44,53.47 59.18,53.21 ; 59.18,53.21 59.02,53.05 U98.3 ; 59.18,53.21 58.84,53.55 U98.2
XDS110_EMU0: length 9
  BOTTOM w0.132: U103.8 51.02,39.75 51.12,39.65 51.12,36.13 50.8,35.81 50.8,34.54 51.34,34 R655.2 51.37,33.33 51.69,33.01 U106.42
XDS110_EMU1: length 9.1
  BOTTOM w0.132: U106.43 52.09,33.03 52.39,33.33 R654.2 52.42,34 53.02,34.6 53.02,35.69 52.58,36.13 52.58,39.59 52.74,39.75 U103.1
XDS110_TCK: length 18
  TOP w0.132: v1(52.32,52.55) 52.77,52.11 54.14,52.11 54.37,52.34 54.37,52.74 50.31,56.8 v1(44.09,56.8)
  BOTTOM w0.132: R609.2 v1(44.09,56.8) ; v1(52.32,52.55) 52.82,52.05 U98.12
XDS110_TDI: length 17.9
  TOP w0.132: v1(53.93,52.55) 52.06,54.42 42.8,54.42 40.65,56.57 v1(39.18,56.57)
  BOTTOM w0.132: R612.2 v1(39.18,56.57) ; v1(53.93,52.55) U98.13
XDS110_TDO: length 6.1
  TOP w0.132: v1(41.21,60.34) 41.72,59.82 41.72,58.32 41.72,58.32 v1(41.72,56.57)
  BOTTOM w0.132: R611.2 v1(41.72,56.57) ; v1(41.21,60.34) 41.53,60.02 41.53,59.77 41.7,59.6 U97.7
XDS110_TMS: length 19.6
  TOP w0.132: v1(53.93,51.55) 52.89,51.55 52.44,52 51.5,52 49.47,54.04 42.8,54.04 40.83,56.01 38.47,56.01 v1(37.91,56.57)
  BOTTOM w0.132: R613.2 v1(37.91,56.57) ; U98.11 v1(53.93,51.55)
XDS110_TRST#: length 26.3
  TOP w0.132: v1(52.26,51.55) 45.08,51.55 37.91,44.39 v1(37.91,38.93)
  BOTTOM w0.132: v1(52.26,51.55) 52.76,51.05 U98.10 ; R646.2 v1(37.91,38.93)
XDS_SHIELD: length 3.3
  TOP w0.254: J23.SH3 100.37,3.75 99.49,2.87 J23.SH1
  vias: v1(98.22,0.81) v1(98.25,2.31)
XDS_USB_DM: length 55.9
  TOP w0.104: J23.2 104.09,4.87 103.87,5.09 103.87,5.72 v1(104.28,6.13) 103.99,6.13 103.87,6.24 103.87,6.43 103.93,6.49 103.93,6.77 U58.5
  L05_SIG2 w0.089: v1(104.28,6.13) 103.97,6.13 103.89,6.21 103.89,7.07 101.83,9.13 96.16,9.13 95.9,9.4 71.86,9.4 62.01,19.24 60.19,19.24 60.1,19.33 v1(60.1,19.63)
  BOTTOM w0.104: U106.93 60.41,19.32 v1(60.1,19.63)
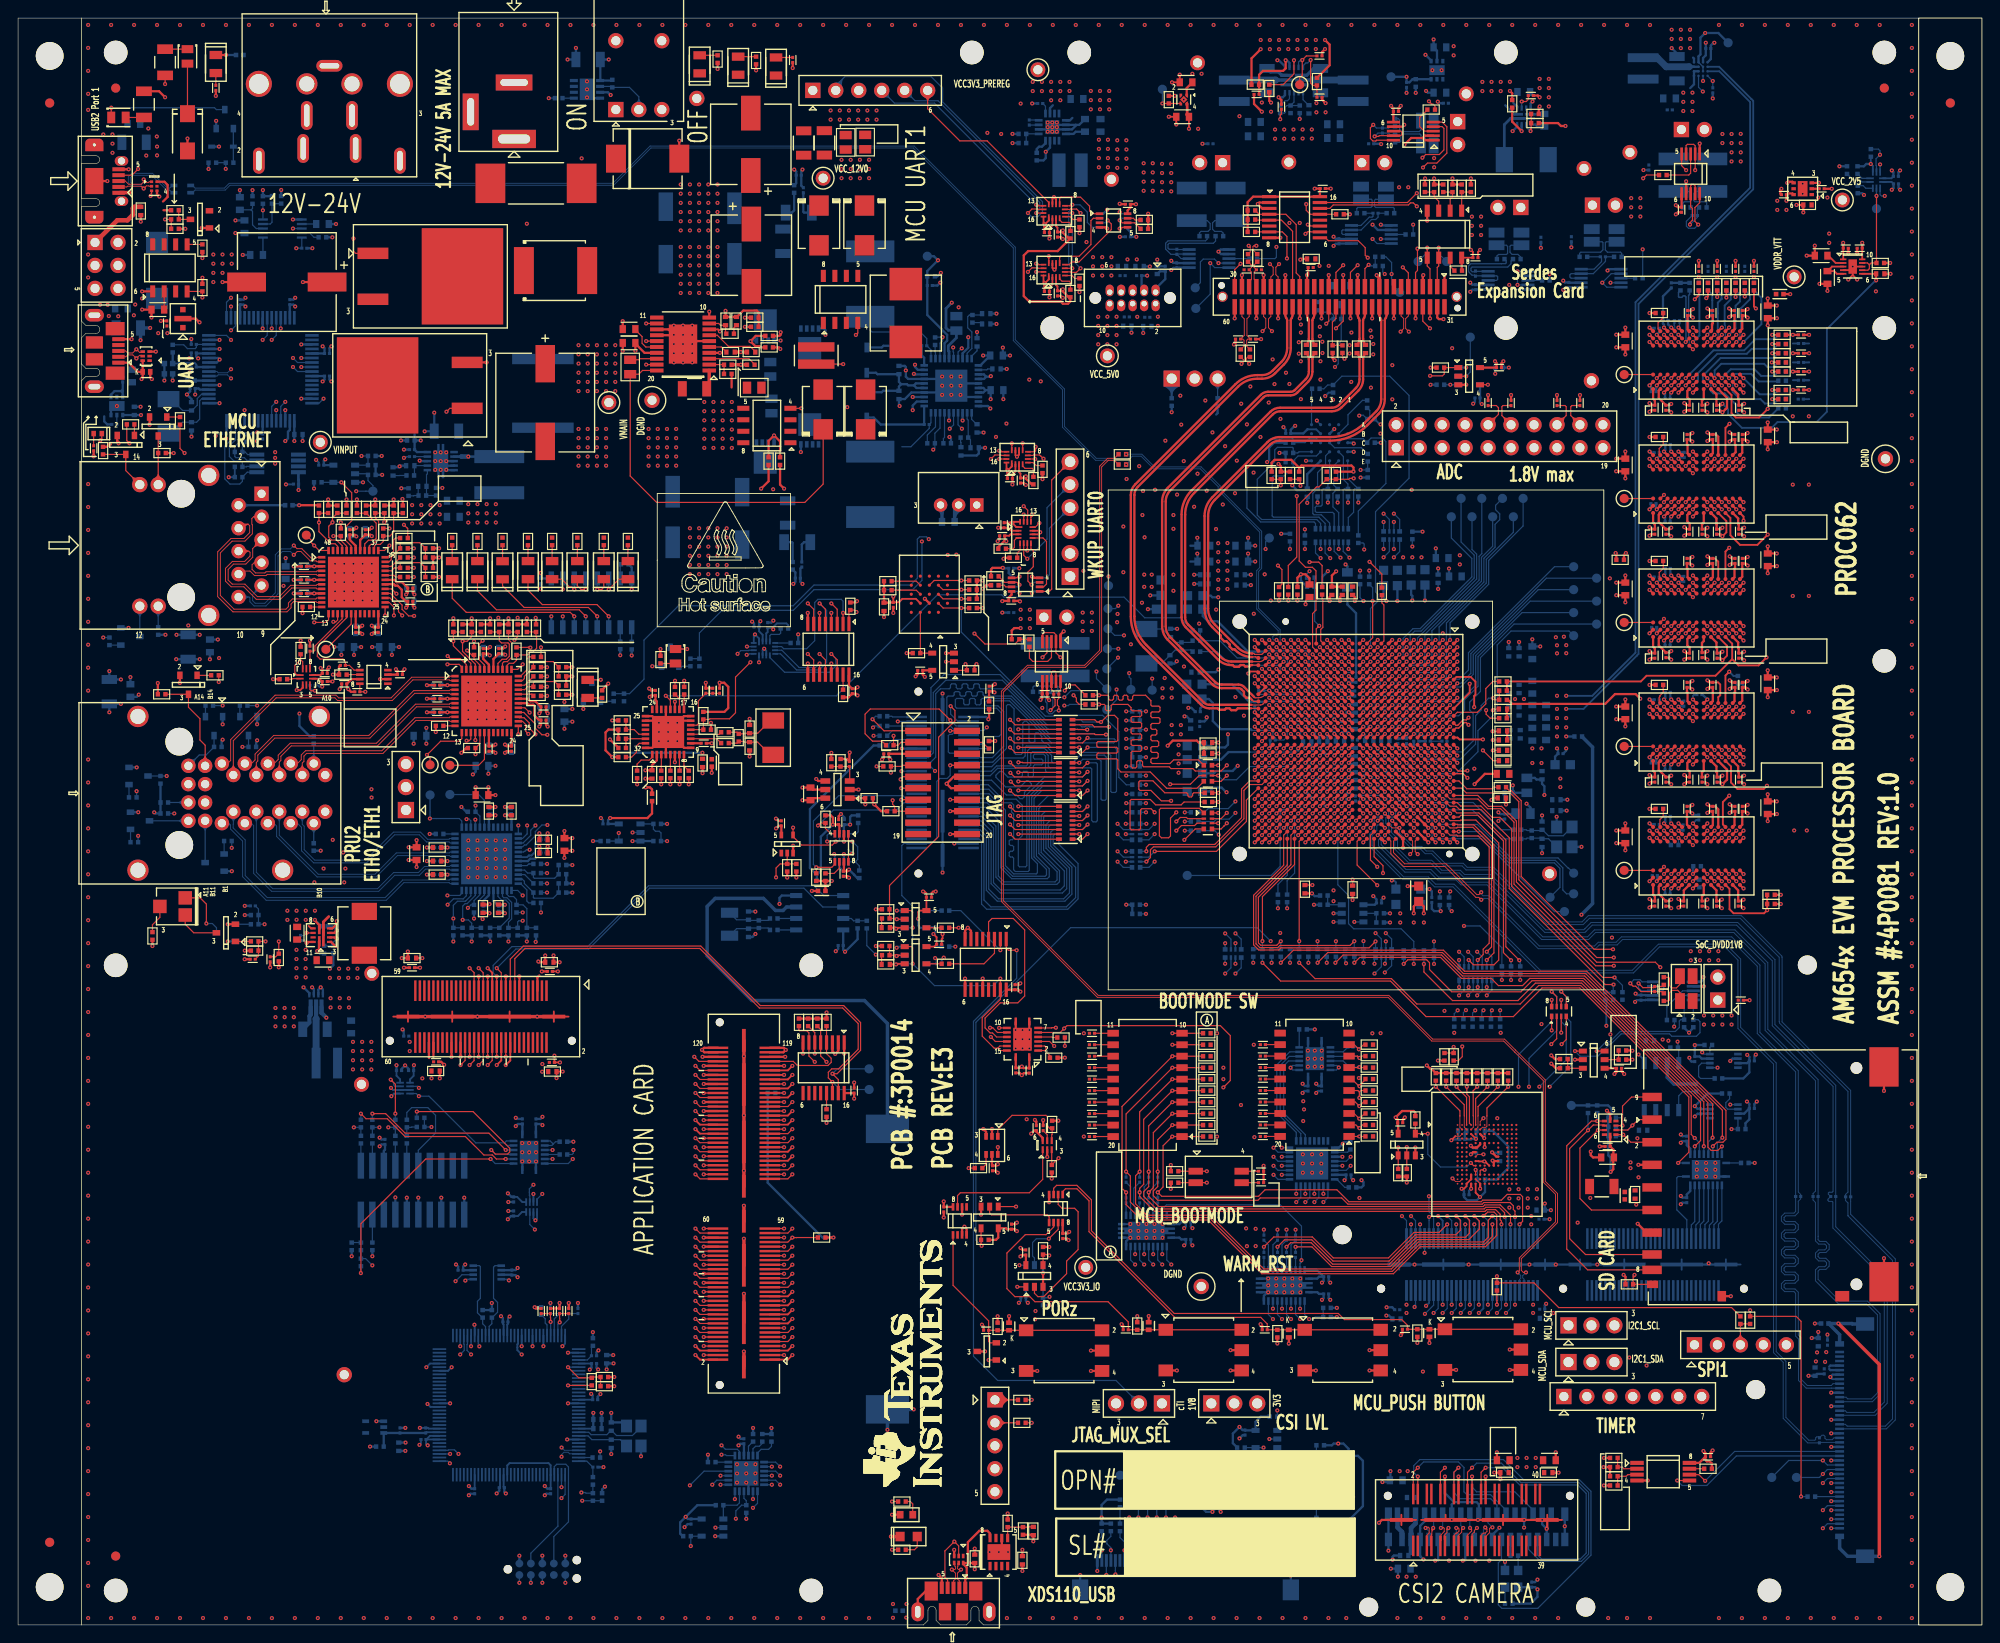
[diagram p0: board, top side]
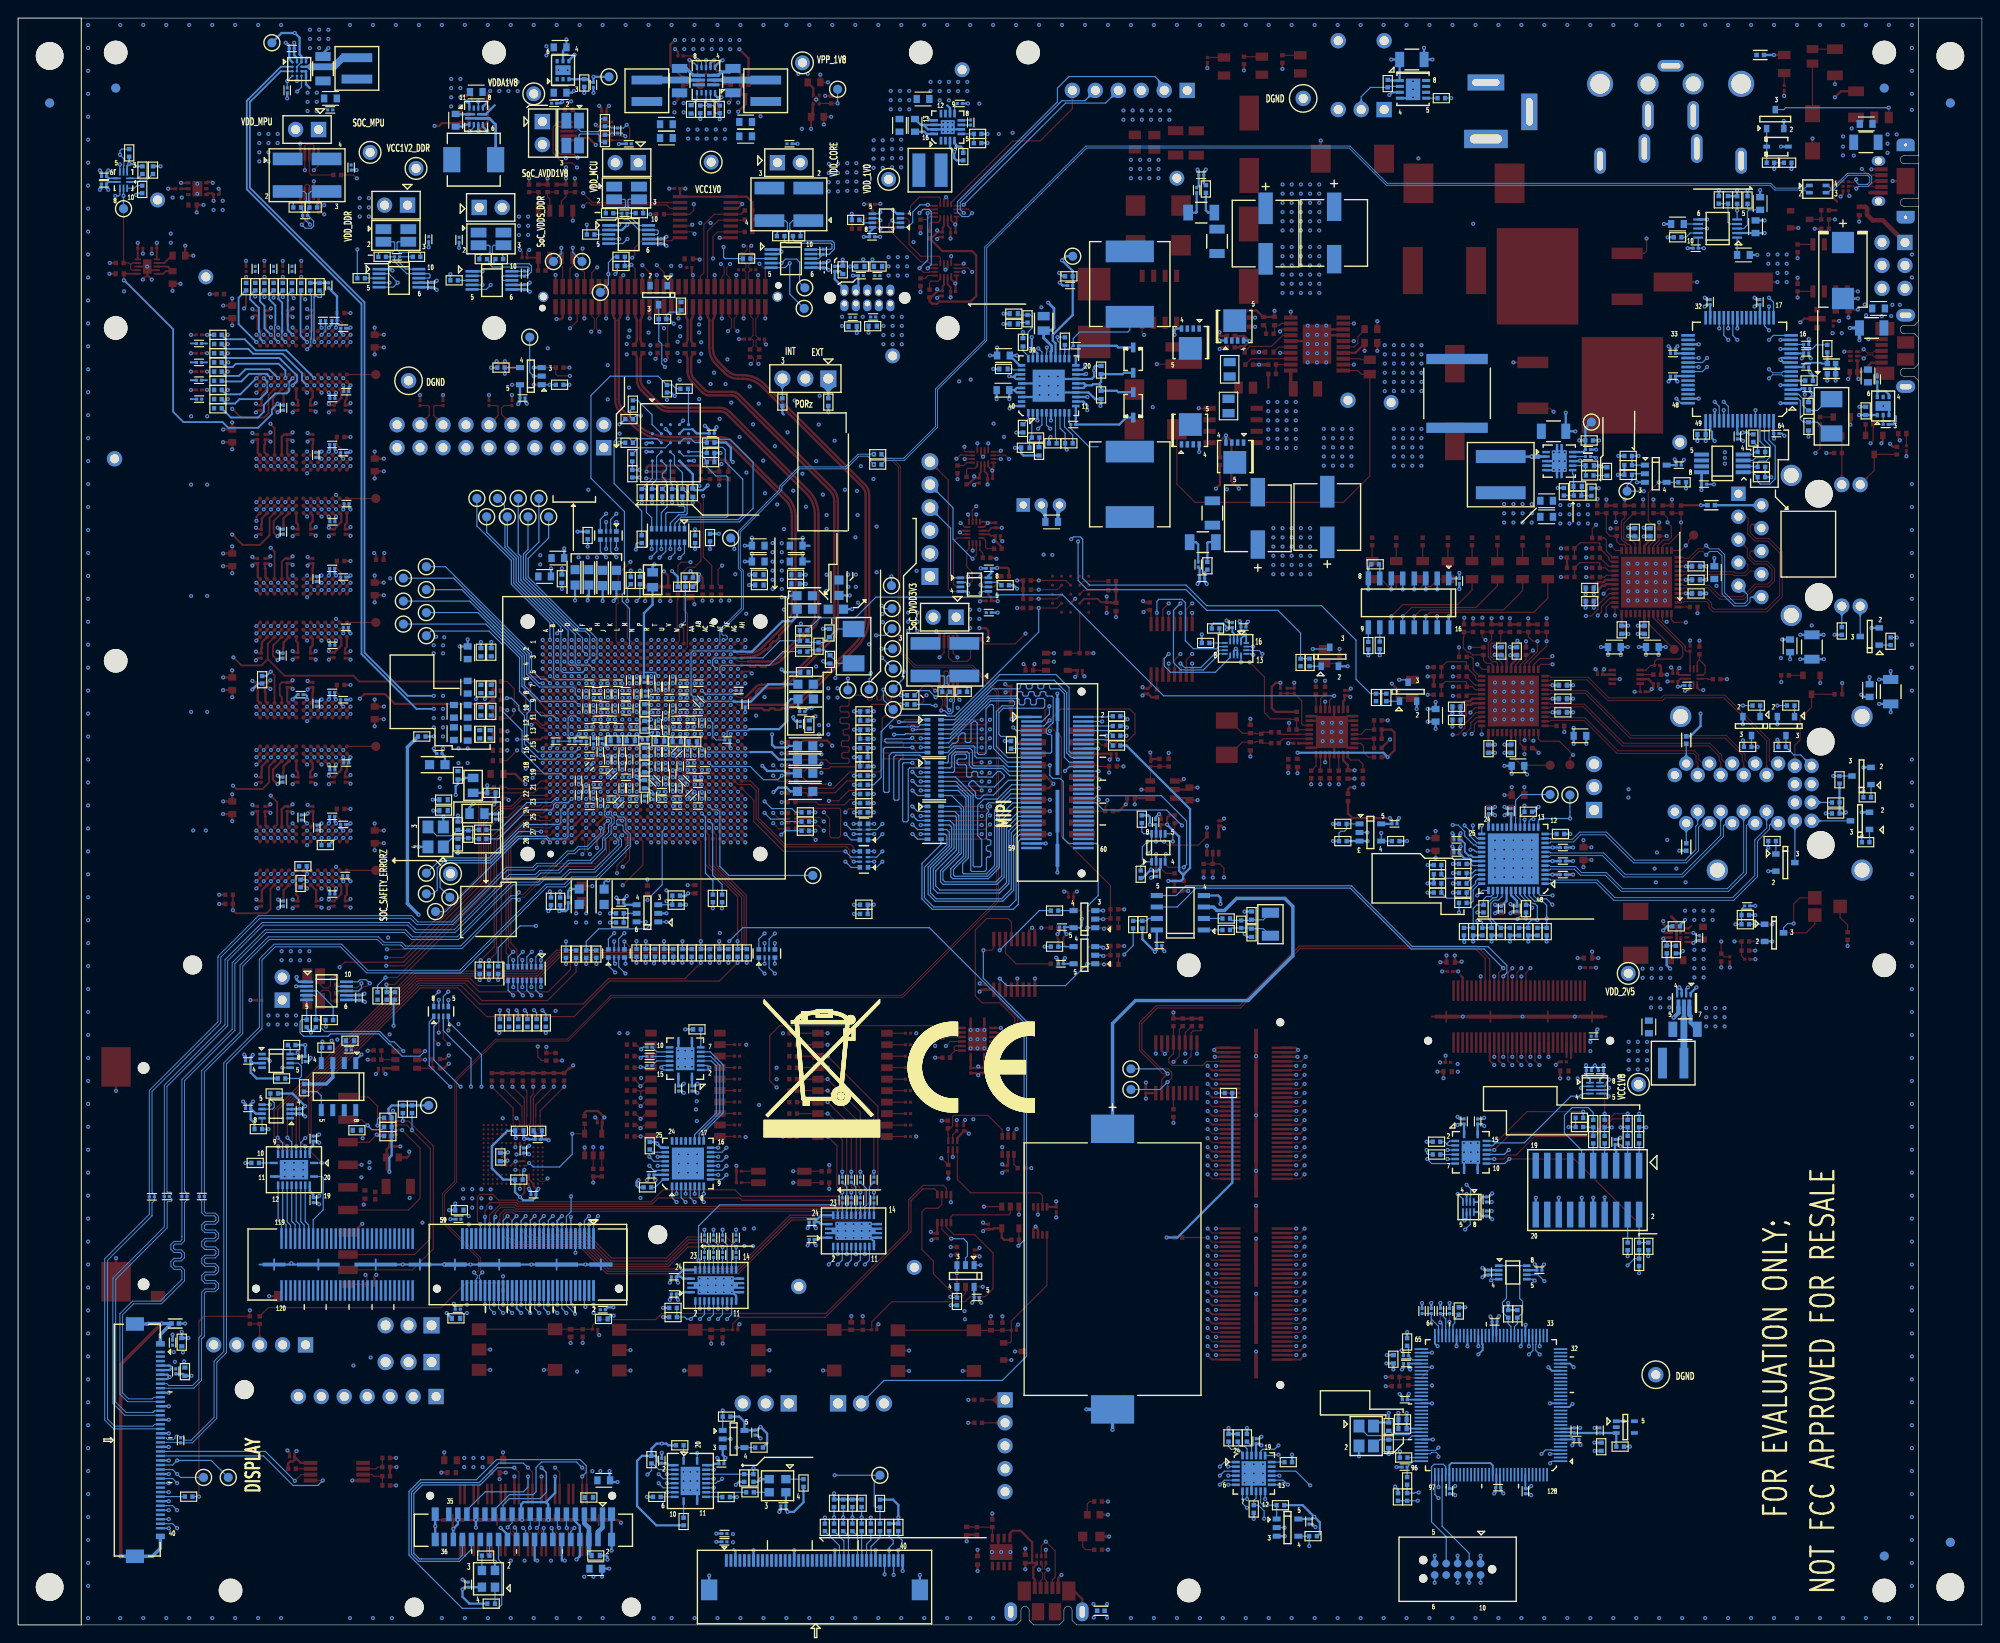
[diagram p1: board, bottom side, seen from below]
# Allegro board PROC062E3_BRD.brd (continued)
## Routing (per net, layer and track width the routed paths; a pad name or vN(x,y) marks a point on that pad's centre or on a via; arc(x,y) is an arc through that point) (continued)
XDS_USB_DP: length 55.9
  TOP w0.104: J23.3 103.44,4.88 103.66,5.09 103.66,5.72 v1(103.26,6.13) 103.57,6.13 103.66,6.21 103.66,6.43 103.59,6.5 103.59,6.78 U58.4
  L05_SIG2 w0.089: v1(103.26,6.13) 103.58,6.13 103.67,6.21 103.67,6.98 101.74,8.92 96.07,8.92 95.81,9.18 71.77,9.18 61.92,19.02 60.19,19.02 60.1,18.94 v1(60.1,18.61)
  BOTTOM w0.104: v1(60.1,18.61) 60.1,18.85 60.36,19.1 60.83,19.1 60.99,18.94 61.98,18.94 U106.94
XDS_USB_ID: length 51.5
  TOP w0.132: U58.2 104.02,8.74 v1(103.53,9.22) 102.49,8.18 102.49,5.27 102.79,4.97 J23.4
  L05_SIG2 w0.084: v1(103.53,9.22) 102.44,10.31 73.26,10.31 v1(64.36,19.21)
  BOTTOM w0.132: R665.2 v1(64.36,19.21)
XDS_USB_VBUS: length 60.7
  TOP w0.254: J23.1 104.74,5.05 104.9,5.21 104.9,6.37 104.52,6.75 U58.6 105.03,6.85 ; 105.03,6.85 105.03,9.14 106.3,10.42 107.19,10.42 107.48,10.12 U57.8 ; 105.03,6.85 C250.1 v1(105.79,6.16)
  L05_SIG2 w0.203: v1(62.29,14.65) 69.6,7.34 100.84,7.34 102.72,5.46 105.09,5.46 v1(105.79,6.16)
  BOTTOM w0.132: R670.1 R678.1 62.81,14.58 62.74,14.65 v1(62.29,14.65)
N5126218: length 2.2
  BOTTOM w0.132: R501.2 J14.A12
N5126260: length 19.4
  TOP w0.132: U31.13 49.07,98.06 48.79,97.78 46.73,97.78 v1(45.21,96.27) 45.56,95.92 TP16.1 ; v1(47.48,106.29) 48.77,106.29 49.07,105.99 U31.48
  L03_SIG1 w0.084: v1(45.21,96.27) 46.86,97.92 46.86,105.68 v1(47.48,106.29)
N15202140: length 1.5
  BOTTOM w0.132: U106.95 R665.1
N15204440: length 4.1
  TOP w0.132: C249.2 111.71,10.85 111.68,10.82 R334.2 R333.1 U57.5
N15205319: length 2.8
  BOTTOM w0.132: U106.68 62.95,29.32 C645.1 63.41,30.73 R657.1
N15205492: length 6.3
  TOP w0.132: v1(60.81,28.52) 61.99,27.34 R323.1 63.52,27.43 R322.1 R324.1
  BOTTOM w0.132: v1(60.81,28.52) U106.70
N15212041: length 2.6
  BOTTOM w0.132: R653.1 57.86,34.31 58.29,33.88 58.29,33.4 58.49,33.2 U106.59
N15239696: length 2.9
  BOTTOM w0.132: R670.2 C665.1 63.55,17.46 62.89,18.12 U106.96
N15241750: length 20
  L10_SIG3 w0.084: v1(62.38,13.74) 58,18.12 47.99,18.12 v1(47.75,17.88)
  BOTTOM w0.132: U106.1 47.52,18.12 v1(47.75,17.88) ; R677.1 R678.2 v1(62.38,13.74)
N15242949: length 55.1
  TOP w0.132: R335.1 v1(96.65,8.32)
  L05_SIG2 w0.084: v1(96.65,8.32) 69.72,8.32 59.88,18.16 48.53,18.16 v1(47.77,18.92)
  BOTTOM w0.132: v1(47.77,18.92) U106.3
N15242980: length 2.6
  TOP w0.132: R335.2 99.12,8.32 99.43,8.63 LD20.2
N15243226: length 54.8
  TOP w0.132: R332.1 v1(96.65,13.65)
  L05_SIG2 w0.084: v1(96.65,13.65) 95.5,14.8 70.48,14.8 64.3,20.98 50.76,20.98 v1(48.7,18.92)
  BOTTOM w0.132: U106.4 47.54,19.32 47.59,19.37 48.26,19.37 48.39,19.24 48.39,19.24 v1(48.7,18.92)
N15352717: length 4.7
  BOTTOM w0.132: R410.1 149.23,129.57 148.55,130.26 145.59,130.26 U77.C3
N15365714: length 3.7
  BOTTOM w0.132: J41.27 125.85,9.3 126.92,10.38 R690.2
N15365947: length 3.5
  BOTTOM w0.132: J41.30 124.35,9.83 124.89,10.38 R692.2
N15366015: length 3.3
  BOTTOM w0.132: J41.31 123.85,8.1 123.89,8.14 R693.2
N15366091: length 3.4
  BOTTOM w0.132: R694.2 122.87,9.4 123.35,8.92 J41.32
N15507744: length 1
  BOTTOM w0.132: U76.2 10.92,132.84
N15584817: length 2.1
  TOP w0.132: SW3.17 R281.2
N15584821: length 2.1
  TOP w0.132: SW3.18 R286.2
N15584825: length 2.1
  TOP w0.132: SW3.19 R292.2
N15584829: length 2.1
  TOP w0.132: SW3.20 R296.2
N15591045: length 2.1
  TOP w0.132: SW3.13 R250.2
N15591049: length 2.1
  TOP w0.132: SW3.14 R259.2
N15591053: length 2.1
  TOP w0.132: SW3.15 R273.2
N15591057: length 2.1
  TOP w0.132: SW3.16 R277.2
N15697942: length 2.3
  BOTTOM w0.132: R449.2 J12.11
N15698204: length 14.9
  TOP w0.132: v1(32.74,110.93) 34.06,110.93 34.33,111.21 U22.13 ; TP12.1 32.43,120.04 32.43,119.76 v1(32.74,119.44) 33.3,118.89 U22.48
  L10_SIG3 w0.084: v1(32.74,110.93) 33.53,111.72 33.53,118.66 v1(32.74,119.44)
N15808488: length 2.2
  TOP w0.132: R75.1 181.92,130.62 181.48,130.18 181.48,129.57 U20.B9
N15808528: length 3.2
  TOP w0.132: TP8.1 U16.A3
N15808578: length 3.2
  TOP w0.132: TP11.1 U20.A3
N15808694: length 3.2
  TOP w0.132: TP13.1 U25.A3
N15808746: length 2.4
  TOP w0.132: U16.B9 181.36,143.41 181.36,144.08 181.74,144.46 181.75,144.46 181.92,144.64 R52.1
N15808770: length 3.2
  TOP w0.132: TP15.1 U33.A3
N15812130: length 2.2
  TOP w0.132: R166.1 181.92,103.18 181.56,102.82 181.56,102.72 181.48,102.64 181.48,102.13 U33.B9
N15812170: length 2.2
  TOP w0.132: U25.B9 181.48,115.85 181.48,116.46 181.92,116.9 R117.1
N15820521: length 1.4
  TOP w0.132: U38.E7 v1(183.61,87.09)
  BOTTOM w0.132: R516.2 183.62,87.08 v1(183.61,87.09)
N15820751: length 3.2
  TOP w0.132: TP18.1 U38.A3
N15820885: length 2.2
  TOP w0.132: R212.1 181.92,89.47 181.56,89.1 181.56,88.34 U38.B9
N15854221: length 8.4
  TOP w0.132: v1(114.17,101.22) 114.67,101.72 114.67,102.42 114.53,102.56 C440.2 114.53,103.28 114.28,103.53 U27.8 114.28,105.39 114.42,105.54 114.68,105.54 114.78,105.44 U27.9
  BOTTOM w0.132: v1(114.17,101.22) 114.43,101.47 114.43,102.96 R715.1
N15854243: length 7.5
  TOP w0.132: U27.10 115.28,103.46 115.09,103.28 C440.1 115.09,102.51 114.94,102.36 114.94,101.78 115.09,101.63 v1(115.09,101.18)
  BOTTOM w0.132: v1(115.09,101.18) 114.7,101.18 114.34,100.82 114.01,100.82 113.78,101.05 113.78,102.01 113.62,102.17 113.62,102.69 113.07,103.24 R714.1
N15854325: length 5.8
  TOP w0.132: R148.1 111.84,106.98 112.21,106.61 113.85,106.61 114.28,107.04 U27.3
N15854335: length 4.9
  TOP w0.132: U3.3 184.96,160.64 184.75,160.43 R18.1
N15854337: length 8.3
  TOP w0.132: v1(184.89,154.94) 184.89,155.17 185.17,155.45 185.17,156.72 184.96,156.92 U3.8 184.96,159.24 185.11,159.38 185.29,159.38 185.46,159.22 U3.9
  BOTTOM w0.132: R713.1 185.7,156.66 C279.2 185.7,155.75 v1(184.89,154.94)
N15854349: length 7.8
  TOP w0.132: v1(185.8,154.94) 185.43,155.31 185.43,156.84 185.96,157.37 U3.10
  BOTTOM w0.132: v1(185.8,154.94) 185.4,154.54 184.72,154.54 184.49,154.78 184.49,155.32 185.13,155.96 C279.1 185.14,156.66 R712.1
N15854407: length 2.3
  BOTTOM w0.132: U68.3 R363.1
N15854417: length 10.2
  BOTTOM w0.132: C286.2 127.48,151.66 126.9,152.24 126.9,152.89 127.16,153.15 131.3,153.15 131.48,153.33 R709.1 ; C286.2 128.17,151.69 U68.9 ; C286.2 128.61,151.19 U68.8
N15854427: length 8.8
  BOTTOM w0.132: U68.10 128.17,152.19 C286.1 127.3,152.22 127.17,152.35 127.17,152.75 127.3,152.88 132.18,152.88 132.42,153.13 R708.1
N15854463: length 1.6
  BOTTOM w0.132: U67.3 R358.1
N15854467: length 7.4
  BOTTOM w0.132: R711.1 C280.2 150.39,155.78 150.13,155.51 149.67,155.51 148.51,154.35 U67.9 146.48,154.35 146.39,154.26 146.39,153.97 146.5,153.85 U67.8
N15854483: length 4.1
  BOTTOM w0.132: U67.10 148.5,154.85 149.43,155.78 149.73,155.78 149.83,155.88 C280.1 R710.1
N15854545: length 5.1
  BOTTOM w0.132: R591.1 182.33,68.41 184.08,70.16 U93.3
N15854547: length 3.9
  TOP w0.132: U2.3 155.5,165.29 155,165.78 155,166.82 155.85,167.66 R14.1
N15854553: length 8
  TOP w0.132: R717.1 181.8,70.64 C218.2 180.85,70.51 179.68,70.51 v1(179.2,70.99)
  BOTTOM w0.132: v1(179.2,70.99) 179.2,70.48 179.52,70.16 U93.8 181.86,70.16 181.99,70.29 181.99,70.52 181.85,70.66 U93.9
N15854557: length 6.8
  TOP w0.132: U2.8 152.9,165.29 153.03,165.16 153.03,164.92 152.9,164.79 U2.9 150.54,164.79 150.46,164.71 v1(150.01,164.71)
  BOTTOM w0.132: R719.1 151.75,164.88 151.56,165.07 C273.2 150.38,165.07 v1(150.01,164.71)
N15854581: length 7
  TOP w0.132: U2.10 150.24,164.29 150.15,164.2 149.82,164.2 149.54,164.47 149.54,165.67 v1(149.86,165.99)
  BOTTOM w0.132: v1(149.86,165.99) 150.22,165.63 C273.1 151.56,165.63 151.75,165.82 R718.1
N15854603: length 7
  TOP w0.132: v1(178.28,70.99) 178.6,70.68 178.88,70.68 179.48,70.08 C218.1 181.8,70.08 R716.1
  BOTTOM w0.132: U93.10 179.59,71.16 179.36,71.39 178.68,71.39 v1(178.28,70.99)
N15854669: length 1.6
  BOTTOM w0.132: U69.3 R364.1
N15854673: length 7.5
  BOTTOM w0.132: U69.8 171.74,149.02 171.61,149.15 171.61,149.38 171.74,149.52 U69.9 174.18,149.52 175.54,150.88 C292.2 R723.1
N15854685: length 4.6
  BOTTOM w0.132: R722.1 C292.1 175.11,151.26 175.11,150.85 174.27,150.02 U69.10
N15854737: length 1.6
  BOTTOM w0.132: U70.3 R365.1
N15854741: length 10.3
  BOTTOM w0.132: U70.8 163.51,148.77 163.62,148.89 163.62,149.18 163.53,149.27 U70.9 161.19,149.27 C293.2 161.06,149.35 160.78,149.35 160.4,149.73 160.4,150.37 160.65,150.62 164.01,150.62 164.01,150.62 164.47,150.62 164.56,150.72 164.56,150.94 R721.1
N15854757: length 7.5
  BOTTOM w0.132: U70.10 161.19,149.77 C293.1 161.09,149.73 160.8,149.73 160.67,149.87 160.67,150.12 160.8,150.25 164.73,150.25 165.1,150.62 165.1,150.91 R720.1
N15854857: length 2.6
  TOP w0.132: J21.2 R326.2
N15854859: length 2.6
  TOP w0.132: J21.1 R325.2
N16248811: length 66.2
  TOP w0.132: v1(71.63,102.81) 72.13,102.3 U32.20
  BOTTOM w0.132: v1(71.63,102.81) 90.49,102.81 101.67,113.99 108.77,113.99 109.03,113.73 122.3,113.73 124.59,111.44 128.5,111.44 129.88,110.06 R448.1
N16248833: length 1.9
  TOP w0.132: R169.1 72.66,102.96 73.13,102.48 U32.18
N16248855: length 1.7
  TOP w0.132: U32.17 73.63,102.42 73.66,102.45 R170.1
N16248877: length 2
  TOP w0.132: R207.1 74.16,94.53 73.63,95.05 U32.8
N16248899: length 1.8
  TOP w0.132: R206.1 73.15,95.04 73.13,95.06 U32.7
N16248921: length 1.8
  TOP w0.132: R205.1 72.14,95.04 72.13,95.04 U32.5
N16248943: length 1.8
  TOP w0.132: R204.1 71.12,95.04 71.13,95.05 U32.3
N16248965: length 3
  TOP w0.132: U32.1 70.13,96.04 69.79,95.7 68.9,95.7 68.45,95.25 R203.1
N16295803: length 2.1
  TOP w0.132: SW3.12 R244.2
N16300126: length 2.1
  TOP w0.132: SW3.11 R239.2
N16303893: length 1.6
  TOP w0.132: R279.2 SW2.17
N16303897: length 1.6
  TOP w0.132: SW2.18 R284.2
N16303901: length 1.6
  TOP w0.132: R290.2 SW2.19
N16303905: length 1.6
  TOP w0.132: SW2.20 R294.2
N16303913: length 1.6
  TOP w0.132: SW2.13 R248.2
N16303917: length 1.6
  TOP w0.132: R257.2 SW2.14
N16303921: length 1.6
  TOP w0.132: R271.2 SW2.15
N16303925: length 1.6
  TOP w0.132: SW2.16 R275.2
N16303929: length 1.6
  TOP w0.132: R242.2 SW2.12
N16457366: length 5.8
  BOTTOM w0.132: Y3.2 126.55,110.2 C401.1 128.03,108.72 R455.1 129.7,108.72 R450.2
N16457370: length 5.8
  BOTTOM w0.132: R457.2 129.7,107.88 R455.2 127.96,107.88 C412.1 126.48,106.4 Y3.1
N16458713: length 6.4
  BOTTOM w0.132: Y4.3 170.88,87.33 169.23,87.33 168.58,87.98 C584.1 168.46,87.9 R510.1 166.86,87.9 166.77,87.99 R507.2
N16458717: length 4.4
  BOTTOM w0.132: Y4.1 169.25,86.99 C587.1 168.46,87.06 R510.2 166.86,87.06 166.77,86.98 R511.2
N16460347: length 4.9
  BOTTOM w0.132: R564.2 82.93,77.11 R563.1 80.84,77.11 C602.1 79.46,77.04 Y5.2
N16460351: length 4.9
  BOTTOM w0.132: R550.2 82.93,77.95 R563.2 80.84,77.95 C600.1 79.46,78.03 Y5.1
N16489740: length 2.7
  BOTTOM w0.132: R551.1 R552.1 92.39,77.91 92.14,78.17 U91.7
N16493735: length 51.1
  BOTTOM w0.381: B1.1 96.14,66.55 93.6,69.09 81.15,69.09 76.2,74.04 76.2,79.5 77.09,80.39 82.42,80.39 83.76,79.06 84.6,79.06 84.98,79.44 U91.3
N16679303: length 3.5
  TOP w0.132: R312.2 R313.1 58.86,34.01 58.89,33.98 v1(58.89,33.53)
  BOTTOM w0.132: U106.60 v1(58.89,33.53)
N16679944: length 3.8
  BOTTOM w0.132: R649.1 R650.2 60.9,33.85 60.09,33.04 U106.63
N16679981: length 3.7
  BOTTOM w0.132: R652.2 R651.1 59.88,34.44 59.29,33.85 U106.61
N16680014: length 3.5
  TOP w0.132: R315.2 R314.1 59.88,33.94 59.89,33.93 v1(59.89,33.48)
  BOTTOM w0.132: v1(59.89,33.48) 59.69,33.28 U106.62
N16753626: length 3.3
  BOTTOM w0.132: J32.6 R472.2
N16753680: length 2.3
  BOTTOM w0.132: J32.15 R478.2
N16753934: length 3.5
  BOTTOM w0.132: J32.12 97.03,97.97 97,97.94 96.73,97.94 96.11,97.32 R479.2
N16818481: length 13.7
  TOP w0.132: LD6.1 v1(10.3,167.88)
  BOTTOM w0.132: Q8.3 21.92,167.67 21.72,167.88 v1(10.3,167.88)
N16818579: length 3.8
  BOTTOM w0.132: Q8.1 D14.1 R346.2
N16818604: length 1.9
  BOTTOM w0.132: R362.2 U66.1
N16818646: length 2
  TOP w0.132: LD6.2 R13.2
N16818667: length 2.1
  BOTTOM w0.132: R359.2 32.72,153.54 32.26,154.01 U66.9
N16818684: length 1.6
  BOTTOM w0.132: U66.7 C281.1
N16818713: length 1.4
  TOP w0.132: LD5.2 R9.2
N16818872: length 4.2
  BOTTOM w0.132: R350.1 R351.2 28.08,155.2 27.89,155.01 U66.4
N16818874: length 5
  BOTTOM w0.132: R353.1 25.92,156.74 25.76,156.58 ; 25.76,156.58 25.92,156.41 25.92,154.92 26.34,154.51 U66.3 ; 25.76,156.58 R354.2
N16865556: length 2.2
  BOTTOM w0.132: FL12.2 J14.A9
N16865678: length 5.1
  BOTTOM w0.254: FL11.2 J12.2
N16937764: length 2.1
  TOP w0.132: U43.5 114.35,65.06 114.41,64.99 R241.1
N16938293: length 1.7
  BOTTOM w0.132: U98.5 R623.1
N17211229: length 3.7
  BOTTOM w0.132: R695.2 121.86,9.66 122.85,8.68 J41.33
N17247526: length 1.8
  TOP w0.132: R107.2 LD11.2
N17247539: length 1.8
  TOP w0.132: R108.2 LD12.2
N17247599: length 1.8
  TOP w0.132: R109.2 LD13.2
N17247637: length 1.8
  TOP w0.132: R110.2 LD14.2
N17247662: length 1.8
  TOP w0.132: LD10.2 R106.2
N17247701: length 1.8
  TOP w0.132: LD15.2 R105.2
N17247743: length 1.8
  TOP w0.132: LD9.2 R104.2
N17247786: length 1.8
  TOP w0.132: LD8.2 R103.2
N17248427: length 1.6
  BOTTOM w0.132: R431.2 66.59,117.27 U84.7
N17248432: length 1.6
  BOTTOM w0.132: U84.10 R453.2
N17248439: length 1.6
  BOTTOM w0.132: U84.9 R454.2
N17307815: length 1.8
  BOTTOM w0.132: U111.10 R688.1
N17309165: length 1.6
  BOTTOM w0.132: R676.2 144.55,14.17 U111.9
N17314921: length 1.8
  BOTTOM w0.132: U111.12 139.32,14.18 R679.2
N17368941: length 1.6
  BOTTOM w0.132: U65.7 123.74,155.15 124.05,155.46 R356.1
N17368953: length 1.6
  BOTTOM w0.132: R440.1 108.51,115.05 108.82,115.36 U83.7
N17372472: length 1.7
  BOTTOM w0.132: R452.2 U85.5
N17372478: length 2.5
  BOTTOM w0.132: R447.1 84.33,109.74 84.19,109.6 83.27,109.6 83.13,109.47 U85.4
N17372544: length 1.7
  TOP w0.132: R80.2 112.58,128.29 112.26,128.61 U19.5
N17372552: length 2.4
  TOP w0.132: R89.1 112.28,127.84 112.15,127.98 111.35,127.98 111.09,128.24 U19.4
N17372616: length 1.7
  TOP w0.132: U21.5 110.81,118.92 110.49,118.61 R116.2
N17372624: length 2.4
  TOP w0.132: U21.4 110.43,120.28 110.17,120.02 110.17,119.22 110.04,119.09 R113.1
N17372676: length 1.7
  TOP w0.132: R42.2 116.85,149 116.53,149.31 U12.5
N17372684: length 2.4
  TOP w0.132: R51.1 116.37,148.55 116.24,148.68 115.44,148.68 115.18,148.94 U12.4
N17402100: length 1.6
  BOTTOM w0.132: U100.10 R624.1
N17546132: length 3.9
  BOTTOM w0.132: R689.2 127.94,10.38 126.35,8.78 J41.26
N17546158: length 3.5
  BOTTOM w0.132: R691.2 125.91,10.38 125.35,9.81 J41.28
N17682848: length 4.5
  BOTTOM w0.132: R708.2 133.26,154.01 133.08,154.19 132.33,154.19 132.09,154.44 132.09,155.14 132.34,155.39 R355.4
N17682861: length 4.5
  BOTTOM w0.132: R709.2 130.64,154.03 130.81,154.19 131.59,154.19 131.83,154.43 131.83,155.07 131.5,155.39 R355.1
N17683733: length 4.3
  BOTTOM w0.132: R710.2 148.04,156.73 148.15,156.84 149.6,156.84 149.73,156.98 149.73,157.66 149.64,157.75 148.52,157.75 R349.3
N17683748: length 4.8
  BOTTOM w0.132: R711.2 152.18,156.73 152.07,156.84 150.13,156.84 150,156.98 150,157.63 150.11,157.75 R349.2
N17685192: length 4.4
  BOTTOM w0.132: R348.3 184.79,158.61 185.03,158.38 185.03,157.61 184.9,157.48 184.24,157.48 184.11,157.35 R712.2
N17685207: length 5
  BOTTOM w0.132: R348.2 185.54,158.61 185.29,158.37 185.29,157.61 185.43,157.48 186.62,157.48 186.73,157.37 R713.2
N17685595: length 5.6
  BOTTOM w0.132: R459.1 114.35,105.01 114.45,104.9 114.45,104.2 114.14,103.89 112.34,103.89 112.23,103.77 R714.2
N17685608: length 3.9
  BOTTOM w0.132: R459.4 114.82,105.01 114.72,104.9 114.72,104.11 114.97,103.85 R715.2
N17685678: length 3.8
  TOP w0.132: R234.1 183.78,69.97 183.53,70.22 182.87,70.22 182.63,69.98 182.63,69.16 182.51,69.05 R716.2
N17685693: length 3.8
  TOP w0.132: R234.4 183.78,70.88 183.38,70.48 182.88,70.48 182.63,70.74 182.63,71.56 182.51,71.67 R717.2
N17685736: length 5.2
  BOTTOM w0.132: R718.2 152.63,166.66 152.78,166.51 152.78,165.48 153.03,165.24 154.94,165.24 155.14,165.44 R342.1
N17685749: length 4.8
  BOTTOM w0.132: R719.2 152.78,164.05 152.91,164.18 152.91,164.84 153.04,164.97 155.01,164.97 155.14,164.85 R342.4
N17686321: length 3.6
  BOTTOM w0.132: R720.2 166.15,151.36 165.86,151.65 165.21,151.65 164.98,151.88 164.98,152.55 165.1,152.67 R361.2
N17686333: length 3.7
  BOTTOM w0.132: R721.2 163.54,151.47 163.71,151.64 164.59,151.64 164.72,151.76 164.72,152.53 164.58,152.67 R361.3
N17686697: length 5.2
  BOTTOM w0.132: R360.3 175.17,153.05 175.26,152.95 175.26,152.15 175,151.89 172.81,151.89 172.68,151.76 R722.2
N17686710: length 4.4
  BOTTOM w0.132: R723.2 177.33,151.76 177.2,151.89 175.77,151.89 175.52,152.14 175.52,152.94 175.63,153.05 R360.2
N17781485: length 6.2
  BOTTOM w0.457: 32.96,67.06 U94.6
  BOTTOM w0.762: L11.1 32.96,67.06
N17781689: length 6.3
  BOTTOM w0.305: L6.1 164.36,166.01 165.05,166.7 U63.2
N17781701: length 2.9
  TOP w0.132: R15.1 R16.2 167.32,165.36 v1(167.26,165.29)
  BOTTOM w0.132: v1(167.26,165.29) 167.2,165.29 166.77,165.72 U63.4
N17781734: length 6.5
  BOTTOM w0.254: 184.79,172.41 U59.B4 U59.B3
  BOTTOM w0.762: L3.1 181.25,173.42 182.26,172.41 184.79,172.41
N17782106: length 6
  TOP w0.132: v1(142.94,173.16) 142.94,170.6 143.18,170.36 R7.2 R11.1
  BOTTOM w0.132: v1(142.94,173.16) 142.61,172.84 142.41,172.84 142.1,172.52 U61.8
N17782154: length 5.8
  BOTTOM w0.356: 139.07,170.94 U61.2
  BOTTOM w0.762: L5.1 139.07,170.94
N17782156: length 5.7
  BOTTOM w0.356: 143.19,170.94 U61.10
  BOTTOM w0.762: L4.1 143.19,170.94
N17782314: length 6.2
  TOP w0.132: v1(139.57,166.61) 139.57,167.06 139.7,167.18 C4.2
  BOTTOM w0.132: R340.1 140.31,168.12 140.14,167.96 140.14,167.38 140.05,167.28 R341.2 v1(139.57,166.61) ; R340.1 141.1,168.5 U61.14 ; R340.1 R339.2
N17782316: length 1.7
  BOTTOM w0.132: C265.1 142.7,168.16 142.1,168.76 U61.12
N17782320: length 5.5
  TOP w0.132: v1(141.09,173.14) 141.09,171.64 139.89,170.43 R10.1
  BOTTOM w0.132: U61.6 141.1,173.13 v1(141.09,173.14)
N17782393: length 2
  BOTTOM w0.132: U61.15 140.6,168.88 140.37,168.66 140.12,168.66 139.59,168.12 R341.1
N17785459: length 2.5
  BOTTOM w0.132: U80.7 43.84,128.28 C357.1 43.83,127.23 R414.1
N17785463: length 1.5
  BOTTOM w0.132: C359.2 42.15,127.18 42.17,127.19 R414.2
N17785477: length 13.7
  L03_SIG1 w0.203: v1(49.78,129.28) 48.77,130.29 43.83,130.29 v1(42.67,129.13)
  BOTTOM w0.132: C356.2 42.82,129.28 v1(42.67,129.13)
  BOTTOM w0.279: 49.02,129.28 U80.2 ; L9.1 v1(49.78,129.28)
  BOTTOM w0.508: v1(49.78,129.28) 49.02,129.28
N17785481: length 1.4
  BOTTOM w0.132: C356.1 U80.9
N17785497: length 2.2
  BOTTOM w0.132: C361.1 44.24,125.01 R425.1 43.77,124.97 43.73,124.93 R419.2
N17785692: length 1
  BOTTOM w0.132: C269.2 112.84,165.96 U64.7
N17785694: length 1.1
  BOTTOM w0.132: C269.1 112.83,166.52 U64.8
N17785722: length 2.4
  BOTTOM w0.132: R344.2 R343.1 U64.5
N17786037: length 2.3
  TOP w0.305: U40.2 33.76,77.79 34.35,78.38
N17786049: length 2.8
  TOP w0.254: U40.4 35.1,76.07 v1(35.24,75.93)
  BOTTOM w0.132: v1(35.24,75.93) 34.86,75.55 R566.2 34.84,75.14 R567.1
N17817176: length 22.1
  TOP w0.132: U34.A7 v1(159.16,104.19)
  BOTTOM w0.122: v1(159.16,104.19) 159.55,104.19 159.77,104.41
  BOTTOM w0.132: 159.77,104.41 160.66,105.3 160.66,107.47 169.01,115.82 TP41.1
N17817178: length 20.7
  TOP w0.132: U34.B7 v1(158.36,104.19)
  BOTTOM w0.122: 159.76,105.03 159.38,104.65 158.81,104.65 v1(158.36,104.19)
  BOTTOM w0.132: TP39.1 169.91,117.09 160.39,107.58 160.39,105.66 159.76,105.03
N17817198: length 22.5
  TOP w0.132: U34.C12 v1(157.56,100.19)
  BOTTOM w0.122: v1(157.56,100.19) 157.96,100.6 159.32,100.6 159.77,101.05
  BOTTOM w0.132: 159.77,101.05 159.95,101.24 159.95,102.37 161.45,103.86 161.45,107.14 166.32,112.01 TP45.1
N17817246: length 24
  TOP w0.132: U34.F9 v1(155.16,102.59)
  BOTTOM w0.122: v1(155.16,102.59) 155.56,103 155.56,103.55 155.79,103.78 159.51,103.78
  BOTTOM w0.132: 159.51,103.78 160.92,105.19 160.92,107.36 168.11,114.55 TP42.1
N17817413: length 11.1
  TOP w0.132: U34.F13 v1(155.16,99.39) ; R186.1 162.79,100.33 162.34,100.77 v1(162.34,101.22)
  L05_SIG2 w0.084: v1(155.16,99.39) 155.55,99 159.77,99 159.77,99 160.42,99 162.34,100.93 v1(162.34,101.22)
N17817732: length 26.7
  TOP w0.132: U34.F10 v1(155.16,101.79)
  BOTTOM w0.122: v1(155.16,101.79) 155.56,102.2 159.41,102.2 159.77,102.55
  BOTTOM w0.132: 159.77,102.55 161.18,103.97 161.18,107.25 167.22,113.28 TP44.1
N17818942: length 31.2
  TOP w0.132: U34.F15 v1(155.16,96.99)
  BOTTOM w0.122: v1(155.16,96.99) 155.55,96.6 159.68,96.6 159.77,96.68
  BOTTOM w0.132: 159.77,96.68 160.91,97.82 160.91,100.84 160.53,101.22 160.53,102.11 161.72,103.3 161.72,107.04 165.42,110.74 TP46.1
N17903256: length 1.9
  TOP w0.132: SW4.4 R302.2
N17903258: length 1.9
  TOP w0.132: SW4.3 R306.2
N17976903: length 2
  BOTTOM w0.132: R596.2 U95.7
N18001847: length 1.8
  BOTTOM w0.132: U114.1 R700.2
N18001866: length 1.6
  BOTTOM w0.132: R699.1 U114.3
N18022426: length 1.7
  TOP w0.132: U6.5 116.36,155.83 116.68,155.51 R31.2
N18022434: length 2.4
  TOP w0.132: R35.1 116.37,155.06 116.24,155.19 115.44,155.19 115.18,155.45 U6.4
N18024163: length 1.5
  TOP w0.132: R30.1 123.52,155.46 123.33,155.65 U8.7
N18024634: length 1.5
  TOP w0.132: U23.7 109.23,114.86 109.04,115.05 R125.1
N18046866: length 3.7
  TOP w0.132: U14.16 69.41,141.41 69,141.82 69,142.55 68.26,143.29 C51.1
N18046972: length 1.1
  TOP w0.132: R55.2 79.16,143.53 C49.1
N18070254: length 2.1
  BOTTOM w0.132: U95.13 146.53,62.41 147.04,61.9 R603.2
N18070257: length 1.9
  BOTTOM w0.132: U95.12 R602.2
N18070260: length 2.1
  BOTTOM w0.132: U95.11 146.52,63.41 147.04,63.93 R601.2
N18104656: length 2.2
  BOTTOM w0.254: R395.1 J8.1
N18104659: length 2.2
  BOTTOM w0.132: J8.3 R394.2
N18114187: length 2.2
  BOTTOM w0.132: J14.B9 FL14.2
N18115017: length 47.3
  L12_SIG4 w0.084: J14.B12 21.45,91.77 34.6,91.77 35.69,90.68 35.69,88.77 33.53,86.61 23.62,86.61 20.57,83.57 16.26,83.57 15.37,84.45 15.37,87.88 v1(17.27,89.79)
  BOTTOM w0.132: R496.2 v1(17.27,89.79)
N18115328: length 18.3
  L03_SIG1 w0.084: v1(45.54,89.22) 46.23,88.53 46.23,81.97 v1(47.48,80.72)
  BOTTOM w0.132: U88.48 49.07,80.94 48.84,80.72 v1(47.48,80.72) ; U88.13 49.07,88.95 48.79,89.22 v1(45.54,89.22) 45.56,89.25 TP56.1
N18116794: length 1.4
  BOTTOM w0.132: Q16.1 R512.2
N18116818: length 1.2
  BOTTOM w0.132: Q12.1 24.52,100.52 R467.1
N18116875: length 1.2
  BOTTOM w0.132: Q13.1 R468.1
N18117332: length 1.4
  BOTTOM w0.132: R515.2 Q15.1
N18117348: length 1.4
  BOTTOM w0.132: Q14.1 R495.1
N18117389: length 1.6
  TOP w0.132: Q5.1 R161.1
N18118509: length 18.1
  TOP w0.132: U34.AF14 v1(138.36,98.59)
  L10_SIG3 w0.084: v1(124.73,91.95) 126.92,94.14 126.92,94.49 127.19,94.75 130.41,94.75 132.68,97.03 133.92,97.03 135.87,98.98 137.96,98.98 v1(138.36,98.59)
  BOTTOM w0.132: R494.1 v1(124.73,91.95)
N18118513: length 21.8
  TOP w0.132: U34.AC15 v1(140.76,96.99)
  L10_SIG3 w0.084: v1(140.76,96.99) 140.36,97.38 138.99,97.38 138.76,97.15 138.76,96.85 138.5,96.58 135.61,96.58 134.42,95.39 134.42,94.98 134.14,94.7 130.98,94.7 130.01,93.73 127.63,93.73 127.62,93.74 127.11,93.74 125.19,91.82 125.19,90.37 v1(124.73,89.92)
  BOTTOM w0.132: R500.1 v1(124.73,89.92)
N18118517: length 11.3
  TOP w0.132: R211.1 v1(132.73,91.06) ; U34.AH16 v1(136.76,96.19)
  L03_SIG1 w0.084: v1(132.73,91.06) 131.76,91.06 131.57,91.25 131.57,94.02 132.15,94.6 133.74,94.6 135.08,95.94 136.06,95.94 136.31,96.19 v1(136.76,96.19)
N18118519: length 16.3
  TOP w0.132: U34.AF16 v1(138.36,96.19) ; RA4.6 v1(132.71,88.71)
  L03_SIG1 w0.084: v1(132.71,88.71) 131.69,89.73 131.69,90 131.99,90.31 133.03,90.31 133.27,90.55 133.27,91.27 133.03,91.52 132.04,91.52 131.89,91.67 131.89,93.26 132.04,93.41 134,93.41 135.74,95.15 135.86,95.15 136.49,95.78 137.95,95.78 v1(138.36,96.19)
N18118521: length 17.8
  TOP w0.132: RA4.5 133.03,88.08 133.35,88.4 133.35,88.4 v1(133.67,88.71) ; U34.AG16 v1(137.56,96.19)
  L03_SIG1 w0.084: v1(133.67,88.71) 133.21,88.26 132.52,88.26 131.23,89.54 131.23,94.29 133.52,96.58 137.16,96.58 v1(137.56,96.19)
N18118523: length 13.6
  TOP w0.132: RA4.7 133.03,89.21 v1(133.67,89.85) ; U34.AE16 v1(139.16,96.19)
  L03_SIG1 w0.084: v1(133.67,89.85) 134.13,90.31 135.06,90.31 135.7,90.94 135.7,93.41 136.14,93.85 136.14,93.86 136.49,94.2 139.32,94.2 139.55,94.43 139.55,95.8 v1(139.16,96.19)
N18118537: length 15.1
  TOP w0.132: RA4.8 v1(132.71,89.85) ; U34.AD16 v1(139.96,96.19)
  L03_SIG1 w0.084: v1(139.96,96.19) 140.35,95.8 140.35,93.63 140.12,93.4 136.64,93.4 136.08,92.84 136.08,90.28 135.19,89.39 133.17,89.39 v1(132.71,89.85)
N18118541: length 12.8
  TOP w0.132: R209.1 v1(132.73,92.08) ; U34.AE17 v1(139.16,95.39)
  L03_SIG1 w0.084: v1(139.16,95.39) 138.76,95 136.43,95 135.39,93.96 135.39,93.3 135.24,93.14 135.04,93.14 134.89,92.99 134.89,92.69 135.04,92.53 135.24,92.53 135.39,92.38 135.39,91.81 135.19,91.6 134.38,91.6 134.22,91.76 134.22,92.62 134,92.84 132.88,92.84 132.73,92.69 v1(132.73,92.08)
N18120742: length 4.1
  TOP w0.132: 31.24,106.81 R150.2 ; 31.24,106.81 31.48,106.57 U29.10 ; 31.24,106.81 30.61,106.17 30.61,105.35 30.85,105.1 U29.1
N18120819: length 1.5
  TOP w0.132: R160.2 U30.6
N18120892: length 1.4
  TOP w0.132: R164.2 30.27,104.65 30.32,104.7 U29.2
N18122515: length 1.5
  TOP w0.132: Q3.1 R73.1
N18122533: length 1.2
  TOP w0.132: R72.1 Q4.1
N18122581: length 1.3
  BOTTOM w0.132: Q9.1 R451.1
N18125073: length 17.6
  TOP w0.132: U34.A27 v1(159.32,87.79)
  BOTTOM w0.122: 159.77,87.79 v1(159.32,87.79)
  BOTTOM w0.132: 159.77,87.79 161.78,87.79 164.97,84.6 169.99,84.6 170.82,83.77 170.82,81.32 171.24,80.9 TP60.1
N18125082: length 5.4
  TOP w0.132: R208.1 163.2,92.7 163.02,92.52 160.21,92.52 159.34,93.39 U34.A20
N18125186: length 7.2
  TOP w0.132: R129.1 v1(140.46,113.33) ; U34.AB2 v1(141.56,108.19)
  L03_SIG1 w0.084: v1(140.46,113.33) 141.96,111.83 141.96,108.6 v1(141.56,108.19)
N18184841: length 1.4
  BOTTOM w0.132: U110.18 R667.1
N18184861: length 2.2
  BOTTOM w0.132: U110.23 81.27,19.48 81.56,19.77 81.98,19.77 82.3,20.09 R660.2
N18184865: length 2.7
  BOTTOM w0.132: R659.2 83.31,19.75 82.99,19.43 82.17,19.43 81.77,19.03 U110.24
N18275385: length 2.5
  TOP w0.132: U37.6 90.82,83.74 90.25,83.16 R218.1
N18276744: length 1
  TOP w0.132: R229.2 95.49,74.06 C214.1
N18280417: length 1.7
  TOP w0.132: R233.2 U41.4
N18280437: length 1.7
  BOTTOM w0.132: R565.2 U92.4
N18280477: length 1.7
  BOTTOM w0.132: U90.4 R543.2
N18280857: length 1.7
  TOP w0.132: U39.4 R223.2
N18289329: length 92.4
  TOP w0.132: v1(115.06,51.65) 114.32,50.9 R300.1 U49.3
  L10_SIG3 w0.381: v1(115.06,51.65) 117.94,51.65 127.34,61.05 130.52,61.05 135.98,66.51 146.24,66.51 149.28,69.55 154.89,69.55 156.85,71.5 161.67,71.5 168.76,78.59 v1(172.88,78.59)
  BOTTOM w0.381: v1(172.88,78.59) 174.12,79.82 174.12,97.12 172.95,98.29 R476.2
N18289350: length 1.3
  TOP w0.132: U49.5 113.81,54.24 113.36,54.68 C232.1
N18289892: length 1.7
  BOTTOM w0.132: U112.3 R674.1
N18289915: length 1.9
  BOTTOM w0.132: R671.2 U112.1
N18292398: length 3.6
  TOP w0.132: R200.2 R201.1 C168.1 91.96,94.94 U35.3
N18320293: length 5.6
  TOP w0.132: R194.1 79.51,97.57 R192.1 80.27,97.76 80.34,97.68 C161.2 81.79,97.68 83.2,96.28 Y1.2
N18320301: length 5.6
  TOP w0.132: R191.1 79.51,98.78 R192.2 80.27,98.59 80.34,98.67 C156.2 81.79,98.67 83.2,100.07 Y1.1
N18321769: length 3.2
  TOP w0.132: R199.1 67.85,96.02 68.39,96.56 68.39,97.25 68.69,97.56 U32.31
N18436285: length 6.7
  TOP w0.132: v1(20.82,77.61) 20.82,79.77 20.13,80.45 LD18.1
  BOTTOM w0.132: Q17.3 21.94,77.16 21.48,77.61 v1(20.82,77.61)
N18436298: length 3.2
  TOP w0.132: LD18.3 15.68,78.29 14.86,77.47 R224.1
N18436321: length 1.7
  TOP w0.132: Q6.1 R225.1
N18436342: length 4.9
  TOP w0.132: LD18.2 18.48,77.53 19.43,76.58 Q6.3
N18436344: length 1.7
  BOTTOM w0.132: R548.1 Q17.1
N18436628: length 1.5
  BOTTOM w0.132: R464.1 Q11.1
N18436656: length 1.6
  TOP w0.132: R177.1 LD17.2
N18436666: length 2.6
  TOP w0.132: LD17.1 64.39,104.57 64.39,104.58 v1(64.44,104.58)
  BOTTOM w0.132: Q11.3 63.73,104.58 v1(64.44,104.58)
N18436681: length 1.3
  BOTTOM w0.132: Q10.1 R458.1
N18436707: length 1.7
  TOP w0.132: LD16.2 71.05,106.39 R155.1
N18546005: length 52.3
  TOP w0.132: R5.1 v1(16.26,170.5)
  L10_SIG3 w0.084: v1(16.26,170.5) 21.53,170.5 31.94,160.08 60.13,160.08 v1(62.32,162.28)
N18546027: length 2.5
  TOP w0.132: R5.2 LD1.1
N18546044: length 5.5
  TOP w0.132: LD1.2 D1.1
N18547174: length 1.3
  BOTTOM w0.132: R338.2 U62.5
N18547348: length 6.2
  BOTTOM w0.132: U62.2 65.6,170.24 R337.2 67.62,170.13 68.64,169.1 SW1.2
N18550089: length 2
  TOP w0.132: v1(166.27,168.57) 166.78,168.57 167.01,168.79 C3.1
  BOTTOM w0.132: U63.9 v1(166.27,168.57)
N18860929: length 1.8
  BOTTOM w0.132: U109.10 204.33,158.97 204.04,159.26 R672.1
N18860951: length 1.6
  BOTTOM w0.132: U109.2 203.9,160.07 R673.1
N18867275: length 1.4
  BOTTOM w0.132: R642.2 U105.21
N18867277: length 3.5
  BOTTOM w0.132: R635.2 141.27,42.56 140.77,42.06 U105.20
N18867279: length 1.4
  BOTTOM w0.132: U105.19 R643.2
N18867281: length 3.5
  BOTTOM w0.132: R636.2 140.27,42.56 139.77,42.06 U105.18
N18867283: length 1.4
  BOTTOM w0.132: U105.17 R644.2
N18867285: length 3.5
  BOTTOM w0.132: R637.2 139.27,42.56 138.77,42.06 U105.16
N18867287: length 3.5
  BOTTOM w0.132: R638.2 137.77,42.56 138.27,42.06 U105.15
N18867289: length 1.4
  BOTTOM w0.132: U105.14 R645.2
N18867885: length 1.4
  BOTTOM w0.132: R631.2 U102.21
N18867903: length 3.9
  BOTTOM w0.132: U102.20 125.53,48.47 126.03,48.97 R626.2
N18867905: length 1.4
  BOTTOM w0.132: U102.19 R632.2
N18867915: length 3.9
  BOTTOM w0.132: R627.2 125.03,48.97 124.53,48.47 U102.18
N18867925: length 1.4
  BOTTOM w0.132: U102.17 R633.2
N18867943: length 4
  BOTTOM w0.132: U102.16 123.53,46.27 123.38,46.42 123.38,48.32 124.03,48.97 R628.2
N18867953: length 3.9
  BOTTOM w0.132: U102.15 123.03,48.48 R629.2
N18867955: length 1.4
  BOTTOM w0.132: U102.14 R634.2
N18948512: length 3.4
  TOP w0.132: R124.1 99.33,115.49 U24.D4
N18950218: length 15.3
  TOP w0.132: U34.R4 v1(147.16,106.59)
  L12_SIG4 w0.084: v1(147.16,106.59) 147.56,107 147.56,109.14 147.22,109.48 147.22,113.88 148.86,115.52 v1(148.86,119)
  BOTTOM w0.132: v1(148.86,119) 148.86,119.6 148.73,119.72 R429.1
N18968753: length 2
  TOP w0.132: C42.1 U11.2
N18968782: length 1.7
  TOP w0.132: U11.5 R37.2
N18972035: length 1.7
  TOP w0.132: U26.15 R176.1
N18977103: length 1.3
  TOP w0.132: R77.2 LD7.2
N18977129: length 6.2
  BOTTOM w0.132: U73.3 20.3,136.19 19.81,135.7 19.81,134.97 19.23,134.38 C337.1 18.19,134.38 16.94,135.63 Y2.2
N18977189: length 7.2
  BOTTOM w0.132: U73.2 20.31,135.69 20.08,135.45 20.08,133.42 19.74,133.08 C344.1 18.19,133.08 16.94,131.83 Y2.1
N18977240: length 19.4
  TOP w0.132: v1(9.08,131.06) 9.26,131.24 LD7.1
  L05_SIG2 w0.084: v1(25.05,134.42) 23.03,132.4 10.42,132.4 v1(9.08,131.06)
  BOTTOM w0.132: U73.60 v1(25.05,134.42)
N19031494: length 1.5
  TOP w0.132: U40.9 v1(31.9,76.57)
  BOTTOM w0.132: C601.1 31.61,76.29 v1(31.9,76.57)
N19031660: length 1.2
  BOTTOM w0.132: U64.9 113.61,168.05 C264.1
N19158110: length 1.7
  TOP w0.132: R299.1 107.04,50.96 U50.4
N19311007: length 7.6
  TOP w0.132: R165.2 163.09,104.39 162.31,103.61 162.31,101.92 161.38,100.99 159.16,100.99 U34.A11
N19311901: length 85.1
  L03_SIG1 w0.084: v1(122.54,101.09) 118.75,104.89 118.75,109.35 119.15,109.75 119.15,119.93 116.61,122.47 114.54,122.47 111.04,125.97 111.04,127.26 111.18,127.39 111.18,130.09 110.68,130.58 110.68,131.38 113.09,133.79 v1(113.09,137.6)
  L05_SIG2 w0.084: v1(145.63,139.19) 145.17,139.19 145.05,139.06 126.17,139.06 124.71,137.6 v1(113.09,137.6)
  BOTTOM w0.132: R469.1 v1(122.54,101.09) ; v1(145.63,139.19) 145.99,139.55 145.99,141.73 146.32,142.06 R380.2 146.32,146.08 D16.3
N19312123: length 2.3
  TOP w0.132: R25.2 R28.1 D4.3
N19753713: length 8.7
  BOTTOM w0.254: U75.11 C343.2 95.39,132.83 94.62,133.6 D17.1
N19753729: length 5.7
  BOTTOM w0.132: U75.10 100.95,133.02 C343.1 100.76,132.39 98.73,130.37 97.73,130.37
N19753760: length 3
  BOTTOM w0.254: R426.1 86.92,119.81 86.67,119.56 R703.1
N19753772: length 20
  L10_SIG3 w0.203: v1(101.2,130.05) 87.25,130.05 86.98,129.78 v1(86.57,129.78)
  BOTTOM w0.132: v1(101.2,130.05) 101.38,130.23 R405.2 101.38,131.86 101.95,132.43 U75.8
  BOTTOM w0.254: U78.4 v1(86.57,129.78)
N19753820: length 25.7
  TOP w0.254: R392.1 82.99,126.56 v1(82.17,125.73)
  L12_SIG4 w0.254: v1(82.17,125.73) 82.68,126.24 82.68,127.08 84.04,128.45 90.41,128.45 97.35,135.38 98.44,135.38 v1(98.93,135.87)
  BOTTOM w0.254: U75.13 v1(98.93,135.87)
N19753822: length 6.2
  TOP w0.254: R392.2 82.99,131.01 v1(83.6,131.62) 84.26,130.95 R396.2
  BOTTOM w0.254: U81.4 v1(83.6,131.62)
N19753872: length 33.3
  L12_SIG4 w0.254: v1(86.74,115.19) 86.39,115.54 86.39,117.98 89.43,121.03 97.16,121.03 103.89,127.76 103.89,131.87 v1(104.37,132.36)
  BOTTOM w0.132: v1(104.37,132.36) 103.95,132.78 U75.4
  BOTTOM w0.254: R703.2 86.51,116.9 C684.1 86.51,115.42 v1(86.74,115.19)
N19753878: length 33
  L12_SIG4 w0.254: v1(85.72,115.19) 85.98,115.44 85.98,118.15 89.27,121.44 96.99,121.44 103.48,127.93 103.48,131.91 v1(103.03,132.36)
  BOTTOM w0.132: U75.5 103.45,132.78 v1(103.03,132.36)
  BOTTOM w0.254: R704.2 85.95,116.47 C684.2 85.95,115.42 v1(85.72,115.19)
N19753964: length 1.1
  BOTTOM w0.132: C352.1 104.27,130.83 104.23,130.87 R399.1
N19754006: length 1.6
  BOTTOM w0.132: C317.1 106.05,140.98 105.45,140.39 U75.30
N19754185: length 1.5
  BOTTOM w0.132: U75.1 105.45,133.4 105.99,132.86 C345.1
N19754201: length 10.5
  BOTTOM w0.132: U75.21 100.95,141.09 100.5,141.54 C320.2 100.48,142.34 99.76,143.07 94.44,143.07 94.23,143.27 L8.2
N19754203: length 8.4
  BOTTOM w0.254: D15.1 95.51,141.35 95.69,141.54 C320.1 99.92,140.49 100.2,140.21 U75.20
N19754223: length 1.5
  BOTTOM w0.132: U75.22 101.45,140.81 101.41,140.85 R378.2
N19754237: length 18.4
  L05_SIG2 w0.203: v1(102.23,142.49) 101.13,143.6 90.13,143.6 v1(89.28,142.75)
  BOTTOM w0.132: R378.1 101.43,142.49 v1(102.23,142.49) 102.23,142.11 101.95,141.83 U75.23
  BOTTOM w0.254: v1(89.28,142.75) 89.28,143.26 89.09,143.44 U72.4
N19754314: length 4.5
  TOP w0.254: R387.1 82.13,141.36 82,141.49 81.54,141.49 v1(80.99,142.04) 81.57,142.63 R384.1
  BOTTOM w0.254: U71.4 81.06,142.12 v1(80.99,142.04)
N19754320: length 19
  TOP w0.254: v1(84.33,143.04) 84.33,143.04 84.33,142.76 84.19,142.63 R384.2
  L12_SIG4 w0.254: v1(84.33,143.04) 84.83,142.53 88.14,142.53 89.66,141.01 95.41,141.01 97.09,139.32 98.55,139.32 98.68,139.45 v1(99.19,139.45)
  BOTTOM w0.254: U75.19 99.51,138.87 99.19,139.19 v1(99.19,139.45)
N19754322: length 18.5
  TOP w0.254: R387.2 84.12,141.36 v1(84.29,141.19)
  L12_SIG4 w0.254: v1(84.29,141.19) 84.82,141.72 87.8,141.72 89.33,140.19 95.07,140.19 96.96,138.3 98.42,138.3 98.55,138.43 v1(99.06,138.43)
  BOTTOM w0.254: U75.18 99.12,138.37 v1(99.06,138.43)
N19754431: length 3.8
  BOTTOM w0.132: U75.9 101.45,132.57 100.55,131.66 R405.1
N19754435: length 24.5
  TOP w0.254: R396.1 84.26,126.17 v1(84.71,125.73)
  L12_SIG4 w0.254: v1(84.71,125.73) 83.95,126.49 83.95,127.2 84.38,127.64 90.82,127.64 97.6,134.42 v1(98.93,134.42)
  BOTTOM w0.254: v1(98.93,134.42) 98.93,134.92 99.38,135.37 U75.12
N19754522: length 3.1
  BOTTOM w0.254: R701.1 86.84,156.35 86.92,156.27 R357.2
N19754526: length 31.8
  L12_SIG4 w0.254: v1(103.41,141.35) 103.73,141.68 103.73,143.6 100.42,146.91 98.03,146.91 86.11,158.84 86.11,160.76 v1(85.83,161.04)
  BOTTOM w0.132: U75.26 103.45,140.81 103.41,140.85 v1(103.41,141.35)
  BOTTOM w0.254: v1(85.83,161.04) 86.05,160.81 C683.1 86.05,159.54 R702.2
N19754534: length 32.1
  L12_SIG4 w0.254: v1(86.74,161.04) 86.51,160.81 86.51,159 98.2,147.32 100.58,147.32 104.14,143.76 104.14,141.47 v1(104.35,141.25)
  BOTTOM w0.132: U75.27 103.95,140.85 v1(104.35,141.25)
  BOTTOM w0.254: R701.2 86.61,159.26 C683.2 86.61,160.9 v1(86.74,161.04)
N19754630: length 1.6
  BOTTOM w0.132: C325.2 107.23,138.97 107.12,138.87 U75.32
N19754677: length 1.1
  BOTTOM w0.132: C307.1 106.45,144.11 R375.1
N20141585: length 2.9
  BOTTOM w0.132: U109.1 203.9,159.67 203.7,159.87 202.95,159.87 202.26,160.56 R680.1
N20142928: length 0.8
  TOP w0.254: C14.1 199.16,158.91 U5.2
N20155231: length 3.1
  BOTTOM w0.132: U45.6 189.05,57.07 188.85,57.28 188.85,57.78 189.27,58.2 R246.1
N20155262: length 4.4
  BOTTOM w0.132: R604.1 186.05,60.47 185.84,60.68 185.84,61.83 186.18,62.16 U96.6
N20584902: length 5.3
  BOTTOM w0.132: U77.B2 147.07,132.84 147.07,133.9 148.66,135.5 R706.2
N20753582: length 2
  BOTTOM w0.254: C303.2 R374.2 R373.2
N21124530: length 2.7
  BOTTOM w0.132: J38.33 R675.2
N21549383: length 88.5
  TOP w0.132: R729.1 146.46,140.33 v1(146.69,140.1) ; U34.F18 v1(155.16,94.59)
  L05_SIG2 w0.084: v1(146.69,140.1) 148.74,138.05 152.02,138.05 154.43,135.64 175.77,135.64 176.91,134.49 176.91,130.18 176.02,129.29 v1(176.02,115.8)
  L12_SIG4 w0.084: v1(155.16,94.59) 154.77,94.97 154.77,97.24 155.56,98.03 155.56,103.53 155.83,103.8 159.42,103.8 163.32,107.7 168.33,107.7 169.16,108.53 169.16,109.6 175.37,115.8 v1(176.02,115.8)
N22464359: length 3.7
  BOTTOM w0.132: U115.5 183.64,58.55 184.11,59.02 R736.2
N22573349: length 4
  BOTTOM w0.132: R745.2 143.03,136.72 U77.A5
N152432201: length 2.1
  TOP w0.132: R332.2 98.67,13.65 98.93,13.39 LD19.2
N182775171: length 1
  TOP w0.132: R222.2 95.49,78.13 C210.1
N184366740: length 3.2
  TOP w0.132: v1(73.99,107.99) LD16.1
  BOTTOM w0.132: v1(73.99,107.99) 72.31,107.99 Q10.3
N194468551: length 1.8
  TOP w0.132: LD4.2 R2.2
N197540311: length 2
  TOP w0.132: LD2.2 R1.2
N197540831: length 2
  TOP w0.132: LD3.2 R3.2

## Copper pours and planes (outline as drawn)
DGND on L05_SIG2 (solid shape): 93.35,89.61 93.37,89.5 93.28,89.44 86.12,89.44 85.9,89.66 85.88,89.77 85.97,89.84 93.13,89.84
DGND on L05_SIG2 (solid shape): 172.31,54.97 172.25,54.88 172.14,54.9 172.11,54.93 172.11,63.02 172.13,63.08 172.2,63.12 172.31,63.13
DGND on L05_SIG2 (solid shape): 90.9,12.59 118.54,12.59 118.63,12.53 118.61,12.42 118.03,11.84 82.87,11.84 81.83,12.88 81.81,12.99 81.91,13.05 90.44,13.05
DGND on L05_SIG2 (solid shape): 135.14,57.16 135.2,57.15 135.26,57.12 135.29,57.05 135.29,56.63 130.5,51.85 129.59,51.85 129.49,51.91 129.51,52.02 134.68,57.18 135.07,57.18
DGND on L05_SIG2 (solid shape): 177.07,87.65 177.14,87.63 178.01,86.76 178.01,85.2 176.97,85.2 176.65,85.53 176.65,87.42 176.68,87.49 176.75,87.52 176.88,87.55 177,87.63
DGND on L05_SIG2 (solid shape): 160.1,78.27 160.12,78.16 160.03,78.1 159.31,78.1 157.17,80.24 157.17,80.69 157.19,80.75 157.26,80.79 157.38,80.82 157.48,80.89
DGND on L05_SIG2 (solid shape): 185.06,79.98 185.17,80 185.23,79.91 185.23,78.72 179.6,78.72 179.48,78.84 179.48,79.84 179.54,79.94 179.65,79.92 180.12,79.45 184.53,79.45
DGND on L05_SIG2 (solid shape): 71.62,8.83 73.91,8.83 73.98,8.8 74.01,8.73 74.01,8.67 69.87,8.67 60.46,18.07 60.43,18.15 60.46,18.22 60.58,18.38 60.63,18.58 60.67,18.65 60.73,18.68 61.78,18.68
DGND on L05_SIG2 (solid shape): 83.06,15.75 83.03,15.72 82.98,15.51 83.04,15.3 83.05,15.2 82.96,15.14 78.08,15.14 77.99,15.2 78,15.3 78.02,15.33 78.04,15.38 78.46,15.81 83,15.81
DGND on L05_SIG2 (solid shape): 173.3,100.4 173.3,89.44 173.33,89.3 173.41,89.18 173.59,89 173.53,88.95 173.3,88.72 173.3,81.43 173.24,81.34 173.13,81.36 172.77,81.72 172.77,94.88 172.48,95.16 172.77,95.45 172.77,99.98 171.54,101.2 171.56,101.23 171.57,101.31 171.57,101.4 171.6,101.48 171.68,101.51 172.19,101.51
DGND on L05_SIG2 (solid shape): 174.22,63.08 174.27,63.17 174.38,63.17 174.46,63.13 174.55,63.12 174.58,63.1 174.59,63.07 174.59,61.4 178.83,57.16 178.83,55.71 178.78,55.62 178.68,55.61 178.38,55.63 178.17,55.41 178.16,55.4 177.95,55.19 177.91,55.19 177.84,55.22 177.81,55.29 177.62,55.58 177.28,55.6 177.27,55.6 176.79,55.6 174.22,58.17
DGND on L05_SIG2 (solid shape): 133.87,45.98 133.96,45.92 133.94,45.81 131.89,43.76 129.43,43.76 129.35,43.79 129.33,43.87 128.95,44.29 128.57,43.87 128.54,43.79 128.47,43.76 127.72,43.76 126.67,42.7 125.69,42.7 124.64,41.65 124.64,41.65 124.58,41.55 124.46,41.58 124.21,41.83 123.85,41.83 122.89,42.79 122.89,45.06 123.82,45.98
DGND on L05_SIG2 (solid shape): 174.98,55.53 175.05,55.5 176.64,53.91 177.05,53.91 177.15,53.84 177.13,53.73 175.72,52.33 174.57,52.33 174.22,52.68 173.92,52.81 173.54,52.66 173.47,52.69 172.95,53.2 172.93,53.31 173.03,53.37 174.17,53.37 175.05,54.25 175.05,54.6 175.05,54.6 175.03,54.95 174.73,55.13 174.65,55.2 174.67,55.31 174.76,55.4 174.84,55.44 174.9,55.49
DGND on L05_SIG2 (solid shape): outline of 112 points within 148.69,77.97 152.03,83.5
DGND on L05_SIG2 (solid shape): 152.31,17.24 152.39,17.2 152.41,17.12 152.78,16.64 153.15,17.12 153.17,17.2 153.25,17.24 153.33,17.24 153.33,17.18 153.32,17.17 153.51,16.67 154.01,16.85 154.09,16.9 154.17,16.87 154.45,16.6 154.43,16.56 154.32,16.45 151.91,16.45 151.37,16.98 147.73,16.98 147.72,16.99 147.19,16.64 147.72,16.29 147.73,16.29 149.6,16.29 149.7,16.23 149.68,16.12 148.58,15.02 146.41,15.02 146.32,15.09 146.34,15.2 146.46,15.32 146.47,15.32 146.71,15.71 146.41,16.05 146.34,16.12 146.36,16.22 146.46,16.32 146.47,16.32 146.71,16.68 146.46,17.03 146.4,17.11 146.43,17.2 146.47,17.24
DGND on L05_SIG2 (solid shape): outline of 195 points within 159.35,31.15 162.66,39.49
DGND on L05_SIG2 (solid shape): outline of 597 points within 141.18,40.94 161.16,46.84
DGND on L05_SIG2 (solid shape): outline of 663 points within 141.46,89.11 144.02,97.16
DGND on L10_SIG3 (solid shape): 80.82,43.73 80.93,43.75 81,43.65 81,43.31 77.43,39.75 77.09,39.75 77,39.81 77.02,39.92
DGND on L10_SIG3 (solid shape): 108.45,95.55 108.56,95.57 108.62,95.48 108.62,94.96 101.65,87.99 101.13,87.99 101.04,88.05 101.06,88.16
DGND on L10_SIG3 (solid shape): 83.25,65.57 83.34,65.5 83.32,65.39 79.62,61.69 75.57,61.69 75.42,61.84 75.4,61.95 75.49,62.01 79.19,62.01 82.75,65.57
DGND on L10_SIG3 (solid shape): 107.99,98.42 108.1,98.44 108.16,98.35 108.16,96.25 103.49,91.58 103.42,91.55 103.35,91.58 103.29,91.62 103.24,91.66 103.18,91.73 103.21,91.82 105.25,93.86 105.25,95.68
DGND on L10_SIG3 (solid shape): 108.61,90.68 108.71,90.62 108.68,90.51 104.53,86.36 92.69,86.36 92.6,86.41 92.6,86.51 92.64,86.6 92.65,86.69 92.68,86.77 92.75,86.8 102.08,86.8 105.97,90.68
DGND on L10_SIG3 (solid shape): 56.17,91.83 56.26,91.77 56.24,91.66 54.34,89.75 54.25,89.72 54.18,89.77 54.05,89.91 53.88,89.97 53.81,90 53.78,90.07 53.78,90.57 55.05,91.83
DGND on L10_SIG3 (solid shape): 110.52,61.9 110.59,61.87 110.62,61.79 111,61.4 111.38,61.79 111.41,61.87 111.48,61.9 115.23,61.9 115.33,61.83 115.3,61.72 114.25,60.67 103.47,60.67 103.37,60.73 103.39,60.85 104.44,61.9
DGND on L10_SIG3 (solid shape): 95.16,89.69 95.1,89.59 94.99,89.61 94.89,89.71 94.39,89.71 94.26,89.69 94.14,89.61 93.91,89.37 93.57,89.71 93.07,89.71 92.93,89.69 92.82,89.61 92.57,89.36 92.57,88.45 92.49,88.45 92.42,88.48 92.39,88.55 92.01,88.94 91.63,88.55 91.6,88.48 91.53,88.45 91.5,88.45 90.27,89.68 90.24,89.79 90.34,89.85 95.16,89.85
DGND on L10_SIG3 (solid shape): 106.26,54.99 106.34,54.96 106.36,54.88 106.74,54.48 107.12,54.88 107.15,54.96 107.23,54.99 114.57,54.99 114.67,54.93 114.65,54.82 114.02,54.19 112.51,54.19 112.44,54.23 112.41,54.31 112.03,54.74 111.66,54.31 111.63,54.23 111.56,54.19 104.48,54.19 104.38,54.26 104.41,54.37 105.03,54.99
DGND on L10_SIG3 (solid shape): 148.58,54.61 148.62,54.52 148.62,54.47 153.59,49.5 156,49.5 157.13,48.37 157.13,44.96 157.07,44.87 156.96,44.89 156.94,44.91 156.94,48.15 156.23,48.86 154.05,48.86 153.98,48.89 153.95,48.96 153.57,49.33 153.19,48.96 153.16,48.89 153.09,48.86 152.86,48.86 148.17,53.55 148.17,53.57 148.21,53.65 148.29,53.67 148.71,54.05 148.29,54.43 148.21,54.46 148.17,54.53 148.17,54.6 148.24,54.6 148.36,54.59 148.48,54.62
DGND on L10_SIG3 (solid shape): 95.94,61.1 96.03,61.04 96.01,60.93 94.8,59.72 90.46,59.72 90.37,59.77 90.38,59.87 90.05,60.46 89.73,59.87 89.73,59.77 89.64,59.72 85.19,59.72 85.12,59.75 85.09,59.83 85.09,59.88 85.08,59.92 85.11,60.01 85.18,60.04 88.85,60.04 89.59,60.78 89.67,60.81 89.74,60.77 90.17,60.63 90.43,61 90.46,61.07 90.54,61.1
DGND on L10_SIG3 (solid shape): outline of 164 points within 77.41,56.21 98.25,63.74
DGND on L10_SIG3 (solid shape): outline of 177 points within 104.88,69.97 129.85,85.09
DGND on L10_SIG3 (solid shape): outline of 176 points within 188.14,88.71 190.05,93.83
DGND on L10_SIG3 (solid shape): outline of 227 points within 115.25,52.14 135.31,66.68
DGND on L10_SIG3 (solid shape): outline of 128 points within 58.39,80.86 93.42,85.66
DGND on L10_SIG3 (solid shape): outline of 366 points within 148.55,75.53 156.23,80.93
DGND on L10_SIG3 (solid shape): outline of 445 points within 78.15,69.14 104.94,75.62
DGND on L10_SIG3 (solid shape): outline of 461 points within 76.69,35.21 104.98,56.93
DGND on L10_SIG3 (solid shape): outline of 808 points within 136.89,40.3 154.77,59.63
DGND on L12_SIG4 (solid shape): 122.52,11.75 122.53,11.72 122.53,11.62 122.44,11.57 120.26,11.57 120.17,11.62 120.17,11.72 119.82,12.27 119.48,11.72 119.48,11.62 119.39,11.57 81,11.57 80.93,11.61 80.9,11.69 80.9,11.78 80.88,11.88 80.89,11.97 80.97,12.02 91.76,12.02 92.21,12.47 121.8,12.47
DGND on L12_SIG4 (solid shape): 150.67,30.21 150.74,30.3 150.85,30.28 152.57,28.56 151.93,27.92 151.93,27.18 152.48,26.63 153.22,26.63 153.86,27.27 155.23,25.9 155.91,25.9 155.91,25.22 156.46,24.67 157.13,24.67 157.13,24 158.05,23.08 158.05,17.85 158.01,17.77 157.92,17.76 157.41,17.4 157.92,17.04 158.01,17.03 158.05,16.94 158.05,15.02 154.75,11.72 154.63,11.7 154.57,11.79 154.57,12.44 156.77,14.64 156.77,21.95 154.87,23.85 154.19,23.85 154.19,24.52 153.64,25.07 152.97,25.07 152.97,25.75 150.67,28.04
DGND on L12_SIG4 (solid shape): 159.52,17.03 159.57,16.95 159.57,14.05 159.09,13.58 159.09,11.31 159.08,11.28 159.04,11.26 158.85,11.23 158.68,11.12 158.61,11.09 158.54,11.12 158.21,11.26 157.86,11.16 157.79,11.18 157.72,11.19 157.61,11.19 157.6,11.2 157.28,11.26 156.98,11.13 156.91,11.1 156.49,11.26 156.14,11.13 156.05,11.16 155.96,11.18 155.94,11.18 155.88,11.21 155.83,11.23 155.76,11.31 155.79,11.4 159.01,14.63 159.01,16.95 159.06,17.03 159.15,17.04 159.29,17.02 159.43,17.04
DGND on L12_SIG4 (solid shape): outline of 295 points within 148.42,9.93 155.81,31.44
DGND on L12_SIG4 (solid shape): outline of 287 points within 150.94,9.83 164.22,36.06
DGND on L12_SIG4 (solid shape): outline of 1299 points within 85.07,29.61 146.6,66.72
DGND on L02_GND1: 7.51,147.38 7.51,153.8 7.76,154.05 9.12,154.05 10.95,155.88 11.96,155.88 12.24,156.16 12.24,158.01 12.07,158.19 10.49,158.19 10.39,158.29 10.39,161.09 10.57,161.26 12.27,161.26 12.67,161.67 12.67,165.2 12.22,165.66 7.77,165.66 7.51,165.93 7.51,177.28 209.66,177.28 209.66,0.52 109,0.52 108.79,0.74 108.79,2.57 107.24,4.11 107.24,5 107.04,5.21 105.13,5.21 104.98,5.05 104.98,3.56 104.85,3.43 102.01,3.43 101.9,3.53 101.9,5.11 101.8,5.21 99.82,5.21 99.69,5.08 99.69,3.86 98.88,3.05 97.79,3.05 97.21,2.46 97.21,0.85 96.88,0.52 7.51,0.52 7.51,135.06 7.8,135.36 11.94,135.36 12.29,135.71 12.29,139.14 12,139.43 10.59,139.43 10.4,139.62 10.4,142.32 10.56,142.48 11.99,142.48 12.29,142.79 12.29,146.28 11.89,146.69 8.2,146.69 ; 9 cut-outs
DGND on L04_GND2: 7.51,165.89 7.51,177.28 209.66,177.28 209.66,0.52 106.79,0.52 106.79,1.6 105.82,2.57 104.85,1.6 104.85,0.52 102.04,0.52 102.04,1.6 101.07,2.57 100.1,1.6 100.1,0.52 7.51,0.52 7.51,137.62 8.58,137.62 9.56,138.6 8.58,139.57 7.51,139.57 7.51,142.37 8.58,142.37 9.56,143.34 8.58,144.32 7.51,144.32 7.51,153.67 7.73,153.9 8.97,153.9 10.95,155.88 11.96,155.88 12.24,156.16 12.24,157.99 12.04,158.19 10.49,158.19 10.39,158.29 10.39,161.06 10.57,161.24 12.27,161.24 12.67,161.65 12.67,165.2 12.22,165.66 7.74,165.66 ; 3 cut-outs
DGND on L06_PWR1: 155.92,110.11 152.78,106.97 152.78,99.44 155.32,96.9 155.32,92.46 167.13,92.46 168.78,90.81 168.78,85.34 171.32,82.8 171.32,80.14 177.8,73.66 189.48,73.66 194.95,79.12 194.95,145.67 193.29,147.32 185.55,147.32 181.48,143.26 181.48,109.47 180.34,108.33 175.51,108.33 173.99,106.81 169.76,106.81 169.27,107.3 169.27,109.39 168.56,110.11
DGND on L08_PWR3: 99.59,1.03 8.01,1.03 8.01,123.51 8.41,123.9 30.38,123.9 34.95,128.47 34.95,144.58 32.05,147.47 15.24,147.47 13.18,145.41 12.6,145.41 12.4,145.62 12.4,146.2 11.89,146.71 8.29,146.71 8.01,146.99 8.01,155.94 8.6,155.94 10.06,157.39 8.6,158.84 8.01,158.84 8.01,160.69 8.6,160.69 10.06,162.14 8.6,163.59 8.01,163.59 8.01,176.77 209.16,176.77 209.16,1.03 107.3,1.03 107.3,1.6 105.82,3.08 104.34,1.6 104.34,1.03 102.55,1.03 102.55,1.6 101.07,3.08 99.59,1.6 ; 14 cut-outs
DGND on L09_GND3: 7.51,139.57 7.51,142.37 8.58,142.37 9.56,143.34 8.58,144.32 7.51,144.32 7.51,156.45 8.6,156.45 9.55,157.39 8.6,158.34 7.51,158.34 7.51,161.2 8.6,161.2 9.55,162.14 8.6,163.09 7.51,163.09 7.51,177.28 209.66,177.28 209.66,0.52 106.79,0.52 106.79,1.6 105.82,2.57 104.85,1.6 104.85,0.72 104.65,0.52 102.23,0.52 102.04,0.72 102.04,1.6 101.07,2.57 100.1,1.6 100.1,0.52 7.51,0.52 7.51,137.62 8.58,137.62 9.56,138.6 8.58,139.57 ; 3 cut-outs
DGND on L11_GND4: 7.51,139.57 7.51,142.37 8.58,142.37 9.56,143.34 8.58,144.32 7.51,144.32 7.51,156.45 8.6,156.45 9.55,157.39 8.6,158.34 7.51,158.34 7.51,161.2 8.6,161.2 9.55,162.14 8.6,163.09 7.51,163.09 7.51,177.28 209.66,177.28 209.66,0.52 106.79,0.52 106.79,1.6 105.82,2.57 104.85,1.6 104.85,0.71 104.66,0.52 102.23,0.52 102.04,0.72 102.04,1.6 101.07,2.57 100.1,1.6 100.1,0.52 7.51,0.52 7.51,137.62 8.58,137.62 9.56,138.6 8.58,139.57 ; 3 cut-outs
DGND on L13_GND5: 7.51,139.57 7.51,142.37 8.58,142.37 9.56,143.34 8.58,144.32 7.51,144.32 7.51,156.45 8.6,156.45 9.55,157.39 8.6,158.34 7.51,158.34 7.51,161.2 8.6,161.2 9.55,162.14 8.6,163.09 7.51,163.09 7.51,177.28 209.66,177.28 209.66,0.52 106.79,0.52 106.79,1.6 105.82,2.57 104.85,1.6 104.85,0.72 104.65,0.52 102.23,0.52 102.04,0.72 102.04,1.6 101.07,2.57 100.1,1.6 100.1,0.52 7.51,0.52 7.51,137.62 8.58,137.62 9.56,138.6 8.58,139.57 ; 8 cut-outs
GNDUSB on TOP: 7.62,136.02 7.62,142.37 7.67,142.37 7.7,142.39 7.7,144.3 7.49,144.5 7.49,146.15 7.65,146.3 11.43,146.3 11.81,145.92 11.81,142.62 10.29,142.62 10.29,139.32 10.92,139.32 10.92,137.29 9.4,135.76 7.87,135.76
GNDUSB on BOTTOM: 7.62,146.08 7.95,146.41 11.15,146.41 11.33,146.23 11.33,139.62 10.67,138.97 10.67,137.33 9.21,135.86 7.9,135.86 7.62,136.14
